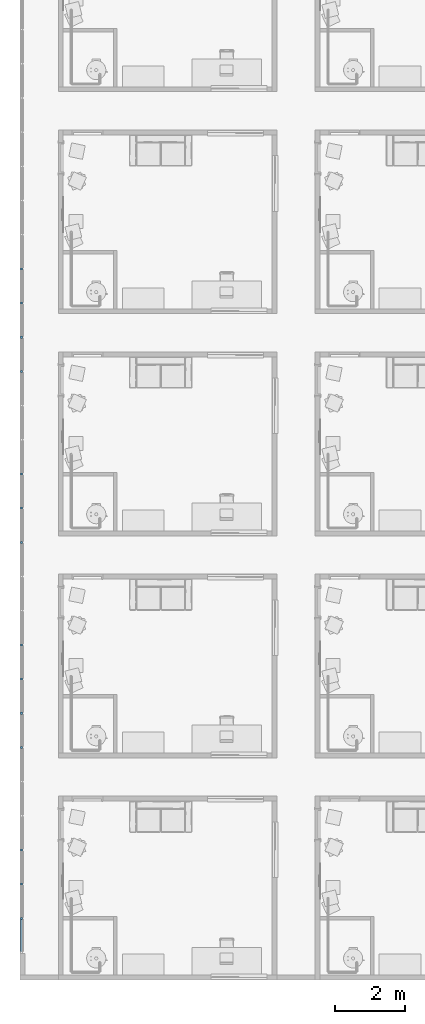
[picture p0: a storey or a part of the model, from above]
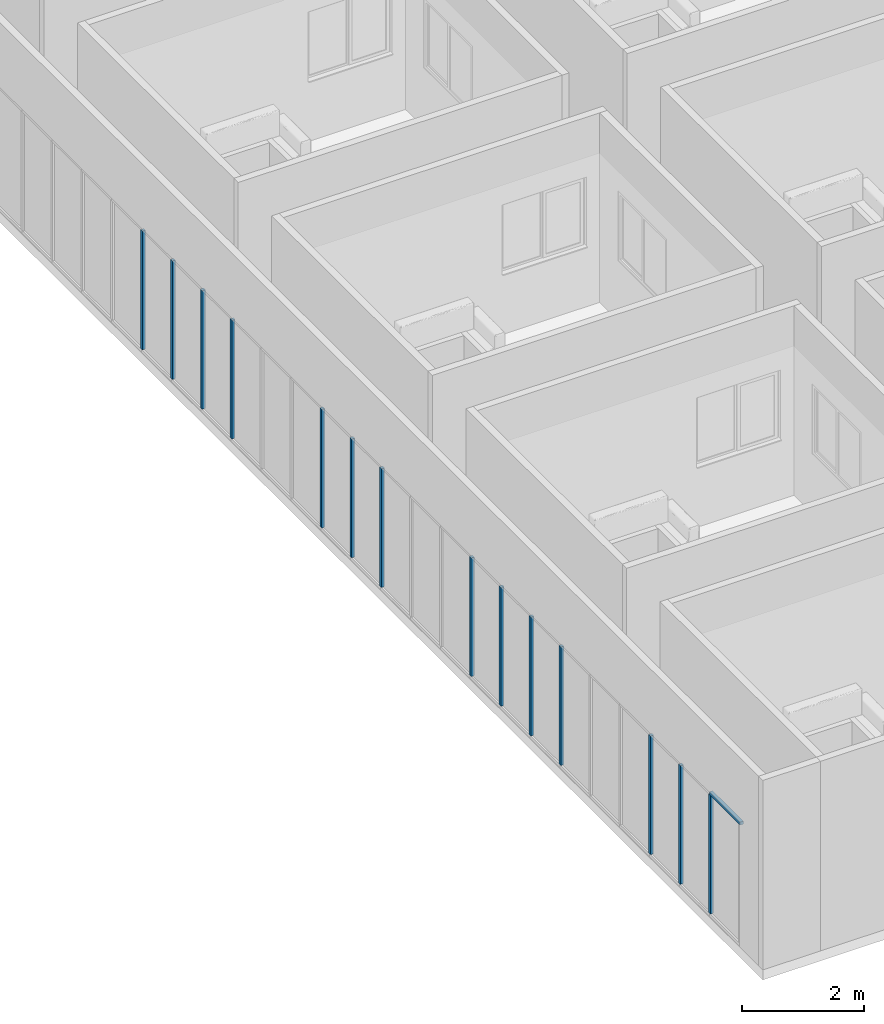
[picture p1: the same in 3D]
Properties of the parts of a building model (IFC4), part 1 of 14

# File
Description: ViewDefinition [ReferenceView_V1.2], RevitIdentifiers [ContentGUID: c18e4294-0ce0-4c7b-a355-1a523e65e639, VersionGUID: 25dbcee9-d0bb-4168-91c9-4b536ebd78aa, NumberOfSaves: 26], CoordinateReference [CoordinateBase: Shared Coordinates, ProjectSite: Internal], ExchangeRequirement [Architecture]
File name: IDS_Escape_Room.ifc
Time: 2026-06-12T16:36:04+02:00
Written by: IfcOpenShell 0.8.5
Made in: Bonsai 0.8.5

# IfcProject, 1234
LongName: IDS Escape Game; Phase: As-Built

# IfcSite, Default
RefLatitude: 42, 24, 53, 508911; RefLongitude: -71, -15, -29, -58837; RefElevation: 0 cm
Pset_SiteCommon - Reference: Project Information

# IfcBuilding, IDS Escape Game Building
LongName: IDS Escape Game Building
Pset_BuildingCommon - Reference: Project Information; NumberOfStoreys: 9

# IfcBuildingStorey: Level:Arcade_ARCHITECTURE_Symbol_Project Base Point (9)
In: IDS Escape Game Building
Pset_BuildingStoreyCommon - Reference: Arcade_ARCHITECTURE_Symbol_Project Base Point
Name | LongName | Elevation (cm)
00_Ground Floor | 00_Ground Floor | 0
01_First Floor | 01_First Floor | 400
02_Second Floor | 02_Second Floor | 800
03_Third Floor | 03_Third Floor | 1200
04_Fourth Floor | 04_Fourth Floor | 1600
05_Fifth Floor | 05_Fifth Floor | 2000
06_Sixth Floor | 06_Sixth Floor | 2400
07_Seventh Floor | 07_Seventh Floor | 2800
08_Roof | 08_Roof | 3200

# IfcSpace: Appartment 100:3026748, 100
In: 02_Second Floor
LongName: Appartment
Pset_SpaceCommon - IsExternal: no; Reference: Appartment 100
Qto_SpaceBaseQuantities - Height: 243.84 cm; GrossFloorArea: 27.396 m2; NetFloorArea: 27.396 m2; GrossCeilingArea: 27.396 m2; NetVolume: 66.8024 m3

# IfcSpace: Appartment 101:3026751, 101
In: 02_Second Floor
LongName: Appartment
Pset_SpaceCommon - IsExternal: no; Reference: Appartment 101
Qto_SpaceBaseQuantities - Height: 243.84 cm; GrossFloorArea: 27.396 m2; NetFloorArea: 27.396 m2; GrossCeilingArea: 27.396 m2; NetVolume: 66.8024 m3

# IfcSpace: Appartment 102:3026754, 102
In: 02_Second Floor
LongName: Appartment
Pset_SpaceCommon - IsExternal: no; Reference: Appartment 102
Qto_SpaceBaseQuantities - Height: 243.84 cm; GrossFloorArea: 27.396 m2; NetFloorArea: 27.396 m2; GrossCeilingArea: 27.396 m2; NetVolume: 66.8024 m3

# IfcSpace: Appartment 103:3026757, 103
In: 02_Second Floor
LongName: Appartment
Pset_SpaceCommon - IsExternal: no; Reference: Appartment 103
Qto_SpaceBaseQuantities - Height: 243.84 cm; GrossFloorArea: 27.396 m2; NetFloorArea: 27.396 m2; GrossCeilingArea: 27.396 m2; NetVolume: 66.8024 m3

# IfcSpace: Appartment 104:3026760, 104
In: 02_Second Floor
LongName: Appartment
Pset_SpaceCommon - IsExternal: no; Reference: Appartment 104
Qto_SpaceBaseQuantities - Height: 243.84 cm; GrossFloorArea: 27.396 m2; NetFloorArea: 27.396 m2; GrossCeilingArea: 27.396 m2; NetVolume: 66.8024 m3

# IfcSpace: Appartment 105:3026763, 105
In: 02_Second Floor
LongName: Appartment
Pset_SpaceCommon - IsExternal: no; Reference: Appartment 105
Qto_SpaceBaseQuantities - Height: 243.84 cm; GrossFloorArea: 27.396 m2; NetFloorArea: 27.396 m2; GrossCeilingArea: 27.396 m2; NetVolume: 66.8024 m3

# IfcSpace: Appartment 106:3026766, 106
In: 03_Third Floor
LongName: Appartment
Pset_SpaceCommon - IsExternal: no; Reference: Appartment 106
Qto_SpaceBaseQuantities - Height: 243.84 cm; GrossFloorArea: 27.396 m2; NetFloorArea: 27.396 m2; GrossCeilingArea: 27.396 m2; NetVolume: 66.8024 m3

# IfcSpace: Appartment 107:3026769, 107
In: 03_Third Floor
LongName: Appartment
Pset_SpaceCommon - IsExternal: no; Reference: Appartment 107
Qto_SpaceBaseQuantities - Height: 243.84 cm; GrossFloorArea: 27.396 m2; NetFloorArea: 27.396 m2; GrossCeilingArea: 27.396 m2; NetVolume: 66.8024 m3

# IfcSpace: Appartment 108:3026772, 108
In: 03_Third Floor
LongName: Appartment
Pset_SpaceCommon - IsExternal: no; Reference: Appartment 108
Qto_SpaceBaseQuantities - Height: 243.84 cm; GrossFloorArea: 27.396 m2; NetFloorArea: 27.396 m2; GrossCeilingArea: 27.396 m2; NetVolume: 66.8024 m3

# IfcSpace: Appartment 109:3026775, 109
In: 03_Third Floor
LongName: Appartment
Pset_SpaceCommon - IsExternal: no; Reference: Appartment 109
Qto_SpaceBaseQuantities - Height: 243.84 cm; GrossFloorArea: 27.396 m2; NetFloorArea: 27.396 m2; GrossCeilingArea: 27.396 m2; NetVolume: 66.8024 m3

# IfcSpace: Appartment 10:3026478, 10
In: 00_Ground Floor
LongName: Appartment
Pset_SpaceCommon - IsExternal: no; Reference: Appartment 10
Qto_SpaceBaseQuantities - Height: 243.84 cm; GrossFloorArea: 27.396 m2; NetFloorArea: 27.396 m2; GrossCeilingArea: 27.396 m2; NetVolume: 66.8024 m3

# IfcSpace: Appartment 110:3026778, 110
In: 03_Third Floor
LongName: Appartment
Pset_SpaceCommon - IsExternal: no; Reference: Appartment 110
Qto_SpaceBaseQuantities - Height: 243.84 cm; GrossFloorArea: 27.396 m2; NetFloorArea: 27.396 m2; GrossCeilingArea: 27.396 m2; NetVolume: 66.8024 m3

# IfcSpace: Appartment 111:3026781, 111
In: 03_Third Floor
LongName: Appartment
Pset_SpaceCommon - IsExternal: no; Reference: Appartment 111
Qto_SpaceBaseQuantities - Height: 243.84 cm; GrossFloorArea: 27.396 m2; NetFloorArea: 27.396 m2; GrossCeilingArea: 27.396 m2; NetVolume: 66.8024 m3

# IfcSpace: Appartment 112:3026784, 112
In: 03_Third Floor
LongName: Appartment
Pset_SpaceCommon - IsExternal: no; Reference: Appartment 112
Qto_SpaceBaseQuantities - Height: 243.84 cm; GrossFloorArea: 27.396 m2; NetFloorArea: 27.396 m2; GrossCeilingArea: 27.396 m2; NetVolume: 66.8024 m3

# IfcSpace: Appartment 113:3026787, 113
In: 03_Third Floor
LongName: Appartment
Pset_SpaceCommon - IsExternal: no; Reference: Appartment 113
Qto_SpaceBaseQuantities - Height: 243.84 cm; GrossFloorArea: 27.396 m2; NetFloorArea: 27.396 m2; GrossCeilingArea: 27.396 m2; NetVolume: 66.8024 m3

# IfcSpace: Appartment 114:3026790, 114
In: 03_Third Floor
LongName: Appartment
Pset_SpaceCommon - IsExternal: no; Reference: Appartment 114
Qto_SpaceBaseQuantities - Height: 243.84 cm; GrossFloorArea: 27.396 m2; NetFloorArea: 27.396 m2; GrossCeilingArea: 27.396 m2; NetVolume: 66.8024 m3

# IfcSpace: Appartment 115:3026793, 115
In: 03_Third Floor
LongName: Appartment
Pset_SpaceCommon - IsExternal: no; Reference: Appartment 115
Qto_SpaceBaseQuantities - Height: 243.84 cm; GrossFloorArea: 27.396 m2; NetFloorArea: 27.396 m2; GrossCeilingArea: 27.396 m2; NetVolume: 66.8024 m3

# IfcSpace: Appartment 116:3026796, 116
In: 03_Third Floor
LongName: Appartment
Pset_SpaceCommon - IsExternal: no; Reference: Appartment 116
Qto_SpaceBaseQuantities - Height: 243.84 cm; GrossFloorArea: 27.396 m2; NetFloorArea: 27.396 m2; GrossCeilingArea: 27.396 m2; NetVolume: 66.8024 m3

# IfcSpace: Appartment 117:3026799, 117
In: 03_Third Floor
LongName: Appartment
Pset_SpaceCommon - IsExternal: no; Reference: Appartment 117
Qto_SpaceBaseQuantities - Height: 243.84 cm; GrossFloorArea: 27.396 m2; NetFloorArea: 27.396 m2; GrossCeilingArea: 27.396 m2; NetVolume: 66.8024 m3

# IfcSpace: Appartment 118:3026802, 118
In: 03_Third Floor
LongName: Appartment
Pset_SpaceCommon - IsExternal: no; Reference: Appartment 118
Qto_SpaceBaseQuantities - Height: 243.84 cm; GrossFloorArea: 27.396 m2; NetFloorArea: 27.396 m2; GrossCeilingArea: 27.396 m2; NetVolume: 66.8024 m3

# IfcSpace: Appartment 119:3026805, 119
In: 03_Third Floor
LongName: Appartment
Pset_SpaceCommon - IsExternal: no; Reference: Appartment 119
Qto_SpaceBaseQuantities - Height: 243.84 cm; GrossFloorArea: 27.396 m2; NetFloorArea: 27.396 m2; GrossCeilingArea: 27.396 m2; NetVolume: 66.8024 m3

# IfcSpace: Appartment 11:3026481, 11
In: 00_Ground Floor
LongName: Appartment
Pset_SpaceCommon - IsExternal: no; Reference: Appartment 11
Qto_SpaceBaseQuantities - Height: 243.84 cm; GrossFloorArea: 27.396 m2; NetFloorArea: 27.396 m2; GrossCeilingArea: 27.396 m2; NetVolume: 66.8024 m3

# IfcSpace: Appartment 120:3026808, 120
In: 03_Third Floor
LongName: Appartment
Pset_SpaceCommon - IsExternal: no; Reference: Appartment 120
Qto_SpaceBaseQuantities - Height: 243.84 cm; GrossFloorArea: 27.396 m2; NetFloorArea: 27.396 m2; GrossCeilingArea: 27.396 m2; NetVolume: 66.8024 m3

# IfcSpace: Appartment 121:3026811, 121
In: 03_Third Floor
LongName: Appartment
Pset_SpaceCommon - IsExternal: no; Reference: Appartment 121
Qto_SpaceBaseQuantities - Height: 243.84 cm; GrossFloorArea: 27.396 m2; NetFloorArea: 27.396 m2; GrossCeilingArea: 27.396 m2; NetVolume: 66.8024 m3

# IfcSpace: Appartment 122:3026814, 122
In: 03_Third Floor
LongName: Appartment
Pset_SpaceCommon - IsExternal: no; Reference: Appartment 122
Qto_SpaceBaseQuantities - Height: 243.84 cm; GrossFloorArea: 27.396 m2; NetFloorArea: 27.396 m2; GrossCeilingArea: 27.396 m2; NetVolume: 66.8024 m3

# IfcSpace: Appartment 123:3026817, 123
In: 03_Third Floor
LongName: Appartment
Pset_SpaceCommon - IsExternal: no; Reference: Appartment 123
Qto_SpaceBaseQuantities - Height: 243.84 cm; GrossFloorArea: 27.396 m2; NetFloorArea: 27.396 m2; GrossCeilingArea: 27.396 m2; NetVolume: 66.8024 m3

# IfcSpace: Appartment 124:3026820, 124
In: 03_Third Floor
LongName: Appartment
Pset_SpaceCommon - IsExternal: no; Reference: Appartment 124
Qto_SpaceBaseQuantities - Height: 243.84 cm; GrossFloorArea: 27.396 m2; NetFloorArea: 27.396 m2; GrossCeilingArea: 27.396 m2; NetVolume: 66.8024 m3

# IfcSpace: Appartment 125:3026823, 125
In: 03_Third Floor
LongName: Appartment
Pset_SpaceCommon - IsExternal: no; Reference: Appartment 125
Qto_SpaceBaseQuantities - Height: 243.84 cm; GrossFloorArea: 27.396 m2; NetFloorArea: 27.396 m2; GrossCeilingArea: 27.396 m2; NetVolume: 66.8024 m3

# IfcSpace: Appartment 126:3026826, 126
In: 03_Third Floor
LongName: Appartment
Pset_SpaceCommon - IsExternal: no; Reference: Appartment 126
Qto_SpaceBaseQuantities - Height: 243.84 cm; GrossFloorArea: 27.396 m2; NetFloorArea: 27.396 m2; GrossCeilingArea: 27.396 m2; NetVolume: 66.8024 m3

# IfcSpace: Appartment 127:3026829, 127
In: 03_Third Floor
LongName: Appartment
Pset_SpaceCommon - IsExternal: no; Reference: Appartment 127
Qto_SpaceBaseQuantities - Height: 243.84 cm; GrossFloorArea: 27.396 m2; NetFloorArea: 27.396 m2; GrossCeilingArea: 27.396 m2; NetVolume: 66.8024 m3

# IfcSpace: Appartment 128:3026832, 128
In: 03_Third Floor
LongName: Appartment
Pset_SpaceCommon - IsExternal: no; Reference: Appartment 128
Qto_SpaceBaseQuantities - Height: 243.84 cm; GrossFloorArea: 27.396 m2; NetFloorArea: 27.396 m2; GrossCeilingArea: 27.396 m2; NetVolume: 66.8024 m3

# IfcSpace: Appartment 129:3026835, 129
In: 03_Third Floor
LongName: Appartment
Pset_SpaceCommon - IsExternal: no; Reference: Appartment 129
Qto_SpaceBaseQuantities - Height: 243.84 cm; GrossFloorArea: 27.396 m2; NetFloorArea: 27.396 m2; GrossCeilingArea: 27.396 m2; NetVolume: 66.8024 m3

# IfcSpace: Appartment 12:3026484, 12
In: 00_Ground Floor
LongName: Appartment
Pset_SpaceCommon - IsExternal: no; Reference: Appartment 12
Qto_SpaceBaseQuantities - Height: 243.84 cm; GrossFloorArea: 27.396 m2; NetFloorArea: 27.396 m2; GrossCeilingArea: 27.396 m2; NetVolume: 66.8024 m3

# IfcSpace: Appartment 130:3026838, 130
In: 03_Third Floor
LongName: Appartment
Pset_SpaceCommon - IsExternal: no; Reference: Appartment 130
Qto_SpaceBaseQuantities - Height: 243.84 cm; GrossFloorArea: 27.396 m2; NetFloorArea: 27.396 m2; GrossCeilingArea: 27.396 m2; NetVolume: 66.8024 m3

# IfcSpace: Appartment 131:3026841, 131
In: 03_Third Floor
LongName: Appartment
Pset_SpaceCommon - IsExternal: no; Reference: Appartment 131
Qto_SpaceBaseQuantities - Height: 243.84 cm; GrossFloorArea: 27.396 m2; NetFloorArea: 27.396 m2; GrossCeilingArea: 27.396 m2; NetVolume: 66.8024 m3

# IfcSpace: Appartment 132:3026844, 132
In: 03_Third Floor
LongName: Appartment
Pset_SpaceCommon - IsExternal: no; Reference: Appartment 132
Qto_SpaceBaseQuantities - Height: 243.84 cm; GrossFloorArea: 27.396 m2; NetFloorArea: 27.396 m2; GrossCeilingArea: 27.396 m2; NetVolume: 66.8024 m3

# IfcSpace: Appartment 133:3026847, 133
In: 03_Third Floor
LongName: Appartment
Pset_SpaceCommon - IsExternal: no; Reference: Appartment 133
Qto_SpaceBaseQuantities - Height: 243.84 cm; GrossFloorArea: 27.396 m2; NetFloorArea: 27.396 m2; GrossCeilingArea: 27.396 m2; NetVolume: 66.8024 m3

# IfcSpace: Appartment 134:3026850, 134
In: 03_Third Floor
LongName: Appartment
Pset_SpaceCommon - IsExternal: no; Reference: Appartment 134
Qto_SpaceBaseQuantities - Height: 243.84 cm; GrossFloorArea: 27.396 m2; NetFloorArea: 27.396 m2; GrossCeilingArea: 27.396 m2; NetVolume: 66.8024 m3

# IfcSpace: Appartment 135:3026853, 135
In: 03_Third Floor
LongName: Appartment
Pset_SpaceCommon - IsExternal: no; Reference: Appartment 135
Qto_SpaceBaseQuantities - Height: 243.84 cm; GrossFloorArea: 27.396 m2; NetFloorArea: 27.396 m2; GrossCeilingArea: 27.396 m2; NetVolume: 66.8024 m3

# IfcSpace: Appartment 136:3026856, 136
In: 03_Third Floor
LongName: Appartment
Pset_SpaceCommon - IsExternal: no; Reference: Appartment 136
Qto_SpaceBaseQuantities - Height: 243.84 cm; GrossFloorArea: 27.396 m2; NetFloorArea: 27.396 m2; GrossCeilingArea: 27.396 m2; NetVolume: 66.8024 m3

# IfcSpace: Appartment 137:3026859, 137
In: 03_Third Floor
LongName: Appartment
Pset_SpaceCommon - IsExternal: no; Reference: Appartment 137
Qto_SpaceBaseQuantities - Height: 243.84 cm; GrossFloorArea: 27.396 m2; NetFloorArea: 27.396 m2; GrossCeilingArea: 27.396 m2; NetVolume: 66.8024 m3

# IfcSpace: Appartment 138:3026862, 138
In: 03_Third Floor
LongName: Appartment
Pset_SpaceCommon - IsExternal: no; Reference: Appartment 138
Qto_SpaceBaseQuantities - Height: 243.84 cm; GrossFloorArea: 27.396 m2; NetFloorArea: 27.396 m2; GrossCeilingArea: 27.396 m2; NetVolume: 66.8024 m3

# IfcSpace: Appartment 139:3026865, 139
In: 03_Third Floor
LongName: Appartment
Pset_SpaceCommon - IsExternal: no; Reference: Appartment 139
Qto_SpaceBaseQuantities - Height: 243.84 cm; GrossFloorArea: 27.396 m2; NetFloorArea: 27.396 m2; GrossCeilingArea: 27.396 m2; NetVolume: 66.8024 m3

# IfcSpace: Appartment 13:3026487, 13
In: 00_Ground Floor
LongName: Appartment
Pset_SpaceCommon - IsExternal: no; Reference: Appartment 13
Qto_SpaceBaseQuantities - Height: 243.84 cm; GrossFloorArea: 27.396 m2; NetFloorArea: 27.396 m2; GrossCeilingArea: 27.396 m2; NetVolume: 66.8024 m3

# IfcSpace: Appartment 140:3026868, 140
In: 03_Third Floor
LongName: Appartment
Pset_SpaceCommon - IsExternal: no; Reference: Appartment 140
Qto_SpaceBaseQuantities - Height: 243.84 cm; GrossFloorArea: 27.396 m2; NetFloorArea: 27.396 m2; GrossCeilingArea: 27.396 m2; NetVolume: 66.8024 m3

# IfcSpace: Appartment 141:3026871, 141
In: 04_Fourth Floor
LongName: Appartment
Pset_SpaceCommon - IsExternal: no; Reference: Appartment 141
Qto_SpaceBaseQuantities - Height: 243.84 cm; GrossFloorArea: 27.396 m2; NetFloorArea: 27.396 m2; GrossCeilingArea: 27.396 m2; NetVolume: 66.8024 m3

# IfcSpace: Appartment 142:3026874, 142
In: 04_Fourth Floor
LongName: Appartment
Pset_SpaceCommon - IsExternal: no; Reference: Appartment 142
Qto_SpaceBaseQuantities - Height: 243.84 cm; GrossFloorArea: 27.396 m2; NetFloorArea: 27.396 m2; GrossCeilingArea: 27.396 m2; NetVolume: 66.8024 m3

# IfcSpace: Appartment 143:3026877, 143
In: 04_Fourth Floor
LongName: Appartment
Pset_SpaceCommon - IsExternal: no; Reference: Appartment 143
Qto_SpaceBaseQuantities - Height: 243.84 cm; GrossFloorArea: 27.396 m2; NetFloorArea: 27.396 m2; GrossCeilingArea: 27.396 m2; NetVolume: 66.8024 m3

# IfcSpace: Appartment 144:3026880, 144
In: 04_Fourth Floor
LongName: Appartment
Pset_SpaceCommon - IsExternal: no; Reference: Appartment 144
Qto_SpaceBaseQuantities - Height: 243.84 cm; GrossFloorArea: 27.396 m2; NetFloorArea: 27.396 m2; GrossCeilingArea: 27.396 m2; NetVolume: 66.8024 m3

# IfcSpace: Appartment 145:3026883, 145
In: 04_Fourth Floor
LongName: Appartment
Pset_SpaceCommon - IsExternal: no; Reference: Appartment 145
Qto_SpaceBaseQuantities - Height: 243.84 cm; GrossFloorArea: 27.396 m2; NetFloorArea: 27.396 m2; GrossCeilingArea: 27.396 m2; NetVolume: 66.8024 m3

# IfcSpace: Appartment 146:3026886, 146
In: 04_Fourth Floor
LongName: Appartment
Pset_SpaceCommon - IsExternal: no; Reference: Appartment 146
Qto_SpaceBaseQuantities - Height: 243.84 cm; GrossFloorArea: 27.396 m2; NetFloorArea: 27.396 m2; GrossCeilingArea: 27.396 m2; NetVolume: 66.8024 m3

# IfcSpace: Appartment 147:3026889, 147
In: 04_Fourth Floor
LongName: Appartment
Pset_SpaceCommon - IsExternal: no; Reference: Appartment 147
Qto_SpaceBaseQuantities - Height: 243.84 cm; GrossFloorArea: 27.396 m2; NetFloorArea: 27.396 m2; GrossCeilingArea: 27.396 m2; NetVolume: 66.8024 m3

# IfcSpace: Appartment 148:3026892, 148
In: 04_Fourth Floor
LongName: Appartment
Pset_SpaceCommon - IsExternal: no; Reference: Appartment 148
Qto_SpaceBaseQuantities - Height: 243.84 cm; GrossFloorArea: 27.396 m2; NetFloorArea: 27.396 m2; GrossCeilingArea: 27.396 m2; NetVolume: 66.8024 m3

# IfcSpace: Appartment 149:3026895, 149
In: 04_Fourth Floor
LongName: Appartment
Pset_SpaceCommon - IsExternal: no; Reference: Appartment 149
Qto_SpaceBaseQuantities - Height: 243.84 cm; GrossFloorArea: 27.396 m2; NetFloorArea: 27.396 m2; GrossCeilingArea: 27.396 m2; NetVolume: 66.8024 m3

# IfcSpace: Appartment 14:3026490, 14
In: 00_Ground Floor
LongName: Appartment
Pset_SpaceCommon - IsExternal: no; Reference: Appartment 14
Qto_SpaceBaseQuantities - Height: 243.84 cm; GrossFloorArea: 27.396 m2; NetFloorArea: 27.396 m2; GrossCeilingArea: 27.396 m2; NetVolume: 66.8024 m3

# IfcSpace: Appartment 150:3026898, 150
In: 04_Fourth Floor
LongName: Appartment
Pset_SpaceCommon - IsExternal: no; Reference: Appartment 150
Qto_SpaceBaseQuantities - Height: 243.84 cm; GrossFloorArea: 27.396 m2; NetFloorArea: 27.396 m2; GrossCeilingArea: 27.396 m2; NetVolume: 66.8024 m3

# IfcSpace: Appartment 151:3026901, 151
In: 04_Fourth Floor
LongName: Appartment
Pset_SpaceCommon - IsExternal: no; Reference: Appartment 151
Qto_SpaceBaseQuantities - Height: 243.84 cm; GrossFloorArea: 27.396 m2; NetFloorArea: 27.396 m2; GrossCeilingArea: 27.396 m2; NetVolume: 66.8024 m3

# IfcSpace: Appartment 152:3026904, 152
In: 04_Fourth Floor
LongName: Appartment
Pset_SpaceCommon - IsExternal: no; Reference: Appartment 152
Qto_SpaceBaseQuantities - Height: 243.84 cm; GrossFloorArea: 27.396 m2; NetFloorArea: 27.396 m2; GrossCeilingArea: 27.396 m2; NetVolume: 66.8024 m3

# IfcSpace: Appartment 153:3026907, 153
In: 04_Fourth Floor
LongName: Appartment
Pset_SpaceCommon - IsExternal: no; Reference: Appartment 153
Qto_SpaceBaseQuantities - Height: 243.84 cm; GrossFloorArea: 27.396 m2; NetFloorArea: 27.396 m2; GrossCeilingArea: 27.396 m2; NetVolume: 66.8024 m3

# IfcSpace: Appartment 154:3026910, 154
In: 04_Fourth Floor
LongName: Appartment
Pset_SpaceCommon - IsExternal: no; Reference: Appartment 154
Qto_SpaceBaseQuantities - Height: 243.84 cm; GrossFloorArea: 27.396 m2; NetFloorArea: 27.396 m2; GrossCeilingArea: 27.396 m2; NetVolume: 66.8024 m3

# IfcSpace: Appartment 155:3026913, 155
In: 04_Fourth Floor
LongName: Appartment
Pset_SpaceCommon - IsExternal: no; Reference: Appartment 155
Qto_SpaceBaseQuantities - Height: 243.84 cm; GrossFloorArea: 27.396 m2; NetFloorArea: 27.396 m2; GrossCeilingArea: 27.396 m2; NetVolume: 66.8024 m3

# IfcSpace: Appartment 156:3026916, 156
In: 04_Fourth Floor
LongName: Appartment
Pset_SpaceCommon - IsExternal: no; Reference: Appartment 156
Qto_SpaceBaseQuantities - Height: 243.84 cm; GrossFloorArea: 27.396 m2; NetFloorArea: 27.396 m2; GrossCeilingArea: 27.396 m2; NetVolume: 66.8024 m3

# IfcSpace: Appartment 157:3026919, 157
In: 04_Fourth Floor
LongName: Appartment
Pset_SpaceCommon - IsExternal: no; Reference: Appartment 157
Qto_SpaceBaseQuantities - Height: 243.84 cm; GrossFloorArea: 27.396 m2; NetFloorArea: 27.396 m2; GrossCeilingArea: 27.396 m2; NetVolume: 66.8024 m3

# IfcSpace: Appartment 158:3026922, 158
In: 04_Fourth Floor
LongName: Appartment
Pset_SpaceCommon - IsExternal: no; Reference: Appartment 158
Qto_SpaceBaseQuantities - Height: 243.84 cm; GrossFloorArea: 27.396 m2; NetFloorArea: 27.396 m2; GrossCeilingArea: 27.396 m2; NetVolume: 66.8024 m3

# IfcSpace: Appartment 159:3026925, 159
In: 04_Fourth Floor
LongName: Appartment
Pset_SpaceCommon - IsExternal: no; Reference: Appartment 159
Qto_SpaceBaseQuantities - Height: 243.84 cm; GrossFloorArea: 27.396 m2; NetFloorArea: 27.396 m2; GrossCeilingArea: 27.396 m2; NetVolume: 66.8024 m3

# IfcSpace: Appartment 15:3026493, 15
In: 00_Ground Floor
LongName: Appartment
Pset_SpaceCommon - IsExternal: no; Reference: Appartment 15
Qto_SpaceBaseQuantities - Height: 243.84 cm; GrossFloorArea: 27.396 m2; NetFloorArea: 27.396 m2; GrossCeilingArea: 27.396 m2; NetVolume: 66.8024 m3

# IfcSpace: Appartment 160:3026928, 160
In: 04_Fourth Floor
LongName: Appartment
Pset_SpaceCommon - IsExternal: no; Reference: Appartment 160
Qto_SpaceBaseQuantities - Height: 243.84 cm; GrossFloorArea: 27.396 m2; NetFloorArea: 27.396 m2; GrossCeilingArea: 27.396 m2; NetVolume: 66.8024 m3

# IfcSpace: Appartment 161:3026931, 161
In: 04_Fourth Floor
LongName: Appartment
Pset_SpaceCommon - IsExternal: no; Reference: Appartment 161
Qto_SpaceBaseQuantities - Height: 243.84 cm; GrossFloorArea: 27.396 m2; NetFloorArea: 27.396 m2; GrossCeilingArea: 27.396 m2; NetVolume: 66.8024 m3

# IfcSpace: Appartment 162:3026934, 162
In: 04_Fourth Floor
LongName: Appartment
Pset_SpaceCommon - IsExternal: no; Reference: Appartment 162
Qto_SpaceBaseQuantities - Height: 243.84 cm; GrossFloorArea: 27.396 m2; NetFloorArea: 27.396 m2; GrossCeilingArea: 27.396 m2; NetVolume: 66.8024 m3

# IfcSpace: Appartment 163:3026937, 163
In: 04_Fourth Floor
LongName: Appartment
Pset_SpaceCommon - IsExternal: no; Reference: Appartment 163
Qto_SpaceBaseQuantities - Height: 243.84 cm; GrossFloorArea: 27.396 m2; NetFloorArea: 27.396 m2; GrossCeilingArea: 27.396 m2; NetVolume: 66.8024 m3

# IfcSpace: Appartment 164:3026940, 164
In: 04_Fourth Floor
LongName: Appartment
Pset_SpaceCommon - IsExternal: no; Reference: Appartment 164
Qto_SpaceBaseQuantities - Height: 243.84 cm; GrossFloorArea: 27.396 m2; NetFloorArea: 27.396 m2; GrossCeilingArea: 27.396 m2; NetVolume: 66.8024 m3

# IfcSpace: Appartment 165:3026943, 165
In: 04_Fourth Floor
LongName: Appartment
Pset_SpaceCommon - IsExternal: no; Reference: Appartment 165
Qto_SpaceBaseQuantities - Height: 243.84 cm; GrossFloorArea: 27.396 m2; NetFloorArea: 27.396 m2; GrossCeilingArea: 27.396 m2; NetVolume: 66.8024 m3

# IfcSpace: Appartment 166:3026946, 166
In: 04_Fourth Floor
LongName: Appartment
Pset_SpaceCommon - IsExternal: no; Reference: Appartment 166
Qto_SpaceBaseQuantities - Height: 243.84 cm; GrossFloorArea: 27.396 m2; NetFloorArea: 27.396 m2; GrossCeilingArea: 27.396 m2; NetVolume: 66.8024 m3

# IfcSpace: Appartment 167:3026949, 167
In: 04_Fourth Floor
LongName: Appartment
Pset_SpaceCommon - IsExternal: no; Reference: Appartment 167
Qto_SpaceBaseQuantities - Height: 243.84 cm; GrossFloorArea: 27.396 m2; NetFloorArea: 27.396 m2; GrossCeilingArea: 27.396 m2; NetVolume: 66.8024 m3

# IfcSpace: Appartment 168:3026952, 168
In: 04_Fourth Floor
LongName: Appartment
Pset_SpaceCommon - IsExternal: no; Reference: Appartment 168
Qto_SpaceBaseQuantities - Height: 243.84 cm; GrossFloorArea: 27.396 m2; NetFloorArea: 27.396 m2; GrossCeilingArea: 27.396 m2; NetVolume: 66.8024 m3

# IfcSpace: Appartment 169:3026955, 169
In: 04_Fourth Floor
LongName: Appartment
Pset_SpaceCommon - IsExternal: no; Reference: Appartment 169
Qto_SpaceBaseQuantities - Height: 243.84 cm; GrossFloorArea: 27.396 m2; NetFloorArea: 27.396 m2; GrossCeilingArea: 27.396 m2; NetVolume: 66.8024 m3

# IfcSpace: Appartment 16:3026496, 16
In: 00_Ground Floor
LongName: Appartment
Pset_SpaceCommon - IsExternal: no; Reference: Appartment 16
Qto_SpaceBaseQuantities - Height: 243.84 cm; GrossFloorArea: 27.396 m2; NetFloorArea: 27.396 m2; GrossCeilingArea: 27.396 m2; NetVolume: 66.8024 m3

# IfcSpace: Appartment 170:3026958, 170
In: 04_Fourth Floor
LongName: Appartment
Pset_SpaceCommon - IsExternal: no; Reference: Appartment 170
Qto_SpaceBaseQuantities - Height: 243.84 cm; GrossFloorArea: 27.396 m2; NetFloorArea: 27.396 m2; GrossCeilingArea: 27.396 m2; NetVolume: 66.8024 m3

# IfcSpace: Appartment 171:3026961, 171
In: 04_Fourth Floor
LongName: Appartment
Pset_SpaceCommon - IsExternal: no; Reference: Appartment 171
Qto_SpaceBaseQuantities - Height: 243.84 cm; GrossFloorArea: 27.396 m2; NetFloorArea: 27.396 m2; GrossCeilingArea: 27.396 m2; NetVolume: 66.8024 m3

# IfcSpace: Appartment 172:3026964, 172
In: 04_Fourth Floor
LongName: Appartment
Pset_SpaceCommon - IsExternal: no; Reference: Appartment 172
Qto_SpaceBaseQuantities - Height: 243.84 cm; GrossFloorArea: 27.396 m2; NetFloorArea: 27.396 m2; GrossCeilingArea: 27.396 m2; NetVolume: 66.8024 m3

# IfcSpace: Appartment 173:3026967, 173
In: 04_Fourth Floor
LongName: Appartment
Pset_SpaceCommon - IsExternal: no; Reference: Appartment 173
Qto_SpaceBaseQuantities - Height: 243.84 cm; GrossFloorArea: 27.396 m2; NetFloorArea: 27.396 m2; GrossCeilingArea: 27.396 m2; NetVolume: 66.8024 m3

# IfcSpace: Appartment 174:3026970, 174
In: 04_Fourth Floor
LongName: Appartment
Pset_SpaceCommon - IsExternal: no; Reference: Appartment 174
Qto_SpaceBaseQuantities - Height: 243.84 cm; GrossFloorArea: 27.396 m2; NetFloorArea: 27.396 m2; GrossCeilingArea: 27.396 m2; NetVolume: 66.8024 m3

# IfcSpace: Appartment 175:3026973, 175
In: 04_Fourth Floor
LongName: Appartment
Pset_SpaceCommon - IsExternal: no; Reference: Appartment 175
Qto_SpaceBaseQuantities - Height: 243.84 cm; GrossFloorArea: 27.396 m2; NetFloorArea: 27.396 m2; GrossCeilingArea: 27.396 m2; NetVolume: 66.8024 m3

# IfcSpace: Appartment 176:3026976, 176
In: 05_Fifth Floor
LongName: Appartment
Pset_SpaceCommon - IsExternal: no; Reference: Appartment 176
Qto_SpaceBaseQuantities - Height: 243.84 cm; GrossFloorArea: 27.396 m2; NetFloorArea: 27.396 m2; GrossCeilingArea: 27.396 m2; NetVolume: 66.8024 m3

# IfcSpace: Appartment 177:3026979, 177
In: 05_Fifth Floor
LongName: Appartment
Pset_SpaceCommon - IsExternal: no; Reference: Appartment 177
Qto_SpaceBaseQuantities - Height: 243.84 cm; GrossFloorArea: 27.396 m2; NetFloorArea: 27.396 m2; GrossCeilingArea: 27.396 m2; NetVolume: 66.8024 m3

# IfcSpace: Appartment 178:3026982, 178
In: 05_Fifth Floor
LongName: Appartment
Pset_SpaceCommon - IsExternal: no; Reference: Appartment 178
Qto_SpaceBaseQuantities - Height: 243.84 cm; GrossFloorArea: 27.396 m2; NetFloorArea: 27.396 m2; GrossCeilingArea: 27.396 m2; NetVolume: 66.8024 m3

# IfcSpace: Appartment 179:3026985, 179
In: 05_Fifth Floor
LongName: Appartment
Pset_SpaceCommon - IsExternal: no; Reference: Appartment 179
Qto_SpaceBaseQuantities - Height: 243.84 cm; GrossFloorArea: 27.396 m2; NetFloorArea: 27.396 m2; GrossCeilingArea: 27.396 m2; NetVolume: 66.8024 m3

# IfcSpace: Appartment 17:3026499, 17
In: 00_Ground Floor
LongName: Appartment
Pset_SpaceCommon - IsExternal: no; Reference: Appartment 17
Qto_SpaceBaseQuantities - Height: 243.84 cm; GrossFloorArea: 27.396 m2; NetFloorArea: 27.396 m2; GrossCeilingArea: 27.396 m2; NetVolume: 66.8024 m3

# IfcSpace: Appartment 180:3026988, 180
In: 05_Fifth Floor
LongName: Appartment
Pset_SpaceCommon - IsExternal: no; Reference: Appartment 180
Qto_SpaceBaseQuantities - Height: 243.84 cm; GrossFloorArea: 27.396 m2; NetFloorArea: 27.396 m2; GrossCeilingArea: 27.396 m2; NetVolume: 66.8024 m3

# IfcSpace: Appartment 181:3026991, 181
In: 05_Fifth Floor
LongName: Appartment
Pset_SpaceCommon - IsExternal: no; Reference: Appartment 181
Qto_SpaceBaseQuantities - Height: 243.84 cm; GrossFloorArea: 27.396 m2; NetFloorArea: 27.396 m2; GrossCeilingArea: 27.396 m2; NetVolume: 66.8024 m3

# IfcSpace: Appartment 182:3026994, 182
In: 05_Fifth Floor
LongName: Appartment
Pset_SpaceCommon - IsExternal: no; Reference: Appartment 182
Qto_SpaceBaseQuantities - Height: 243.84 cm; GrossFloorArea: 27.396 m2; NetFloorArea: 27.396 m2; GrossCeilingArea: 27.396 m2; NetVolume: 66.8024 m3

# IfcSpace: Appartment 183:3026997, 183
In: 05_Fifth Floor
LongName: Appartment
Pset_SpaceCommon - IsExternal: no; Reference: Appartment 183
Qto_SpaceBaseQuantities - Height: 243.84 cm; GrossFloorArea: 27.396 m2; NetFloorArea: 27.396 m2; GrossCeilingArea: 27.396 m2; NetVolume: 66.8024 m3

# IfcSpace: Appartment 184:3027000, 184
In: 05_Fifth Floor
LongName: Appartment
Pset_SpaceCommon - IsExternal: no; Reference: Appartment 184
Qto_SpaceBaseQuantities - Height: 243.84 cm; GrossFloorArea: 27.396 m2; NetFloorArea: 27.396 m2; GrossCeilingArea: 27.396 m2; NetVolume: 66.8024 m3

# IfcSpace: Appartment 185:3027003, 185
In: 05_Fifth Floor
LongName: Appartment
Pset_SpaceCommon - IsExternal: no; Reference: Appartment 185
Qto_SpaceBaseQuantities - Height: 243.84 cm; GrossFloorArea: 27.396 m2; NetFloorArea: 27.396 m2; GrossCeilingArea: 27.396 m2; NetVolume: 66.8024 m3

# IfcSpace: Appartment 186:3027006, 186
In: 05_Fifth Floor
LongName: Appartment
Pset_SpaceCommon - IsExternal: no; Reference: Appartment 186
Qto_SpaceBaseQuantities - Height: 243.84 cm; GrossFloorArea: 27.396 m2; NetFloorArea: 27.396 m2; GrossCeilingArea: 27.396 m2; NetVolume: 66.8024 m3

# IfcSpace: Appartment 187:3027009, 187
In: 05_Fifth Floor
LongName: Appartment
Pset_SpaceCommon - IsExternal: no; Reference: Appartment 187
Qto_SpaceBaseQuantities - Height: 243.84 cm; GrossFloorArea: 27.396 m2; NetFloorArea: 27.396 m2; GrossCeilingArea: 27.396 m2; NetVolume: 66.8024 m3

# IfcSpace: Appartment 188:3027012, 188
In: 05_Fifth Floor
LongName: Appartment
Pset_SpaceCommon - IsExternal: no; Reference: Appartment 188
Qto_SpaceBaseQuantities - Height: 243.84 cm; GrossFloorArea: 27.396 m2; NetFloorArea: 27.396 m2; GrossCeilingArea: 27.396 m2; NetVolume: 66.8024 m3

# IfcSpace: Appartment 189:3027015, 189
In: 05_Fifth Floor
LongName: Appartment
Pset_SpaceCommon - IsExternal: no; Reference: Appartment 189
Qto_SpaceBaseQuantities - Height: 243.84 cm; GrossFloorArea: 27.396 m2; NetFloorArea: 27.396 m2; GrossCeilingArea: 27.396 m2; NetVolume: 66.8024 m3

# IfcSpace: Appartment 18:3026502, 18
In: 00_Ground Floor
LongName: Appartment
Pset_SpaceCommon - IsExternal: no; Reference: Appartment 18
Qto_SpaceBaseQuantities - Height: 243.84 cm; GrossFloorArea: 27.396 m2; NetFloorArea: 27.396 m2; GrossCeilingArea: 27.396 m2; NetVolume: 66.8024 m3

# IfcSpace: Appartment 190:3027018, 190
In: 05_Fifth Floor
LongName: Appartment
Pset_SpaceCommon - IsExternal: no; Reference: Appartment 190
Qto_SpaceBaseQuantities - Height: 243.84 cm; GrossFloorArea: 27.396 m2; NetFloorArea: 27.396 m2; GrossCeilingArea: 27.396 m2; NetVolume: 66.8024 m3

# IfcSpace: Appartment 191:3027021, 191
In: 05_Fifth Floor
LongName: Appartment
Pset_SpaceCommon - IsExternal: no; Reference: Appartment 191
Qto_SpaceBaseQuantities - Height: 243.84 cm; GrossFloorArea: 27.396 m2; NetFloorArea: 27.396 m2; GrossCeilingArea: 27.396 m2; NetVolume: 66.8024 m3

# IfcSpace: Appartment 192:3027024, 192
In: 05_Fifth Floor
LongName: Appartment
Pset_SpaceCommon - IsExternal: no; Reference: Appartment 192
Qto_SpaceBaseQuantities - Height: 243.84 cm; GrossFloorArea: 27.396 m2; NetFloorArea: 27.396 m2; GrossCeilingArea: 27.396 m2; NetVolume: 66.8024 m3

# IfcSpace: Appartment 193:3027027, 193
In: 05_Fifth Floor
LongName: Appartment
Pset_SpaceCommon - IsExternal: no; Reference: Appartment 193
Qto_SpaceBaseQuantities - Height: 243.84 cm; GrossFloorArea: 27.396 m2; NetFloorArea: 27.396 m2; GrossCeilingArea: 27.396 m2; NetVolume: 66.8024 m3

# IfcSpace: Appartment 194:3027030, 194
In: 05_Fifth Floor
LongName: Appartment
Pset_SpaceCommon - IsExternal: no; Reference: Appartment 194
Qto_SpaceBaseQuantities - Height: 243.84 cm; GrossFloorArea: 27.396 m2; NetFloorArea: 27.396 m2; GrossCeilingArea: 27.396 m2; NetVolume: 66.8024 m3

# IfcSpace: Appartment 195:3027033, 195
In: 05_Fifth Floor
LongName: Appartment
Pset_SpaceCommon - IsExternal: no; Reference: Appartment 195
Qto_SpaceBaseQuantities - Height: 243.84 cm; GrossFloorArea: 27.396 m2; NetFloorArea: 27.396 m2; GrossCeilingArea: 27.396 m2; NetVolume: 66.8024 m3

# IfcSpace: Appartment 196:3027036, 196
In: 05_Fifth Floor
LongName: Appartment
Pset_SpaceCommon - IsExternal: no; Reference: Appartment 196
Qto_SpaceBaseQuantities - Height: 243.84 cm; GrossFloorArea: 27.396 m2; NetFloorArea: 27.396 m2; GrossCeilingArea: 27.396 m2; NetVolume: 66.8024 m3

# IfcSpace: Appartment 197:3027039, 197
In: 05_Fifth Floor
LongName: Appartment
Pset_SpaceCommon - IsExternal: no; Reference: Appartment 197
Qto_SpaceBaseQuantities - Height: 243.84 cm; GrossFloorArea: 27.396 m2; NetFloorArea: 27.396 m2; GrossCeilingArea: 27.396 m2; NetVolume: 66.8024 m3

# IfcSpace: Appartment 198:3027042, 198
In: 05_Fifth Floor
LongName: Appartment
Pset_SpaceCommon - IsExternal: no; Reference: Appartment 198
Qto_SpaceBaseQuantities - Height: 243.84 cm; GrossFloorArea: 27.396 m2; NetFloorArea: 27.396 m2; GrossCeilingArea: 27.396 m2; NetVolume: 66.8024 m3

# IfcSpace: Appartment 199:3027045, 199
In: 05_Fifth Floor
LongName: Appartment
Pset_SpaceCommon - IsExternal: no; Reference: Appartment 199
Qto_SpaceBaseQuantities - Height: 243.84 cm; GrossFloorArea: 27.396 m2; NetFloorArea: 27.396 m2; GrossCeilingArea: 27.396 m2; NetVolume: 66.8024 m3

# IfcSpace: Appartment 19:3026505, 19
In: 00_Ground Floor
LongName: Appartment
Pset_SpaceCommon - IsExternal: no; Reference: Appartment 19
Qto_SpaceBaseQuantities - Height: 243.84 cm; GrossFloorArea: 27.396 m2; NetFloorArea: 27.396 m2; GrossCeilingArea: 27.396 m2; NetVolume: 66.8024 m3

# IfcSpace: Appartment 1:3022528, 1
In: 00_Ground Floor
LongName: Appartment
Pset_SpaceCommon - Reference: Appartment 1; IsExternal: no
Qto_SpaceBaseQuantities - Height: 243.84 cm; GrossFloorArea: 27.396 m2; NetFloorArea: 27.396 m2; GrossCeilingArea: 27.396 m2; NetVolume: 66.8024 m3

# IfcSpace: Appartment 200:3027048, 200
In: 05_Fifth Floor
LongName: Appartment
Pset_SpaceCommon - IsExternal: no; Reference: Appartment 200
Qto_SpaceBaseQuantities - Height: 243.84 cm; GrossFloorArea: 27.396 m2; NetFloorArea: 27.396 m2; GrossCeilingArea: 27.396 m2; NetVolume: 66.8024 m3

# IfcSpace: Appartment 201:3027051, 201
In: 05_Fifth Floor
LongName: Appartment
Pset_SpaceCommon - IsExternal: no; Reference: Appartment 201
Qto_SpaceBaseQuantities - Height: 243.84 cm; GrossFloorArea: 27.396 m2; NetFloorArea: 27.396 m2; GrossCeilingArea: 27.396 m2; NetVolume: 66.8024 m3

# IfcSpace: Appartment 202:3027054, 202
In: 05_Fifth Floor
LongName: Appartment
Pset_SpaceCommon - IsExternal: no; Reference: Appartment 202
Qto_SpaceBaseQuantities - Height: 243.84 cm; GrossFloorArea: 27.396 m2; NetFloorArea: 27.396 m2; GrossCeilingArea: 27.396 m2; NetVolume: 66.8024 m3

# IfcSpace: Appartment 203:3027057, 203
In: 05_Fifth Floor
LongName: Appartment
Pset_SpaceCommon - IsExternal: no; Reference: Appartment 203
Qto_SpaceBaseQuantities - Height: 243.84 cm; GrossFloorArea: 27.396 m2; NetFloorArea: 27.396 m2; GrossCeilingArea: 27.396 m2; NetVolume: 66.8024 m3

# IfcSpace: Appartment 204:3027060, 204
In: 05_Fifth Floor
LongName: Appartment
Pset_SpaceCommon - IsExternal: no; Reference: Appartment 204
Qto_SpaceBaseQuantities - Height: 243.84 cm; GrossFloorArea: 27.396 m2; NetFloorArea: 27.396 m2; GrossCeilingArea: 27.396 m2; NetVolume: 66.8024 m3

# IfcSpace: Appartment 205:3027063, 205
In: 05_Fifth Floor
LongName: Appartment
Pset_SpaceCommon - IsExternal: no; Reference: Appartment 205
Qto_SpaceBaseQuantities - Height: 243.84 cm; GrossFloorArea: 27.396 m2; NetFloorArea: 27.396 m2; GrossCeilingArea: 27.396 m2; NetVolume: 66.8024 m3

# IfcSpace: Appartment 206:3027066, 206
In: 05_Fifth Floor
LongName: Appartment
Pset_SpaceCommon - IsExternal: no; Reference: Appartment 206
Qto_SpaceBaseQuantities - Height: 243.84 cm; GrossFloorArea: 27.396 m2; NetFloorArea: 27.396 m2; GrossCeilingArea: 27.396 m2; NetVolume: 66.8024 m3

# IfcSpace: Appartment 207:3027069, 207
In: 05_Fifth Floor
LongName: Appartment
Pset_SpaceCommon - IsExternal: no; Reference: Appartment 207
Qto_SpaceBaseQuantities - Height: 243.84 cm; GrossFloorArea: 27.396 m2; NetFloorArea: 27.396 m2; GrossCeilingArea: 27.396 m2; NetVolume: 66.8024 m3

# IfcSpace: Appartment 208:3027072, 208
In: 05_Fifth Floor
LongName: Appartment
Pset_SpaceCommon - IsExternal: no; Reference: Appartment 208
Qto_SpaceBaseQuantities - Height: 243.84 cm; GrossFloorArea: 27.396 m2; NetFloorArea: 27.396 m2; GrossCeilingArea: 27.396 m2; NetVolume: 66.8024 m3

# IfcSpace: Appartment 209:3027075, 209
In: 05_Fifth Floor
LongName: Appartment
Pset_SpaceCommon - IsExternal: no; Reference: Appartment 209
Qto_SpaceBaseQuantities - Height: 243.84 cm; GrossFloorArea: 27.396 m2; NetFloorArea: 27.396 m2; GrossCeilingArea: 27.396 m2; NetVolume: 66.8024 m3

# IfcSpace: Appartment 20:3026508, 20
In: 00_Ground Floor
LongName: Appartment
Pset_SpaceCommon - IsExternal: no; Reference: Appartment 20
Qto_SpaceBaseQuantities - Height: 243.84 cm; GrossFloorArea: 27.396 m2; NetFloorArea: 27.396 m2; GrossCeilingArea: 27.396 m2; NetVolume: 66.8024 m3

# IfcSpace: Appartment 210:3027078, 210
In: 05_Fifth Floor
LongName: Appartment
Pset_SpaceCommon - IsExternal: no; Reference: Appartment 210
Qto_SpaceBaseQuantities - Height: 243.84 cm; GrossFloorArea: 27.396 m2; NetFloorArea: 27.396 m2; GrossCeilingArea: 27.396 m2; NetVolume: 66.8024 m3

# IfcSpace: Appartment 211:3027081, 211
In: 06_Sixth Floor
LongName: Appartment
Pset_SpaceCommon - IsExternal: no; Reference: Appartment 211
Qto_SpaceBaseQuantities - Height: 243.84 cm; GrossFloorArea: 27.396 m2; NetFloorArea: 27.396 m2; GrossCeilingArea: 27.396 m2; NetVolume: 66.8024 m3

# IfcSpace: Appartment 212:3027084, 212
In: 06_Sixth Floor
LongName: Appartment
Pset_SpaceCommon - IsExternal: no; Reference: Appartment 212
Qto_SpaceBaseQuantities - Height: 243.84 cm; GrossFloorArea: 27.396 m2; NetFloorArea: 27.396 m2; GrossCeilingArea: 27.396 m2; NetVolume: 66.8024 m3

# IfcSpace: Appartment 213:3027087, 213
In: 06_Sixth Floor
LongName: Appartment
Pset_SpaceCommon - IsExternal: no; Reference: Appartment 213
Qto_SpaceBaseQuantities - Height: 243.84 cm; GrossFloorArea: 27.396 m2; NetFloorArea: 27.396 m2; GrossCeilingArea: 27.396 m2; NetVolume: 66.8024 m3

# IfcSpace: Appartment 214:3027090, 214
In: 06_Sixth Floor
LongName: Appartment
Pset_SpaceCommon - IsExternal: no; Reference: Appartment 214
Qto_SpaceBaseQuantities - Height: 243.84 cm; GrossFloorArea: 27.396 m2; NetFloorArea: 27.396 m2; GrossCeilingArea: 27.396 m2; NetVolume: 66.8024 m3

# IfcSpace: Appartment 215:3027093, 215
In: 06_Sixth Floor
LongName: Appartment
Pset_SpaceCommon - IsExternal: no; Reference: Appartment 215
Qto_SpaceBaseQuantities - Height: 243.84 cm; GrossFloorArea: 27.396 m2; NetFloorArea: 27.396 m2; GrossCeilingArea: 27.396 m2; NetVolume: 66.8024 m3

# IfcSpace: Appartment 216:3027096, 216
In: 06_Sixth Floor
LongName: Appartment
Pset_SpaceCommon - IsExternal: no; Reference: Appartment 216
Qto_SpaceBaseQuantities - Height: 243.84 cm; GrossFloorArea: 27.396 m2; NetFloorArea: 27.396 m2; GrossCeilingArea: 27.396 m2; NetVolume: 66.8024 m3

# IfcSpace: Appartment 217:3027099, 217
In: 06_Sixth Floor
LongName: Appartment
Pset_SpaceCommon - IsExternal: no; Reference: Appartment 217
Qto_SpaceBaseQuantities - Height: 243.84 cm; GrossFloorArea: 27.396 m2; NetFloorArea: 27.396 m2; GrossCeilingArea: 27.396 m2; NetVolume: 66.8024 m3

# IfcSpace: Appartment 218:3027102, 218
In: 06_Sixth Floor
LongName: Appartment
Pset_SpaceCommon - IsExternal: no; Reference: Appartment 218
Qto_SpaceBaseQuantities - Height: 243.84 cm; GrossFloorArea: 27.396 m2; NetFloorArea: 27.396 m2; GrossCeilingArea: 27.396 m2; NetVolume: 66.8024 m3

# IfcSpace: Appartment 219:3027105, 219
In: 06_Sixth Floor
LongName: Appartment
Pset_SpaceCommon - IsExternal: no; Reference: Appartment 219
Qto_SpaceBaseQuantities - Height: 243.84 cm; GrossFloorArea: 27.396 m2; NetFloorArea: 27.396 m2; GrossCeilingArea: 27.396 m2; NetVolume: 66.8024 m3

# IfcSpace: Appartment 21:3026511, 21
In: 00_Ground Floor
LongName: Appartment
Pset_SpaceCommon - IsExternal: no; Reference: Appartment 21
Qto_SpaceBaseQuantities - Height: 243.84 cm; GrossFloorArea: 27.396 m2; NetFloorArea: 27.396 m2; GrossCeilingArea: 27.396 m2; NetVolume: 66.8024 m3

# IfcSpace: Appartment 220:3027108, 220
In: 06_Sixth Floor
LongName: Appartment
Pset_SpaceCommon - IsExternal: no; Reference: Appartment 220
Qto_SpaceBaseQuantities - Height: 243.84 cm; GrossFloorArea: 27.396 m2; NetFloorArea: 27.396 m2; GrossCeilingArea: 27.396 m2; NetVolume: 66.8024 m3

# IfcSpace: Appartment 221:3027111, 221
In: 06_Sixth Floor
LongName: Appartment
Pset_SpaceCommon - IsExternal: no; Reference: Appartment 221
Qto_SpaceBaseQuantities - Height: 243.84 cm; GrossFloorArea: 27.396 m2; NetFloorArea: 27.396 m2; GrossCeilingArea: 27.396 m2; NetVolume: 66.8024 m3

# IfcSpace: Appartment 222:3027114, 222
In: 06_Sixth Floor
LongName: Appartment
Pset_SpaceCommon - IsExternal: no; Reference: Appartment 222
Qto_SpaceBaseQuantities - Height: 243.84 cm; GrossFloorArea: 27.396 m2; NetFloorArea: 27.396 m2; GrossCeilingArea: 27.396 m2; NetVolume: 66.8024 m3

# IfcSpace: Appartment 223:3027117, 223
In: 06_Sixth Floor
LongName: Appartment
Pset_SpaceCommon - IsExternal: no; Reference: Appartment 223
Qto_SpaceBaseQuantities - Height: 243.84 cm; GrossFloorArea: 27.396 m2; NetFloorArea: 27.396 m2; GrossCeilingArea: 27.396 m2; NetVolume: 66.8024 m3

# IfcSpace: Appartment 224:3027120, 224
In: 06_Sixth Floor
LongName: Appartment
Pset_SpaceCommon - IsExternal: no; Reference: Appartment 224
Qto_SpaceBaseQuantities - Height: 243.84 cm; GrossFloorArea: 27.396 m2; NetFloorArea: 27.396 m2; GrossCeilingArea: 27.396 m2; NetVolume: 66.8024 m3

# IfcSpace: Appartment 225:3027123, 225
In: 06_Sixth Floor
LongName: Appartment
Pset_SpaceCommon - IsExternal: no; Reference: Appartment 225
Qto_SpaceBaseQuantities - Height: 243.84 cm; GrossFloorArea: 27.396 m2; NetFloorArea: 27.396 m2; GrossCeilingArea: 27.396 m2; NetVolume: 66.8024 m3

# IfcSpace: Appartment 226:3027126, 226
In: 06_Sixth Floor
LongName: Appartment
Pset_SpaceCommon - IsExternal: no; Reference: Appartment 226
Qto_SpaceBaseQuantities - Height: 243.84 cm; GrossFloorArea: 27.396 m2; NetFloorArea: 27.396 m2; GrossCeilingArea: 27.396 m2; NetVolume: 66.8024 m3

# IfcSpace: Appartment 227:3027129, 227
In: 06_Sixth Floor
LongName: Appartment
Pset_SpaceCommon - IsExternal: no; Reference: Appartment 227
Qto_SpaceBaseQuantities - Height: 243.84 cm; GrossFloorArea: 27.396 m2; NetFloorArea: 27.396 m2; GrossCeilingArea: 27.396 m2; NetVolume: 66.8024 m3

# IfcSpace: Appartment 228:3027132, 228
In: 06_Sixth Floor
LongName: Appartment
Pset_SpaceCommon - IsExternal: no; Reference: Appartment 228
Qto_SpaceBaseQuantities - Height: 243.84 cm; GrossFloorArea: 27.396 m2; NetFloorArea: 27.396 m2; GrossCeilingArea: 27.396 m2; NetVolume: 66.8024 m3

# IfcSpace: Appartment 229:3027135, 229
In: 06_Sixth Floor
LongName: Appartment
Pset_SpaceCommon - IsExternal: no; Reference: Appartment 229
Qto_SpaceBaseQuantities - Height: 243.84 cm; GrossFloorArea: 27.396 m2; NetFloorArea: 27.396 m2; GrossCeilingArea: 27.396 m2; NetVolume: 66.8024 m3

# IfcSpace: Appartment 22:3026514, 22
In: 00_Ground Floor
LongName: Appartment
Pset_SpaceCommon - IsExternal: no; Reference: Appartment 22
Qto_SpaceBaseQuantities - Height: 243.84 cm; GrossFloorArea: 27.396 m2; NetFloorArea: 27.396 m2; GrossCeilingArea: 27.396 m2; NetVolume: 66.8024 m3

# IfcSpace: Appartment 230:3027138, 230
In: 06_Sixth Floor
LongName: Appartment
Pset_SpaceCommon - IsExternal: no; Reference: Appartment 230
Qto_SpaceBaseQuantities - Height: 243.84 cm; GrossFloorArea: 27.396 m2; NetFloorArea: 27.396 m2; GrossCeilingArea: 27.396 m2; NetVolume: 66.8024 m3

# IfcSpace: Appartment 231:3027141, 231
In: 06_Sixth Floor
LongName: Appartment
Pset_SpaceCommon - IsExternal: no; Reference: Appartment 231
Qto_SpaceBaseQuantities - Height: 243.84 cm; GrossFloorArea: 27.396 m2; NetFloorArea: 27.396 m2; GrossCeilingArea: 27.396 m2; NetVolume: 66.8024 m3

# IfcSpace: Appartment 232:3027144, 232
In: 06_Sixth Floor
LongName: Appartment
Pset_SpaceCommon - IsExternal: no; Reference: Appartment 232
Qto_SpaceBaseQuantities - Height: 243.84 cm; GrossFloorArea: 27.396 m2; NetFloorArea: 27.396 m2; GrossCeilingArea: 27.396 m2; NetVolume: 66.8024 m3

# IfcSpace: Appartment 233:3027147, 233
In: 06_Sixth Floor
LongName: Appartment
Pset_SpaceCommon - IsExternal: no; Reference: Appartment 233
Qto_SpaceBaseQuantities - Height: 243.84 cm; GrossFloorArea: 27.396 m2; NetFloorArea: 27.396 m2; GrossCeilingArea: 27.396 m2; NetVolume: 66.8024 m3

# IfcSpace: Appartment 234:3027150, 234
In: 06_Sixth Floor
LongName: Appartment
Pset_SpaceCommon - IsExternal: no; Reference: Appartment 234
Qto_SpaceBaseQuantities - Height: 243.84 cm; GrossFloorArea: 27.396 m2; NetFloorArea: 27.396 m2; GrossCeilingArea: 27.396 m2; NetVolume: 66.8024 m3

# IfcSpace: Appartment 235:3027153, 235
In: 06_Sixth Floor
LongName: Appartment
Pset_SpaceCommon - IsExternal: no; Reference: Appartment 235
Qto_SpaceBaseQuantities - Height: 243.84 cm; GrossFloorArea: 27.396 m2; NetFloorArea: 27.396 m2; GrossCeilingArea: 27.396 m2; NetVolume: 66.8024 m3

# IfcSpace: Appartment 236:3027156, 236
In: 06_Sixth Floor
LongName: Appartment
Pset_SpaceCommon - IsExternal: no; Reference: Appartment 236
Qto_SpaceBaseQuantities - Height: 243.84 cm; GrossFloorArea: 27.396 m2; NetFloorArea: 27.396 m2; GrossCeilingArea: 27.396 m2; NetVolume: 66.8024 m3

# IfcSpace: Appartment 237:3027159, 237
In: 06_Sixth Floor
LongName: Appartment
Pset_SpaceCommon - IsExternal: no; Reference: Appartment 237
Qto_SpaceBaseQuantities - Height: 243.84 cm; GrossFloorArea: 27.396 m2; NetFloorArea: 27.396 m2; GrossCeilingArea: 27.396 m2; NetVolume: 66.8024 m3

# IfcSpace: Appartment 238:3027162, 238
In: 06_Sixth Floor
LongName: Appartment
Pset_SpaceCommon - IsExternal: no; Reference: Appartment 238
Qto_SpaceBaseQuantities - Height: 243.84 cm; GrossFloorArea: 27.396 m2; NetFloorArea: 27.396 m2; GrossCeilingArea: 27.396 m2; NetVolume: 66.8024 m3

# IfcSpace: Appartment 239:3027165, 239
In: 06_Sixth Floor
LongName: Appartment
Pset_SpaceCommon - IsExternal: no; Reference: Appartment 239
Qto_SpaceBaseQuantities - Height: 243.84 cm; GrossFloorArea: 27.396 m2; NetFloorArea: 27.396 m2; GrossCeilingArea: 27.396 m2; NetVolume: 66.8024 m3

# IfcSpace: Appartment 23:3026517, 23
In: 00_Ground Floor
LongName: Appartment
Pset_SpaceCommon - IsExternal: no; Reference: Appartment 23
Qto_SpaceBaseQuantities - Height: 243.84 cm; GrossFloorArea: 27.396 m2; NetFloorArea: 27.396 m2; GrossCeilingArea: 27.396 m2; NetVolume: 66.8024 m3

# IfcSpace: Appartment 240:3027168, 240
In: 06_Sixth Floor
LongName: Appartment
Pset_SpaceCommon - IsExternal: no; Reference: Appartment 240
Qto_SpaceBaseQuantities - Height: 243.84 cm; GrossFloorArea: 27.396 m2; NetFloorArea: 27.396 m2; GrossCeilingArea: 27.396 m2; NetVolume: 66.8024 m3

# IfcSpace: Appartment 241:3027171, 241
In: 06_Sixth Floor
LongName: Appartment
Pset_SpaceCommon - IsExternal: no; Reference: Appartment 241
Qto_SpaceBaseQuantities - Height: 243.84 cm; GrossFloorArea: 27.396 m2; NetFloorArea: 27.396 m2; GrossCeilingArea: 27.396 m2; NetVolume: 66.8024 m3

# IfcSpace: Appartment 242:3027174, 242
In: 06_Sixth Floor
LongName: Appartment
Pset_SpaceCommon - IsExternal: no; Reference: Appartment 242
Qto_SpaceBaseQuantities - Height: 243.84 cm; GrossFloorArea: 27.396 m2; NetFloorArea: 27.396 m2; GrossCeilingArea: 27.396 m2; NetVolume: 66.8024 m3

# IfcSpace: Appartment 243:3027177, 243
In: 06_Sixth Floor
LongName: Appartment
Pset_SpaceCommon - IsExternal: no; Reference: Appartment 243
Qto_SpaceBaseQuantities - Height: 243.84 cm; GrossFloorArea: 27.396 m2; NetFloorArea: 27.396 m2; GrossCeilingArea: 27.396 m2; NetVolume: 66.8024 m3

# IfcSpace: Appartment 244:3027180, 244
In: 06_Sixth Floor
LongName: Appartment
Pset_SpaceCommon - IsExternal: no; Reference: Appartment 244
Qto_SpaceBaseQuantities - Height: 243.84 cm; GrossFloorArea: 27.396 m2; NetFloorArea: 27.396 m2; GrossCeilingArea: 27.396 m2; NetVolume: 66.8024 m3

# IfcSpace: Appartment 245:3027183, 245
In: 06_Sixth Floor
LongName: Appartment
Pset_SpaceCommon - IsExternal: no; Reference: Appartment 245
Qto_SpaceBaseQuantities - Height: 243.84 cm; GrossFloorArea: 27.396 m2; NetFloorArea: 27.396 m2; GrossCeilingArea: 27.396 m2; NetVolume: 66.8024 m3

# IfcSpace: Appartment 246:3027186, 246
In: 07_Seventh Floor
LongName: Appartment
Pset_SpaceCommon - IsExternal: no; Reference: Appartment 246
Qto_SpaceBaseQuantities - Height: 243.84 cm; GrossFloorArea: 27.396 m2; NetFloorArea: 27.396 m2; GrossCeilingArea: 27.396 m2; NetVolume: 66.8024 m3

# IfcSpace: Appartment 247:3027189, 247
In: 07_Seventh Floor
LongName: Appartment
Pset_SpaceCommon - IsExternal: no; Reference: Appartment 247
Qto_SpaceBaseQuantities - Height: 243.84 cm; GrossFloorArea: 27.396 m2; NetFloorArea: 27.396 m2; GrossCeilingArea: 27.396 m2; NetVolume: 66.8024 m3

# IfcSpace: Appartment 248:3027192, 248
In: 07_Seventh Floor
LongName: Appartment
Pset_SpaceCommon - IsExternal: no; Reference: Appartment 248
Qto_SpaceBaseQuantities - Height: 243.84 cm; GrossFloorArea: 27.396 m2; NetFloorArea: 27.396 m2; GrossCeilingArea: 27.396 m2; NetVolume: 66.8024 m3

# IfcSpace: Appartment 249:3027195, 249
In: 07_Seventh Floor
LongName: Appartment
Pset_SpaceCommon - IsExternal: no; Reference: Appartment 249
Qto_SpaceBaseQuantities - Height: 243.84 cm; GrossFloorArea: 27.396 m2; NetFloorArea: 27.396 m2; GrossCeilingArea: 27.396 m2; NetVolume: 66.8024 m3

# IfcSpace: Appartment 24:3026520, 24
In: 00_Ground Floor
LongName: Appartment
Pset_SpaceCommon - IsExternal: no; Reference: Appartment 24
Qto_SpaceBaseQuantities - Height: 243.84 cm; GrossFloorArea: 27.396 m2; NetFloorArea: 27.396 m2; GrossCeilingArea: 27.396 m2; NetVolume: 66.8024 m3

# IfcSpace: Appartment 250:3027198, 250
In: 07_Seventh Floor
LongName: Appartment
Pset_SpaceCommon - IsExternal: no; Reference: Appartment 250
Qto_SpaceBaseQuantities - Height: 243.84 cm; GrossFloorArea: 27.396 m2; NetFloorArea: 27.396 m2; GrossCeilingArea: 27.396 m2; NetVolume: 66.8024 m3

# IfcSpace: Appartment 251:3027201, 251
In: 07_Seventh Floor
LongName: Appartment
Pset_SpaceCommon - IsExternal: no; Reference: Appartment 251
Qto_SpaceBaseQuantities - Height: 243.84 cm; GrossFloorArea: 27.396 m2; NetFloorArea: 27.396 m2; GrossCeilingArea: 27.396 m2; NetVolume: 66.8024 m3

# IfcSpace: Appartment 252:3027204, 252
In: 07_Seventh Floor
LongName: Appartment
Pset_SpaceCommon - IsExternal: no; Reference: Appartment 252
Qto_SpaceBaseQuantities - Height: 243.84 cm; GrossFloorArea: 27.396 m2; NetFloorArea: 27.396 m2; GrossCeilingArea: 27.396 m2; NetVolume: 66.8024 m3

# IfcSpace: Appartment 253:3027207, 253
In: 07_Seventh Floor
LongName: Appartment
Pset_SpaceCommon - IsExternal: no; Reference: Appartment 253
Qto_SpaceBaseQuantities - Height: 243.84 cm; GrossFloorArea: 27.396 m2; NetFloorArea: 27.396 m2; GrossCeilingArea: 27.396 m2; NetVolume: 66.8024 m3

# IfcSpace: Appartment 254:3027210, 254
In: 07_Seventh Floor
LongName: Appartment
Pset_SpaceCommon - IsExternal: no; Reference: Appartment 254
Qto_SpaceBaseQuantities - Height: 243.84 cm; GrossFloorArea: 27.396 m2; NetFloorArea: 27.396 m2; GrossCeilingArea: 27.396 m2; NetVolume: 66.8024 m3

# IfcSpace: Appartment 255:3027213, 255
In: 07_Seventh Floor
LongName: Appartment
Pset_SpaceCommon - IsExternal: no; Reference: Appartment 255
Qto_SpaceBaseQuantities - Height: 243.84 cm; GrossFloorArea: 27.396 m2; NetFloorArea: 27.396 m2; GrossCeilingArea: 27.396 m2; NetVolume: 66.8024 m3

# IfcSpace: Appartment 256:3027216, 256
In: 07_Seventh Floor
LongName: Appartment
Pset_SpaceCommon - IsExternal: no; Reference: Appartment 256
Qto_SpaceBaseQuantities - Height: 243.84 cm; GrossFloorArea: 27.396 m2; NetFloorArea: 27.396 m2; GrossCeilingArea: 27.396 m2; NetVolume: 66.8024 m3

# IfcSpace: Appartment 257:3027219, 257
In: 07_Seventh Floor
LongName: Appartment
Pset_SpaceCommon - IsExternal: no; Reference: Appartment 257
Qto_SpaceBaseQuantities - Height: 243.84 cm; GrossFloorArea: 27.396 m2; NetFloorArea: 27.396 m2; GrossCeilingArea: 27.396 m2; NetVolume: 66.8024 m3

# IfcSpace: Appartment 258:3027222, 258
In: 07_Seventh Floor
LongName: Appartment
Pset_SpaceCommon - IsExternal: no; Reference: Appartment 258
Qto_SpaceBaseQuantities - Height: 243.84 cm; GrossFloorArea: 27.396 m2; NetFloorArea: 27.396 m2; GrossCeilingArea: 27.396 m2; NetVolume: 66.8024 m3

# IfcSpace: Appartment 259:3027225, 259
In: 07_Seventh Floor
LongName: Appartment
Pset_SpaceCommon - IsExternal: no; Reference: Appartment 259
Qto_SpaceBaseQuantities - Height: 243.84 cm; GrossFloorArea: 27.396 m2; NetFloorArea: 27.396 m2; GrossCeilingArea: 27.396 m2; NetVolume: 66.8024 m3

# IfcSpace: Appartment 25:3026523, 25
In: 00_Ground Floor
LongName: Appartment
Pset_SpaceCommon - IsExternal: no; Reference: Appartment 25
Qto_SpaceBaseQuantities - Height: 243.84 cm; GrossFloorArea: 27.396 m2; NetFloorArea: 27.396 m2; GrossCeilingArea: 27.396 m2; NetVolume: 66.8024 m3

# IfcSpace: Appartment 260:3027228, 260
In: 07_Seventh Floor
LongName: Appartment
Pset_SpaceCommon - IsExternal: no; Reference: Appartment 260
Qto_SpaceBaseQuantities - Height: 243.84 cm; GrossFloorArea: 27.396 m2; NetFloorArea: 27.396 m2; GrossCeilingArea: 27.396 m2; NetVolume: 66.8024 m3

# IfcSpace: Appartment 261:3027231, 261
In: 07_Seventh Floor
LongName: Appartment
Pset_SpaceCommon - IsExternal: no; Reference: Appartment 261
Qto_SpaceBaseQuantities - Height: 243.84 cm; GrossFloorArea: 27.396 m2; NetFloorArea: 27.396 m2; GrossCeilingArea: 27.396 m2; NetVolume: 66.8024 m3

# IfcSpace: Appartment 262:3027234, 262
In: 07_Seventh Floor
LongName: Appartment
Pset_SpaceCommon - IsExternal: no; Reference: Appartment 262
Qto_SpaceBaseQuantities - Height: 243.84 cm; GrossFloorArea: 27.396 m2; NetFloorArea: 27.396 m2; GrossCeilingArea: 27.396 m2; NetVolume: 66.8024 m3

# IfcSpace: Appartment 263:3027237, 263
In: 07_Seventh Floor
LongName: Appartment
Pset_SpaceCommon - IsExternal: no; Reference: Appartment 263
Qto_SpaceBaseQuantities - Height: 243.84 cm; GrossFloorArea: 27.396 m2; NetFloorArea: 27.396 m2; GrossCeilingArea: 27.396 m2; NetVolume: 66.8024 m3

# IfcSpace: Appartment 264:3027240, 264
In: 07_Seventh Floor
LongName: Appartment
Pset_SpaceCommon - IsExternal: no; Reference: Appartment 264
Qto_SpaceBaseQuantities - Height: 243.84 cm; GrossFloorArea: 27.396 m2; NetFloorArea: 27.396 m2; GrossCeilingArea: 27.396 m2; NetVolume: 66.8024 m3

# IfcSpace: Appartment 265:3027243, 265
In: 07_Seventh Floor
LongName: Appartment
Pset_SpaceCommon - IsExternal: no; Reference: Appartment 265
Qto_SpaceBaseQuantities - Height: 243.84 cm; GrossFloorArea: 27.396 m2; NetFloorArea: 27.396 m2; GrossCeilingArea: 27.396 m2; NetVolume: 66.8024 m3

# IfcSpace: Appartment 266:3027246, 266
In: 07_Seventh Floor
LongName: Appartment
Pset_SpaceCommon - IsExternal: no; Reference: Appartment 266
Qto_SpaceBaseQuantities - Height: 243.84 cm; GrossFloorArea: 27.396 m2; NetFloorArea: 27.396 m2; GrossCeilingArea: 27.396 m2; NetVolume: 66.8024 m3

# IfcSpace: Appartment 267:3027249, 267
In: 07_Seventh Floor
LongName: Appartment
Pset_SpaceCommon - IsExternal: no; Reference: Appartment 267
Qto_SpaceBaseQuantities - Height: 243.84 cm; GrossFloorArea: 27.396 m2; NetFloorArea: 27.396 m2; GrossCeilingArea: 27.396 m2; NetVolume: 66.8024 m3

# IfcSpace: Appartment 268:3027252, 268
In: 07_Seventh Floor
LongName: Appartment
Pset_SpaceCommon - IsExternal: no; Reference: Appartment 268
Qto_SpaceBaseQuantities - Height: 243.84 cm; GrossFloorArea: 27.396 m2; NetFloorArea: 27.396 m2; GrossCeilingArea: 27.396 m2; NetVolume: 66.8024 m3

# IfcSpace: Appartment 269:3027255, 269
In: 07_Seventh Floor
LongName: Appartment
Pset_SpaceCommon - IsExternal: no; Reference: Appartment 269
Qto_SpaceBaseQuantities - Height: 243.84 cm; GrossFloorArea: 27.396 m2; NetFloorArea: 27.396 m2; GrossCeilingArea: 27.396 m2; NetVolume: 66.8024 m3

# IfcSpace: Appartment 26:3026526, 26
In: 00_Ground Floor
LongName: Appartment
Pset_SpaceCommon - IsExternal: no; Reference: Appartment 26
Qto_SpaceBaseQuantities - Height: 243.84 cm; GrossFloorArea: 27.396 m2; NetFloorArea: 27.396 m2; GrossCeilingArea: 27.396 m2; NetVolume: 66.8024 m3

# IfcSpace: Appartment 270:3027258, 270
In: 07_Seventh Floor
LongName: Appartment
Pset_SpaceCommon - IsExternal: no; Reference: Appartment 270
Qto_SpaceBaseQuantities - Height: 243.84 cm; GrossFloorArea: 27.396 m2; NetFloorArea: 27.396 m2; GrossCeilingArea: 27.396 m2; NetVolume: 66.8024 m3

# IfcSpace: Appartment 271:3027261, 271
In: 07_Seventh Floor
LongName: Appartment
Pset_SpaceCommon - IsExternal: no; Reference: Appartment 271
Qto_SpaceBaseQuantities - Height: 243.84 cm; GrossFloorArea: 27.396 m2; NetFloorArea: 27.396 m2; GrossCeilingArea: 27.396 m2; NetVolume: 66.8024 m3

# IfcSpace: Appartment 272:3027264, 272
In: 07_Seventh Floor
LongName: Appartment
Pset_SpaceCommon - IsExternal: no; Reference: Appartment 272
Qto_SpaceBaseQuantities - Height: 243.84 cm; GrossFloorArea: 27.396 m2; NetFloorArea: 27.396 m2; GrossCeilingArea: 27.396 m2; NetVolume: 66.8024 m3

# IfcSpace: Appartment 273:3027267, 273
In: 07_Seventh Floor
LongName: Appartment
Pset_SpaceCommon - IsExternal: no; Reference: Appartment 273
Qto_SpaceBaseQuantities - Height: 243.84 cm; GrossFloorArea: 27.396 m2; NetFloorArea: 27.396 m2; GrossCeilingArea: 27.396 m2; NetVolume: 66.8024 m3

# IfcSpace: Appartment 274:3027270, 274
In: 07_Seventh Floor
LongName: Appartment
Pset_SpaceCommon - IsExternal: no; Reference: Appartment 274
Qto_SpaceBaseQuantities - Height: 243.84 cm; GrossFloorArea: 27.396 m2; NetFloorArea: 27.396 m2; GrossCeilingArea: 27.396 m2; NetVolume: 66.8024 m3

# IfcSpace: Appartment 275:3027273, 275
In: 07_Seventh Floor
LongName: Appartment
Pset_SpaceCommon - IsExternal: no; Reference: Appartment 275
Qto_SpaceBaseQuantities - Height: 243.84 cm; GrossFloorArea: 27.396 m2; NetFloorArea: 27.396 m2; GrossCeilingArea: 27.396 m2; NetVolume: 66.8024 m3

# IfcSpace: Appartment 276:3027276, 276
In: 07_Seventh Floor
LongName: Appartment
Pset_SpaceCommon - IsExternal: no; Reference: Appartment 276
Qto_SpaceBaseQuantities - Height: 243.84 cm; GrossFloorArea: 27.396 m2; NetFloorArea: 27.396 m2; GrossCeilingArea: 27.396 m2; NetVolume: 66.8024 m3

# IfcSpace: Appartment 277:3027279, 277
In: 07_Seventh Floor
LongName: Appartment
Pset_SpaceCommon - IsExternal: no; Reference: Appartment 277
Qto_SpaceBaseQuantities - Height: 243.84 cm; GrossFloorArea: 27.396 m2; NetFloorArea: 27.396 m2; GrossCeilingArea: 27.396 m2; NetVolume: 66.8024 m3

# IfcSpace: Appartment 278:3027282, 278
In: 07_Seventh Floor
LongName: Appartment
Pset_SpaceCommon - IsExternal: no; Reference: Appartment 278
Qto_SpaceBaseQuantities - Height: 243.84 cm; GrossFloorArea: 27.396 m2; NetFloorArea: 27.396 m2; GrossCeilingArea: 27.396 m2; NetVolume: 66.8024 m3

# IfcSpace: Appartment 279:3027285, 279
In: 07_Seventh Floor
LongName: Appartment
Pset_SpaceCommon - IsExternal: no; Reference: Appartment 279
Qto_SpaceBaseQuantities - Height: 243.84 cm; GrossFloorArea: 27.396 m2; NetFloorArea: 27.396 m2; GrossCeilingArea: 27.396 m2; NetVolume: 66.8024 m3

# IfcSpace: Appartment 27:3026529, 27
In: 00_Ground Floor
LongName: Appartment
Pset_SpaceCommon - IsExternal: no; Reference: Appartment 27
Qto_SpaceBaseQuantities - Height: 243.84 cm; GrossFloorArea: 27.396 m2; NetFloorArea: 27.396 m2; GrossCeilingArea: 27.396 m2; NetVolume: 66.8024 m3

# IfcSpace: Appartment 280:3027288, 280
In: 07_Seventh Floor
LongName: Appartment
Pset_SpaceCommon - IsExternal: no; Reference: Appartment 280
Qto_SpaceBaseQuantities - Height: 243.84 cm; GrossFloorArea: 27.396 m2; NetFloorArea: 27.396 m2; GrossCeilingArea: 27.396 m2; NetVolume: 66.8024 m3

# IfcSpace: Appartment 28:3026532, 28
In: 00_Ground Floor
LongName: Appartment
Pset_SpaceCommon - IsExternal: no; Reference: Appartment 28
Qto_SpaceBaseQuantities - Height: 243.84 cm; GrossFloorArea: 27.396 m2; NetFloorArea: 27.396 m2; GrossCeilingArea: 27.396 m2; NetVolume: 66.8024 m3

# IfcSpace: Appartment 29:3026535, 29
In: 00_Ground Floor
LongName: Appartment
Pset_SpaceCommon - IsExternal: no; Reference: Appartment 29
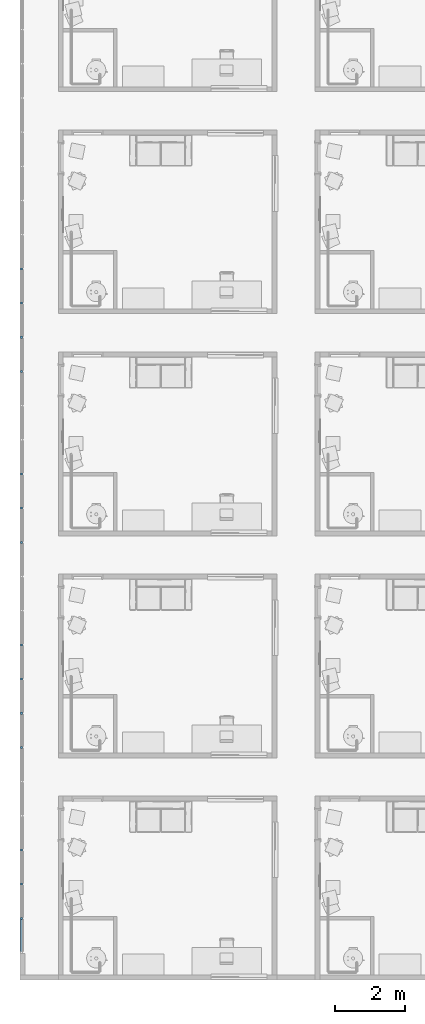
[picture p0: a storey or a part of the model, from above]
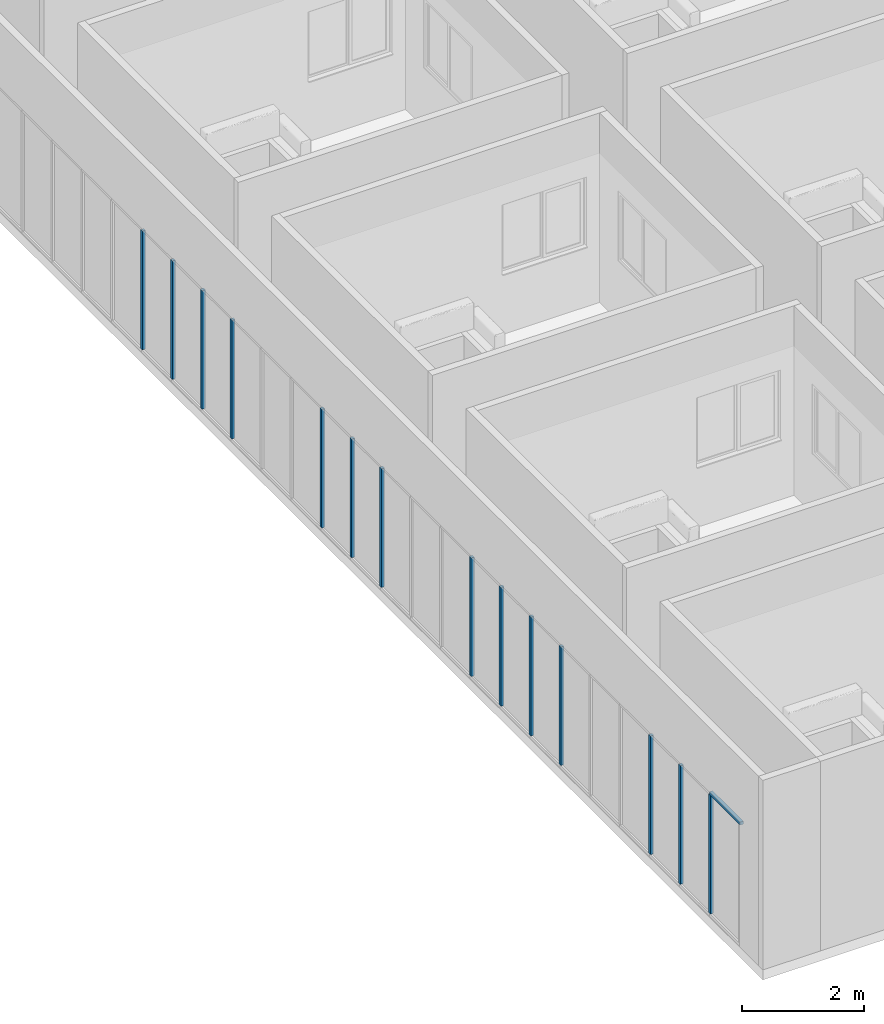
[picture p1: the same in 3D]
Properties of the parts of a building model (IFC4), part 2 of 14

# IfcSpace: Appartment 29:3026535, 29
Qto_SpaceBaseQuantities - Height: 243.84 cm; GrossFloorArea: 27.396 m2; NetFloorArea: 27.396 m2; GrossCeilingArea: 27.396 m2; NetVolume: 66.8024 m3

# IfcSpace: Appartment 2:3026454, 2
In: 00_Ground Floor
LongName: Appartment
Pset_SpaceCommon - IsExternal: no; Reference: Appartment 2
Qto_SpaceBaseQuantities - Height: 243.84 cm; GrossFloorArea: 27.396 m2; NetFloorArea: 27.396 m2; GrossCeilingArea: 27.396 m2; NetVolume: 66.8024 m3

# IfcSpace: Appartment 30:3026538, 30
In: 00_Ground Floor
LongName: Appartment
Pset_SpaceCommon - IsExternal: no; Reference: Appartment 30
Qto_SpaceBaseQuantities - Height: 243.84 cm; GrossFloorArea: 27.396 m2; NetFloorArea: 27.396 m2; GrossCeilingArea: 27.396 m2; NetVolume: 66.8024 m3

# IfcSpace: Appartment 31:3026541, 31
In: 00_Ground Floor
LongName: Appartment
Pset_SpaceCommon - IsExternal: no; Reference: Appartment 31
Qto_SpaceBaseQuantities - Height: 243.84 cm; GrossFloorArea: 27.396 m2; NetFloorArea: 27.396 m2; GrossCeilingArea: 27.396 m2; NetVolume: 66.8024 m3

# IfcSpace: Appartment 32:3026544, 32
In: 00_Ground Floor
LongName: Appartment
Pset_SpaceCommon - IsExternal: no; Reference: Appartment 32
Qto_SpaceBaseQuantities - Height: 243.84 cm; GrossFloorArea: 27.396 m2; NetFloorArea: 27.396 m2; GrossCeilingArea: 27.396 m2; NetVolume: 66.8024 m3

# IfcSpace: Appartment 33:3026547, 33
In: 00_Ground Floor
LongName: Appartment
Pset_SpaceCommon - IsExternal: no; Reference: Appartment 33
Qto_SpaceBaseQuantities - Height: 243.84 cm; GrossFloorArea: 27.396 m2; NetFloorArea: 27.396 m2; GrossCeilingArea: 27.396 m2; NetVolume: 66.8024 m3

# IfcSpace: Appartment 34:3026550, 34
In: 00_Ground Floor
LongName: Appartment
Pset_SpaceCommon - IsExternal: no; Reference: Appartment 34
Qto_SpaceBaseQuantities - Height: 243.84 cm; GrossFloorArea: 27.396 m2; NetFloorArea: 27.396 m2; GrossCeilingArea: 27.396 m2; NetVolume: 66.8024 m3

# IfcSpace: Appartment 35:3026553, 35
In: 00_Ground Floor
LongName: Appartment
Pset_SpaceCommon - IsExternal: no; Reference: Appartment 35
Qto_SpaceBaseQuantities - Height: 243.84 cm; GrossFloorArea: 27.396 m2; NetFloorArea: 27.396 m2; GrossCeilingArea: 27.396 m2; NetVolume: 66.8024 m3

# IfcSpace: Appartment 36:3026556, 36
In: 01_First Floor
LongName: Appartment
Pset_SpaceCommon - IsExternal: no; Reference: Appartment 36
Qto_SpaceBaseQuantities - Height: 243.84 cm; GrossFloorArea: 27.396 m2; NetFloorArea: 27.396 m2; GrossCeilingArea: 27.396 m2; NetVolume: 66.8024 m3

# IfcSpace: Appartment 37:3026559, 37
In: 01_First Floor
LongName: Appartment
Pset_SpaceCommon - IsExternal: no; Reference: Appartment 37
Qto_SpaceBaseQuantities - Height: 243.84 cm; GrossFloorArea: 27.396 m2; NetFloorArea: 27.396 m2; GrossCeilingArea: 27.396 m2; NetVolume: 66.8024 m3

# IfcSpace: Appartment 38:3026562, 38
In: 01_First Floor
LongName: Appartment
Pset_SpaceCommon - IsExternal: no; Reference: Appartment 38
Qto_SpaceBaseQuantities - Height: 243.84 cm; GrossFloorArea: 27.396 m2; NetFloorArea: 27.396 m2; GrossCeilingArea: 27.396 m2; NetVolume: 66.8024 m3

# IfcSpace: Appartment 39:3026565, 39
In: 01_First Floor
LongName: Appartment
Pset_SpaceCommon - IsExternal: no; Reference: Appartment 39
Qto_SpaceBaseQuantities - Height: 243.84 cm; GrossFloorArea: 27.396 m2; NetFloorArea: 27.396 m2; GrossCeilingArea: 27.396 m2; NetVolume: 66.8024 m3

# IfcSpace: Appartment 3:3026457, 3
In: 00_Ground Floor
LongName: Appartment
Pset_SpaceCommon - IsExternal: no; Reference: Appartment 3
Qto_SpaceBaseQuantities - Height: 243.84 cm; GrossFloorArea: 27.396 m2; NetFloorArea: 27.396 m2; GrossCeilingArea: 27.396 m2; NetVolume: 66.8024 m3

# IfcSpace: Appartment 40:3026568, 40
In: 01_First Floor
LongName: Appartment
Pset_SpaceCommon - IsExternal: no; Reference: Appartment 40
Qto_SpaceBaseQuantities - Height: 243.84 cm; GrossFloorArea: 27.396 m2; NetFloorArea: 27.396 m2; GrossCeilingArea: 27.396 m2; NetVolume: 66.8024 m3

# IfcSpace: Appartment 41:3026571, 41
In: 01_First Floor
LongName: Appartment
Pset_SpaceCommon - IsExternal: no; Reference: Appartment 41
Qto_SpaceBaseQuantities - Height: 243.84 cm; GrossFloorArea: 27.396 m2; NetFloorArea: 27.396 m2; GrossCeilingArea: 27.396 m2; NetVolume: 66.8024 m3

# IfcSpace: Appartment 42:3026574, 42
In: 01_First Floor
LongName: Appartment
Pset_SpaceCommon - IsExternal: no; Reference: Appartment 42
Qto_SpaceBaseQuantities - Height: 243.84 cm; GrossFloorArea: 27.396 m2; NetFloorArea: 27.396 m2; GrossCeilingArea: 27.396 m2; NetVolume: 66.8024 m3

# IfcSpace: Appartment 43:3026577, 43
In: 01_First Floor
LongName: Appartment
Pset_SpaceCommon - IsExternal: no; Reference: Appartment 43
Qto_SpaceBaseQuantities - Height: 243.84 cm; GrossFloorArea: 27.396 m2; NetFloorArea: 27.396 m2; GrossCeilingArea: 27.396 m2; NetVolume: 66.8024 m3

# IfcSpace: Appartment 44:3026580, 44
In: 01_First Floor
LongName: Appartment
Pset_SpaceCommon - IsExternal: no; Reference: Appartment 44
Qto_SpaceBaseQuantities - Height: 243.84 cm; GrossFloorArea: 27.396 m2; NetFloorArea: 27.396 m2; GrossCeilingArea: 27.396 m2; NetVolume: 66.8024 m3

# IfcSpace: Appartment 45:3026583, 45
In: 01_First Floor
LongName: Appartment
Pset_SpaceCommon - IsExternal: no; Reference: Appartment 45
Qto_SpaceBaseQuantities - Height: 243.84 cm; GrossFloorArea: 27.396 m2; NetFloorArea: 27.396 m2; GrossCeilingArea: 27.396 m2; NetVolume: 66.8024 m3

# IfcSpace: Appartment 46:3026586, 46
In: 01_First Floor
LongName: Appartment
Pset_SpaceCommon - IsExternal: no; Reference: Appartment 46
Qto_SpaceBaseQuantities - Height: 243.84 cm; GrossFloorArea: 27.396 m2; NetFloorArea: 27.396 m2; GrossCeilingArea: 27.396 m2; NetVolume: 66.8024 m3

# IfcSpace: Appartment 47:3026589, 47
In: 01_First Floor
LongName: Appartment
Pset_SpaceCommon - IsExternal: no; Reference: Appartment 47
Qto_SpaceBaseQuantities - Height: 243.84 cm; GrossFloorArea: 27.396 m2; NetFloorArea: 27.396 m2; GrossCeilingArea: 27.396 m2; NetVolume: 66.8024 m3

# IfcSpace: Appartment 48:3026592, 48
In: 01_First Floor
LongName: Appartment
Pset_SpaceCommon - IsExternal: no; Reference: Appartment 48
Qto_SpaceBaseQuantities - Height: 243.84 cm; GrossFloorArea: 27.396 m2; NetFloorArea: 27.396 m2; GrossCeilingArea: 27.396 m2; NetVolume: 66.8024 m3

# IfcSpace: Appartment 49:3026595, 49
In: 01_First Floor
LongName: Appartment
Pset_SpaceCommon - IsExternal: no; Reference: Appartment 49
Qto_SpaceBaseQuantities - Height: 243.84 cm; GrossFloorArea: 27.396 m2; NetFloorArea: 27.396 m2; GrossCeilingArea: 27.396 m2; NetVolume: 66.8024 m3

# IfcSpace: Appartment 4:3026460, 4
In: 00_Ground Floor
LongName: Appartment
Pset_SpaceCommon - IsExternal: no; Reference: Appartment 4
Qto_SpaceBaseQuantities - Height: 243.84 cm; GrossFloorArea: 27.396 m2; NetFloorArea: 27.396 m2; GrossCeilingArea: 27.396 m2; NetVolume: 66.8024 m3

# IfcSpace: Appartment 50:3026598, 50
In: 01_First Floor
LongName: Appartment
Pset_SpaceCommon - IsExternal: no; Reference: Appartment 50
Qto_SpaceBaseQuantities - Height: 243.84 cm; GrossFloorArea: 27.396 m2; NetFloorArea: 27.396 m2; GrossCeilingArea: 27.396 m2; NetVolume: 66.8024 m3

# IfcSpace: Appartment 51:3026601, 51
In: 01_First Floor
LongName: Appartment
Pset_SpaceCommon - IsExternal: no; Reference: Appartment 51
Qto_SpaceBaseQuantities - Height: 243.84 cm; GrossFloorArea: 27.396 m2; NetFloorArea: 27.396 m2; GrossCeilingArea: 27.396 m2; NetVolume: 66.8024 m3

# IfcSpace: Appartment 52:3026604, 52
In: 01_First Floor
LongName: Appartment
Pset_SpaceCommon - IsExternal: no; Reference: Appartment 52
Qto_SpaceBaseQuantities - Height: 243.84 cm; GrossFloorArea: 27.396 m2; NetFloorArea: 27.396 m2; GrossCeilingArea: 27.396 m2; NetVolume: 66.8024 m3

# IfcSpace: Appartment 53:3026607, 53
In: 01_First Floor
LongName: Appartment
Pset_SpaceCommon - IsExternal: no; Reference: Appartment 53
Qto_SpaceBaseQuantities - Height: 243.84 cm; GrossFloorArea: 27.396 m2; NetFloorArea: 27.396 m2; GrossCeilingArea: 27.396 m2; NetVolume: 66.8024 m3

# IfcSpace: Appartment 54:3026610, 54
In: 01_First Floor
LongName: Appartment
Pset_SpaceCommon - IsExternal: no; Reference: Appartment 54
Qto_SpaceBaseQuantities - Height: 243.84 cm; GrossFloorArea: 27.396 m2; NetFloorArea: 27.396 m2; GrossCeilingArea: 27.396 m2; NetVolume: 66.8024 m3

# IfcSpace: Appartment 55:3026613, 55
In: 01_First Floor
LongName: Appartment
Pset_SpaceCommon - IsExternal: no; Reference: Appartment 55
Qto_SpaceBaseQuantities - Height: 243.84 cm; GrossFloorArea: 27.396 m2; NetFloorArea: 27.396 m2; GrossCeilingArea: 27.396 m2; NetVolume: 66.8024 m3

# IfcSpace: Appartment 56:3026616, 56
In: 01_First Floor
LongName: Appartment
Pset_SpaceCommon - IsExternal: no; Reference: Appartment 56
Qto_SpaceBaseQuantities - Height: 243.84 cm; GrossFloorArea: 27.396 m2; NetFloorArea: 27.396 m2; GrossCeilingArea: 27.396 m2; NetVolume: 66.8024 m3

# IfcSpace: Appartment 57:3026619, 57
In: 01_First Floor
LongName: Appartment
Pset_SpaceCommon - IsExternal: no; Reference: Appartment 57
Qto_SpaceBaseQuantities - Height: 243.84 cm; GrossFloorArea: 27.396 m2; NetFloorArea: 27.396 m2; GrossCeilingArea: 27.396 m2; NetVolume: 66.8024 m3

# IfcSpace: Appartment 58:3026622, 58
In: 01_First Floor
LongName: Appartment
Pset_SpaceCommon - IsExternal: no; Reference: Appartment 58
Qto_SpaceBaseQuantities - Height: 243.84 cm; GrossFloorArea: 27.396 m2; NetFloorArea: 27.396 m2; GrossCeilingArea: 27.396 m2; NetVolume: 66.8024 m3

# IfcSpace: Appartment 59:3026625, 59
In: 01_First Floor
LongName: Appartment
Pset_SpaceCommon - IsExternal: no; Reference: Appartment 59
Qto_SpaceBaseQuantities - Height: 243.84 cm; GrossFloorArea: 27.396 m2; NetFloorArea: 27.396 m2; GrossCeilingArea: 27.396 m2; NetVolume: 66.8024 m3

# IfcSpace: Appartment 5:3026463, 5
In: 00_Ground Floor
LongName: Appartment
Pset_SpaceCommon - IsExternal: no; Reference: Appartment 5
Qto_SpaceBaseQuantities - Height: 243.84 cm; GrossFloorArea: 27.396 m2; NetFloorArea: 27.396 m2; GrossCeilingArea: 27.396 m2; NetVolume: 66.8024 m3

# IfcSpace: Appartment 60:3026628, 60
In: 01_First Floor
LongName: Appartment
Pset_SpaceCommon - IsExternal: no; Reference: Appartment 60
Qto_SpaceBaseQuantities - Height: 243.84 cm; GrossFloorArea: 27.396 m2; NetFloorArea: 27.396 m2; GrossCeilingArea: 27.396 m2; NetVolume: 66.8024 m3

# IfcSpace: Appartment 61:3026631, 61
In: 01_First Floor
LongName: Appartment
Pset_SpaceCommon - IsExternal: no; Reference: Appartment 61
Qto_SpaceBaseQuantities - Height: 243.84 cm; GrossFloorArea: 27.396 m2; NetFloorArea: 27.396 m2; GrossCeilingArea: 27.396 m2; NetVolume: 66.8024 m3

# IfcSpace: Appartment 62:3026634, 62
In: 01_First Floor
LongName: Appartment
Pset_SpaceCommon - IsExternal: no; Reference: Appartment 62
Qto_SpaceBaseQuantities - Height: 243.84 cm; GrossFloorArea: 27.396 m2; NetFloorArea: 27.396 m2; GrossCeilingArea: 27.396 m2; NetVolume: 66.8024 m3

# IfcSpace: Appartment 63:3026637, 63
In: 01_First Floor
LongName: Appartment
Pset_SpaceCommon - IsExternal: no; Reference: Appartment 63
Qto_SpaceBaseQuantities - Height: 243.84 cm; GrossFloorArea: 27.396 m2; NetFloorArea: 27.396 m2; GrossCeilingArea: 27.396 m2; NetVolume: 66.8024 m3

# IfcSpace: Appartment 64:3026640, 64
In: 01_First Floor
LongName: Appartment
Pset_SpaceCommon - IsExternal: no; Reference: Appartment 64
Qto_SpaceBaseQuantities - Height: 243.84 cm; GrossFloorArea: 27.396 m2; NetFloorArea: 27.396 m2; GrossCeilingArea: 27.396 m2; NetVolume: 66.8024 m3

# IfcSpace: Appartment 65:3026643, 65
In: 01_First Floor
LongName: Appartment
Pset_SpaceCommon - IsExternal: no; Reference: Appartment 65
Qto_SpaceBaseQuantities - Height: 243.84 cm; GrossFloorArea: 27.396 m2; NetFloorArea: 27.396 m2; GrossCeilingArea: 27.396 m2; NetVolume: 66.8024 m3

# IfcSpace: Appartment 66:3026646, 66
In: 01_First Floor
LongName: Appartment
Pset_SpaceCommon - IsExternal: no; Reference: Appartment 66
Qto_SpaceBaseQuantities - Height: 243.84 cm; GrossFloorArea: 27.396 m2; NetFloorArea: 27.396 m2; GrossCeilingArea: 27.396 m2; NetVolume: 66.8024 m3

# IfcSpace: Appartment 67:3026649, 67
In: 01_First Floor
LongName: Appartment
Pset_SpaceCommon - IsExternal: no; Reference: Appartment 67
Qto_SpaceBaseQuantities - Height: 243.84 cm; GrossFloorArea: 27.396 m2; NetFloorArea: 27.396 m2; GrossCeilingArea: 27.396 m2; NetVolume: 66.8024 m3

# IfcSpace: Appartment 68:3026652, 68
In: 01_First Floor
LongName: Appartment
Pset_SpaceCommon - IsExternal: no; Reference: Appartment 68
Qto_SpaceBaseQuantities - Height: 243.84 cm; GrossFloorArea: 27.396 m2; NetFloorArea: 27.396 m2; GrossCeilingArea: 27.396 m2; NetVolume: 66.8024 m3

# IfcSpace: Appartment 69:3026655, 69
In: 01_First Floor
LongName: Appartment
Pset_SpaceCommon - IsExternal: no; Reference: Appartment 69
Qto_SpaceBaseQuantities - Height: 243.84 cm; GrossFloorArea: 27.396 m2; NetFloorArea: 27.396 m2; GrossCeilingArea: 27.396 m2; NetVolume: 66.8024 m3

# IfcSpace: Appartment 6:3026466, 6
In: 00_Ground Floor
LongName: Appartment
Pset_SpaceCommon - IsExternal: no; Reference: Appartment 6
Qto_SpaceBaseQuantities - Height: 243.84 cm; GrossFloorArea: 27.396 m2; NetFloorArea: 27.396 m2; GrossCeilingArea: 27.396 m2; NetVolume: 66.8024 m3

# IfcSpace: Appartment 70:3026658, 70
In: 01_First Floor
LongName: Appartment
Pset_SpaceCommon - IsExternal: no; Reference: Appartment 70
Qto_SpaceBaseQuantities - Height: 243.84 cm; GrossFloorArea: 27.396 m2; NetFloorArea: 27.396 m2; GrossCeilingArea: 27.396 m2; NetVolume: 66.8024 m3

# IfcSpace: Appartment 71:3026661, 71
In: 02_Second Floor
LongName: Appartment
Pset_SpaceCommon - IsExternal: no; Reference: Appartment 71
Qto_SpaceBaseQuantities - Height: 243.84 cm; GrossFloorArea: 27.396 m2; NetFloorArea: 27.396 m2; GrossCeilingArea: 27.396 m2; NetVolume: 66.8024 m3

# IfcSpace: Appartment 72:3026664, 72
In: 02_Second Floor
LongName: Appartment
Pset_SpaceCommon - IsExternal: no; Reference: Appartment 72
Qto_SpaceBaseQuantities - Height: 243.84 cm; GrossFloorArea: 27.396 m2; NetFloorArea: 27.396 m2; GrossCeilingArea: 27.396 m2; NetVolume: 66.8024 m3

# IfcSpace: Appartment 73:3026667, 73
In: 02_Second Floor
LongName: Appartment
Pset_SpaceCommon - IsExternal: no; Reference: Appartment 73
Qto_SpaceBaseQuantities - Height: 243.84 cm; GrossFloorArea: 27.396 m2; NetFloorArea: 27.396 m2; GrossCeilingArea: 27.396 m2; NetVolume: 66.8024 m3

# IfcSpace: Appartment 74:3026670, 74
In: 02_Second Floor
LongName: Appartment
Pset_SpaceCommon - IsExternal: no; Reference: Appartment 74
Qto_SpaceBaseQuantities - Height: 243.84 cm; GrossFloorArea: 27.396 m2; NetFloorArea: 27.396 m2; GrossCeilingArea: 27.396 m2; NetVolume: 66.8024 m3

# IfcSpace: Appartment 75:3026673, 75
In: 02_Second Floor
LongName: Appartment
Pset_SpaceCommon - IsExternal: no; Reference: Appartment 75
Qto_SpaceBaseQuantities - Height: 243.84 cm; GrossFloorArea: 27.396 m2; NetFloorArea: 27.396 m2; GrossCeilingArea: 27.396 m2; NetVolume: 66.8024 m3

# IfcSpace: Appartment 76:3026676, 76
In: 02_Second Floor
LongName: Appartment
Pset_SpaceCommon - IsExternal: no; Reference: Appartment 76
Qto_SpaceBaseQuantities - Height: 243.84 cm; GrossFloorArea: 27.396 m2; NetFloorArea: 27.396 m2; GrossCeilingArea: 27.396 m2; NetVolume: 66.8024 m3

# IfcSpace: Appartment 77:3026679, 77
In: 02_Second Floor
LongName: Appartment
Pset_SpaceCommon - IsExternal: no; Reference: Appartment 77
Qto_SpaceBaseQuantities - Height: 243.84 cm; GrossFloorArea: 27.396 m2; NetFloorArea: 27.396 m2; GrossCeilingArea: 27.396 m2; NetVolume: 66.8024 m3

# IfcSpace: Appartment 78:3026682, 78
In: 02_Second Floor
LongName: Appartment
Pset_SpaceCommon - IsExternal: no; Reference: Appartment 78
Qto_SpaceBaseQuantities - Height: 243.84 cm; GrossFloorArea: 27.396 m2; NetFloorArea: 27.396 m2; GrossCeilingArea: 27.396 m2; NetVolume: 66.8024 m3

# IfcSpace: Appartment 79:3026685, 79
In: 02_Second Floor
LongName: Appartment
Pset_SpaceCommon - IsExternal: no; Reference: Appartment 79
Qto_SpaceBaseQuantities - Height: 243.84 cm; GrossFloorArea: 27.396 m2; NetFloorArea: 27.396 m2; GrossCeilingArea: 27.396 m2; NetVolume: 66.8024 m3

# IfcSpace: Appartment 7:3026469, 7
In: 00_Ground Floor
LongName: Appartment
Pset_SpaceCommon - IsExternal: no; Reference: Appartment 7
Qto_SpaceBaseQuantities - Height: 243.84 cm; GrossFloorArea: 27.396 m2; NetFloorArea: 27.396 m2; GrossCeilingArea: 27.396 m2; NetVolume: 66.8024 m3

# IfcSpace: Appartment 80:3026688, 80
In: 02_Second Floor
LongName: Appartment
Pset_SpaceCommon - IsExternal: no; Reference: Appartment 80
Qto_SpaceBaseQuantities - Height: 243.84 cm; GrossFloorArea: 27.396 m2; NetFloorArea: 27.396 m2; GrossCeilingArea: 27.396 m2; NetVolume: 66.8024 m3

# IfcSpace: Appartment 81:3026691, 81
In: 02_Second Floor
LongName: Appartment
Pset_SpaceCommon - IsExternal: no; Reference: Appartment 81
Qto_SpaceBaseQuantities - Height: 243.84 cm; GrossFloorArea: 27.396 m2; NetFloorArea: 27.396 m2; GrossCeilingArea: 27.396 m2; NetVolume: 66.8024 m3

# IfcSpace: Appartment 82:3026694, 82
In: 02_Second Floor
LongName: Appartment
Pset_SpaceCommon - IsExternal: no; Reference: Appartment 82
Qto_SpaceBaseQuantities - Height: 243.84 cm; GrossFloorArea: 27.396 m2; NetFloorArea: 27.396 m2; GrossCeilingArea: 27.396 m2; NetVolume: 66.8024 m3

# IfcSpace: Appartment 83:3026697, 83
In: 02_Second Floor
LongName: Appartment
Pset_SpaceCommon - IsExternal: no; Reference: Appartment 83
Qto_SpaceBaseQuantities - Height: 243.84 cm; GrossFloorArea: 27.396 m2; NetFloorArea: 27.396 m2; GrossCeilingArea: 27.396 m2; NetVolume: 66.8024 m3

# IfcSpace: Appartment 84:3026700, 84
In: 02_Second Floor
LongName: Appartment
Pset_SpaceCommon - IsExternal: no; Reference: Appartment 84
Qto_SpaceBaseQuantities - Height: 243.84 cm; GrossFloorArea: 27.396 m2; NetFloorArea: 27.396 m2; GrossCeilingArea: 27.396 m2; NetVolume: 66.8024 m3

# IfcSpace: Appartment 85:3026703, 85
In: 02_Second Floor
LongName: Appartment
Pset_SpaceCommon - IsExternal: no; Reference: Appartment 85
Qto_SpaceBaseQuantities - Height: 243.84 cm; GrossFloorArea: 27.396 m2; NetFloorArea: 27.396 m2; GrossCeilingArea: 27.396 m2; NetVolume: 66.8024 m3

# IfcSpace: Appartment 86:3026706, 86
In: 02_Second Floor
LongName: Appartment
Pset_SpaceCommon - IsExternal: no; Reference: Appartment 86
Qto_SpaceBaseQuantities - Height: 243.84 cm; GrossFloorArea: 27.396 m2; NetFloorArea: 27.396 m2; GrossCeilingArea: 27.396 m2; NetVolume: 66.8024 m3

# IfcSpace: Appartment 87:3026709, 87
In: 02_Second Floor
LongName: Appartment
Pset_SpaceCommon - IsExternal: no; Reference: Appartment 87
Qto_SpaceBaseQuantities - Height: 243.84 cm; GrossFloorArea: 27.396 m2; NetFloorArea: 27.396 m2; GrossCeilingArea: 27.396 m2; NetVolume: 66.8024 m3

# IfcSpace: Appartment 88:3026712, 88
In: 02_Second Floor
LongName: Appartment
Pset_SpaceCommon - IsExternal: no; Reference: Appartment 88
Qto_SpaceBaseQuantities - Height: 243.84 cm; GrossFloorArea: 27.396 m2; NetFloorArea: 27.396 m2; GrossCeilingArea: 27.396 m2; NetVolume: 66.8024 m3

# IfcSpace: Appartment 89:3026715, 89
In: 02_Second Floor
LongName: Appartment
Pset_SpaceCommon - IsExternal: no; Reference: Appartment 89
Qto_SpaceBaseQuantities - Height: 243.84 cm; GrossFloorArea: 27.396 m2; NetFloorArea: 27.396 m2; GrossCeilingArea: 27.396 m2; NetVolume: 66.8024 m3

# IfcSpace: Appartment 8:3026472, 8
In: 00_Ground Floor
LongName: Appartment
Pset_SpaceCommon - IsExternal: no; Reference: Appartment 8
Qto_SpaceBaseQuantities - Height: 243.84 cm; GrossFloorArea: 27.396 m2; NetFloorArea: 27.396 m2; GrossCeilingArea: 27.396 m2; NetVolume: 66.8024 m3

# IfcSpace: Appartment 90:3026718, 90
In: 02_Second Floor
LongName: Appartment
Pset_SpaceCommon - IsExternal: no; Reference: Appartment 90
Qto_SpaceBaseQuantities - Height: 243.84 cm; GrossFloorArea: 27.396 m2; NetFloorArea: 27.396 m2; GrossCeilingArea: 27.396 m2; NetVolume: 66.8024 m3

# IfcSpace: Appartment 91:3026721, 91
In: 02_Second Floor
LongName: Appartment
Pset_SpaceCommon - IsExternal: no; Reference: Appartment 91
Qto_SpaceBaseQuantities - Height: 243.84 cm; GrossFloorArea: 27.396 m2; NetFloorArea: 27.396 m2; GrossCeilingArea: 27.396 m2; NetVolume: 66.8024 m3

# IfcSpace: Appartment 92:3026724, 92
In: 02_Second Floor
LongName: Appartment
Pset_SpaceCommon - IsExternal: no; Reference: Appartment 92
Qto_SpaceBaseQuantities - Height: 243.84 cm; GrossFloorArea: 27.396 m2; NetFloorArea: 27.396 m2; GrossCeilingArea: 27.396 m2; NetVolume: 66.8024 m3

# IfcSpace: Appartment 93:3026727, 93
In: 02_Second Floor
LongName: Appartment
Pset_SpaceCommon - IsExternal: no; Reference: Appartment 93
Qto_SpaceBaseQuantities - Height: 243.84 cm; GrossFloorArea: 27.396 m2; NetFloorArea: 27.396 m2; GrossCeilingArea: 27.396 m2; NetVolume: 66.8024 m3

# IfcSpace: Appartment 94:3026730, 94
In: 02_Second Floor
LongName: Appartment
Pset_SpaceCommon - IsExternal: no; Reference: Appartment 94
Qto_SpaceBaseQuantities - Height: 243.84 cm; GrossFloorArea: 27.396 m2; NetFloorArea: 27.396 m2; GrossCeilingArea: 27.396 m2; NetVolume: 66.8024 m3

# IfcSpace: Appartment 95:3026733, 95
In: 02_Second Floor
LongName: Appartment
Pset_SpaceCommon - IsExternal: no; Reference: Appartment 95
Qto_SpaceBaseQuantities - Height: 243.84 cm; GrossFloorArea: 27.396 m2; NetFloorArea: 27.396 m2; GrossCeilingArea: 27.396 m2; NetVolume: 66.8024 m3

# IfcSpace: Appartment 96:3026736, 96
In: 02_Second Floor
LongName: Appartment
Pset_SpaceCommon - IsExternal: no; Reference: Appartment 96
Qto_SpaceBaseQuantities - Height: 243.84 cm; GrossFloorArea: 27.396 m2; NetFloorArea: 27.396 m2; GrossCeilingArea: 27.396 m2; NetVolume: 66.8024 m3

# IfcSpace: Appartment 97:3026739, 97
In: 02_Second Floor
LongName: Appartment
Pset_SpaceCommon - IsExternal: no; Reference: Appartment 97
Qto_SpaceBaseQuantities - Height: 243.84 cm; GrossFloorArea: 27.396 m2; NetFloorArea: 27.396 m2; GrossCeilingArea: 27.396 m2; NetVolume: 66.8024 m3

# IfcSpace: Appartment 98:3026742, 98
In: 02_Second Floor
LongName: Appartment
Pset_SpaceCommon - IsExternal: no; Reference: Appartment 98
Qto_SpaceBaseQuantities - Height: 243.84 cm; GrossFloorArea: 27.396 m2; NetFloorArea: 27.396 m2; GrossCeilingArea: 27.396 m2; NetVolume: 66.8024 m3

# IfcSpace: Appartment 99:3026745, 99
In: 02_Second Floor
LongName: Appartment
Pset_SpaceCommon - IsExternal: no; Reference: Appartment 99
Qto_SpaceBaseQuantities - Height: 243.84 cm; GrossFloorArea: 27.396 m2; NetFloorArea: 27.396 m2; GrossCeilingArea: 27.396 m2; NetVolume: 66.8024 m3

# IfcSpace: Appartment 9:3026475, 9
In: 00_Ground Floor
LongName: Appartment
Pset_SpaceCommon - IsExternal: no; Reference: Appartment 9
Qto_SpaceBaseQuantities - Height: 243.84 cm; GrossFloorArea: 27.396 m2; NetFloorArea: 27.396 m2; GrossCeilingArea: 27.396 m2; NetVolume: 66.8024 m3

# IfcAirTerminal: TB_57_AIR_FB_aanzuigrooster - 1 rechthoekige aansluiting - calculated flow_gen_BERSnl:Air Terminal - Exhaust (279)
Type - PredefinedType: GRILLE; Material: TB_LVC_referentievlak_00_gen_BERSnl, ARC_FME.h2_staal_00_gen_BERSnl
Type - Pset_ManufacturerTypeInformation - Manufacturer: gen
Classification: 57.10.90.1 (Uniformat)
Pset_AirTerminalTypeCommon - Reference: Air Terminal - Exhaust; sets with these values: 2
Qto_AirTerminalBaseQuantities - Perimeter: 240 cm
Name (TB_57_AIR_FB_aanzuigrooster - 1 rechthoekige aansluiting - calculated flow_gen_BERSnl:Air Terminal - Exhaust:...) | In | bSI_C_TX_SuperSecretCode
2975006 | 1 | R
2995748 | 2 | R
2995857 | 3 | R
2995916 | 4 | R
2995975 | 5 | R
2996034 | 6 | R
2996093 | 7 | R
2996160 | 8 | R
2996215 | 9 | R
2996274 | 10 | R
2996329 | 11 | R
2996384 | 12 | R
2996439 | 13 | R
2996494 | 14 | R
2996604 | 15 | R
2996659 | 16 | R
2996718 | 17 | R
2996773 | 18 | R
2996828 | 19 | R
2996883 | 20 | R
2996938 | 21 | R
2997010 | 22 | R
2997065 | 23 | R
2997124 | 24 | R
2997179 | 25 | R
2997234 | 26 | R
2997289 | 27 | R
2997344 | 28 | R
2997416 | 29 | R
2997471 | 30 | R
2997530 | 31 | R
2997585 | 32 | R
2997640 | 33 | R
2997695 | 34 | R
2997750 | 35 | R
3001449 | 36 | O
3001496 | 37 | O
3001547 | 38 | O
3001594 | 39 | O
3001641 | 40 | O
3001688 | 41 | O
3001735 | 42 | O
3001783 | 43 | O
3001829 | 44 | O
3001879 | 45 | O
3001925 | 46 | O
3001971 | 47 | O
3002017 | 48 | O
3002063 | 49 | O
3002110 | 50 | O
3002156 | 51 | O
3002206 | 52 | O
3002252 | 53 | O
3002298 | 54 | O
3002344 | 55 | O
3002390 | 56 | O
3002437 | 57 | O
3002483 | 58 | O
3002533 | 59 | O
3002579 | 60 | O
3002625 | 61 | O
3002671 | 62 | O
3002717 | 63 | O
3002764 | 64 | O
3002810 | 65 | O
3002860 | 66 | O
3002906 | 67 | O
3002952 | 68 | O
3002998 | 69 | O
3003044 | 70 | O
3003653 | 71 | P
3003699 | 72 | P
3003749 | 73 | P
3003795 | 74 | P
3003841 | 75 | P
3003887 | 76 | P
3003933 | 77 | P
3003980 | 78 | P
3004026 | 79 | P
3004076 | 80 | P
3004122 | 81 | P
3004168 | 82 | P
3004214 | 83 | P
3004260 | 84 | P
3004307 | 85 | P
3004353 | 86 | P
3004403 | 87 | P
3004449 | 88 | P
3004495 | 89 | P
3004541 | 90 | P
3004587 | 91 | P
3004634 | 92 | P
3004680 | 93 | P
3004730 | 94 | P
3004776 | 95 | P
3004822 | 96 | P
3004868 | 97 | P
3004914 | 98 | P
3004961 | 99 | P
3005007 | 100 | P
3005057 | 101 | P
3005103 | 102 | P
3005149 | 103 | P
3005195 | 104 | P
3005241 | 105 | P
3005850 | 106 | G
3005896 | 107 | G
3005946 | 108 | G
3005992 | 109 | G
3006038 | 110 | G
3006084 | 111 | G
3006130 | 112 | G
3006177 | 113 | G
3006223 | 114 | G
3006273 | 115 | G
3006319 | 116 | G
3006365 | 117 | G
3006411 | 118 | G
3006457 | 119 | G
3006504 | 120 | G
3006550 | 121 | G
3006600 | 122 | G
3006646 | 123 | G
3006692 | 124 | G
3006738 | 125 | G
3006784 | 126 | G
3006831 | 127 | G
3006877 | 128 | G
3006927 | 129 | G
3006973 | 130 | G
3007019 | 131 | G
3007065 | 132 | G
3007111 | 133 | G
3007158 | 134 | G
3007204 | 135 | G
3007254 | 136 | G
3007300 | 137 | G
3007346 | 138 | G
3007392 | 139 | G
3007438 | 140 | G
3008045 | 141 | R
3008091 | 142 | R
3008141 | 143 | R
3008187 | 144 | R
3008233 | 145 | R
3008279 | 146 | R
3008325 | 147 | R
3008372 | 148 | R
3008418 | 149 | R
3008468 | 150 | R
3008514 | 151 | R
3008560 | 152 | R
3008606 | 153 | R
3008652 | 154 | R
3008699 | 155 | R
3008745 | 156 | R
3008795 | 157 | R
3008841 | 158 | R
3008887 | 159 | R
3008933 | 160 | R
3008979 | 161 | R
3009026 | 162 | R
3009072 | 163 | R
3009122 | 164 | R
3009168 | 165 | R
3009214 | 166 | R
3009260 | 167 | R
3009306 | 168 | R
3009353 | 169 | R
3009399 | 170 | R
3009449 | 171 | R
3009495 | 172 | R
3009541 | 173 | R
3009587 | 174 | R
3009633 | 175 | R
3010240 | 176 | B
3010286 | 177 | B
3010336 | 178 | B
3010382 | 179 | B
3010428 | 180 | B
3010474 | 181 | B
3010520 | 182 | B
3010567 | 183 | B
3010613 | 184 | B
3010663 | 185 | B
3010709 | 186 | B
3010755 | 187 | B
3010801 | 188 | B
3010847 | 189 | B
3010894 | 190 | B
3010940 | 191 | B
3010990 | 192 | B
3011036 | 193 | B
3011082 | 194 | B
3011128 | 195 | B
3011174 | 196 | B
3011221 | 197 | B
3011267 | 198 | B
3011317 | 199 | B
3011363 | 200 | B
3011409 | 201 | B
3011455 | 202 | B
3011501 | 203 | B
3011548 | 204 | B
3011594 | 205 | B
3011644 | 206 | B
3011690 | 207 | B
3011736 | 208 | B
3011782 | 209 | B
3011828 | 210 | B
3012437 | 211 | Y
3012483 | 212 | Y
3012533 | 213 | Y
3012579 | 214 | Y
3012625 | 215 | Y
3012671 | 216 | Y
3012717 | 217 | Y
3012764 | 218 | Y
3012810 | 219 | Y
3012860 | 220 | Y
3012906 | 221 | Y
3012952 | 222 | Y
3012998 | 223 | Y
3013044 | 224 | Y
3013091 | 225 | Y
3013137 | 226 | Y
3013187 | 227 | Y
3013233 | 228 | Y
3013279 | 229 | Y
3013325 | 230 | Y
3013371 | 231 | Y
3013464 | 233 | Y
3013514 | 234 | Y
3013560 | 235 | Y
3013606 | 236 | Y
3013652 | 237 | Y
3013698 | 238 | Y
3013745 | 239 | Y
3013791 | 240 | Y
3013841 | 241 | Y
3013887 | 242 | Y
3013933 | 243 | Y
3013979 | 244 | Y
3014025 | 245 | Y
3014632 | 246 | P
3014678 | 247 | P
3014728 | 248 | P
3014774 | 249 | P
3014820 | 250 | P
3014866 | 251 | P
3014912 | 252 | P
3014959 | 253 | P
3015005 | 254 | P
3015055 | 255 | P
3015101 | 256 | P
3015147 | 257 | P
3015193 | 258 | P
3015239 | 259 | P
3015286 | 260 | P
3015332 | 261 | P
3015382 | 262 | P
3015428 | 263 | P
3015474 | 264 | P
3015520 | 265 | P
3015566 | 266 | P
3015613 | 267 | P
3015659 | 268 | P
3015709 | 269 | P
3015755 | 270 | P
3015801 | 271 | P
3015847 | 272 | P
3015893 | 273 | P
3015940 | 274 | P
3015986 | 275 | P
3016036 | 276 | P
3016082 | 277 | P
3016128 | 278 | P
3016174 | 279 | P
3016220 | 280 | P

# IfcAirTerminal: TB_57_AIR_FB_aanzuigrooster - 1 rechthoekige aansluiting - calculated flow_gen_BERSnl:Air Terminal - Exhaust - 2, TB_57_AIR_FB_aanzuigrooster - 1 rechthoekige aansluiting - calculated flow_gen_BERSnl:Air Terminal - Exhaust - 2:3013418
In: 232
Type - PredefinedType: GRILLE; Material: TB_LVC_referentievlak_00_gen_BERSnl, ARC_FME.h4_aluminium_00_gen_BERSnl
Type - Pset_ManufacturerTypeInformation - Manufacturer: gen
Classification: 57.10.90.1 (Uniformat)
Pset_AirTerminalTypeCommon - Reference: Air Terminal - Exhaust - 2; sets with these values: 2
cPset_IDSGame - bSI_C_TX_SuperSecretCode: #FFFF00
Qto_AirTerminalBaseQuantities - Perimeter: 240 cm

# IfcBoiler: TB_53_ME_FB_boiler gasgestookt_gen_BERSnl:160L_gen_hxdi 1230x550 mm (280)
Type - PredefinedType: WATER; Material: <Unnamed>
Type - Pset_ManufacturerTypeInformation - Manufacturer: gen
Classification: 53.30.10.2 (Uniformat)
Pset_BoilerTypeCommon - Reference: 160L_gen_hxdi 1230x550 mm; sets with these values: 2
Name (TB_53_ME_FB_boiler gasgestookt_gen_BERSnl:160L_gen_hxdi 1230x550 mm:...) | In | bSI_C_TX_SuperSecretCode | Group
2978829 | 00_Ground Floor | 1500 | Domestic Hot Water 1
2995759 | 00_Ground Floor | 1501 | Domestic Hot Water 2
2995868 | 00_Ground Floor | 1502 | Domestic Hot Water 4
2995927 | 00_Ground Floor | 1503 | Domestic Hot Water 6
2995986 | 00_Ground Floor | 1504 | Domestic Hot Water 8
2996045 | 00_Ground Floor | 1505 | Domestic Hot Water 10
2996104 | 00_Ground Floor | 1506 | Domestic Hot Water 12
2996171 | 00_Ground Floor | 1507 | Domestic Hot Water 3
2996226 | 00_Ground Floor | 1508 | Domestic Hot Water 7
2996285 | 00_Ground Floor | 1509 | Domestic Hot Water 11
2996340 | 00_Ground Floor | 1510 | Domestic Hot Water 14
2996395 | 00_Ground Floor | 1511 | Domestic Hot Water 16
2996450 | 00_Ground Floor | 1512 | Domestic Hot Water 18
2996505 | 00_Ground Floor | 1513 | Domestic Hot Water 20
2996615 | 00_Ground Floor | 1514 | Domestic Hot Water 22
2996670 | 00_Ground Floor | 1515 | Domestic Hot Water 24
2996729 | 00_Ground Floor | 1516 | Domestic Hot Water 26
2996784 | 00_Ground Floor | 1517 | Domestic Hot Water 28
2996839 | 00_Ground Floor | 1518 | Domestic Hot Water 30
2996894 | 00_Ground Floor | 1519 | Domestic Hot Water 32
2996949 | 00_Ground Floor | 1520 | Domestic Hot Water 34
2997021 | 00_Ground Floor | 1521 | Domestic Hot Water 36
2997076 | 00_Ground Floor | 1522 | Domestic Hot Water 38
2997135 | 00_Ground Floor | 1523 | Domestic Hot Water 40
2997190 | 00_Ground Floor | 1524 | Domestic Hot Water 42
2997245 | 00_Ground Floor | 1525 | Domestic Hot Water 44
2997300 | 00_Ground Floor | 1526 | Domestic Hot Water 46
2997355 | 00_Ground Floor | 1527 | Domestic Hot Water 48
2997482 | 00_Ground Floor | 1529 | Domestic Hot Water 52
2997541 | 00_Ground Floor | 1530 | Domestic Hot Water 54
2997596 | 00_Ground Floor | 1531 | Domestic Hot Water 56
2997651 | 00_Ground Floor | 1532 | Domestic Hot Water 58
2997706 | 00_Ground Floor | 1533 | Domestic Hot Water 60
2997761 | 00_Ground Floor | 1534 | Domestic Hot Water 62
3001460 | 01_First Floor | 1535 | Domestic Hot Water 5
3001507 | 01_First Floor | 1536 | Domestic Hot Water 13
3001558 | 01_First Floor | 1537 | Domestic Hot Water 17
3001605 | 01_First Floor | 1538 | Domestic Hot Water 21
3001652 | 01_First Floor | 1539 | Domestic Hot Water 25
3001699 | 01_First Floor | 1540 | Domestic Hot Water 29
3001746 | 01_First Floor | 1541 | Domestic Hot Water 33
3001793 | 01_First Floor | 1542 | Domestic Hot Water 37
3001839 | 01_First Floor | 1543 | Domestic Hot Water 41
3001889 | 01_First Floor | 1544 | Domestic Hot Water 45
3001935 | 01_First Floor | 1545 | Domestic Hot Water 49
3001981 | 01_First Floor | 1546 | Domestic Hot Water 53
3002027 | 01_First Floor | 1547 | Domestic Hot Water 57
3002073 | 01_First Floor | 1548 | Domestic Hot Water 61
3002120 | 01_First Floor | 1549 | Domestic Hot Water 64
3002166 | 01_First Floor | 1550 | Domestic Hot Water 66
3002216 | 01_First Floor | 1551 | Domestic Hot Water 68
3002262 | 01_First Floor | 1552 | Domestic Hot Water 70
3002308 | 01_First Floor | 1553 | Domestic Hot Water 72
3002354 | 01_First Floor | 1554 | Domestic Hot Water 74
3002400 | 01_First Floor | 1555 | Domestic Hot Water 76
3002447 | 01_First Floor | 1556 | Domestic Hot Water 78
3002493 | 01_First Floor | 1557 | Domestic Hot Water 80
3002543 | 01_First Floor | 1558 | Domestic Hot Water 82
3002589 | 01_First Floor | 1559 | Domestic Hot Water 84
3002635 | 01_First Floor | 1560 | Domestic Hot Water 86
3002681 | 01_First Floor | 1561 | Domestic Hot Water 88
3002727 | 01_First Floor | 1562 | Domestic Hot Water 90
3002774 | 01_First Floor | 1563 | Domestic Hot Water 92
3002820 | 01_First Floor | 1564 | Domestic Hot Water 94
3002870 | 01_First Floor | 1565 | Domestic Hot Water 96
3002916 | 01_First Floor | 1566 | Domestic Hot Water 98
3002962 | 01_First Floor | 1567 | Domestic Hot Water 100
3003008 | 01_First Floor | 1568 | Domestic Hot Water 102
3003054 | 01_First Floor | 1569 | Domestic Hot Water 104
3003663 | 02_Second Floor | 1570 | Domestic Hot Water 9
3003709 | 02_Second Floor | 1571 | Domestic Hot Water 19
3003759 | 02_Second Floor | 1572 | Domestic Hot Water 27
3003805 | 02_Second Floor | 1573 | Domestic Hot Water 35
3003851 | 02_Second Floor | 1574 | Domestic Hot Water 43
3003897 | 02_Second Floor | 1575 | Domestic Hot Water 51
3003943 | 02_Second Floor | 1576 | Domestic Hot Water 59
3003990 | 02_Second Floor | 1577 | Domestic Hot Water 65
3004036 | 02_Second Floor | 1578 | Domestic Hot Water 69
3004086 | 02_Second Floor | 1579 | Domestic Hot Water 73
3004132 | 02_Second Floor | 1580 | Domestic Hot Water 77
3004178 | 02_Second Floor | 1581 | Domestic Hot Water 81
3004224 | 02_Second Floor | 1582 | Domestic Hot Water 85
3004270 | 02_Second Floor | 1583 | Domestic Hot Water 89
3004317 | 02_Second Floor | 1584 | Domestic Hot Water 93
3004363 | 02_Second Floor | 1585 | Domestic Hot Water 97
3004413 | 02_Second Floor | 1586 | Domestic Hot Water 101
3004459 | 02_Second Floor | 1587 | Domestic Hot Water 105
3004505 | 02_Second Floor | 1588 | Domestic Hot Water 107
3004551 | 02_Second Floor | 1589 | Domestic Hot Water 109
3004597 | 02_Second Floor | 1590 | Domestic Hot Water 111
3004644 | 02_Second Floor | 1591 | Domestic Hot Water 113
3004690 | 02_Second Floor | 1592 | Domestic Hot Water 115
3004740 | 02_Second Floor | 1593 | Domestic Hot Water 117
3004786 | 02_Second Floor | 1594 | Domestic Hot Water 119
3004832 | 02_Second Floor | 1595 | Domestic Hot Water 121
3004878 | 02_Second Floor | 1596 | Domestic Hot Water 123
3004924 | 02_Second Floor | 1597 | Domestic Hot Water 125
3004971 | 02_Second Floor | 1598 | Domestic Hot Water 127
3005017 | 02_Second Floor | 1599 | Domestic Hot Water 129
3005067 | 02_Second Floor | 1600 | Domestic Hot Water 131
3005113 | 02_Second Floor | 1601 | Domestic Hot Water 133
3005159 | 02_Second Floor | 1602 | Domestic Hot Water 135
3005205 | 02_Second Floor | 1603 | Domestic Hot Water 137
3005251 | 02_Second Floor | 1604 | Domestic Hot Water 139
3005860 | 03_Third Floor | 1605 | Domestic Hot Water 15
3005906 | 03_Third Floor | 1606 | Domestic Hot Water 31
3005956 | 03_Third Floor | 1607 | Domestic Hot Water 47
3006002 | 03_Third Floor | 1608 | Domestic Hot Water 63
3006048 | 03_Third Floor | 1609 | Domestic Hot Water 71
3006094 | 03_Third Floor | 1610 | Domestic Hot Water 79
3006140 | 03_Third Floor | 1611 | Domestic Hot Water 87
3006187 | 03_Third Floor | 1612 | Domestic Hot Water 95
3006233 | 03_Third Floor | 1613 | Domestic Hot Water 103
3006283 | 03_Third Floor | 1614 | Domestic Hot Water 108
3006329 | 03_Third Floor | 1615 | Domestic Hot Water 112
3006375 | 03_Third Floor | 1616 | Domestic Hot Water 116
3006421 | 03_Third Floor | 1617 | Domestic Hot Water 120
3006467 | 03_Third Floor | 1618 | Domestic Hot Water 124
3006514 | 03_Third Floor | 1619 | Domestic Hot Water 128
3006560 | 03_Third Floor | 1620 | Domestic Hot Water 132
3006610 | 03_Third Floor | 1621 | Domestic Hot Water 136
3006656 | 03_Third Floor | 1622 | Domestic Hot Water 140
3006702 | 03_Third Floor | 1623 | Domestic Hot Water 142
3006748 | 03_Third Floor | 1624 | Domestic Hot Water 144
3006794 | 03_Third Floor | 1625 | Domestic Hot Water 146
3006841 | 03_Third Floor | 1626 | Domestic Hot Water 148
3006887 | 03_Third Floor | 1627 | Domestic Hot Water 150
3006937 | 03_Third Floor | 1628 | Domestic Hot Water 152
3006983 | 03_Third Floor | 1629 | Domestic Hot Water 154
3007029 | 03_Third Floor | 1630 | Domestic Hot Water 156
3007075 | 03_Third Floor | 1631 | Domestic Hot Water 158
3007121 | 03_Third Floor | 1632 | Domestic Hot Water 160
3007168 | 03_Third Floor | 1633 | Domestic Hot Water 162
3007214 | 03_Third Floor | 1634 | Domestic Hot Water 164
3007264 | 03_Third Floor | 1635 | Domestic Hot Water 166
3007310 | 03_Third Floor | 1636 | Domestic Hot Water 168
3007356 | 03_Third Floor | 1637 | Domestic Hot Water 170
3007402 | 03_Third Floor | 1638 | Domestic Hot Water 172
3007448 | 03_Third Floor | 1639 | Domestic Hot Water 174
3008055 | 04_Fourth Floor | 1640 | Domestic Hot Water 23
3008101 | 04_Fourth Floor | 1641 | Domestic Hot Water 55
3008151 | 04_Fourth Floor | 1642 | Domestic Hot Water 75
3008197 | 04_Fourth Floor | 1643 | Domestic Hot Water 91
3008243 | 04_Fourth Floor | 1644 | Domestic Hot Water 106
3008289 | 04_Fourth Floor | 1645 | Domestic Hot Water 114
3008335 | 04_Fourth Floor | 1646 | Domestic Hot Water 122
3008382 | 04_Fourth Floor | 1647 | Domestic Hot Water 130
3008428 | 04_Fourth Floor | 1648 | Domestic Hot Water 138
3008478 | 04_Fourth Floor | 1649 | Domestic Hot Water 143
3008524 | 04_Fourth Floor | 1650 | Domestic Hot Water 147
3008570 | 04_Fourth Floor | 1651 | Domestic Hot Water 151
3008616 | 04_Fourth Floor | 1652 | Domestic Hot Water 155
3008662 | 04_Fourth Floor | 1653 | Domestic Hot Water 159
3008709 | 04_Fourth Floor | 1654 | Domestic Hot Water 163
3008755 | 04_Fourth Floor | 1655 | Domestic Hot Water 167
3008805 | 04_Fourth Floor | 1656 | Domestic Hot Water 171
3008851 | 04_Fourth Floor | 1657 | Domestic Hot Water 175
3008897 | 04_Fourth Floor | 1658 | Domestic Hot Water 177
3008943 | 04_Fourth Floor | 1659 | Domestic Hot Water 179
3008989 | 04_Fourth Floor | 1660 | Domestic Hot Water 181
3009036 | 04_Fourth Floor | 1661 | Domestic Hot Water 183
3009082 | 04_Fourth Floor | 1662 | Domestic Hot Water 185
3009132 | 04_Fourth Floor | 1663 | Domestic Hot Water 187
3009178 | 04_Fourth Floor | 1664 | Domestic Hot Water 189
3009224 | 04_Fourth Floor | 1665 | Domestic Hot Water 191
3009270 | 04_Fourth Floor | 1666 | Domestic Hot Water 193
3009316 | 04_Fourth Floor | 1667 | Domestic Hot Water 195
3009363 | 04_Fourth Floor | 1668 | Domestic Hot Water 197
3009409 | 04_Fourth Floor | 1669 | Domestic Hot Water 199
3009459 | 04_Fourth Floor | 1670 | Domestic Hot Water 201
3009505 | 04_Fourth Floor | 1671 | Domestic Hot Water 203
3009551 | 04_Fourth Floor | 1672 | Domestic Hot Water 205
3009597 | 04_Fourth Floor | 1673 | Domestic Hot Water 207
3009643 | 04_Fourth Floor | 1674 | Domestic Hot Water 209
3010250 | 05_Fifth Floor | 1675 | Domestic Hot Water 39
3010296 | 05_Fifth Floor | 1676 | Domestic Hot Water 83
3010346 | 05_Fifth Floor | 1677 | Domestic Hot Water 110
3010392 | 05_Fifth Floor | 1678 | Domestic Hot Water 126
3010438 | 05_Fifth Floor | 1679 | Domestic Hot Water 141
3010484 | 05_Fifth Floor | 1680 | Domestic Hot Water 149
3010530 | 05_Fifth Floor | 1681 | Domestic Hot Water 157
3010577 | 05_Fifth Floor | 1682 | Domestic Hot Water 165
3010623 | 05_Fifth Floor | 1683 | Domestic Hot Water 173
3010673 | 05_Fifth Floor | 1684 | Domestic Hot Water 178
3010719 | 05_Fifth Floor | 1685 | Domestic Hot Water 182
3010765 | 05_Fifth Floor | 1686 | Domestic Hot Water 186
3010811 | 05_Fifth Floor | 1687 | Domestic Hot Water 190
3010857 | 05_Fifth Floor | 1688 | Domestic Hot Water 194
3010904 | 05_Fifth Floor | 1689 | Domestic Hot Water 198
3010950 | 05_Fifth Floor | 1690 | Domestic Hot Water 202
3011000 | 05_Fifth Floor | 1691 | Domestic Hot Water 206
3011046 | 05_Fifth Floor | 1692 | Domestic Hot Water 210
3011092 | 05_Fifth Floor | 1693 | Domestic Hot Water 212
3011138 | 05_Fifth Floor | 1694 | Domestic Hot Water 214
3011184 | 05_Fifth Floor | 1695 | Domestic Hot Water 216
3011231 | 05_Fifth Floor | 1696 | Domestic Hot Water 218
3011277 | 05_Fifth Floor | 1697 | Domestic Hot Water 220
3011327 | 05_Fifth Floor | 1698 | Domestic Hot Water 222
3011373 | 05_Fifth Floor | 1699 | Domestic Hot Water 224
3011419 | 05_Fifth Floor | 1700 | Domestic Hot Water 226
3011465 | 05_Fifth Floor | 1701 | Domestic Hot Water 228
3011511 | 05_Fifth Floor | 1702 | Domestic Hot Water 230
3011558 | 05_Fifth Floor | 1703 | Domestic Hot Water 232
3011604 | 05_Fifth Floor | 1704 | Domestic Hot Water 234
3011654 | 05_Fifth Floor | 1705 | Domestic Hot Water 236
3011700 | 05_Fifth Floor | 1706 | Domestic Hot Water 238
3011746 | 05_Fifth Floor | 1707 | Domestic Hot Water 240
3011792 | 05_Fifth Floor | 1708 | Domestic Hot Water 242
3011838 | 05_Fifth Floor | 1709 | Domestic Hot Water 244
3012447 | 06_Sixth Floor | 1710 | Domestic Hot Water 67
3012493 | 06_Sixth Floor | 1711 | Domestic Hot Water 118
3012543 | 06_Sixth Floor | 1712 | Domestic Hot Water 145
3012589 | 06_Sixth Floor | 1713 | Domestic Hot Water 161
3012635 | 06_Sixth Floor | 1714 | Domestic Hot Water 176
3012681 | 06_Sixth Floor | 1715 | Domestic Hot Water 184
3012727 | 06_Sixth Floor | 1716 | Domestic Hot Water 192
3012774 | 06_Sixth Floor | 1717 | Domestic Hot Water 200
3012820 | 06_Sixth Floor | 1718 | Domestic Hot Water 208
3012870 | 06_Sixth Floor | 1719 | Domestic Hot Water 213
3012916 | 06_Sixth Floor | 1720 | Domestic Hot Water 217
3012962 | 06_Sixth Floor | 1721 | Domestic Hot Water 221
3013008 | 06_Sixth Floor | 1722 | Domestic Hot Water 225
3013054 | 06_Sixth Floor | 1723 | Domestic Hot Water 229
3013101 | 06_Sixth Floor | 1724 | Domestic Hot Water 233
3013147 | 06_Sixth Floor | 1725 | Domestic Hot Water 237
3013197 | 06_Sixth Floor | 1726 | Domestic Hot Water 241
3013243 | 06_Sixth Floor | 1727 | Domestic Hot Water 245
3013289 | 06_Sixth Floor | 1728 | Domestic Hot Water 247
3013335 | 06_Sixth Floor | 1729 | Domestic Hot Water 249
3013381 | 06_Sixth Floor | 1730 | Domestic Hot Water 251
3013428 | 06_Sixth Floor | 1731 | Domestic Hot Water 253
3013474 | 06_Sixth Floor | 1732 | Domestic Hot Water 255
3013524 | 06_Sixth Floor | 1733 | Domestic Hot Water 257
3013570 | 06_Sixth Floor | 1734 | Domestic Hot Water 259
3013616 | 06_Sixth Floor | 1735 | Domestic Hot Water 261
3013662 | 06_Sixth Floor | 1736 | Domestic Hot Water 263
3013708 | 06_Sixth Floor | 1737 | Domestic Hot Water 265
3013755 | 06_Sixth Floor | 1738 | Domestic Hot Water 267
3013801 | 06_Sixth Floor | 1739 | Domestic Hot Water 269
3013851 | 06_Sixth Floor | 1740 | Domestic Hot Water 271
3013897 | 06_Sixth Floor | 1741 | Domestic Hot Water 273
3013943 | 06_Sixth Floor | 1742 | Domestic Hot Water 275
3013989 | 06_Sixth Floor | 1743 | Domestic Hot Water 277
3014035 | 06_Sixth Floor | 1744 | Domestic Hot Water 279
3014642 | 07_Seventh Floor | 1745 | Domestic Hot Water 99
3014688 | 07_Seventh Floor | 1746 | Domestic Hot Water 153
3014738 | 07_Seventh Floor | 1747 | Domestic Hot Water 180
3014784 | 07_Seventh Floor | 1748 | Domestic Hot Water 196
3014830 | 07_Seventh Floor | 1749 | Domestic Hot Water 211
3014876 | 07_Seventh Floor | 1750 | Domestic Hot Water 219
3014922 | 07_Seventh Floor | 1751 | Domestic Hot Water 227
3014969 | 07_Seventh Floor | 1752 | Domestic Hot Water 235
3015015 | 07_Seventh Floor | 1753 | Domestic Hot Water 243
3015065 | 07_Seventh Floor | 1754 | Domestic Hot Water 248
3015111 | 07_Seventh Floor | 1755 | Domestic Hot Water 252
3015157 | 07_Seventh Floor | 1756 | Domestic Hot Water 256
3015203 | 07_Seventh Floor | 1757 | Domestic Hot Water 260
3015249 | 07_Seventh Floor | 1758 | Domestic Hot Water 264
3015296 | 07_Seventh Floor | 1759 | Domestic Hot Water 268
3015342 | 07_Seventh Floor | 1760 | Domestic Hot Water 272
3015392 | 07_Seventh Floor | 1761 | Domestic Hot Water 276
3015438 | 07_Seventh Floor | 1762 | Domestic Hot Water 280
3015484 | 07_Seventh Floor | 1763 | Domestic Hot Water 282
3015530 | 07_Seventh Floor | 1764 | Domestic Hot Water 284
3015576 | 07_Seventh Floor | 1765 | Domestic Hot Water 286
3015623 | 07_Seventh Floor | 1766 | Domestic Hot Water 288
3015669 | 07_Seventh Floor | 1767 | Domestic Hot Water 290
3015719 | 07_Seventh Floor | 1768 | Domestic Hot Water 292
3015765 | 07_Seventh Floor | 1769 | Domestic Hot Water 294
3015811 | 07_Seventh Floor | 1770 | Domestic Hot Water 296
3015857 | 07_Seventh Floor | 1771 | Domestic Hot Water 298
3015903 | 07_Seventh Floor | 1772 | Domestic Hot Water 300
3015950 | 07_Seventh Floor | 1773 | Domestic Hot Water 302
3015996 | 07_Seventh Floor | 1774 | Domestic Hot Water 304
3016046 | 07_Seventh Floor | 1775 | Domestic Hot Water 306
3016092 | 07_Seventh Floor | 1776 | Domestic Hot Water 308
3016138 | 07_Seventh Floor | 1777 | Domestic Hot Water 310
3016184 | 07_Seventh Floor | 1778 | Domestic Hot Water 312
3016230 | 07_Seventh Floor | 1779 | Domestic Hot Water 314
3040234 | 00_Ground Floor | 1528

# IfcBuildingElementProxy: Cat:Cat (31)
Type - Material: Cat
Pset_BuildingElementProxyCommon - Reference: Cat
Pset_EnvironmentalImpactIndicators - Reference: Cat
Qto_BuildingElementProxyQuantities - NetSurfaceArea: 86.8471 m2; NetVolume: 0.005646 m3
Name | In | IsExternal
Sir Louis Casteleyn | 70 | no
Sir Luis Briones Alonso | 61 | yes
Sir Lex Ransijn | 00_Ground Floor | yes
Lady Jari Verniers | 64 | yes
Lady Evy Verwimp | 107 | no
Sir Dieter Froyen | 129 | no
Sir Jorden Schuit | 132 | yes
Catrick Stewart | 129 | no
Sir Michiel Bienens | 121 | no | PredefinedType: USERDEFINED
Sir Arjan Toet | 113 | yes
Sir Joris Van Bossche | 160 | no
Sir Stefan Boeykens | 151 | yes
King of IDS Menno Mekens | 145 | yes
Lady Aarisca Droog | 170 | yes
Sir Artur Tomczak | 165 | yes
Sir Petru Conduraru | 152 | no
Lady Simon Demaré | 179 | no | PredefinedType: USERDEFINED
Lady Hélène Dewint | 191 | no | PredefinedType: USERDEFINED
Sir Johan De Cock | 183 | yes | PredefinedType: USERDEFINED
Sir Dries Anthonissen | 235 | no | PredefinedType: USERDEFINED
Sir Gerard van der Veer | 244 | yes | PredefinedType: USERDEFINED
Purrlock Holmes | 224 | yes
Sir Mike dos Santos Freitas | 216 | no | PredefinedType: USERDEFINED
Lady Rita Nogueira | 221 | no | PredefinedType: USERDEFINED
Sir Olivier Pesch | 275 | no | PredefinedType: USERDEFINED
Dolly Pawton | 269 | no
Lady Anna Van Gucht | 255 | no | PredefinedType: USERDEFINED
Charlize Furon | 250 | no
Lady Bianca Fontana | 252 | no | PredefinedType: USERDEFINED
Meowri Antoinette | 266 | no
Marcel | 280 | no | cPset_IDSGame - bSI_C_TX_SuperSecretCode: #00FF00 / #FFFFFF

# IfcBuildingElementProxy: Moving Boxes:Moving Boxes (280)
Type - Material: <Unnamed>
Pset_BuildingElementProxyCommon - IsExternal: no; Reference: Moving Boxes
Pset_EnvironmentalImpactIndicators - Reference: Moving Boxes
Qto_BuildingElementProxyQuantities - NetSurfaceArea: 6.72 m2; NetVolume: 0.448 m3
Name (Moving Boxes:Moving Boxes:...) | In
3067638 | 7 | Group: Model Group:Array Group 1:3067993
3067996 | 14 | Group: Model Group:Array Group 1:3067997
3068052 | 21 | Group: Model Group:Array Group 1:3068053
3068055 | 28 | Group: Model Group:Array Group 1:3068056
3068058 | 35 | Group: Model Group:Array Group 1:3068059
3068081 | 6 | Group: Model Group:Array Group 1:3068082
3068083 | 13 | Group: Model Group:Array Group 1:3068084
3068089 | 20 | Group: Model Group:Array Group 1:3068090
3068091 | 27 | Group: Model Group:Array Group 1:3068092
3068093 | 34 | Group: Model Group:Array Group 1:3068094
3068150 | 5 | Group: Model Group:Array Group 1:3068151
3068152 | 12 | Group: Model Group:Array Group 1:3068153
3068158 | 19 | Group: Model Group:Array Group 1:3068159
3068160 | 26 | Group: Model Group:Array Group 1:3068161
3068162 | 33 | Group: Model Group:Array Group 1:3068163
3068166 | 4 | Group: Model Group:Array Group 1:3068167
3068168 | 11 | Group: Model Group:Array Group 1:3068169
3068174 | 18 | Group: Model Group:Array Group 1:3068175
3068176 | 25 | Group: Model Group:Array Group 1:3068177
3068178 | 32 | Group: Model Group:Array Group 1:3068179
3068182 | 3 | Group: Model Group:Array Group 1:3068183
3068184 | 10 | Group: Model Group:Array Group 1:3068185
3068190 | 17 | Group: Model Group:Array Group 1:3068191
3068192 | 24 | Group: Model Group:Array Group 1:3068193
3068194 | 31 | Group: Model Group:Array Group 1:3068195
3068198 | 2 | Group: Model Group:Array Group 1:3068199
3068200 | 9 | Group: Model Group:Array Group 1:3068201
3068206 | 16 | Group: Model Group:Array Group 1:3068207
3068208 | 23 | Group: Model Group:Array Group 1:3068209
3068210 | 30 | Group: Model Group:Array Group 1:3068211
3068214 | 1 | Group: Model Group:Array Group 1:3068215
3068216 | 8 | Group: Model Group:Array Group 1:3068217
3068222 | 15 | Group: Model Group:Array Group 1:3068223
3068224 | 22 | Group: Model Group:Array Group 1:3068225
3068226 | 29 | Group: Model Group:Array Group 1:3068227
3068285 | 42
3068286 | 49
3068287 | 56
3068288 | 63
3068289 | 70
3068290 | 41
3068291 | 48
3068292 | 55
3068293 | 62
3068294 | 69
3068295 | 40
3068296 | 47
3068297 | 54
3068298 | 61
3068299 | 68
3068300 | 39
3068301 | 46
3068302 | 53
3068303 | 60
3068304 | 67
3068305 | 38
3068306 | 45
3068307 | 52
3068308 | 59
3068309 | 66
3068310 | 37
3068311 | 44
3068312 | 51
3068313 | 58
3068314 | 65
3068315 | 36
3068316 | 43
3068317 | 50
3068318 | 57
3068319 | 64
3068327 | 77
3068328 | 84
3068329 | 91
3068330 | 98
3068331 | 105
3068332 | 76
3068333 | 83
3068334 | 90
3068335 | 97
3068336 | 104
3068337 | 75
3068338 | 82
3068339 | 89
3068340 | 96
3068341 | 103
3068342 | 74
3068343 | 81
3068344 | 88
3068345 | 95
3068346 | 102
3068347 | 73
3068348 | 80
3068349 | 87
3068350 | 94
3068351 | 101
3068352 | 72
3068353 | 79
3068354 | 86
3068355 | 93
3068356 | 100
3068357 | 71
3068358 | 78
3068359 | 85
3068360 | 92
3068361 | 99
3068369 | 112
3068370 | 119
3068371 | 126
3068372 | 133
3068373 | 140
3068374 | 111
3068375 | 118
3068376 | 125
3068377 | 132
3068378 | 139
3068379 | 110
3068380 | 117
3068381 | 124
3068382 | 131
3068383 | 138
3068384 | 109
3068385 | 116
3068386 | 123
3068387 | 130
3068388 | 137
3068389 | 108
3068390 | 115
3068391 | 122
3068392 | 129
3068393 | 136
3068394 | 107
3068395 | 114
3068396 | 121
3068397 | 128
3068398 | 135
3068399 | 106
3068400 | 113
3068401 | 120
3068402 | 127
3068403 | 134
3068411 | 147
3068412 | 154
3068413 | 161
3068414 | 168
3068415 | 175
3068416 | 146
3068417 | 153
3068418 | 160
3068419 | 167
3068420 | 174
3068421 | 145
3068422 | 152
3068423 | 159
3068424 | 166
3068425 | 173
3068426 | 144
3068427 | 151
3068428 | 158
3068429 | 165
3068430 | 172
3068431 | 143
3068432 | 150
3068433 | 157
3068434 | 164
3068435 | 171
3068436 | 142
3068437 | 149
3068438 | 156
3068439 | 163
3068440 | 170
3068441 | 141
3068442 | 148
3068443 | 155
3068444 | 162
3068445 | 169
3068453 | 182
3068454 | 189
3068455 | 196
3068456 | 203
3068457 | 210
3068458 | 181
3068459 | 188
3068460 | 195
3068461 | 202
3068462 | 209
3068463 | 180
3068464 | 187
3068465 | 194
3068466 | 201
3068467 | 208
3068468 | 179
3068469 | 186
3068470 | 193
3068471 | 200
3068472 | 207
3068473 | 178
3068474 | 185
3068475 | 192
3068476 | 199
3068477 | 206
3068478 | 177
3068479 | 184
3068480 | 191
3068481 | 198
3068482 | 205
3068483 | 176
3068484 | 183
3068485 | 190
3068486 | 197
3068487 | 204
3068495 | 217
3068496 | 224
3068497 | 231
3068498 | 238
3068499 | 245
3068500 | 216
3068501 | 223
3068502 | 230
3068503 | 237
3068504 | 244
3068505 | 215
3068506 | 222
3068507 | 229
3068508 | 236
3068509 | 243
3068510 | 214
3068511 | 221
3068512 | 228
3068513 | 235
3068514 | 242
3068515 | 213
3068516 | 220
3068517 | 227
3068518 | 234
3068519 | 241
3068520 | 212
3068521 | 219
3068522 | 226
3068523 | 233
3068524 | 240
3068525 | 211
3068526 | 218
3068527 | 225
3068528 | 232
3068529 | 239
3068537 | 252
3068538 | 259
3068539 | 266
3068540 | 273
3068541 | 280
3068542 | 251
3068543 | 258
3068544 | 265
3068545 | 272
3068546 | 279
3068547 | 250
3068548 | 257
3068549 | 264
3068550 | 271
3068551 | 278
3068552 | 249
3068553 | 256
3068554 | 263
3068555 | 270
3068556 | 277
3068557 | 248
3068558 | 255
3068559 | 262
3068560 | 269
3068561 | 276
3068562 | 247
3068563 | 254
3068564 | 261
3068565 | 268
3068566 | 275
3068567 | 246
3068568 | 253
3068569 | 260
3068570 | 267
3068571 | 274

# IfcCovering: Basic Ceiling:ARC_45_CEI_SB_PLxx_gen_BERSnl (280)
Type - PredefinedType: CEILING
Pset_CoveringCommon - IsExternal: no; Reference: ARC_45_CEI_SB_PLxx_gen_BERSnl
Pset_EnvironmentalImpactIndicators - Reference: ARC_45_CEI_SB_PLxx_gen_BERSnl
Qto_CoveringBaseQuantities - GrossArea: 27.709 m2; NetArea: 27.709 m2
Name (Basic Ceiling:ARC_45_CEI_SB_PLxx_gen_BERSnl:...) | In
2975562 | 00_Ground Floor
2995752 | 00_Ground Floor
2995861 | 00_Ground Floor
2995920 | 00_Ground Floor
2995979 | 00_Ground Floor
2996038 | 00_Ground Floor
2996097 | 00_Ground Floor
2996164 | 00_Ground Floor
2996219 | 00_Ground Floor
2996278 | 00_Ground Floor
2996333 | 00_Ground Floor
2996388 | 00_Ground Floor
2996443 | 00_Ground Floor
2996498 | 00_Ground Floor
2996608 | 00_Ground Floor
2996663 | 00_Ground Floor
2996722 | 00_Ground Floor
2996777 | 00_Ground Floor
2996832 | 00_Ground Floor
2996887 | 00_Ground Floor
2996942 | 00_Ground Floor
2997014 | 00_Ground Floor
2997069 | 00_Ground Floor
2997128 | 00_Ground Floor
2997183 | 00_Ground Floor
2997238 | 00_Ground Floor
2997293 | 00_Ground Floor
2997348 | 00_Ground Floor
2997420 | 00_Ground Floor
2997475 | 00_Ground Floor
2997534 | 00_Ground Floor
2997589 | 00_Ground Floor
2997644 | 00_Ground Floor
2997699 | 00_Ground Floor
2997754 | 00_Ground Floor
3001453 | 01_First Floor
3001500 | 01_First Floor
3001551 | 01_First Floor
3001598 | 01_First Floor
3001645 | 01_First Floor
3001692 | 01_First Floor
3001739 | 01_First Floor
3001786 | 01_First Floor
3001832 | 01_First Floor
3001882 | 01_First Floor
3001928 | 01_First Floor
3001974 | 01_First Floor
3002020 | 01_First Floor
3002066 | 01_First Floor
3002113 | 01_First Floor
3002159 | 01_First Floor
3002209 | 01_First Floor
3002255 | 01_First Floor
3002301 | 01_First Floor
3002347 | 01_First Floor
3002393 | 01_First Floor
3002440 | 01_First Floor
3002486 | 01_First Floor
3002536 | 01_First Floor
3002582 | 01_First Floor
3002628 | 01_First Floor
3002674 | 01_First Floor
3002720 | 01_First Floor
3002767 | 01_First Floor
3002813 | 01_First Floor
3002863 | 01_First Floor
3002909 | 01_First Floor
3002955 | 01_First Floor
3003001 | 01_First Floor
3003047 | 01_First Floor
3003656 | 02_Second Floor
3003702 | 02_Second Floor
3003752 | 02_Second Floor
3003798 | 02_Second Floor
3003844 | 02_Second Floor
3003890 | 02_Second Floor
3003936 | 02_Second Floor
3003983 | 02_Second Floor
3004029 | 02_Second Floor
3004079 | 02_Second Floor
3004125 | 02_Second Floor
3004171 | 02_Second Floor
3004217 | 02_Second Floor
3004263 | 02_Second Floor
3004310 | 02_Second Floor
3004356 | 02_Second Floor
3004406 | 02_Second Floor
3004452 | 02_Second Floor
3004498 | 02_Second Floor
3004544 | 02_Second Floor
3004590 | 02_Second Floor
3004637 | 02_Second Floor
3004683 | 02_Second Floor
3004733 | 02_Second Floor
3004779 | 02_Second Floor
3004825 | 02_Second Floor
3004871 | 02_Second Floor
3004917 | 02_Second Floor
3004964 | 02_Second Floor
3005010 | 02_Second Floor
3005060 | 02_Second Floor
3005106 | 02_Second Floor
3005152 | 02_Second Floor
3005198 | 02_Second Floor
3005244 | 02_Second Floor
3005853 | 03_Third Floor
3005899 | 03_Third Floor
3005949 | 03_Third Floor
3005995 | 03_Third Floor
3006041 | 03_Third Floor
3006087 | 03_Third Floor
3006133 | 03_Third Floor
3006180 | 03_Third Floor
3006226 | 03_Third Floor
3006276 | 03_Third Floor
3006322 | 03_Third Floor
3006368 | 03_Third Floor
3006414 | 03_Third Floor
3006460 | 03_Third Floor
3006507 | 03_Third Floor
3006553 | 03_Third Floor
3006603 | 03_Third Floor
3006649 | 03_Third Floor
3006695 | 03_Third Floor
3006741 | 03_Third Floor
3006787 | 03_Third Floor
3006834 | 03_Third Floor
3006880 | 03_Third Floor
3006930 | 03_Third Floor
3006976 | 03_Third Floor
3007022 | 03_Third Floor
3007068 | 03_Third Floor
3007114 | 03_Third Floor
3007161 | 03_Third Floor
3007207 | 03_Third Floor
3007257 | 03_Third Floor
3007303 | 03_Third Floor
3007349 | 03_Third Floor
3007395 | 03_Third Floor
3007441 | 03_Third Floor
3008048 | 04_Fourth Floor
3008094 | 04_Fourth Floor
3008144 | 04_Fourth Floor
3008190 | 04_Fourth Floor
3008236 | 04_Fourth Floor
3008282 | 04_Fourth Floor
3008328 | 04_Fourth Floor
3008375 | 04_Fourth Floor
3008421 | 04_Fourth Floor
3008471 | 04_Fourth Floor
3008517 | 04_Fourth Floor
3008563 | 04_Fourth Floor
3008609 | 04_Fourth Floor
3008655 | 04_Fourth Floor
3008702 | 04_Fourth Floor
3008748 | 04_Fourth Floor
3008798 | 04_Fourth Floor
3008844 | 04_Fourth Floor
3008890 | 04_Fourth Floor
3008936 | 04_Fourth Floor
3008982 | 04_Fourth Floor
3009029 | 04_Fourth Floor
3009075 | 04_Fourth Floor
3009125 | 04_Fourth Floor
3009171 | 04_Fourth Floor
3009217 | 04_Fourth Floor
3009263 | 04_Fourth Floor
3009309 | 04_Fourth Floor
3009356 | 04_Fourth Floor
3009402 | 04_Fourth Floor
3009452 | 04_Fourth Floor
3009498 | 04_Fourth Floor
3009544 | 04_Fourth Floor
3009590 | 04_Fourth Floor
3009636 | 04_Fourth Floor
3010243 | 05_Fifth Floor
3010289 | 05_Fifth Floor
3010339 | 05_Fifth Floor
3010385 | 05_Fifth Floor
3010431 | 05_Fifth Floor
3010477 | 05_Fifth Floor
3010523 | 05_Fifth Floor
3010570 | 05_Fifth Floor
3010616 | 05_Fifth Floor
3010666 | 05_Fifth Floor
3010712 | 05_Fifth Floor
3010758 | 05_Fifth Floor
3010804 | 05_Fifth Floor
3010850 | 05_Fifth Floor
3010897 | 05_Fifth Floor
3010943 | 05_Fifth Floor
3010993 | 05_Fifth Floor
3011039 | 05_Fifth Floor
3011085 | 05_Fifth Floor
3011131 | 05_Fifth Floor
3011177 | 05_Fifth Floor
3011224 | 05_Fifth Floor
3011270 | 05_Fifth Floor
3011320 | 05_Fifth Floor
3011366 | 05_Fifth Floor
3011412 | 05_Fifth Floor
3011458 | 05_Fifth Floor
3011504 | 05_Fifth Floor
3011551 | 05_Fifth Floor
3011597 | 05_Fifth Floor
3011647 | 05_Fifth Floor
3011693 | 05_Fifth Floor
3011739 | 05_Fifth Floor
3011785 | 05_Fifth Floor
3011831 | 05_Fifth Floor
3012440 | 06_Sixth Floor
3012486 | 06_Sixth Floor
3012536 | 06_Sixth Floor
3012582 | 06_Sixth Floor
3012628 | 06_Sixth Floor
3012674 | 06_Sixth Floor
3012720 | 06_Sixth Floor
3012767 | 06_Sixth Floor
3012813 | 06_Sixth Floor
3012863 | 06_Sixth Floor
3012909 | 06_Sixth Floor
3012955 | 06_Sixth Floor
3013001 | 06_Sixth Floor
3013047 | 06_Sixth Floor
3013094 | 06_Sixth Floor
3013140 | 06_Sixth Floor
3013190 | 06_Sixth Floor
3013236 | 06_Sixth Floor
3013282 | 06_Sixth Floor
3013328 | 06_Sixth Floor
3013374 | 06_Sixth Floor
3013421 | 06_Sixth Floor
3013467 | 06_Sixth Floor
3013517 | 06_Sixth Floor
3013563 | 06_Sixth Floor
3013609 | 06_Sixth Floor
3013655 | 06_Sixth Floor
3013701 | 06_Sixth Floor
3013748 | 06_Sixth Floor
3013794 | 06_Sixth Floor
3013844 | 06_Sixth Floor
3013890 | 06_Sixth Floor
3013936 | 06_Sixth Floor
3013982 | 06_Sixth Floor
3014028 | 06_Sixth Floor
3014635 | 07_Seventh Floor
3014681 | 07_Seventh Floor
3014731 | 07_Seventh Floor
3014777 | 07_Seventh Floor
3014823 | 07_Seventh Floor
3014869 | 07_Seventh Floor
3014915 | 07_Seventh Floor
3014962 | 07_Seventh Floor
3015008 | 07_Seventh Floor
3015058 | 07_Seventh Floor
3015104 | 07_Seventh Floor
3015150 | 07_Seventh Floor
3015196 | 07_Seventh Floor
3015242 | 07_Seventh Floor
3015289 | 07_Seventh Floor
3015335 | 07_Seventh Floor
3015385 | 07_Seventh Floor
3015431 | 07_Seventh Floor
3015477 | 07_Seventh Floor
3015523 | 07_Seventh Floor
3015569 | 07_Seventh Floor
3015616 | 07_Seventh Floor
3015662 | 07_Seventh Floor
3015712 | 07_Seventh Floor
3015758 | 07_Seventh Floor
3015804 | 07_Seventh Floor
3015850 | 07_Seventh Floor
3015896 | 07_Seventh Floor
3015943 | 07_Seventh Floor
3015989 | 07_Seventh Floor
3016039 | 07_Seventh Floor
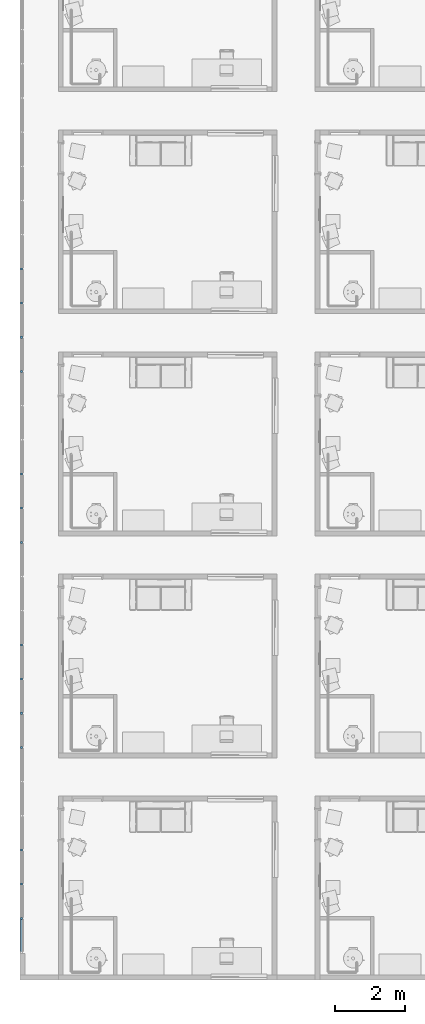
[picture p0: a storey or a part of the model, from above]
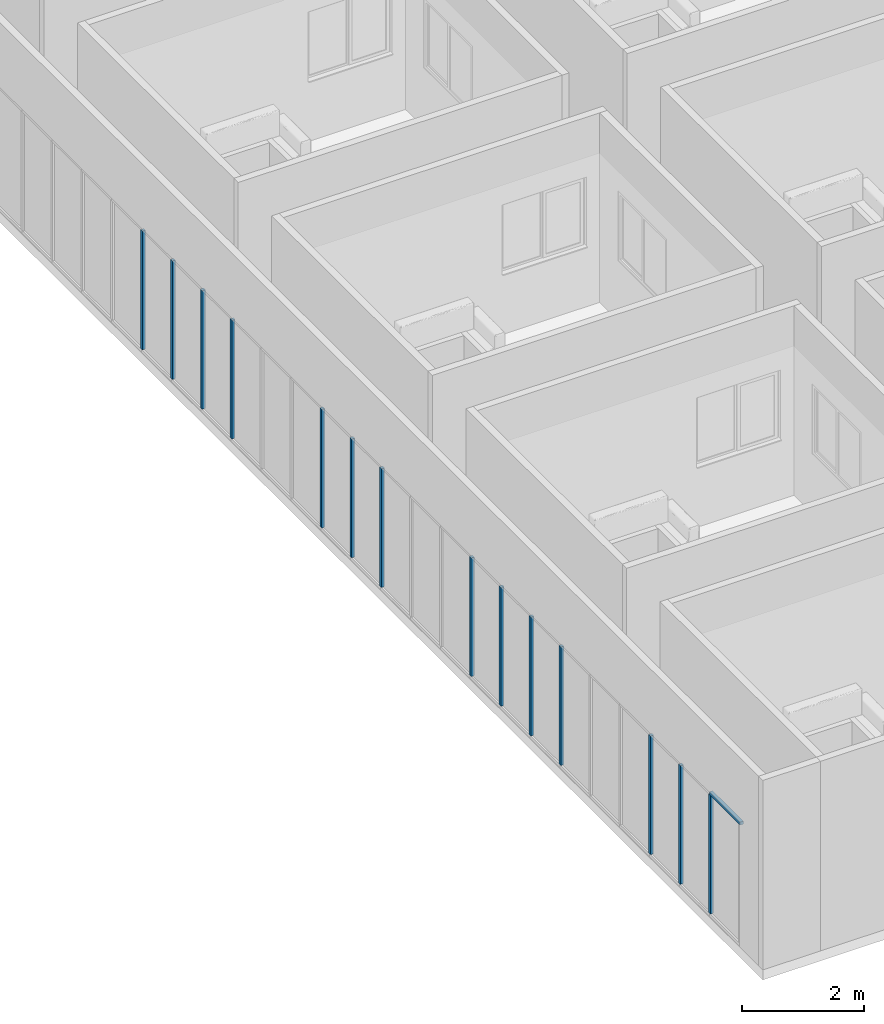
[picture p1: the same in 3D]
Properties of the parts of a building model (IFC4), part 3 of 14

# IfcCovering: Basic Ceiling:ARC_45_CEI_SB_PLxx_gen_BERSnl (280)
Name (Basic Ceiling:ARC_45_CEI_SB_PLxx_gen_BERSnl:...) | In
3016085 | 07_Seventh Floor
3016131 | 07_Seventh Floor
3016177 | 07_Seventh Floor
3016223 | 07_Seventh Floor

# IfcCurtainWall: Curtain Wall:ARC_31.3_CWA_LIB_bandraam vast 100cm - profiel 60x60_gen_BERSnl (16)
Classification: 31.2 buitenwandopeningen; gevuld met ramen (Uniformat)
Pset_CurtainWallCommon - Reference: ARC_31.3_CWA_LIB_bandraam vast 100cm - profiel 60x60_gen_BERSnl; IsExternal: yes
Pset_EnvironmentalImpactIndicators - Reference: ARC_31.3_CWA_LIB_bandraam vast 100cm - profiel 60x60_gen_BERSnl
Name (Curtain Wall:ARC_31.3_CWA_LIB_bandraam vast 100cm - profiel 60x60_gen_BERSnl:...) | In | bSI_C_TX_SuperSecretCode | Length (cm)
3000426 | 00_Ground Floor | 1 | 5098
3001061 | 00_Ground Floor | 2 | 3050
3003140 | 01_First Floor | 3 | 5098
3003396 | 01_First Floor | 4 | 3050
3005333 | 02_Second Floor | 5 | 5098
3005589 | 02_Second Floor | 6 | 3050
3007530 | 03_Third Floor | 7 | 5098
3007786 | 03_Third Floor | 8 | 3050
3009725 | 04_Fourth Floor | 9 | 5098
3009981 | 04_Fourth Floor | 10 | 3050
3011920 | 05_Fifth Floor | 11 | 5098
3012176 | 05_Fifth Floor | 12 | 3050
3014117 | 06_Sixth Floor | 13 | 5098
3014373 | 06_Sixth Floor | 14 | 3050
3016312 | 07_Seventh Floor | 15 | 5098
3016568 | 07_Seventh Floor | 16 | 3050

# IfcDistributionPort (2240)
Description: Flow
Name | FlowDirection | PredefinedType | SystemType
OutPort_2975006_5 | SOURCE | DUCT | VENTILATION
InPort_2978829_4 | SINK | PIPE | DOMESTICHOTWATER | Group: Domestic Hot Water 1
OutPort_2980486_0 | SOURCE | PIPE | DOMESTICHOTWATER | Group: Domestic Hot Water 1
OutPort_2978829_5 | SOURCE | PIPE | DOMESTICHOTWATER
InPort_2978829_6 | SINK | PIPE | DOMESTICCOLDWATER
OutPort_2978829_7 | SOURCE | DUCT | EXHAUST
InPort_2978829_8 | SINK | PIPE | USERDEFINED
InPort_2994246_1 | SINK | PIPE | DOMESTICHOTWATER | Group: Domestic Hot Water 1
OutPort_2995748_5 | SOURCE | DUCT | VENTILATION
InPort_2995759_4 | SINK | PIPE | DOMESTICHOTWATER | Group: Domestic Hot Water 2
OutPort_2995772_0 | SOURCE | PIPE | DOMESTICHOTWATER | Group: Domestic Hot Water 2
OutPort_2995759_5 | SOURCE | PIPE | DOMESTICHOTWATER
InPort_2995759_6 | SINK | PIPE | DOMESTICCOLDWATER
OutPort_2995759_7 | SOURCE | DUCT | EXHAUST
InPort_2995759_8 | SINK | PIPE | USERDEFINED
InPort_2995786_1 | SINK | PIPE | DOMESTICHOTWATER | Group: Domestic Hot Water 2
OutPort_2995857_5 | SOURCE | DUCT | VENTILATION
InPort_2995868_4 | SINK | PIPE | DOMESTICHOTWATER | Group: Domestic Hot Water 4
OutPort_2995881_0 | SOURCE | PIPE | DOMESTICHOTWATER | Group: Domestic Hot Water 4
OutPort_2995868_5 | SOURCE | PIPE | DOMESTICHOTWATER
InPort_2995868_6 | SINK | PIPE | DOMESTICCOLDWATER
OutPort_2995868_7 | SOURCE | DUCT | EXHAUST
InPort_2995868_8 | SINK | PIPE | USERDEFINED
InPort_2995895_1 | SINK | PIPE | DOMESTICHOTWATER | Group: Domestic Hot Water 4
OutPort_2995916_5 | SOURCE | DUCT | VENTILATION
InPort_2995927_4 | SINK | PIPE | DOMESTICHOTWATER | Group: Domestic Hot Water 6
OutPort_2995940_0 | SOURCE | PIPE | DOMESTICHOTWATER | Group: Domestic Hot Water 6
OutPort_2995927_5 | SOURCE | PIPE | DOMESTICHOTWATER
InPort_2995927_6 | SINK | PIPE | DOMESTICCOLDWATER
OutPort_2995927_7 | SOURCE | DUCT | EXHAUST
InPort_2995927_8 | SINK | PIPE | USERDEFINED
InPort_2995954_1 | SINK | PIPE | DOMESTICHOTWATER | Group: Domestic Hot Water 6
OutPort_2995975_5 | SOURCE | DUCT | VENTILATION
InPort_2995986_4 | SINK | PIPE | DOMESTICHOTWATER | Group: Domestic Hot Water 8
OutPort_2995999_0 | SOURCE | PIPE | DOMESTICHOTWATER | Group: Domestic Hot Water 8
OutPort_2995986_5 | SOURCE | PIPE | DOMESTICHOTWATER
InPort_2995986_6 | SINK | PIPE | DOMESTICCOLDWATER
OutPort_2995986_7 | SOURCE | DUCT | EXHAUST
InPort_2995986_8 | SINK | PIPE | USERDEFINED
InPort_2996013_1 | SINK | PIPE | DOMESTICHOTWATER | Group: Domestic Hot Water 8
OutPort_2996034_5 | SOURCE | DUCT | VENTILATION
InPort_2996045_4 | SINK | PIPE | DOMESTICHOTWATER | Group: Domestic Hot Water 10
OutPort_2996058_0 | SOURCE | PIPE | DOMESTICHOTWATER | Group: Domestic Hot Water 10
OutPort_2996045_5 | SOURCE | PIPE | DOMESTICHOTWATER
InPort_2996045_6 | SINK | PIPE | DOMESTICCOLDWATER
OutPort_2996045_7 | SOURCE | DUCT | EXHAUST
InPort_2996045_8 | SINK | PIPE | USERDEFINED
InPort_2996072_1 | SINK | PIPE | DOMESTICHOTWATER | Group: Domestic Hot Water 10
OutPort_2996093_5 | SOURCE | DUCT | VENTILATION
InPort_2996104_4 | SINK | PIPE | DOMESTICHOTWATER | Group: Domestic Hot Water 12
OutPort_2996117_0 | SOURCE | PIPE | DOMESTICHOTWATER | Group: Domestic Hot Water 12
OutPort_2996104_5 | SOURCE | PIPE | DOMESTICHOTWATER
InPort_2996104_6 | SINK | PIPE | DOMESTICCOLDWATER
OutPort_2996104_7 | SOURCE | DUCT | EXHAUST
InPort_2996104_8 | SINK | PIPE | USERDEFINED
InPort_2996131_1 | SINK | PIPE | DOMESTICHOTWATER | Group: Domestic Hot Water 12
OutPort_2996160_5 | SOURCE | DUCT | VENTILATION
InPort_2996171_4 | SINK | PIPE | DOMESTICHOTWATER | Group: Domestic Hot Water 3
OutPort_2996184_0 | SOURCE | PIPE | DOMESTICHOTWATER | Group: Domestic Hot Water 3
OutPort_2996171_5 | SOURCE | PIPE | DOMESTICHOTWATER
InPort_2996171_6 | SINK | PIPE | DOMESTICCOLDWATER
OutPort_2996171_7 | SOURCE | DUCT | EXHAUST
InPort_2996171_8 | SINK | PIPE | USERDEFINED
InPort_2996198_1 | SINK | PIPE | DOMESTICHOTWATER | Group: Domestic Hot Water 3
OutPort_2996215_5 | SOURCE | DUCT | VENTILATION
InPort_2996226_4 | SINK | PIPE | DOMESTICHOTWATER | Group: Domestic Hot Water 7
OutPort_2996239_0 | SOURCE | PIPE | DOMESTICHOTWATER | Group: Domestic Hot Water 7
OutPort_2996226_5 | SOURCE | PIPE | DOMESTICHOTWATER
InPort_2996226_6 | SINK | PIPE | DOMESTICCOLDWATER
OutPort_2996226_7 | SOURCE | DUCT | EXHAUST
InPort_2996226_8 | SINK | PIPE | USERDEFINED
InPort_2996253_1 | SINK | PIPE | DOMESTICHOTWATER | Group: Domestic Hot Water 7
OutPort_2996274_5 | SOURCE | DUCT | VENTILATION
InPort_2996285_4 | SINK | PIPE | DOMESTICHOTWATER | Group: Domestic Hot Water 11
OutPort_2996298_0 | SOURCE | PIPE | DOMESTICHOTWATER | Group: Domestic Hot Water 11
OutPort_2996285_5 | SOURCE | PIPE | DOMESTICHOTWATER
InPort_2996285_6 | SINK | PIPE | DOMESTICCOLDWATER
OutPort_2996285_7 | SOURCE | DUCT | EXHAUST
InPort_2996285_8 | SINK | PIPE | USERDEFINED
InPort_2996312_1 | SINK | PIPE | DOMESTICHOTWATER | Group: Domestic Hot Water 11
OutPort_2996329_5 | SOURCE | DUCT | VENTILATION
InPort_2996340_4 | SINK | PIPE | DOMESTICHOTWATER | Group: Domestic Hot Water 14
OutPort_2996353_0 | SOURCE | PIPE | DOMESTICHOTWATER | Group: Domestic Hot Water 14
OutPort_2996340_5 | SOURCE | PIPE | DOMESTICHOTWATER
InPort_2996340_6 | SINK | PIPE | DOMESTICCOLDWATER
OutPort_2996340_7 | SOURCE | DUCT | EXHAUST
InPort_2996340_8 | SINK | PIPE | USERDEFINED
InPort_2996367_1 | SINK | PIPE | DOMESTICHOTWATER | Group: Domestic Hot Water 14
OutPort_2996384_5 | SOURCE | DUCT | VENTILATION
InPort_2996395_4 | SINK | PIPE | DOMESTICHOTWATER | Group: Domestic Hot Water 16
OutPort_2996408_0 | SOURCE | PIPE | DOMESTICHOTWATER | Group: Domestic Hot Water 16
OutPort_2996395_5 | SOURCE | PIPE | DOMESTICHOTWATER
InPort_2996395_6 | SINK | PIPE | DOMESTICCOLDWATER
OutPort_2996395_7 | SOURCE | DUCT | EXHAUST
InPort_2996395_8 | SINK | PIPE | USERDEFINED
InPort_2996422_1 | SINK | PIPE | DOMESTICHOTWATER | Group: Domestic Hot Water 16
OutPort_2996439_5 | SOURCE | DUCT | VENTILATION
InPort_2996450_4 | SINK | PIPE | DOMESTICHOTWATER | Group: Domestic Hot Water 18
OutPort_2996463_0 | SOURCE | PIPE | DOMESTICHOTWATER | Group: Domestic Hot Water 18
OutPort_2996450_5 | SOURCE | PIPE | DOMESTICHOTWATER
InPort_2996450_6 | SINK | PIPE | DOMESTICCOLDWATER
OutPort_2996450_7 | SOURCE | DUCT | EXHAUST
InPort_2996450_8 | SINK | PIPE | USERDEFINED
InPort_2996477_1 | SINK | PIPE | DOMESTICHOTWATER | Group: Domestic Hot Water 18
OutPort_2996494_5 | SOURCE | DUCT | VENTILATION
InPort_2996505_4 | SINK | PIPE | DOMESTICHOTWATER | Group: Domestic Hot Water 20
OutPort_2996518_0 | SOURCE | PIPE | DOMESTICHOTWATER | Group: Domestic Hot Water 20
OutPort_2996505_5 | SOURCE | PIPE | DOMESTICHOTWATER
InPort_2996505_6 | SINK | PIPE | DOMESTICCOLDWATER
OutPort_2996505_7 | SOURCE | DUCT | EXHAUST
InPort_2996505_8 | SINK | PIPE | USERDEFINED
InPort_2996532_1 | SINK | PIPE | DOMESTICHOTWATER | Group: Domestic Hot Water 20
OutPort_2996604_5 | SOURCE | DUCT | VENTILATION
InPort_2996615_4 | SINK | PIPE | DOMESTICHOTWATER | Group: Domestic Hot Water 22
OutPort_2996628_0 | SOURCE | PIPE | DOMESTICHOTWATER | Group: Domestic Hot Water 22
OutPort_2996615_5 | SOURCE | PIPE | DOMESTICHOTWATER
InPort_2996615_6 | SINK | PIPE | DOMESTICCOLDWATER
OutPort_2996615_7 | SOURCE | DUCT | EXHAUST
InPort_2996615_8 | SINK | PIPE | USERDEFINED
InPort_2996642_1 | SINK | PIPE | DOMESTICHOTWATER | Group: Domestic Hot Water 22
OutPort_2996659_5 | SOURCE | DUCT | VENTILATION
InPort_2996670_4 | SINK | PIPE | DOMESTICHOTWATER | Group: Domestic Hot Water 24
OutPort_2996683_0 | SOURCE | PIPE | DOMESTICHOTWATER | Group: Domestic Hot Water 24
OutPort_2996670_5 | SOURCE | PIPE | DOMESTICHOTWATER
InPort_2996670_6 | SINK | PIPE | DOMESTICCOLDWATER
OutPort_2996670_7 | SOURCE | DUCT | EXHAUST
InPort_2996670_8 | SINK | PIPE | USERDEFINED
InPort_2996697_1 | SINK | PIPE | DOMESTICHOTWATER | Group: Domestic Hot Water 24
OutPort_2996718_5 | SOURCE | DUCT | VENTILATION
InPort_2996729_4 | SINK | PIPE | DOMESTICHOTWATER | Group: Domestic Hot Water 26
OutPort_2996742_0 | SOURCE | PIPE | DOMESTICHOTWATER | Group: Domestic Hot Water 26
OutPort_2996729_5 | SOURCE | PIPE | DOMESTICHOTWATER
InPort_2996729_6 | SINK | PIPE | DOMESTICCOLDWATER
OutPort_2996729_7 | SOURCE | DUCT | EXHAUST
InPort_2996729_8 | SINK | PIPE | USERDEFINED
InPort_2996756_1 | SINK | PIPE | DOMESTICHOTWATER | Group: Domestic Hot Water 26
OutPort_2996773_5 | SOURCE | DUCT | VENTILATION
InPort_2996784_4 | SINK | PIPE | DOMESTICHOTWATER | Group: Domestic Hot Water 28
OutPort_2996797_0 | SOURCE | PIPE | DOMESTICHOTWATER | Group: Domestic Hot Water 28
OutPort_2996784_5 | SOURCE | PIPE | DOMESTICHOTWATER
InPort_2996784_6 | SINK | PIPE | DOMESTICCOLDWATER
OutPort_2996784_7 | SOURCE | DUCT | EXHAUST
InPort_2996784_8 | SINK | PIPE | USERDEFINED
InPort_2996811_1 | SINK | PIPE | DOMESTICHOTWATER | Group: Domestic Hot Water 28
OutPort_2996828_5 | SOURCE | DUCT | VENTILATION
InPort_2996839_4 | SINK | PIPE | DOMESTICHOTWATER | Group: Domestic Hot Water 30
OutPort_2996852_0 | SOURCE | PIPE | DOMESTICHOTWATER | Group: Domestic Hot Water 30
OutPort_2996839_5 | SOURCE | PIPE | DOMESTICHOTWATER
InPort_2996839_6 | SINK | PIPE | DOMESTICCOLDWATER
OutPort_2996839_7 | SOURCE | DUCT | EXHAUST
InPort_2996839_8 | SINK | PIPE | USERDEFINED
InPort_2996866_1 | SINK | PIPE | DOMESTICHOTWATER | Group: Domestic Hot Water 30
OutPort_2996883_5 | SOURCE | DUCT | VENTILATION
InPort_2996894_4 | SINK | PIPE | DOMESTICHOTWATER | Group: Domestic Hot Water 32
OutPort_2996907_0 | SOURCE | PIPE | DOMESTICHOTWATER | Group: Domestic Hot Water 32
OutPort_2996894_5 | SOURCE | PIPE | DOMESTICHOTWATER
InPort_2996894_6 | SINK | PIPE | DOMESTICCOLDWATER
OutPort_2996894_7 | SOURCE | DUCT | EXHAUST
InPort_2996894_8 | SINK | PIPE | USERDEFINED
InPort_2996921_1 | SINK | PIPE | DOMESTICHOTWATER | Group: Domestic Hot Water 32
OutPort_2996938_5 | SOURCE | DUCT | VENTILATION
InPort_2996949_4 | SINK | PIPE | DOMESTICHOTWATER | Group: Domestic Hot Water 34
OutPort_2996962_0 | SOURCE | PIPE | DOMESTICHOTWATER | Group: Domestic Hot Water 34
OutPort_2996949_5 | SOURCE | PIPE | DOMESTICHOTWATER
InPort_2996949_6 | SINK | PIPE | DOMESTICCOLDWATER
OutPort_2996949_7 | SOURCE | DUCT | EXHAUST
InPort_2996949_8 | SINK | PIPE | USERDEFINED
InPort_2996976_1 | SINK | PIPE | DOMESTICHOTWATER | Group: Domestic Hot Water 34
OutPort_2997010_5 | SOURCE | DUCT | VENTILATION
InPort_2997021_4 | SINK | PIPE | DOMESTICHOTWATER | Group: Domestic Hot Water 36
OutPort_2997034_0 | SOURCE | PIPE | DOMESTICHOTWATER | Group: Domestic Hot Water 36
OutPort_2997021_5 | SOURCE | PIPE | DOMESTICHOTWATER
InPort_2997021_6 | SINK | PIPE | DOMESTICCOLDWATER
OutPort_2997021_7 | SOURCE | DUCT | EXHAUST
InPort_2997021_8 | SINK | PIPE | USERDEFINED
InPort_2997048_1 | SINK | PIPE | DOMESTICHOTWATER | Group: Domestic Hot Water 36
OutPort_2997065_5 | SOURCE | DUCT | VENTILATION
InPort_2997076_4 | SINK | PIPE | DOMESTICHOTWATER | Group: Domestic Hot Water 38
OutPort_2997089_0 | SOURCE | PIPE | DOMESTICHOTWATER | Group: Domestic Hot Water 38
OutPort_2997076_5 | SOURCE | PIPE | DOMESTICHOTWATER
InPort_2997076_6 | SINK | PIPE | DOMESTICCOLDWATER
OutPort_2997076_7 | SOURCE | DUCT | EXHAUST
InPort_2997076_8 | SINK | PIPE | USERDEFINED
InPort_2997103_1 | SINK | PIPE | DOMESTICHOTWATER | Group: Domestic Hot Water 38
OutPort_2997124_5 | SOURCE | DUCT | VENTILATION
InPort_2997135_4 | SINK | PIPE | DOMESTICHOTWATER | Group: Domestic Hot Water 40
OutPort_2997148_0 | SOURCE | PIPE | DOMESTICHOTWATER | Group: Domestic Hot Water 40
OutPort_2997135_5 | SOURCE | PIPE | DOMESTICHOTWATER
InPort_2997135_6 | SINK | PIPE | DOMESTICCOLDWATER
OutPort_2997135_7 | SOURCE | DUCT | EXHAUST
InPort_2997135_8 | SINK | PIPE | USERDEFINED
InPort_2997162_1 | SINK | PIPE | DOMESTICHOTWATER | Group: Domestic Hot Water 40
OutPort_2997179_5 | SOURCE | DUCT | VENTILATION
InPort_2997190_4 | SINK | PIPE | DOMESTICHOTWATER | Group: Domestic Hot Water 42
OutPort_2997203_0 | SOURCE | PIPE | DOMESTICHOTWATER | Group: Domestic Hot Water 42
OutPort_2997190_5 | SOURCE | PIPE | DOMESTICHOTWATER
InPort_2997190_6 | SINK | PIPE | DOMESTICCOLDWATER
OutPort_2997190_7 | SOURCE | DUCT | EXHAUST
InPort_2997190_8 | SINK | PIPE | USERDEFINED
InPort_2997217_1 | SINK | PIPE | DOMESTICHOTWATER | Group: Domestic Hot Water 42
OutPort_2997234_5 | SOURCE | DUCT | VENTILATION
InPort_2997245_4 | SINK | PIPE | DOMESTICHOTWATER | Group: Domestic Hot Water 44
OutPort_2997258_0 | SOURCE | PIPE | DOMESTICHOTWATER | Group: Domestic Hot Water 44
OutPort_2997245_5 | SOURCE | PIPE | DOMESTICHOTWATER
InPort_2997245_6 | SINK | PIPE | DOMESTICCOLDWATER
OutPort_2997245_7 | SOURCE | DUCT | EXHAUST
InPort_2997245_8 | SINK | PIPE | USERDEFINED
InPort_2997272_1 | SINK | PIPE | DOMESTICHOTWATER | Group: Domestic Hot Water 44
OutPort_2997289_5 | SOURCE | DUCT | VENTILATION
InPort_2997300_4 | SINK | PIPE | DOMESTICHOTWATER | Group: Domestic Hot Water 46
OutPort_2997313_0 | SOURCE | PIPE | DOMESTICHOTWATER | Group: Domestic Hot Water 46
OutPort_2997300_5 | SOURCE | PIPE | DOMESTICHOTWATER
InPort_2997300_6 | SINK | PIPE | DOMESTICCOLDWATER
OutPort_2997300_7 | SOURCE | DUCT | EXHAUST
InPort_2997300_8 | SINK | PIPE | USERDEFINED
InPort_2997327_1 | SINK | PIPE | DOMESTICHOTWATER | Group: Domestic Hot Water 46
OutPort_2997344_5 | SOURCE | DUCT | VENTILATION
InPort_2997355_4 | SINK | PIPE | DOMESTICHOTWATER | Group: Domestic Hot Water 48
OutPort_2997368_0 | SOURCE | PIPE | DOMESTICHOTWATER | Group: Domestic Hot Water 48
OutPort_2997355_5 | SOURCE | PIPE | DOMESTICHOTWATER
InPort_2997355_6 | SINK | PIPE | DOMESTICCOLDWATER
OutPort_2997355_7 | SOURCE | DUCT | EXHAUST
InPort_2997355_8 | SINK | PIPE | USERDEFINED
InPort_2997382_1 | SINK | PIPE | DOMESTICHOTWATER | Group: Domestic Hot Water 48
OutPort_2997416_5 | SOURCE | DUCT | VENTILATION
Port_2997440_0 | SOURCEANDSINK | PIPE | DOMESTICHOTWATER | Group: Domestic Hot Water 50
Port_2997454_1 | SOURCEANDSINK | PIPE | DOMESTICHOTWATER | Group: Domestic Hot Water 50
OutPort_2997471_5 | SOURCE | DUCT | VENTILATION
InPort_2997482_4 | SINK | PIPE | DOMESTICHOTWATER | Group: Domestic Hot Water 52
OutPort_2997495_0 | SOURCE | PIPE | DOMESTICHOTWATER | Group: Domestic Hot Water 52
OutPort_2997482_5 | SOURCE | PIPE | DOMESTICHOTWATER
InPort_2997482_6 | SINK | PIPE | DOMESTICCOLDWATER
OutPort_2997482_7 | SOURCE | DUCT | EXHAUST
InPort_2997482_8 | SINK | PIPE | USERDEFINED
InPort_2997509_1 | SINK | PIPE | DOMESTICHOTWATER | Group: Domestic Hot Water 52
OutPort_2997530_5 | SOURCE | DUCT | VENTILATION
InPort_2997541_4 | SINK | PIPE | DOMESTICHOTWATER | Group: Domestic Hot Water 54
OutPort_2997554_0 | SOURCE | PIPE | DOMESTICHOTWATER | Group: Domestic Hot Water 54
OutPort_2997541_5 | SOURCE | PIPE | DOMESTICHOTWATER
InPort_2997541_6 | SINK | PIPE | DOMESTICCOLDWATER
OutPort_2997541_7 | SOURCE | DUCT | EXHAUST
InPort_2997541_8 | SINK | PIPE | USERDEFINED
InPort_2997568_1 | SINK | PIPE | DOMESTICHOTWATER | Group: Domestic Hot Water 54
OutPort_2997585_5 | SOURCE | DUCT | VENTILATION
InPort_2997596_4 | SINK | PIPE | DOMESTICHOTWATER | Group: Domestic Hot Water 56
OutPort_2997609_0 | SOURCE | PIPE | DOMESTICHOTWATER | Group: Domestic Hot Water 56
OutPort_2997596_5 | SOURCE | PIPE | DOMESTICHOTWATER
InPort_2997596_6 | SINK | PIPE | DOMESTICCOLDWATER
OutPort_2997596_7 | SOURCE | DUCT | EXHAUST
InPort_2997596_8 | SINK | PIPE | USERDEFINED
InPort_2997623_1 | SINK | PIPE | DOMESTICHOTWATER | Group: Domestic Hot Water 56
OutPort_2997640_5 | SOURCE | DUCT | VENTILATION
InPort_2997651_4 | SINK | PIPE | DOMESTICHOTWATER | Group: Domestic Hot Water 58
OutPort_2997664_0 | SOURCE | PIPE | DOMESTICHOTWATER | Group: Domestic Hot Water 58
OutPort_2997651_5 | SOURCE | PIPE | DOMESTICHOTWATER
InPort_2997651_6 | SINK | PIPE | DOMESTICCOLDWATER
OutPort_2997651_7 | SOURCE | DUCT | EXHAUST
InPort_2997651_8 | SINK | PIPE | USERDEFINED
InPort_2997678_1 | SINK | PIPE | DOMESTICHOTWATER | Group: Domestic Hot Water 58
OutPort_2997695_5 | SOURCE | DUCT | VENTILATION
InPort_2997706_4 | SINK | PIPE | DOMESTICHOTWATER | Group: Domestic Hot Water 60
OutPort_2997719_0 | SOURCE | PIPE | DOMESTICHOTWATER | Group: Domestic Hot Water 60
OutPort_2997706_5 | SOURCE | PIPE | DOMESTICHOTWATER
InPort_2997706_6 | SINK | PIPE | DOMESTICCOLDWATER
OutPort_2997706_7 | SOURCE | DUCT | EXHAUST
InPort_2997706_8 | SINK | PIPE | USERDEFINED
InPort_2997733_1 | SINK | PIPE | DOMESTICHOTWATER | Group: Domestic Hot Water 60
OutPort_2997750_5 | SOURCE | DUCT | VENTILATION
InPort_2997761_4 | SINK | PIPE | DOMESTICHOTWATER | Group: Domestic Hot Water 62
OutPort_2997774_0 | SOURCE | PIPE | DOMESTICHOTWATER | Group: Domestic Hot Water 62
OutPort_2997761_5 | SOURCE | PIPE | DOMESTICHOTWATER
InPort_2997761_6 | SINK | PIPE | DOMESTICCOLDWATER
OutPort_2997761_7 | SOURCE | DUCT | EXHAUST
InPort_2997761_8 | SINK | PIPE | USERDEFINED
InPort_2997788_1 | SINK | PIPE | DOMESTICHOTWATER | Group: Domestic Hot Water 62
OutPort_3001449_5 | SOURCE | DUCT | VENTILATION
InPort_3001460_4 | SINK | PIPE | DOMESTICHOTWATER | Group: Domestic Hot Water 5
OutPort_3001465_0 | SOURCE | PIPE | DOMESTICHOTWATER | Group: Domestic Hot Water 5
OutPort_3001460_5 | SOURCE | PIPE | DOMESTICHOTWATER
InPort_3001460_6 | SINK | PIPE | DOMESTICCOLDWATER
OutPort_3001460_7 | SOURCE | DUCT | EXHAUST
InPort_3001460_8 | SINK | PIPE | USERDEFINED
InPort_3001479_1 | SINK | PIPE | DOMESTICHOTWATER | Group: Domestic Hot Water 5
OutPort_3001496_5 | SOURCE | DUCT | VENTILATION
InPort_3001507_4 | SINK | PIPE | DOMESTICHOTWATER | Group: Domestic Hot Water 13
OutPort_3001512_0 | SOURCE | PIPE | DOMESTICHOTWATER | Group: Domestic Hot Water 13
OutPort_3001507_5 | SOURCE | PIPE | DOMESTICHOTWATER
InPort_3001507_6 | SINK | PIPE | DOMESTICCOLDWATER
OutPort_3001507_7 | SOURCE | DUCT | EXHAUST
InPort_3001507_8 | SINK | PIPE | USERDEFINED
InPort_3001526_1 | SINK | PIPE | DOMESTICHOTWATER | Group: Domestic Hot Water 13
OutPort_3001547_5 | SOURCE | DUCT | VENTILATION
InPort_3001558_4 | SINK | PIPE | DOMESTICHOTWATER | Group: Domestic Hot Water 17
OutPort_3001563_0 | SOURCE | PIPE | DOMESTICHOTWATER | Group: Domestic Hot Water 17
OutPort_3001558_5 | SOURCE | PIPE | DOMESTICHOTWATER
InPort_3001558_6 | SINK | PIPE | DOMESTICCOLDWATER
OutPort_3001558_7 | SOURCE | DUCT | EXHAUST
InPort_3001558_8 | SINK | PIPE | USERDEFINED
InPort_3001577_1 | SINK | PIPE | DOMESTICHOTWATER | Group: Domestic Hot Water 17
OutPort_3001594_5 | SOURCE | DUCT | VENTILATION
InPort_3001605_4 | SINK | PIPE | DOMESTICHOTWATER | Group: Domestic Hot Water 21
OutPort_3001610_0 | SOURCE | PIPE | DOMESTICHOTWATER | Group: Domestic Hot Water 21
OutPort_3001605_5 | SOURCE | PIPE | DOMESTICHOTWATER
InPort_3001605_6 | SINK | PIPE | DOMESTICCOLDWATER
OutPort_3001605_7 | SOURCE | DUCT | EXHAUST
InPort_3001605_8 | SINK | PIPE | USERDEFINED
InPort_3001624_1 | SINK | PIPE | DOMESTICHOTWATER | Group: Domestic Hot Water 21
OutPort_3001641_5 | SOURCE | DUCT | VENTILATION
InPort_3001652_4 | SINK | PIPE | DOMESTICHOTWATER | Group: Domestic Hot Water 25
OutPort_3001657_0 | SOURCE | PIPE | DOMESTICHOTWATER | Group: Domestic Hot Water 25
OutPort_3001652_5 | SOURCE | PIPE | DOMESTICHOTWATER
InPort_3001652_6 | SINK | PIPE | DOMESTICCOLDWATER
OutPort_3001652_7 | SOURCE | DUCT | EXHAUST
InPort_3001652_8 | SINK | PIPE | USERDEFINED
InPort_3001671_1 | SINK | PIPE | DOMESTICHOTWATER | Group: Domestic Hot Water 25
OutPort_3001688_5 | SOURCE | DUCT | VENTILATION
InPort_3001699_4 | SINK | PIPE | DOMESTICHOTWATER | Group: Domestic Hot Water 29
OutPort_3001704_0 | SOURCE | PIPE | DOMESTICHOTWATER | Group: Domestic Hot Water 29
OutPort_3001699_5 | SOURCE | PIPE | DOMESTICHOTWATER
InPort_3001699_6 | SINK | PIPE | DOMESTICCOLDWATER
OutPort_3001699_7 | SOURCE | DUCT | EXHAUST
InPort_3001699_8 | SINK | PIPE | USERDEFINED
InPort_3001718_1 | SINK | PIPE | DOMESTICHOTWATER | Group: Domestic Hot Water 29
OutPort_3001735_5 | SOURCE | DUCT | VENTILATION
InPort_3001746_4 | SINK | PIPE | DOMESTICHOTWATER | Group: Domestic Hot Water 33
OutPort_3001751_0 | SOURCE | PIPE | DOMESTICHOTWATER | Group: Domestic Hot Water 33
OutPort_3001746_5 | SOURCE | PIPE | DOMESTICHOTWATER
InPort_3001746_6 | SINK | PIPE | DOMESTICCOLDWATER
OutPort_3001746_7 | SOURCE | DUCT | EXHAUST
InPort_3001746_8 | SINK | PIPE | USERDEFINED
InPort_3001765_1 | SINK | PIPE | DOMESTICHOTWATER | Group: Domestic Hot Water 33
OutPort_3001783_5 | SOURCE | DUCT | VENTILATION
InPort_3001793_4 | SINK | PIPE | DOMESTICHOTWATER | Group: Domestic Hot Water 37
OutPort_3001798_0 | SOURCE | PIPE | DOMESTICHOTWATER | Group: Domestic Hot Water 37
OutPort_3001793_5 | SOURCE | PIPE | DOMESTICHOTWATER
InPort_3001793_6 | SINK | PIPE | DOMESTICCOLDWATER
OutPort_3001793_7 | SOURCE | DUCT | EXHAUST
InPort_3001793_8 | SINK | PIPE | USERDEFINED
InPort_3001812_1 | SINK | PIPE | DOMESTICHOTWATER | Group: Domestic Hot Water 37
OutPort_3001829_5 | SOURCE | DUCT | VENTILATION
InPort_3001839_4 | SINK | PIPE | DOMESTICHOTWATER | Group: Domestic Hot Water 41
OutPort_3001844_0 | SOURCE | PIPE | DOMESTICHOTWATER | Group: Domestic Hot Water 41
OutPort_3001839_5 | SOURCE | PIPE | DOMESTICHOTWATER
InPort_3001839_6 | SINK | PIPE | DOMESTICCOLDWATER
OutPort_3001839_7 | SOURCE | DUCT | EXHAUST
InPort_3001839_8 | SINK | PIPE | USERDEFINED
InPort_3001858_1 | SINK | PIPE | DOMESTICHOTWATER | Group: Domestic Hot Water 41
OutPort_3001879_5 | SOURCE | DUCT | VENTILATION
InPort_3001889_4 | SINK | PIPE | DOMESTICHOTWATER | Group: Domestic Hot Water 45
OutPort_3001894_0 | SOURCE | PIPE | DOMESTICHOTWATER | Group: Domestic Hot Water 45
OutPort_3001889_5 | SOURCE | PIPE | DOMESTICHOTWATER
InPort_3001889_6 | SINK | PIPE | DOMESTICCOLDWATER
OutPort_3001889_7 | SOURCE | DUCT | EXHAUST
InPort_3001889_8 | SINK | PIPE | USERDEFINED
InPort_3001908_1 | SINK | PIPE | DOMESTICHOTWATER | Group: Domestic Hot Water 45
OutPort_3001925_5 | SOURCE | DUCT | VENTILATION
InPort_3001935_4 | SINK | PIPE | DOMESTICHOTWATER | Group: Domestic Hot Water 49
OutPort_3001940_0 | SOURCE | PIPE | DOMESTICHOTWATER | Group: Domestic Hot Water 49
OutPort_3001935_5 | SOURCE | PIPE | DOMESTICHOTWATER
InPort_3001935_6 | SINK | PIPE | DOMESTICCOLDWATER
OutPort_3001935_7 | SOURCE | DUCT | EXHAUST
InPort_3001935_8 | SINK | PIPE | USERDEFINED
InPort_3001954_1 | SINK | PIPE | DOMESTICHOTWATER | Group: Domestic Hot Water 49
OutPort_3001971_5 | SOURCE | DUCT | VENTILATION
InPort_3001981_4 | SINK | PIPE | DOMESTICHOTWATER | Group: Domestic Hot Water 53
OutPort_3001986_0 | SOURCE | PIPE | DOMESTICHOTWATER | Group: Domestic Hot Water 53
OutPort_3001981_5 | SOURCE | PIPE | DOMESTICHOTWATER
InPort_3001981_6 | SINK | PIPE | DOMESTICCOLDWATER
OutPort_3001981_7 | SOURCE | DUCT | EXHAUST
InPort_3001981_8 | SINK | PIPE | USERDEFINED
InPort_3002000_1 | SINK | PIPE | DOMESTICHOTWATER | Group: Domestic Hot Water 53
OutPort_3002017_5 | SOURCE | DUCT | VENTILATION
InPort_3002027_4 | SINK | PIPE | DOMESTICHOTWATER | Group: Domestic Hot Water 57
OutPort_3002032_0 | SOURCE | PIPE | DOMESTICHOTWATER | Group: Domestic Hot Water 57
OutPort_3002027_5 | SOURCE | PIPE | DOMESTICHOTWATER
InPort_3002027_6 | SINK | PIPE | DOMESTICCOLDWATER
OutPort_3002027_7 | SOURCE | DUCT | EXHAUST
InPort_3002027_8 | SINK | PIPE | USERDEFINED
InPort_3002046_1 | SINK | PIPE | DOMESTICHOTWATER | Group: Domestic Hot Water 57
OutPort_3002063_5 | SOURCE | DUCT | VENTILATION
InPort_3002073_4 | SINK | PIPE | DOMESTICHOTWATER | Group: Domestic Hot Water 61
OutPort_3002078_0 | SOURCE | PIPE | DOMESTICHOTWATER | Group: Domestic Hot Water 61
OutPort_3002073_5 | SOURCE | PIPE | DOMESTICHOTWATER
InPort_3002073_6 | SINK | PIPE | DOMESTICCOLDWATER
OutPort_3002073_7 | SOURCE | DUCT | EXHAUST
InPort_3002073_8 | SINK | PIPE | USERDEFINED
InPort_3002092_1 | SINK | PIPE | DOMESTICHOTWATER | Group: Domestic Hot Water 61
OutPort_3002110_5 | SOURCE | DUCT | VENTILATION
InPort_3002120_4 | SINK | PIPE | DOMESTICHOTWATER | Group: Domestic Hot Water 64
OutPort_3002125_0 | SOURCE | PIPE | DOMESTICHOTWATER | Group: Domestic Hot Water 64
OutPort_3002120_5 | SOURCE | PIPE | DOMESTICHOTWATER
InPort_3002120_6 | SINK | PIPE | DOMESTICCOLDWATER
OutPort_3002120_7 | SOURCE | DUCT | EXHAUST
InPort_3002120_8 | SINK | PIPE | USERDEFINED
InPort_3002139_1 | SINK | PIPE | DOMESTICHOTWATER | Group: Domestic Hot Water 64
OutPort_3002156_5 | SOURCE | DUCT | VENTILATION
InPort_3002166_4 | SINK | PIPE | DOMESTICHOTWATER | Group: Domestic Hot Water 66
OutPort_3002171_0 | SOURCE | PIPE | DOMESTICHOTWATER | Group: Domestic Hot Water 66
OutPort_3002166_5 | SOURCE | PIPE | DOMESTICHOTWATER
InPort_3002166_6 | SINK | PIPE | DOMESTICCOLDWATER
OutPort_3002166_7 | SOURCE | DUCT | EXHAUST
InPort_3002166_8 | SINK | PIPE | USERDEFINED
InPort_3002185_1 | SINK | PIPE | DOMESTICHOTWATER | Group: Domestic Hot Water 66
OutPort_3002206_5 | SOURCE | DUCT | VENTILATION
InPort_3002216_4 | SINK | PIPE | DOMESTICHOTWATER | Group: Domestic Hot Water 68
OutPort_3002221_0 | SOURCE | PIPE | DOMESTICHOTWATER | Group: Domestic Hot Water 68
OutPort_3002216_5 | SOURCE | PIPE | DOMESTICHOTWATER
InPort_3002216_6 | SINK | PIPE | DOMESTICCOLDWATER
OutPort_3002216_7 | SOURCE | DUCT | EXHAUST
InPort_3002216_8 | SINK | PIPE | USERDEFINED
InPort_3002235_1 | SINK | PIPE | DOMESTICHOTWATER | Group: Domestic Hot Water 68
OutPort_3002252_5 | SOURCE | DUCT | VENTILATION
InPort_3002262_4 | SINK | PIPE | DOMESTICHOTWATER | Group: Domestic Hot Water 70
OutPort_3002267_0 | SOURCE | PIPE | DOMESTICHOTWATER | Group: Domestic Hot Water 70
OutPort_3002262_5 | SOURCE | PIPE | DOMESTICHOTWATER
InPort_3002262_6 | SINK | PIPE | DOMESTICCOLDWATER
OutPort_3002262_7 | SOURCE | DUCT | EXHAUST
InPort_3002262_8 | SINK | PIPE | USERDEFINED
InPort_3002281_1 | SINK | PIPE | DOMESTICHOTWATER | Group: Domestic Hot Water 70
OutPort_3002298_5 | SOURCE | DUCT | VENTILATION
InPort_3002308_4 | SINK | PIPE | DOMESTICHOTWATER | Group: Domestic Hot Water 72
OutPort_3002313_0 | SOURCE | PIPE | DOMESTICHOTWATER | Group: Domestic Hot Water 72
OutPort_3002308_5 | SOURCE | PIPE | DOMESTICHOTWATER
InPort_3002308_6 | SINK | PIPE | DOMESTICCOLDWATER
OutPort_3002308_7 | SOURCE | DUCT | EXHAUST
InPort_3002308_8 | SINK | PIPE | USERDEFINED
InPort_3002327_1 | SINK | PIPE | DOMESTICHOTWATER | Group: Domestic Hot Water 72
OutPort_3002344_5 | SOURCE | DUCT | VENTILATION
InPort_3002354_4 | SINK | PIPE | DOMESTICHOTWATER | Group: Domestic Hot Water 74
OutPort_3002359_0 | SOURCE | PIPE | DOMESTICHOTWATER | Group: Domestic Hot Water 74
OutPort_3002354_5 | SOURCE | PIPE | DOMESTICHOTWATER
InPort_3002354_6 | SINK | PIPE | DOMESTICCOLDWATER
OutPort_3002354_7 | SOURCE | DUCT | EXHAUST
InPort_3002354_8 | SINK | PIPE | USERDEFINED
InPort_3002373_1 | SINK | PIPE | DOMESTICHOTWATER | Group: Domestic Hot Water 74
OutPort_3002390_5 | SOURCE | DUCT | VENTILATION
InPort_3002400_4 | SINK | PIPE | DOMESTICHOTWATER | Group: Domestic Hot Water 76
OutPort_3002405_0 | SOURCE | PIPE | DOMESTICHOTWATER | Group: Domestic Hot Water 76
OutPort_3002400_5 | SOURCE | PIPE | DOMESTICHOTWATER
InPort_3002400_6 | SINK | PIPE | DOMESTICCOLDWATER
OutPort_3002400_7 | SOURCE | DUCT | EXHAUST
InPort_3002400_8 | SINK | PIPE | USERDEFINED
InPort_3002419_1 | SINK | PIPE | DOMESTICHOTWATER | Group: Domestic Hot Water 76
OutPort_3002437_5 | SOURCE | DUCT | VENTILATION
InPort_3002447_4 | SINK | PIPE | DOMESTICHOTWATER | Group: Domestic Hot Water 78
OutPort_3002452_0 | SOURCE | PIPE | DOMESTICHOTWATER | Group: Domestic Hot Water 78
OutPort_3002447_5 | SOURCE | PIPE | DOMESTICHOTWATER
InPort_3002447_6 | SINK | PIPE | DOMESTICCOLDWATER
OutPort_3002447_7 | SOURCE | DUCT | EXHAUST
InPort_3002447_8 | SINK | PIPE | USERDEFINED
InPort_3002466_1 | SINK | PIPE | DOMESTICHOTWATER | Group: Domestic Hot Water 78
OutPort_3002483_5 | SOURCE | DUCT | VENTILATION
InPort_3002493_4 | SINK | PIPE | DOMESTICHOTWATER | Group: Domestic Hot Water 80
OutPort_3002498_0 | SOURCE | PIPE | DOMESTICHOTWATER | Group: Domestic Hot Water 80
OutPort_3002493_5 | SOURCE | PIPE | DOMESTICHOTWATER
InPort_3002493_6 | SINK | PIPE | DOMESTICCOLDWATER
OutPort_3002493_7 | SOURCE | DUCT | EXHAUST
InPort_3002493_8 | SINK | PIPE | USERDEFINED
InPort_3002512_1 | SINK | PIPE | DOMESTICHOTWATER | Group: Domestic Hot Water 80
OutPort_3002533_5 | SOURCE | DUCT | VENTILATION
InPort_3002543_4 | SINK | PIPE | DOMESTICHOTWATER | Group: Domestic Hot Water 82
OutPort_3002548_0 | SOURCE | PIPE | DOMESTICHOTWATER | Group: Domestic Hot Water 82
OutPort_3002543_5 | SOURCE | PIPE | DOMESTICHOTWATER
InPort_3002543_6 | SINK | PIPE | DOMESTICCOLDWATER
OutPort_3002543_7 | SOURCE | DUCT | EXHAUST
InPort_3002543_8 | SINK | PIPE | USERDEFINED
InPort_3002562_1 | SINK | PIPE | DOMESTICHOTWATER | Group: Domestic Hot Water 82
OutPort_3002579_5 | SOURCE | DUCT | VENTILATION
InPort_3002589_4 | SINK | PIPE | DOMESTICHOTWATER | Group: Domestic Hot Water 84
OutPort_3002594_0 | SOURCE | PIPE | DOMESTICHOTWATER | Group: Domestic Hot Water 84
OutPort_3002589_5 | SOURCE | PIPE | DOMESTICHOTWATER
InPort_3002589_6 | SINK | PIPE | DOMESTICCOLDWATER
OutPort_3002589_7 | SOURCE | DUCT | EXHAUST
InPort_3002589_8 | SINK | PIPE | USERDEFINED
InPort_3002608_1 | SINK | PIPE | DOMESTICHOTWATER | Group: Domestic Hot Water 84
OutPort_3002625_5 | SOURCE | DUCT | VENTILATION
InPort_3002635_4 | SINK | PIPE | DOMESTICHOTWATER | Group: Domestic Hot Water 86
OutPort_3002640_0 | SOURCE | PIPE | DOMESTICHOTWATER | Group: Domestic Hot Water 86
OutPort_3002635_5 | SOURCE | PIPE | DOMESTICHOTWATER
InPort_3002635_6 | SINK | PIPE | DOMESTICCOLDWATER
OutPort_3002635_7 | SOURCE | DUCT | EXHAUST
InPort_3002635_8 | SINK | PIPE | USERDEFINED
InPort_3002654_1 | SINK | PIPE | DOMESTICHOTWATER | Group: Domestic Hot Water 86
OutPort_3002671_5 | SOURCE | DUCT | VENTILATION
InPort_3002681_4 | SINK | PIPE | DOMESTICHOTWATER | Group: Domestic Hot Water 88
OutPort_3002686_0 | SOURCE | PIPE | DOMESTICHOTWATER | Group: Domestic Hot Water 88
OutPort_3002681_5 | SOURCE | PIPE | DOMESTICHOTWATER
InPort_3002681_6 | SINK | PIPE | DOMESTICCOLDWATER
OutPort_3002681_7 | SOURCE | DUCT | EXHAUST
InPort_3002681_8 | SINK | PIPE | USERDEFINED
InPort_3002700_1 | SINK | PIPE | DOMESTICHOTWATER | Group: Domestic Hot Water 88
OutPort_3002717_5 | SOURCE | DUCT | VENTILATION
InPort_3002727_4 | SINK | PIPE | DOMESTICHOTWATER | Group: Domestic Hot Water 90
OutPort_3002732_0 | SOURCE | PIPE | DOMESTICHOTWATER | Group: Domestic Hot Water 90
OutPort_3002727_5 | SOURCE | PIPE | DOMESTICHOTWATER
InPort_3002727_6 | SINK | PIPE | DOMESTICCOLDWATER
OutPort_3002727_7 | SOURCE | DUCT | EXHAUST
InPort_3002727_8 | SINK | PIPE | USERDEFINED
InPort_3002746_1 | SINK | PIPE | DOMESTICHOTWATER | Group: Domestic Hot Water 90
OutPort_3002764_5 | SOURCE | DUCT | VENTILATION
InPort_3002774_4 | SINK | PIPE | DOMESTICHOTWATER | Group: Domestic Hot Water 92
OutPort_3002779_0 | SOURCE | PIPE | DOMESTICHOTWATER | Group: Domestic Hot Water 92
OutPort_3002774_5 | SOURCE | PIPE | DOMESTICHOTWATER
InPort_3002774_6 | SINK | PIPE | DOMESTICCOLDWATER
OutPort_3002774_7 | SOURCE | DUCT | EXHAUST
InPort_3002774_8 | SINK | PIPE | USERDEFINED
InPort_3002793_1 | SINK | PIPE | DOMESTICHOTWATER | Group: Domestic Hot Water 92
OutPort_3002810_5 | SOURCE | DUCT | VENTILATION
InPort_3002820_4 | SINK | PIPE | DOMESTICHOTWATER | Group: Domestic Hot Water 94
OutPort_3002825_0 | SOURCE | PIPE | DOMESTICHOTWATER | Group: Domestic Hot Water 94
OutPort_3002820_5 | SOURCE | PIPE | DOMESTICHOTWATER
InPort_3002820_6 | SINK | PIPE | DOMESTICCOLDWATER
OutPort_3002820_7 | SOURCE | DUCT | EXHAUST
InPort_3002820_8 | SINK | PIPE | USERDEFINED
InPort_3002839_1 | SINK | PIPE | DOMESTICHOTWATER | Group: Domestic Hot Water 94
OutPort_3002860_5 | SOURCE | DUCT | VENTILATION
InPort_3002870_4 | SINK | PIPE | DOMESTICHOTWATER | Group: Domestic Hot Water 96
OutPort_3002875_0 | SOURCE | PIPE | DOMESTICHOTWATER | Group: Domestic Hot Water 96
OutPort_3002870_5 | SOURCE | PIPE | DOMESTICHOTWATER
InPort_3002870_6 | SINK | PIPE | DOMESTICCOLDWATER
OutPort_3002870_7 | SOURCE | DUCT | EXHAUST
InPort_3002870_8 | SINK | PIPE | USERDEFINED
InPort_3002889_1 | SINK | PIPE | DOMESTICHOTWATER | Group: Domestic Hot Water 96
OutPort_3002906_5 | SOURCE | DUCT | VENTILATION
InPort_3002916_4 | SINK | PIPE | DOMESTICHOTWATER | Group: Domestic Hot Water 98
OutPort_3002921_0 | SOURCE | PIPE | DOMESTICHOTWATER | Group: Domestic Hot Water 98
OutPort_3002916_5 | SOURCE | PIPE | DOMESTICHOTWATER
InPort_3002916_6 | SINK | PIPE | DOMESTICCOLDWATER
OutPort_3002916_7 | SOURCE | DUCT | EXHAUST
InPort_3002916_8 | SINK | PIPE | USERDEFINED
InPort_3002935_1 | SINK | PIPE | DOMESTICHOTWATER | Group: Domestic Hot Water 98
OutPort_3002952_5 | SOURCE | DUCT | VENTILATION
InPort_3002962_4 | SINK | PIPE | DOMESTICHOTWATER | Group: Domestic Hot Water 100
OutPort_3002967_0 | SOURCE | PIPE | DOMESTICHOTWATER | Group: Domestic Hot Water 100
OutPort_3002962_5 | SOURCE | PIPE | DOMESTICHOTWATER
InPort_3002962_6 | SINK | PIPE | DOMESTICCOLDWATER
OutPort_3002962_7 | SOURCE | DUCT | EXHAUST
InPort_3002962_8 | SINK | PIPE | USERDEFINED
InPort_3002981_1 | SINK | PIPE | DOMESTICHOTWATER | Group: Domestic Hot Water 100
OutPort_3002998_5 | SOURCE | DUCT | VENTILATION
InPort_3003008_4 | SINK | PIPE | DOMESTICHOTWATER | Group: Domestic Hot Water 102
OutPort_3003013_0 | SOURCE | PIPE | DOMESTICHOTWATER | Group: Domestic Hot Water 102
OutPort_3003008_5 | SOURCE | PIPE | DOMESTICHOTWATER
InPort_3003008_6 | SINK | PIPE | DOMESTICCOLDWATER
OutPort_3003008_7 | SOURCE | DUCT | EXHAUST
InPort_3003008_8 | SINK | PIPE | USERDEFINED
InPort_3003027_1 | SINK | PIPE | DOMESTICHOTWATER | Group: Domestic Hot Water 102
OutPort_3003044_5 | SOURCE | DUCT | VENTILATION
InPort_3003054_4 | SINK | PIPE | DOMESTICHOTWATER | Group: Domestic Hot Water 104
OutPort_3003059_0 | SOURCE | PIPE | DOMESTICHOTWATER | Group: Domestic Hot Water 104
OutPort_3003054_5 | SOURCE | PIPE | DOMESTICHOTWATER
InPort_3003054_6 | SINK | PIPE | DOMESTICCOLDWATER
OutPort_3003054_7 | SOURCE | DUCT | EXHAUST
InPort_3003054_8 | SINK | PIPE | USERDEFINED
InPort_3003073_1 | SINK | PIPE | DOMESTICHOTWATER | Group: Domestic Hot Water 104
OutPort_3003653_5 | SOURCE | DUCT | VENTILATION
InPort_3003663_4 | SINK | PIPE | DOMESTICHOTWATER | Group: Domestic Hot Water 9
OutPort_3003668_0 | SOURCE | PIPE | DOMESTICHOTWATER | Group: Domestic Hot Water 9
OutPort_3003663_5 | SOURCE | PIPE | DOMESTICHOTWATER
InPort_3003663_6 | SINK | PIPE | DOMESTICCOLDWATER
OutPort_3003663_7 | SOURCE | DUCT | EXHAUST
InPort_3003663_8 | SINK | PIPE | USERDEFINED
InPort_3003682_1 | SINK | PIPE | DOMESTICHOTWATER | Group: Domestic Hot Water 9
OutPort_3003699_5 | SOURCE | DUCT | VENTILATION
InPort_3003709_4 | SINK | PIPE | DOMESTICHOTWATER | Group: Domestic Hot Water 19
OutPort_3003714_0 | SOURCE | PIPE | DOMESTICHOTWATER | Group: Domestic Hot Water 19
OutPort_3003709_5 | SOURCE | PIPE | DOMESTICHOTWATER
InPort_3003709_6 | SINK | PIPE | DOMESTICCOLDWATER
OutPort_3003709_7 | SOURCE | DUCT | EXHAUST
InPort_3003709_8 | SINK | PIPE | USERDEFINED
InPort_3003728_1 | SINK | PIPE | DOMESTICHOTWATER | Group: Domestic Hot Water 19
OutPort_3003749_5 | SOURCE | DUCT | VENTILATION
InPort_3003759_4 | SINK | PIPE | DOMESTICHOTWATER | Group: Domestic Hot Water 27
OutPort_3003764_0 | SOURCE | PIPE | DOMESTICHOTWATER | Group: Domestic Hot Water 27
OutPort_3003759_5 | SOURCE | PIPE | DOMESTICHOTWATER
InPort_3003759_6 | SINK | PIPE | DOMESTICCOLDWATER
OutPort_3003759_7 | SOURCE | DUCT | EXHAUST
InPort_3003759_8 | SINK | PIPE | USERDEFINED
InPort_3003778_1 | SINK | PIPE | DOMESTICHOTWATER | Group: Domestic Hot Water 27
OutPort_3003795_5 | SOURCE | DUCT | VENTILATION
InPort_3003805_4 | SINK | PIPE | DOMESTICHOTWATER | Group: Domestic Hot Water 35
OutPort_3003810_0 | SOURCE | PIPE | DOMESTICHOTWATER | Group: Domestic Hot Water 35
OutPort_3003805_5 | SOURCE | PIPE | DOMESTICHOTWATER
InPort_3003805_6 | SINK | PIPE | DOMESTICCOLDWATER
OutPort_3003805_7 | SOURCE | DUCT | EXHAUST
InPort_3003805_8 | SINK | PIPE | USERDEFINED
InPort_3003824_1 | SINK | PIPE | DOMESTICHOTWATER | Group: Domestic Hot Water 35
OutPort_3003841_5 | SOURCE | DUCT | VENTILATION
InPort_3003851_4 | SINK | PIPE | DOMESTICHOTWATER | Group: Domestic Hot Water 43
OutPort_3003856_0 | SOURCE | PIPE | DOMESTICHOTWATER | Group: Domestic Hot Water 43
OutPort_3003851_5 | SOURCE | PIPE | DOMESTICHOTWATER
InPort_3003851_6 | SINK | PIPE | DOMESTICCOLDWATER
OutPort_3003851_7 | SOURCE | DUCT | EXHAUST
InPort_3003851_8 | SINK | PIPE | USERDEFINED
InPort_3003870_1 | SINK | PIPE | DOMESTICHOTWATER | Group: Domestic Hot Water 43
OutPort_3003887_5 | SOURCE | DUCT | VENTILATION
InPort_3003897_4 | SINK | PIPE | DOMESTICHOTWATER | Group: Domestic Hot Water 51
OutPort_3003902_0 | SOURCE | PIPE | DOMESTICHOTWATER | Group: Domestic Hot Water 51
OutPort_3003897_5 | SOURCE | PIPE | DOMESTICHOTWATER
InPort_3003897_6 | SINK | PIPE | DOMESTICCOLDWATER
OutPort_3003897_7 | SOURCE | DUCT | EXHAUST
InPort_3003897_8 | SINK | PIPE | USERDEFINED
InPort_3003916_1 | SINK | PIPE | DOMESTICHOTWATER | Group: Domestic Hot Water 51
OutPort_3003933_5 | SOURCE | DUCT | VENTILATION
InPort_3003943_4 | SINK | PIPE | DOMESTICHOTWATER | Group: Domestic Hot Water 59
OutPort_3003948_0 | SOURCE | PIPE | DOMESTICHOTWATER | Group: Domestic Hot Water 59
OutPort_3003943_5 | SOURCE | PIPE | DOMESTICHOTWATER
InPort_3003943_6 | SINK | PIPE | DOMESTICCOLDWATER
OutPort_3003943_7 | SOURCE | DUCT | EXHAUST
InPort_3003943_8 | SINK | PIPE | USERDEFINED
InPort_3003962_1 | SINK | PIPE | DOMESTICHOTWATER | Group: Domestic Hot Water 59
OutPort_3003980_5 | SOURCE | DUCT | VENTILATION
InPort_3003990_4 | SINK | PIPE | DOMESTICHOTWATER | Group: Domestic Hot Water 65
OutPort_3003995_0 | SOURCE | PIPE | DOMESTICHOTWATER | Group: Domestic Hot Water 65
OutPort_3003990_5 | SOURCE | PIPE | DOMESTICHOTWATER
InPort_3003990_6 | SINK | PIPE | DOMESTICCOLDWATER
OutPort_3003990_7 | SOURCE | DUCT | EXHAUST
InPort_3003990_8 | SINK | PIPE | USERDEFINED
InPort_3004009_1 | SINK | PIPE | DOMESTICHOTWATER | Group: Domestic Hot Water 65
OutPort_3004026_5 | SOURCE | DUCT | VENTILATION
InPort_3004036_4 | SINK | PIPE | DOMESTICHOTWATER | Group: Domestic Hot Water 69
OutPort_3004041_0 | SOURCE | PIPE | DOMESTICHOTWATER | Group: Domestic Hot Water 69
OutPort_3004036_5 | SOURCE | PIPE | DOMESTICHOTWATER
InPort_3004036_6 | SINK | PIPE | DOMESTICCOLDWATER
OutPort_3004036_7 | SOURCE | DUCT | EXHAUST
InPort_3004036_8 | SINK | PIPE | USERDEFINED
InPort_3004055_1 | SINK | PIPE | DOMESTICHOTWATER | Group: Domestic Hot Water 69
OutPort_3004076_5 | SOURCE | DUCT | VENTILATION
InPort_3004086_4 | SINK | PIPE | DOMESTICHOTWATER | Group: Domestic Hot Water 73
OutPort_3004091_0 | SOURCE | PIPE | DOMESTICHOTWATER | Group: Domestic Hot Water 73
OutPort_3004086_5 | SOURCE | PIPE | DOMESTICHOTWATER
InPort_3004086_6 | SINK | PIPE | DOMESTICCOLDWATER
OutPort_3004086_7 | SOURCE | DUCT | EXHAUST
InPort_3004086_8 | SINK | PIPE | USERDEFINED
InPort_3004105_1 | SINK | PIPE | DOMESTICHOTWATER | Group: Domestic Hot Water 73
OutPort_3004122_5 | SOURCE | DUCT | VENTILATION
InPort_3004132_4 | SINK | PIPE | DOMESTICHOTWATER | Group: Domestic Hot Water 77
OutPort_3004137_0 | SOURCE | PIPE | DOMESTICHOTWATER | Group: Domestic Hot Water 77
OutPort_3004132_5 | SOURCE | PIPE | DOMESTICHOTWATER
InPort_3004132_6 | SINK | PIPE | DOMESTICCOLDWATER
OutPort_3004132_7 | SOURCE | DUCT | EXHAUST
InPort_3004132_8 | SINK | PIPE | USERDEFINED
InPort_3004151_1 | SINK | PIPE | DOMESTICHOTWATER | Group: Domestic Hot Water 77
OutPort_3004168_5 | SOURCE | DUCT | VENTILATION
InPort_3004178_4 | SINK | PIPE | DOMESTICHOTWATER | Group: Domestic Hot Water 81
OutPort_3004183_0 | SOURCE | PIPE | DOMESTICHOTWATER | Group: Domestic Hot Water 81
OutPort_3004178_5 | SOURCE | PIPE | DOMESTICHOTWATER
InPort_3004178_6 | SINK | PIPE | DOMESTICCOLDWATER
OutPort_3004178_7 | SOURCE | DUCT | EXHAUST
InPort_3004178_8 | SINK | PIPE | USERDEFINED
InPort_3004197_1 | SINK | PIPE | DOMESTICHOTWATER | Group: Domestic Hot Water 81
OutPort_3004214_5 | SOURCE | DUCT | VENTILATION
InPort_3004224_4 | SINK | PIPE | DOMESTICHOTWATER | Group: Domestic Hot Water 85
OutPort_3004229_0 | SOURCE | PIPE | DOMESTICHOTWATER | Group: Domestic Hot Water 85
OutPort_3004224_5 | SOURCE | PIPE | DOMESTICHOTWATER
InPort_3004224_6 | SINK | PIPE | DOMESTICCOLDWATER
OutPort_3004224_7 | SOURCE | DUCT | EXHAUST
InPort_3004224_8 | SINK | PIPE | USERDEFINED
InPort_3004243_1 | SINK | PIPE | DOMESTICHOTWATER | Group: Domestic Hot Water 85
OutPort_3004260_5 | SOURCE | DUCT | VENTILATION
InPort_3004270_4 | SINK | PIPE | DOMESTICHOTWATER | Group: Domestic Hot Water 89
OutPort_3004275_0 | SOURCE | PIPE | DOMESTICHOTWATER | Group: Domestic Hot Water 89
OutPort_3004270_5 | SOURCE | PIPE | DOMESTICHOTWATER
InPort_3004270_6 | SINK | PIPE | DOMESTICCOLDWATER
OutPort_3004270_7 | SOURCE | DUCT | EXHAUST
InPort_3004270_8 | SINK | PIPE | USERDEFINED
InPort_3004289_1 | SINK | PIPE | DOMESTICHOTWATER | Group: Domestic Hot Water 89
OutPort_3004307_5 | SOURCE | DUCT | VENTILATION
InPort_3004317_4 | SINK | PIPE | DOMESTICHOTWATER | Group: Domestic Hot Water 93
OutPort_3004322_0 | SOURCE | PIPE | DOMESTICHOTWATER | Group: Domestic Hot Water 93
OutPort_3004317_5 | SOURCE | PIPE | DOMESTICHOTWATER
InPort_3004317_6 | SINK | PIPE | DOMESTICCOLDWATER
OutPort_3004317_7 | SOURCE | DUCT | EXHAUST
InPort_3004317_8 | SINK | PIPE | USERDEFINED
InPort_3004336_1 | SINK | PIPE | DOMESTICHOTWATER | Group: Domestic Hot Water 93
OutPort_3004353_5 | SOURCE | DUCT | VENTILATION
InPort_3004363_4 | SINK | PIPE | DOMESTICHOTWATER | Group: Domestic Hot Water 97
OutPort_3004368_0 | SOURCE | PIPE | DOMESTICHOTWATER | Group: Domestic Hot Water 97
OutPort_3004363_5 | SOURCE | PIPE | DOMESTICHOTWATER
InPort_3004363_6 | SINK | PIPE | DOMESTICCOLDWATER
OutPort_3004363_7 | SOURCE | DUCT | EXHAUST
InPort_3004363_8 | SINK | PIPE | USERDEFINED
InPort_3004382_1 | SINK | PIPE | DOMESTICHOTWATER | Group: Domestic Hot Water 97
OutPort_3004403_5 | SOURCE | DUCT | VENTILATION
InPort_3004413_4 | SINK | PIPE | DOMESTICHOTWATER | Group: Domestic Hot Water 101
OutPort_3004418_0 | SOURCE | PIPE | DOMESTICHOTWATER | Group: Domestic Hot Water 101
OutPort_3004413_5 | SOURCE | PIPE | DOMESTICHOTWATER
InPort_3004413_6 | SINK | PIPE | DOMESTICCOLDWATER
OutPort_3004413_7 | SOURCE | DUCT | EXHAUST
InPort_3004413_8 | SINK | PIPE | USERDEFINED
InPort_3004432_1 | SINK | PIPE | DOMESTICHOTWATER | Group: Domestic Hot Water 101
OutPort_3004449_5 | SOURCE | DUCT | VENTILATION
InPort_3004459_4 | SINK | PIPE | DOMESTICHOTWATER | Group: Domestic Hot Water 105
OutPort_3004464_0 | SOURCE | PIPE | DOMESTICHOTWATER | Group: Domestic Hot Water 105
OutPort_3004459_5 | SOURCE | PIPE | DOMESTICHOTWATER
InPort_3004459_6 | SINK | PIPE | DOMESTICCOLDWATER
OutPort_3004459_7 | SOURCE | DUCT | EXHAUST
InPort_3004459_8 | SINK | PIPE | USERDEFINED
InPort_3004478_1 | SINK | PIPE | DOMESTICHOTWATER | Group: Domestic Hot Water 105
OutPort_3004495_5 | SOURCE | DUCT | VENTILATION
InPort_3004505_4 | SINK | PIPE | DOMESTICHOTWATER | Group: Domestic Hot Water 107
OutPort_3004510_0 | SOURCE | PIPE | DOMESTICHOTWATER | Group: Domestic Hot Water 107
OutPort_3004505_5 | SOURCE | PIPE | DOMESTICHOTWATER
InPort_3004505_6 | SINK | PIPE | DOMESTICCOLDWATER
OutPort_3004505_7 | SOURCE | DUCT | EXHAUST
InPort_3004505_8 | SINK | PIPE | USERDEFINED
InPort_3004524_1 | SINK | PIPE | DOMESTICHOTWATER | Group: Domestic Hot Water 107
OutPort_3004541_5 | SOURCE | DUCT | VENTILATION
InPort_3004551_4 | SINK | PIPE | DOMESTICHOTWATER | Group: Domestic Hot Water 109
OutPort_3004556_0 | SOURCE | PIPE | DOMESTICHOTWATER | Group: Domestic Hot Water 109
OutPort_3004551_5 | SOURCE | PIPE | DOMESTICHOTWATER
InPort_3004551_6 | SINK | PIPE | DOMESTICCOLDWATER
OutPort_3004551_7 | SOURCE | DUCT | EXHAUST
InPort_3004551_8 | SINK | PIPE | USERDEFINED
InPort_3004570_1 | SINK | PIPE | DOMESTICHOTWATER | Group: Domestic Hot Water 109
OutPort_3004587_5 | SOURCE | DUCT | VENTILATION
InPort_3004597_4 | SINK | PIPE | DOMESTICHOTWATER | Group: Domestic Hot Water 111
OutPort_3004602_0 | SOURCE | PIPE | DOMESTICHOTWATER | Group: Domestic Hot Water 111
OutPort_3004597_5 | SOURCE | PIPE | DOMESTICHOTWATER
InPort_3004597_6 | SINK | PIPE | DOMESTICCOLDWATER
OutPort_3004597_7 | SOURCE | DUCT | EXHAUST
InPort_3004597_8 | SINK | PIPE | USERDEFINED
InPort_3004616_1 | SINK | PIPE | DOMESTICHOTWATER | Group: Domestic Hot Water 111
OutPort_3004634_5 | SOURCE | DUCT | VENTILATION
InPort_3004644_4 | SINK | PIPE | DOMESTICHOTWATER | Group: Domestic Hot Water 113
OutPort_3004649_0 | SOURCE | PIPE | DOMESTICHOTWATER | Group: Domestic Hot Water 113
OutPort_3004644_5 | SOURCE | PIPE | DOMESTICHOTWATER
InPort_3004644_6 | SINK | PIPE | DOMESTICCOLDWATER
OutPort_3004644_7 | SOURCE | DUCT | EXHAUST
InPort_3004644_8 | SINK | PIPE | USERDEFINED
InPort_3004663_1 | SINK | PIPE | DOMESTICHOTWATER | Group: Domestic Hot Water 113
OutPort_3004680_5 | SOURCE | DUCT | VENTILATION
InPort_3004690_4 | SINK | PIPE | DOMESTICHOTWATER | Group: Domestic Hot Water 115
OutPort_3004695_0 | SOURCE | PIPE | DOMESTICHOTWATER | Group: Domestic Hot Water 115
OutPort_3004690_5 | SOURCE | PIPE | DOMESTICHOTWATER
InPort_3004690_6 | SINK | PIPE | DOMESTICCOLDWATER
OutPort_3004690_7 | SOURCE | DUCT | EXHAUST
InPort_3004690_8 | SINK | PIPE | USERDEFINED
InPort_3004709_1 | SINK | PIPE | DOMESTICHOTWATER | Group: Domestic Hot Water 115
OutPort_3004730_5 | SOURCE | DUCT | VENTILATION
InPort_3004740_4 | SINK | PIPE | DOMESTICHOTWATER | Group: Domestic Hot Water 117
OutPort_3004745_0 | SOURCE | PIPE | DOMESTICHOTWATER | Group: Domestic Hot Water 117
OutPort_3004740_5 | SOURCE | PIPE | DOMESTICHOTWATER
InPort_3004740_6 | SINK | PIPE | DOMESTICCOLDWATER
OutPort_3004740_7 | SOURCE | DUCT | EXHAUST
InPort_3004740_8 | SINK | PIPE | USERDEFINED
InPort_3004759_1 | SINK | PIPE | DOMESTICHOTWATER | Group: Domestic Hot Water 117
OutPort_3004776_5 | SOURCE | DUCT | VENTILATION
InPort_3004786_4 | SINK | PIPE | DOMESTICHOTWATER | Group: Domestic Hot Water 119
OutPort_3004791_0 | SOURCE | PIPE | DOMESTICHOTWATER | Group: Domestic Hot Water 119
OutPort_3004786_5 | SOURCE | PIPE | DOMESTICHOTWATER
InPort_3004786_6 | SINK | PIPE | DOMESTICCOLDWATER
OutPort_3004786_7 | SOURCE | DUCT | EXHAUST
InPort_3004786_8 | SINK | PIPE | USERDEFINED
InPort_3004805_1 | SINK | PIPE | DOMESTICHOTWATER | Group: Domestic Hot Water 119
OutPort_3004822_5 | SOURCE | DUCT | VENTILATION
InPort_3004832_4 | SINK | PIPE | DOMESTICHOTWATER | Group: Domestic Hot Water 121
OutPort_3004837_0 | SOURCE | PIPE | DOMESTICHOTWATER | Group: Domestic Hot Water 121
OutPort_3004832_5 | SOURCE | PIPE | DOMESTICHOTWATER
InPort_3004832_6 | SINK | PIPE | DOMESTICCOLDWATER
OutPort_3004832_7 | SOURCE | DUCT | EXHAUST
InPort_3004832_8 | SINK | PIPE | USERDEFINED
InPort_3004851_1 | SINK | PIPE | DOMESTICHOTWATER | Group: Domestic Hot Water 121
OutPort_3004868_5 | SOURCE | DUCT | VENTILATION
InPort_3004878_4 | SINK | PIPE | DOMESTICHOTWATER | Group: Domestic Hot Water 123
OutPort_3004883_0 | SOURCE | PIPE | DOMESTICHOTWATER | Group: Domestic Hot Water 123
OutPort_3004878_5 | SOURCE | PIPE | DOMESTICHOTWATER
InPort_3004878_6 | SINK | PIPE | DOMESTICCOLDWATER
OutPort_3004878_7 | SOURCE | DUCT | EXHAUST
InPort_3004878_8 | SINK | PIPE | USERDEFINED
InPort_3004897_1 | SINK | PIPE | DOMESTICHOTWATER | Group: Domestic Hot Water 123
OutPort_3004914_5 | SOURCE | DUCT | VENTILATION
InPort_3004924_4 | SINK | PIPE | DOMESTICHOTWATER | Group: Domestic Hot Water 125
OutPort_3004929_0 | SOURCE | PIPE | DOMESTICHOTWATER | Group: Domestic Hot Water 125
OutPort_3004924_5 | SOURCE | PIPE | DOMESTICHOTWATER
InPort_3004924_6 | SINK | PIPE | DOMESTICCOLDWATER
OutPort_3004924_7 | SOURCE | DUCT | EXHAUST
InPort_3004924_8 | SINK | PIPE | USERDEFINED
InPort_3004943_1 | SINK | PIPE | DOMESTICHOTWATER | Group: Domestic Hot Water 125
OutPort_3004961_5 | SOURCE | DUCT | VENTILATION
InPort_3004971_4 | SINK | PIPE | DOMESTICHOTWATER | Group: Domestic Hot Water 127
OutPort_3004976_0 | SOURCE | PIPE | DOMESTICHOTWATER | Group: Domestic Hot Water 127
OutPort_3004971_5 | SOURCE | PIPE | DOMESTICHOTWATER
InPort_3004971_6 | SINK | PIPE | DOMESTICCOLDWATER
OutPort_3004971_7 | SOURCE | DUCT | EXHAUST
InPort_3004971_8 | SINK | PIPE | USERDEFINED
InPort_3004990_1 | SINK | PIPE | DOMESTICHOTWATER | Group: Domestic Hot Water 127
OutPort_3005007_5 | SOURCE | DUCT | VENTILATION
InPort_3005017_4 | SINK | PIPE | DOMESTICHOTWATER | Group: Domestic Hot Water 129
OutPort_3005022_0 | SOURCE | PIPE | DOMESTICHOTWATER | Group: Domestic Hot Water 129
OutPort_3005017_5 | SOURCE | PIPE | DOMESTICHOTWATER
InPort_3005017_6 | SINK | PIPE | DOMESTICCOLDWATER
OutPort_3005017_7 | SOURCE | DUCT | EXHAUST
InPort_3005017_8 | SINK | PIPE | USERDEFINED
InPort_3005036_1 | SINK | PIPE | DOMESTICHOTWATER | Group: Domestic Hot Water 129
OutPort_3005057_5 | SOURCE | DUCT | VENTILATION
InPort_3005067_4 | SINK | PIPE | DOMESTICHOTWATER | Group: Domestic Hot Water 131
OutPort_3005072_0 | SOURCE | PIPE | DOMESTICHOTWATER | Group: Domestic Hot Water 131
OutPort_3005067_5 | SOURCE | PIPE | DOMESTICHOTWATER
InPort_3005067_6 | SINK | PIPE | DOMESTICCOLDWATER
OutPort_3005067_7 | SOURCE | DUCT | EXHAUST
InPort_3005067_8 | SINK | PIPE | USERDEFINED
InPort_3005086_1 | SINK | PIPE | DOMESTICHOTWATER | Group: Domestic Hot Water 131
OutPort_3005103_5 | SOURCE | DUCT | VENTILATION
InPort_3005113_4 | SINK | PIPE | DOMESTICHOTWATER | Group: Domestic Hot Water 133
OutPort_3005118_0 | SOURCE | PIPE | DOMESTICHOTWATER | Group: Domestic Hot Water 133
OutPort_3005113_5 | SOURCE | PIPE | DOMESTICHOTWATER
InPort_3005113_6 | SINK | PIPE | DOMESTICCOLDWATER
OutPort_3005113_7 | SOURCE | DUCT | EXHAUST
InPort_3005113_8 | SINK | PIPE | USERDEFINED
InPort_3005132_1 | SINK | PIPE | DOMESTICHOTWATER | Group: Domestic Hot Water 133
OutPort_3005149_5 | SOURCE | DUCT | VENTILATION
InPort_3005159_4 | SINK | PIPE | DOMESTICHOTWATER | Group: Domestic Hot Water 135
OutPort_3005164_0 | SOURCE | PIPE | DOMESTICHOTWATER | Group: Domestic Hot Water 135
OutPort_3005159_5 | SOURCE | PIPE | DOMESTICHOTWATER
InPort_3005159_6 | SINK | PIPE | DOMESTICCOLDWATER
OutPort_3005159_7 | SOURCE | DUCT | EXHAUST
InPort_3005159_8 | SINK | PIPE | USERDEFINED
InPort_3005178_1 | SINK | PIPE | DOMESTICHOTWATER | Group: Domestic Hot Water 135
OutPort_3005195_5 | SOURCE | DUCT | VENTILATION
InPort_3005205_4 | SINK | PIPE | DOMESTICHOTWATER | Group: Domestic Hot Water 137
OutPort_3005210_0 | SOURCE | PIPE | DOMESTICHOTWATER | Group: Domestic Hot Water 137
OutPort_3005205_5 | SOURCE | PIPE | DOMESTICHOTWATER
InPort_3005205_6 | SINK | PIPE | DOMESTICCOLDWATER
OutPort_3005205_7 | SOURCE | DUCT | EXHAUST
InPort_3005205_8 | SINK | PIPE | USERDEFINED
InPort_3005224_1 | SINK | PIPE | DOMESTICHOTWATER | Group: Domestic Hot Water 137
OutPort_3005241_5 | SOURCE | DUCT | VENTILATION
InPort_3005251_4 | SINK | PIPE | DOMESTICHOTWATER | Group: Domestic Hot Water 139
OutPort_3005256_0 | SOURCE | PIPE | DOMESTICHOTWATER | Group: Domestic Hot Water 139
OutPort_3005251_5 | SOURCE | PIPE | DOMESTICHOTWATER
InPort_3005251_6 | SINK | PIPE | DOMESTICCOLDWATER
OutPort_3005251_7 | SOURCE | DUCT | EXHAUST
InPort_3005251_8 | SINK | PIPE | USERDEFINED
InPort_3005270_1 | SINK | PIPE | DOMESTICHOTWATER | Group: Domestic Hot Water 139
OutPort_3005850_5 | SOURCE | DUCT | VENTILATION
InPort_3005860_4 | SINK | PIPE | DOMESTICHOTWATER | Group: Domestic Hot Water 15
OutPort_3005865_0 | SOURCE | PIPE | DOMESTICHOTWATER | Group: Domestic Hot Water 15
OutPort_3005860_5 | SOURCE | PIPE | DOMESTICHOTWATER
InPort_3005860_6 | SINK | PIPE | DOMESTICCOLDWATER
OutPort_3005860_7 | SOURCE | DUCT | EXHAUST
InPort_3005860_8 | SINK | PIPE | USERDEFINED
InPort_3005879_1 | SINK | PIPE | DOMESTICHOTWATER | Group: Domestic Hot Water 15
OutPort_3005896_5 | SOURCE | DUCT | VENTILATION
InPort_3005906_4 | SINK | PIPE | DOMESTICHOTWATER | Group: Domestic Hot Water 31
OutPort_3005911_0 | SOURCE | PIPE | DOMESTICHOTWATER | Group: Domestic Hot Water 31
OutPort_3005906_5 | SOURCE | PIPE | DOMESTICHOTWATER
InPort_3005906_6 | SINK | PIPE | DOMESTICCOLDWATER
OutPort_3005906_7 | SOURCE | DUCT | EXHAUST
InPort_3005906_8 | SINK | PIPE | USERDEFINED
InPort_3005925_1 | SINK | PIPE | DOMESTICHOTWATER | Group: Domestic Hot Water 31
OutPort_3005946_5 | SOURCE | DUCT | VENTILATION
InPort_3005956_4 | SINK | PIPE | DOMESTICHOTWATER | Group: Domestic Hot Water 47
OutPort_3005961_0 | SOURCE | PIPE | DOMESTICHOTWATER | Group: Domestic Hot Water 47
OutPort_3005956_5 | SOURCE | PIPE | DOMESTICHOTWATER
InPort_3005956_6 | SINK | PIPE | DOMESTICCOLDWATER
OutPort_3005956_7 | SOURCE | DUCT | EXHAUST
InPort_3005956_8 | SINK | PIPE | USERDEFINED
InPort_3005975_1 | SINK | PIPE | DOMESTICHOTWATER | Group: Domestic Hot Water 47
OutPort_3005992_5 | SOURCE | DUCT | VENTILATION
InPort_3006002_4 | SINK | PIPE | DOMESTICHOTWATER | Group: Domestic Hot Water 63
OutPort_3006007_0 | SOURCE | PIPE | DOMESTICHOTWATER | Group: Domestic Hot Water 63
OutPort_3006002_5 | SOURCE | PIPE | DOMESTICHOTWATER
InPort_3006002_6 | SINK | PIPE | DOMESTICCOLDWATER
OutPort_3006002_7 | SOURCE | DUCT | EXHAUST
InPort_3006002_8 | SINK | PIPE | USERDEFINED
InPort_3006021_1 | SINK | PIPE | DOMESTICHOTWATER | Group: Domestic Hot Water 63
OutPort_3006038_5 | SOURCE | DUCT | VENTILATION
InPort_3006048_4 | SINK | PIPE | DOMESTICHOTWATER | Group: Domestic Hot Water 71
OutPort_3006053_0 | SOURCE | PIPE | DOMESTICHOTWATER | Group: Domestic Hot Water 71
OutPort_3006048_5 | SOURCE | PIPE | DOMESTICHOTWATER
InPort_3006048_6 | SINK | PIPE | DOMESTICCOLDWATER
OutPort_3006048_7 | SOURCE | DUCT | EXHAUST
InPort_3006048_8 | SINK | PIPE | USERDEFINED
InPort_3006067_1 | SINK | PIPE | DOMESTICHOTWATER | Group: Domestic Hot Water 71
OutPort_3006084_5 | SOURCE | DUCT | VENTILATION
InPort_3006094_4 | SINK | PIPE | DOMESTICHOTWATER | Group: Domestic Hot Water 79
OutPort_3006099_0 | SOURCE | PIPE | DOMESTICHOTWATER | Group: Domestic Hot Water 79
OutPort_3006094_5 | SOURCE | PIPE | DOMESTICHOTWATER
InPort_3006094_6 | SINK | PIPE | DOMESTICCOLDWATER
OutPort_3006094_7 | SOURCE | DUCT | EXHAUST
InPort_3006094_8 | SINK | PIPE | USERDEFINED
InPort_3006113_1 | SINK | PIPE | DOMESTICHOTWATER | Group: Domestic Hot Water 79
OutPort_3006130_5 | SOURCE | DUCT | VENTILATION
InPort_3006140_4 | SINK | PIPE | DOMESTICHOTWATER | Group: Domestic Hot Water 87
OutPort_3006145_0 | SOURCE | PIPE | DOMESTICHOTWATER | Group: Domestic Hot Water 87
OutPort_3006140_5 | SOURCE | PIPE | DOMESTICHOTWATER
InPort_3006140_6 | SINK | PIPE | DOMESTICCOLDWATER
OutPort_3006140_7 | SOURCE | DUCT | EXHAUST
InPort_3006140_8 | SINK | PIPE | USERDEFINED
InPort_3006159_1 | SINK | PIPE | DOMESTICHOTWATER | Group: Domestic Hot Water 87
OutPort_3006177_5 | SOURCE | DUCT | VENTILATION
InPort_3006187_4 | SINK | PIPE | DOMESTICHOTWATER | Group: Domestic Hot Water 95
OutPort_3006192_0 | SOURCE | PIPE | DOMESTICHOTWATER | Group: Domestic Hot Water 95
OutPort_3006187_5 | SOURCE | PIPE | DOMESTICHOTWATER
InPort_3006187_6 | SINK | PIPE | DOMESTICCOLDWATER
OutPort_3006187_7 | SOURCE | DUCT | EXHAUST
InPort_3006187_8 | SINK | PIPE | USERDEFINED
InPort_3006206_1 | SINK | PIPE | DOMESTICHOTWATER | Group: Domestic Hot Water 95
OutPort_3006223_5 | SOURCE | DUCT | VENTILATION
InPort_3006233_4 | SINK | PIPE | DOMESTICHOTWATER | Group: Domestic Hot Water 103
OutPort_3006238_0 | SOURCE | PIPE | DOMESTICHOTWATER | Group: Domestic Hot Water 103
OutPort_3006233_5 | SOURCE | PIPE | DOMESTICHOTWATER
InPort_3006233_6 | SINK | PIPE | DOMESTICCOLDWATER
OutPort_3006233_7 | SOURCE | DUCT | EXHAUST
InPort_3006233_8 | SINK | PIPE | USERDEFINED
InPort_3006252_1 | SINK | PIPE | DOMESTICHOTWATER | Group: Domestic Hot Water 103
OutPort_3006273_5 | SOURCE | DUCT | VENTILATION
InPort_3006283_4 | SINK | PIPE | DOMESTICHOTWATER | Group: Domestic Hot Water 108
OutPort_3006288_0 | SOURCE | PIPE | DOMESTICHOTWATER | Group: Domestic Hot Water 108
OutPort_3006283_5 | SOURCE | PIPE | DOMESTICHOTWATER
InPort_3006283_6 | SINK | PIPE | DOMESTICCOLDWATER
OutPort_3006283_7 | SOURCE | DUCT | EXHAUST
InPort_3006283_8 | SINK | PIPE | USERDEFINED
InPort_3006302_1 | SINK | PIPE | DOMESTICHOTWATER | Group: Domestic Hot Water 108
OutPort_3006319_5 | SOURCE | DUCT | VENTILATION
InPort_3006329_4 | SINK | PIPE | DOMESTICHOTWATER | Group: Domestic Hot Water 112
OutPort_3006334_0 | SOURCE | PIPE | DOMESTICHOTWATER | Group: Domestic Hot Water 112
OutPort_3006329_5 | SOURCE | PIPE | DOMESTICHOTWATER
InPort_3006329_6 | SINK | PIPE | DOMESTICCOLDWATER
OutPort_3006329_7 | SOURCE | DUCT | EXHAUST
InPort_3006329_8 | SINK | PIPE | USERDEFINED
InPort_3006348_1 | SINK | PIPE | DOMESTICHOTWATER | Group: Domestic Hot Water 112
OutPort_3006365_5 | SOURCE | DUCT | VENTILATION
InPort_3006375_4 | SINK | PIPE | DOMESTICHOTWATER | Group: Domestic Hot Water 116
OutPort_3006380_0 | SOURCE | PIPE | DOMESTICHOTWATER | Group: Domestic Hot Water 116
OutPort_3006375_5 | SOURCE | PIPE | DOMESTICHOTWATER
InPort_3006375_6 | SINK | PIPE | DOMESTICCOLDWATER
OutPort_3006375_7 | SOURCE | DUCT | EXHAUST
InPort_3006375_8 | SINK | PIPE | USERDEFINED
InPort_3006394_1 | SINK | PIPE | DOMESTICHOTWATER | Group: Domestic Hot Water 116
OutPort_3006411_5 | SOURCE | DUCT | VENTILATION
InPort_3006421_4 | SINK | PIPE | DOMESTICHOTWATER | Group: Domestic Hot Water 120
OutPort_3006426_0 | SOURCE | PIPE | DOMESTICHOTWATER | Group: Domestic Hot Water 120
OutPort_3006421_5 | SOURCE | PIPE | DOMESTICHOTWATER
InPort_3006421_6 | SINK | PIPE | DOMESTICCOLDWATER
OutPort_3006421_7 | SOURCE | DUCT | EXHAUST
InPort_3006421_8 | SINK | PIPE | USERDEFINED
InPort_3006440_1 | SINK | PIPE | DOMESTICHOTWATER | Group: Domestic Hot Water 120
OutPort_3006457_5 | SOURCE | DUCT | VENTILATION
InPort_3006467_4 | SINK | PIPE | DOMESTICHOTWATER | Group: Domestic Hot Water 124
OutPort_3006472_0 | SOURCE | PIPE | DOMESTICHOTWATER | Group: Domestic Hot Water 124
OutPort_3006467_5 | SOURCE | PIPE | DOMESTICHOTWATER
InPort_3006467_6 | SINK | PIPE | DOMESTICCOLDWATER
OutPort_3006467_7 | SOURCE | DUCT | EXHAUST
InPort_3006467_8 | SINK | PIPE | USERDEFINED
InPort_3006486_1 | SINK | PIPE | DOMESTICHOTWATER | Group: Domestic Hot Water 124
OutPort_3006504_5 | SOURCE | DUCT | VENTILATION
InPort_3006514_4 | SINK | PIPE | DOMESTICHOTWATER | Group: Domestic Hot Water 128
OutPort_3006519_0 | SOURCE | PIPE | DOMESTICHOTWATER | Group: Domestic Hot Water 128
OutPort_3006514_5 | SOURCE | PIPE | DOMESTICHOTWATER
InPort_3006514_6 | SINK | PIPE | DOMESTICCOLDWATER
OutPort_3006514_7 | SOURCE | DUCT | EXHAUST
InPort_3006514_8 | SINK | PIPE | USERDEFINED
InPort_3006533_1 | SINK | PIPE | DOMESTICHOTWATER | Group: Domestic Hot Water 128
OutPort_3006550_5 | SOURCE | DUCT | VENTILATION
InPort_3006560_4 | SINK | PIPE | DOMESTICHOTWATER | Group: Domestic Hot Water 132
OutPort_3006565_0 | SOURCE | PIPE | DOMESTICHOTWATER | Group: Domestic Hot Water 132
OutPort_3006560_5 | SOURCE | PIPE | DOMESTICHOTWATER
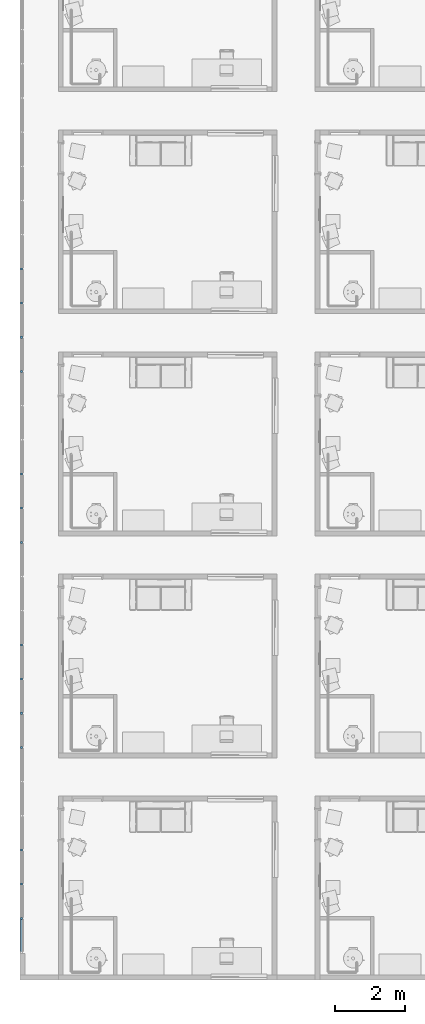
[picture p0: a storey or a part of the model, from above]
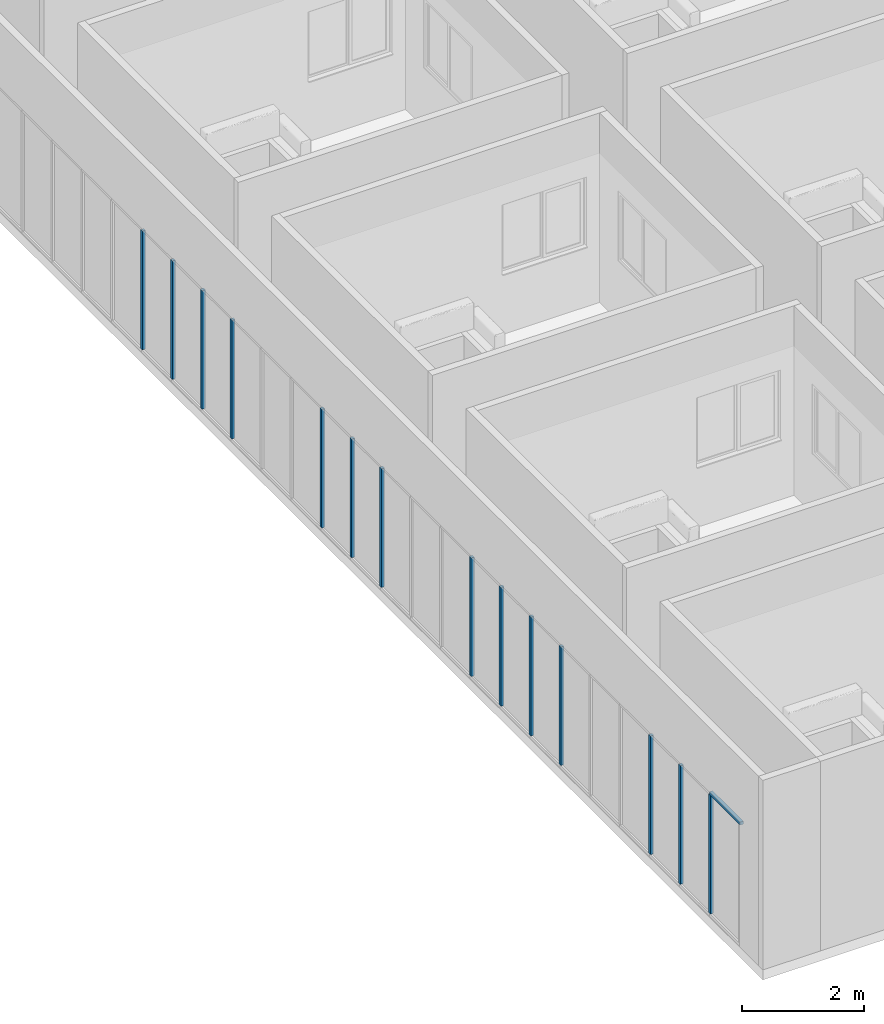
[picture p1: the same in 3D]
Properties of the parts of a building model (IFC4), part 4 of 14

# IfcDistributionPort (2240)
Name | FlowDirection | PredefinedType | SystemType
InPort_3006560_6 | SINK | PIPE | DOMESTICCOLDWATER
OutPort_3006560_7 | SOURCE | DUCT | EXHAUST
InPort_3006560_8 | SINK | PIPE | USERDEFINED
InPort_3006579_1 | SINK | PIPE | DOMESTICHOTWATER | Group: Domestic Hot Water 132
OutPort_3006600_5 | SOURCE | DUCT | VENTILATION
InPort_3006610_4 | SINK | PIPE | DOMESTICHOTWATER | Group: Domestic Hot Water 136
OutPort_3006615_0 | SOURCE | PIPE | DOMESTICHOTWATER | Group: Domestic Hot Water 136
OutPort_3006610_5 | SOURCE | PIPE | DOMESTICHOTWATER
InPort_3006610_6 | SINK | PIPE | DOMESTICCOLDWATER
OutPort_3006610_7 | SOURCE | DUCT | EXHAUST
InPort_3006610_8 | SINK | PIPE | USERDEFINED
InPort_3006629_1 | SINK | PIPE | DOMESTICHOTWATER | Group: Domestic Hot Water 136
OutPort_3006646_5 | SOURCE | DUCT | VENTILATION
InPort_3006656_4 | SINK | PIPE | DOMESTICHOTWATER | Group: Domestic Hot Water 140
OutPort_3006661_0 | SOURCE | PIPE | DOMESTICHOTWATER | Group: Domestic Hot Water 140
OutPort_3006656_5 | SOURCE | PIPE | DOMESTICHOTWATER
InPort_3006656_6 | SINK | PIPE | DOMESTICCOLDWATER
OutPort_3006656_7 | SOURCE | DUCT | EXHAUST
InPort_3006656_8 | SINK | PIPE | USERDEFINED
InPort_3006675_1 | SINK | PIPE | DOMESTICHOTWATER | Group: Domestic Hot Water 140
OutPort_3006692_5 | SOURCE | DUCT | VENTILATION
InPort_3006702_4 | SINK | PIPE | DOMESTICHOTWATER | Group: Domestic Hot Water 142
OutPort_3006707_0 | SOURCE | PIPE | DOMESTICHOTWATER | Group: Domestic Hot Water 142
OutPort_3006702_5 | SOURCE | PIPE | DOMESTICHOTWATER
InPort_3006702_6 | SINK | PIPE | DOMESTICCOLDWATER
OutPort_3006702_7 | SOURCE | DUCT | EXHAUST
InPort_3006702_8 | SINK | PIPE | USERDEFINED
InPort_3006721_1 | SINK | PIPE | DOMESTICHOTWATER | Group: Domestic Hot Water 142
OutPort_3006738_5 | SOURCE | DUCT | VENTILATION
InPort_3006748_4 | SINK | PIPE | DOMESTICHOTWATER | Group: Domestic Hot Water 144
OutPort_3006753_0 | SOURCE | PIPE | DOMESTICHOTWATER | Group: Domestic Hot Water 144
OutPort_3006748_5 | SOURCE | PIPE | DOMESTICHOTWATER
InPort_3006748_6 | SINK | PIPE | DOMESTICCOLDWATER
OutPort_3006748_7 | SOURCE | DUCT | EXHAUST
InPort_3006748_8 | SINK | PIPE | USERDEFINED
InPort_3006767_1 | SINK | PIPE | DOMESTICHOTWATER | Group: Domestic Hot Water 144
OutPort_3006784_5 | SOURCE | DUCT | VENTILATION
InPort_3006794_4 | SINK | PIPE | DOMESTICHOTWATER | Group: Domestic Hot Water 146
OutPort_3006799_0 | SOURCE | PIPE | DOMESTICHOTWATER | Group: Domestic Hot Water 146
OutPort_3006794_5 | SOURCE | PIPE | DOMESTICHOTWATER
InPort_3006794_6 | SINK | PIPE | DOMESTICCOLDWATER
OutPort_3006794_7 | SOURCE | DUCT | EXHAUST
InPort_3006794_8 | SINK | PIPE | USERDEFINED
InPort_3006813_1 | SINK | PIPE | DOMESTICHOTWATER | Group: Domestic Hot Water 146
OutPort_3006831_5 | SOURCE | DUCT | VENTILATION
InPort_3006841_4 | SINK | PIPE | DOMESTICHOTWATER | Group: Domestic Hot Water 148
OutPort_3006846_0 | SOURCE | PIPE | DOMESTICHOTWATER | Group: Domestic Hot Water 148
OutPort_3006841_5 | SOURCE | PIPE | DOMESTICHOTWATER
InPort_3006841_6 | SINK | PIPE | DOMESTICCOLDWATER
OutPort_3006841_7 | SOURCE | DUCT | EXHAUST
InPort_3006841_8 | SINK | PIPE | USERDEFINED
InPort_3006860_1 | SINK | PIPE | DOMESTICHOTWATER | Group: Domestic Hot Water 148
OutPort_3006877_5 | SOURCE | DUCT | VENTILATION
InPort_3006887_4 | SINK | PIPE | DOMESTICHOTWATER | Group: Domestic Hot Water 150
OutPort_3006892_0 | SOURCE | PIPE | DOMESTICHOTWATER | Group: Domestic Hot Water 150
OutPort_3006887_5 | SOURCE | PIPE | DOMESTICHOTWATER
InPort_3006887_6 | SINK | PIPE | DOMESTICCOLDWATER
OutPort_3006887_7 | SOURCE | DUCT | EXHAUST
InPort_3006887_8 | SINK | PIPE | USERDEFINED
InPort_3006906_1 | SINK | PIPE | DOMESTICHOTWATER | Group: Domestic Hot Water 150
OutPort_3006927_5 | SOURCE | DUCT | VENTILATION
InPort_3006937_4 | SINK | PIPE | DOMESTICHOTWATER | Group: Domestic Hot Water 152
OutPort_3006942_0 | SOURCE | PIPE | DOMESTICHOTWATER | Group: Domestic Hot Water 152
OutPort_3006937_5 | SOURCE | PIPE | DOMESTICHOTWATER
InPort_3006937_6 | SINK | PIPE | DOMESTICCOLDWATER
OutPort_3006937_7 | SOURCE | DUCT | EXHAUST
InPort_3006937_8 | SINK | PIPE | USERDEFINED
InPort_3006956_1 | SINK | PIPE | DOMESTICHOTWATER | Group: Domestic Hot Water 152
OutPort_3006973_5 | SOURCE | DUCT | VENTILATION
InPort_3006983_4 | SINK | PIPE | DOMESTICHOTWATER | Group: Domestic Hot Water 154
OutPort_3006988_0 | SOURCE | PIPE | DOMESTICHOTWATER | Group: Domestic Hot Water 154
OutPort_3006983_5 | SOURCE | PIPE | DOMESTICHOTWATER
InPort_3006983_6 | SINK | PIPE | DOMESTICCOLDWATER
OutPort_3006983_7 | SOURCE | DUCT | EXHAUST
InPort_3006983_8 | SINK | PIPE | USERDEFINED
InPort_3007002_1 | SINK | PIPE | DOMESTICHOTWATER | Group: Domestic Hot Water 154
OutPort_3007019_5 | SOURCE | DUCT | VENTILATION
InPort_3007029_4 | SINK | PIPE | DOMESTICHOTWATER | Group: Domestic Hot Water 156
OutPort_3007034_0 | SOURCE | PIPE | DOMESTICHOTWATER | Group: Domestic Hot Water 156
OutPort_3007029_5 | SOURCE | PIPE | DOMESTICHOTWATER
InPort_3007029_6 | SINK | PIPE | DOMESTICCOLDWATER
OutPort_3007029_7 | SOURCE | DUCT | EXHAUST
InPort_3007029_8 | SINK | PIPE | USERDEFINED
InPort_3007048_1 | SINK | PIPE | DOMESTICHOTWATER | Group: Domestic Hot Water 156
OutPort_3007065_5 | SOURCE | DUCT | VENTILATION
InPort_3007075_4 | SINK | PIPE | DOMESTICHOTWATER | Group: Domestic Hot Water 158
OutPort_3007080_0 | SOURCE | PIPE | DOMESTICHOTWATER | Group: Domestic Hot Water 158
OutPort_3007075_5 | SOURCE | PIPE | DOMESTICHOTWATER
InPort_3007075_6 | SINK | PIPE | DOMESTICCOLDWATER
OutPort_3007075_7 | SOURCE | DUCT | EXHAUST
InPort_3007075_8 | SINK | PIPE | USERDEFINED
InPort_3007094_1 | SINK | PIPE | DOMESTICHOTWATER | Group: Domestic Hot Water 158
OutPort_3007111_5 | SOURCE | DUCT | VENTILATION
InPort_3007121_4 | SINK | PIPE | DOMESTICHOTWATER | Group: Domestic Hot Water 160
OutPort_3007126_0 | SOURCE | PIPE | DOMESTICHOTWATER | Group: Domestic Hot Water 160
OutPort_3007121_5 | SOURCE | PIPE | DOMESTICHOTWATER
InPort_3007121_6 | SINK | PIPE | DOMESTICCOLDWATER
OutPort_3007121_7 | SOURCE | DUCT | EXHAUST
InPort_3007121_8 | SINK | PIPE | USERDEFINED
InPort_3007140_1 | SINK | PIPE | DOMESTICHOTWATER | Group: Domestic Hot Water 160
OutPort_3007158_5 | SOURCE | DUCT | VENTILATION
InPort_3007168_4 | SINK | PIPE | DOMESTICHOTWATER | Group: Domestic Hot Water 162
OutPort_3007173_0 | SOURCE | PIPE | DOMESTICHOTWATER | Group: Domestic Hot Water 162
OutPort_3007168_5 | SOURCE | PIPE | DOMESTICHOTWATER
InPort_3007168_6 | SINK | PIPE | DOMESTICCOLDWATER
OutPort_3007168_7 | SOURCE | DUCT | EXHAUST
InPort_3007168_8 | SINK | PIPE | USERDEFINED
InPort_3007187_1 | SINK | PIPE | DOMESTICHOTWATER | Group: Domestic Hot Water 162
OutPort_3007204_5 | SOURCE | DUCT | VENTILATION
InPort_3007214_4 | SINK | PIPE | DOMESTICHOTWATER | Group: Domestic Hot Water 164
OutPort_3007219_0 | SOURCE | PIPE | DOMESTICHOTWATER | Group: Domestic Hot Water 164
OutPort_3007214_5 | SOURCE | PIPE | DOMESTICHOTWATER
InPort_3007214_6 | SINK | PIPE | DOMESTICCOLDWATER
OutPort_3007214_7 | SOURCE | DUCT | EXHAUST
InPort_3007214_8 | SINK | PIPE | USERDEFINED
InPort_3007233_1 | SINK | PIPE | DOMESTICHOTWATER | Group: Domestic Hot Water 164
OutPort_3007254_5 | SOURCE | DUCT | VENTILATION
InPort_3007264_4 | SINK | PIPE | DOMESTICHOTWATER | Group: Domestic Hot Water 166
OutPort_3007269_0 | SOURCE | PIPE | DOMESTICHOTWATER | Group: Domestic Hot Water 166
OutPort_3007264_5 | SOURCE | PIPE | DOMESTICHOTWATER
InPort_3007264_6 | SINK | PIPE | DOMESTICCOLDWATER
OutPort_3007264_7 | SOURCE | DUCT | EXHAUST
InPort_3007264_8 | SINK | PIPE | USERDEFINED
InPort_3007283_1 | SINK | PIPE | DOMESTICHOTWATER | Group: Domestic Hot Water 166
OutPort_3007300_5 | SOURCE | DUCT | VENTILATION
InPort_3007310_4 | SINK | PIPE | DOMESTICHOTWATER | Group: Domestic Hot Water 168
OutPort_3007315_0 | SOURCE | PIPE | DOMESTICHOTWATER | Group: Domestic Hot Water 168
OutPort_3007310_5 | SOURCE | PIPE | DOMESTICHOTWATER
InPort_3007310_6 | SINK | PIPE | DOMESTICCOLDWATER
OutPort_3007310_7 | SOURCE | DUCT | EXHAUST
InPort_3007310_8 | SINK | PIPE | USERDEFINED
InPort_3007329_1 | SINK | PIPE | DOMESTICHOTWATER | Group: Domestic Hot Water 168
OutPort_3007346_5 | SOURCE | DUCT | VENTILATION
InPort_3007356_4 | SINK | PIPE | DOMESTICHOTWATER | Group: Domestic Hot Water 170
OutPort_3007361_0 | SOURCE | PIPE | DOMESTICHOTWATER | Group: Domestic Hot Water 170
OutPort_3007356_5 | SOURCE | PIPE | DOMESTICHOTWATER
InPort_3007356_6 | SINK | PIPE | DOMESTICCOLDWATER
OutPort_3007356_7 | SOURCE | DUCT | EXHAUST
InPort_3007356_8 | SINK | PIPE | USERDEFINED
InPort_3007375_1 | SINK | PIPE | DOMESTICHOTWATER | Group: Domestic Hot Water 170
OutPort_3007392_5 | SOURCE | DUCT | VENTILATION
InPort_3007402_4 | SINK | PIPE | DOMESTICHOTWATER | Group: Domestic Hot Water 172
OutPort_3007407_0 | SOURCE | PIPE | DOMESTICHOTWATER | Group: Domestic Hot Water 172
OutPort_3007402_5 | SOURCE | PIPE | DOMESTICHOTWATER
InPort_3007402_6 | SINK | PIPE | DOMESTICCOLDWATER
OutPort_3007402_7 | SOURCE | DUCT | EXHAUST
InPort_3007402_8 | SINK | PIPE | USERDEFINED
InPort_3007421_1 | SINK | PIPE | DOMESTICHOTWATER | Group: Domestic Hot Water 172
OutPort_3007438_5 | SOURCE | DUCT | VENTILATION
InPort_3007448_4 | SINK | PIPE | DOMESTICHOTWATER | Group: Domestic Hot Water 174
OutPort_3007453_0 | SOURCE | PIPE | DOMESTICHOTWATER | Group: Domestic Hot Water 174
OutPort_3007448_5 | SOURCE | PIPE | DOMESTICHOTWATER
InPort_3007448_6 | SINK | PIPE | DOMESTICCOLDWATER
OutPort_3007448_7 | SOURCE | DUCT | EXHAUST
InPort_3007448_8 | SINK | PIPE | USERDEFINED
InPort_3007467_1 | SINK | PIPE | DOMESTICHOTWATER | Group: Domestic Hot Water 174
OutPort_3008045_5 | SOURCE | DUCT | VENTILATION
InPort_3008055_4 | SINK | PIPE | DOMESTICHOTWATER | Group: Domestic Hot Water 23
OutPort_3008060_0 | SOURCE | PIPE | DOMESTICHOTWATER | Group: Domestic Hot Water 23
OutPort_3008055_5 | SOURCE | PIPE | DOMESTICHOTWATER
InPort_3008055_6 | SINK | PIPE | DOMESTICCOLDWATER
OutPort_3008055_7 | SOURCE | DUCT | EXHAUST
InPort_3008055_8 | SINK | PIPE | USERDEFINED
InPort_3008074_1 | SINK | PIPE | DOMESTICHOTWATER | Group: Domestic Hot Water 23
OutPort_3008091_5 | SOURCE | DUCT | VENTILATION
InPort_3008101_4 | SINK | PIPE | DOMESTICHOTWATER | Group: Domestic Hot Water 55
OutPort_3008106_0 | SOURCE | PIPE | DOMESTICHOTWATER | Group: Domestic Hot Water 55
OutPort_3008101_5 | SOURCE | PIPE | DOMESTICHOTWATER
InPort_3008101_6 | SINK | PIPE | DOMESTICCOLDWATER
OutPort_3008101_7 | SOURCE | DUCT | EXHAUST
InPort_3008101_8 | SINK | PIPE | USERDEFINED
InPort_3008120_1 | SINK | PIPE | DOMESTICHOTWATER | Group: Domestic Hot Water 55
OutPort_3008141_5 | SOURCE | DUCT | VENTILATION
InPort_3008151_4 | SINK | PIPE | DOMESTICHOTWATER | Group: Domestic Hot Water 75
OutPort_3008156_0 | SOURCE | PIPE | DOMESTICHOTWATER | Group: Domestic Hot Water 75
OutPort_3008151_5 | SOURCE | PIPE | DOMESTICHOTWATER
InPort_3008151_6 | SINK | PIPE | DOMESTICCOLDWATER
OutPort_3008151_7 | SOURCE | DUCT | EXHAUST
InPort_3008151_8 | SINK | PIPE | USERDEFINED
InPort_3008170_1 | SINK | PIPE | DOMESTICHOTWATER | Group: Domestic Hot Water 75
OutPort_3008187_5 | SOURCE | DUCT | VENTILATION
InPort_3008197_4 | SINK | PIPE | DOMESTICHOTWATER | Group: Domestic Hot Water 91
OutPort_3008202_0 | SOURCE | PIPE | DOMESTICHOTWATER | Group: Domestic Hot Water 91
OutPort_3008197_5 | SOURCE | PIPE | DOMESTICHOTWATER
InPort_3008197_6 | SINK | PIPE | DOMESTICCOLDWATER
OutPort_3008197_7 | SOURCE | DUCT | EXHAUST
InPort_3008197_8 | SINK | PIPE | USERDEFINED
InPort_3008216_1 | SINK | PIPE | DOMESTICHOTWATER | Group: Domestic Hot Water 91
OutPort_3008233_5 | SOURCE | DUCT | VENTILATION
InPort_3008243_4 | SINK | PIPE | DOMESTICHOTWATER | Group: Domestic Hot Water 106
OutPort_3008248_0 | SOURCE | PIPE | DOMESTICHOTWATER | Group: Domestic Hot Water 106
OutPort_3008243_5 | SOURCE | PIPE | DOMESTICHOTWATER
InPort_3008243_6 | SINK | PIPE | DOMESTICCOLDWATER
OutPort_3008243_7 | SOURCE | DUCT | EXHAUST
InPort_3008243_8 | SINK | PIPE | USERDEFINED
InPort_3008262_1 | SINK | PIPE | DOMESTICHOTWATER | Group: Domestic Hot Water 106
OutPort_3008279_5 | SOURCE | DUCT | VENTILATION
InPort_3008289_4 | SINK | PIPE | DOMESTICHOTWATER | Group: Domestic Hot Water 114
OutPort_3008294_0 | SOURCE | PIPE | DOMESTICHOTWATER | Group: Domestic Hot Water 114
OutPort_3008289_5 | SOURCE | PIPE | DOMESTICHOTWATER
InPort_3008289_6 | SINK | PIPE | DOMESTICCOLDWATER
OutPort_3008289_7 | SOURCE | DUCT | EXHAUST
InPort_3008289_8 | SINK | PIPE | USERDEFINED
InPort_3008308_1 | SINK | PIPE | DOMESTICHOTWATER | Group: Domestic Hot Water 114
OutPort_3008325_5 | SOURCE | DUCT | VENTILATION
InPort_3008335_4 | SINK | PIPE | DOMESTICHOTWATER | Group: Domestic Hot Water 122
OutPort_3008340_0 | SOURCE | PIPE | DOMESTICHOTWATER | Group: Domestic Hot Water 122
OutPort_3008335_5 | SOURCE | PIPE | DOMESTICHOTWATER
InPort_3008335_6 | SINK | PIPE | DOMESTICCOLDWATER
OutPort_3008335_7 | SOURCE | DUCT | EXHAUST
InPort_3008335_8 | SINK | PIPE | USERDEFINED
InPort_3008354_1 | SINK | PIPE | DOMESTICHOTWATER | Group: Domestic Hot Water 122
OutPort_3008372_5 | SOURCE | DUCT | VENTILATION
InPort_3008382_4 | SINK | PIPE | DOMESTICHOTWATER | Group: Domestic Hot Water 130
OutPort_3008387_0 | SOURCE | PIPE | DOMESTICHOTWATER | Group: Domestic Hot Water 130
OutPort_3008382_5 | SOURCE | PIPE | DOMESTICHOTWATER
InPort_3008382_6 | SINK | PIPE | DOMESTICCOLDWATER
OutPort_3008382_7 | SOURCE | DUCT | EXHAUST
InPort_3008382_8 | SINK | PIPE | USERDEFINED
InPort_3008401_1 | SINK | PIPE | DOMESTICHOTWATER | Group: Domestic Hot Water 130
OutPort_3008418_5 | SOURCE | DUCT | VENTILATION
InPort_3008428_4 | SINK | PIPE | DOMESTICHOTWATER | Group: Domestic Hot Water 138
OutPort_3008433_0 | SOURCE | PIPE | DOMESTICHOTWATER | Group: Domestic Hot Water 138
OutPort_3008428_5 | SOURCE | PIPE | DOMESTICHOTWATER
InPort_3008428_6 | SINK | PIPE | DOMESTICCOLDWATER
OutPort_3008428_7 | SOURCE | DUCT | EXHAUST
InPort_3008428_8 | SINK | PIPE | USERDEFINED
InPort_3008447_1 | SINK | PIPE | DOMESTICHOTWATER | Group: Domestic Hot Water 138
OutPort_3008468_5 | SOURCE | DUCT | VENTILATION
InPort_3008478_4 | SINK | PIPE | DOMESTICHOTWATER | Group: Domestic Hot Water 143
OutPort_3008483_0 | SOURCE | PIPE | DOMESTICHOTWATER | Group: Domestic Hot Water 143
OutPort_3008478_5 | SOURCE | PIPE | DOMESTICHOTWATER
InPort_3008478_6 | SINK | PIPE | DOMESTICCOLDWATER
OutPort_3008478_7 | SOURCE | DUCT | EXHAUST
InPort_3008478_8 | SINK | PIPE | USERDEFINED
InPort_3008497_1 | SINK | PIPE | DOMESTICHOTWATER | Group: Domestic Hot Water 143
OutPort_3008514_5 | SOURCE | DUCT | VENTILATION
InPort_3008524_4 | SINK | PIPE | DOMESTICHOTWATER | Group: Domestic Hot Water 147
OutPort_3008529_0 | SOURCE | PIPE | DOMESTICHOTWATER | Group: Domestic Hot Water 147
OutPort_3008524_5 | SOURCE | PIPE | DOMESTICHOTWATER
InPort_3008524_6 | SINK | PIPE | DOMESTICCOLDWATER
OutPort_3008524_7 | SOURCE | DUCT | EXHAUST
InPort_3008524_8 | SINK | PIPE | USERDEFINED
InPort_3008543_1 | SINK | PIPE | DOMESTICHOTWATER | Group: Domestic Hot Water 147
OutPort_3008560_5 | SOURCE | DUCT | VENTILATION
InPort_3008570_4 | SINK | PIPE | DOMESTICHOTWATER | Group: Domestic Hot Water 151
OutPort_3008575_0 | SOURCE | PIPE | DOMESTICHOTWATER | Group: Domestic Hot Water 151
OutPort_3008570_5 | SOURCE | PIPE | DOMESTICHOTWATER
InPort_3008570_6 | SINK | PIPE | DOMESTICCOLDWATER
OutPort_3008570_7 | SOURCE | DUCT | EXHAUST
InPort_3008570_8 | SINK | PIPE | USERDEFINED
InPort_3008589_1 | SINK | PIPE | DOMESTICHOTWATER | Group: Domestic Hot Water 151
OutPort_3008606_5 | SOURCE | DUCT | VENTILATION
InPort_3008616_4 | SINK | PIPE | DOMESTICHOTWATER | Group: Domestic Hot Water 155
OutPort_3008621_0 | SOURCE | PIPE | DOMESTICHOTWATER | Group: Domestic Hot Water 155
OutPort_3008616_5 | SOURCE | PIPE | DOMESTICHOTWATER
InPort_3008616_6 | SINK | PIPE | DOMESTICCOLDWATER
OutPort_3008616_7 | SOURCE | DUCT | EXHAUST
InPort_3008616_8 | SINK | PIPE | USERDEFINED
InPort_3008635_1 | SINK | PIPE | DOMESTICHOTWATER | Group: Domestic Hot Water 155
OutPort_3008652_5 | SOURCE | DUCT | VENTILATION
InPort_3008662_4 | SINK | PIPE | DOMESTICHOTWATER | Group: Domestic Hot Water 159
OutPort_3008667_0 | SOURCE | PIPE | DOMESTICHOTWATER | Group: Domestic Hot Water 159
OutPort_3008662_5 | SOURCE | PIPE | DOMESTICHOTWATER
InPort_3008662_6 | SINK | PIPE | DOMESTICCOLDWATER
OutPort_3008662_7 | SOURCE | DUCT | EXHAUST
InPort_3008662_8 | SINK | PIPE | USERDEFINED
InPort_3008681_1 | SINK | PIPE | DOMESTICHOTWATER | Group: Domestic Hot Water 159
OutPort_3008699_5 | SOURCE | DUCT | VENTILATION
InPort_3008709_4 | SINK | PIPE | DOMESTICHOTWATER | Group: Domestic Hot Water 163
OutPort_3008714_0 | SOURCE | PIPE | DOMESTICHOTWATER | Group: Domestic Hot Water 163
OutPort_3008709_5 | SOURCE | PIPE | DOMESTICHOTWATER
InPort_3008709_6 | SINK | PIPE | DOMESTICCOLDWATER
OutPort_3008709_7 | SOURCE | DUCT | EXHAUST
InPort_3008709_8 | SINK | PIPE | USERDEFINED
InPort_3008728_1 | SINK | PIPE | DOMESTICHOTWATER | Group: Domestic Hot Water 163
OutPort_3008745_5 | SOURCE | DUCT | VENTILATION
InPort_3008755_4 | SINK | PIPE | DOMESTICHOTWATER | Group: Domestic Hot Water 167
OutPort_3008760_0 | SOURCE | PIPE | DOMESTICHOTWATER | Group: Domestic Hot Water 167
OutPort_3008755_5 | SOURCE | PIPE | DOMESTICHOTWATER
InPort_3008755_6 | SINK | PIPE | DOMESTICCOLDWATER
OutPort_3008755_7 | SOURCE | DUCT | EXHAUST
InPort_3008755_8 | SINK | PIPE | USERDEFINED
InPort_3008774_1 | SINK | PIPE | DOMESTICHOTWATER | Group: Domestic Hot Water 167
OutPort_3008795_5 | SOURCE | DUCT | VENTILATION
InPort_3008805_4 | SINK | PIPE | DOMESTICHOTWATER | Group: Domestic Hot Water 171
OutPort_3008810_0 | SOURCE | PIPE | DOMESTICHOTWATER | Group: Domestic Hot Water 171
OutPort_3008805_5 | SOURCE | PIPE | DOMESTICHOTWATER
InPort_3008805_6 | SINK | PIPE | DOMESTICCOLDWATER
OutPort_3008805_7 | SOURCE | DUCT | EXHAUST
InPort_3008805_8 | SINK | PIPE | USERDEFINED
InPort_3008824_1 | SINK | PIPE | DOMESTICHOTWATER | Group: Domestic Hot Water 171
OutPort_3008841_5 | SOURCE | DUCT | VENTILATION
InPort_3008851_4 | SINK | PIPE | DOMESTICHOTWATER | Group: Domestic Hot Water 175
OutPort_3008856_0 | SOURCE | PIPE | DOMESTICHOTWATER | Group: Domestic Hot Water 175
OutPort_3008851_5 | SOURCE | PIPE | DOMESTICHOTWATER
InPort_3008851_6 | SINK | PIPE | DOMESTICCOLDWATER
OutPort_3008851_7 | SOURCE | DUCT | EXHAUST
InPort_3008851_8 | SINK | PIPE | USERDEFINED
InPort_3008870_1 | SINK | PIPE | DOMESTICHOTWATER | Group: Domestic Hot Water 175
OutPort_3008887_5 | SOURCE | DUCT | VENTILATION
InPort_3008897_4 | SINK | PIPE | DOMESTICHOTWATER | Group: Domestic Hot Water 177
OutPort_3008902_0 | SOURCE | PIPE | DOMESTICHOTWATER | Group: Domestic Hot Water 177
OutPort_3008897_5 | SOURCE | PIPE | DOMESTICHOTWATER
InPort_3008897_6 | SINK | PIPE | DOMESTICCOLDWATER
OutPort_3008897_7 | SOURCE | DUCT | EXHAUST
InPort_3008897_8 | SINK | PIPE | USERDEFINED
InPort_3008916_1 | SINK | PIPE | DOMESTICHOTWATER | Group: Domestic Hot Water 177
OutPort_3008933_5 | SOURCE | DUCT | VENTILATION
InPort_3008943_4 | SINK | PIPE | DOMESTICHOTWATER | Group: Domestic Hot Water 179
OutPort_3008948_0 | SOURCE | PIPE | DOMESTICHOTWATER | Group: Domestic Hot Water 179
OutPort_3008943_5 | SOURCE | PIPE | DOMESTICHOTWATER
InPort_3008943_6 | SINK | PIPE | DOMESTICCOLDWATER
OutPort_3008943_7 | SOURCE | DUCT | EXHAUST
InPort_3008943_8 | SINK | PIPE | USERDEFINED
InPort_3008962_1 | SINK | PIPE | DOMESTICHOTWATER | Group: Domestic Hot Water 179
OutPort_3008979_5 | SOURCE | DUCT | VENTILATION
InPort_3008989_4 | SINK | PIPE | DOMESTICHOTWATER | Group: Domestic Hot Water 181
OutPort_3008994_0 | SOURCE | PIPE | DOMESTICHOTWATER | Group: Domestic Hot Water 181
OutPort_3008989_5 | SOURCE | PIPE | DOMESTICHOTWATER
InPort_3008989_6 | SINK | PIPE | DOMESTICCOLDWATER
OutPort_3008989_7 | SOURCE | DUCT | EXHAUST
InPort_3008989_8 | SINK | PIPE | USERDEFINED
InPort_3009008_1 | SINK | PIPE | DOMESTICHOTWATER | Group: Domestic Hot Water 181
OutPort_3009026_5 | SOURCE | DUCT | VENTILATION
InPort_3009036_4 | SINK | PIPE | DOMESTICHOTWATER | Group: Domestic Hot Water 183
OutPort_3009041_0 | SOURCE | PIPE | DOMESTICHOTWATER | Group: Domestic Hot Water 183
OutPort_3009036_5 | SOURCE | PIPE | DOMESTICHOTWATER
InPort_3009036_6 | SINK | PIPE | DOMESTICCOLDWATER
OutPort_3009036_7 | SOURCE | DUCT | EXHAUST
InPort_3009036_8 | SINK | PIPE | USERDEFINED
InPort_3009055_1 | SINK | PIPE | DOMESTICHOTWATER | Group: Domestic Hot Water 183
OutPort_3009072_5 | SOURCE | DUCT | VENTILATION
InPort_3009082_4 | SINK | PIPE | DOMESTICHOTWATER | Group: Domestic Hot Water 185
OutPort_3009087_0 | SOURCE | PIPE | DOMESTICHOTWATER | Group: Domestic Hot Water 185
OutPort_3009082_5 | SOURCE | PIPE | DOMESTICHOTWATER
InPort_3009082_6 | SINK | PIPE | DOMESTICCOLDWATER
OutPort_3009082_7 | SOURCE | DUCT | EXHAUST
InPort_3009082_8 | SINK | PIPE | USERDEFINED
InPort_3009101_1 | SINK | PIPE | DOMESTICHOTWATER | Group: Domestic Hot Water 185
OutPort_3009122_5 | SOURCE | DUCT | VENTILATION
InPort_3009132_4 | SINK | PIPE | DOMESTICHOTWATER | Group: Domestic Hot Water 187
OutPort_3009137_0 | SOURCE | PIPE | DOMESTICHOTWATER | Group: Domestic Hot Water 187
OutPort_3009132_5 | SOURCE | PIPE | DOMESTICHOTWATER
InPort_3009132_6 | SINK | PIPE | DOMESTICCOLDWATER
OutPort_3009132_7 | SOURCE | DUCT | EXHAUST
InPort_3009132_8 | SINK | PIPE | USERDEFINED
InPort_3009151_1 | SINK | PIPE | DOMESTICHOTWATER | Group: Domestic Hot Water 187
OutPort_3009168_5 | SOURCE | DUCT | VENTILATION
InPort_3009178_4 | SINK | PIPE | DOMESTICHOTWATER | Group: Domestic Hot Water 189
OutPort_3009183_0 | SOURCE | PIPE | DOMESTICHOTWATER | Group: Domestic Hot Water 189
OutPort_3009178_5 | SOURCE | PIPE | DOMESTICHOTWATER
InPort_3009178_6 | SINK | PIPE | DOMESTICCOLDWATER
OutPort_3009178_7 | SOURCE | DUCT | EXHAUST
InPort_3009178_8 | SINK | PIPE | USERDEFINED
InPort_3009197_1 | SINK | PIPE | DOMESTICHOTWATER | Group: Domestic Hot Water 189
OutPort_3009214_5 | SOURCE | DUCT | VENTILATION
InPort_3009224_4 | SINK | PIPE | DOMESTICHOTWATER | Group: Domestic Hot Water 191
OutPort_3009229_0 | SOURCE | PIPE | DOMESTICHOTWATER | Group: Domestic Hot Water 191
OutPort_3009224_5 | SOURCE | PIPE | DOMESTICHOTWATER
InPort_3009224_6 | SINK | PIPE | DOMESTICCOLDWATER
OutPort_3009224_7 | SOURCE | DUCT | EXHAUST
InPort_3009224_8 | SINK | PIPE | USERDEFINED
InPort_3009243_1 | SINK | PIPE | DOMESTICHOTWATER | Group: Domestic Hot Water 191
OutPort_3009260_5 | SOURCE | DUCT | VENTILATION
InPort_3009270_4 | SINK | PIPE | DOMESTICHOTWATER | Group: Domestic Hot Water 193
OutPort_3009275_0 | SOURCE | PIPE | DOMESTICHOTWATER | Group: Domestic Hot Water 193
OutPort_3009270_5 | SOURCE | PIPE | DOMESTICHOTWATER
InPort_3009270_6 | SINK | PIPE | DOMESTICCOLDWATER
OutPort_3009270_7 | SOURCE | DUCT | EXHAUST
InPort_3009270_8 | SINK | PIPE | USERDEFINED
InPort_3009289_1 | SINK | PIPE | DOMESTICHOTWATER | Group: Domestic Hot Water 193
OutPort_3009306_5 | SOURCE | DUCT | VENTILATION
InPort_3009316_4 | SINK | PIPE | DOMESTICHOTWATER | Group: Domestic Hot Water 195
OutPort_3009321_0 | SOURCE | PIPE | DOMESTICHOTWATER | Group: Domestic Hot Water 195
OutPort_3009316_5 | SOURCE | PIPE | DOMESTICHOTWATER
InPort_3009316_6 | SINK | PIPE | DOMESTICCOLDWATER
OutPort_3009316_7 | SOURCE | DUCT | EXHAUST
InPort_3009316_8 | SINK | PIPE | USERDEFINED
InPort_3009335_1 | SINK | PIPE | DOMESTICHOTWATER | Group: Domestic Hot Water 195
OutPort_3009353_5 | SOURCE | DUCT | VENTILATION
InPort_3009363_4 | SINK | PIPE | DOMESTICHOTWATER | Group: Domestic Hot Water 197
OutPort_3009368_0 | SOURCE | PIPE | DOMESTICHOTWATER | Group: Domestic Hot Water 197
OutPort_3009363_5 | SOURCE | PIPE | DOMESTICHOTWATER
InPort_3009363_6 | SINK | PIPE | DOMESTICCOLDWATER
OutPort_3009363_7 | SOURCE | DUCT | EXHAUST
InPort_3009363_8 | SINK | PIPE | USERDEFINED
InPort_3009382_1 | SINK | PIPE | DOMESTICHOTWATER | Group: Domestic Hot Water 197
OutPort_3009399_5 | SOURCE | DUCT | VENTILATION
InPort_3009409_4 | SINK | PIPE | DOMESTICHOTWATER | Group: Domestic Hot Water 199
OutPort_3009414_0 | SOURCE | PIPE | DOMESTICHOTWATER | Group: Domestic Hot Water 199
OutPort_3009409_5 | SOURCE | PIPE | DOMESTICHOTWATER
InPort_3009409_6 | SINK | PIPE | DOMESTICCOLDWATER
OutPort_3009409_7 | SOURCE | DUCT | EXHAUST
InPort_3009409_8 | SINK | PIPE | USERDEFINED
InPort_3009428_1 | SINK | PIPE | DOMESTICHOTWATER | Group: Domestic Hot Water 199
OutPort_3009449_5 | SOURCE | DUCT | VENTILATION
InPort_3009459_4 | SINK | PIPE | DOMESTICHOTWATER | Group: Domestic Hot Water 201
OutPort_3009464_0 | SOURCE | PIPE | DOMESTICHOTWATER | Group: Domestic Hot Water 201
OutPort_3009459_5 | SOURCE | PIPE | DOMESTICHOTWATER
InPort_3009459_6 | SINK | PIPE | DOMESTICCOLDWATER
OutPort_3009459_7 | SOURCE | DUCT | EXHAUST
InPort_3009459_8 | SINK | PIPE | USERDEFINED
InPort_3009478_1 | SINK | PIPE | DOMESTICHOTWATER | Group: Domestic Hot Water 201
OutPort_3009495_5 | SOURCE | DUCT | VENTILATION
InPort_3009505_4 | SINK | PIPE | DOMESTICHOTWATER | Group: Domestic Hot Water 203
OutPort_3009510_0 | SOURCE | PIPE | DOMESTICHOTWATER | Group: Domestic Hot Water 203
OutPort_3009505_5 | SOURCE | PIPE | DOMESTICHOTWATER
InPort_3009505_6 | SINK | PIPE | DOMESTICCOLDWATER
OutPort_3009505_7 | SOURCE | DUCT | EXHAUST
InPort_3009505_8 | SINK | PIPE | USERDEFINED
InPort_3009524_1 | SINK | PIPE | DOMESTICHOTWATER | Group: Domestic Hot Water 203
OutPort_3009541_5 | SOURCE | DUCT | VENTILATION
InPort_3009551_4 | SINK | PIPE | DOMESTICHOTWATER | Group: Domestic Hot Water 205
OutPort_3009556_0 | SOURCE | PIPE | DOMESTICHOTWATER | Group: Domestic Hot Water 205
OutPort_3009551_5 | SOURCE | PIPE | DOMESTICHOTWATER
InPort_3009551_6 | SINK | PIPE | DOMESTICCOLDWATER
OutPort_3009551_7 | SOURCE | DUCT | EXHAUST
InPort_3009551_8 | SINK | PIPE | USERDEFINED
InPort_3009570_1 | SINK | PIPE | DOMESTICHOTWATER | Group: Domestic Hot Water 205
OutPort_3009587_5 | SOURCE | DUCT | VENTILATION
InPort_3009597_4 | SINK | PIPE | DOMESTICHOTWATER | Group: Domestic Hot Water 207
OutPort_3009602_0 | SOURCE | PIPE | DOMESTICHOTWATER | Group: Domestic Hot Water 207
OutPort_3009597_5 | SOURCE | PIPE | DOMESTICHOTWATER
InPort_3009597_6 | SINK | PIPE | DOMESTICCOLDWATER
OutPort_3009597_7 | SOURCE | DUCT | EXHAUST
InPort_3009597_8 | SINK | PIPE | USERDEFINED
InPort_3009616_1 | SINK | PIPE | DOMESTICHOTWATER | Group: Domestic Hot Water 207
OutPort_3009633_5 | SOURCE | DUCT | VENTILATION
InPort_3009643_4 | SINK | PIPE | DOMESTICHOTWATER | Group: Domestic Hot Water 209
OutPort_3009648_0 | SOURCE | PIPE | DOMESTICHOTWATER | Group: Domestic Hot Water 209
OutPort_3009643_5 | SOURCE | PIPE | DOMESTICHOTWATER
InPort_3009643_6 | SINK | PIPE | DOMESTICCOLDWATER
OutPort_3009643_7 | SOURCE | DUCT | EXHAUST
InPort_3009643_8 | SINK | PIPE | USERDEFINED
InPort_3009662_1 | SINK | PIPE | DOMESTICHOTWATER | Group: Domestic Hot Water 209
OutPort_3010240_5 | SOURCE | DUCT | VENTILATION
InPort_3010250_4 | SINK | PIPE | DOMESTICHOTWATER | Group: Domestic Hot Water 39
OutPort_3010255_0 | SOURCE | PIPE | DOMESTICHOTWATER | Group: Domestic Hot Water 39
OutPort_3010250_5 | SOURCE | PIPE | DOMESTICHOTWATER
InPort_3010250_6 | SINK | PIPE | DOMESTICCOLDWATER
OutPort_3010250_7 | SOURCE | DUCT | EXHAUST
InPort_3010250_8 | SINK | PIPE | USERDEFINED
InPort_3010269_1 | SINK | PIPE | DOMESTICHOTWATER | Group: Domestic Hot Water 39
OutPort_3010286_5 | SOURCE | DUCT | VENTILATION
InPort_3010296_4 | SINK | PIPE | DOMESTICHOTWATER | Group: Domestic Hot Water 83
OutPort_3010301_0 | SOURCE | PIPE | DOMESTICHOTWATER | Group: Domestic Hot Water 83
OutPort_3010296_5 | SOURCE | PIPE | DOMESTICHOTWATER
InPort_3010296_6 | SINK | PIPE | DOMESTICCOLDWATER
OutPort_3010296_7 | SOURCE | DUCT | EXHAUST
InPort_3010296_8 | SINK | PIPE | USERDEFINED
InPort_3010315_1 | SINK | PIPE | DOMESTICHOTWATER | Group: Domestic Hot Water 83
OutPort_3010336_5 | SOURCE | DUCT | VENTILATION
InPort_3010346_4 | SINK | PIPE | DOMESTICHOTWATER | Group: Domestic Hot Water 110
OutPort_3010351_0 | SOURCE | PIPE | DOMESTICHOTWATER | Group: Domestic Hot Water 110
OutPort_3010346_5 | SOURCE | PIPE | DOMESTICHOTWATER
InPort_3010346_6 | SINK | PIPE | DOMESTICCOLDWATER
OutPort_3010346_7 | SOURCE | DUCT | EXHAUST
InPort_3010346_8 | SINK | PIPE | USERDEFINED
InPort_3010365_1 | SINK | PIPE | DOMESTICHOTWATER | Group: Domestic Hot Water 110
OutPort_3010382_5 | SOURCE | DUCT | VENTILATION
InPort_3010392_4 | SINK | PIPE | DOMESTICHOTWATER | Group: Domestic Hot Water 126
OutPort_3010397_0 | SOURCE | PIPE | DOMESTICHOTWATER | Group: Domestic Hot Water 126
OutPort_3010392_5 | SOURCE | PIPE | DOMESTICHOTWATER
InPort_3010392_6 | SINK | PIPE | DOMESTICCOLDWATER
OutPort_3010392_7 | SOURCE | DUCT | EXHAUST
InPort_3010392_8 | SINK | PIPE | USERDEFINED
InPort_3010411_1 | SINK | PIPE | DOMESTICHOTWATER | Group: Domestic Hot Water 126
OutPort_3010428_5 | SOURCE | DUCT | VENTILATION
InPort_3010438_4 | SINK | PIPE | DOMESTICHOTWATER | Group: Domestic Hot Water 141
OutPort_3010443_0 | SOURCE | PIPE | DOMESTICHOTWATER | Group: Domestic Hot Water 141
OutPort_3010438_5 | SOURCE | PIPE | DOMESTICHOTWATER
InPort_3010438_6 | SINK | PIPE | DOMESTICCOLDWATER
OutPort_3010438_7 | SOURCE | DUCT | EXHAUST
InPort_3010438_8 | SINK | PIPE | USERDEFINED
InPort_3010457_1 | SINK | PIPE | DOMESTICHOTWATER | Group: Domestic Hot Water 141
OutPort_3010474_5 | SOURCE | DUCT | VENTILATION
InPort_3010484_4 | SINK | PIPE | DOMESTICHOTWATER | Group: Domestic Hot Water 149
OutPort_3010489_0 | SOURCE | PIPE | DOMESTICHOTWATER | Group: Domestic Hot Water 149
OutPort_3010484_5 | SOURCE | PIPE | DOMESTICHOTWATER
InPort_3010484_6 | SINK | PIPE | DOMESTICCOLDWATER
OutPort_3010484_7 | SOURCE | DUCT | EXHAUST
InPort_3010484_8 | SINK | PIPE | USERDEFINED
InPort_3010503_1 | SINK | PIPE | DOMESTICHOTWATER | Group: Domestic Hot Water 149
OutPort_3010520_5 | SOURCE | DUCT | VENTILATION
InPort_3010530_4 | SINK | PIPE | DOMESTICHOTWATER | Group: Domestic Hot Water 157
OutPort_3010535_0 | SOURCE | PIPE | DOMESTICHOTWATER | Group: Domestic Hot Water 157
OutPort_3010530_5 | SOURCE | PIPE | DOMESTICHOTWATER
InPort_3010530_6 | SINK | PIPE | DOMESTICCOLDWATER
OutPort_3010530_7 | SOURCE | DUCT | EXHAUST
InPort_3010530_8 | SINK | PIPE | USERDEFINED
InPort_3010549_1 | SINK | PIPE | DOMESTICHOTWATER | Group: Domestic Hot Water 157
OutPort_3010567_5 | SOURCE | DUCT | VENTILATION
InPort_3010577_4 | SINK | PIPE | DOMESTICHOTWATER | Group: Domestic Hot Water 165
OutPort_3010582_0 | SOURCE | PIPE | DOMESTICHOTWATER | Group: Domestic Hot Water 165
OutPort_3010577_5 | SOURCE | PIPE | DOMESTICHOTWATER
InPort_3010577_6 | SINK | PIPE | DOMESTICCOLDWATER
OutPort_3010577_7 | SOURCE | DUCT | EXHAUST
InPort_3010577_8 | SINK | PIPE | USERDEFINED
InPort_3010596_1 | SINK | PIPE | DOMESTICHOTWATER | Group: Domestic Hot Water 165
OutPort_3010613_5 | SOURCE | DUCT | VENTILATION
InPort_3010623_4 | SINK | PIPE | DOMESTICHOTWATER | Group: Domestic Hot Water 173
OutPort_3010628_0 | SOURCE | PIPE | DOMESTICHOTWATER | Group: Domestic Hot Water 173
OutPort_3010623_5 | SOURCE | PIPE | DOMESTICHOTWATER
InPort_3010623_6 | SINK | PIPE | DOMESTICCOLDWATER
OutPort_3010623_7 | SOURCE | DUCT | EXHAUST
InPort_3010623_8 | SINK | PIPE | USERDEFINED
InPort_3010642_1 | SINK | PIPE | DOMESTICHOTWATER | Group: Domestic Hot Water 173
OutPort_3010663_5 | SOURCE | DUCT | VENTILATION
InPort_3010673_4 | SINK | PIPE | DOMESTICHOTWATER | Group: Domestic Hot Water 178
OutPort_3010678_0 | SOURCE | PIPE | DOMESTICHOTWATER | Group: Domestic Hot Water 178
OutPort_3010673_5 | SOURCE | PIPE | DOMESTICHOTWATER
InPort_3010673_6 | SINK | PIPE | DOMESTICCOLDWATER
OutPort_3010673_7 | SOURCE | DUCT | EXHAUST
InPort_3010673_8 | SINK | PIPE | USERDEFINED
InPort_3010692_1 | SINK | PIPE | DOMESTICHOTWATER | Group: Domestic Hot Water 178
OutPort_3010709_5 | SOURCE | DUCT | VENTILATION
InPort_3010719_4 | SINK | PIPE | DOMESTICHOTWATER | Group: Domestic Hot Water 182
OutPort_3010724_0 | SOURCE | PIPE | DOMESTICHOTWATER | Group: Domestic Hot Water 182
OutPort_3010719_5 | SOURCE | PIPE | DOMESTICHOTWATER
InPort_3010719_6 | SINK | PIPE | DOMESTICCOLDWATER
OutPort_3010719_7 | SOURCE | DUCT | EXHAUST
InPort_3010719_8 | SINK | PIPE | USERDEFINED
InPort_3010738_1 | SINK | PIPE | DOMESTICHOTWATER | Group: Domestic Hot Water 182
OutPort_3010755_5 | SOURCE | DUCT | VENTILATION
InPort_3010765_4 | SINK | PIPE | DOMESTICHOTWATER | Group: Domestic Hot Water 186
OutPort_3010770_0 | SOURCE | PIPE | DOMESTICHOTWATER | Group: Domestic Hot Water 186
OutPort_3010765_5 | SOURCE | PIPE | DOMESTICHOTWATER
InPort_3010765_6 | SINK | PIPE | DOMESTICCOLDWATER
OutPort_3010765_7 | SOURCE | DUCT | EXHAUST
InPort_3010765_8 | SINK | PIPE | USERDEFINED
InPort_3010784_1 | SINK | PIPE | DOMESTICHOTWATER | Group: Domestic Hot Water 186
OutPort_3010801_5 | SOURCE | DUCT | VENTILATION
InPort_3010811_4 | SINK | PIPE | DOMESTICHOTWATER | Group: Domestic Hot Water 190
OutPort_3010816_0 | SOURCE | PIPE | DOMESTICHOTWATER | Group: Domestic Hot Water 190
OutPort_3010811_5 | SOURCE | PIPE | DOMESTICHOTWATER
InPort_3010811_6 | SINK | PIPE | DOMESTICCOLDWATER
OutPort_3010811_7 | SOURCE | DUCT | EXHAUST
InPort_3010811_8 | SINK | PIPE | USERDEFINED
InPort_3010830_1 | SINK | PIPE | DOMESTICHOTWATER | Group: Domestic Hot Water 190
OutPort_3010847_5 | SOURCE | DUCT | VENTILATION
InPort_3010857_4 | SINK | PIPE | DOMESTICHOTWATER | Group: Domestic Hot Water 194
OutPort_3010862_0 | SOURCE | PIPE | DOMESTICHOTWATER | Group: Domestic Hot Water 194
OutPort_3010857_5 | SOURCE | PIPE | DOMESTICHOTWATER
InPort_3010857_6 | SINK | PIPE | DOMESTICCOLDWATER
OutPort_3010857_7 | SOURCE | DUCT | EXHAUST
InPort_3010857_8 | SINK | PIPE | USERDEFINED
InPort_3010876_1 | SINK | PIPE | DOMESTICHOTWATER | Group: Domestic Hot Water 194
OutPort_3010894_5 | SOURCE | DUCT | VENTILATION
InPort_3010904_4 | SINK | PIPE | DOMESTICHOTWATER | Group: Domestic Hot Water 198
OutPort_3010909_0 | SOURCE | PIPE | DOMESTICHOTWATER | Group: Domestic Hot Water 198
OutPort_3010904_5 | SOURCE | PIPE | DOMESTICHOTWATER
InPort_3010904_6 | SINK | PIPE | DOMESTICCOLDWATER
OutPort_3010904_7 | SOURCE | DUCT | EXHAUST
InPort_3010904_8 | SINK | PIPE | USERDEFINED
InPort_3010923_1 | SINK | PIPE | DOMESTICHOTWATER | Group: Domestic Hot Water 198
OutPort_3010940_5 | SOURCE | DUCT | VENTILATION
InPort_3010950_4 | SINK | PIPE | DOMESTICHOTWATER | Group: Domestic Hot Water 202
OutPort_3010955_0 | SOURCE | PIPE | DOMESTICHOTWATER | Group: Domestic Hot Water 202
OutPort_3010950_5 | SOURCE | PIPE | DOMESTICHOTWATER
InPort_3010950_6 | SINK | PIPE | DOMESTICCOLDWATER
OutPort_3010950_7 | SOURCE | DUCT | EXHAUST
InPort_3010950_8 | SINK | PIPE | USERDEFINED
InPort_3010969_1 | SINK | PIPE | DOMESTICHOTWATER | Group: Domestic Hot Water 202
OutPort_3010990_5 | SOURCE | DUCT | VENTILATION
InPort_3011000_4 | SINK | PIPE | DOMESTICHOTWATER | Group: Domestic Hot Water 206
OutPort_3011005_0 | SOURCE | PIPE | DOMESTICHOTWATER | Group: Domestic Hot Water 206
OutPort_3011000_5 | SOURCE | PIPE | DOMESTICHOTWATER
InPort_3011000_6 | SINK | PIPE | DOMESTICCOLDWATER
OutPort_3011000_7 | SOURCE | DUCT | EXHAUST
InPort_3011000_8 | SINK | PIPE | USERDEFINED
InPort_3011019_1 | SINK | PIPE | DOMESTICHOTWATER | Group: Domestic Hot Water 206
OutPort_3011036_5 | SOURCE | DUCT | VENTILATION
InPort_3011046_4 | SINK | PIPE | DOMESTICHOTWATER | Group: Domestic Hot Water 210
OutPort_3011051_0 | SOURCE | PIPE | DOMESTICHOTWATER | Group: Domestic Hot Water 210
OutPort_3011046_5 | SOURCE | PIPE | DOMESTICHOTWATER
InPort_3011046_6 | SINK | PIPE | DOMESTICCOLDWATER
OutPort_3011046_7 | SOURCE | DUCT | EXHAUST
InPort_3011046_8 | SINK | PIPE | USERDEFINED
InPort_3011065_1 | SINK | PIPE | DOMESTICHOTWATER | Group: Domestic Hot Water 210
OutPort_3011082_5 | SOURCE | DUCT | VENTILATION
InPort_3011092_4 | SINK | PIPE | DOMESTICHOTWATER | Group: Domestic Hot Water 212
OutPort_3011097_0 | SOURCE | PIPE | DOMESTICHOTWATER | Group: Domestic Hot Water 212
OutPort_3011092_5 | SOURCE | PIPE | DOMESTICHOTWATER
InPort_3011092_6 | SINK | PIPE | DOMESTICCOLDWATER
OutPort_3011092_7 | SOURCE | DUCT | EXHAUST
InPort_3011092_8 | SINK | PIPE | USERDEFINED
InPort_3011111_1 | SINK | PIPE | DOMESTICHOTWATER | Group: Domestic Hot Water 212
OutPort_3011128_5 | SOURCE | DUCT | VENTILATION
InPort_3011138_4 | SINK | PIPE | DOMESTICHOTWATER | Group: Domestic Hot Water 214
OutPort_3011143_0 | SOURCE | PIPE | DOMESTICHOTWATER | Group: Domestic Hot Water 214
OutPort_3011138_5 | SOURCE | PIPE | DOMESTICHOTWATER
InPort_3011138_6 | SINK | PIPE | DOMESTICCOLDWATER
OutPort_3011138_7 | SOURCE | DUCT | EXHAUST
InPort_3011138_8 | SINK | PIPE | USERDEFINED
InPort_3011157_1 | SINK | PIPE | DOMESTICHOTWATER | Group: Domestic Hot Water 214
OutPort_3011174_5 | SOURCE | DUCT | VENTILATION
InPort_3011184_4 | SINK | PIPE | DOMESTICHOTWATER | Group: Domestic Hot Water 216
OutPort_3011189_0 | SOURCE | PIPE | DOMESTICHOTWATER | Group: Domestic Hot Water 216
OutPort_3011184_5 | SOURCE | PIPE | DOMESTICHOTWATER
InPort_3011184_6 | SINK | PIPE | DOMESTICCOLDWATER
OutPort_3011184_7 | SOURCE | DUCT | EXHAUST
InPort_3011184_8 | SINK | PIPE | USERDEFINED
InPort_3011203_1 | SINK | PIPE | DOMESTICHOTWATER | Group: Domestic Hot Water 216
OutPort_3011221_5 | SOURCE | DUCT | VENTILATION
InPort_3011231_4 | SINK | PIPE | DOMESTICHOTWATER | Group: Domestic Hot Water 218
OutPort_3011236_0 | SOURCE | PIPE | DOMESTICHOTWATER | Group: Domestic Hot Water 218
OutPort_3011231_5 | SOURCE | PIPE | DOMESTICHOTWATER
InPort_3011231_6 | SINK | PIPE | DOMESTICCOLDWATER
OutPort_3011231_7 | SOURCE | DUCT | EXHAUST
InPort_3011231_8 | SINK | PIPE | USERDEFINED
InPort_3011250_1 | SINK | PIPE | DOMESTICHOTWATER | Group: Domestic Hot Water 218
OutPort_3011267_5 | SOURCE | DUCT | VENTILATION
InPort_3011277_4 | SINK | PIPE | DOMESTICHOTWATER | Group: Domestic Hot Water 220
OutPort_3011282_0 | SOURCE | PIPE | DOMESTICHOTWATER | Group: Domestic Hot Water 220
OutPort_3011277_5 | SOURCE | PIPE | DOMESTICHOTWATER
InPort_3011277_6 | SINK | PIPE | DOMESTICCOLDWATER
OutPort_3011277_7 | SOURCE | DUCT | EXHAUST
InPort_3011277_8 | SINK | PIPE | USERDEFINED
InPort_3011296_1 | SINK | PIPE | DOMESTICHOTWATER | Group: Domestic Hot Water 220
OutPort_3011317_5 | SOURCE | DUCT | VENTILATION
InPort_3011327_4 | SINK | PIPE | DOMESTICHOTWATER | Group: Domestic Hot Water 222
OutPort_3011332_0 | SOURCE | PIPE | DOMESTICHOTWATER | Group: Domestic Hot Water 222
OutPort_3011327_5 | SOURCE | PIPE | DOMESTICHOTWATER
InPort_3011327_6 | SINK | PIPE | DOMESTICCOLDWATER
OutPort_3011327_7 | SOURCE | DUCT | EXHAUST
InPort_3011327_8 | SINK | PIPE | USERDEFINED
InPort_3011346_1 | SINK | PIPE | DOMESTICHOTWATER | Group: Domestic Hot Water 222
OutPort_3011363_5 | SOURCE | DUCT | VENTILATION
InPort_3011373_4 | SINK | PIPE | DOMESTICHOTWATER | Group: Domestic Hot Water 224
OutPort_3011378_0 | SOURCE | PIPE | DOMESTICHOTWATER | Group: Domestic Hot Water 224
OutPort_3011373_5 | SOURCE | PIPE | DOMESTICHOTWATER
InPort_3011373_6 | SINK | PIPE | DOMESTICCOLDWATER
OutPort_3011373_7 | SOURCE | DUCT | EXHAUST
InPort_3011373_8 | SINK | PIPE | USERDEFINED
InPort_3011392_1 | SINK | PIPE | DOMESTICHOTWATER | Group: Domestic Hot Water 224
OutPort_3011409_5 | SOURCE | DUCT | VENTILATION
InPort_3011419_4 | SINK | PIPE | DOMESTICHOTWATER | Group: Domestic Hot Water 226
OutPort_3011424_0 | SOURCE | PIPE | DOMESTICHOTWATER | Group: Domestic Hot Water 226
OutPort_3011419_5 | SOURCE | PIPE | DOMESTICHOTWATER
InPort_3011419_6 | SINK | PIPE | DOMESTICCOLDWATER
OutPort_3011419_7 | SOURCE | DUCT | EXHAUST
InPort_3011419_8 | SINK | PIPE | USERDEFINED
InPort_3011438_1 | SINK | PIPE | DOMESTICHOTWATER | Group: Domestic Hot Water 226
OutPort_3011455_5 | SOURCE | DUCT | VENTILATION
InPort_3011465_4 | SINK | PIPE | DOMESTICHOTWATER | Group: Domestic Hot Water 228
OutPort_3011470_0 | SOURCE | PIPE | DOMESTICHOTWATER | Group: Domestic Hot Water 228
OutPort_3011465_5 | SOURCE | PIPE | DOMESTICHOTWATER
InPort_3011465_6 | SINK | PIPE | DOMESTICCOLDWATER
OutPort_3011465_7 | SOURCE | DUCT | EXHAUST
InPort_3011465_8 | SINK | PIPE | USERDEFINED
InPort_3011484_1 | SINK | PIPE | DOMESTICHOTWATER | Group: Domestic Hot Water 228
OutPort_3011501_5 | SOURCE | DUCT | VENTILATION
InPort_3011511_4 | SINK | PIPE | DOMESTICHOTWATER | Group: Domestic Hot Water 230
OutPort_3011516_0 | SOURCE | PIPE | DOMESTICHOTWATER | Group: Domestic Hot Water 230
OutPort_3011511_5 | SOURCE | PIPE | DOMESTICHOTWATER
InPort_3011511_6 | SINK | PIPE | DOMESTICCOLDWATER
OutPort_3011511_7 | SOURCE | DUCT | EXHAUST
InPort_3011511_8 | SINK | PIPE | USERDEFINED
InPort_3011530_1 | SINK | PIPE | DOMESTICHOTWATER | Group: Domestic Hot Water 230
OutPort_3011548_5 | SOURCE | DUCT | VENTILATION
InPort_3011558_4 | SINK | PIPE | DOMESTICHOTWATER | Group: Domestic Hot Water 232
OutPort_3011563_0 | SOURCE | PIPE | DOMESTICHOTWATER | Group: Domestic Hot Water 232
OutPort_3011558_5 | SOURCE | PIPE | DOMESTICHOTWATER
InPort_3011558_6 | SINK | PIPE | DOMESTICCOLDWATER
OutPort_3011558_7 | SOURCE | DUCT | EXHAUST
InPort_3011558_8 | SINK | PIPE | USERDEFINED
InPort_3011577_1 | SINK | PIPE | DOMESTICHOTWATER | Group: Domestic Hot Water 232
OutPort_3011594_5 | SOURCE | DUCT | VENTILATION
InPort_3011604_4 | SINK | PIPE | DOMESTICHOTWATER | Group: Domestic Hot Water 234
OutPort_3011609_0 | SOURCE | PIPE | DOMESTICHOTWATER | Group: Domestic Hot Water 234
OutPort_3011604_5 | SOURCE | PIPE | DOMESTICHOTWATER
InPort_3011604_6 | SINK | PIPE | DOMESTICCOLDWATER
OutPort_3011604_7 | SOURCE | DUCT | EXHAUST
InPort_3011604_8 | SINK | PIPE | USERDEFINED
InPort_3011623_1 | SINK | PIPE | DOMESTICHOTWATER | Group: Domestic Hot Water 234
OutPort_3011644_5 | SOURCE | DUCT | VENTILATION
InPort_3011654_4 | SINK | PIPE | DOMESTICHOTWATER | Group: Domestic Hot Water 236
OutPort_3011659_0 | SOURCE | PIPE | DOMESTICHOTWATER | Group: Domestic Hot Water 236
OutPort_3011654_5 | SOURCE | PIPE | DOMESTICHOTWATER
InPort_3011654_6 | SINK | PIPE | DOMESTICCOLDWATER
OutPort_3011654_7 | SOURCE | DUCT | EXHAUST
InPort_3011654_8 | SINK | PIPE | USERDEFINED
InPort_3011673_1 | SINK | PIPE | DOMESTICHOTWATER | Group: Domestic Hot Water 236
OutPort_3011690_5 | SOURCE | DUCT | VENTILATION
InPort_3011700_4 | SINK | PIPE | DOMESTICHOTWATER | Group: Domestic Hot Water 238
OutPort_3011705_0 | SOURCE | PIPE | DOMESTICHOTWATER | Group: Domestic Hot Water 238
OutPort_3011700_5 | SOURCE | PIPE | DOMESTICHOTWATER
InPort_3011700_6 | SINK | PIPE | DOMESTICCOLDWATER
OutPort_3011700_7 | SOURCE | DUCT | EXHAUST
InPort_3011700_8 | SINK | PIPE | USERDEFINED
InPort_3011719_1 | SINK | PIPE | DOMESTICHOTWATER | Group: Domestic Hot Water 238
OutPort_3011736_5 | SOURCE | DUCT | VENTILATION
InPort_3011746_4 | SINK | PIPE | DOMESTICHOTWATER | Group: Domestic Hot Water 240
OutPort_3011751_0 | SOURCE | PIPE | DOMESTICHOTWATER | Group: Domestic Hot Water 240
OutPort_3011746_5 | SOURCE | PIPE | DOMESTICHOTWATER
InPort_3011746_6 | SINK | PIPE | DOMESTICCOLDWATER
OutPort_3011746_7 | SOURCE | DUCT | EXHAUST
InPort_3011746_8 | SINK | PIPE | USERDEFINED
InPort_3011765_1 | SINK | PIPE | DOMESTICHOTWATER | Group: Domestic Hot Water 240
OutPort_3011782_5 | SOURCE | DUCT | VENTILATION
InPort_3011792_4 | SINK | PIPE | DOMESTICHOTWATER | Group: Domestic Hot Water 242
OutPort_3011797_0 | SOURCE | PIPE | DOMESTICHOTWATER | Group: Domestic Hot Water 242
OutPort_3011792_5 | SOURCE | PIPE | DOMESTICHOTWATER
InPort_3011792_6 | SINK | PIPE | DOMESTICCOLDWATER
OutPort_3011792_7 | SOURCE | DUCT | EXHAUST
InPort_3011792_8 | SINK | PIPE | USERDEFINED
InPort_3011811_1 | SINK | PIPE | DOMESTICHOTWATER | Group: Domestic Hot Water 242
OutPort_3011828_5 | SOURCE | DUCT | VENTILATION
InPort_3011838_4 | SINK | PIPE | DOMESTICHOTWATER | Group: Domestic Hot Water 244
OutPort_3011843_0 | SOURCE | PIPE | DOMESTICHOTWATER | Group: Domestic Hot Water 244
OutPort_3011838_5 | SOURCE | PIPE | DOMESTICHOTWATER
InPort_3011838_6 | SINK | PIPE | DOMESTICCOLDWATER
OutPort_3011838_7 | SOURCE | DUCT | EXHAUST
InPort_3011838_8 | SINK | PIPE | USERDEFINED
InPort_3011857_1 | SINK | PIPE | DOMESTICHOTWATER | Group: Domestic Hot Water 244
OutPort_3012437_5 | SOURCE | DUCT | VENTILATION
InPort_3012447_4 | SINK | PIPE | DOMESTICHOTWATER | Group: Domestic Hot Water 67
OutPort_3012452_0 | SOURCE | PIPE | DOMESTICHOTWATER | Group: Domestic Hot Water 67
OutPort_3012447_5 | SOURCE | PIPE | DOMESTICHOTWATER
InPort_3012447_6 | SINK | PIPE | DOMESTICCOLDWATER
OutPort_3012447_7 | SOURCE | DUCT | EXHAUST
InPort_3012447_8 | SINK | PIPE | USERDEFINED
InPort_3012466_1 | SINK | PIPE | DOMESTICHOTWATER | Group: Domestic Hot Water 67
OutPort_3012483_5 | SOURCE | DUCT | VENTILATION
InPort_3012493_4 | SINK | PIPE | DOMESTICHOTWATER | Group: Domestic Hot Water 118
OutPort_3012498_0 | SOURCE | PIPE | DOMESTICHOTWATER | Group: Domestic Hot Water 118
OutPort_3012493_5 | SOURCE | PIPE | DOMESTICHOTWATER
InPort_3012493_6 | SINK | PIPE | DOMESTICCOLDWATER
OutPort_3012493_7 | SOURCE | DUCT | EXHAUST
InPort_3012493_8 | SINK | PIPE | USERDEFINED
InPort_3012512_1 | SINK | PIPE | DOMESTICHOTWATER | Group: Domestic Hot Water 118
OutPort_3012533_5 | SOURCE | DUCT | VENTILATION
InPort_3012543_4 | SINK | PIPE | DOMESTICHOTWATER | Group: Domestic Hot Water 145
OutPort_3012548_0 | SOURCE | PIPE | DOMESTICHOTWATER | Group: Domestic Hot Water 145
OutPort_3012543_5 | SOURCE | PIPE | DOMESTICHOTWATER
InPort_3012543_6 | SINK | PIPE | DOMESTICCOLDWATER
OutPort_3012543_7 | SOURCE | DUCT | EXHAUST
InPort_3012543_8 | SINK | PIPE | USERDEFINED
InPort_3012562_1 | SINK | PIPE | DOMESTICHOTWATER | Group: Domestic Hot Water 145
OutPort_3012579_5 | SOURCE | DUCT | VENTILATION
InPort_3012589_4 | SINK | PIPE | DOMESTICHOTWATER | Group: Domestic Hot Water 161
OutPort_3012594_0 | SOURCE | PIPE | DOMESTICHOTWATER | Group: Domestic Hot Water 161
OutPort_3012589_5 | SOURCE | PIPE | DOMESTICHOTWATER
InPort_3012589_6 | SINK | PIPE | DOMESTICCOLDWATER
OutPort_3012589_7 | SOURCE | DUCT | EXHAUST
InPort_3012589_8 | SINK | PIPE | USERDEFINED
InPort_3012608_1 | SINK | PIPE | DOMESTICHOTWATER | Group: Domestic Hot Water 161
OutPort_3012625_5 | SOURCE | DUCT | VENTILATION
InPort_3012635_4 | SINK | PIPE | DOMESTICHOTWATER | Group: Domestic Hot Water 176
OutPort_3012640_0 | SOURCE | PIPE | DOMESTICHOTWATER | Group: Domestic Hot Water 176
OutPort_3012635_5 | SOURCE | PIPE | DOMESTICHOTWATER
InPort_3012635_6 | SINK | PIPE | DOMESTICCOLDWATER
OutPort_3012635_7 | SOURCE | DUCT | EXHAUST
InPort_3012635_8 | SINK | PIPE | USERDEFINED
InPort_3012654_1 | SINK | PIPE | DOMESTICHOTWATER | Group: Domestic Hot Water 176
OutPort_3012671_5 | SOURCE | DUCT | VENTILATION
InPort_3012681_4 | SINK | PIPE | DOMESTICHOTWATER | Group: Domestic Hot Water 184
OutPort_3012686_0 | SOURCE | PIPE | DOMESTICHOTWATER | Group: Domestic Hot Water 184
OutPort_3012681_5 | SOURCE | PIPE | DOMESTICHOTWATER
InPort_3012681_6 | SINK | PIPE | DOMESTICCOLDWATER
OutPort_3012681_7 | SOURCE | DUCT | EXHAUST
InPort_3012681_8 | SINK | PIPE | USERDEFINED
InPort_3012700_1 | SINK | PIPE | DOMESTICHOTWATER | Group: Domestic Hot Water 184
OutPort_3012717_5 | SOURCE | DUCT | VENTILATION
InPort_3012727_4 | SINK | PIPE | DOMESTICHOTWATER | Group: Domestic Hot Water 192
OutPort_3012732_0 | SOURCE | PIPE | DOMESTICHOTWATER | Group: Domestic Hot Water 192
OutPort_3012727_5 | SOURCE | PIPE | DOMESTICHOTWATER
InPort_3012727_6 | SINK | PIPE | DOMESTICCOLDWATER
OutPort_3012727_7 | SOURCE | DUCT | EXHAUST
InPort_3012727_8 | SINK | PIPE | USERDEFINED
InPort_3012746_1 | SINK | PIPE | DOMESTICHOTWATER | Group: Domestic Hot Water 192
OutPort_3012764_5 | SOURCE | DUCT | VENTILATION
InPort_3012774_4 | SINK | PIPE | DOMESTICHOTWATER | Group: Domestic Hot Water 200
OutPort_3012779_0 | SOURCE | PIPE | DOMESTICHOTWATER | Group: Domestic Hot Water 200
OutPort_3012774_5 | SOURCE | PIPE | DOMESTICHOTWATER
InPort_3012774_6 | SINK | PIPE | DOMESTICCOLDWATER
OutPort_3012774_7 | SOURCE | DUCT | EXHAUST
InPort_3012774_8 | SINK | PIPE | USERDEFINED
InPort_3012793_1 | SINK | PIPE | DOMESTICHOTWATER | Group: Domestic Hot Water 200
OutPort_3012810_5 | SOURCE | DUCT | VENTILATION
InPort_3012820_4 | SINK | PIPE | DOMESTICHOTWATER | Group: Domestic Hot Water 208
OutPort_3012825_0 | SOURCE | PIPE | DOMESTICHOTWATER | Group: Domestic Hot Water 208
OutPort_3012820_5 | SOURCE | PIPE | DOMESTICHOTWATER
InPort_3012820_6 | SINK | PIPE | DOMESTICCOLDWATER
OutPort_3012820_7 | SOURCE | DUCT | EXHAUST
InPort_3012820_8 | SINK | PIPE | USERDEFINED
InPort_3012839_1 | SINK | PIPE | DOMESTICHOTWATER | Group: Domestic Hot Water 208
OutPort_3012860_5 | SOURCE | DUCT | VENTILATION
InPort_3012870_4 | SINK | PIPE | DOMESTICHOTWATER | Group: Domestic Hot Water 213
OutPort_3012875_0 | SOURCE | PIPE | DOMESTICHOTWATER | Group: Domestic Hot Water 213
OutPort_3012870_5 | SOURCE | PIPE | DOMESTICHOTWATER
InPort_3012870_6 | SINK | PIPE | DOMESTICCOLDWATER
OutPort_3012870_7 | SOURCE | DUCT | EXHAUST
InPort_3012870_8 | SINK | PIPE | USERDEFINED
InPort_3012889_1 | SINK | PIPE | DOMESTICHOTWATER | Group: Domestic Hot Water 213
OutPort_3012906_5 | SOURCE | DUCT | VENTILATION
InPort_3012916_4 | SINK | PIPE | DOMESTICHOTWATER | Group: Domestic Hot Water 217
OutPort_3012921_0 | SOURCE | PIPE | DOMESTICHOTWATER | Group: Domestic Hot Water 217
OutPort_3012916_5 | SOURCE | PIPE | DOMESTICHOTWATER
InPort_3012916_6 | SINK | PIPE | DOMESTICCOLDWATER
OutPort_3012916_7 | SOURCE | DUCT | EXHAUST
InPort_3012916_8 | SINK | PIPE | USERDEFINED
InPort_3012935_1 | SINK | PIPE | DOMESTICHOTWATER | Group: Domestic Hot Water 217
OutPort_3012952_5 | SOURCE | DUCT | VENTILATION
InPort_3012962_4 | SINK | PIPE | DOMESTICHOTWATER | Group: Domestic Hot Water 221
OutPort_3012967_0 | SOURCE | PIPE | DOMESTICHOTWATER | Group: Domestic Hot Water 221
OutPort_3012962_5 | SOURCE | PIPE | DOMESTICHOTWATER
InPort_3012962_6 | SINK | PIPE | DOMESTICCOLDWATER
OutPort_3012962_7 | SOURCE | DUCT | EXHAUST
InPort_3012962_8 | SINK | PIPE | USERDEFINED
InPort_3012981_1 | SINK | PIPE | DOMESTICHOTWATER | Group: Domestic Hot Water 221
OutPort_3012998_5 | SOURCE | DUCT | VENTILATION
InPort_3013008_4 | SINK | PIPE | DOMESTICHOTWATER | Group: Domestic Hot Water 225
OutPort_3013013_0 | SOURCE | PIPE | DOMESTICHOTWATER | Group: Domestic Hot Water 225
OutPort_3013008_5 | SOURCE | PIPE | DOMESTICHOTWATER
InPort_3013008_6 | SINK | PIPE | DOMESTICCOLDWATER
OutPort_3013008_7 | SOURCE | DUCT | EXHAUST
InPort_3013008_8 | SINK | PIPE | USERDEFINED
InPort_3013027_1 | SINK | PIPE | DOMESTICHOTWATER | Group: Domestic Hot Water 225
OutPort_3013044_5 | SOURCE | DUCT | VENTILATION
InPort_3013054_4 | SINK | PIPE | DOMESTICHOTWATER | Group: Domestic Hot Water 229
OutPort_3013059_0 | SOURCE | PIPE | DOMESTICHOTWATER | Group: Domestic Hot Water 229
OutPort_3013054_5 | SOURCE | PIPE | DOMESTICHOTWATER
InPort_3013054_6 | SINK | PIPE | DOMESTICCOLDWATER
OutPort_3013054_7 | SOURCE | DUCT | EXHAUST
InPort_3013054_8 | SINK | PIPE | USERDEFINED
InPort_3013073_1 | SINK | PIPE | DOMESTICHOTWATER | Group: Domestic Hot Water 229
OutPort_3013091_5 | SOURCE | DUCT | VENTILATION
InPort_3013101_4 | SINK | PIPE | DOMESTICHOTWATER | Group: Domestic Hot Water 233
OutPort_3013106_0 | SOURCE | PIPE | DOMESTICHOTWATER | Group: Domestic Hot Water 233
OutPort_3013101_5 | SOURCE | PIPE | DOMESTICHOTWATER
InPort_3013101_6 | SINK | PIPE | DOMESTICCOLDWATER
OutPort_3013101_7 | SOURCE | DUCT | EXHAUST
InPort_3013101_8 | SINK | PIPE | USERDEFINED
InPort_3013120_1 | SINK | PIPE | DOMESTICHOTWATER | Group: Domestic Hot Water 233
OutPort_3013137_5 | SOURCE | DUCT | VENTILATION
InPort_3013147_4 | SINK | PIPE | DOMESTICHOTWATER | Group: Domestic Hot Water 237
OutPort_3013152_0 | SOURCE | PIPE | DOMESTICHOTWATER | Group: Domestic Hot Water 237
OutPort_3013147_5 | SOURCE | PIPE | DOMESTICHOTWATER
InPort_3013147_6 | SINK | PIPE | DOMESTICCOLDWATER
OutPort_3013147_7 | SOURCE | DUCT | EXHAUST
InPort_3013147_8 | SINK | PIPE | USERDEFINED
InPort_3013166_1 | SINK | PIPE | DOMESTICHOTWATER | Group: Domestic Hot Water 237
OutPort_3013187_5 | SOURCE | DUCT | VENTILATION
InPort_3013197_4 | SINK | PIPE | DOMESTICHOTWATER | Group: Domestic Hot Water 241
OutPort_3013202_0 | SOURCE | PIPE | DOMESTICHOTWATER | Group: Domestic Hot Water 241
OutPort_3013197_5 | SOURCE | PIPE | DOMESTICHOTWATER
InPort_3013197_6 | SINK | PIPE | DOMESTICCOLDWATER
OutPort_3013197_7 | SOURCE | DUCT | EXHAUST
InPort_3013197_8 | SINK | PIPE | USERDEFINED
InPort_3013216_1 | SINK | PIPE | DOMESTICHOTWATER | Group: Domestic Hot Water 241
OutPort_3013233_5 | SOURCE | DUCT | VENTILATION
InPort_3013243_4 | SINK | PIPE | DOMESTICHOTWATER | Group: Domestic Hot Water 245
OutPort_3013248_0 | SOURCE | PIPE | DOMESTICHOTWATER | Group: Domestic Hot Water 245
OutPort_3013243_5 | SOURCE | PIPE | DOMESTICHOTWATER
InPort_3013243_6 | SINK | PIPE | DOMESTICCOLDWATER
OutPort_3013243_7 | SOURCE | DUCT | EXHAUST
InPort_3013243_8 | SINK | PIPE | USERDEFINED
InPort_3013262_1 | SINK | PIPE | DOMESTICHOTWATER | Group: Domestic Hot Water 245
OutPort_3013279_5 | SOURCE | DUCT | VENTILATION
InPort_3013289_4 | SINK | PIPE | DOMESTICHOTWATER | Group: Domestic Hot Water 247
OutPort_3013294_0 | SOURCE | PIPE | DOMESTICHOTWATER | Group: Domestic Hot Water 247
OutPort_3013289_5 | SOURCE | PIPE | DOMESTICHOTWATER
InPort_3013289_6 | SINK | PIPE | DOMESTICCOLDWATER
OutPort_3013289_7 | SOURCE | DUCT | EXHAUST
InPort_3013289_8 | SINK | PIPE | USERDEFINED
InPort_3013308_1 | SINK | PIPE | DOMESTICHOTWATER | Group: Domestic Hot Water 247
OutPort_3013325_5 | SOURCE | DUCT | VENTILATION
InPort_3013335_4 | SINK | PIPE | DOMESTICHOTWATER | Group: Domestic Hot Water 249
OutPort_3013340_0 | SOURCE | PIPE | DOMESTICHOTWATER | Group: Domestic Hot Water 249
OutPort_3013335_5 | SOURCE | PIPE | DOMESTICHOTWATER
InPort_3013335_6 | SINK | PIPE | DOMESTICCOLDWATER
OutPort_3013335_7 | SOURCE | DUCT | EXHAUST
InPort_3013335_8 | SINK | PIPE | USERDEFINED
InPort_3013354_1 | SINK | PIPE | DOMESTICHOTWATER | Group: Domestic Hot Water 249
OutPort_3013371_5 | SOURCE | DUCT | VENTILATION
InPort_3013381_4 | SINK | PIPE | DOMESTICHOTWATER | Group: Domestic Hot Water 251
OutPort_3013386_0 | SOURCE | PIPE | DOMESTICHOTWATER | Group: Domestic Hot Water 251
OutPort_3013381_5 | SOURCE | PIPE | DOMESTICHOTWATER
InPort_3013381_6 | SINK | PIPE | DOMESTICCOLDWATER
OutPort_3013381_7 | SOURCE | DUCT | EXHAUST
InPort_3013381_8 | SINK | PIPE | USERDEFINED
InPort_3013400_1 | SINK | PIPE | DOMESTICHOTWATER | Group: Domestic Hot Water 251
OutPort_3013418_5 | SOURCE | DUCT | VENTILATION
InPort_3013428_4 | SINK | PIPE | DOMESTICHOTWATER | Group: Domestic Hot Water 253
OutPort_3013433_0 | SOURCE | PIPE | DOMESTICHOTWATER | Group: Domestic Hot Water 253
OutPort_3013428_5 | SOURCE | PIPE | DOMESTICHOTWATER
InPort_3013428_6 | SINK | PIPE | DOMESTICCOLDWATER
OutPort_3013428_7 | SOURCE | DUCT | EXHAUST
InPort_3013428_8 | SINK | PIPE | USERDEFINED
InPort_3013447_1 | SINK | PIPE | DOMESTICHOTWATER | Group: Domestic Hot Water 253
OutPort_3013464_5 | SOURCE | DUCT | VENTILATION
InPort_3013474_4 | SINK | PIPE | DOMESTICHOTWATER | Group: Domestic Hot Water 255
OutPort_3013479_0 | SOURCE | PIPE | DOMESTICHOTWATER | Group: Domestic Hot Water 255
OutPort_3013474_5 | SOURCE | PIPE | DOMESTICHOTWATER
InPort_3013474_6 | SINK | PIPE | DOMESTICCOLDWATER
OutPort_3013474_7 | SOURCE | DUCT | EXHAUST
InPort_3013474_8 | SINK | PIPE | USERDEFINED
InPort_3013493_1 | SINK | PIPE | DOMESTICHOTWATER | Group: Domestic Hot Water 255
OutPort_3013514_5 | SOURCE | DUCT | VENTILATION
InPort_3013524_4 | SINK | PIPE | DOMESTICHOTWATER | Group: Domestic Hot Water 257
OutPort_3013529_0 | SOURCE | PIPE | DOMESTICHOTWATER | Group: Domestic Hot Water 257
OutPort_3013524_5 | SOURCE | PIPE | DOMESTICHOTWATER
InPort_3013524_6 | SINK | PIPE | DOMESTICCOLDWATER
OutPort_3013524_7 | SOURCE | DUCT | EXHAUST
InPort_3013524_8 | SINK | PIPE | USERDEFINED
InPort_3013543_1 | SINK | PIPE | DOMESTICHOTWATER | Group: Domestic Hot Water 257
OutPort_3013560_5 | SOURCE | DUCT | VENTILATION
InPort_3013570_4 | SINK | PIPE | DOMESTICHOTWATER | Group: Domestic Hot Water 259
OutPort_3013575_0 | SOURCE | PIPE | DOMESTICHOTWATER | Group: Domestic Hot Water 259
OutPort_3013570_5 | SOURCE | PIPE | DOMESTICHOTWATER
InPort_3013570_6 | SINK | PIPE | DOMESTICCOLDWATER
OutPort_3013570_7 | SOURCE | DUCT | EXHAUST
InPort_3013570_8 | SINK | PIPE | USERDEFINED
InPort_3013589_1 | SINK | PIPE | DOMESTICHOTWATER | Group: Domestic Hot Water 259
OutPort_3013606_5 | SOURCE | DUCT | VENTILATION
InPort_3013616_4 | SINK | PIPE | DOMESTICHOTWATER | Group: Domestic Hot Water 261
OutPort_3013621_0 | SOURCE | PIPE | DOMESTICHOTWATER | Group: Domestic Hot Water 261
OutPort_3013616_5 | SOURCE | PIPE | DOMESTICHOTWATER
InPort_3013616_6 | SINK | PIPE | DOMESTICCOLDWATER
OutPort_3013616_7 | SOURCE | DUCT | EXHAUST
InPort_3013616_8 | SINK | PIPE | USERDEFINED
InPort_3013635_1 | SINK | PIPE | DOMESTICHOTWATER | Group: Domestic Hot Water 261
OutPort_3013652_5 | SOURCE | DUCT | VENTILATION
InPort_3013662_4 | SINK | PIPE | DOMESTICHOTWATER | Group: Domestic Hot Water 263
OutPort_3013667_0 | SOURCE | PIPE | DOMESTICHOTWATER | Group: Domestic Hot Water 263
OutPort_3013662_5 | SOURCE | PIPE | DOMESTICHOTWATER
InPort_3013662_6 | SINK | PIPE | DOMESTICCOLDWATER
OutPort_3013662_7 | SOURCE | DUCT | EXHAUST
InPort_3013662_8 | SINK | PIPE | USERDEFINED
InPort_3013681_1 | SINK | PIPE | DOMESTICHOTWATER | Group: Domestic Hot Water 263
OutPort_3013698_5 | SOURCE | DUCT | VENTILATION
InPort_3013708_4 | SINK | PIPE | DOMESTICHOTWATER | Group: Domestic Hot Water 265
OutPort_3013713_0 | SOURCE | PIPE | DOMESTICHOTWATER | Group: Domestic Hot Water 265
OutPort_3013708_5 | SOURCE | PIPE | DOMESTICHOTWATER
InPort_3013708_6 | SINK | PIPE | DOMESTICCOLDWATER
OutPort_3013708_7 | SOURCE | DUCT | EXHAUST
InPort_3013708_8 | SINK | PIPE | USERDEFINED
InPort_3013727_1 | SINK | PIPE | DOMESTICHOTWATER | Group: Domestic Hot Water 265
OutPort_3013745_5 | SOURCE | DUCT | VENTILATION
InPort_3013755_4 | SINK | PIPE | DOMESTICHOTWATER | Group: Domestic Hot Water 267
OutPort_3013760_0 | SOURCE | PIPE | DOMESTICHOTWATER | Group: Domestic Hot Water 267
OutPort_3013755_5 | SOURCE | PIPE | DOMESTICHOTWATER
InPort_3013755_6 | SINK | PIPE | DOMESTICCOLDWATER
OutPort_3013755_7 | SOURCE | DUCT | EXHAUST
InPort_3013755_8 | SINK | PIPE | USERDEFINED
InPort_3013774_1 | SINK | PIPE | DOMESTICHOTWATER | Group: Domestic Hot Water 267
OutPort_3013791_5 | SOURCE | DUCT | VENTILATION
InPort_3013801_4 | SINK | PIPE | DOMESTICHOTWATER | Group: Domestic Hot Water 269
OutPort_3013806_0 | SOURCE | PIPE | DOMESTICHOTWATER | Group: Domestic Hot Water 269
OutPort_3013801_5 | SOURCE | PIPE | DOMESTICHOTWATER
InPort_3013801_6 | SINK | PIPE | DOMESTICCOLDWATER
OutPort_3013801_7 | SOURCE | DUCT | EXHAUST
InPort_3013801_8 | SINK | PIPE | USERDEFINED
InPort_3013820_1 | SINK | PIPE | DOMESTICHOTWATER | Group: Domestic Hot Water 269
OutPort_3013841_5 | SOURCE | DUCT | VENTILATION
InPort_3013851_4 | SINK | PIPE | DOMESTICHOTWATER | Group: Domestic Hot Water 271
OutPort_3013856_0 | SOURCE | PIPE | DOMESTICHOTWATER | Group: Domestic Hot Water 271
OutPort_3013851_5 | SOURCE | PIPE | DOMESTICHOTWATER
InPort_3013851_6 | SINK | PIPE | DOMESTICCOLDWATER
OutPort_3013851_7 | SOURCE | DUCT | EXHAUST
InPort_3013851_8 | SINK | PIPE | USERDEFINED
InPort_3013870_1 | SINK | PIPE | DOMESTICHOTWATER | Group: Domestic Hot Water 271
OutPort_3013887_5 | SOURCE | DUCT | VENTILATION
InPort_3013897_4 | SINK | PIPE | DOMESTICHOTWATER | Group: Domestic Hot Water 273
OutPort_3013902_0 | SOURCE | PIPE | DOMESTICHOTWATER | Group: Domestic Hot Water 273
OutPort_3013897_5 | SOURCE | PIPE | DOMESTICHOTWATER
InPort_3013897_6 | SINK | PIPE | DOMESTICCOLDWATER
OutPort_3013897_7 | SOURCE | DUCT | EXHAUST
InPort_3013897_8 | SINK | PIPE | USERDEFINED
InPort_3013916_1 | SINK | PIPE | DOMESTICHOTWATER | Group: Domestic Hot Water 273
OutPort_3013933_5 | SOURCE | DUCT | VENTILATION
InPort_3013943_4 | SINK | PIPE | DOMESTICHOTWATER | Group: Domestic Hot Water 275
OutPort_3013948_0 | SOURCE | PIPE | DOMESTICHOTWATER | Group: Domestic Hot Water 275
OutPort_3013943_5 | SOURCE | PIPE | DOMESTICHOTWATER
InPort_3013943_6 | SINK | PIPE | DOMESTICCOLDWATER
OutPort_3013943_7 | SOURCE | DUCT | EXHAUST
InPort_3013943_8 | SINK | PIPE | USERDEFINED
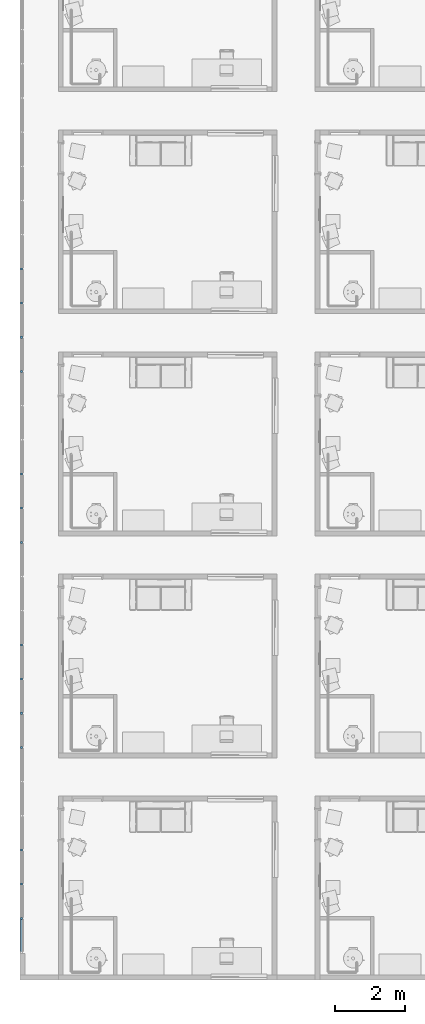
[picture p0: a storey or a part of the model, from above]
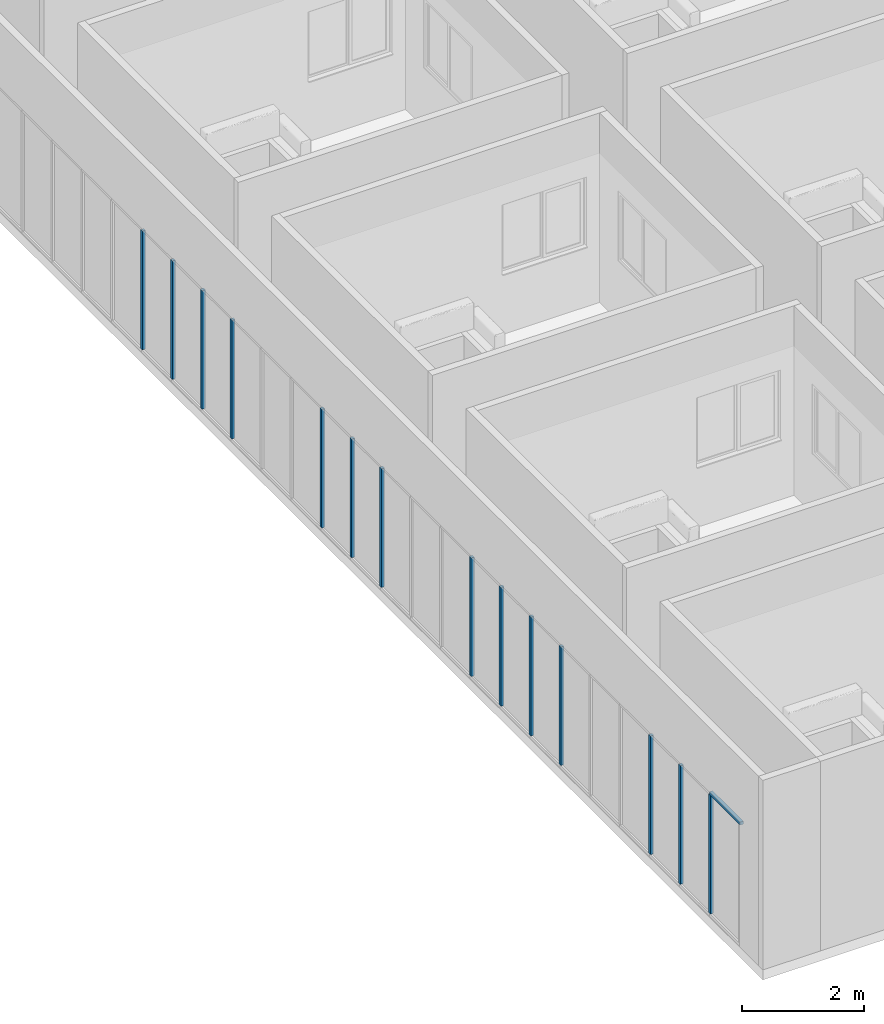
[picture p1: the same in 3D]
Properties of the parts of a building model (IFC4), part 5 of 14

# IfcDistributionPort (2240)
Name | FlowDirection | PredefinedType | SystemType
InPort_3013962_1 | SINK | PIPE | DOMESTICHOTWATER | Group: Domestic Hot Water 275
OutPort_3013979_5 | SOURCE | DUCT | VENTILATION
InPort_3013989_4 | SINK | PIPE | DOMESTICHOTWATER | Group: Domestic Hot Water 277
OutPort_3013994_0 | SOURCE | PIPE | DOMESTICHOTWATER | Group: Domestic Hot Water 277
OutPort_3013989_5 | SOURCE | PIPE | DOMESTICHOTWATER
InPort_3013989_6 | SINK | PIPE | DOMESTICCOLDWATER
OutPort_3013989_7 | SOURCE | DUCT | EXHAUST
InPort_3013989_8 | SINK | PIPE | USERDEFINED
InPort_3014008_1 | SINK | PIPE | DOMESTICHOTWATER | Group: Domestic Hot Water 277
OutPort_3014025_5 | SOURCE | DUCT | VENTILATION
InPort_3014035_4 | SINK | PIPE | DOMESTICHOTWATER | Group: Domestic Hot Water 279
OutPort_3014040_0 | SOURCE | PIPE | DOMESTICHOTWATER | Group: Domestic Hot Water 279
OutPort_3014035_5 | SOURCE | PIPE | DOMESTICHOTWATER
InPort_3014035_6 | SINK | PIPE | DOMESTICCOLDWATER
OutPort_3014035_7 | SOURCE | DUCT | EXHAUST
InPort_3014035_8 | SINK | PIPE | USERDEFINED
InPort_3014054_1 | SINK | PIPE | DOMESTICHOTWATER | Group: Domestic Hot Water 279
OutPort_3014632_5 | SOURCE | DUCT | VENTILATION
InPort_3014642_4 | SINK | PIPE | DOMESTICHOTWATER | Group: Domestic Hot Water 99
OutPort_3014647_0 | SOURCE | PIPE | DOMESTICHOTWATER | Group: Domestic Hot Water 99
OutPort_3014642_5 | SOURCE | PIPE | DOMESTICHOTWATER
InPort_3014642_6 | SINK | PIPE | DOMESTICCOLDWATER
OutPort_3014642_7 | SOURCE | DUCT | EXHAUST
InPort_3014642_8 | SINK | PIPE | USERDEFINED
InPort_3014661_1 | SINK | PIPE | DOMESTICHOTWATER | Group: Domestic Hot Water 99
OutPort_3014678_5 | SOURCE | DUCT | VENTILATION
InPort_3014688_4 | SINK | PIPE | DOMESTICHOTWATER | Group: Domestic Hot Water 153
OutPort_3014693_0 | SOURCE | PIPE | DOMESTICHOTWATER | Group: Domestic Hot Water 153
OutPort_3014688_5 | SOURCE | PIPE | DOMESTICHOTWATER
InPort_3014688_6 | SINK | PIPE | DOMESTICCOLDWATER
OutPort_3014688_7 | SOURCE | DUCT | EXHAUST
InPort_3014688_8 | SINK | PIPE | USERDEFINED
InPort_3014707_1 | SINK | PIPE | DOMESTICHOTWATER | Group: Domestic Hot Water 153
OutPort_3014728_5 | SOURCE | DUCT | VENTILATION
InPort_3014738_4 | SINK | PIPE | DOMESTICHOTWATER | Group: Domestic Hot Water 180
OutPort_3014743_0 | SOURCE | PIPE | DOMESTICHOTWATER | Group: Domestic Hot Water 180
OutPort_3014738_5 | SOURCE | PIPE | DOMESTICHOTWATER
InPort_3014738_6 | SINK | PIPE | DOMESTICCOLDWATER
OutPort_3014738_7 | SOURCE | DUCT | EXHAUST
InPort_3014738_8 | SINK | PIPE | USERDEFINED
InPort_3014757_1 | SINK | PIPE | DOMESTICHOTWATER | Group: Domestic Hot Water 180
OutPort_3014774_5 | SOURCE | DUCT | VENTILATION
InPort_3014784_4 | SINK | PIPE | DOMESTICHOTWATER | Group: Domestic Hot Water 196
OutPort_3014789_0 | SOURCE | PIPE | DOMESTICHOTWATER | Group: Domestic Hot Water 196
OutPort_3014784_5 | SOURCE | PIPE | DOMESTICHOTWATER
InPort_3014784_6 | SINK | PIPE | DOMESTICCOLDWATER
OutPort_3014784_7 | SOURCE | DUCT | EXHAUST
InPort_3014784_8 | SINK | PIPE | USERDEFINED
InPort_3014803_1 | SINK | PIPE | DOMESTICHOTWATER | Group: Domestic Hot Water 196
OutPort_3014820_5 | SOURCE | DUCT | VENTILATION
InPort_3014830_4 | SINK | PIPE | DOMESTICHOTWATER | Group: Domestic Hot Water 211
OutPort_3014835_0 | SOURCE | PIPE | DOMESTICHOTWATER | Group: Domestic Hot Water 211
OutPort_3014830_5 | SOURCE | PIPE | DOMESTICHOTWATER
InPort_3014830_6 | SINK | PIPE | DOMESTICCOLDWATER
OutPort_3014830_7 | SOURCE | DUCT | EXHAUST
InPort_3014830_8 | SINK | PIPE | USERDEFINED
InPort_3014849_1 | SINK | PIPE | DOMESTICHOTWATER | Group: Domestic Hot Water 211
OutPort_3014866_5 | SOURCE | DUCT | VENTILATION
InPort_3014876_4 | SINK | PIPE | DOMESTICHOTWATER | Group: Domestic Hot Water 219
OutPort_3014881_0 | SOURCE | PIPE | DOMESTICHOTWATER | Group: Domestic Hot Water 219
OutPort_3014876_5 | SOURCE | PIPE | DOMESTICHOTWATER
InPort_3014876_6 | SINK | PIPE | DOMESTICCOLDWATER
OutPort_3014876_7 | SOURCE | DUCT | EXHAUST
InPort_3014876_8 | SINK | PIPE | USERDEFINED
InPort_3014895_1 | SINK | PIPE | DOMESTICHOTWATER | Group: Domestic Hot Water 219
OutPort_3014912_5 | SOURCE | DUCT | VENTILATION
InPort_3014922_4 | SINK | PIPE | DOMESTICHOTWATER | Group: Domestic Hot Water 227
OutPort_3014927_0 | SOURCE | PIPE | DOMESTICHOTWATER | Group: Domestic Hot Water 227
OutPort_3014922_5 | SOURCE | PIPE | DOMESTICHOTWATER
InPort_3014922_6 | SINK | PIPE | DOMESTICCOLDWATER
OutPort_3014922_7 | SOURCE | DUCT | EXHAUST
InPort_3014922_8 | SINK | PIPE | USERDEFINED
InPort_3014941_1 | SINK | PIPE | DOMESTICHOTWATER | Group: Domestic Hot Water 227
OutPort_3014959_5 | SOURCE | DUCT | VENTILATION
InPort_3014969_4 | SINK | PIPE | DOMESTICHOTWATER | Group: Domestic Hot Water 235
OutPort_3014974_0 | SOURCE | PIPE | DOMESTICHOTWATER | Group: Domestic Hot Water 235
OutPort_3014969_5 | SOURCE | PIPE | DOMESTICHOTWATER
InPort_3014969_6 | SINK | PIPE | DOMESTICCOLDWATER
OutPort_3014969_7 | SOURCE | DUCT | EXHAUST
InPort_3014969_8 | SINK | PIPE | USERDEFINED
InPort_3014988_1 | SINK | PIPE | DOMESTICHOTWATER | Group: Domestic Hot Water 235
OutPort_3015005_5 | SOURCE | DUCT | VENTILATION
InPort_3015015_4 | SINK | PIPE | DOMESTICHOTWATER | Group: Domestic Hot Water 243
OutPort_3015020_0 | SOURCE | PIPE | DOMESTICHOTWATER | Group: Domestic Hot Water 243
OutPort_3015015_5 | SOURCE | PIPE | DOMESTICHOTWATER
InPort_3015015_6 | SINK | PIPE | DOMESTICCOLDWATER
OutPort_3015015_7 | SOURCE | DUCT | EXHAUST
InPort_3015015_8 | SINK | PIPE | USERDEFINED
InPort_3015034_1 | SINK | PIPE | DOMESTICHOTWATER | Group: Domestic Hot Water 243
OutPort_3015055_5 | SOURCE | DUCT | VENTILATION
InPort_3015065_4 | SINK | PIPE | DOMESTICHOTWATER | Group: Domestic Hot Water 248
OutPort_3015070_0 | SOURCE | PIPE | DOMESTICHOTWATER | Group: Domestic Hot Water 248
OutPort_3015065_5 | SOURCE | PIPE | DOMESTICHOTWATER
InPort_3015065_6 | SINK | PIPE | DOMESTICCOLDWATER
OutPort_3015065_7 | SOURCE | DUCT | EXHAUST
InPort_3015065_8 | SINK | PIPE | USERDEFINED
InPort_3015084_1 | SINK | PIPE | DOMESTICHOTWATER | Group: Domestic Hot Water 248
OutPort_3015101_5 | SOURCE | DUCT | VENTILATION
InPort_3015111_4 | SINK | PIPE | DOMESTICHOTWATER | Group: Domestic Hot Water 252
OutPort_3015116_0 | SOURCE | PIPE | DOMESTICHOTWATER | Group: Domestic Hot Water 252
OutPort_3015111_5 | SOURCE | PIPE | DOMESTICHOTWATER
InPort_3015111_6 | SINK | PIPE | DOMESTICCOLDWATER
OutPort_3015111_7 | SOURCE | DUCT | EXHAUST
InPort_3015111_8 | SINK | PIPE | USERDEFINED
InPort_3015130_1 | SINK | PIPE | DOMESTICHOTWATER | Group: Domestic Hot Water 252
OutPort_3015147_5 | SOURCE | DUCT | VENTILATION
InPort_3015157_4 | SINK | PIPE | DOMESTICHOTWATER | Group: Domestic Hot Water 256
OutPort_3015162_0 | SOURCE | PIPE | DOMESTICHOTWATER | Group: Domestic Hot Water 256
OutPort_3015157_5 | SOURCE | PIPE | DOMESTICHOTWATER
InPort_3015157_6 | SINK | PIPE | DOMESTICCOLDWATER
OutPort_3015157_7 | SOURCE | DUCT | EXHAUST
InPort_3015157_8 | SINK | PIPE | USERDEFINED
InPort_3015176_1 | SINK | PIPE | DOMESTICHOTWATER | Group: Domestic Hot Water 256
OutPort_3015193_5 | SOURCE | DUCT | VENTILATION
InPort_3015203_4 | SINK | PIPE | DOMESTICHOTWATER | Group: Domestic Hot Water 260
OutPort_3015208_0 | SOURCE | PIPE | DOMESTICHOTWATER | Group: Domestic Hot Water 260
OutPort_3015203_5 | SOURCE | PIPE | DOMESTICHOTWATER
InPort_3015203_6 | SINK | PIPE | DOMESTICCOLDWATER
OutPort_3015203_7 | SOURCE | DUCT | EXHAUST
InPort_3015203_8 | SINK | PIPE | USERDEFINED
InPort_3015222_1 | SINK | PIPE | DOMESTICHOTWATER | Group: Domestic Hot Water 260
OutPort_3015239_5 | SOURCE | DUCT | VENTILATION
InPort_3015249_4 | SINK | PIPE | DOMESTICHOTWATER | Group: Domestic Hot Water 264
OutPort_3015254_0 | SOURCE | PIPE | DOMESTICHOTWATER | Group: Domestic Hot Water 264
OutPort_3015249_5 | SOURCE | PIPE | DOMESTICHOTWATER
InPort_3015249_6 | SINK | PIPE | DOMESTICCOLDWATER
OutPort_3015249_7 | SOURCE | DUCT | EXHAUST
InPort_3015249_8 | SINK | PIPE | USERDEFINED
InPort_3015268_1 | SINK | PIPE | DOMESTICHOTWATER | Group: Domestic Hot Water 264
OutPort_3015286_5 | SOURCE | DUCT | VENTILATION
InPort_3015296_4 | SINK | PIPE | DOMESTICHOTWATER | Group: Domestic Hot Water 268
OutPort_3015301_0 | SOURCE | PIPE | DOMESTICHOTWATER | Group: Domestic Hot Water 268
OutPort_3015296_5 | SOURCE | PIPE | DOMESTICHOTWATER
InPort_3015296_6 | SINK | PIPE | DOMESTICCOLDWATER
OutPort_3015296_7 | SOURCE | DUCT | EXHAUST
InPort_3015296_8 | SINK | PIPE | USERDEFINED
InPort_3015315_1 | SINK | PIPE | DOMESTICHOTWATER | Group: Domestic Hot Water 268
OutPort_3015332_5 | SOURCE | DUCT | VENTILATION
InPort_3015342_4 | SINK | PIPE | DOMESTICHOTWATER | Group: Domestic Hot Water 272
OutPort_3015347_0 | SOURCE | PIPE | DOMESTICHOTWATER | Group: Domestic Hot Water 272
OutPort_3015342_5 | SOURCE | PIPE | DOMESTICHOTWATER
InPort_3015342_6 | SINK | PIPE | DOMESTICCOLDWATER
OutPort_3015342_7 | SOURCE | DUCT | EXHAUST
InPort_3015342_8 | SINK | PIPE | USERDEFINED
InPort_3015361_1 | SINK | PIPE | DOMESTICHOTWATER | Group: Domestic Hot Water 272
OutPort_3015382_5 | SOURCE | DUCT | VENTILATION
InPort_3015392_4 | SINK | PIPE | DOMESTICHOTWATER | Group: Domestic Hot Water 276
OutPort_3015397_0 | SOURCE | PIPE | DOMESTICHOTWATER | Group: Domestic Hot Water 276
OutPort_3015392_5 | SOURCE | PIPE | DOMESTICHOTWATER
InPort_3015392_6 | SINK | PIPE | DOMESTICCOLDWATER
OutPort_3015392_7 | SOURCE | DUCT | EXHAUST
InPort_3015392_8 | SINK | PIPE | USERDEFINED
InPort_3015411_1 | SINK | PIPE | DOMESTICHOTWATER | Group: Domestic Hot Water 276
OutPort_3015428_5 | SOURCE | DUCT | VENTILATION
InPort_3015438_4 | SINK | PIPE | DOMESTICHOTWATER | Group: Domestic Hot Water 280
OutPort_3015443_0 | SOURCE | PIPE | DOMESTICHOTWATER | Group: Domestic Hot Water 280
OutPort_3015438_5 | SOURCE | PIPE | DOMESTICHOTWATER
InPort_3015438_6 | SINK | PIPE | DOMESTICCOLDWATER
OutPort_3015438_7 | SOURCE | DUCT | EXHAUST
InPort_3015438_8 | SINK | PIPE | USERDEFINED
InPort_3015457_1 | SINK | PIPE | DOMESTICHOTWATER | Group: Domestic Hot Water 280
OutPort_3015474_5 | SOURCE | DUCT | VENTILATION
InPort_3015484_4 | SINK | PIPE | DOMESTICHOTWATER | Group: Domestic Hot Water 282
OutPort_3015489_0 | SOURCE | PIPE | DOMESTICHOTWATER | Group: Domestic Hot Water 282
OutPort_3015484_5 | SOURCE | PIPE | DOMESTICHOTWATER
InPort_3015484_6 | SINK | PIPE | DOMESTICCOLDWATER
OutPort_3015484_7 | SOURCE | DUCT | EXHAUST
InPort_3015484_8 | SINK | PIPE | USERDEFINED
InPort_3015503_1 | SINK | PIPE | DOMESTICHOTWATER | Group: Domestic Hot Water 282
OutPort_3015520_5 | SOURCE | DUCT | VENTILATION
InPort_3015530_4 | SINK | PIPE | DOMESTICHOTWATER | Group: Domestic Hot Water 284
OutPort_3015535_0 | SOURCE | PIPE | DOMESTICHOTWATER | Group: Domestic Hot Water 284
OutPort_3015530_5 | SOURCE | PIPE | DOMESTICHOTWATER
InPort_3015530_6 | SINK | PIPE | DOMESTICCOLDWATER
OutPort_3015530_7 | SOURCE | DUCT | EXHAUST
InPort_3015530_8 | SINK | PIPE | USERDEFINED
InPort_3015549_1 | SINK | PIPE | DOMESTICHOTWATER | Group: Domestic Hot Water 284
OutPort_3015566_5 | SOURCE | DUCT | VENTILATION
InPort_3015576_4 | SINK | PIPE | DOMESTICHOTWATER | Group: Domestic Hot Water 286
OutPort_3015581_0 | SOURCE | PIPE | DOMESTICHOTWATER | Group: Domestic Hot Water 286
OutPort_3015576_5 | SOURCE | PIPE | DOMESTICHOTWATER
InPort_3015576_6 | SINK | PIPE | DOMESTICCOLDWATER
OutPort_3015576_7 | SOURCE | DUCT | EXHAUST
InPort_3015576_8 | SINK | PIPE | USERDEFINED
InPort_3015595_1 | SINK | PIPE | DOMESTICHOTWATER | Group: Domestic Hot Water 286
OutPort_3015613_5 | SOURCE | DUCT | VENTILATION
InPort_3015623_4 | SINK | PIPE | DOMESTICHOTWATER | Group: Domestic Hot Water 288
OutPort_3015628_0 | SOURCE | PIPE | DOMESTICHOTWATER | Group: Domestic Hot Water 288
OutPort_3015623_5 | SOURCE | PIPE | DOMESTICHOTWATER
InPort_3015623_6 | SINK | PIPE | DOMESTICCOLDWATER
OutPort_3015623_7 | SOURCE | DUCT | EXHAUST
InPort_3015623_8 | SINK | PIPE | USERDEFINED
InPort_3015642_1 | SINK | PIPE | DOMESTICHOTWATER | Group: Domestic Hot Water 288
OutPort_3015659_5 | SOURCE | DUCT | VENTILATION
InPort_3015669_4 | SINK | PIPE | DOMESTICHOTWATER | Group: Domestic Hot Water 290
OutPort_3015674_0 | SOURCE | PIPE | DOMESTICHOTWATER | Group: Domestic Hot Water 290
OutPort_3015669_5 | SOURCE | PIPE | DOMESTICHOTWATER
InPort_3015669_6 | SINK | PIPE | DOMESTICCOLDWATER
OutPort_3015669_7 | SOURCE | DUCT | EXHAUST
InPort_3015669_8 | SINK | PIPE | USERDEFINED
InPort_3015688_1 | SINK | PIPE | DOMESTICHOTWATER | Group: Domestic Hot Water 290
OutPort_3015709_5 | SOURCE | DUCT | VENTILATION
InPort_3015719_4 | SINK | PIPE | DOMESTICHOTWATER | Group: Domestic Hot Water 292
OutPort_3015724_0 | SOURCE | PIPE | DOMESTICHOTWATER | Group: Domestic Hot Water 292
OutPort_3015719_5 | SOURCE | PIPE | DOMESTICHOTWATER
InPort_3015719_6 | SINK | PIPE | DOMESTICCOLDWATER
OutPort_3015719_7 | SOURCE | DUCT | EXHAUST
InPort_3015719_8 | SINK | PIPE | USERDEFINED
InPort_3015738_1 | SINK | PIPE | DOMESTICHOTWATER | Group: Domestic Hot Water 292
OutPort_3015755_5 | SOURCE | DUCT | VENTILATION
InPort_3015765_4 | SINK | PIPE | DOMESTICHOTWATER | Group: Domestic Hot Water 294
OutPort_3015770_0 | SOURCE | PIPE | DOMESTICHOTWATER | Group: Domestic Hot Water 294
OutPort_3015765_5 | SOURCE | PIPE | DOMESTICHOTWATER
InPort_3015765_6 | SINK | PIPE | DOMESTICCOLDWATER
OutPort_3015765_7 | SOURCE | DUCT | EXHAUST
InPort_3015765_8 | SINK | PIPE | USERDEFINED
InPort_3015784_1 | SINK | PIPE | DOMESTICHOTWATER | Group: Domestic Hot Water 294
OutPort_3015801_5 | SOURCE | DUCT | VENTILATION
InPort_3015811_4 | SINK | PIPE | DOMESTICHOTWATER | Group: Domestic Hot Water 296
OutPort_3015816_0 | SOURCE | PIPE | DOMESTICHOTWATER | Group: Domestic Hot Water 296
OutPort_3015811_5 | SOURCE | PIPE | DOMESTICHOTWATER
InPort_3015811_6 | SINK | PIPE | DOMESTICCOLDWATER
OutPort_3015811_7 | SOURCE | DUCT | EXHAUST
InPort_3015811_8 | SINK | PIPE | USERDEFINED
InPort_3015830_1 | SINK | PIPE | DOMESTICHOTWATER | Group: Domestic Hot Water 296
OutPort_3015847_5 | SOURCE | DUCT | VENTILATION
InPort_3015857_4 | SINK | PIPE | DOMESTICHOTWATER | Group: Domestic Hot Water 298
OutPort_3015862_0 | SOURCE | PIPE | DOMESTICHOTWATER | Group: Domestic Hot Water 298
OutPort_3015857_5 | SOURCE | PIPE | DOMESTICHOTWATER
InPort_3015857_6 | SINK | PIPE | DOMESTICCOLDWATER
OutPort_3015857_7 | SOURCE | DUCT | EXHAUST
InPort_3015857_8 | SINK | PIPE | USERDEFINED
InPort_3015876_1 | SINK | PIPE | DOMESTICHOTWATER | Group: Domestic Hot Water 298
OutPort_3015893_5 | SOURCE | DUCT | VENTILATION
InPort_3015903_4 | SINK | PIPE | DOMESTICHOTWATER | Group: Domestic Hot Water 300
OutPort_3015908_0 | SOURCE | PIPE | DOMESTICHOTWATER | Group: Domestic Hot Water 300
OutPort_3015903_5 | SOURCE | PIPE | DOMESTICHOTWATER
InPort_3015903_6 | SINK | PIPE | DOMESTICCOLDWATER
OutPort_3015903_7 | SOURCE | DUCT | EXHAUST
InPort_3015903_8 | SINK | PIPE | USERDEFINED
InPort_3015922_1 | SINK | PIPE | DOMESTICHOTWATER | Group: Domestic Hot Water 300
OutPort_3015940_5 | SOURCE | DUCT | VENTILATION
InPort_3015950_4 | SINK | PIPE | DOMESTICHOTWATER | Group: Domestic Hot Water 302
OutPort_3015955_0 | SOURCE | PIPE | DOMESTICHOTWATER | Group: Domestic Hot Water 302
OutPort_3015950_5 | SOURCE | PIPE | DOMESTICHOTWATER
InPort_3015950_6 | SINK | PIPE | DOMESTICCOLDWATER
OutPort_3015950_7 | SOURCE | DUCT | EXHAUST
InPort_3015950_8 | SINK | PIPE | USERDEFINED
InPort_3015969_1 | SINK | PIPE | DOMESTICHOTWATER | Group: Domestic Hot Water 302
OutPort_3015986_5 | SOURCE | DUCT | VENTILATION
InPort_3015996_4 | SINK | PIPE | DOMESTICHOTWATER | Group: Domestic Hot Water 304
OutPort_3016001_0 | SOURCE | PIPE | DOMESTICHOTWATER | Group: Domestic Hot Water 304
OutPort_3015996_5 | SOURCE | PIPE | DOMESTICHOTWATER
InPort_3015996_6 | SINK | PIPE | DOMESTICCOLDWATER
OutPort_3015996_7 | SOURCE | DUCT | EXHAUST
InPort_3015996_8 | SINK | PIPE | USERDEFINED
InPort_3016015_1 | SINK | PIPE | DOMESTICHOTWATER | Group: Domestic Hot Water 304
OutPort_3016036_5 | SOURCE | DUCT | VENTILATION
InPort_3016046_4 | SINK | PIPE | DOMESTICHOTWATER | Group: Domestic Hot Water 306
OutPort_3016051_0 | SOURCE | PIPE | DOMESTICHOTWATER | Group: Domestic Hot Water 306
OutPort_3016046_5 | SOURCE | PIPE | DOMESTICHOTWATER
InPort_3016046_6 | SINK | PIPE | DOMESTICCOLDWATER
OutPort_3016046_7 | SOURCE | DUCT | EXHAUST
InPort_3016046_8 | SINK | PIPE | USERDEFINED
InPort_3016065_1 | SINK | PIPE | DOMESTICHOTWATER | Group: Domestic Hot Water 306
OutPort_3016082_5 | SOURCE | DUCT | VENTILATION
InPort_3016092_4 | SINK | PIPE | DOMESTICHOTWATER | Group: Domestic Hot Water 308
OutPort_3016097_0 | SOURCE | PIPE | DOMESTICHOTWATER | Group: Domestic Hot Water 308
OutPort_3016092_5 | SOURCE | PIPE | DOMESTICHOTWATER
InPort_3016092_6 | SINK | PIPE | DOMESTICCOLDWATER
OutPort_3016092_7 | SOURCE | DUCT | EXHAUST
InPort_3016092_8 | SINK | PIPE | USERDEFINED
InPort_3016111_1 | SINK | PIPE | DOMESTICHOTWATER | Group: Domestic Hot Water 308
OutPort_3016128_5 | SOURCE | DUCT | VENTILATION
InPort_3016138_4 | SINK | PIPE | DOMESTICHOTWATER | Group: Domestic Hot Water 310
OutPort_3016143_0 | SOURCE | PIPE | DOMESTICHOTWATER | Group: Domestic Hot Water 310
OutPort_3016138_5 | SOURCE | PIPE | DOMESTICHOTWATER
InPort_3016138_6 | SINK | PIPE | DOMESTICCOLDWATER
OutPort_3016138_7 | SOURCE | DUCT | EXHAUST
InPort_3016138_8 | SINK | PIPE | USERDEFINED
InPort_3016157_1 | SINK | PIPE | DOMESTICHOTWATER | Group: Domestic Hot Water 310
OutPort_3016174_5 | SOURCE | DUCT | VENTILATION
InPort_3016184_4 | SINK | PIPE | DOMESTICHOTWATER | Group: Domestic Hot Water 312
OutPort_3016189_0 | SOURCE | PIPE | DOMESTICHOTWATER | Group: Domestic Hot Water 312
OutPort_3016184_5 | SOURCE | PIPE | DOMESTICHOTWATER
InPort_3016184_6 | SINK | PIPE | DOMESTICCOLDWATER
OutPort_3016184_7 | SOURCE | DUCT | EXHAUST
InPort_3016184_8 | SINK | PIPE | USERDEFINED
InPort_3016203_1 | SINK | PIPE | DOMESTICHOTWATER | Group: Domestic Hot Water 312
OutPort_3016220_5 | SOURCE | DUCT | VENTILATION
InPort_3016230_4 | SINK | PIPE | DOMESTICHOTWATER | Group: Domestic Hot Water 314
OutPort_3016235_0 | SOURCE | PIPE | DOMESTICHOTWATER | Group: Domestic Hot Water 314
OutPort_3016230_5 | SOURCE | PIPE | DOMESTICHOTWATER
InPort_3016230_6 | SINK | PIPE | DOMESTICCOLDWATER
OutPort_3016230_7 | SOURCE | DUCT | EXHAUST
InPort_3016230_8 | SINK | PIPE | USERDEFINED
InPort_3016249_1 | SINK | PIPE | DOMESTICHOTWATER | Group: Domestic Hot Water 314
InPort_3040234_4 | SINK | PIPE | DOMESTICHOTWATER
OutPort_3040234_5 | SOURCE | PIPE | DOMESTICHOTWATER
InPort_3040234_6 | SINK | PIPE | DOMESTICCOLDWATER
OutPort_3040234_7 | SOURCE | DUCT | EXHAUST
InPort_3040234_8 | SINK | PIPE | USERDEFINED

# IfcDistributionSystem: Domestic Hot Water (280)
PredefinedType: DOMESTICHOTWATER
Pset_DistributionSystemCommon - Reference: Domestic Hot Water
Name
Domestic Hot Water 1
Domestic Hot Water 2
Domestic Hot Water 4
Domestic Hot Water 6
Domestic Hot Water 8
Domestic Hot Water 10
Domestic Hot Water 12
Domestic Hot Water 3
Domestic Hot Water 7
Domestic Hot Water 11
Domestic Hot Water 14
Domestic Hot Water 16
Domestic Hot Water 18
Domestic Hot Water 20
Domestic Hot Water 22
Domestic Hot Water 24
Domestic Hot Water 26
Domestic Hot Water 28
Domestic Hot Water 30
Domestic Hot Water 32
Domestic Hot Water 34
Domestic Hot Water 36
Domestic Hot Water 38
Domestic Hot Water 40
Domestic Hot Water 42
Domestic Hot Water 44
Domestic Hot Water 46
Domestic Hot Water 48
Domestic Hot Water 50
Domestic Hot Water 52
Domestic Hot Water 54
Domestic Hot Water 56
Domestic Hot Water 58
Domestic Hot Water 60
Domestic Hot Water 62
Domestic Hot Water 5
Domestic Hot Water 13
Domestic Hot Water 17
Domestic Hot Water 21
Domestic Hot Water 25
Domestic Hot Water 29
Domestic Hot Water 33
Domestic Hot Water 37
Domestic Hot Water 41
Domestic Hot Water 45
Domestic Hot Water 49
Domestic Hot Water 53
Domestic Hot Water 57
Domestic Hot Water 61
Domestic Hot Water 64
Domestic Hot Water 66
Domestic Hot Water 68
Domestic Hot Water 70
Domestic Hot Water 72
Domestic Hot Water 74
Domestic Hot Water 76
Domestic Hot Water 78
Domestic Hot Water 80
Domestic Hot Water 82
Domestic Hot Water 84
Domestic Hot Water 86
Domestic Hot Water 88
Domestic Hot Water 90
Domestic Hot Water 92
Domestic Hot Water 94
Domestic Hot Water 96
Domestic Hot Water 98
Domestic Hot Water 100
Domestic Hot Water 102
Domestic Hot Water 104
Domestic Hot Water 9
Domestic Hot Water 19
Domestic Hot Water 27
Domestic Hot Water 35
Domestic Hot Water 43
Domestic Hot Water 51
Domestic Hot Water 59
Domestic Hot Water 65
Domestic Hot Water 69
Domestic Hot Water 73
Domestic Hot Water 77
Domestic Hot Water 81
Domestic Hot Water 85
Domestic Hot Water 89
Domestic Hot Water 93
Domestic Hot Water 97
Domestic Hot Water 101
Domestic Hot Water 105
Domestic Hot Water 107
Domestic Hot Water 109
Domestic Hot Water 111
Domestic Hot Water 113
Domestic Hot Water 115
Domestic Hot Water 117
Domestic Hot Water 119
Domestic Hot Water 121
Domestic Hot Water 123
Domestic Hot Water 125
Domestic Hot Water 127
Domestic Hot Water 129
Domestic Hot Water 131
Domestic Hot Water 133
Domestic Hot Water 135
Domestic Hot Water 137
Domestic Hot Water 139
Domestic Hot Water 15
Domestic Hot Water 31
Domestic Hot Water 47
Domestic Hot Water 63
Domestic Hot Water 71
Domestic Hot Water 79
Domestic Hot Water 87
Domestic Hot Water 95
Domestic Hot Water 103
Domestic Hot Water 108
Domestic Hot Water 112
Domestic Hot Water 116
Domestic Hot Water 120
Domestic Hot Water 124
Domestic Hot Water 128
Domestic Hot Water 132
Domestic Hot Water 136
Domestic Hot Water 140
Domestic Hot Water 142
Domestic Hot Water 144
Domestic Hot Water 146
Domestic Hot Water 148
Domestic Hot Water 150
Domestic Hot Water 152
Domestic Hot Water 154
Domestic Hot Water 156
Domestic Hot Water 158
Domestic Hot Water 160
Domestic Hot Water 162
Domestic Hot Water 164
Domestic Hot Water 166
Domestic Hot Water 168
Domestic Hot Water 170
Domestic Hot Water 172
Domestic Hot Water 174
Domestic Hot Water 23
Domestic Hot Water 55
Domestic Hot Water 75
Domestic Hot Water 91
Domestic Hot Water 106
Domestic Hot Water 114
Domestic Hot Water 122
Domestic Hot Water 130
Domestic Hot Water 138
Domestic Hot Water 143
Domestic Hot Water 147
Domestic Hot Water 151
Domestic Hot Water 155
Domestic Hot Water 159
Domestic Hot Water 163
Domestic Hot Water 167
Domestic Hot Water 171
Domestic Hot Water 175
Domestic Hot Water 177
Domestic Hot Water 179
Domestic Hot Water 181
Domestic Hot Water 183
Domestic Hot Water 185
Domestic Hot Water 187
Domestic Hot Water 189
Domestic Hot Water 191
Domestic Hot Water 193
Domestic Hot Water 195
Domestic Hot Water 197
Domestic Hot Water 199
Domestic Hot Water 201
Domestic Hot Water 203
Domestic Hot Water 205
Domestic Hot Water 207
Domestic Hot Water 209
Domestic Hot Water 39
Domestic Hot Water 83
Domestic Hot Water 110
Domestic Hot Water 126
Domestic Hot Water 141
Domestic Hot Water 149
Domestic Hot Water 157
Domestic Hot Water 165
Domestic Hot Water 173
Domestic Hot Water 178
Domestic Hot Water 182
Domestic Hot Water 186
Domestic Hot Water 190
Domestic Hot Water 194
Domestic Hot Water 198
Domestic Hot Water 202
Domestic Hot Water 206
Domestic Hot Water 210
Domestic Hot Water 212
Domestic Hot Water 214
Domestic Hot Water 216
Domestic Hot Water 218
Domestic Hot Water 220
Domestic Hot Water 222
Domestic Hot Water 224
Domestic Hot Water 226
Domestic Hot Water 228
Domestic Hot Water 230
Domestic Hot Water 232
Domestic Hot Water 234
Domestic Hot Water 236
Domestic Hot Water 238
Domestic Hot Water 240
Domestic Hot Water 242
Domestic Hot Water 244
Domestic Hot Water 67
Domestic Hot Water 118
Domestic Hot Water 145
Domestic Hot Water 161
Domestic Hot Water 176
Domestic Hot Water 184
Domestic Hot Water 192
Domestic Hot Water 200
Domestic Hot Water 208
Domestic Hot Water 213
Domestic Hot Water 217
Domestic Hot Water 221
Domestic Hot Water 225
Domestic Hot Water 229
Domestic Hot Water 233
Domestic Hot Water 237
Domestic Hot Water 241
Domestic Hot Water 245
Domestic Hot Water 247
Domestic Hot Water 249
Domestic Hot Water 251
Domestic Hot Water 253
Domestic Hot Water 255
Domestic Hot Water 257
Domestic Hot Water 259
Domestic Hot Water 261
Domestic Hot Water 263
Domestic Hot Water 265
Domestic Hot Water 267
Domestic Hot Water 269
Domestic Hot Water 271
Domestic Hot Water 273
Domestic Hot Water 275
Domestic Hot Water 277
Domestic Hot Water 279
Domestic Hot Water 99
Domestic Hot Water 153
Domestic Hot Water 180
Domestic Hot Water 196
Domestic Hot Water 211
Domestic Hot Water 219
Domestic Hot Water 227
Domestic Hot Water 235
Domestic Hot Water 243
Domestic Hot Water 248
Domestic Hot Water 252
Domestic Hot Water 256
Domestic Hot Water 260
Domestic Hot Water 264
Domestic Hot Water 268
Domestic Hot Water 272
Domestic Hot Water 276
Domestic Hot Water 280
Domestic Hot Water 282
Domestic Hot Water 284
Domestic Hot Water 286
Domestic Hot Water 288
Domestic Hot Water 290
Domestic Hot Water 292
Domestic Hot Water 294
Domestic Hot Water 296
Domestic Hot Water 298
Domestic Hot Water 300
Domestic Hot Water 302
Domestic Hot Water 304
Domestic Hot Water 306
Domestic Hot Water 308
Domestic Hot Water 310
Domestic Hot Water 312
Domestic Hot Water 314

# IfcDoor: ARC_32.30_DO_WB_binnendeur enkel draaiend met void_gen_BERSnl:Fire Exit_830x2115_EI60 (280)
Type - PredefinedType: DOOR; OperationType: SINGLE_SWING_RIGHT; Material: ARC_FME.i3_wood_00_gen_BERSnl
Type - ARC_32.30_DO_WB_binnendeur enkel draaiend met void_gen_BERSnl:Fire Exit_830x2115_EI60:2968559:1 - PanelOperation: SWINGING
Type - Pset_DoorCommon - FireRating: EI60
OverallHeight: 275 cm; OverallWidth: 90 cm
Pset_DoorCommon - IsExternal: no; Reference: Fire Exit_830x2115_EI60
Pset_EnvironmentalImpactIndicators - Reference: Fire Exit_830x2115_EI60
Qto_DoorBaseQuantities - Width: 90 cm; Height: 215 cm; Perimeter: 181 cm; Area: 1.935 m2
Name (ARC_32.30_DO_WB_binnendeur enkel draaiend met void_gen_BERSnl:Fire Exit_830x2115_EI60:...) | In | FireExit | bSI_C_TX_SuperSecretCode
2968559 | 00_Ground Floor | yes | G
2995747 | 00_Ground Floor | yes | G
2995856 | 00_Ground Floor | yes | G
2995915 | 00_Ground Floor | yes | G
2995974 | 00_Ground Floor | yes | G
2996033 | 00_Ground Floor | yes | G
2996092 | 00_Ground Floor | yes | G
2996159 | 00_Ground Floor | yes | G
2996214 | 00_Ground Floor | yes | G
2996273 | 00_Ground Floor | yes | G
2996328 | 00_Ground Floor | yes | G
2996383 | 00_Ground Floor | yes | G
2996438 | 00_Ground Floor | yes | G
2996493 | 00_Ground Floor | yes | G
2996603 | 00_Ground Floor | yes | G
2996658 | 00_Ground Floor | yes | G
2996717 | 00_Ground Floor | yes | G
2996772 | 00_Ground Floor | yes | G
2996827 | 00_Ground Floor | yes | G
2996882 | 00_Ground Floor | yes | G
2996937 | 00_Ground Floor | yes | G
2997009 | 00_Ground Floor | yes | G
2997064 | 00_Ground Floor | yes | G
2997123 | 00_Ground Floor | yes | G
2997178 | 00_Ground Floor | yes | G
2997233 | 00_Ground Floor | yes | G
2997288 | 00_Ground Floor | yes | G
2997343 | 00_Ground Floor | yes | G
2997415 | 00_Ground Floor | yes | G
2997470 | 00_Ground Floor | yes | G
2997529 | 00_Ground Floor | yes | G
2997584 | 00_Ground Floor | yes | G
2997639 | 00_Ground Floor | yes | G
2997694 | 00_Ground Floor | yes | G
2997749 | 00_Ground Floor | yes | G
3001448 | 01_First Floor | yes | O
3001495 | 01_First Floor | yes | O
3001546 | 01_First Floor | yes | O
3001593 | 01_First Floor | yes | O
3001640 | 01_First Floor | yes | O
3001687 | 01_First Floor | yes | O
3001734 | 01_First Floor | yes | O
3001782 | 01_First Floor | yes | O
3001828 | 01_First Floor | yes | O
3001878 | 01_First Floor | yes | O
3001924 | 01_First Floor | yes | O
3001970 | 01_First Floor | yes | O
3002016 | 01_First Floor | yes | O
3002062 | 01_First Floor | yes | O
3002109 | 01_First Floor | yes | O
3002155 | 01_First Floor | yes | O
3002205 | 01_First Floor | yes | O
3002251 | 01_First Floor | yes | O
3002297 | 01_First Floor | yes | O
3002343 | 01_First Floor | yes | O
3002389 | 01_First Floor | yes | O
3002436 | 01_First Floor | yes | O
3002482 | 01_First Floor | yes | O
3002532 | 01_First Floor | yes | O
3002578 | 01_First Floor | yes | O
3002624 | 01_First Floor | yes | O
3002670 | 01_First Floor | yes | O
3002716 | 01_First Floor | yes | O
3002763 | 01_First Floor | yes | O
3002809 | 01_First Floor | yes | O
3002859 | 01_First Floor | yes | O
3002905 | 01_First Floor | yes | O
3002951 | 01_First Floor | yes | O
3002997 | 01_First Floor | yes | O
3003043 | 01_First Floor | yes | O
3003652 | 02_Second Floor | yes | R
3003698 | 02_Second Floor | yes | R
3003748 | 02_Second Floor | yes | R
3003794 | 02_Second Floor | yes | R
3003840 | 02_Second Floor | yes | R
3003886 | 02_Second Floor | yes | R
3003932 | 02_Second Floor | yes | R
3003979 | 02_Second Floor | yes | R
3004025 | 02_Second Floor | yes | R
3004075 | 02_Second Floor | yes | R
3004121 | 02_Second Floor | yes | R
3004167 | 02_Second Floor | yes | R
3004213 | 02_Second Floor | yes | R
3004259 | 02_Second Floor | yes | R
3004306 | 02_Second Floor | yes | R
3004352 | 02_Second Floor | yes | R
3004402 | 02_Second Floor | yes | R
3004448 | 02_Second Floor | yes | R
3004494 | 02_Second Floor | yes | R
3004540 | 02_Second Floor | yes | R
3004586 | 02_Second Floor | yes | R
3004633 | 02_Second Floor | yes | R
3004679 | 02_Second Floor | yes | R
3004729 | 02_Second Floor | yes | R
3004775 | 02_Second Floor | yes | R
3004821 | 02_Second Floor | yes | R
3004867 | 02_Second Floor | yes | R
3004913 | 02_Second Floor | yes | R
3004960 | 02_Second Floor | yes | R
3005006 | 02_Second Floor | yes | R
3005056 | 02_Second Floor | yes | R
3005102 | 02_Second Floor | yes | R
3005148 | 02_Second Floor | yes | R
3005194 | 02_Second Floor | yes | R
3005240 | 02_Second Floor | yes | R
3005849 | 03_Third Floor | yes | Y
3005895 | 03_Third Floor | yes | Y
3005945 | 03_Third Floor | yes | Y
3005991 | 03_Third Floor | yes | Y
3006037 | 03_Third Floor | yes | Y
3006083 | 03_Third Floor | yes | Y
3006129 | 03_Third Floor | yes | Y
3006176 | 03_Third Floor | yes | Y
3006222 | 03_Third Floor | yes | Y
3006272 | 03_Third Floor | yes | Y
3006318 | 03_Third Floor | yes | Y
3006364 | 03_Third Floor | yes | Y
3006410 | 03_Third Floor | yes | Y
3006456 | 03_Third Floor | yes | Y
3006503 | 03_Third Floor | yes | Y
3006549 | 03_Third Floor | yes | Y
3006599 | 03_Third Floor | yes | Y
3006645 | 03_Third Floor | yes | Y
3006691 | 03_Third Floor | yes | Y
3006737 | 03_Third Floor | yes | Y
3006783 | 03_Third Floor | yes | Y
3006830 | 03_Third Floor | yes | Y
3006876 | 03_Third Floor | yes | Y
3006926 | 03_Third Floor | yes | Y
3006972 | 03_Third Floor | yes | Y
3007018 | 03_Third Floor | yes | Y
3007064 | 03_Third Floor | yes | Y
3007110 | 03_Third Floor | yes | Y
3007157 | 03_Third Floor | yes | Y
3007203 | 03_Third Floor | yes | Y
3007253 | 03_Third Floor | yes | Y
3007299 | 03_Third Floor | yes | Y
3007345 | 03_Third Floor | yes | Y
3007391 | 03_Third Floor | yes | Y
3007437 | 03_Third Floor | yes | Y
3008044 | 04_Fourth Floor | yes | B
3008090 | 04_Fourth Floor | yes | B
3008140 | 04_Fourth Floor | yes | B
3008186 | 04_Fourth Floor | yes | B
3008232 | 04_Fourth Floor | yes | B
3008278 | 04_Fourth Floor | yes | B
3008324 | 04_Fourth Floor | yes | B
3008371 | 04_Fourth Floor | yes | B
3008417 | 04_Fourth Floor | yes | B
3008467 | 04_Fourth Floor | yes | B
3008513 | 04_Fourth Floor | yes | B
3008559 | 04_Fourth Floor | yes | B
3008605 | 04_Fourth Floor | yes | B
3008651 | 04_Fourth Floor | yes | B
3008698 | 04_Fourth Floor | yes | B
3008744 | 04_Fourth Floor | yes | B
3008794 | 04_Fourth Floor | yes | B
3008840 | 04_Fourth Floor | yes | B
3008886 | 04_Fourth Floor | yes | B
3008932 | 04_Fourth Floor | yes | B
3008978 | 04_Fourth Floor | yes | B
3009025 | 04_Fourth Floor | yes | B
3009071 | 04_Fourth Floor | yes | B
3009121 | 04_Fourth Floor | yes | B
3009167 | 04_Fourth Floor | yes | B
3009213 | 04_Fourth Floor | yes | B
3009259 | 04_Fourth Floor | yes | B
3009305 | 04_Fourth Floor | yes | B
3009352 | 04_Fourth Floor | yes | B
3009398 | 04_Fourth Floor | yes | B
3009448 | 04_Fourth Floor | yes | B
3009494 | 04_Fourth Floor | yes | B
3009540 | 04_Fourth Floor | yes | B
3009586 | 04_Fourth Floor | yes | B
3009632 | 04_Fourth Floor | yes | B
3010239 | 05_Fifth Floor | yes | O
3010285 | 05_Fifth Floor | yes | O
3010335 | 05_Fifth Floor | yes | O
3010381 | 05_Fifth Floor | yes | O
3010427 | 05_Fifth Floor | yes | O
3010473 | 05_Fifth Floor | yes | O
3010519 | 05_Fifth Floor | yes | O
3010566 | 05_Fifth Floor | yes | O
3010612 | 05_Fifth Floor | yes | O
3010662 | 05_Fifth Floor | yes | O
3010708 | 05_Fifth Floor | yes | O
3010754 | 05_Fifth Floor | yes | O
3010800 | 05_Fifth Floor | yes | O
3010846 | 05_Fifth Floor | yes | O
3010893 | 05_Fifth Floor | yes | O
3010939 | 05_Fifth Floor | yes | O
3010989 | 05_Fifth Floor | yes | O
3011035 | 05_Fifth Floor | yes | O
3011081 | 05_Fifth Floor | yes | O
3011127 | 05_Fifth Floor | yes | O
3011173 | 05_Fifth Floor | yes | O
3011220 | 05_Fifth Floor | yes | O
3011266 | 05_Fifth Floor | yes | O
3011316 | 05_Fifth Floor | yes | O
3011362 | 05_Fifth Floor | yes | O
3011408 | 05_Fifth Floor | no | #FFA500
3011454 | 05_Fifth Floor | yes | O
3011500 | 05_Fifth Floor | yes | O
3011547 | 05_Fifth Floor | yes | O
3011593 | 05_Fifth Floor | yes | O
3011643 | 05_Fifth Floor | yes | O
3011689 | 05_Fifth Floor | yes | O
3011735 | 05_Fifth Floor | yes | O
3011781 | 05_Fifth Floor | yes | O
3011827 | 05_Fifth Floor | yes | O
3012436 | 06_Sixth Floor | yes | R
3012482 | 06_Sixth Floor | yes | R
3012532 | 06_Sixth Floor | yes | R
3012578 | 06_Sixth Floor | yes | R
3012624 | 06_Sixth Floor | yes | R
3012670 | 06_Sixth Floor | yes | R
3012716 | 06_Sixth Floor | yes | R
3012763 | 06_Sixth Floor | yes | R
3012809 | 06_Sixth Floor | yes | R
3012859 | 06_Sixth Floor | yes | R
3012905 | 06_Sixth Floor | yes | R
3012951 | 06_Sixth Floor | yes | R
3012997 | 06_Sixth Floor | yes | R
3013043 | 06_Sixth Floor | yes | R
3013090 | 06_Sixth Floor | yes | R
3013136 | 06_Sixth Floor | yes | R
3013186 | 06_Sixth Floor | yes | R
3013232 | 06_Sixth Floor | yes | R
3013278 | 06_Sixth Floor | yes | R
3013324 | 06_Sixth Floor | yes | R
3013370 | 06_Sixth Floor | yes | R
3013417 | 06_Sixth Floor | yes | R
3013463 | 06_Sixth Floor | yes | R
3013513 | 06_Sixth Floor | yes | R
3013559 | 06_Sixth Floor | yes | R
3013605 | 06_Sixth Floor | yes | R
3013651 | 06_Sixth Floor | yes | R
3013697 | 06_Sixth Floor | yes | R
3013744 | 06_Sixth Floor | yes | R
3013790 | 06_Sixth Floor | yes | R
3013840 | 06_Sixth Floor | yes | R
3013886 | 06_Sixth Floor | yes | R
3013932 | 06_Sixth Floor | yes | R
3013978 | 06_Sixth Floor | yes | R
3014024 | 06_Sixth Floor | yes | R
3014631 | 07_Seventh Floor | yes | P
3014677 | 07_Seventh Floor | yes | P
3014727 | 07_Seventh Floor | yes | P
3014773 | 07_Seventh Floor | yes | P
3014819 | 07_Seventh Floor | yes | P
3014865 | 07_Seventh Floor | yes | P
3014911 | 07_Seventh Floor | yes | P
3014958 | 07_Seventh Floor | yes | P
3015004 | 07_Seventh Floor | yes | P
3015054 | 07_Seventh Floor | yes | P
3015100 | 07_Seventh Floor | yes | P
3015146 | 07_Seventh Floor | yes | P
3015192 | 07_Seventh Floor | yes | P
3015238 | 07_Seventh Floor | yes | P
3015285 | 07_Seventh Floor | yes | P
3015331 | 07_Seventh Floor | yes | P
3015381 | 07_Seventh Floor | yes | P
3015427 | 07_Seventh Floor | yes | P
3015473 | 07_Seventh Floor | yes | P
3015519 | 07_Seventh Floor | yes | P
3015565 | 07_Seventh Floor | yes | P
3015612 | 07_Seventh Floor | yes | P
3015658 | 07_Seventh Floor | yes | P
3015708 | 07_Seventh Floor | yes | P
3015754 | 07_Seventh Floor | yes | P
3015800 | 07_Seventh Floor | yes | P
3015846 | 07_Seventh Floor | yes | P
3015892 | 07_Seventh Floor | yes | P
3015939 | 07_Seventh Floor | yes | P
3015985 | 07_Seventh Floor | yes | P
3016035 | 07_Seventh Floor | yes | P
3016081 | 07_Seventh Floor | yes | P
3016127 | 07_Seventh Floor | yes | P
3016173 | 07_Seventh Floor | yes | P
3016219 | 07_Seventh Floor | yes | P

# IfcDoor: ARC_32.30_DO_WB_binnendeur enkel draaiend met void_gen_BERSnl:hout_blokkader_830x2115_EI00 (280)
Type - PredefinedType: DOOR; OperationType: SINGLE_SWING_LEFT; Material: ARC_FME.i3_wood_00_gen_BERSnl
Type - ARC_32.30_DO_WB_binnendeur enkel draaiend met void_gen_BERSnl:hout_blokkader_830x2115_EI00:2949493:1 - PanelOperation: SWINGING
Type - Pset_DoorCommon - FireRating: EI60
OverallHeight: 275 cm; OverallWidth: 90 cm
Pset_DoorCommon - IsExternal: no; Reference: hout_blokkader_830x2115_EI00; FireExit: yes
Pset_EnvironmentalImpactIndicators - Reference: hout_blokkader_830x2115_EI00
Qto_DoorBaseQuantities - Width: 90 cm; Height: 215 cm; Perimeter: 181 cm; Area: 1.935 m2
Name (ARC_32.30_DO_WB_binnendeur enkel draaiend met void_gen_BERSnl:hout_blokkader_830x2115_EI00:...) | In
2949493 | 00_Ground Floor
2995740 | 00_Ground Floor
2995849 | 00_Ground Floor
2995908 | 00_Ground Floor
2995967 | 00_Ground Floor
2996026 | 00_Ground Floor
2996085 | 00_Ground Floor
2996152 | 00_Ground Floor
2996207 | 00_Ground Floor
2996266 | 00_Ground Floor
2996321 | 00_Ground Floor
2996376 | 00_Ground Floor
2996431 | 00_Ground Floor
2996486 | 00_Ground Floor
2996596 | 00_Ground Floor
2996651 | 00_Ground Floor
2996710 | 00_Ground Floor
2996765 | 00_Ground Floor
2996820 | 00_Ground Floor
2996875 | 00_Ground Floor
2996930 | 00_Ground Floor
2997002 | 00_Ground Floor
2997057 | 00_Ground Floor
2997116 | 00_Ground Floor
2997171 | 00_Ground Floor
2997226 | 00_Ground Floor
2997281 | 00_Ground Floor
2997336 | 00_Ground Floor
2997408 | 00_Ground Floor
2997463 | 00_Ground Floor
2997522 | 00_Ground Floor
2997577 | 00_Ground Floor
2997632 | 00_Ground Floor
2997687 | 00_Ground Floor
2997742 | 00_Ground Floor
3001441 | 01_First Floor
3001488 | 01_First Floor
3001539 | 01_First Floor
3001586 | 01_First Floor
3001633 | 01_First Floor
3001680 | 01_First Floor
3001727 | 01_First Floor
3001775 | 01_First Floor
3001821 | 01_First Floor
3001871 | 01_First Floor
3001917 | 01_First Floor
3001963 | 01_First Floor
3002009 | 01_First Floor
3002055 | 01_First Floor
3002102 | 01_First Floor
3002148 | 01_First Floor
3002198 | 01_First Floor
3002244 | 01_First Floor
3002290 | 01_First Floor
3002336 | 01_First Floor
3002382 | 01_First Floor
3002429 | 01_First Floor
3002475 | 01_First Floor
3002525 | 01_First Floor
3002571 | 01_First Floor
3002617 | 01_First Floor
3002663 | 01_First Floor
3002709 | 01_First Floor
3002756 | 01_First Floor
3002802 | 01_First Floor
3002852 | 01_First Floor
3002898 | 01_First Floor
3002944 | 01_First Floor
3002990 | 01_First Floor
3003036 | 01_First Floor
3003645 | 02_Second Floor
3003691 | 02_Second Floor
3003741 | 02_Second Floor
3003787 | 02_Second Floor
3003833 | 02_Second Floor
3003879 | 02_Second Floor
3003925 | 02_Second Floor
3003972 | 02_Second Floor
3004018 | 02_Second Floor
3004068 | 02_Second Floor
3004114 | 02_Second Floor
3004160 | 02_Second Floor
3004206 | 02_Second Floor
3004252 | 02_Second Floor
3004299 | 02_Second Floor
3004345 | 02_Second Floor
3004395 | 02_Second Floor
3004441 | 02_Second Floor
3004487 | 02_Second Floor
3004533 | 02_Second Floor
3004579 | 02_Second Floor
3004626 | 02_Second Floor
3004672 | 02_Second Floor
3004722 | 02_Second Floor
3004768 | 02_Second Floor
3004814 | 02_Second Floor
3004860 | 02_Second Floor
3004906 | 02_Second Floor
3004953 | 02_Second Floor
3004999 | 02_Second Floor
3005049 | 02_Second Floor
3005095 | 02_Second Floor
3005141 | 02_Second Floor
3005187 | 02_Second Floor
3005233 | 02_Second Floor
3005842 | 03_Third Floor
3005888 | 03_Third Floor
3005938 | 03_Third Floor
3005984 | 03_Third Floor
3006030 | 03_Third Floor
3006076 | 03_Third Floor
3006122 | 03_Third Floor
3006169 | 03_Third Floor
3006215 | 03_Third Floor
3006265 | 03_Third Floor
3006311 | 03_Third Floor
3006357 | 03_Third Floor
3006403 | 03_Third Floor
3006449 | 03_Third Floor
3006496 | 03_Third Floor
3006542 | 03_Third Floor
3006592 | 03_Third Floor
3006638 | 03_Third Floor
3006684 | 03_Third Floor
3006730 | 03_Third Floor
3006776 | 03_Third Floor
3006823 | 03_Third Floor
3006869 | 03_Third Floor
3006919 | 03_Third Floor
3006965 | 03_Third Floor
3007011 | 03_Third Floor
3007057 | 03_Third Floor
3007103 | 03_Third Floor
3007150 | 03_Third Floor
3007196 | 03_Third Floor
3007246 | 03_Third Floor
3007292 | 03_Third Floor
3007338 | 03_Third Floor
3007384 | 03_Third Floor
3007430 | 03_Third Floor
3008037 | 04_Fourth Floor
3008083 | 04_Fourth Floor
3008133 | 04_Fourth Floor
3008179 | 04_Fourth Floor
3008225 | 04_Fourth Floor
3008271 | 04_Fourth Floor
3008317 | 04_Fourth Floor
3008364 | 04_Fourth Floor
3008410 | 04_Fourth Floor
3008460 | 04_Fourth Floor
3008506 | 04_Fourth Floor
3008552 | 04_Fourth Floor
3008598 | 04_Fourth Floor
3008644 | 04_Fourth Floor
3008691 | 04_Fourth Floor
3008737 | 04_Fourth Floor
3008787 | 04_Fourth Floor
3008833 | 04_Fourth Floor
3008879 | 04_Fourth Floor
3008925 | 04_Fourth Floor
3008971 | 04_Fourth Floor
3009018 | 04_Fourth Floor
3009064 | 04_Fourth Floor
3009114 | 04_Fourth Floor
3009160 | 04_Fourth Floor
3009206 | 04_Fourth Floor
3009252 | 04_Fourth Floor
3009298 | 04_Fourth Floor
3009345 | 04_Fourth Floor
3009391 | 04_Fourth Floor
3009441 | 04_Fourth Floor
3009487 | 04_Fourth Floor
3009533 | 04_Fourth Floor
3009579 | 04_Fourth Floor
3009625 | 04_Fourth Floor
3010232 | 05_Fifth Floor
3010278 | 05_Fifth Floor
3010328 | 05_Fifth Floor
3010374 | 05_Fifth Floor
3010420 | 05_Fifth Floor
3010466 | 05_Fifth Floor
3010512 | 05_Fifth Floor
3010559 | 05_Fifth Floor
3010605 | 05_Fifth Floor
3010655 | 05_Fifth Floor
3010701 | 05_Fifth Floor
3010747 | 05_Fifth Floor
3010793 | 05_Fifth Floor
3010839 | 05_Fifth Floor
3010886 | 05_Fifth Floor
3010932 | 05_Fifth Floor
3010982 | 05_Fifth Floor
3011028 | 05_Fifth Floor
3011074 | 05_Fifth Floor
3011120 | 05_Fifth Floor
3011166 | 05_Fifth Floor
3011213 | 05_Fifth Floor
3011259 | 05_Fifth Floor
3011309 | 05_Fifth Floor
3011355 | 05_Fifth Floor
3011401 | 05_Fifth Floor
3011447 | 05_Fifth Floor
3011493 | 05_Fifth Floor
3011540 | 05_Fifth Floor
3011586 | 05_Fifth Floor
3011636 | 05_Fifth Floor
3011682 | 05_Fifth Floor
3011728 | 05_Fifth Floor
3011774 | 05_Fifth Floor
3011820 | 05_Fifth Floor
3012429 | 06_Sixth Floor
3012475 | 06_Sixth Floor
3012525 | 06_Sixth Floor
3012571 | 06_Sixth Floor
3012617 | 06_Sixth Floor
3012663 | 06_Sixth Floor
3012709 | 06_Sixth Floor
3012756 | 06_Sixth Floor
3012802 | 06_Sixth Floor
3012852 | 06_Sixth Floor
3012898 | 06_Sixth Floor
3012944 | 06_Sixth Floor
3012990 | 06_Sixth Floor
3013036 | 06_Sixth Floor
3013083 | 06_Sixth Floor
3013129 | 06_Sixth Floor
3013179 | 06_Sixth Floor
3013225 | 06_Sixth Floor
3013271 | 06_Sixth Floor
3013317 | 06_Sixth Floor
3013363 | 06_Sixth Floor
3013410 | 06_Sixth Floor
3013456 | 06_Sixth Floor
3013506 | 06_Sixth Floor
3013552 | 06_Sixth Floor
3013598 | 06_Sixth Floor
3013644 | 06_Sixth Floor
3013690 | 06_Sixth Floor
3013737 | 06_Sixth Floor
3013783 | 06_Sixth Floor
3013833 | 06_Sixth Floor
3013879 | 06_Sixth Floor
3013925 | 06_Sixth Floor
3013971 | 06_Sixth Floor
3014017 | 06_Sixth Floor
3014624 | 07_Seventh Floor
3014670 | 07_Seventh Floor
3014720 | 07_Seventh Floor
3014766 | 07_Seventh Floor
3014812 | 07_Seventh Floor
3014858 | 07_Seventh Floor
3014904 | 07_Seventh Floor
3014951 | 07_Seventh Floor
3014997 | 07_Seventh Floor
3015047 | 07_Seventh Floor
3015093 | 07_Seventh Floor
3015139 | 07_Seventh Floor
3015185 | 07_Seventh Floor
3015231 | 07_Seventh Floor
3015278 | 07_Seventh Floor
3015324 | 07_Seventh Floor
3015374 | 07_Seventh Floor
3015420 | 07_Seventh Floor
3015466 | 07_Seventh Floor
3015512 | 07_Seventh Floor
3015558 | 07_Seventh Floor
3015605 | 07_Seventh Floor
3015651 | 07_Seventh Floor
3015701 | 07_Seventh Floor
3015747 | 07_Seventh Floor
3015793 | 07_Seventh Floor
3015839 | 07_Seventh Floor
3015885 | 07_Seventh Floor
3015932 | 07_Seventh Floor
3015978 | 07_Seventh Floor
3016028 | 07_Seventh Floor
3016074 | 07_Seventh Floor
3016120 | 07_Seventh Floor
3016166 | 07_Seventh Floor
3016212 | 07_Seventh Floor

# IfcFurniture: BPL_82.11_CA_UN_kast_gen_BERSnl:type 1 (279)
Type - Material: <Unnamed>
Pset_EnvironmentalImpactIndicators - Reference: type 1; sets with these values: 2
Name (BPL_82.11_CA_UN_kast_gen_BERSnl:type 1:...) | In | bSI_C_TX_SuperSecretCode
2960721 | 1 | 4500
2995745 | 2 | 4501
2995854 | 3 | 4502
2995913 | 4 | 4503
2995972 | 5 | 4504
2996031 | 6 | 4505
2996090 | 7 | 4506
2996157 | 8 | 4507
2996212 | 9 | 4508
2996271 | 10 | 4509
2996326 | 11 | 4510
2996381 | 12 | 4511
2996436 | 13 | 4512
2996491 | 14 | 4513
2996601 | 15 | 4514
2996656 | 16 | 4515
2996715 | 17 | 4516
2996770 | 18 | 4517
2996825 | 19 | 4518
2996880 | 20 | 4519
2996935 | 21 | 4520
2997007 | 22 | 4521
2997062 | 23 | 4522
2997121 | 24 | 4523
2997176 | 25 | 4524
2997231 | 26 | 4525
2997286 | 27 | 4526
2997341 | 28 | 4527
2997413 | 29 | 4528
2997468 | 30 | 4529
2997527 | 31 | 4530
2997582 | 32 | 4531
2997637 | 33 | 4532
2997692 | 34 | 4533
2997747 | 35 | 4534
3001446 | 36 | 4535
3001493 | 37 | 4536
3001544 | 38 | 4537
3001591 | 39 | 4538
3001638 | 40 | 4539
3001685 | 41 | 4540
3001732 | 42 | 4541
3001780 | 43 | 4542
3001826 | 44 | 4543
3001876 | 45 | 4544
3001922 | 46 | 4545
3001968 | 47 | 4546
3002014 | 48 | 4547
3002060 | 49 | 4548
3002107 | 50 | 4549
3002153 | 51 | 4550
3002203 | 52 | 4551
3002249 | 53 | 4552
3002295 | 54 | 4553
3002341 | 55 | 4554
3002387 | 56 | 4555
3002434 | 57 | 4556
3002480 | 58 | 4557
3002530 | 59 | 4558
3002576 | 60 | 4559
3002622 | 61 | 4560
3002668 | 62 | 4561
3002714 | 63 | 4562
3002761 | 64 | 4563
3002807 | 65 | 4564
3002857 | 66 | 4565
3002903 | 67 | 4566
3002949 | 68 | 4567
3002995 | 69 | 4568
3003041 | 70 | 4569
3003650 | 71 | 4570
3003696 | 72 | 4571
3003746 | 73 | 4572
3003792 | 74 | 4573
3003838 | 75 | 4574
3003884 | 76 | 4575
3003930 | 77 | 4576
3003977 | 78 | 4577
3004023 | 79 | 4578
3004073 | 80 | 4579
3004119 | 81 | 4580
3004165 | 82 | 4581
3004211 | 83 | 4582
3004257 | 84 | 4583
3004304 | 85 | 4584
3004350 | 86 | 4585
3004400 | 87 | 4586
3004446 | 88 | 4587
3004492 | 89 | 4588
3004538 | 90 | 4589
3004584 | 91 | 4590
3004631 | 92 | 4591
3004677 | 93 | 4592
3004727 | 94 | 4593
3004773 | 95 | 4594
3004819 | 96 | 4595
3004865 | 97 | 4596
3004911 | 98 | 4597
3004958 | 99 | 4598
3005004 | 100 | 4599
3005054 | 101 | 4600
3005100 | 102 | 4601
3005146 | 103 | 4602
3005192 | 104 | 4603
3005238 | 105 | 4604
3005893 | 107 | 4606
3005943 | 108 | 4607
3005989 | 109 | 4608
3006035 | 110 | 4609
3006081 | 111 | 4610
3006127 | 112 | 4611
3006174 | 113 | 4612
3006220 | 114 | 4613
3006270 | 115 | 4614
3006316 | 116 | 4615
3006362 | 117 | 4616
3006408 | 118 | 4617
3006454 | 119 | 4618
3006501 | 120 | 4619
3006547 | 121 | 4620
3006597 | 122 | 4621
3006643 | 123 | 4622
3006689 | 124 | 4623
3006735 | 125 | 4624
3006781 | 126 | 4625
3006828 | 127 | 4626
3006874 | 128 | 4627
3006924 | 129 | 4628
3006970 | 130 | 4629
3007016 | 131 | 4630
3007062 | 132 | 4631
3007108 | 133 | 4632
3007155 | 134 | 4633
3007201 | 135 | 4634
3007251 | 136 | 4635
3007297 | 137 | 4636
3007343 | 138 | 4637
3007389 | 139 | 4638
3007435 | 140 | 4639
3008042 | 141 | 4640
3008088 | 142 | 4641
3008138 | 143 | 4642
3008184 | 144 | 4643
3008230 | 145 | 4644
3008276 | 146 | 4645
3008322 | 147 | 4646
3008369 | 148 | 4647
3008415 | 149 | 4648
3008465 | 150 | 4649
3008511 | 151 | 4650
3008557 | 152 | 4651
3008603 | 153 | 4652
3008649 | 154 | 4653
3008696 | 155 | 4654
3008742 | 156 | 4655
3008792 | 157 | 4656
3008838 | 158 | 4657
3008884 | 159 | 4658
3008930 | 160 | 4659
3008976 | 161 | 4660
3009023 | 162 | 4661
3009069 | 163 | 4662
3009119 | 164 | 4663
3009165 | 165 | 4664
3009211 | 166 | 4665
3009257 | 167 | 4666
3009303 | 168 | 4667
3009350 | 169 | 4668
3009396 | 170 | 4669
3009446 | 171 | 4670
3009492 | 172 | 4671
3009538 | 173 | 4672
3009584 | 174 | 4673
3009630 | 175 | 4674
3010237 | 176 | 4675
3010283 | 177 | 4676
3010333 | 178 | 4677
3010379 | 179 | 4678
3010425 | 180 | 4679
3010471 | 181 | 4680
3010517 | 182 | 4681
3010564 | 183 | 4682
3010610 | 184 | 4683
3010660 | 185 | 4684
3010706 | 186 | 4685
3010752 | 187 | 4686
3010798 | 188 | 4687
3010844 | 189 | 4688
3010891 | 190 | 4689
3010937 | 191 | 4690
3010987 | 192 | 4691
3011033 | 193 | 4692
3011079 | 194 | 4693
3011125 | 195 | 4694
3011171 | 196 | 4695
3011218 | 197 | 4696
3011264 | 198 | 4697
3011314 | 199 | 4698
3011360 | 200 | 4699
3011406 | 201 | 4700
3011452 | 202 | 4701
3011498 | 203 | 4702
3011545 | 204 | 4703
3011591 | 205 | 4704
3011641 | 206 | 4705
3011687 | 207 | 4706
3011733 | 208 | 4707
3011779 | 209 | 4708
3011825 | 210 | 4709
3012434 | 211 | 4710
3012480 | 212 | 4711
3012530 | 213 | 4712
3012576 | 214 | 4713
3012622 | 215 | 4714
3012668 | 216 | 4715
3012714 | 217 | 4716
3012761 | 218 | 4717
3012807 | 219 | 4718
3012857 | 220 | 4719
3012903 | 221 | 4720
3012949 | 222 | 4721
3012995 | 223 | 4722
3013041 | 224 | 4723
3013088 | 225 | 4724
3013134 | 226 | 4725
3013184 | 227 | 4726
3013230 | 228 | 4727
3013276 | 229 | 4728
3013322 | 230 | 4729
3013368 | 231 | 4730
3013415 | 232 | 4731
3013461 | 233 | 4732
3013511 | 234 | 4733
3013557 | 235 | 4734
3013603 | 236 | 4735
3013649 | 237 | 4736
3013695 | 238 | 4737
3013742 | 239 | 4738
3013788 | 240 | 4739
3013838 | 241 | 4740
3013884 | 242 | 4741
3013930 | 243 | 4742
3013976 | 244 | 4743
3014022 | 245 | 4744
3014629 | 246 | 4745
3014675 | 247 | 4746
3014725 | 248 | 4747
3014771 | 249 | 4748
3014817 | 250 | 4749
3014863 | 251 | 4750
3014909 | 252 | 4751
3014956 | 253 | 4752
3015002 | 254 | 4753
3015052 | 255 | 4754
3015098 | 256 | 4755
3015144 | 257 | 4756
3015190 | 258 | 4757
3015236 | 259 | 4758
3015283 | 260 | 4759
3015329 | 261 | 4760
3015379 | 262 | 4761
3015425 | 263 | 4762
3015471 | 264 | 4763
3015517 | 265 | 4764
3015563 | 266 | 4765
3015610 | 267 | 4766
3015656 | 268 | 4767
3015706 | 269 | 4768
3015752 | 270 | 4769
3015798 | 271 | 4770
3015844 | 272 | 4771
3015890 | 273 | 4772
3015937 | 274 | 4773
3015983 | 275 | 4774
3016033 | 276 | 4775
3016079 | 277 | 4776
3016125 | 278 | 4777
3016171 | 279 | 4778
3016217 | 280 | 4779

# IfcFurniture: BPL_82.11_CA_UN_kast_gen_BERSnl:type 1, BPL_82.11_CA_UN_kast_gen_BERSnl:type 1:3005847
In: 106
Type - PredefinedType: FILECABINET; Material: <Unnamed>
Pset_EnvironmentalImpactIndicators - Reference: type 1; sets with these values: 2
cPset_IDSGame - bSI_C_TX_SuperSecretCode: 4605

# IfcFurniture: BPL_82.11_FU_WPB_bureau met stoel_gen_BERSnl:1200x800x750 (280)
Type - PredefinedType: DESK; Material: <Unnamed>
Pset_EnvironmentalImpactIndicators - Reference: 1200x800x750; sets with these values: 2
Name (BPL_82.11_FU_WPB_bureau met stoel_gen_BERSnl:1200x800x750:...) | In | bSI_C_TX_SuperSecretCode
2958787 | 1 | 4900
2995744 | 2 | 4901
2995853 | 3 | 4902
2995912 | 4 | 4903
2995971 | 5 | 4904
2996030 | 6 | 4905
2996089 | 7 | 4906
2996156 | 8 | 4907
2996211 | 9 | 4908
2996270 | 10 | 4909
2996325 | 11 | 4910
2996380 | 12 | 4911
2996435 | 13 | 4912
2996490 | 14 | 4913
2996600 | 15 | 4914
2996655 | 16 | 4915
2996714 | 17 | 4916
2996769 | 18 | 4917
2996824 | 19 | 4918
2996879 | 20 | 4919
2996934 | 21 | 4920
2997006 | 22 | 4921
2997061 | 23 | 4922
2997120 | 24 | 4923
2997175 | 25 | 4924
2997230 | 26 | 4925
2997285 | 27 | 4926
2997340 | 28 | 4927
2997412 | 29 | 4928
2997467 | 30 | 4929
2997526 | 31 | 4930
2997581 | 32 | 4931
2997636 | 33 | 4932
2997691 | 34 | 4933
2997746 | 35 | 4934
3001445 | 36 | 4935
3001492 | 37 | 4936
3001543 | 38 | 4937
3001590 | 39 | 4938
3001637 | 40 | 4939
3001684 | 41 | 4940
3001731 | 42 | 4941
3001779 | 43 | 4942
3001825 | 44 | 4943
3001875 | 45 | 4944
3001921 | 46 | 4945
3001967 | 47 | 4946
3002013 | 48 | 4947
3002059 | 49 | 4948
3002106 | 50 | 4949
3002152 | 51 | 4950
3002202 | 52 | 4951
3002248 | 53 | 4952
3002294 | 54 | 4953
3002340 | 55 | 4954
3002386 | 56 | 4955
3002433 | 57 | 4956
3002479 | 58 | 4957
3002529 | 59 | 4958
3002575 | 60 | 4959
3002621 | 61 | 4960
3002667 | 62 | 4961
3002713 | 63 | 4962
3002760 | 64 | 4963
3002806 | 65 | 4964
3002856 | 66 | 4965
3002902 | 67 | 4966
3002948 | 68 | 4967
3002994 | 69 | 4968
3003040 | 70 | 4969
3003649 | 71 | 4970
3003695 | 72 | 4971
3003745 | 73 | 4972
3003791 | 74 | 4973
3003837 | 75 | 4974
3003883 | 76 | 4975
3003929 | 77 | 4976
3003976 | 78 | 4977
3004022 | 79 | 4978
3004072 | 80 | 4979
3004118 | 81 | 4980
3004164 | 82 | 4981
3004210 | 83 | 4982
3004256 | 84 | 4983
3004303 | 85 | 4984
3004349 | 86 | 4985
3004399 | 87 | 4986
3004445 | 88 | 4987
3004491 | 89 | 4988
3004537 | 90 | 4989
3004583 | 91 | 4990
3004630 | 92 | 4991
3004676 | 93 | 4992
3004726 | 94 | 4993
3004772 | 95 | 4994
3004818 | 96 | 4995
3004864 | 97 | 4996
3004910 | 98 | 4997
3004957 | 99 | 4998
3005003 | 100 | 4999
3005053 | 101 | 5000
3005099 | 102 | 5001
3005145 | 103 | 5002
3005191 | 104 | 5003
3005237 | 105 | 5004
3005846 | 106 | 5005
3005892 | 107 | 5006
3005942 | 108 | 5007
3005988 | 109 | 5008
3006034 | 110 | 5009
3006080 | 111 | 5010
3006126 | 112 | 5011
3006173 | 113 | 5012
3006219 | 114 | 5013
3006269 | 115 | 5014
3006315 | 116 | 5015
3006361 | 117 | 5016
3006407 | 118 | 5017
3006453 | 119 | 5018
3006500 | 120 | 5019
3006546 | 121 | 5020
3006596 | 122 | 5021
3006642 | 123 | 5022
3006688 | 124 | 5023
3006734 | 125 | 5024
3006780 | 126 | 5025
3006827 | 127 | 5026
3006873 | 128 | 5027
3006923 | 129 | 5028
3006969 | 130 | 5029
3007015 | 131 | 5030
3007061 | 132 | 5031
3007107 | 133 | 5032
3007154 | 134 | 5033
3007200 | 135 | 5034
3007250 | 136 | 5035
3007296 | 137 | 5036
3007342 | 138 | 5037
3007388 | 139 | 5038
3007434 | 140 | 5039
3008041 | 141 | 5040
3008087 | 142 | 5041
3008137 | 143 | 5042
3008183 | 144 | 5043
3008229 | 145 | 5044
3008275 | 146 | 5045
3008321 | 147 | 5046
3008368 | 148 | 5047
3008414 | 149 | 5048
3008464 | 150 | 5049
3008510 | 151 | 5050
3008556 | 152 | 5051
3008602 | 153 | 5052
3008648 | 154 | 5053
3008695 | 155 | 5054
3008741 | 156 | 5055
3008791 | 157 | 5056
3008837 | 158 | 5057
3008883 | 159 | 5058
3008929 | 160 | 5059
3008975 | 161 | 5060
3009022 | 162 | 5061
3009068 | 163 | 5062
3009118 | 164 | 5063
3009164 | 165 | 5064
3009210 | 166 | 5065
3009256 | 167 | 5066
3009302 | 168 | 5067
3009349 | 169 | 5068
3009395 | 170 | 5069
3009445 | 171 | 5070
3009491 | 172 | 5071
3009537 | 173 | 5072
3009583 | 174 | 5073
3009629 | 175 | 5074
3010236 | 176 | 5075
3010282 | 177 | 5076
3010332 | 178 | 5077
3010378 | 179 | 5078
3010424 | 180 | 5079
3010470 | 181 | 5080
3010516 | 182 | 5081
3010563 | 183 | 5082
3010609 | 184 | 5083
3010659 | 185 | 5084
3010705 | 186 | 5085
3010751 | 187 | 5086
3010797 | 188 | 5087
3010843 | 189 | 5088
3010890 | 190 | 5089
3010936 | 191 | 5090
3010986 | 192 | 5091
3011032 | 193 | 5092
3011078 | 194 | 5093
3011124 | 195 | 5094
3011170 | 196 | 5095
3011217 | 197 | 5096
3011263 | 198 | 5097
3011313 | 199 | 5098
3011359 | 200 | 5099
3011405 | 201 | 5100
3011451 | 202 | 5101
3011497 | 203 | 5102
3011544 | 204 | 5103
3011590 | 205 | 5104
3011640 | 206 | 5105
3011686 | 207 | 5106
3011732 | 208 | 5107
3011778 | 209 | 5108
3011824 | 210 | 5109
3012433 | 211 | 5110
3012479 | 212 | 5111
3012529 | 213 | 5112
3012575 | 214 | 5113
3012621 | 215 | 5114
3012667 | 216 | 5115
3012713 | 217 | 5116
3012760 | 218 | 5117
3012806 | 219 | 5118
3012856 | 220 | 5119
3012902 | 221 | 5120
3012948 | 222 | 5121
3012994 | 223 | 5122
3013040 | 224 | 5123
3013087 | 225 | 5124
3013133 | 226 | 5125
3013183 | 227 | 5126
3013229 | 228 | 5127
3013275 | 229 | 5128
3013321 | 230 | 5129
3013367 | 231 | 5130
3013414 | 232 | 5131
3013460 | 233 | 5132
3013510 | 234 | 5133
3013556 | 235 | 5134
3013602 | 236 | 5135
3013648 | 237 | 5136
3013694 | 238 | 5137
3013741 | 239 | 5138
3013787 | 240 | 5139
3013837 | 241 | 5140
3013883 | 242 | 5141
3013929 | 243 | 5142
3013975 | 244 | 5143
3014021 | 245 | 5144
3014628 | 246 | 5145
3014674 | 247 | 5146
3014724 | 248 | 5147
3014770 | 249 | 5148
3014816 | 250 | 5149
3014862 | 251 | 5150
3014908 | 252 | 5151
3014955 | 253 | 5152
3015001 | 254 | 5153
3015051 | 255 | 5154
3015097 | 256 | 5155
3015143 | 257 | 5156
3015189 | 258 | 5157
3015235 | 259 | 5158
3015282 | 260 | 5159
3015328 | 261 | 5160
3015378 | 262 | 5161
3015424 | 263 | 5162
3015470 | 264 | 5163
3015516 | 265 | 5164
3015562 | 266 | 5165
3015609 | 267 | 5166
3015655 | 268 | 5167
3015705 | 269 | 5168
3015751 | 270 | 5169
3015797 | 271 | 5170
3015843 | 272 | 5171
3015889 | 273 | 5172
3015936 | 274 | 5173
3015982 | 275 | 5174
3016032 | 276 | 5175
3016078 | 277 | 5176
3016124 | 278 | 5177
3016170 | 279 | 5178
3016216 | 280 | 5179

# IfcFurniture: BPL_82.11_FU_WPB_zetel 2 zit_gen_BERSnl:Type 1 (280)
Type - Material: <Unnamed>
Pset_EnvironmentalImpactIndicators - Reference: Type 1; sets with these values: 2
Name (BPL_82.11_FU_WPB_zetel 2 zit_gen_BERSnl:Type 1:...) | In | bSI_C_TX_SuperSecretCode
2955559 | 1 | 8500
2995742 | 2 | 8501
2995851 | 3 | 8502
2995910 | 4 | 8503
2995969 | 5 | 8504
2996028 | 6 | 8505
2996087 | 7 | 8506
2996154 | 8 | 8507
2996209 | 9 | 8508
2996268 | 10 | 8509
2996323 | 11 | 8510
2996378 | 12 | 8511
2996433 | 13 | 8512
2996488 | 14 | 8513
2996598 | 15 | 8514
2996653 | 16 | 8515
2996712 | 17 | 8516 | Classification: Pr_40_50_12_80 SofaBeds (Uniclass 2015)
2996767 | 18 | 8517
2996822 | 19 | 8518
2996877 | 20 | 8519
2996932 | 21 | 8520
2997004 | 22 | 8521
2997059 | 23 | 8522
2997118 | 24 | 8523
2997173 | 25 | 8524
2997228 | 26 | 8525
2997283 | 27 | 8526
2997338 | 28 | 8527
2997410 | 29 | 8528
2997465 | 30 | 8529
2997524 | 31 | 8530
2997579 | 32 | 8531
2997634 | 33 | 8532
2997689 | 34 | 8533
2997744 | 35 | 8534
3001443 | 36 | 8535
3001490 | 37 | 8536
3001541 | 38 | 8537
3001588 | 39 | 8538
3001635 | 40 | 8539
3001682 | 41 | 8540
3001729 | 42 | 8541
3001777 | 43 | 8542
3001823 | 44 | 8543
3001873 | 45 | 8544
3001919 | 46 | 8545
3001965 | 47 | 8546
3002011 | 48 | 8547
3002057 | 49 | 8548
3002104 | 50 | 8549
3002150 | 51 | 8550
3002200 | 52 | 8551
3002246 | 53 | 8552
3002292 | 54 | 8553
3002338 | 55 | 8554
3002384 | 56 | 8555
3002431 | 57 | 8556
3002477 | 58 | 8557
3002527 | 59 | 8558
3002573 | 60 | 8559
3002619 | 61 | 8560
3002665 | 62 | 8561
3002711 | 63 | 8562
3002758 | 64 | 8563
3002804 | 65 | 8564
3002854 | 66 | 8565
3002900 | 67 | 8566
3002946 | 68 | 8567
3002992 | 69 | 8568
3003038 | 70 | 8569
3003647 | 71 | 8570
3003693 | 72 | 8571
3003743 | 73 | 8572
3003789 | 74 | 8573
3003835 | 75 | 8574
3003881 | 76 | 8575
3003927 | 77 | 8576
3003974 | 78 | 8577
3004020 | 79 | 8578
3004070 | 80 | 8579
3004116 | 81 | 8580
3004162 | 82 | 8581
3004208 | 83 | 8582
3004254 | 84 | 8583
3004301 | 85 | 8584
3004347 | 86 | 8585
3004397 | 87 | 8586
3004443 | 88 | 8587
3004489 | 89 | 8588
3004535 | 90 | 8589
3004581 | 91 | 8590
3004628 | 92 | 8591
3004674 | 93 | 8592
3004724 | 94 | 8593
3004770 | 95 | 8594
3004816 | 96 | 8595
3004862 | 97 | 8596
3004908 | 98 | 8597
3004955 | 99 | 8598
3005001 | 100 | 8599
3005051 | 101 | 8600
3005097 | 102 | 8601
3005143 | 103 | 8602
3005189 | 104 | 8603
3005235 | 105 | 8604
3005844 | 106 | 8605
3005890 | 107 | 8606
3005940 | 108 | 8607
3005986 | 109 | 8608
3006032 | 110 | 8609
3006078 | 111 | 8610
3006124 | 112 | 8611
3006171 | 113 | 8612
3006217 | 114 | 8613
3006267 | 115 | 8614
3006313 | 116 | 8615
3006359 | 117 | 8616
3006405 | 118 | 8617
3006451 | 119 | 8618
3006498 | 120 | 8619
3006544 | 121 | 8620
3006594 | 122 | 8621
3006640 | 123 | 8622
3006686 | 124 | 8623
3006732 | 125 | 8624
3006778 | 126 | 8625
3006825 | 127 | 8626
3006871 | 128 | 8627
3006921 | 129 | 8628
3006967 | 130 | 8629
3007013 | 131 | 8630
3007059 | 132 | 8631
3007105 | 133 | 8632
3007152 | 134 | 8633
3007198 | 135 | 8634
3007248 | 136 | 8635
3007294 | 137 | 8636
3007340 | 138 | 8637
3007386 | 139 | 8638
3007432 | 140 | 8639
3008039 | 141 | 8640
3008085 | 142 | 8641
3008135 | 143 | 8642
3008181 | 144 | 8643
3008227 | 145 | 8644
3008273 | 146 | 8645
3008319 | 147 | 8646
3008366 | 148 | 8647
3008412 | 149 | 8648
3008462 | 150 | 8649
3008508 | 151 | 8650
3008554 | 152 | 8651
3008600 | 153 | 8652
3008646 | 154 | 8653
3008693 | 155 | 8654
3008739 | 156 | 8655
3008789 | 157 | 8656
3008835 | 158 | 8657
3008881 | 159 | 8658
3008927 | 160 | 8659
3008973 | 161 | 8660
3009020 | 162 | 8661
3009066 | 163 | 8662
3009116 | 164 | 8663
3009162 | 165 | 8664
3009208 | 166 | 8665
3009254 | 167 | 8666
3009300 | 168 | 8667
3009347 | 169 | 8668
3009393 | 170 | 8669
3009443 | 171 | 8670
3009489 | 172 | 8671
3009535 | 173 | 8672
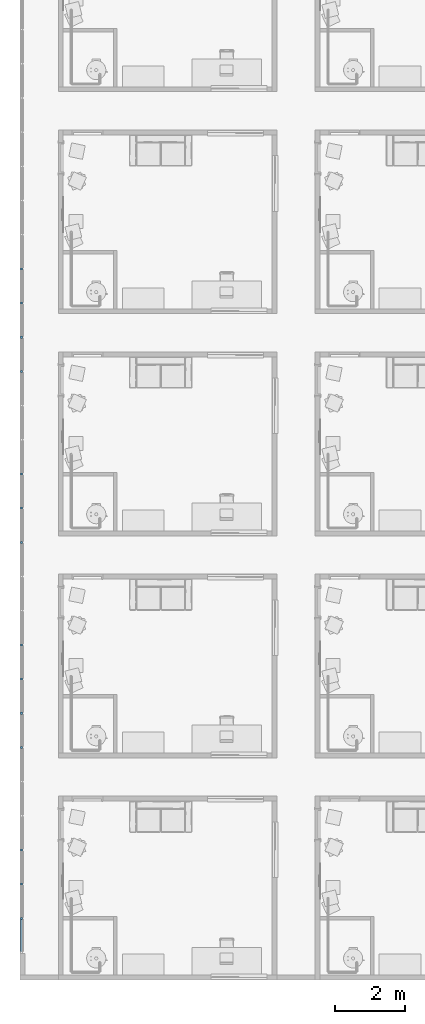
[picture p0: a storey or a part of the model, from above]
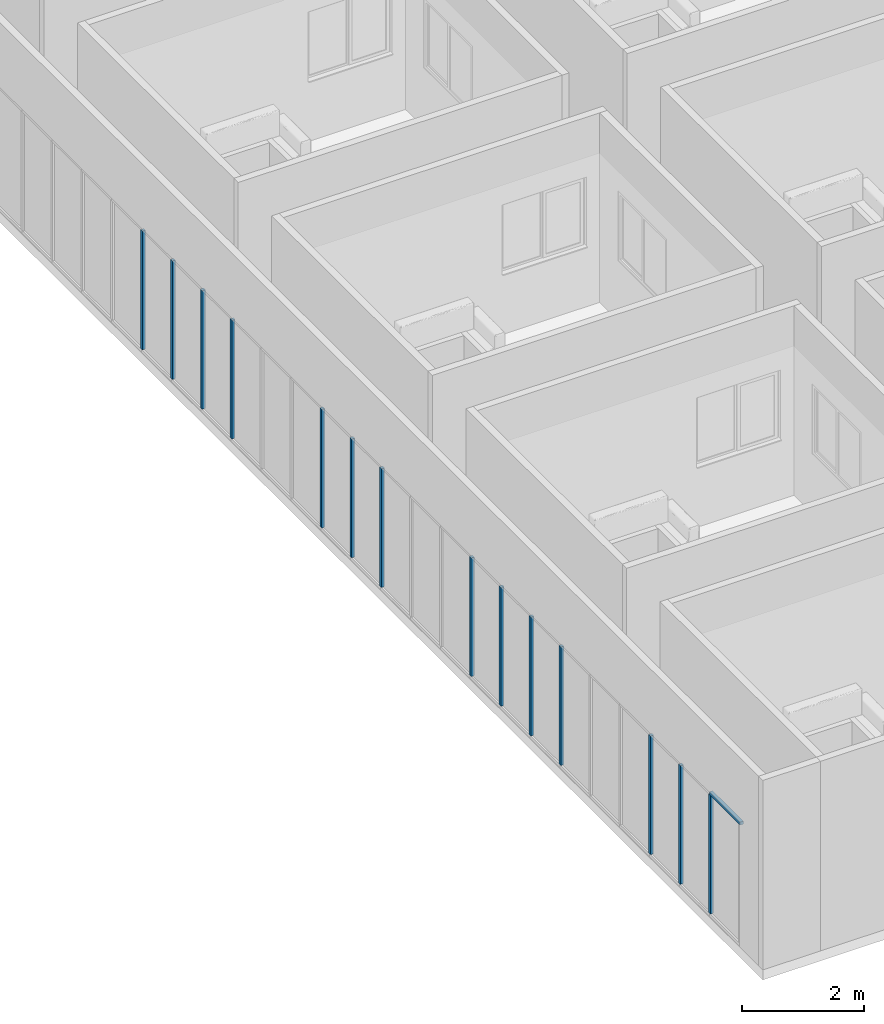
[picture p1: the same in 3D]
Properties of the parts of a building model (IFC4), part 6 of 14

# IfcFurniture: BPL_82.11_FU_WPB_zetel 2 zit_gen_BERSnl:Type 1 (280)
Name (BPL_82.11_FU_WPB_zetel 2 zit_gen_BERSnl:Type 1:...) | In | bSI_C_TX_SuperSecretCode
3009581 | 174 | 8673
3009627 | 175 | 8674
3010234 | 176 | 8675
3010280 | 177 | 8676
3010330 | 178 | 8677
3010376 | 179 | 8678
3010422 | 180 | 8679
3010468 | 181 | 8680
3010514 | 182 | 8681
3010561 | 183 | 8682
3010607 | 184 | 8683
3010657 | 185 | 8684
3010703 | 186 | 8685
3010749 | 187 | 8686
3010795 | 188 | 8687
3010841 | 189 | 8688
3010888 | 190 | 8689
3010934 | 191 | 8690
3010984 | 192 | 8691
3011030 | 193 | 8692
3011076 | 194 | 8693
3011122 | 195 | 8694
3011168 | 196 | 8695
3011215 | 197 | 8696
3011261 | 198 | 8697
3011311 | 199 | 8698
3011357 | 200 | 8699
3011403 | 201 | 8700
3011449 | 202 | 8701
3011495 | 203 | 8702
3011542 | 204 | 8703
3011588 | 205 | 8704
3011638 | 206 | 8705
3011684 | 207 | 8706
3011730 | 208 | 8707
3011776 | 209 | 8708
3011822 | 210 | 8709
3012431 | 211 | 8710
3012477 | 212 | 8711
3012527 | 213 | 8712
3012573 | 214 | 8713
3012619 | 215 | 8714
3012665 | 216 | 8715
3012711 | 217 | 8716
3012758 | 218 | 8717
3012804 | 219 | 8718
3012854 | 220 | 8719
3012900 | 221 | 8720
3012946 | 222 | 8721
3012992 | 223 | 8722
3013038 | 224 | 8723
3013085 | 225 | 8724
3013131 | 226 | 8725
3013181 | 227 | 8726
3013227 | 228 | 8727
3013273 | 229 | 8728
3013319 | 230 | 8729
3013365 | 231 | 8730
3013412 | 232 | 8731
3013458 | 233 | 8732
3013508 | 234 | 8733
3013554 | 235 | 8734
3013600 | 236 | 8735
3013646 | 237 | 8736
3013692 | 238 | 8737
3013739 | 239 | 8738
3013785 | 240 | 8739
3013835 | 241 | 8740
3013881 | 242 | 8741
3013927 | 243 | 8742
3013973 | 244 | 8743
3014019 | 245 | 8744
3014626 | 246 | 8745
3014672 | 247 | 8746
3014722 | 248 | 8747
3014768 | 249 | 8748
3014814 | 250 | 8749
3014860 | 251 | 8750
3014906 | 252 | 8751
3014953 | 253 | 8752
3014999 | 254 | 8753
3015049 | 255 | 8754
3015095 | 256 | 8755
3015141 | 257 | 8756
3015187 | 258 | 8757
3015233 | 259 | 8758
3015280 | 260 | 8759
3015326 | 261 | 8760
3015376 | 262 | 8761
3015422 | 263 | 8762
3015468 | 264 | 8763
3015514 | 265 | 8764
3015560 | 266 | 8765
3015607 | 267 | 8766
3015653 | 268 | 8767
3015703 | 269 | 8768
3015749 | 270 | 8769
3015795 | 271 | 8770
3015841 | 272 | 8771
3015887 | 273 | 8772
3015934 | 274 | 8773
3015980 | 275 | 8774
3016030 | 276 | 8775
3016076 | 277 | 8776
3016122 | 278 | 8777
3016168 | 279 | 8778
3016214 | 280 | 8779

# IfcFurniture: BPL_82.22_FU_WPB_laptop_gen_BERSnl:type 1 (280)
Type - Material: <Unnamed>
Pset_EnvironmentalImpactIndicators - Reference: type 1; sets with these values: 2
Name (BPL_82.22_FU_WPB_laptop_gen_BERSnl:type 1:...) | In
2965565 | 1
2995746 | 2
2995855 | 3
2995914 | 4
2995973 | 5
2996032 | 6
2996091 | 7
2996158 | 8
2996213 | 9
2996272 | 10
2996327 | 11
2996382 | 12
2996437 | 13
2996492 | 14
2996602 | 15
2996657 | 16
2996716 | 17
2996771 | 18
2996826 | 19
2996881 | 20
2996936 | 21
2997008 | 22
2997063 | 23
2997122 | 24
2997177 | 25
2997232 | 26
2997287 | 27
2997342 | 28
2997414 | 29
2997469 | 30
2997528 | 31
2997583 | 32
2997638 | 33
2997693 | 34
2997748 | 35
3001447 | 36
3001494 | 37
3001545 | 38
3001592 | 39
3001639 | 40
3001686 | 41
3001733 | 42
3001781 | 43
3001827 | 44
3001877 | 45
3001923 | 46
3001969 | 47
3002015 | 48
3002061 | 49
3002108 | 50
3002154 | 51
3002204 | 52
3002250 | 53
3002296 | 54
3002342 | 55
3002388 | 56
3002435 | 57
3002481 | 58
3002531 | 59
3002577 | 60
3002623 | 61
3002669 | 62
3002715 | 63
3002762 | 64
3002808 | 65
3002858 | 66
3002904 | 67
3002950 | 68
3002996 | 69
3003042 | 70
3003651 | 71
3003697 | 72
3003747 | 73
3003793 | 74
3003839 | 75
3003885 | 76
3003931 | 77
3003978 | 78
3004024 | 79
3004074 | 80
3004120 | 81
3004166 | 82
3004212 | 83
3004258 | 84
3004305 | 85
3004351 | 86
3004401 | 87
3004447 | 88
3004493 | 89
3004539 | 90
3004585 | 91
3004632 | 92
3004678 | 93
3004728 | 94
3004774 | 95
3004820 | 96
3004866 | 97
3004912 | 98
3004959 | 99
3005005 | 100
3005055 | 101
3005101 | 102
3005147 | 103
3005193 | 104
3005239 | 105
3005848 | 106
3005894 | 107
3005944 | 108
3005990 | 109
3006036 | 110
3006082 | 111
3006128 | 112
3006175 | 113
3006221 | 114
3006271 | 115
3006317 | 116
3006363 | 117
3006409 | 118
3006455 | 119
3006502 | 120
3006548 | 121
3006598 | 122
3006644 | 123
3006690 | 124
3006736 | 125
3006782 | 126
3006829 | 127
3006875 | 128
3006925 | 129
3006971 | 130
3007017 | 131
3007063 | 132
3007109 | 133
3007156 | 134
3007202 | 135
3007252 | 136
3007298 | 137
3007344 | 138
3007390 | 139
3007436 | 140
3008043 | 141
3008089 | 142
3008139 | 143
3008185 | 144
3008231 | 145
3008277 | 146
3008323 | 147
3008370 | 148
3008416 | 149
3008466 | 150
3008512 | 151
3008558 | 152
3008604 | 153
3008650 | 154
3008697 | 155
3008743 | 156
3008793 | 157
3008839 | 158
3008885 | 159
3008931 | 160
3008977 | 161
3009024 | 162
3009070 | 163
3009120 | 164
3009166 | 165
3009212 | 166
3009258 | 167
3009304 | 168
3009351 | 169
3009397 | 170
3009447 | 171
3009493 | 172
3009539 | 173
3009585 | 174
3009631 | 175
3010238 | 176
3010284 | 177
3010334 | 178
3010380 | 179
3010426 | 180
3010472 | 181
3010518 | 182
3010565 | 183
3010611 | 184
3010661 | 185
3010707 | 186
3010753 | 187
3010799 | 188
3010845 | 189
3010892 | 190
3010938 | 191
3010988 | 192
3011034 | 193
3011080 | 194
3011126 | 195
3011172 | 196
3011219 | 197
3011265 | 198
3011315 | 199
3011361 | 200
3011407 | 201
3011453 | 202
3011499 | 203
3011546 | 204
3011592 | 205
3011642 | 206
3011688 | 207
3011734 | 208
3011780 | 209
3011826 | 210
3012435 | 211
3012481 | 212
3012531 | 213
3012577 | 214
3012623 | 215
3012669 | 216
3012715 | 217
3012762 | 218
3012808 | 219
3012858 | 220
3012904 | 221
3012950 | 222
3012996 | 223
3013042 | 224
3013089 | 225
3013135 | 226
3013185 | 227
3013231 | 228
3013277 | 229
3013323 | 230
3013369 | 231
3013416 | 232
3013462 | 233
3013512 | 234
3013558 | 235
3013604 | 236
3013650 | 237
3013696 | 238
3013743 | 239
3013789 | 240
3013839 | 241
3013885 | 242
3013931 | 243
3013977 | 244
3014023 | 245
3014630 | 246
3014676 | 247
3014726 | 248
3014772 | 249
3014818 | 250
3014864 | 251
3014910 | 252
3014957 | 253
3015003 | 254
3015053 | 255
3015099 | 256
3015145 | 257
3015191 | 258
3015237 | 259
3015284 | 260
3015330 | 261
3015380 | 262
3015426 | 263
3015472 | 264
3015518 | 265
3015564 | 266
3015611 | 267
3015657 | 268
3015707 | 269
3015753 | 270
3015799 | 271
3015845 | 272
3015891 | 273
3015938 | 274
3015984 | 275
3016034 | 276
3016080 | 277
3016126 | 278
3016172 | 279
3016218 | 280

# IfcGroup: Model Group:Array Group 1 (35)
Name (Model Group:Array Group 1:...) | Group
3067993 | Model Group:Array Group 2:3068075
3067997 | Model Group:Array Group 2:3068075
3068053 | Model Group:Array Group 2:3068075
3068056 | Model Group:Array Group 2:3068075
3068059 | Model Group:Array Group 2:3068075
3068082 | Model Group:Array Group 2:3068095
3068084 | Model Group:Array Group 2:3068095
3068090 | Model Group:Array Group 2:3068095
3068092 | Model Group:Array Group 2:3068095
3068094 | Model Group:Array Group 2:3068095
3068151 | Model Group:Array Group 2:3068164
3068153 | Model Group:Array Group 2:3068164
3068159 | Model Group:Array Group 2:3068164
3068161 | Model Group:Array Group 2:3068164
3068163 | Model Group:Array Group 2:3068164
3068167 | Model Group:Array Group 2:3068180
3068169 | Model Group:Array Group 2:3068180
3068175 | Model Group:Array Group 2:3068180
3068177 | Model Group:Array Group 2:3068180
3068179 | Model Group:Array Group 2:3068180
3068183 | Model Group:Array Group 2:3068196
3068185 | Model Group:Array Group 2:3068196
3068191 | Model Group:Array Group 2:3068196
3068193 | Model Group:Array Group 2:3068196
3068195 | Model Group:Array Group 2:3068196
3068199 | Model Group:Array Group 2:3068212
3068201 | Model Group:Array Group 2:3068212
3068207 | Model Group:Array Group 2:3068212
3068209 | Model Group:Array Group 2:3068212
3068211 | Model Group:Array Group 2:3068212
3068215 | Model Group:Array Group 2:3068228
3068217 | Model Group:Array Group 2:3068228
3068223 | Model Group:Array Group 2:3068228
3068225 | Model Group:Array Group 2:3068228
3068227 | Model Group:Array Group 2:3068228

# IfcMember: Rectangular Mullion:30-_Stijl_Rechthoek_Midden_B60xD60 (1984)
Type - PredefinedType: MULLION; Material: <Unnamed>
Pset_EnvironmentalImpactIndicators - Reference: 30-_Stijl_Rechthoek_Midden_B60xD60
Pset_MemberCommon - IsExternal: yes; Reference: 30-_Stijl_Rechthoek_Midden_B60xD60
Name (Rectangular Mullion:30-_Stijl_Rechthoek_Midden_B60xD60:...) | In | Length (cm) | CrossSectionArea (m2) | NetSurfaceArea (m2) | NetVolume (m3)
3000530 | 00_Ground Floor | 102.843 | 0.127012 | 0.250424 | 0.00370235
3000531 | 00_Ground Floor | 102.843 | 0.127012 | 0.250424 | 0.00370235
3000532 | 00_Ground Floor | 99.8431 | 0.123412 | 0.239624 | 0.00359435
3000533 | 00_Ground Floor | 99.8431 | 0.123412 | 0.239624 | 0.00359435
3000534 | 00_Ground Floor | 99.8431 | 0.123412 | 0.239624 | 0.00359435
3000535 | 00_Ground Floor | 99.8431 | 0.123412 | 0.239624 | 0.00359435
3000536 | 00_Ground Floor | 99.8431 | 0.123412 | 0.239624 | 0.00359435
3000537 | 00_Ground Floor | 99.8431 | 0.123412 | 0.239624 | 0.00359435
3000538 | 00_Ground Floor | 99.8431 | 0.123412 | 0.239624 | 0.00359435
3000539 | 00_Ground Floor | 99.8431 | 0.123412 | 0.239624 | 0.00359435
3000540 | 00_Ground Floor | 99.8431 | 0.123412 | 0.239624 | 0.00359435
3000541 | 00_Ground Floor | 99.8431 | 0.123412 | 0.239624 | 0.00359435
3000542 | 00_Ground Floor | 99.8431 | 0.123412 | 0.239624 | 0.00359435
3000543 | 00_Ground Floor | 99.8431 | 0.123412 | 0.239624 | 0.00359435
3000544 | 00_Ground Floor | 99.8431 | 0.123412 | 0.239624 | 0.00359435
3000545 | 00_Ground Floor | 99.8431 | 0.123412 | 0.239624 | 0.00359435
3000546 | 00_Ground Floor | 99.8431 | 0.123412 | 0.239624 | 0.00359435
3000547 | 00_Ground Floor | 99.8431 | 0.123412 | 0.239624 | 0.00359435
3000548 | 00_Ground Floor | 99.8431 | 0.123412 | 0.239624 | 0.00359435
3000549 | 00_Ground Floor | 99.8431 | 0.123412 | 0.239624 | 0.00359435
3000550 | 00_Ground Floor | 99.8431 | 0.123412 | 0.239624 | 0.00359435
3000551 | 00_Ground Floor | 99.8431 | 0.123412 | 0.239624 | 0.00359435
3000552 | 00_Ground Floor | 99.8431 | 0.123412 | 0.239624 | 0.00359435
3000553 | 00_Ground Floor | 99.8431 | 0.123412 | 0.239624 | 0.00359435
3000554 | 00_Ground Floor | 99.8431 | 0.123412 | 0.239624 | 0.00359435
3000555 | 00_Ground Floor | 99.8431 | 0.123412 | 0.239624 | 0.00359435
3000556 | 00_Ground Floor | 99.8431 | 0.123412 | 0.239624 | 0.00359435
3000557 | 00_Ground Floor | 99.8431 | 0.123412 | 0.239624 | 0.00359435
3000558 | 00_Ground Floor | 99.8431 | 0.123412 | 0.239624 | 0.00359435
3000559 | 00_Ground Floor | 99.8431 | 0.123412 | 0.239624 | 0.00359435
3000560 | 00_Ground Floor | 99.8431 | 0.123412 | 0.239624 | 0.00359435
3000561 | 00_Ground Floor | 99.8431 | 0.123412 | 0.239624 | 0.00359435
3000562 | 00_Ground Floor | 99.8431 | 0.123412 | 0.239624 | 0.00359435
3000563 | 00_Ground Floor | 99.8431 | 0.123412 | 0.239624 | 0.00359435
3000564 | 00_Ground Floor | 99.8431 | 0.123412 | 0.239624 | 0.00359435
3000565 | 00_Ground Floor | 99.8431 | 0.123412 | 0.239624 | 0.00359435
3000566 | 00_Ground Floor | 99.8431 | 0.123412 | 0.239624 | 0.00359435
3000567 | 00_Ground Floor | 99.8431 | 0.123412 | 0.239624 | 0.00359435
3000568 | 00_Ground Floor | 99.8431 | 0.123412 | 0.239624 | 0.00359435
3000569 | 00_Ground Floor | 99.8431 | 0.123412 | 0.239624 | 0.00359435
3000570 | 00_Ground Floor | 99.8431 | 0.123412 | 0.239624 | 0.00359435
3000571 | 00_Ground Floor | 99.8431 | 0.123412 | 0.239624 | 0.00359435
3000572 | 00_Ground Floor | 99.8431 | 0.123412 | 0.239624 | 0.00359435
3000573 | 00_Ground Floor | 99.8431 | 0.123412 | 0.239624 | 0.00359435
3000574 | 00_Ground Floor | 99.8431 | 0.123412 | 0.239624 | 0.00359435
3000575 | 00_Ground Floor | 99.8431 | 0.123412 | 0.239624 | 0.00359435
3000576 | 00_Ground Floor | 99.8431 | 0.123412 | 0.239624 | 0.00359435
3000577 | 00_Ground Floor | 99.8431 | 0.123412 | 0.239624 | 0.00359435
3000578 | 00_Ground Floor | 99.8431 | 0.123412 | 0.239624 | 0.00359435
3000579 | 00_Ground Floor | 99.8431 | 0.123412 | 0.239624 | 0.00359435
3000580 | 00_Ground Floor | 99.8431 | 0.123412 | 0.239624 | 0.00359435
3000581 | 00_Ground Floor | 102.843 | 0.127012 | 0.250424 | 0.00370235
3000582 | 00_Ground Floor | 99.8431 | 0.123412 | 0.239624 | 0.00359435
3000583 | 00_Ground Floor | 99.8431 | 0.123412 | 0.239624 | 0.00359435
3000584 | 00_Ground Floor | 99.8431 | 0.123412 | 0.239624 | 0.00359435
3000585 | 00_Ground Floor | 99.8431 | 0.123412 | 0.239624 | 0.00359435
3000586 | 00_Ground Floor | 99.8431 | 0.123412 | 0.239624 | 0.00359435
3000587 | 00_Ground Floor | 99.8431 | 0.123412 | 0.239624 | 0.00359435
3000588 | 00_Ground Floor | 99.8431 | 0.123412 | 0.239624 | 0.00359435
3000589 | 00_Ground Floor | 99.8431 | 0.123412 | 0.239624 | 0.00359435
3000590 | 00_Ground Floor | 99.8431 | 0.123412 | 0.239624 | 0.00359435
3000591 | 00_Ground Floor | 99.8431 | 0.123412 | 0.239624 | 0.00359435
3000592 | 00_Ground Floor | 99.8431 | 0.123412 | 0.239624 | 0.00359435
3000593 | 00_Ground Floor | 99.8431 | 0.123412 | 0.239624 | 0.00359435
3000594 | 00_Ground Floor | 99.8431 | 0.123412 | 0.239624 | 0.00359435
3000595 | 00_Ground Floor | 99.8431 | 0.123412 | 0.239624 | 0.00359435
3000596 | 00_Ground Floor | 99.8431 | 0.123412 | 0.239624 | 0.00359435
3000597 | 00_Ground Floor | 99.8431 | 0.123412 | 0.239624 | 0.00359435
3000598 | 00_Ground Floor | 99.8431 | 0.123412 | 0.239624 | 0.00359435
3000599 | 00_Ground Floor | 99.8431 | 0.123412 | 0.239624 | 0.00359435
3000600 | 00_Ground Floor | 99.8431 | 0.123412 | 0.239624 | 0.00359435
3000601 | 00_Ground Floor | 99.8431 | 0.123412 | 0.239624 | 0.00359435
3000602 | 00_Ground Floor | 99.8431 | 0.123412 | 0.239624 | 0.00359435
3000603 | 00_Ground Floor | 99.8431 | 0.123412 | 0.239624 | 0.00359435
3000604 | 00_Ground Floor | 99.8431 | 0.123412 | 0.239624 | 0.00359435
3000605 | 00_Ground Floor | 99.8431 | 0.123412 | 0.239624 | 0.00359435
3000606 | 00_Ground Floor | 99.8431 | 0.123412 | 0.239624 | 0.00359435
3000607 | 00_Ground Floor | 99.8431 | 0.123412 | 0.239624 | 0.00359435
3000608 | 00_Ground Floor | 99.8431 | 0.123412 | 0.239624 | 0.00359435
3000609 | 00_Ground Floor | 99.8431 | 0.123412 | 0.239624 | 0.00359435
3000610 | 00_Ground Floor | 99.8431 | 0.123412 | 0.239624 | 0.00359435
3000611 | 00_Ground Floor | 99.8431 | 0.123412 | 0.239624 | 0.00359435
3000612 | 00_Ground Floor | 99.8431 | 0.123412 | 0.239624 | 0.00359435
3000613 | 00_Ground Floor | 99.8431 | 0.123412 | 0.239624 | 0.00359435
3000614 | 00_Ground Floor | 99.8431 | 0.123412 | 0.239624 | 0.00359435
3000615 | 00_Ground Floor | 99.8431 | 0.123412 | 0.239624 | 0.00359435
3000616 | 00_Ground Floor | 99.8431 | 0.123412 | 0.239624 | 0.00359435
3000617 | 00_Ground Floor | 99.8431 | 0.123412 | 0.239624 | 0.00359435
3000618 | 00_Ground Floor | 99.8431 | 0.123412 | 0.239624 | 0.00359435
3000619 | 00_Ground Floor | 99.8431 | 0.123412 | 0.239624 | 0.00359435
3000620 | 00_Ground Floor | 99.8431 | 0.123412 | 0.239624 | 0.00359435
3000621 | 00_Ground Floor | 99.8431 | 0.123412 | 0.239624 | 0.00359435
3000622 | 00_Ground Floor | 99.8431 | 0.123412 | 0.239624 | 0.00359435
3000623 | 00_Ground Floor | 99.8431 | 0.123412 | 0.239624 | 0.00359435
3000624 | 00_Ground Floor | 99.8431 | 0.123412 | 0.239624 | 0.00359435
3000625 | 00_Ground Floor | 99.8431 | 0.123412 | 0.239624 | 0.00359435
3000626 | 00_Ground Floor | 99.8431 | 0.123412 | 0.239624 | 0.00359435
3000627 | 00_Ground Floor | 99.8431 | 0.123412 | 0.239624 | 0.00359435
3000628 | 00_Ground Floor | 99.8431 | 0.123412 | 0.239624 | 0.00359435
3000629 | 00_Ground Floor | 99.8431 | 0.123412 | 0.239624 | 0.00359435
3000630 | 00_Ground Floor | 99.8431 | 0.123412 | 0.239624 | 0.00359435
3000631 | 00_Ground Floor | 102.843 | 0.127012 | 0.250424 | 0.00370235
3000632 | 00_Ground Floor | 238 | 0.2892 | 0.5784 | 0.008568
3000633 | 00_Ground Floor | 238 | 0.2892 | 0.5784 | 0.008568
3000634 | 00_Ground Floor | 238 | 0.2892 | 0.5784 | 0.008568
3000635 | 00_Ground Floor | 238 | 0.2892 | 0.5784 | 0.008568
3000636 | 00_Ground Floor | 238 | 0.2892 | 0.5784 | 0.008568
3000637 | 00_Ground Floor | 238 | 0.2892 | 0.5784 | 0.008568
3000638 | 00_Ground Floor | 238 | 0.2892 | 0.5784 | 0.008568
3000639 | 00_Ground Floor | 238 | 0.2892 | 0.5784 | 0.008568
3000640 | 00_Ground Floor | 238 | 0.2892 | 0.5784 | 0.008568
3000641 | 00_Ground Floor | 238 | 0.2892 | 0.5784 | 0.008568
3000642 | 00_Ground Floor | 238 | 0.2892 | 0.5784 | 0.008568
3000643 | 00_Ground Floor | 238 | 0.2892 | 0.5784 | 0.008568
3000644 | 00_Ground Floor | 238 | 0.2892 | 0.5784 | 0.008568
3000645 | 00_Ground Floor | 238 | 0.2892 | 0.5784 | 0.008568
3000646 | 00_Ground Floor | 238 | 0.2892 | 0.5784 | 0.008568
3000647 | 00_Ground Floor | 238 | 0.2892 | 0.5784 | 0.008568
3000648 | 00_Ground Floor | 238 | 0.2892 | 0.5784 | 0.008568
3000649 | 00_Ground Floor | 238 | 0.2892 | 0.5784 | 0.008568
3000650 | 00_Ground Floor | 238 | 0.2892 | 0.5784 | 0.008568
3000651 | 00_Ground Floor | 238 | 0.2892 | 0.5784 | 0.008568
3000652 | 00_Ground Floor | 238 | 0.2892 | 0.5784 | 0.008568
3000653 | 00_Ground Floor | 238 | 0.2892 | 0.5784 | 0.008568
3000654 | 00_Ground Floor | 238 | 0.2892 | 0.5784 | 0.008568
3000655 | 00_Ground Floor | 238 | 0.2892 | 0.5784 | 0.008568
3000656 | 00_Ground Floor | 238 | 0.2892 | 0.5784 | 0.008568
3000657 | 00_Ground Floor | 238 | 0.2892 | 0.5784 | 0.008568
3000658 | 00_Ground Floor | 238 | 0.2892 | 0.5784 | 0.008568
3000659 | 00_Ground Floor | 238 | 0.2892 | 0.5784 | 0.008568
3000660 | 00_Ground Floor | 238 | 0.2892 | 0.5784 | 0.008568
3000661 | 00_Ground Floor | 238 | 0.2892 | 0.5784 | 0.008568
3000662 | 00_Ground Floor | 238 | 0.2892 | 0.5784 | 0.008568
3000663 | 00_Ground Floor | 238 | 0.2892 | 0.5784 | 0.008568
3000664 | 00_Ground Floor | 238 | 0.2892 | 0.5784 | 0.008568
3000665 | 00_Ground Floor | 238 | 0.2892 | 0.5784 | 0.008568
3000666 | 00_Ground Floor | 238 | 0.2892 | 0.5784 | 0.008568
3000667 | 00_Ground Floor | 238 | 0.2892 | 0.5784 | 0.008568
3000668 | 00_Ground Floor | 238 | 0.2892 | 0.5784 | 0.008568
3000669 | 00_Ground Floor | 238 | 0.2892 | 0.5784 | 0.008568
3000670 | 00_Ground Floor | 238 | 0.2892 | 0.5784 | 0.008568
3000671 | 00_Ground Floor | 238 | 0.2892 | 0.5784 | 0.008568
3000672 | 00_Ground Floor | 238 | 0.2892 | 0.5784 | 0.008568
3000673 | 00_Ground Floor | 238 | 0.2892 | 0.5784 | 0.008568
3000674 | 00_Ground Floor | 238 | 0.2892 | 0.5784 | 0.008568
3000675 | 00_Ground Floor | 238 | 0.2892 | 0.5784 | 0.008568
3000676 | 00_Ground Floor | 238 | 0.2892 | 0.5784 | 0.008568
3000677 | 00_Ground Floor | 238 | 0.2892 | 0.5784 | 0.008568
3000678 | 00_Ground Floor | 238 | 0.2892 | 0.5784 | 0.008568
3000679 | 00_Ground Floor | 238 | 0.2892 | 0.5784 | 0.008568
3000680 | 00_Ground Floor | 238 | 0.2892 | 0.5784 | 0.008568
3000681 | 00_Ground Floor | 238 | 0.2892 | 0.5784 | 0.008568
3000682 | 00_Ground Floor | 238 | 0.2892 | 0.5784 | 0.008568
3000683 | 00_Ground Floor | 238 | 0.2892 | 0.5784 | 0.008568
3001125 | 00_Ground Floor | 101.194 | 0.125032 | 0.246465 | 0.00364297
3001126 | 00_Ground Floor | 101.194 | 0.125032 | 0.246465 | 0.00364297
3001127 | 00_Ground Floor | 98.1935 | 0.121432 | 0.235665 | 0.00353497
3001128 | 00_Ground Floor | 98.1935 | 0.121432 | 0.235665 | 0.00353497
3001129 | 00_Ground Floor | 98.1935 | 0.121432 | 0.235665 | 0.00353497
3001130 | 00_Ground Floor | 98.1935 | 0.121432 | 0.235665 | 0.00353497
3001131 | 00_Ground Floor | 98.1935 | 0.121432 | 0.235665 | 0.00353497
3001132 | 00_Ground Floor | 98.1935 | 0.121432 | 0.235665 | 0.00353497
3001133 | 00_Ground Floor | 98.1935 | 0.121432 | 0.235665 | 0.00353497
3001134 | 00_Ground Floor | 98.1935 | 0.121432 | 0.235665 | 0.00353497
3001135 | 00_Ground Floor | 98.1935 | 0.121432 | 0.235665 | 0.00353497
3001136 | 00_Ground Floor | 98.1935 | 0.121432 | 0.235665 | 0.00353497
3001137 | 00_Ground Floor | 98.1935 | 0.121432 | 0.235665 | 0.00353497
3001138 | 00_Ground Floor | 98.1935 | 0.121432 | 0.235665 | 0.00353497
3001139 | 00_Ground Floor | 98.1935 | 0.121432 | 0.235665 | 0.00353497
3001140 | 00_Ground Floor | 98.1935 | 0.121432 | 0.235665 | 0.00353497
3001141 | 00_Ground Floor | 98.1935 | 0.121432 | 0.235665 | 0.00353497
3001142 | 00_Ground Floor | 98.1935 | 0.121432 | 0.235665 | 0.00353497
3001143 | 00_Ground Floor | 98.1935 | 0.121432 | 0.235665 | 0.00353497
3001144 | 00_Ground Floor | 98.1935 | 0.121432 | 0.235665 | 0.00353497
3001145 | 00_Ground Floor | 98.1935 | 0.121432 | 0.235665 | 0.00353497
3001146 | 00_Ground Floor | 98.1935 | 0.121432 | 0.235665 | 0.00353497
3001147 | 00_Ground Floor | 98.1935 | 0.121432 | 0.235665 | 0.00353497
3001148 | 00_Ground Floor | 98.1935 | 0.121432 | 0.235665 | 0.00353497
3001149 | 00_Ground Floor | 98.1935 | 0.121432 | 0.235665 | 0.00353497
3001150 | 00_Ground Floor | 98.1935 | 0.121432 | 0.235665 | 0.00353497
3001151 | 00_Ground Floor | 98.1935 | 0.121432 | 0.235665 | 0.00353497
3001152 | 00_Ground Floor | 98.1935 | 0.121432 | 0.235665 | 0.00353497
3001153 | 00_Ground Floor | 98.1935 | 0.121432 | 0.235665 | 0.00353497
3001154 | 00_Ground Floor | 98.1935 | 0.121432 | 0.235665 | 0.00353497
3001155 | 00_Ground Floor | 98.1935 | 0.121432 | 0.235665 | 0.00353497
3001156 | 00_Ground Floor | 101.194 | 0.125032 | 0.246465 | 0.00364297
3001157 | 00_Ground Floor | 98.1935 | 0.121432 | 0.235665 | 0.00353497
3001158 | 00_Ground Floor | 98.1935 | 0.121432 | 0.235665 | 0.00353497
3001159 | 00_Ground Floor | 98.1935 | 0.121432 | 0.235665 | 0.00353497
3001160 | 00_Ground Floor | 98.1935 | 0.121432 | 0.235665 | 0.00353497
3001161 | 00_Ground Floor | 98.1935 | 0.121432 | 0.235665 | 0.00353497
3001162 | 00_Ground Floor | 98.1935 | 0.121432 | 0.235665 | 0.00353497
3001163 | 00_Ground Floor | 98.1935 | 0.121432 | 0.235665 | 0.00353497
3001164 | 00_Ground Floor | 98.1935 | 0.121432 | 0.235665 | 0.00353497
3001165 | 00_Ground Floor | 98.1935 | 0.121432 | 0.235665 | 0.00353497
3001166 | 00_Ground Floor | 98.1935 | 0.121432 | 0.235665 | 0.00353497
3001167 | 00_Ground Floor | 98.1935 | 0.121432 | 0.235665 | 0.00353497
3001168 | 00_Ground Floor | 98.1935 | 0.121432 | 0.235665 | 0.00353497
3001169 | 00_Ground Floor | 98.1935 | 0.121432 | 0.235665 | 0.00353497
3001170 | 00_Ground Floor | 98.1935 | 0.121432 | 0.235665 | 0.00353497
3001171 | 00_Ground Floor | 98.1935 | 0.121432 | 0.235665 | 0.00353497
3001172 | 00_Ground Floor | 98.1935 | 0.121432 | 0.235665 | 0.00353497
3001173 | 00_Ground Floor | 98.1935 | 0.121432 | 0.235665 | 0.00353497
3001174 | 00_Ground Floor | 98.1935 | 0.121432 | 0.235665 | 0.00353497
3001175 | 00_Ground Floor | 98.1935 | 0.121432 | 0.235665 | 0.00353497
3001176 | 00_Ground Floor | 98.1935 | 0.121432 | 0.235665 | 0.00353497
3001177 | 00_Ground Floor | 98.1935 | 0.121432 | 0.235665 | 0.00353497
3001178 | 00_Ground Floor | 98.1935 | 0.121432 | 0.235665 | 0.00353497
3001179 | 00_Ground Floor | 98.1935 | 0.121432 | 0.235665 | 0.00353497
3001180 | 00_Ground Floor | 98.1935 | 0.121432 | 0.235665 | 0.00353497
3001181 | 00_Ground Floor | 98.1935 | 0.121432 | 0.235665 | 0.00353497
3001182 | 00_Ground Floor | 98.1935 | 0.121432 | 0.235665 | 0.00353497
3001183 | 00_Ground Floor | 98.1935 | 0.121432 | 0.235665 | 0.00353497
3001184 | 00_Ground Floor | 98.1935 | 0.121432 | 0.235665 | 0.00353497
3001185 | 00_Ground Floor | 98.1935 | 0.121432 | 0.235665 | 0.00353497
3001186 | 00_Ground Floor | 101.194 | 0.125032 | 0.246465 | 0.00364297
3001187 | 00_Ground Floor | 238 | 0.2892 | 0.5784 | 0.008568
3001188 | 00_Ground Floor | 238 | 0.2892 | 0.5784 | 0.008568
3001189 | 00_Ground Floor | 238 | 0.2892 | 0.5784 | 0.008568
3001190 | 00_Ground Floor | 238 | 0.2892 | 0.5784 | 0.008568
3001191 | 00_Ground Floor | 238 | 0.2892 | 0.5784 | 0.008568
3001192 | 00_Ground Floor | 238 | 0.2892 | 0.5784 | 0.008568
3001193 | 00_Ground Floor | 238 | 0.2892 | 0.5784 | 0.008568
3001194 | 00_Ground Floor | 238 | 0.2892 | 0.5784 | 0.008568
3001195 | 00_Ground Floor | 238 | 0.2892 | 0.5784 | 0.008568
3001196 | 00_Ground Floor | 238 | 0.2892 | 0.5784 | 0.008568
3001197 | 00_Ground Floor | 238 | 0.2892 | 0.5784 | 0.008568
3001198 | 00_Ground Floor | 238 | 0.2892 | 0.5784 | 0.008568
3001199 | 00_Ground Floor | 238 | 0.2892 | 0.5784 | 0.008568
3001200 | 00_Ground Floor | 238 | 0.2892 | 0.5784 | 0.008568
3001201 | 00_Ground Floor | 238 | 0.2892 | 0.5784 | 0.008568
3001202 | 00_Ground Floor | 238 | 0.2892 | 0.5784 | 0.008568
3001203 | 00_Ground Floor | 238 | 0.2892 | 0.5784 | 0.008568
3001204 | 00_Ground Floor | 238 | 0.2892 | 0.5784 | 0.008568
3001205 | 00_Ground Floor | 238 | 0.2892 | 0.5784 | 0.008568
3001206 | 00_Ground Floor | 238 | 0.2892 | 0.5784 | 0.008568
3001207 | 00_Ground Floor | 238 | 0.2892 | 0.5784 | 0.008568
3001208 | 00_Ground Floor | 238 | 0.2892 | 0.5784 | 0.008568
3001209 | 00_Ground Floor | 238 | 0.2892 | 0.5784 | 0.008568
3001210 | 00_Ground Floor | 238 | 0.2892 | 0.5784 | 0.008568
3001211 | 00_Ground Floor | 238 | 0.2892 | 0.5784 | 0.008568
3001212 | 00_Ground Floor | 238 | 0.2892 | 0.5784 | 0.008568
3001213 | 00_Ground Floor | 238 | 0.2892 | 0.5784 | 0.008568
3001214 | 00_Ground Floor | 238 | 0.2892 | 0.5784 | 0.008568
3001215 | 00_Ground Floor | 238 | 0.2892 | 0.5784 | 0.008568
3001216 | 00_Ground Floor | 238 | 0.2892 | 0.5784 | 0.008568
3001217 | 00_Ground Floor | 238 | 0.2892 | 0.5784 | 0.008568
3001218 | 00_Ground Floor | 238 | 0.2892 | 0.5784 | 0.008568
3003242 | 01_First Floor | 102.843 | 0.127012 | 0.250424 | 0.00370235
3003243 | 01_First Floor | 102.843 | 0.127012 | 0.250424 | 0.00370235
3003244 | 01_First Floor | 99.8431 | 0.123412 | 0.239624 | 0.00359435
3003245 | 01_First Floor | 99.8431 | 0.123412 | 0.239624 | 0.00359435
3003246 | 01_First Floor | 99.8431 | 0.123412 | 0.239624 | 0.00359435
3003247 | 01_First Floor | 99.8431 | 0.123412 | 0.239624 | 0.00359435
3003248 | 01_First Floor | 99.8431 | 0.123412 | 0.239624 | 0.00359435
3003249 | 01_First Floor | 99.8431 | 0.123412 | 0.239624 | 0.00359435
3003250 | 01_First Floor | 99.8431 | 0.123412 | 0.239624 | 0.00359435
3003251 | 01_First Floor | 99.8431 | 0.123412 | 0.239624 | 0.00359435
3003252 | 01_First Floor | 99.8431 | 0.123412 | 0.239624 | 0.00359435
3003253 | 01_First Floor | 99.8431 | 0.123412 | 0.239624 | 0.00359435
3003254 | 01_First Floor | 99.8431 | 0.123412 | 0.239624 | 0.00359435
3003255 | 01_First Floor | 99.8431 | 0.123412 | 0.239624 | 0.00359435
3003256 | 01_First Floor | 99.8431 | 0.123412 | 0.239624 | 0.00359435
3003257 | 01_First Floor | 99.8431 | 0.123412 | 0.239624 | 0.00359435
3003258 | 01_First Floor | 99.8431 | 0.123412 | 0.239624 | 0.00359435
3003259 | 01_First Floor | 99.8431 | 0.123412 | 0.239624 | 0.00359435
3003260 | 01_First Floor | 99.8431 | 0.123412 | 0.239624 | 0.00359435
3003261 | 01_First Floor | 99.8431 | 0.123412 | 0.239624 | 0.00359435
3003262 | 01_First Floor | 99.8431 | 0.123412 | 0.239624 | 0.00359435
3003263 | 01_First Floor | 99.8431 | 0.123412 | 0.239624 | 0.00359435
3003264 | 01_First Floor | 99.8431 | 0.123412 | 0.239624 | 0.00359435
3003265 | 01_First Floor | 99.8431 | 0.123412 | 0.239624 | 0.00359435
3003266 | 01_First Floor | 99.8431 | 0.123412 | 0.239624 | 0.00359435
3003267 | 01_First Floor | 99.8431 | 0.123412 | 0.239624 | 0.00359435
3003268 | 01_First Floor | 99.8431 | 0.123412 | 0.239624 | 0.00359435
3003269 | 01_First Floor | 99.8431 | 0.123412 | 0.239624 | 0.00359435
3003270 | 01_First Floor | 99.8431 | 0.123412 | 0.239624 | 0.00359435
3003271 | 01_First Floor | 99.8431 | 0.123412 | 0.239624 | 0.00359435
3003272 | 01_First Floor | 99.8431 | 0.123412 | 0.239624 | 0.00359435
3003273 | 01_First Floor | 99.8431 | 0.123412 | 0.239624 | 0.00359435
3003274 | 01_First Floor | 99.8431 | 0.123412 | 0.239624 | 0.00359435
3003275 | 01_First Floor | 99.8431 | 0.123412 | 0.239624 | 0.00359435
3003276 | 01_First Floor | 99.8431 | 0.123412 | 0.239624 | 0.00359435
3003277 | 01_First Floor | 99.8431 | 0.123412 | 0.239624 | 0.00359435
3003278 | 01_First Floor | 99.8431 | 0.123412 | 0.239624 | 0.00359435
3003279 | 01_First Floor | 99.8431 | 0.123412 | 0.239624 | 0.00359435
3003280 | 01_First Floor | 99.8431 | 0.123412 | 0.239624 | 0.00359435
3003281 | 01_First Floor | 99.8431 | 0.123412 | 0.239624 | 0.00359435
3003282 | 01_First Floor | 99.8431 | 0.123412 | 0.239624 | 0.00359435
3003283 | 01_First Floor | 99.8431 | 0.123412 | 0.239624 | 0.00359435
3003284 | 01_First Floor | 99.8431 | 0.123412 | 0.239624 | 0.00359435
3003285 | 01_First Floor | 99.8431 | 0.123412 | 0.239624 | 0.00359435
3003286 | 01_First Floor | 99.8431 | 0.123412 | 0.239624 | 0.00359435
3003287 | 01_First Floor | 99.8431 | 0.123412 | 0.239624 | 0.00359435
3003288 | 01_First Floor | 99.8431 | 0.123412 | 0.239624 | 0.00359435
3003289 | 01_First Floor | 99.8431 | 0.123412 | 0.239624 | 0.00359435
3003290 | 01_First Floor | 99.8431 | 0.123412 | 0.239624 | 0.00359435
3003291 | 01_First Floor | 99.8431 | 0.123412 | 0.239624 | 0.00359435
3003292 | 01_First Floor | 99.8431 | 0.123412 | 0.239624 | 0.00359435
3003293 | 01_First Floor | 102.843 | 0.127012 | 0.250424 | 0.00370235
3003294 | 01_First Floor | 99.8431 | 0.123412 | 0.239624 | 0.00359435
3003295 | 01_First Floor | 99.8431 | 0.123412 | 0.239624 | 0.00359435
3003296 | 01_First Floor | 99.8431 | 0.123412 | 0.239624 | 0.00359435
3003297 | 01_First Floor | 99.8431 | 0.123412 | 0.239624 | 0.00359435
3003298 | 01_First Floor | 99.8431 | 0.123412 | 0.239624 | 0.00359435
3003299 | 01_First Floor | 99.8431 | 0.123412 | 0.239624 | 0.00359435
3003300 | 01_First Floor | 99.8431 | 0.123412 | 0.239624 | 0.00359435
3003301 | 01_First Floor | 99.8431 | 0.123412 | 0.239624 | 0.00359435
3003302 | 01_First Floor | 99.8431 | 0.123412 | 0.239624 | 0.00359435
3003303 | 01_First Floor | 99.8431 | 0.123412 | 0.239624 | 0.00359435
3003304 | 01_First Floor | 99.8431 | 0.123412 | 0.239624 | 0.00359435
3003305 | 01_First Floor | 99.8431 | 0.123412 | 0.239624 | 0.00359435
3003306 | 01_First Floor | 99.8431 | 0.123412 | 0.239624 | 0.00359435
3003307 | 01_First Floor | 99.8431 | 0.123412 | 0.239624 | 0.00359435
3003308 | 01_First Floor | 99.8431 | 0.123412 | 0.239624 | 0.00359435
3003309 | 01_First Floor | 99.8431 | 0.123412 | 0.239624 | 0.00359435
3003310 | 01_First Floor | 99.8431 | 0.123412 | 0.239624 | 0.00359435
3003311 | 01_First Floor | 99.8431 | 0.123412 | 0.239624 | 0.00359435
3003312 | 01_First Floor | 99.8431 | 0.123412 | 0.239624 | 0.00359435
3003313 | 01_First Floor | 99.8431 | 0.123412 | 0.239624 | 0.00359435
3003314 | 01_First Floor | 99.8431 | 0.123412 | 0.239624 | 0.00359435
3003315 | 01_First Floor | 99.8431 | 0.123412 | 0.239624 | 0.00359435
3003316 | 01_First Floor | 99.8431 | 0.123412 | 0.239624 | 0.00359435
3003317 | 01_First Floor | 99.8431 | 0.123412 | 0.239624 | 0.00359435
3003318 | 01_First Floor | 99.8431 | 0.123412 | 0.239624 | 0.00359435
3003319 | 01_First Floor | 99.8431 | 0.123412 | 0.239624 | 0.00359435
3003320 | 01_First Floor | 99.8431 | 0.123412 | 0.239624 | 0.00359435
3003321 | 01_First Floor | 99.8431 | 0.123412 | 0.239624 | 0.00359435
3003322 | 01_First Floor | 99.8431 | 0.123412 | 0.239624 | 0.00359435
3003323 | 01_First Floor | 99.8431 | 0.123412 | 0.239624 | 0.00359435
3003324 | 01_First Floor | 99.8431 | 0.123412 | 0.239624 | 0.00359435
3003325 | 01_First Floor | 99.8431 | 0.123412 | 0.239624 | 0.00359435
3003326 | 01_First Floor | 99.8431 | 0.123412 | 0.239624 | 0.00359435
3003327 | 01_First Floor | 99.8431 | 0.123412 | 0.239624 | 0.00359435
3003328 | 01_First Floor | 99.8431 | 0.123412 | 0.239624 | 0.00359435
3003329 | 01_First Floor | 99.8431 | 0.123412 | 0.239624 | 0.00359435
3003330 | 01_First Floor | 99.8431 | 0.123412 | 0.239624 | 0.00359435
3003331 | 01_First Floor | 99.8431 | 0.123412 | 0.239624 | 0.00359435
3003332 | 01_First Floor | 99.8431 | 0.123412 | 0.239624 | 0.00359435
3003333 | 01_First Floor | 99.8431 | 0.123412 | 0.239624 | 0.00359435
3003334 | 01_First Floor | 99.8431 | 0.123412 | 0.239624 | 0.00359435
3003335 | 01_First Floor | 99.8431 | 0.123412 | 0.239624 | 0.00359435
3003336 | 01_First Floor | 99.8431 | 0.123412 | 0.239624 | 0.00359435
3003337 | 01_First Floor | 99.8431 | 0.123412 | 0.239624 | 0.00359435
3003338 | 01_First Floor | 99.8431 | 0.123412 | 0.239624 | 0.00359435
3003339 | 01_First Floor | 99.8431 | 0.123412 | 0.239624 | 0.00359435
3003340 | 01_First Floor | 99.8431 | 0.123412 | 0.239624 | 0.00359435
3003341 | 01_First Floor | 99.8431 | 0.123412 | 0.239624 | 0.00359435
3003342 | 01_First Floor | 99.8431 | 0.123412 | 0.239624 | 0.00359435
3003343 | 01_First Floor | 102.843 | 0.127012 | 0.250424 | 0.00370235
3003344 | 01_First Floor | 238 | 0.2892 | 0.5784 | 0.008568
3003345 | 01_First Floor | 238 | 0.2892 | 0.5784 | 0.008568
3003346 | 01_First Floor | 238 | 0.2892 | 0.5784 | 0.008568
3003347 | 01_First Floor | 238 | 0.2892 | 0.5784 | 0.008568
3003348 | 01_First Floor | 238 | 0.2892 | 0.5784 | 0.008568
3003349 | 01_First Floor | 238 | 0.2892 | 0.5784 | 0.008568
3003350 | 01_First Floor | 238 | 0.2892 | 0.5784 | 0.008568
3003351 | 01_First Floor | 238 | 0.2892 | 0.5784 | 0.008568
3003352 | 01_First Floor | 238 | 0.2892 | 0.5784 | 0.008568
3003353 | 01_First Floor | 238 | 0.2892 | 0.5784 | 0.008568
3003354 | 01_First Floor | 238 | 0.2892 | 0.5784 | 0.008568
3003355 | 01_First Floor | 238 | 0.2892 | 0.5784 | 0.008568
3003356 | 01_First Floor | 238 | 0.2892 | 0.5784 | 0.008568
3003357 | 01_First Floor | 238 | 0.2892 | 0.5784 | 0.008568
3003358 | 01_First Floor | 238 | 0.2892 | 0.5784 | 0.008568
3003359 | 01_First Floor | 238 | 0.2892 | 0.5784 | 0.008568
3003360 | 01_First Floor | 238 | 0.2892 | 0.5784 | 0.008568
3003361 | 01_First Floor | 238 | 0.2892 | 0.5784 | 0.008568
3003362 | 01_First Floor | 238 | 0.2892 | 0.5784 | 0.008568
3003363 | 01_First Floor | 238 | 0.2892 | 0.5784 | 0.008568
3003364 | 01_First Floor | 238 | 0.2892 | 0.5784 | 0.008568
3003365 | 01_First Floor | 238 | 0.2892 | 0.5784 | 0.008568
3003366 | 01_First Floor | 238 | 0.2892 | 0.5784 | 0.008568
3003367 | 01_First Floor | 238 | 0.2892 | 0.5784 | 0.008568
3003368 | 01_First Floor | 238 | 0.2892 | 0.5784 | 0.008568
3003369 | 01_First Floor | 238 | 0.2892 | 0.5784 | 0.008568
3003370 | 01_First Floor | 238 | 0.2892 | 0.5784 | 0.008568
3003371 | 01_First Floor | 238 | 0.2892 | 0.5784 | 0.008568
3003372 | 01_First Floor | 238 | 0.2892 | 0.5784 | 0.008568
3003373 | 01_First Floor | 238 | 0.2892 | 0.5784 | 0.008568
3003374 | 01_First Floor | 238 | 0.2892 | 0.5784 | 0.008568
3003375 | 01_First Floor | 238 | 0.2892 | 0.5784 | 0.008568
3003376 | 01_First Floor | 238 | 0.2892 | 0.5784 | 0.008568
3003377 | 01_First Floor | 238 | 0.2892 | 0.5784 | 0.008568
3003378 | 01_First Floor | 238 | 0.2892 | 0.5784 | 0.008568
3003379 | 01_First Floor | 238 | 0.2892 | 0.5784 | 0.008568
3003380 | 01_First Floor | 238 | 0.2892 | 0.5784 | 0.008568
3003381 | 01_First Floor | 238 | 0.2892 | 0.5784 | 0.008568
3003382 | 01_First Floor | 238 | 0.2892 | 0.5784 | 0.008568
3003383 | 01_First Floor | 238 | 0.2892 | 0.5784 | 0.008568
3003384 | 01_First Floor | 238 | 0.2892 | 0.5784 | 0.008568
3003385 | 01_First Floor | 238 | 0.2892 | 0.5784 | 0.008568
3003386 | 01_First Floor | 238 | 0.2892 | 0.5784 | 0.008568
3003387 | 01_First Floor | 238 | 0.2892 | 0.5784 | 0.008568
3003388 | 01_First Floor | 238 | 0.2892 | 0.5784 | 0.008568
3003389 | 01_First Floor | 238 | 0.2892 | 0.5784 | 0.008568
3003390 | 01_First Floor | 238 | 0.2892 | 0.5784 | 0.008568
3003391 | 01_First Floor | 238 | 0.2892 | 0.5784 | 0.008568
3003392 | 01_First Floor | 238 | 0.2892 | 0.5784 | 0.008568
3003393 | 01_First Floor | 238 | 0.2892 | 0.5784 | 0.008568
3003394 | 01_First Floor | 238 | 0.2892 | 0.5784 | 0.008568
3003395 | 01_First Floor | 238 | 0.2892 | 0.5784 | 0.008568
3003458 | 01_First Floor | 101.194 | 0.125032 | 0.246465 | 0.00364297
3003459 | 01_First Floor | 101.194 | 0.125032 | 0.246465 | 0.00364297
3003460 | 01_First Floor | 98.1935 | 0.121432 | 0.235665 | 0.00353497
3003461 | 01_First Floor | 98.1935 | 0.121432 | 0.235665 | 0.00353497
3003462 | 01_First Floor | 98.1935 | 0.121432 | 0.235665 | 0.00353497
3003463 | 01_First Floor | 98.1935 | 0.121432 | 0.235665 | 0.00353497
3003464 | 01_First Floor | 98.1935 | 0.121432 | 0.235665 | 0.00353497
3003465 | 01_First Floor | 98.1935 | 0.121432 | 0.235665 | 0.00353497
3003466 | 01_First Floor | 98.1935 | 0.121432 | 0.235665 | 0.00353497
3003467 | 01_First Floor | 98.1935 | 0.121432 | 0.235665 | 0.00353497
3003468 | 01_First Floor | 98.1935 | 0.121432 | 0.235665 | 0.00353497
3003469 | 01_First Floor | 98.1935 | 0.121432 | 0.235665 | 0.00353497
3003470 | 01_First Floor | 98.1935 | 0.121432 | 0.235665 | 0.00353497
3003471 | 01_First Floor | 98.1935 | 0.121432 | 0.235665 | 0.00353497
3003472 | 01_First Floor | 98.1935 | 0.121432 | 0.235665 | 0.00353497
3003473 | 01_First Floor | 98.1935 | 0.121432 | 0.235665 | 0.00353497
3003474 | 01_First Floor | 98.1935 | 0.121432 | 0.235665 | 0.00353497
3003475 | 01_First Floor | 98.1935 | 0.121432 | 0.235665 | 0.00353497
3003476 | 01_First Floor | 98.1935 | 0.121432 | 0.235665 | 0.00353497
3003477 | 01_First Floor | 98.1935 | 0.121432 | 0.235665 | 0.00353497
3003478 | 01_First Floor | 98.1935 | 0.121432 | 0.235665 | 0.00353497
3003479 | 01_First Floor | 98.1935 | 0.121432 | 0.235665 | 0.00353497
3003480 | 01_First Floor | 98.1935 | 0.121432 | 0.235665 | 0.00353497
3003481 | 01_First Floor | 98.1935 | 0.121432 | 0.235665 | 0.00353497
3003482 | 01_First Floor | 98.1935 | 0.121432 | 0.235665 | 0.00353497
3003483 | 01_First Floor | 98.1935 | 0.121432 | 0.235665 | 0.00353497
3003484 | 01_First Floor | 98.1935 | 0.121432 | 0.235665 | 0.00353497
3003485 | 01_First Floor | 98.1935 | 0.121432 | 0.235665 | 0.00353497
3003486 | 01_First Floor | 98.1935 | 0.121432 | 0.235665 | 0.00353497
3003487 | 01_First Floor | 98.1935 | 0.121432 | 0.235665 | 0.00353497
3003488 | 01_First Floor | 98.1935 | 0.121432 | 0.235665 | 0.00353497
3003489 | 01_First Floor | 101.194 | 0.125032 | 0.246465 | 0.00364297
3003490 | 01_First Floor | 98.1935 | 0.121432 | 0.235665 | 0.00353497
3003491 | 01_First Floor | 98.1935 | 0.121432 | 0.235665 | 0.00353497
3003492 | 01_First Floor | 98.1935 | 0.121432 | 0.235665 | 0.00353497
3003493 | 01_First Floor | 98.1935 | 0.121432 | 0.235665 | 0.00353497
3003494 | 01_First Floor | 98.1935 | 0.121432 | 0.235665 | 0.00353497
3003495 | 01_First Floor | 98.1935 | 0.121432 | 0.235665 | 0.00353497
3003496 | 01_First Floor | 98.1935 | 0.121432 | 0.235665 | 0.00353497
3003497 | 01_First Floor | 98.1935 | 0.121432 | 0.235665 | 0.00353497
3003498 | 01_First Floor | 98.1935 | 0.121432 | 0.235665 | 0.00353497
3003499 | 01_First Floor | 98.1935 | 0.121432 | 0.235665 | 0.00353497
3003500 | 01_First Floor | 98.1935 | 0.121432 | 0.235665 | 0.00353497
3003501 | 01_First Floor | 98.1935 | 0.121432 | 0.235665 | 0.00353497
3003502 | 01_First Floor | 98.1935 | 0.121432 | 0.235665 | 0.00353497
3003503 | 01_First Floor | 98.1935 | 0.121432 | 0.235665 | 0.00353497
3003504 | 01_First Floor | 98.1935 | 0.121432 | 0.235665 | 0.00353497
3003505 | 01_First Floor | 98.1935 | 0.121432 | 0.235665 | 0.00353497
3003506 | 01_First Floor | 98.1935 | 0.121432 | 0.235665 | 0.00353497
3003507 | 01_First Floor | 98.1935 | 0.121432 | 0.235665 | 0.00353497
3003508 | 01_First Floor | 98.1935 | 0.121432 | 0.235665 | 0.00353497
3003509 | 01_First Floor | 98.1935 | 0.121432 | 0.235665 | 0.00353497
3003510 | 01_First Floor | 98.1935 | 0.121432 | 0.235665 | 0.00353497
3003511 | 01_First Floor | 98.1935 | 0.121432 | 0.235665 | 0.00353497
3003512 | 01_First Floor | 98.1935 | 0.121432 | 0.235665 | 0.00353497
3003513 | 01_First Floor | 98.1935 | 0.121432 | 0.235665 | 0.00353497
3003514 | 01_First Floor | 98.1935 | 0.121432 | 0.235665 | 0.00353497
3003515 | 01_First Floor | 98.1935 | 0.121432 | 0.235665 | 0.00353497
3003516 | 01_First Floor | 98.1935 | 0.121432 | 0.235665 | 0.00353497
3003517 | 01_First Floor | 98.1935 | 0.121432 | 0.235665 | 0.00353497
3003518 | 01_First Floor | 98.1935 | 0.121432 | 0.235665 | 0.00353497
3003519 | 01_First Floor | 101.194 | 0.125032 | 0.246465 | 0.00364297
3003520 | 01_First Floor | 238 | 0.2892 | 0.5784 | 0.008568
3003521 | 01_First Floor | 238 | 0.2892 | 0.5784 | 0.008568
3003522 | 01_First Floor | 238 | 0.2892 | 0.5784 | 0.008568
3003523 | 01_First Floor | 238 | 0.2892 | 0.5784 | 0.008568
3003524 | 01_First Floor | 238 | 0.2892 | 0.5784 | 0.008568
3003525 | 01_First Floor | 238 | 0.2892 | 0.5784 | 0.008568
3003526 | 01_First Floor | 238 | 0.2892 | 0.5784 | 0.008568
3003527 | 01_First Floor | 238 | 0.2892 | 0.5784 | 0.008568
3003528 | 01_First Floor | 238 | 0.2892 | 0.5784 | 0.008568
3003529 | 01_First Floor | 238 | 0.2892 | 0.5784 | 0.008568
3003530 | 01_First Floor | 238 | 0.2892 | 0.5784 | 0.008568
3003531 | 01_First Floor | 238 | 0.2892 | 0.5784 | 0.008568
3003532 | 01_First Floor | 238 | 0.2892 | 0.5784 | 0.008568
3003533 | 01_First Floor | 238 | 0.2892 | 0.5784 | 0.008568
3003534 | 01_First Floor | 238 | 0.2892 | 0.5784 | 0.008568
3003535 | 01_First Floor | 238 | 0.2892 | 0.5784 | 0.008568
3003536 | 01_First Floor | 238 | 0.2892 | 0.5784 | 0.008568
3003537 | 01_First Floor | 238 | 0.2892 | 0.5784 | 0.008568
3003538 | 01_First Floor | 238 | 0.2892 | 0.5784 | 0.008568
3003539 | 01_First Floor | 238 | 0.2892 | 0.5784 | 0.008568
3003540 | 01_First Floor | 238 | 0.2892 | 0.5784 | 0.008568
3003541 | 01_First Floor | 238 | 0.2892 | 0.5784 | 0.008568
3003542 | 01_First Floor | 238 | 0.2892 | 0.5784 | 0.008568
3003543 | 01_First Floor | 238 | 0.2892 | 0.5784 | 0.008568
3003544 | 01_First Floor | 238 | 0.2892 | 0.5784 | 0.008568
3003545 | 01_First Floor | 238 | 0.2892 | 0.5784 | 0.008568
3003546 | 01_First Floor | 238 | 0.2892 | 0.5784 | 0.008568
3003547 | 01_First Floor | 238 | 0.2892 | 0.5784 | 0.008568
3003548 | 01_First Floor | 238 | 0.2892 | 0.5784 | 0.008568
3003549 | 01_First Floor | 238 | 0.2892 | 0.5784 | 0.008568
3003550 | 01_First Floor | 238 | 0.2892 | 0.5784 | 0.008568
3003551 | 01_First Floor | 238 | 0.2892 | 0.5784 | 0.008568
3005435 | 02_Second Floor | 102.843 | 0.127012 | 0.250424 | 0.00370235
3005436 | 02_Second Floor | 102.843 | 0.127012 | 0.250424 | 0.00370235
3005437 | 02_Second Floor | 99.8431 | 0.123412 | 0.239624 | 0.00359435
3005438 | 02_Second Floor | 99.8431 | 0.123412 | 0.239624 | 0.00359435
3005439 | 02_Second Floor | 99.8431 | 0.123412 | 0.239624 | 0.00359435
3005440 | 02_Second Floor | 99.8431 | 0.123412 | 0.239624 | 0.00359435
3005441 | 02_Second Floor | 99.8431 | 0.123412 | 0.239624 | 0.00359435
3005442 | 02_Second Floor | 99.8431 | 0.123412 | 0.239624 | 0.00359435
3005443 | 02_Second Floor | 99.8431 | 0.123412 | 0.239624 | 0.00359435
3005444 | 02_Second Floor | 99.8431 | 0.123412 | 0.239624 | 0.00359435
3005445 | 02_Second Floor | 99.8431 | 0.123412 | 0.239624 | 0.00359435
3005446 | 02_Second Floor | 99.8431 | 0.123412 | 0.239624 | 0.00359435
3005447 | 02_Second Floor | 99.8431 | 0.123412 | 0.239624 | 0.00359435
3005448 | 02_Second Floor | 99.8431 | 0.123412 | 0.239624 | 0.00359435
3005449 | 02_Second Floor | 99.8431 | 0.123412 | 0.239624 | 0.00359435
3005450 | 02_Second Floor | 99.8431 | 0.123412 | 0.239624 | 0.00359435
3005451 | 02_Second Floor | 99.8431 | 0.123412 | 0.239624 | 0.00359435
3005452 | 02_Second Floor | 99.8431 | 0.123412 | 0.239624 | 0.00359435
3005453 | 02_Second Floor | 99.8431 | 0.123412 | 0.239624 | 0.00359435
3005454 | 02_Second Floor | 99.8431 | 0.123412 | 0.239624 | 0.00359435
3005455 | 02_Second Floor | 99.8431 | 0.123412 | 0.239624 | 0.00359435
3005456 | 02_Second Floor | 99.8431 | 0.123412 | 0.239624 | 0.00359435
3005457 | 02_Second Floor | 99.8431 | 0.123412 | 0.239624 | 0.00359435
3005458 | 02_Second Floor | 99.8431 | 0.123412 | 0.239624 | 0.00359435
3005459 | 02_Second Floor | 99.8431 | 0.123412 | 0.239624 | 0.00359435
3005460 | 02_Second Floor | 99.8431 | 0.123412 | 0.239624 | 0.00359435
3005461 | 02_Second Floor | 99.8431 | 0.123412 | 0.239624 | 0.00359435
3005462 | 02_Second Floor | 99.8431 | 0.123412 | 0.239624 | 0.00359435
3005463 | 02_Second Floor | 99.8431 | 0.123412 | 0.239624 | 0.00359435
3005464 | 02_Second Floor | 99.8431 | 0.123412 | 0.239624 | 0.00359435
3005465 | 02_Second Floor | 99.8431 | 0.123412 | 0.239624 | 0.00359435
3005466 | 02_Second Floor | 99.8431 | 0.123412 | 0.239624 | 0.00359435
3005467 | 02_Second Floor | 99.8431 | 0.123412 | 0.239624 | 0.00359435
3005468 | 02_Second Floor | 99.8431 | 0.123412 | 0.239624 | 0.00359435
3005469 | 02_Second Floor | 99.8431 | 0.123412 | 0.239624 | 0.00359435
3005470 | 02_Second Floor | 99.8431 | 0.123412 | 0.239624 | 0.00359435
3005471 | 02_Second Floor | 99.8431 | 0.123412 | 0.239624 | 0.00359435
3005472 | 02_Second Floor | 99.8431 | 0.123412 | 0.239624 | 0.00359435
3005473 | 02_Second Floor | 99.8431 | 0.123412 | 0.239624 | 0.00359435
3005474 | 02_Second Floor | 99.8431 | 0.123412 | 0.239624 | 0.00359435
3005475 | 02_Second Floor | 99.8431 | 0.123412 | 0.239624 | 0.00359435
3005476 | 02_Second Floor | 99.8431 | 0.123412 | 0.239624 | 0.00359435
3005477 | 02_Second Floor | 99.8431 | 0.123412 | 0.239624 | 0.00359435
3005478 | 02_Second Floor | 99.8431 | 0.123412 | 0.239624 | 0.00359435
3005479 | 02_Second Floor | 99.8431 | 0.123412 | 0.239624 | 0.00359435
3005480 | 02_Second Floor | 99.8431 | 0.123412 | 0.239624 | 0.00359435
3005481 | 02_Second Floor | 99.8431 | 0.123412 | 0.239624 | 0.00359435
3005482 | 02_Second Floor | 99.8431 | 0.123412 | 0.239624 | 0.00359435
3005483 | 02_Second Floor | 99.8431 | 0.123412 | 0.239624 | 0.00359435
3005484 | 02_Second Floor | 99.8431 | 0.123412 | 0.239624 | 0.00359435
3005485 | 02_Second Floor | 99.8431 | 0.123412 | 0.239624 | 0.00359435
3005486 | 02_Second Floor | 102.843 | 0.127012 | 0.250424 | 0.00370235
3005487 | 02_Second Floor | 99.8431 | 0.123412 | 0.239624 | 0.00359435
3005488 | 02_Second Floor | 99.8431 | 0.123412 | 0.239624 | 0.00359435
3005489 | 02_Second Floor | 99.8431 | 0.123412 | 0.239624 | 0.00359435
3005490 | 02_Second Floor | 99.8431 | 0.123412 | 0.239624 | 0.00359435
3005491 | 02_Second Floor | 99.8431 | 0.123412 | 0.239624 | 0.00359435
3005492 | 02_Second Floor | 99.8431 | 0.123412 | 0.239624 | 0.00359435
3005493 | 02_Second Floor | 99.8431 | 0.123412 | 0.239624 | 0.00359435
3005494 | 02_Second Floor | 99.8431 | 0.123412 | 0.239624 | 0.00359435
3005495 | 02_Second Floor | 99.8431 | 0.123412 | 0.239624 | 0.00359435
3005496 | 02_Second Floor | 99.8431 | 0.123412 | 0.239624 | 0.00359435
3005497 | 02_Second Floor | 99.8431 | 0.123412 | 0.239624 | 0.00359435
3005498 | 02_Second Floor | 99.8431 | 0.123412 | 0.239624 | 0.00359435
3005499 | 02_Second Floor | 99.8431 | 0.123412 | 0.239624 | 0.00359435
3005500 | 02_Second Floor | 99.8431 | 0.123412 | 0.239624 | 0.00359435
3005501 | 02_Second Floor | 99.8431 | 0.123412 | 0.239624 | 0.00359435
3005502 | 02_Second Floor | 99.8431 | 0.123412 | 0.239624 | 0.00359435
3005503 | 02_Second Floor | 99.8431 | 0.123412 | 0.239624 | 0.00359435
3005504 | 02_Second Floor | 99.8431 | 0.123412 | 0.239624 | 0.00359435
3005505 | 02_Second Floor | 99.8431 | 0.123412 | 0.239624 | 0.00359435
3005506 | 02_Second Floor | 99.8431 | 0.123412 | 0.239624 | 0.00359435
3005507 | 02_Second Floor | 99.8431 | 0.123412 | 0.239624 | 0.00359435
3005508 | 02_Second Floor | 99.8431 | 0.123412 | 0.239624 | 0.00359435
3005509 | 02_Second Floor | 99.8431 | 0.123412 | 0.239624 | 0.00359435
3005510 | 02_Second Floor | 99.8431 | 0.123412 | 0.239624 | 0.00359435
3005511 | 02_Second Floor | 99.8431 | 0.123412 | 0.239624 | 0.00359435
3005512 | 02_Second Floor | 99.8431 | 0.123412 | 0.239624 | 0.00359435
3005513 | 02_Second Floor | 99.8431 | 0.123412 | 0.239624 | 0.00359435
3005514 | 02_Second Floor | 99.8431 | 0.123412 | 0.239624 | 0.00359435
3005515 | 02_Second Floor | 99.8431 | 0.123412 | 0.239624 | 0.00359435
3005516 | 02_Second Floor | 99.8431 | 0.123412 | 0.239624 | 0.00359435
3005517 | 02_Second Floor | 99.8431 | 0.123412 | 0.239624 | 0.00359435
3005518 | 02_Second Floor | 99.8431 | 0.123412 | 0.239624 | 0.00359435
3005519 | 02_Second Floor | 99.8431 | 0.123412 | 0.239624 | 0.00359435
3005520 | 02_Second Floor | 99.8431 | 0.123412 | 0.239624 | 0.00359435
3005521 | 02_Second Floor | 99.8431 | 0.123412 | 0.239624 | 0.00359435
3005522 | 02_Second Floor | 99.8431 | 0.123412 | 0.239624 | 0.00359435
3005523 | 02_Second Floor | 99.8431 | 0.123412 | 0.239624 | 0.00359435
3005524 | 02_Second Floor | 99.8431 | 0.123412 | 0.239624 | 0.00359435
3005525 | 02_Second Floor | 99.8431 | 0.123412 | 0.239624 | 0.00359435
3005526 | 02_Second Floor | 99.8431 | 0.123412 | 0.239624 | 0.00359435
3005527 | 02_Second Floor | 99.8431 | 0.123412 | 0.239624 | 0.00359435
3005528 | 02_Second Floor | 99.8431 | 0.123412 | 0.239624 | 0.00359435
3005529 | 02_Second Floor | 99.8431 | 0.123412 | 0.239624 | 0.00359435
3005530 | 02_Second Floor | 99.8431 | 0.123412 | 0.239624 | 0.00359435
3005531 | 02_Second Floor | 99.8431 | 0.123412 | 0.239624 | 0.00359435
3005532 | 02_Second Floor | 99.8431 | 0.123412 | 0.239624 | 0.00359435
3005533 | 02_Second Floor | 99.8431 | 0.123412 | 0.239624 | 0.00359435
3005534 | 02_Second Floor | 99.8431 | 0.123412 | 0.239624 | 0.00359435
3005535 | 02_Second Floor | 99.8431 | 0.123412 | 0.239624 | 0.00359435
3005536 | 02_Second Floor | 102.843 | 0.127012 | 0.250424 | 0.00370235
3005537 | 02_Second Floor | 238 | 0.2892 | 0.5784 | 0.008568
3005538 | 02_Second Floor | 238 | 0.2892 | 0.5784 | 0.008568
3005539 | 02_Second Floor | 238 | 0.2892 | 0.5784 | 0.008568
3005540 | 02_Second Floor | 238 | 0.2892 | 0.5784 | 0.008568
3005541 | 02_Second Floor | 238 | 0.2892 | 0.5784 | 0.008568
3005542 | 02_Second Floor | 238 | 0.2892 | 0.5784 | 0.008568
3005543 | 02_Second Floor | 238 | 0.2892 | 0.5784 | 0.008568
3005544 | 02_Second Floor | 238 | 0.2892 | 0.5784 | 0.008568
3005545 | 02_Second Floor | 238 | 0.2892 | 0.5784 | 0.008568
3005546 | 02_Second Floor | 238 | 0.2892 | 0.5784 | 0.008568
3005547 | 02_Second Floor | 238 | 0.2892 | 0.5784 | 0.008568
3005548 | 02_Second Floor | 238 | 0.2892 | 0.5784 | 0.008568
3005549 | 02_Second Floor | 238 | 0.2892 | 0.5784 | 0.008568
3005550 | 02_Second Floor | 238 | 0.2892 | 0.5784 | 0.008568
3005551 | 02_Second Floor | 238 | 0.2892 | 0.5784 | 0.008568
3005552 | 02_Second Floor | 238 | 0.2892 | 0.5784 | 0.008568
3005553 | 02_Second Floor | 238 | 0.2892 | 0.5784 | 0.008568
3005554 | 02_Second Floor | 238 | 0.2892 | 0.5784 | 0.008568
3005555 | 02_Second Floor | 238 | 0.2892 | 0.5784 | 0.008568
3005556 | 02_Second Floor | 238 | 0.2892 | 0.5784 | 0.008568
3005557 | 02_Second Floor | 238 | 0.2892 | 0.5784 | 0.008568
3005558 | 02_Second Floor | 238 | 0.2892 | 0.5784 | 0.008568
3005559 | 02_Second Floor | 238 | 0.2892 | 0.5784 | 0.008568
3005560 | 02_Second Floor | 238 | 0.2892 | 0.5784 | 0.008568
3005561 | 02_Second Floor | 238 | 0.2892 | 0.5784 | 0.008568
3005562 | 02_Second Floor | 238 | 0.2892 | 0.5784 | 0.008568
3005563 | 02_Second Floor | 238 | 0.2892 | 0.5784 | 0.008568
3005564 | 02_Second Floor | 238 | 0.2892 | 0.5784 | 0.008568
3005565 | 02_Second Floor | 238 | 0.2892 | 0.5784 | 0.008568
3005566 | 02_Second Floor | 238 | 0.2892 | 0.5784 | 0.008568
3005567 | 02_Second Floor | 238 | 0.2892 | 0.5784 | 0.008568
3005568 | 02_Second Floor | 238 | 0.2892 | 0.5784 | 0.008568
3005569 | 02_Second Floor | 238 | 0.2892 | 0.5784 | 0.008568
3005570 | 02_Second Floor | 238 | 0.2892 | 0.5784 | 0.008568
3005571 | 02_Second Floor | 238 | 0.2892 | 0.5784 | 0.008568
3005572 | 02_Second Floor | 238 | 0.2892 | 0.5784 | 0.008568
3005573 | 02_Second Floor | 238 | 0.2892 | 0.5784 | 0.008568
3005574 | 02_Second Floor | 238 | 0.2892 | 0.5784 | 0.008568
3005575 | 02_Second Floor | 238 | 0.2892 | 0.5784 | 0.008568
3005576 | 02_Second Floor | 238 | 0.2892 | 0.5784 | 0.008568
3005577 | 02_Second Floor | 238 | 0.2892 | 0.5784 | 0.008568
3005578 | 02_Second Floor | 238 | 0.2892 | 0.5784 | 0.008568
3005579 | 02_Second Floor | 238 | 0.2892 | 0.5784 | 0.008568
3005580 | 02_Second Floor | 238 | 0.2892 | 0.5784 | 0.008568
3005581 | 02_Second Floor | 238 | 0.2892 | 0.5784 | 0.008568
3005582 | 02_Second Floor | 238 | 0.2892 | 0.5784 | 0.008568
3005583 | 02_Second Floor | 238 | 0.2892 | 0.5784 | 0.008568
3005584 | 02_Second Floor | 238 | 0.2892 | 0.5784 | 0.008568
3005585 | 02_Second Floor | 238 | 0.2892 | 0.5784 | 0.008568
3005586 | 02_Second Floor | 238 | 0.2892 | 0.5784 | 0.008568
3005587 | 02_Second Floor | 238 | 0.2892 | 0.5784 | 0.008568
3005588 | 02_Second Floor | 238 | 0.2892 | 0.5784 | 0.008568
3005651 | 02_Second Floor | 101.194 | 0.125032 | 0.246465 | 0.00364297
3005652 | 02_Second Floor | 101.194 | 0.125032 | 0.246465 | 0.00364297
3005653 | 02_Second Floor | 98.1935 | 0.121432 | 0.235665 | 0.00353497
3005654 | 02_Second Floor | 98.1935 | 0.121432 | 0.235665 | 0.00353497
3005655 | 02_Second Floor | 98.1935 | 0.121432 | 0.235665 | 0.00353497
3005656 | 02_Second Floor | 98.1935 | 0.121432 | 0.235665 | 0.00353497
3005657 | 02_Second Floor | 98.1935 | 0.121432 | 0.235665 | 0.00353497
3005658 | 02_Second Floor | 98.1935 | 0.121432 | 0.235665 | 0.00353497
3005659 | 02_Second Floor | 98.1935 | 0.121432 | 0.235665 | 0.00353497
3005660 | 02_Second Floor | 98.1935 | 0.121432 | 0.235665 | 0.00353497
3005661 | 02_Second Floor | 98.1935 | 0.121432 | 0.235665 | 0.00353497
3005662 | 02_Second Floor | 98.1935 | 0.121432 | 0.235665 | 0.00353497
3005663 | 02_Second Floor | 98.1935 | 0.121432 | 0.235665 | 0.00353497
3005664 | 02_Second Floor | 98.1935 | 0.121432 | 0.235665 | 0.00353497
3005665 | 02_Second Floor | 98.1935 | 0.121432 | 0.235665 | 0.00353497
3005666 | 02_Second Floor | 98.1935 | 0.121432 | 0.235665 | 0.00353497
3005667 | 02_Second Floor | 98.1935 | 0.121432 | 0.235665 | 0.00353497
3005668 | 02_Second Floor | 98.1935 | 0.121432 | 0.235665 | 0.00353497
3005669 | 02_Second Floor | 98.1935 | 0.121432 | 0.235665 | 0.00353497
3005670 | 02_Second Floor | 98.1935 | 0.121432 | 0.235665 | 0.00353497
3005671 | 02_Second Floor | 98.1935 | 0.121432 | 0.235665 | 0.00353497
3005672 | 02_Second Floor | 98.1935 | 0.121432 | 0.235665 | 0.00353497
3005673 | 02_Second Floor | 98.1935 | 0.121432 | 0.235665 | 0.00353497
3005674 | 02_Second Floor | 98.1935 | 0.121432 | 0.235665 | 0.00353497
3005675 | 02_Second Floor | 98.1935 | 0.121432 | 0.235665 | 0.00353497
3005676 | 02_Second Floor | 98.1935 | 0.121432 | 0.235665 | 0.00353497
3005677 | 02_Second Floor | 98.1935 | 0.121432 | 0.235665 | 0.00353497
3005678 | 02_Second Floor | 98.1935 | 0.121432 | 0.235665 | 0.00353497
3005679 | 02_Second Floor | 98.1935 | 0.121432 | 0.235665 | 0.00353497
3005680 | 02_Second Floor | 98.1935 | 0.121432 | 0.235665 | 0.00353497
3005681 | 02_Second Floor | 98.1935 | 0.121432 | 0.235665 | 0.00353497
3005682 | 02_Second Floor | 101.194 | 0.125032 | 0.246465 | 0.00364297
3005683 | 02_Second Floor | 98.1935 | 0.121432 | 0.235665 | 0.00353497
3005684 | 02_Second Floor | 98.1935 | 0.121432 | 0.235665 | 0.00353497
3005685 | 02_Second Floor | 98.1935 | 0.121432 | 0.235665 | 0.00353497
3005686 | 02_Second Floor | 98.1935 | 0.121432 | 0.235665 | 0.00353497
3005687 | 02_Second Floor | 98.1935 | 0.121432 | 0.235665 | 0.00353497
3005688 | 02_Second Floor | 98.1935 | 0.121432 | 0.235665 | 0.00353497
3005689 | 02_Second Floor | 98.1935 | 0.121432 | 0.235665 | 0.00353497
3005690 | 02_Second Floor | 98.1935 | 0.121432 | 0.235665 | 0.00353497
3005691 | 02_Second Floor | 98.1935 | 0.121432 | 0.235665 | 0.00353497
3005692 | 02_Second Floor | 98.1935 | 0.121432 | 0.235665 | 0.00353497
3005693 | 02_Second Floor | 98.1935 | 0.121432 | 0.235665 | 0.00353497
3005694 | 02_Second Floor | 98.1935 | 0.121432 | 0.235665 | 0.00353497
3005695 | 02_Second Floor | 98.1935 | 0.121432 | 0.235665 | 0.00353497
3005696 | 02_Second Floor | 98.1935 | 0.121432 | 0.235665 | 0.00353497
3005697 | 02_Second Floor | 98.1935 | 0.121432 | 0.235665 | 0.00353497
3005698 | 02_Second Floor | 98.1935 | 0.121432 | 0.235665 | 0.00353497
3005699 | 02_Second Floor | 98.1935 | 0.121432 | 0.235665 | 0.00353497
3005700 | 02_Second Floor | 98.1935 | 0.121432 | 0.235665 | 0.00353497
3005701 | 02_Second Floor | 98.1935 | 0.121432 | 0.235665 | 0.00353497
3005702 | 02_Second Floor | 98.1935 | 0.121432 | 0.235665 | 0.00353497
3005703 | 02_Second Floor | 98.1935 | 0.121432 | 0.235665 | 0.00353497
3005704 | 02_Second Floor | 98.1935 | 0.121432 | 0.235665 | 0.00353497
3005705 | 02_Second Floor | 98.1935 | 0.121432 | 0.235665 | 0.00353497
3005706 | 02_Second Floor | 98.1935 | 0.121432 | 0.235665 | 0.00353497
3005707 | 02_Second Floor | 98.1935 | 0.121432 | 0.235665 | 0.00353497
3005708 | 02_Second Floor | 98.1935 | 0.121432 | 0.235665 | 0.00353497
3005709 | 02_Second Floor | 98.1935 | 0.121432 | 0.235665 | 0.00353497
3005710 | 02_Second Floor | 98.1935 | 0.121432 | 0.235665 | 0.00353497
3005711 | 02_Second Floor | 98.1935 | 0.121432 | 0.235665 | 0.00353497
3005712 | 02_Second Floor | 101.194 | 0.125032 | 0.246465 | 0.00364297
3005713 | 02_Second Floor | 238 | 0.2892 | 0.5784 | 0.008568
3005714 | 02_Second Floor | 238 | 0.2892 | 0.5784 | 0.008568
3005715 | 02_Second Floor | 238 | 0.2892 | 0.5784 | 0.008568
3005716 | 02_Second Floor | 238 | 0.2892 | 0.5784 | 0.008568
3005717 | 02_Second Floor | 238 | 0.2892 | 0.5784 | 0.008568
3005718 | 02_Second Floor | 238 | 0.2892 | 0.5784 | 0.008568
3005719 | 02_Second Floor | 238 | 0.2892 | 0.5784 | 0.008568
3005720 | 02_Second Floor | 238 | 0.2892 | 0.5784 | 0.008568
3005721 | 02_Second Floor | 238 | 0.2892 | 0.5784 | 0.008568
3005722 | 02_Second Floor | 238 | 0.2892 | 0.5784 | 0.008568
3005723 | 02_Second Floor | 238 | 0.2892 | 0.5784 | 0.008568
3005724 | 02_Second Floor | 238 | 0.2892 | 0.5784 | 0.008568
3005725 | 02_Second Floor | 238 | 0.2892 | 0.5784 | 0.008568
3005726 | 02_Second Floor | 238 | 0.2892 | 0.5784 | 0.008568
3005727 | 02_Second Floor | 238 | 0.2892 | 0.5784 | 0.008568
3005728 | 02_Second Floor | 238 | 0.2892 | 0.5784 | 0.008568
3005729 | 02_Second Floor | 238 | 0.2892 | 0.5784 | 0.008568
3005730 | 02_Second Floor | 238 | 0.2892 | 0.5784 | 0.008568
3005731 | 02_Second Floor | 238 | 0.2892 | 0.5784 | 0.008568
3005732 | 02_Second Floor | 238 | 0.2892 | 0.5784 | 0.008568
3005733 | 02_Second Floor | 238 | 0.2892 | 0.5784 | 0.008568
3005734 | 02_Second Floor | 238 | 0.2892 | 0.5784 | 0.008568
3005735 | 02_Second Floor | 238 | 0.2892 | 0.5784 | 0.008568
3005736 | 02_Second Floor | 238 | 0.2892 | 0.5784 | 0.008568
3005737 | 02_Second Floor | 238 | 0.2892 | 0.5784 | 0.008568
3005738 | 02_Second Floor | 238 | 0.2892 | 0.5784 | 0.008568
3005739 | 02_Second Floor | 238 | 0.2892 | 0.5784 | 0.008568
3005740 | 02_Second Floor | 238 | 0.2892 | 0.5784 | 0.008568
3005741 | 02_Second Floor | 238 | 0.2892 | 0.5784 | 0.008568
3005742 | 02_Second Floor | 238 | 0.2892 | 0.5784 | 0.008568
3005743 | 02_Second Floor | 238 | 0.2892 | 0.5784 | 0.008568
3005744 | 02_Second Floor | 238 | 0.2892 | 0.5784 | 0.008568
3007632 | 03_Third Floor | 102.843 | 0.127012 | 0.250424 | 0.00370235
3007633 | 03_Third Floor | 102.843 | 0.127012 | 0.250424 | 0.00370235
3007634 | 03_Third Floor | 99.8431 | 0.123412 | 0.239624 | 0.00359435
3007635 | 03_Third Floor | 99.8431 | 0.123412 | 0.239624 | 0.00359435
3007636 | 03_Third Floor | 99.8431 | 0.123412 | 0.239624 | 0.00359435
3007637 | 03_Third Floor | 99.8431 | 0.123412 | 0.239624 | 0.00359435
3007638 | 03_Third Floor | 99.8431 | 0.123412 | 0.239624 | 0.00359435
3007639 | 03_Third Floor | 99.8431 | 0.123412 | 0.239624 | 0.00359435
3007640 | 03_Third Floor | 99.8431 | 0.123412 | 0.239624 | 0.00359435
3007641 | 03_Third Floor | 99.8431 | 0.123412 | 0.239624 | 0.00359435
3007642 | 03_Third Floor | 99.8431 | 0.123412 | 0.239624 | 0.00359435
3007643 | 03_Third Floor | 99.8431 | 0.123412 | 0.239624 | 0.00359435
3007644 | 03_Third Floor | 99.8431 | 0.123412 | 0.239624 | 0.00359435
3007645 | 03_Third Floor | 99.8431 | 0.123412 | 0.239624 | 0.00359435
3007646 | 03_Third Floor | 99.8431 | 0.123412 | 0.239624 | 0.00359435
3007647 | 03_Third Floor | 99.8431 | 0.123412 | 0.239624 | 0.00359435
3007648 | 03_Third Floor | 99.8431 | 0.123412 | 0.239624 | 0.00359435
3007649 | 03_Third Floor | 99.8431 | 0.123412 | 0.239624 | 0.00359435
3007650 | 03_Third Floor | 99.8431 | 0.123412 | 0.239624 | 0.00359435
3007651 | 03_Third Floor | 99.8431 | 0.123412 | 0.239624 | 0.00359435
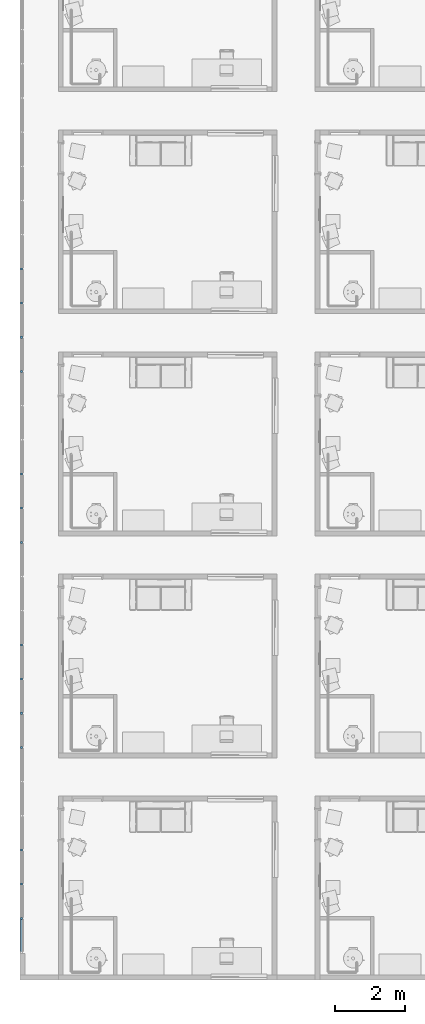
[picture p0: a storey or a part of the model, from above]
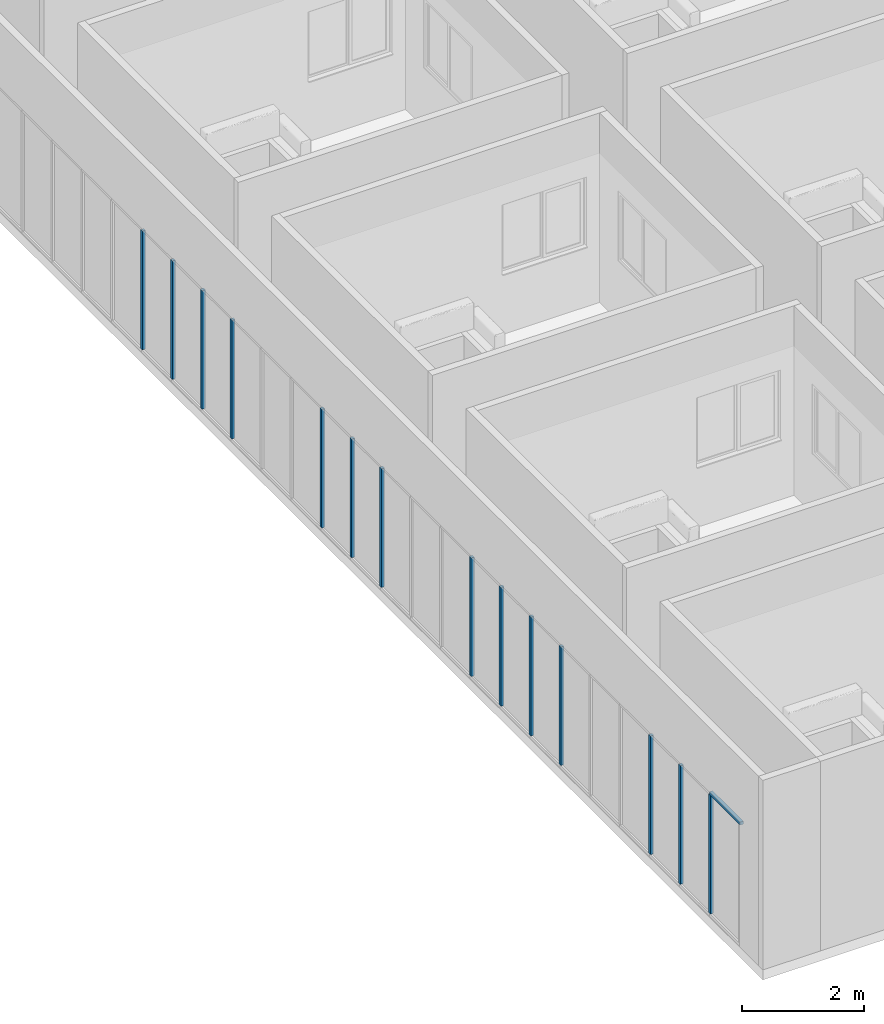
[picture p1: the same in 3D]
Properties of the parts of a building model (IFC4), part 7 of 14

# IfcMember: Rectangular Mullion:30-_Stijl_Rechthoek_Midden_B60xD60 (1984)
Name (Rectangular Mullion:30-_Stijl_Rechthoek_Midden_B60xD60:...) | In | Length (cm) | CrossSectionArea (m2) | NetSurfaceArea (m2) | NetVolume (m3)
3007652 | 03_Third Floor | 99.8431 | 0.123412 | 0.239624 | 0.00359435
3007653 | 03_Third Floor | 99.8431 | 0.123412 | 0.239624 | 0.00359435
3007654 | 03_Third Floor | 99.8431 | 0.123412 | 0.239624 | 0.00359435
3007655 | 03_Third Floor | 99.8431 | 0.123412 | 0.239624 | 0.00359435
3007656 | 03_Third Floor | 99.8431 | 0.123412 | 0.239624 | 0.00359435
3007657 | 03_Third Floor | 99.8431 | 0.123412 | 0.239624 | 0.00359435
3007658 | 03_Third Floor | 99.8431 | 0.123412 | 0.239624 | 0.00359435
3007659 | 03_Third Floor | 99.8431 | 0.123412 | 0.239624 | 0.00359435
3007660 | 03_Third Floor | 99.8431 | 0.123412 | 0.239624 | 0.00359435
3007661 | 03_Third Floor | 99.8431 | 0.123412 | 0.239624 | 0.00359435
3007662 | 03_Third Floor | 99.8431 | 0.123412 | 0.239624 | 0.00359435
3007663 | 03_Third Floor | 99.8431 | 0.123412 | 0.239624 | 0.00359435
3007664 | 03_Third Floor | 99.8431 | 0.123412 | 0.239624 | 0.00359435
3007665 | 03_Third Floor | 99.8431 | 0.123412 | 0.239624 | 0.00359435
3007666 | 03_Third Floor | 99.8431 | 0.123412 | 0.239624 | 0.00359435
3007667 | 03_Third Floor | 99.8431 | 0.123412 | 0.239624 | 0.00359435
3007668 | 03_Third Floor | 99.8431 | 0.123412 | 0.239624 | 0.00359435
3007669 | 03_Third Floor | 99.8431 | 0.123412 | 0.239624 | 0.00359435
3007670 | 03_Third Floor | 99.8431 | 0.123412 | 0.239624 | 0.00359435
3007671 | 03_Third Floor | 99.8431 | 0.123412 | 0.239624 | 0.00359435
3007672 | 03_Third Floor | 99.8431 | 0.123412 | 0.239624 | 0.00359435
3007673 | 03_Third Floor | 99.8431 | 0.123412 | 0.239624 | 0.00359435
3007674 | 03_Third Floor | 99.8431 | 0.123412 | 0.239624 | 0.00359435
3007675 | 03_Third Floor | 99.8431 | 0.123412 | 0.239624 | 0.00359435
3007676 | 03_Third Floor | 99.8431 | 0.123412 | 0.239624 | 0.00359435
3007677 | 03_Third Floor | 99.8431 | 0.123412 | 0.239624 | 0.00359435
3007678 | 03_Third Floor | 99.8431 | 0.123412 | 0.239624 | 0.00359435
3007679 | 03_Third Floor | 99.8431 | 0.123412 | 0.239624 | 0.00359435
3007680 | 03_Third Floor | 99.8431 | 0.123412 | 0.239624 | 0.00359435
3007681 | 03_Third Floor | 99.8431 | 0.123412 | 0.239624 | 0.00359435
3007682 | 03_Third Floor | 99.8431 | 0.123412 | 0.239624 | 0.00359435
3007683 | 03_Third Floor | 102.843 | 0.127012 | 0.250424 | 0.00370235
3007684 | 03_Third Floor | 99.8431 | 0.123412 | 0.239624 | 0.00359435
3007685 | 03_Third Floor | 99.8431 | 0.123412 | 0.239624 | 0.00359435
3007686 | 03_Third Floor | 99.8431 | 0.123412 | 0.239624 | 0.00359435
3007687 | 03_Third Floor | 99.8431 | 0.123412 | 0.239624 | 0.00359435
3007688 | 03_Third Floor | 99.8431 | 0.123412 | 0.239624 | 0.00359435
3007689 | 03_Third Floor | 99.8431 | 0.123412 | 0.239624 | 0.00359435
3007690 | 03_Third Floor | 99.8431 | 0.123412 | 0.239624 | 0.00359435
3007691 | 03_Third Floor | 99.8431 | 0.123412 | 0.239624 | 0.00359435
3007692 | 03_Third Floor | 99.8431 | 0.123412 | 0.239624 | 0.00359435
3007693 | 03_Third Floor | 99.8431 | 0.123412 | 0.239624 | 0.00359435
3007694 | 03_Third Floor | 99.8431 | 0.123412 | 0.239624 | 0.00359435
3007695 | 03_Third Floor | 99.8431 | 0.123412 | 0.239624 | 0.00359435
3007696 | 03_Third Floor | 99.8431 | 0.123412 | 0.239624 | 0.00359435
3007697 | 03_Third Floor | 99.8431 | 0.123412 | 0.239624 | 0.00359435
3007698 | 03_Third Floor | 99.8431 | 0.123412 | 0.239624 | 0.00359435
3007699 | 03_Third Floor | 99.8431 | 0.123412 | 0.239624 | 0.00359435
3007700 | 03_Third Floor | 99.8431 | 0.123412 | 0.239624 | 0.00359435
3007701 | 03_Third Floor | 99.8431 | 0.123412 | 0.239624 | 0.00359435
3007702 | 03_Third Floor | 99.8431 | 0.123412 | 0.239624 | 0.00359435
3007703 | 03_Third Floor | 99.8431 | 0.123412 | 0.239624 | 0.00359435
3007704 | 03_Third Floor | 99.8431 | 0.123412 | 0.239624 | 0.00359435
3007705 | 03_Third Floor | 99.8431 | 0.123412 | 0.239624 | 0.00359435
3007706 | 03_Third Floor | 99.8431 | 0.123412 | 0.239624 | 0.00359435
3007707 | 03_Third Floor | 99.8431 | 0.123412 | 0.239624 | 0.00359435
3007708 | 03_Third Floor | 99.8431 | 0.123412 | 0.239624 | 0.00359435
3007709 | 03_Third Floor | 99.8431 | 0.123412 | 0.239624 | 0.00359435
3007710 | 03_Third Floor | 99.8431 | 0.123412 | 0.239624 | 0.00359435
3007711 | 03_Third Floor | 99.8431 | 0.123412 | 0.239624 | 0.00359435
3007712 | 03_Third Floor | 99.8431 | 0.123412 | 0.239624 | 0.00359435
3007713 | 03_Third Floor | 99.8431 | 0.123412 | 0.239624 | 0.00359435
3007714 | 03_Third Floor | 99.8431 | 0.123412 | 0.239624 | 0.00359435
3007715 | 03_Third Floor | 99.8431 | 0.123412 | 0.239624 | 0.00359435
3007716 | 03_Third Floor | 99.8431 | 0.123412 | 0.239624 | 0.00359435
3007717 | 03_Third Floor | 99.8431 | 0.123412 | 0.239624 | 0.00359435
3007718 | 03_Third Floor | 99.8431 | 0.123412 | 0.239624 | 0.00359435
3007719 | 03_Third Floor | 99.8431 | 0.123412 | 0.239624 | 0.00359435
3007720 | 03_Third Floor | 99.8431 | 0.123412 | 0.239624 | 0.00359435
3007721 | 03_Third Floor | 99.8431 | 0.123412 | 0.239624 | 0.00359435
3007722 | 03_Third Floor | 99.8431 | 0.123412 | 0.239624 | 0.00359435
3007723 | 03_Third Floor | 99.8431 | 0.123412 | 0.239624 | 0.00359435
3007724 | 03_Third Floor | 99.8431 | 0.123412 | 0.239624 | 0.00359435
3007725 | 03_Third Floor | 99.8431 | 0.123412 | 0.239624 | 0.00359435
3007726 | 03_Third Floor | 99.8431 | 0.123412 | 0.239624 | 0.00359435
3007727 | 03_Third Floor | 99.8431 | 0.123412 | 0.239624 | 0.00359435
3007728 | 03_Third Floor | 99.8431 | 0.123412 | 0.239624 | 0.00359435
3007729 | 03_Third Floor | 99.8431 | 0.123412 | 0.239624 | 0.00359435
3007730 | 03_Third Floor | 99.8431 | 0.123412 | 0.239624 | 0.00359435
3007731 | 03_Third Floor | 99.8431 | 0.123412 | 0.239624 | 0.00359435
3007732 | 03_Third Floor | 99.8431 | 0.123412 | 0.239624 | 0.00359435
3007733 | 03_Third Floor | 102.843 | 0.127012 | 0.250424 | 0.00370235
3007734 | 03_Third Floor | 238 | 0.2892 | 0.5784 | 0.008568
3007735 | 03_Third Floor | 238 | 0.2892 | 0.5784 | 0.008568
3007736 | 03_Third Floor | 238 | 0.2892 | 0.5784 | 0.008568
3007737 | 03_Third Floor | 238 | 0.2892 | 0.5784 | 0.008568
3007738 | 03_Third Floor | 238 | 0.2892 | 0.5784 | 0.008568
3007739 | 03_Third Floor | 238 | 0.2892 | 0.5784 | 0.008568
3007740 | 03_Third Floor | 238 | 0.2892 | 0.5784 | 0.008568
3007741 | 03_Third Floor | 238 | 0.2892 | 0.5784 | 0.008568
3007742 | 03_Third Floor | 238 | 0.2892 | 0.5784 | 0.008568
3007743 | 03_Third Floor | 238 | 0.2892 | 0.5784 | 0.008568
3007744 | 03_Third Floor | 238 | 0.2892 | 0.5784 | 0.008568
3007745 | 03_Third Floor | 238 | 0.2892 | 0.5784 | 0.008568
3007746 | 03_Third Floor | 238 | 0.2892 | 0.5784 | 0.008568
3007747 | 03_Third Floor | 238 | 0.2892 | 0.5784 | 0.008568
3007748 | 03_Third Floor | 238 | 0.2892 | 0.5784 | 0.008568
3007749 | 03_Third Floor | 238 | 0.2892 | 0.5784 | 0.008568
3007750 | 03_Third Floor | 238 | 0.2892 | 0.5784 | 0.008568
3007751 | 03_Third Floor | 238 | 0.2892 | 0.5784 | 0.008568
3007752 | 03_Third Floor | 238 | 0.2892 | 0.5784 | 0.008568
3007753 | 03_Third Floor | 238 | 0.2892 | 0.5784 | 0.008568
3007754 | 03_Third Floor | 238 | 0.2892 | 0.5784 | 0.008568
3007755 | 03_Third Floor | 238 | 0.2892 | 0.5784 | 0.008568
3007756 | 03_Third Floor | 238 | 0.2892 | 0.5784 | 0.008568
3007757 | 03_Third Floor | 238 | 0.2892 | 0.5784 | 0.008568
3007758 | 03_Third Floor | 238 | 0.2892 | 0.5784 | 0.008568
3007759 | 03_Third Floor | 238 | 0.2892 | 0.5784 | 0.008568
3007760 | 03_Third Floor | 238 | 0.2892 | 0.5784 | 0.008568
3007761 | 03_Third Floor | 238 | 0.2892 | 0.5784 | 0.008568
3007762 | 03_Third Floor | 238 | 0.2892 | 0.5784 | 0.008568
3007763 | 03_Third Floor | 238 | 0.2892 | 0.5784 | 0.008568
3007764 | 03_Third Floor | 238 | 0.2892 | 0.5784 | 0.008568
3007765 | 03_Third Floor | 238 | 0.2892 | 0.5784 | 0.008568
3007766 | 03_Third Floor | 238 | 0.2892 | 0.5784 | 0.008568
3007767 | 03_Third Floor | 238 | 0.2892 | 0.5784 | 0.008568
3007768 | 03_Third Floor | 238 | 0.2892 | 0.5784 | 0.008568
3007769 | 03_Third Floor | 238 | 0.2892 | 0.5784 | 0.008568
3007770 | 03_Third Floor | 238 | 0.2892 | 0.5784 | 0.008568
3007771 | 03_Third Floor | 238 | 0.2892 | 0.5784 | 0.008568
3007772 | 03_Third Floor | 238 | 0.2892 | 0.5784 | 0.008568
3007773 | 03_Third Floor | 238 | 0.2892 | 0.5784 | 0.008568
3007774 | 03_Third Floor | 238 | 0.2892 | 0.5784 | 0.008568
3007775 | 03_Third Floor | 238 | 0.2892 | 0.5784 | 0.008568
3007776 | 03_Third Floor | 238 | 0.2892 | 0.5784 | 0.008568
3007777 | 03_Third Floor | 238 | 0.2892 | 0.5784 | 0.008568
3007778 | 03_Third Floor | 238 | 0.2892 | 0.5784 | 0.008568
3007779 | 03_Third Floor | 238 | 0.2892 | 0.5784 | 0.008568
3007780 | 03_Third Floor | 238 | 0.2892 | 0.5784 | 0.008568
3007781 | 03_Third Floor | 238 | 0.2892 | 0.5784 | 0.008568
3007782 | 03_Third Floor | 238 | 0.2892 | 0.5784 | 0.008568
3007783 | 03_Third Floor | 238 | 0.2892 | 0.5784 | 0.008568
3007784 | 03_Third Floor | 238 | 0.2892 | 0.5784 | 0.008568
3007785 | 03_Third Floor | 238 | 0.2892 | 0.5784 | 0.008568
3007848 | 03_Third Floor | 101.194 | 0.125032 | 0.246465 | 0.00364297
3007849 | 03_Third Floor | 101.194 | 0.125032 | 0.246465 | 0.00364297
3007850 | 03_Third Floor | 98.1935 | 0.121432 | 0.235665 | 0.00353497
3007851 | 03_Third Floor | 98.1935 | 0.121432 | 0.235665 | 0.00353497
3007852 | 03_Third Floor | 98.1935 | 0.121432 | 0.235665 | 0.00353497
3007853 | 03_Third Floor | 98.1935 | 0.121432 | 0.235665 | 0.00353497
3007854 | 03_Third Floor | 98.1935 | 0.121432 | 0.235665 | 0.00353497
3007855 | 03_Third Floor | 98.1935 | 0.121432 | 0.235665 | 0.00353497
3007856 | 03_Third Floor | 98.1935 | 0.121432 | 0.235665 | 0.00353497
3007857 | 03_Third Floor | 98.1935 | 0.121432 | 0.235665 | 0.00353497
3007858 | 03_Third Floor | 98.1935 | 0.121432 | 0.235665 | 0.00353497
3007859 | 03_Third Floor | 98.1935 | 0.121432 | 0.235665 | 0.00353497
3007860 | 03_Third Floor | 98.1935 | 0.121432 | 0.235665 | 0.00353497
3007861 | 03_Third Floor | 98.1935 | 0.121432 | 0.235665 | 0.00353497
3007862 | 03_Third Floor | 98.1935 | 0.121432 | 0.235665 | 0.00353497
3007863 | 03_Third Floor | 98.1935 | 0.121432 | 0.235665 | 0.00353497
3007864 | 03_Third Floor | 98.1935 | 0.121432 | 0.235665 | 0.00353497
3007865 | 03_Third Floor | 98.1935 | 0.121432 | 0.235665 | 0.00353497
3007866 | 03_Third Floor | 98.1935 | 0.121432 | 0.235665 | 0.00353497
3007867 | 03_Third Floor | 98.1935 | 0.121432 | 0.235665 | 0.00353497
3007868 | 03_Third Floor | 98.1935 | 0.121432 | 0.235665 | 0.00353497
3007869 | 03_Third Floor | 98.1935 | 0.121432 | 0.235665 | 0.00353497
3007870 | 03_Third Floor | 98.1935 | 0.121432 | 0.235665 | 0.00353497
3007871 | 03_Third Floor | 98.1935 | 0.121432 | 0.235665 | 0.00353497
3007872 | 03_Third Floor | 98.1935 | 0.121432 | 0.235665 | 0.00353497
3007873 | 03_Third Floor | 98.1935 | 0.121432 | 0.235665 | 0.00353497
3007874 | 03_Third Floor | 98.1935 | 0.121432 | 0.235665 | 0.00353497
3007875 | 03_Third Floor | 98.1935 | 0.121432 | 0.235665 | 0.00353497
3007876 | 03_Third Floor | 98.1935 | 0.121432 | 0.235665 | 0.00353497
3007877 | 03_Third Floor | 98.1935 | 0.121432 | 0.235665 | 0.00353497
3007878 | 03_Third Floor | 98.1935 | 0.121432 | 0.235665 | 0.00353497
3007879 | 03_Third Floor | 101.194 | 0.125032 | 0.246465 | 0.00364297
3007880 | 03_Third Floor | 98.1935 | 0.121432 | 0.235665 | 0.00353497
3007881 | 03_Third Floor | 98.1935 | 0.121432 | 0.235665 | 0.00353497
3007882 | 03_Third Floor | 98.1935 | 0.121432 | 0.235665 | 0.00353497
3007883 | 03_Third Floor | 98.1935 | 0.121432 | 0.235665 | 0.00353497
3007884 | 03_Third Floor | 98.1935 | 0.121432 | 0.235665 | 0.00353497
3007885 | 03_Third Floor | 98.1935 | 0.121432 | 0.235665 | 0.00353497
3007886 | 03_Third Floor | 98.1935 | 0.121432 | 0.235665 | 0.00353497
3007887 | 03_Third Floor | 98.1935 | 0.121432 | 0.235665 | 0.00353497
3007888 | 03_Third Floor | 98.1935 | 0.121432 | 0.235665 | 0.00353497
3007889 | 03_Third Floor | 98.1935 | 0.121432 | 0.235665 | 0.00353497
3007890 | 03_Third Floor | 98.1935 | 0.121432 | 0.235665 | 0.00353497
3007891 | 03_Third Floor | 98.1935 | 0.121432 | 0.235665 | 0.00353497
3007892 | 03_Third Floor | 98.1935 | 0.121432 | 0.235665 | 0.00353497
3007893 | 03_Third Floor | 98.1935 | 0.121432 | 0.235665 | 0.00353497
3007894 | 03_Third Floor | 98.1935 | 0.121432 | 0.235665 | 0.00353497
3007895 | 03_Third Floor | 98.1935 | 0.121432 | 0.235665 | 0.00353497
3007896 | 03_Third Floor | 98.1935 | 0.121432 | 0.235665 | 0.00353497
3007897 | 03_Third Floor | 98.1935 | 0.121432 | 0.235665 | 0.00353497
3007898 | 03_Third Floor | 98.1935 | 0.121432 | 0.235665 | 0.00353497
3007899 | 03_Third Floor | 98.1935 | 0.121432 | 0.235665 | 0.00353497
3007900 | 03_Third Floor | 98.1935 | 0.121432 | 0.235665 | 0.00353497
3007901 | 03_Third Floor | 98.1935 | 0.121432 | 0.235665 | 0.00353497
3007902 | 03_Third Floor | 98.1935 | 0.121432 | 0.235665 | 0.00353497
3007903 | 03_Third Floor | 98.1935 | 0.121432 | 0.235665 | 0.00353497
3007904 | 03_Third Floor | 98.1935 | 0.121432 | 0.235665 | 0.00353497
3007905 | 03_Third Floor | 98.1935 | 0.121432 | 0.235665 | 0.00353497
3007906 | 03_Third Floor | 98.1935 | 0.121432 | 0.235665 | 0.00353497
3007907 | 03_Third Floor | 98.1935 | 0.121432 | 0.235665 | 0.00353497
3007908 | 03_Third Floor | 98.1935 | 0.121432 | 0.235665 | 0.00353497
3007909 | 03_Third Floor | 101.194 | 0.125032 | 0.246465 | 0.00364297
3007910 | 03_Third Floor | 238 | 0.2892 | 0.5784 | 0.008568
3007911 | 03_Third Floor | 238 | 0.2892 | 0.5784 | 0.008568
3007912 | 03_Third Floor | 238 | 0.2892 | 0.5784 | 0.008568
3007913 | 03_Third Floor | 238 | 0.2892 | 0.5784 | 0.008568
3007914 | 03_Third Floor | 238 | 0.2892 | 0.5784 | 0.008568
3007915 | 03_Third Floor | 238 | 0.2892 | 0.5784 | 0.008568
3007916 | 03_Third Floor | 238 | 0.2892 | 0.5784 | 0.008568
3007917 | 03_Third Floor | 238 | 0.2892 | 0.5784 | 0.008568
3007918 | 03_Third Floor | 238 | 0.2892 | 0.5784 | 0.008568
3007919 | 03_Third Floor | 238 | 0.2892 | 0.5784 | 0.008568
3007920 | 03_Third Floor | 238 | 0.2892 | 0.5784 | 0.008568
3007921 | 03_Third Floor | 238 | 0.2892 | 0.5784 | 0.008568
3007922 | 03_Third Floor | 238 | 0.2892 | 0.5784 | 0.008568
3007923 | 03_Third Floor | 238 | 0.2892 | 0.5784 | 0.008568
3007924 | 03_Third Floor | 238 | 0.2892 | 0.5784 | 0.008568
3007925 | 03_Third Floor | 238 | 0.2892 | 0.5784 | 0.008568
3007926 | 03_Third Floor | 238 | 0.2892 | 0.5784 | 0.008568
3007927 | 03_Third Floor | 238 | 0.2892 | 0.5784 | 0.008568
3007928 | 03_Third Floor | 238 | 0.2892 | 0.5784 | 0.008568
3007929 | 03_Third Floor | 238 | 0.2892 | 0.5784 | 0.008568
3007930 | 03_Third Floor | 238 | 0.2892 | 0.5784 | 0.008568
3007931 | 03_Third Floor | 238 | 0.2892 | 0.5784 | 0.008568
3007932 | 03_Third Floor | 238 | 0.2892 | 0.5784 | 0.008568
3007933 | 03_Third Floor | 238 | 0.2892 | 0.5784 | 0.008568
3007934 | 03_Third Floor | 238 | 0.2892 | 0.5784 | 0.008568
3007935 | 03_Third Floor | 238 | 0.2892 | 0.5784 | 0.008568
3007936 | 03_Third Floor | 238 | 0.2892 | 0.5784 | 0.008568
3007937 | 03_Third Floor | 238 | 0.2892 | 0.5784 | 0.008568
3007938 | 03_Third Floor | 238 | 0.2892 | 0.5784 | 0.008568
3007939 | 03_Third Floor | 238 | 0.2892 | 0.5784 | 0.008568
3007940 | 03_Third Floor | 238 | 0.2892 | 0.5784 | 0.008568
3007941 | 03_Third Floor | 238 | 0.2892 | 0.5784 | 0.008568
3009827 | 04_Fourth Floor | 102.843 | 0.127012 | 0.250424 | 0.00370235
3009828 | 04_Fourth Floor | 102.843 | 0.127012 | 0.250424 | 0.00370235
3009829 | 04_Fourth Floor | 99.8431 | 0.123412 | 0.239624 | 0.00359435
3009830 | 04_Fourth Floor | 99.8431 | 0.123412 | 0.239624 | 0.00359435
3009831 | 04_Fourth Floor | 99.8431 | 0.123412 | 0.239624 | 0.00359435
3009832 | 04_Fourth Floor | 99.8431 | 0.123412 | 0.239624 | 0.00359435
3009833 | 04_Fourth Floor | 99.8431 | 0.123412 | 0.239624 | 0.00359435
3009834 | 04_Fourth Floor | 99.8431 | 0.123412 | 0.239624 | 0.00359435
3009835 | 04_Fourth Floor | 99.8431 | 0.123412 | 0.239624 | 0.00359435
3009836 | 04_Fourth Floor | 99.8431 | 0.123412 | 0.239624 | 0.00359435
3009837 | 04_Fourth Floor | 99.8431 | 0.123412 | 0.239624 | 0.00359435
3009838 | 04_Fourth Floor | 99.8431 | 0.123412 | 0.239624 | 0.00359435
3009839 | 04_Fourth Floor | 99.8431 | 0.123412 | 0.239624 | 0.00359435
3009840 | 04_Fourth Floor | 99.8431 | 0.123412 | 0.239624 | 0.00359435
3009841 | 04_Fourth Floor | 99.8431 | 0.123412 | 0.239624 | 0.00359435
3009842 | 04_Fourth Floor | 99.8431 | 0.123412 | 0.239624 | 0.00359435
3009843 | 04_Fourth Floor | 99.8431 | 0.123412 | 0.239624 | 0.00359435
3009844 | 04_Fourth Floor | 99.8431 | 0.123412 | 0.239624 | 0.00359435
3009845 | 04_Fourth Floor | 99.8431 | 0.123412 | 0.239624 | 0.00359435
3009846 | 04_Fourth Floor | 99.8431 | 0.123412 | 0.239624 | 0.00359435
3009847 | 04_Fourth Floor | 99.8431 | 0.123412 | 0.239624 | 0.00359435
3009848 | 04_Fourth Floor | 99.8431 | 0.123412 | 0.239624 | 0.00359435
3009849 | 04_Fourth Floor | 99.8431 | 0.123412 | 0.239624 | 0.00359435
3009850 | 04_Fourth Floor | 99.8431 | 0.123412 | 0.239624 | 0.00359435
3009851 | 04_Fourth Floor | 99.8431 | 0.123412 | 0.239624 | 0.00359435
3009852 | 04_Fourth Floor | 99.8431 | 0.123412 | 0.239624 | 0.00359435
3009853 | 04_Fourth Floor | 99.8431 | 0.123412 | 0.239624 | 0.00359435
3009854 | 04_Fourth Floor | 99.8431 | 0.123412 | 0.239624 | 0.00359435
3009855 | 04_Fourth Floor | 99.8431 | 0.123412 | 0.239624 | 0.00359435
3009856 | 04_Fourth Floor | 99.8431 | 0.123412 | 0.239624 | 0.00359435
3009857 | 04_Fourth Floor | 99.8431 | 0.123412 | 0.239624 | 0.00359435
3009858 | 04_Fourth Floor | 99.8431 | 0.123412 | 0.239624 | 0.00359435
3009859 | 04_Fourth Floor | 99.8431 | 0.123412 | 0.239624 | 0.00359435
3009860 | 04_Fourth Floor | 99.8431 | 0.123412 | 0.239624 | 0.00359435
3009861 | 04_Fourth Floor | 99.8431 | 0.123412 | 0.239624 | 0.00359435
3009862 | 04_Fourth Floor | 99.8431 | 0.123412 | 0.239624 | 0.00359435
3009863 | 04_Fourth Floor | 99.8431 | 0.123412 | 0.239624 | 0.00359435
3009864 | 04_Fourth Floor | 99.8431 | 0.123412 | 0.239624 | 0.00359435
3009865 | 04_Fourth Floor | 99.8431 | 0.123412 | 0.239624 | 0.00359435
3009866 | 04_Fourth Floor | 99.8431 | 0.123412 | 0.239624 | 0.00359435
3009867 | 04_Fourth Floor | 99.8431 | 0.123412 | 0.239624 | 0.00359435
3009868 | 04_Fourth Floor | 99.8431 | 0.123412 | 0.239624 | 0.00359435
3009869 | 04_Fourth Floor | 99.8431 | 0.123412 | 0.239624 | 0.00359435
3009870 | 04_Fourth Floor | 99.8431 | 0.123412 | 0.239624 | 0.00359435
3009871 | 04_Fourth Floor | 99.8431 | 0.123412 | 0.239624 | 0.00359435
3009872 | 04_Fourth Floor | 99.8431 | 0.123412 | 0.239624 | 0.00359435
3009873 | 04_Fourth Floor | 99.8431 | 0.123412 | 0.239624 | 0.00359435
3009874 | 04_Fourth Floor | 99.8431 | 0.123412 | 0.239624 | 0.00359435
3009875 | 04_Fourth Floor | 99.8431 | 0.123412 | 0.239624 | 0.00359435
3009876 | 04_Fourth Floor | 99.8431 | 0.123412 | 0.239624 | 0.00359435
3009877 | 04_Fourth Floor | 99.8431 | 0.123412 | 0.239624 | 0.00359435
3009878 | 04_Fourth Floor | 102.843 | 0.127012 | 0.250424 | 0.00370235
3009879 | 04_Fourth Floor | 99.8431 | 0.123412 | 0.239624 | 0.00359435
3009880 | 04_Fourth Floor | 99.8431 | 0.123412 | 0.239624 | 0.00359435
3009881 | 04_Fourth Floor | 99.8431 | 0.123412 | 0.239624 | 0.00359435
3009882 | 04_Fourth Floor | 99.8431 | 0.123412 | 0.239624 | 0.00359435
3009883 | 04_Fourth Floor | 99.8431 | 0.123412 | 0.239624 | 0.00359435
3009884 | 04_Fourth Floor | 99.8431 | 0.123412 | 0.239624 | 0.00359435
3009885 | 04_Fourth Floor | 99.8431 | 0.123412 | 0.239624 | 0.00359435
3009886 | 04_Fourth Floor | 99.8431 | 0.123412 | 0.239624 | 0.00359435
3009887 | 04_Fourth Floor | 99.8431 | 0.123412 | 0.239624 | 0.00359435
3009888 | 04_Fourth Floor | 99.8431 | 0.123412 | 0.239624 | 0.00359435
3009889 | 04_Fourth Floor | 99.8431 | 0.123412 | 0.239624 | 0.00359435
3009890 | 04_Fourth Floor | 99.8431 | 0.123412 | 0.239624 | 0.00359435
3009891 | 04_Fourth Floor | 99.8431 | 0.123412 | 0.239624 | 0.00359435
3009892 | 04_Fourth Floor | 99.8431 | 0.123412 | 0.239624 | 0.00359435
3009893 | 04_Fourth Floor | 99.8431 | 0.123412 | 0.239624 | 0.00359435
3009894 | 04_Fourth Floor | 99.8431 | 0.123412 | 0.239624 | 0.00359435
3009895 | 04_Fourth Floor | 99.8431 | 0.123412 | 0.239624 | 0.00359435
3009896 | 04_Fourth Floor | 99.8431 | 0.123412 | 0.239624 | 0.00359435
3009897 | 04_Fourth Floor | 99.8431 | 0.123412 | 0.239624 | 0.00359435
3009898 | 04_Fourth Floor | 99.8431 | 0.123412 | 0.239624 | 0.00359435
3009899 | 04_Fourth Floor | 99.8431 | 0.123412 | 0.239624 | 0.00359435
3009900 | 04_Fourth Floor | 99.8431 | 0.123412 | 0.239624 | 0.00359435
3009901 | 04_Fourth Floor | 99.8431 | 0.123412 | 0.239624 | 0.00359435
3009902 | 04_Fourth Floor | 99.8431 | 0.123412 | 0.239624 | 0.00359435
3009903 | 04_Fourth Floor | 99.8431 | 0.123412 | 0.239624 | 0.00359435
3009904 | 04_Fourth Floor | 99.8431 | 0.123412 | 0.239624 | 0.00359435
3009905 | 04_Fourth Floor | 99.8431 | 0.123412 | 0.239624 | 0.00359435
3009906 | 04_Fourth Floor | 99.8431 | 0.123412 | 0.239624 | 0.00359435
3009907 | 04_Fourth Floor | 99.8431 | 0.123412 | 0.239624 | 0.00359435
3009908 | 04_Fourth Floor | 99.8431 | 0.123412 | 0.239624 | 0.00359435
3009909 | 04_Fourth Floor | 99.8431 | 0.123412 | 0.239624 | 0.00359435
3009910 | 04_Fourth Floor | 99.8431 | 0.123412 | 0.239624 | 0.00359435
3009911 | 04_Fourth Floor | 99.8431 | 0.123412 | 0.239624 | 0.00359435
3009912 | 04_Fourth Floor | 99.8431 | 0.123412 | 0.239624 | 0.00359435
3009913 | 04_Fourth Floor | 99.8431 | 0.123412 | 0.239624 | 0.00359435
3009914 | 04_Fourth Floor | 99.8431 | 0.123412 | 0.239624 | 0.00359435
3009915 | 04_Fourth Floor | 99.8431 | 0.123412 | 0.239624 | 0.00359435
3009916 | 04_Fourth Floor | 99.8431 | 0.123412 | 0.239624 | 0.00359435
3009917 | 04_Fourth Floor | 99.8431 | 0.123412 | 0.239624 | 0.00359435
3009918 | 04_Fourth Floor | 99.8431 | 0.123412 | 0.239624 | 0.00359435
3009919 | 04_Fourth Floor | 99.8431 | 0.123412 | 0.239624 | 0.00359435
3009920 | 04_Fourth Floor | 99.8431 | 0.123412 | 0.239624 | 0.00359435
3009921 | 04_Fourth Floor | 99.8431 | 0.123412 | 0.239624 | 0.00359435
3009922 | 04_Fourth Floor | 99.8431 | 0.123412 | 0.239624 | 0.00359435
3009923 | 04_Fourth Floor | 99.8431 | 0.123412 | 0.239624 | 0.00359435
3009924 | 04_Fourth Floor | 99.8431 | 0.123412 | 0.239624 | 0.00359435
3009925 | 04_Fourth Floor | 99.8431 | 0.123412 | 0.239624 | 0.00359435
3009926 | 04_Fourth Floor | 99.8431 | 0.123412 | 0.239624 | 0.00359435
3009927 | 04_Fourth Floor | 99.8431 | 0.123412 | 0.239624 | 0.00359435
3009928 | 04_Fourth Floor | 102.843 | 0.127012 | 0.250424 | 0.00370235
3009929 | 04_Fourth Floor | 238 | 0.2892 | 0.5784 | 0.008568
3009930 | 04_Fourth Floor | 238 | 0.2892 | 0.5784 | 0.008568
3009931 | 04_Fourth Floor | 238 | 0.2892 | 0.5784 | 0.008568
3009932 | 04_Fourth Floor | 238 | 0.2892 | 0.5784 | 0.008568
3009933 | 04_Fourth Floor | 238 | 0.2892 | 0.5784 | 0.008568
3009934 | 04_Fourth Floor | 238 | 0.2892 | 0.5784 | 0.008568
3009935 | 04_Fourth Floor | 238 | 0.2892 | 0.5784 | 0.008568
3009936 | 04_Fourth Floor | 238 | 0.2892 | 0.5784 | 0.008568
3009937 | 04_Fourth Floor | 238 | 0.2892 | 0.5784 | 0.008568
3009938 | 04_Fourth Floor | 238 | 0.2892 | 0.5784 | 0.008568
3009939 | 04_Fourth Floor | 238 | 0.2892 | 0.5784 | 0.008568
3009940 | 04_Fourth Floor | 238 | 0.2892 | 0.5784 | 0.008568
3009941 | 04_Fourth Floor | 238 | 0.2892 | 0.5784 | 0.008568
3009942 | 04_Fourth Floor | 238 | 0.2892 | 0.5784 | 0.008568
3009943 | 04_Fourth Floor | 238 | 0.2892 | 0.5784 | 0.008568
3009944 | 04_Fourth Floor | 238 | 0.2892 | 0.5784 | 0.008568
3009945 | 04_Fourth Floor | 238 | 0.2892 | 0.5784 | 0.008568
3009946 | 04_Fourth Floor | 238 | 0.2892 | 0.5784 | 0.008568
3009947 | 04_Fourth Floor | 238 | 0.2892 | 0.5784 | 0.008568
3009948 | 04_Fourth Floor | 238 | 0.2892 | 0.5784 | 0.008568
3009949 | 04_Fourth Floor | 238 | 0.2892 | 0.5784 | 0.008568
3009950 | 04_Fourth Floor | 238 | 0.2892 | 0.5784 | 0.008568
3009951 | 04_Fourth Floor | 238 | 0.2892 | 0.5784 | 0.008568
3009952 | 04_Fourth Floor | 238 | 0.2892 | 0.5784 | 0.008568
3009953 | 04_Fourth Floor | 238 | 0.2892 | 0.5784 | 0.008568
3009954 | 04_Fourth Floor | 238 | 0.2892 | 0.5784 | 0.008568
3009955 | 04_Fourth Floor | 238 | 0.2892 | 0.5784 | 0.008568
3009956 | 04_Fourth Floor | 238 | 0.2892 | 0.5784 | 0.008568
3009957 | 04_Fourth Floor | 238 | 0.2892 | 0.5784 | 0.008568
3009958 | 04_Fourth Floor | 238 | 0.2892 | 0.5784 | 0.008568
3009959 | 04_Fourth Floor | 238 | 0.2892 | 0.5784 | 0.008568
3009960 | 04_Fourth Floor | 238 | 0.2892 | 0.5784 | 0.008568
3009961 | 04_Fourth Floor | 238 | 0.2892 | 0.5784 | 0.008568
3009962 | 04_Fourth Floor | 238 | 0.2892 | 0.5784 | 0.008568
3009963 | 04_Fourth Floor | 238 | 0.2892 | 0.5784 | 0.008568
3009964 | 04_Fourth Floor | 238 | 0.2892 | 0.5784 | 0.008568
3009965 | 04_Fourth Floor | 238 | 0.2892 | 0.5784 | 0.008568
3009966 | 04_Fourth Floor | 238 | 0.2892 | 0.5784 | 0.008568
3009967 | 04_Fourth Floor | 238 | 0.2892 | 0.5784 | 0.008568
3009968 | 04_Fourth Floor | 238 | 0.2892 | 0.5784 | 0.008568
3009969 | 04_Fourth Floor | 238 | 0.2892 | 0.5784 | 0.008568
3009970 | 04_Fourth Floor | 238 | 0.2892 | 0.5784 | 0.008568
3009971 | 04_Fourth Floor | 238 | 0.2892 | 0.5784 | 0.008568
3009972 | 04_Fourth Floor | 238 | 0.2892 | 0.5784 | 0.008568
3009973 | 04_Fourth Floor | 238 | 0.2892 | 0.5784 | 0.008568
3009974 | 04_Fourth Floor | 238 | 0.2892 | 0.5784 | 0.008568
3009975 | 04_Fourth Floor | 238 | 0.2892 | 0.5784 | 0.008568
3009976 | 04_Fourth Floor | 238 | 0.2892 | 0.5784 | 0.008568
3009977 | 04_Fourth Floor | 238 | 0.2892 | 0.5784 | 0.008568
3009978 | 04_Fourth Floor | 238 | 0.2892 | 0.5784 | 0.008568
3009979 | 04_Fourth Floor | 238 | 0.2892 | 0.5784 | 0.008568
3009980 | 04_Fourth Floor | 238 | 0.2892 | 0.5784 | 0.008568
3010043 | 04_Fourth Floor | 101.194 | 0.125032 | 0.246465 | 0.00364297
3010044 | 04_Fourth Floor | 101.194 | 0.125032 | 0.246465 | 0.00364297
3010045 | 04_Fourth Floor | 98.1935 | 0.121432 | 0.235665 | 0.00353497
3010046 | 04_Fourth Floor | 98.1935 | 0.121432 | 0.235665 | 0.00353497
3010047 | 04_Fourth Floor | 98.1935 | 0.121432 | 0.235665 | 0.00353497
3010048 | 04_Fourth Floor | 98.1935 | 0.121432 | 0.235665 | 0.00353497
3010049 | 04_Fourth Floor | 98.1935 | 0.121432 | 0.235665 | 0.00353497
3010050 | 04_Fourth Floor | 98.1935 | 0.121432 | 0.235665 | 0.00353497
3010051 | 04_Fourth Floor | 98.1935 | 0.121432 | 0.235665 | 0.00353497
3010052 | 04_Fourth Floor | 98.1935 | 0.121432 | 0.235665 | 0.00353497
3010053 | 04_Fourth Floor | 98.1935 | 0.121432 | 0.235665 | 0.00353497
3010054 | 04_Fourth Floor | 98.1935 | 0.121432 | 0.235665 | 0.00353497
3010055 | 04_Fourth Floor | 98.1935 | 0.121432 | 0.235665 | 0.00353497
3010056 | 04_Fourth Floor | 98.1935 | 0.121432 | 0.235665 | 0.00353497
3010057 | 04_Fourth Floor | 98.1935 | 0.121432 | 0.235665 | 0.00353497
3010058 | 04_Fourth Floor | 98.1935 | 0.121432 | 0.235665 | 0.00353497
3010059 | 04_Fourth Floor | 98.1935 | 0.121432 | 0.235665 | 0.00353497
3010060 | 04_Fourth Floor | 98.1935 | 0.121432 | 0.235665 | 0.00353497
3010061 | 04_Fourth Floor | 98.1935 | 0.121432 | 0.235665 | 0.00353497
3010062 | 04_Fourth Floor | 98.1935 | 0.121432 | 0.235665 | 0.00353497
3010063 | 04_Fourth Floor | 98.1935 | 0.121432 | 0.235665 | 0.00353497
3010064 | 04_Fourth Floor | 98.1935 | 0.121432 | 0.235665 | 0.00353497
3010065 | 04_Fourth Floor | 98.1935 | 0.121432 | 0.235665 | 0.00353497
3010066 | 04_Fourth Floor | 98.1935 | 0.121432 | 0.235665 | 0.00353497
3010067 | 04_Fourth Floor | 98.1935 | 0.121432 | 0.235665 | 0.00353497
3010068 | 04_Fourth Floor | 98.1935 | 0.121432 | 0.235665 | 0.00353497
3010069 | 04_Fourth Floor | 98.1935 | 0.121432 | 0.235665 | 0.00353497
3010070 | 04_Fourth Floor | 98.1935 | 0.121432 | 0.235665 | 0.00353497
3010071 | 04_Fourth Floor | 98.1935 | 0.121432 | 0.235665 | 0.00353497
3010072 | 04_Fourth Floor | 98.1935 | 0.121432 | 0.235665 | 0.00353497
3010073 | 04_Fourth Floor | 98.1935 | 0.121432 | 0.235665 | 0.00353497
3010074 | 04_Fourth Floor | 101.194 | 0.125032 | 0.246465 | 0.00364297
3010075 | 04_Fourth Floor | 98.1935 | 0.121432 | 0.235665 | 0.00353497
3010076 | 04_Fourth Floor | 98.1935 | 0.121432 | 0.235665 | 0.00353497
3010077 | 04_Fourth Floor | 98.1935 | 0.121432 | 0.235665 | 0.00353497
3010078 | 04_Fourth Floor | 98.1935 | 0.121432 | 0.235665 | 0.00353497
3010079 | 04_Fourth Floor | 98.1935 | 0.121432 | 0.235665 | 0.00353497
3010080 | 04_Fourth Floor | 98.1935 | 0.121432 | 0.235665 | 0.00353497
3010081 | 04_Fourth Floor | 98.1935 | 0.121432 | 0.235665 | 0.00353497
3010082 | 04_Fourth Floor | 98.1935 | 0.121432 | 0.235665 | 0.00353497
3010083 | 04_Fourth Floor | 98.1935 | 0.121432 | 0.235665 | 0.00353497
3010084 | 04_Fourth Floor | 98.1935 | 0.121432 | 0.235665 | 0.00353497
3010085 | 04_Fourth Floor | 98.1935 | 0.121432 | 0.235665 | 0.00353497
3010086 | 04_Fourth Floor | 98.1935 | 0.121432 | 0.235665 | 0.00353497
3010087 | 04_Fourth Floor | 98.1935 | 0.121432 | 0.235665 | 0.00353497
3010088 | 04_Fourth Floor | 98.1935 | 0.121432 | 0.235665 | 0.00353497
3010089 | 04_Fourth Floor | 98.1935 | 0.121432 | 0.235665 | 0.00353497
3010090 | 04_Fourth Floor | 98.1935 | 0.121432 | 0.235665 | 0.00353497
3010091 | 04_Fourth Floor | 98.1935 | 0.121432 | 0.235665 | 0.00353497
3010092 | 04_Fourth Floor | 98.1935 | 0.121432 | 0.235665 | 0.00353497
3010093 | 04_Fourth Floor | 98.1935 | 0.121432 | 0.235665 | 0.00353497
3010094 | 04_Fourth Floor | 98.1935 | 0.121432 | 0.235665 | 0.00353497
3010095 | 04_Fourth Floor | 98.1935 | 0.121432 | 0.235665 | 0.00353497
3010096 | 04_Fourth Floor | 98.1935 | 0.121432 | 0.235665 | 0.00353497
3010097 | 04_Fourth Floor | 98.1935 | 0.121432 | 0.235665 | 0.00353497
3010098 | 04_Fourth Floor | 98.1935 | 0.121432 | 0.235665 | 0.00353497
3010099 | 04_Fourth Floor | 98.1935 | 0.121432 | 0.235665 | 0.00353497
3010100 | 04_Fourth Floor | 98.1935 | 0.121432 | 0.235665 | 0.00353497
3010101 | 04_Fourth Floor | 98.1935 | 0.121432 | 0.235665 | 0.00353497
3010102 | 04_Fourth Floor | 98.1935 | 0.121432 | 0.235665 | 0.00353497
3010103 | 04_Fourth Floor | 98.1935 | 0.121432 | 0.235665 | 0.00353497
3010104 | 04_Fourth Floor | 101.194 | 0.125032 | 0.246465 | 0.00364297
3010105 | 04_Fourth Floor | 238 | 0.2892 | 0.5784 | 0.008568
3010106 | 04_Fourth Floor | 238 | 0.2892 | 0.5784 | 0.008568
3010107 | 04_Fourth Floor | 238 | 0.2892 | 0.5784 | 0.008568
3010108 | 04_Fourth Floor | 238 | 0.2892 | 0.5784 | 0.008568
3010109 | 04_Fourth Floor | 238 | 0.2892 | 0.5784 | 0.008568
3010110 | 04_Fourth Floor | 238 | 0.2892 | 0.5784 | 0.008568
3010111 | 04_Fourth Floor | 238 | 0.2892 | 0.5784 | 0.008568
3010112 | 04_Fourth Floor | 238 | 0.2892 | 0.5784 | 0.008568
3010113 | 04_Fourth Floor | 238 | 0.2892 | 0.5784 | 0.008568
3010114 | 04_Fourth Floor | 238 | 0.2892 | 0.5784 | 0.008568
3010115 | 04_Fourth Floor | 238 | 0.2892 | 0.5784 | 0.008568
3010116 | 04_Fourth Floor | 238 | 0.2892 | 0.5784 | 0.008568
3010117 | 04_Fourth Floor | 238 | 0.2892 | 0.5784 | 0.008568
3010118 | 04_Fourth Floor | 238 | 0.2892 | 0.5784 | 0.008568
3010119 | 04_Fourth Floor | 238 | 0.2892 | 0.5784 | 0.008568
3010120 | 04_Fourth Floor | 238 | 0.2892 | 0.5784 | 0.008568
3010121 | 04_Fourth Floor | 238 | 0.2892 | 0.5784 | 0.008568
3010122 | 04_Fourth Floor | 238 | 0.2892 | 0.5784 | 0.008568
3010123 | 04_Fourth Floor | 238 | 0.2892 | 0.5784 | 0.008568
3010124 | 04_Fourth Floor | 238 | 0.2892 | 0.5784 | 0.008568
3010125 | 04_Fourth Floor | 238 | 0.2892 | 0.5784 | 0.008568
3010126 | 04_Fourth Floor | 238 | 0.2892 | 0.5784 | 0.008568
3010127 | 04_Fourth Floor | 238 | 0.2892 | 0.5784 | 0.008568
3010128 | 04_Fourth Floor | 238 | 0.2892 | 0.5784 | 0.008568
3010129 | 04_Fourth Floor | 238 | 0.2892 | 0.5784 | 0.008568
3010130 | 04_Fourth Floor | 238 | 0.2892 | 0.5784 | 0.008568
3010131 | 04_Fourth Floor | 238 | 0.2892 | 0.5784 | 0.008568
3010132 | 04_Fourth Floor | 238 | 0.2892 | 0.5784 | 0.008568
3010133 | 04_Fourth Floor | 238 | 0.2892 | 0.5784 | 0.008568
3010134 | 04_Fourth Floor | 238 | 0.2892 | 0.5784 | 0.008568
3010135 | 04_Fourth Floor | 238 | 0.2892 | 0.5784 | 0.008568
3010136 | 04_Fourth Floor | 238 | 0.2892 | 0.5784 | 0.008568
3012022 | 05_Fifth Floor | 102.843 | 0.127012 | 0.250424 | 0.00370235
3012023 | 05_Fifth Floor | 102.843 | 0.127012 | 0.250424 | 0.00370235
3012024 | 05_Fifth Floor | 99.8431 | 0.123412 | 0.239624 | 0.00359435
3012025 | 05_Fifth Floor | 99.8431 | 0.123412 | 0.239624 | 0.00359435
3012026 | 05_Fifth Floor | 99.8431 | 0.123412 | 0.239624 | 0.00359435
3012027 | 05_Fifth Floor | 99.8431 | 0.123412 | 0.239624 | 0.00359435
3012028 | 05_Fifth Floor | 99.8431 | 0.123412 | 0.239624 | 0.00359435
3012029 | 05_Fifth Floor | 99.8431 | 0.123412 | 0.239624 | 0.00359435
3012030 | 05_Fifth Floor | 99.8431 | 0.123412 | 0.239624 | 0.00359435
3012031 | 05_Fifth Floor | 99.8431 | 0.123412 | 0.239624 | 0.00359435
3012032 | 05_Fifth Floor | 99.8431 | 0.123412 | 0.239624 | 0.00359435
3012033 | 05_Fifth Floor | 99.8431 | 0.123412 | 0.239624 | 0.00359435
3012034 | 05_Fifth Floor | 99.8431 | 0.123412 | 0.239624 | 0.00359435
3012035 | 05_Fifth Floor | 99.8431 | 0.123412 | 0.239624 | 0.00359435
3012036 | 05_Fifth Floor | 99.8431 | 0.123412 | 0.239624 | 0.00359435
3012037 | 05_Fifth Floor | 99.8431 | 0.123412 | 0.239624 | 0.00359435
3012038 | 05_Fifth Floor | 99.8431 | 0.123412 | 0.239624 | 0.00359435
3012039 | 05_Fifth Floor | 99.8431 | 0.123412 | 0.239624 | 0.00359435
3012040 | 05_Fifth Floor | 99.8431 | 0.123412 | 0.239624 | 0.00359435
3012041 | 05_Fifth Floor | 99.8431 | 0.123412 | 0.239624 | 0.00359435
3012042 | 05_Fifth Floor | 99.8431 | 0.123412 | 0.239624 | 0.00359435
3012043 | 05_Fifth Floor | 99.8431 | 0.123412 | 0.239624 | 0.00359435
3012044 | 05_Fifth Floor | 99.8431 | 0.123412 | 0.239624 | 0.00359435
3012045 | 05_Fifth Floor | 99.8431 | 0.123412 | 0.239624 | 0.00359435
3012046 | 05_Fifth Floor | 99.8431 | 0.123412 | 0.239624 | 0.00359435
3012047 | 05_Fifth Floor | 99.8431 | 0.123412 | 0.239624 | 0.00359435
3012048 | 05_Fifth Floor | 99.8431 | 0.123412 | 0.239624 | 0.00359435
3012049 | 05_Fifth Floor | 99.8431 | 0.123412 | 0.239624 | 0.00359435
3012050 | 05_Fifth Floor | 99.8431 | 0.123412 | 0.239624 | 0.00359435
3012051 | 05_Fifth Floor | 99.8431 | 0.123412 | 0.239624 | 0.00359435
3012052 | 05_Fifth Floor | 99.8431 | 0.123412 | 0.239624 | 0.00359435
3012053 | 05_Fifth Floor | 99.8431 | 0.123412 | 0.239624 | 0.00359435
3012054 | 05_Fifth Floor | 99.8431 | 0.123412 | 0.239624 | 0.00359435
3012055 | 05_Fifth Floor | 99.8431 | 0.123412 | 0.239624 | 0.00359435
3012056 | 05_Fifth Floor | 99.8431 | 0.123412 | 0.239624 | 0.00359435
3012057 | 05_Fifth Floor | 99.8431 | 0.123412 | 0.239624 | 0.00359435
3012058 | 05_Fifth Floor | 99.8431 | 0.123412 | 0.239624 | 0.00359435
3012059 | 05_Fifth Floor | 99.8431 | 0.123412 | 0.239624 | 0.00359435
3012060 | 05_Fifth Floor | 99.8431 | 0.123412 | 0.239624 | 0.00359435
3012061 | 05_Fifth Floor | 99.8431 | 0.123412 | 0.239624 | 0.00359435
3012062 | 05_Fifth Floor | 99.8431 | 0.123412 | 0.239624 | 0.00359435
3012063 | 05_Fifth Floor | 99.8431 | 0.123412 | 0.239624 | 0.00359435
3012064 | 05_Fifth Floor | 99.8431 | 0.123412 | 0.239624 | 0.00359435
3012065 | 05_Fifth Floor | 99.8431 | 0.123412 | 0.239624 | 0.00359435
3012066 | 05_Fifth Floor | 99.8431 | 0.123412 | 0.239624 | 0.00359435
3012067 | 05_Fifth Floor | 99.8431 | 0.123412 | 0.239624 | 0.00359435
3012068 | 05_Fifth Floor | 99.8431 | 0.123412 | 0.239624 | 0.00359435
3012069 | 05_Fifth Floor | 99.8431 | 0.123412 | 0.239624 | 0.00359435
3012070 | 05_Fifth Floor | 99.8431 | 0.123412 | 0.239624 | 0.00359435
3012071 | 05_Fifth Floor | 99.8431 | 0.123412 | 0.239624 | 0.00359435
3012072 | 05_Fifth Floor | 99.8431 | 0.123412 | 0.239624 | 0.00359435
3012073 | 05_Fifth Floor | 102.843 | 0.127012 | 0.250424 | 0.00370235
3012074 | 05_Fifth Floor | 99.8431 | 0.123412 | 0.239624 | 0.00359435
3012075 | 05_Fifth Floor | 99.8431 | 0.123412 | 0.239624 | 0.00359435
3012076 | 05_Fifth Floor | 99.8431 | 0.123412 | 0.239624 | 0.00359435
3012077 | 05_Fifth Floor | 99.8431 | 0.123412 | 0.239624 | 0.00359435
3012078 | 05_Fifth Floor | 99.8431 | 0.123412 | 0.239624 | 0.00359435
3012079 | 05_Fifth Floor | 99.8431 | 0.123412 | 0.239624 | 0.00359435
3012080 | 05_Fifth Floor | 99.8431 | 0.123412 | 0.239624 | 0.00359435
3012081 | 05_Fifth Floor | 99.8431 | 0.123412 | 0.239624 | 0.00359435
3012082 | 05_Fifth Floor | 99.8431 | 0.123412 | 0.239624 | 0.00359435
3012083 | 05_Fifth Floor | 99.8431 | 0.123412 | 0.239624 | 0.00359435
3012084 | 05_Fifth Floor | 99.8431 | 0.123412 | 0.239624 | 0.00359435
3012085 | 05_Fifth Floor | 99.8431 | 0.123412 | 0.239624 | 0.00359435
3012086 | 05_Fifth Floor | 99.8431 | 0.123412 | 0.239624 | 0.00359435
3012087 | 05_Fifth Floor | 99.8431 | 0.123412 | 0.239624 | 0.00359435
3012088 | 05_Fifth Floor | 99.8431 | 0.123412 | 0.239624 | 0.00359435
3012089 | 05_Fifth Floor | 99.8431 | 0.123412 | 0.239624 | 0.00359435
3012090 | 05_Fifth Floor | 99.8431 | 0.123412 | 0.239624 | 0.00359435
3012091 | 05_Fifth Floor | 99.8431 | 0.123412 | 0.239624 | 0.00359435
3012092 | 05_Fifth Floor | 99.8431 | 0.123412 | 0.239624 | 0.00359435
3012093 | 05_Fifth Floor | 99.8431 | 0.123412 | 0.239624 | 0.00359435
3012094 | 05_Fifth Floor | 99.8431 | 0.123412 | 0.239624 | 0.00359435
3012095 | 05_Fifth Floor | 99.8431 | 0.123412 | 0.239624 | 0.00359435
3012096 | 05_Fifth Floor | 99.8431 | 0.123412 | 0.239624 | 0.00359435
3012097 | 05_Fifth Floor | 99.8431 | 0.123412 | 0.239624 | 0.00359435
3012098 | 05_Fifth Floor | 99.8431 | 0.123412 | 0.239624 | 0.00359435
3012099 | 05_Fifth Floor | 99.8431 | 0.123412 | 0.239624 | 0.00359435
3012100 | 05_Fifth Floor | 99.8431 | 0.123412 | 0.239624 | 0.00359435
3012101 | 05_Fifth Floor | 99.8431 | 0.123412 | 0.239624 | 0.00359435
3012102 | 05_Fifth Floor | 99.8431 | 0.123412 | 0.239624 | 0.00359435
3012103 | 05_Fifth Floor | 99.8431 | 0.123412 | 0.239624 | 0.00359435
3012104 | 05_Fifth Floor | 99.8431 | 0.123412 | 0.239624 | 0.00359435
3012105 | 05_Fifth Floor | 99.8431 | 0.123412 | 0.239624 | 0.00359435
3012106 | 05_Fifth Floor | 99.8431 | 0.123412 | 0.239624 | 0.00359435
3012107 | 05_Fifth Floor | 99.8431 | 0.123412 | 0.239624 | 0.00359435
3012108 | 05_Fifth Floor | 99.8431 | 0.123412 | 0.239624 | 0.00359435
3012109 | 05_Fifth Floor | 99.8431 | 0.123412 | 0.239624 | 0.00359435
3012110 | 05_Fifth Floor | 99.8431 | 0.123412 | 0.239624 | 0.00359435
3012111 | 05_Fifth Floor | 99.8431 | 0.123412 | 0.239624 | 0.00359435
3012112 | 05_Fifth Floor | 99.8431 | 0.123412 | 0.239624 | 0.00359435
3012113 | 05_Fifth Floor | 99.8431 | 0.123412 | 0.239624 | 0.00359435
3012114 | 05_Fifth Floor | 99.8431 | 0.123412 | 0.239624 | 0.00359435
3012115 | 05_Fifth Floor | 99.8431 | 0.123412 | 0.239624 | 0.00359435
3012116 | 05_Fifth Floor | 99.8431 | 0.123412 | 0.239624 | 0.00359435
3012117 | 05_Fifth Floor | 99.8431 | 0.123412 | 0.239624 | 0.00359435
3012118 | 05_Fifth Floor | 99.8431 | 0.123412 | 0.239624 | 0.00359435
3012119 | 05_Fifth Floor | 99.8431 | 0.123412 | 0.239624 | 0.00359435
3012120 | 05_Fifth Floor | 99.8431 | 0.123412 | 0.239624 | 0.00359435
3012121 | 05_Fifth Floor | 99.8431 | 0.123412 | 0.239624 | 0.00359435
3012122 | 05_Fifth Floor | 99.8431 | 0.123412 | 0.239624 | 0.00359435
3012123 | 05_Fifth Floor | 102.843 | 0.127012 | 0.250424 | 0.00370235
3012124 | 05_Fifth Floor | 238 | 0.2892 | 0.5784 | 0.008568
3012125 | 05_Fifth Floor | 238 | 0.2892 | 0.5784 | 0.008568
3012126 | 05_Fifth Floor | 238 | 0.2892 | 0.5784 | 0.008568
3012127 | 05_Fifth Floor | 238 | 0.2892 | 0.5784 | 0.008568
3012128 | 05_Fifth Floor | 238 | 0.2892 | 0.5784 | 0.008568
3012129 | 05_Fifth Floor | 238 | 0.2892 | 0.5784 | 0.008568
3012130 | 05_Fifth Floor | 238 | 0.2892 | 0.5784 | 0.008568
3012131 | 05_Fifth Floor | 238 | 0.2892 | 0.5784 | 0.008568
3012132 | 05_Fifth Floor | 238 | 0.2892 | 0.5784 | 0.008568
3012133 | 05_Fifth Floor | 238 | 0.2892 | 0.5784 | 0.008568
3012134 | 05_Fifth Floor | 238 | 0.2892 | 0.5784 | 0.008568
3012135 | 05_Fifth Floor | 238 | 0.2892 | 0.5784 | 0.008568
3012136 | 05_Fifth Floor | 238 | 0.2892 | 0.5784 | 0.008568
3012137 | 05_Fifth Floor | 238 | 0.2892 | 0.5784 | 0.008568
3012138 | 05_Fifth Floor | 238 | 0.2892 | 0.5784 | 0.008568
3012139 | 05_Fifth Floor | 238 | 0.2892 | 0.5784 | 0.008568
3012140 | 05_Fifth Floor | 238 | 0.2892 | 0.5784 | 0.008568
3012141 | 05_Fifth Floor | 238 | 0.2892 | 0.5784 | 0.008568
3012142 | 05_Fifth Floor | 238 | 0.2892 | 0.5784 | 0.008568
3012143 | 05_Fifth Floor | 238 | 0.2892 | 0.5784 | 0.008568
3012144 | 05_Fifth Floor | 238 | 0.2892 | 0.5784 | 0.008568
3012145 | 05_Fifth Floor | 238 | 0.2892 | 0.5784 | 0.008568
3012146 | 05_Fifth Floor | 238 | 0.2892 | 0.5784 | 0.008568
3012147 | 05_Fifth Floor | 238 | 0.2892 | 0.5784 | 0.008568
3012148 | 05_Fifth Floor | 238 | 0.2892 | 0.5784 | 0.008568
3012149 | 05_Fifth Floor | 238 | 0.2892 | 0.5784 | 0.008568
3012150 | 05_Fifth Floor | 238 | 0.2892 | 0.5784 | 0.008568
3012151 | 05_Fifth Floor | 238 | 0.2892 | 0.5784 | 0.008568
3012152 | 05_Fifth Floor | 238 | 0.2892 | 0.5784 | 0.008568
3012153 | 05_Fifth Floor | 238 | 0.2892 | 0.5784 | 0.008568
3012154 | 05_Fifth Floor | 238 | 0.2892 | 0.5784 | 0.008568
3012155 | 05_Fifth Floor | 238 | 0.2892 | 0.5784 | 0.008568
3012156 | 05_Fifth Floor | 238 | 0.2892 | 0.5784 | 0.008568
3012157 | 05_Fifth Floor | 238 | 0.2892 | 0.5784 | 0.008568
3012158 | 05_Fifth Floor | 238 | 0.2892 | 0.5784 | 0.008568
3012159 | 05_Fifth Floor | 238 | 0.2892 | 0.5784 | 0.008568
3012160 | 05_Fifth Floor | 238 | 0.2892 | 0.5784 | 0.008568
3012161 | 05_Fifth Floor | 238 | 0.2892 | 0.5784 | 0.008568
3012162 | 05_Fifth Floor | 238 | 0.2892 | 0.5784 | 0.008568
3012163 | 05_Fifth Floor | 238 | 0.2892 | 0.5784 | 0.008568
3012164 | 05_Fifth Floor | 238 | 0.2892 | 0.5784 | 0.008568
3012165 | 05_Fifth Floor | 238 | 0.2892 | 0.5784 | 0.008568
3012166 | 05_Fifth Floor | 238 | 0.2892 | 0.5784 | 0.008568
3012167 | 05_Fifth Floor | 238 | 0.2892 | 0.5784 | 0.008568
3012168 | 05_Fifth Floor | 238 | 0.2892 | 0.5784 | 0.008568
3012169 | 05_Fifth Floor | 238 | 0.2892 | 0.5784 | 0.008568
3012170 | 05_Fifth Floor | 238 | 0.2892 | 0.5784 | 0.008568
3012171 | 05_Fifth Floor | 238 | 0.2892 | 0.5784 | 0.008568
3012172 | 05_Fifth Floor | 238 | 0.2892 | 0.5784 | 0.008568
3012173 | 05_Fifth Floor | 238 | 0.2892 | 0.5784 | 0.008568
3012174 | 05_Fifth Floor | 238 | 0.2892 | 0.5784 | 0.008568
3012175 | 05_Fifth Floor | 238 | 0.2892 | 0.5784 | 0.008568
3012238 | 05_Fifth Floor | 101.194 | 0.125032 | 0.246465 | 0.00364297
3012239 | 05_Fifth Floor | 101.194 | 0.125032 | 0.246465 | 0.00364297
3012240 | 05_Fifth Floor | 98.1935 | 0.121432 | 0.235665 | 0.00353497
3012241 | 05_Fifth Floor | 98.1935 | 0.121432 | 0.235665 | 0.00353497
3012242 | 05_Fifth Floor | 98.1935 | 0.121432 | 0.235665 | 0.00353497
3012243 | 05_Fifth Floor | 98.1935 | 0.121432 | 0.235665 | 0.00353497
3012244 | 05_Fifth Floor | 98.1935 | 0.121432 | 0.235665 | 0.00353497
3012245 | 05_Fifth Floor | 98.1935 | 0.121432 | 0.235665 | 0.00353497
3012246 | 05_Fifth Floor | 98.1935 | 0.121432 | 0.235665 | 0.00353497
3012247 | 05_Fifth Floor | 98.1935 | 0.121432 | 0.235665 | 0.00353497
3012248 | 05_Fifth Floor | 98.1935 | 0.121432 | 0.235665 | 0.00353497
3012249 | 05_Fifth Floor | 98.1935 | 0.121432 | 0.235665 | 0.00353497
3012250 | 05_Fifth Floor | 98.1935 | 0.121432 | 0.235665 | 0.00353497
3012251 | 05_Fifth Floor | 98.1935 | 0.121432 | 0.235665 | 0.00353497
3012252 | 05_Fifth Floor | 98.1935 | 0.121432 | 0.235665 | 0.00353497
3012253 | 05_Fifth Floor | 98.1935 | 0.121432 | 0.235665 | 0.00353497
3012254 | 05_Fifth Floor | 98.1935 | 0.121432 | 0.235665 | 0.00353497
3012255 | 05_Fifth Floor | 98.1935 | 0.121432 | 0.235665 | 0.00353497
3012256 | 05_Fifth Floor | 98.1935 | 0.121432 | 0.235665 | 0.00353497
3012257 | 05_Fifth Floor | 98.1935 | 0.121432 | 0.235665 | 0.00353497
3012258 | 05_Fifth Floor | 98.1935 | 0.121432 | 0.235665 | 0.00353497
3012259 | 05_Fifth Floor | 98.1935 | 0.121432 | 0.235665 | 0.00353497
3012260 | 05_Fifth Floor | 98.1935 | 0.121432 | 0.235665 | 0.00353497
3012261 | 05_Fifth Floor | 98.1935 | 0.121432 | 0.235665 | 0.00353497
3012262 | 05_Fifth Floor | 98.1935 | 0.121432 | 0.235665 | 0.00353497
3012263 | 05_Fifth Floor | 98.1935 | 0.121432 | 0.235665 | 0.00353497
3012264 | 05_Fifth Floor | 98.1935 | 0.121432 | 0.235665 | 0.00353497
3012265 | 05_Fifth Floor | 98.1935 | 0.121432 | 0.235665 | 0.00353497
3012266 | 05_Fifth Floor | 98.1935 | 0.121432 | 0.235665 | 0.00353497
3012267 | 05_Fifth Floor | 98.1935 | 0.121432 | 0.235665 | 0.00353497
3012268 | 05_Fifth Floor | 98.1935 | 0.121432 | 0.235665 | 0.00353497
3012269 | 05_Fifth Floor | 101.194 | 0.125032 | 0.246465 | 0.00364297
3012270 | 05_Fifth Floor | 98.1935 | 0.121432 | 0.235665 | 0.00353497
3012271 | 05_Fifth Floor | 98.1935 | 0.121432 | 0.235665 | 0.00353497
3012272 | 05_Fifth Floor | 98.1935 | 0.121432 | 0.235665 | 0.00353497
3012273 | 05_Fifth Floor | 98.1935 | 0.121432 | 0.235665 | 0.00353497
3012274 | 05_Fifth Floor | 98.1935 | 0.121432 | 0.235665 | 0.00353497
3012275 | 05_Fifth Floor | 98.1935 | 0.121432 | 0.235665 | 0.00353497
3012276 | 05_Fifth Floor | 98.1935 | 0.121432 | 0.235665 | 0.00353497
3012277 | 05_Fifth Floor | 98.1935 | 0.121432 | 0.235665 | 0.00353497
3012278 | 05_Fifth Floor | 98.1935 | 0.121432 | 0.235665 | 0.00353497
3012279 | 05_Fifth Floor | 98.1935 | 0.121432 | 0.235665 | 0.00353497
3012280 | 05_Fifth Floor | 98.1935 | 0.121432 | 0.235665 | 0.00353497
3012281 | 05_Fifth Floor | 98.1935 | 0.121432 | 0.235665 | 0.00353497
3012282 | 05_Fifth Floor | 98.1935 | 0.121432 | 0.235665 | 0.00353497
3012283 | 05_Fifth Floor | 98.1935 | 0.121432 | 0.235665 | 0.00353497
3012284 | 05_Fifth Floor | 98.1935 | 0.121432 | 0.235665 | 0.00353497
3012285 | 05_Fifth Floor | 98.1935 | 0.121432 | 0.235665 | 0.00353497
3012286 | 05_Fifth Floor | 98.1935 | 0.121432 | 0.235665 | 0.00353497
3012287 | 05_Fifth Floor | 98.1935 | 0.121432 | 0.235665 | 0.00353497
3012288 | 05_Fifth Floor | 98.1935 | 0.121432 | 0.235665 | 0.00353497
3012289 | 05_Fifth Floor | 98.1935 | 0.121432 | 0.235665 | 0.00353497
3012290 | 05_Fifth Floor | 98.1935 | 0.121432 | 0.235665 | 0.00353497
3012291 | 05_Fifth Floor | 98.1935 | 0.121432 | 0.235665 | 0.00353497
3012292 | 05_Fifth Floor | 98.1935 | 0.121432 | 0.235665 | 0.00353497
3012293 | 05_Fifth Floor | 98.1935 | 0.121432 | 0.235665 | 0.00353497
3012294 | 05_Fifth Floor | 98.1935 | 0.121432 | 0.235665 | 0.00353497
3012295 | 05_Fifth Floor | 98.1935 | 0.121432 | 0.235665 | 0.00353497
3012296 | 05_Fifth Floor | 98.1935 | 0.121432 | 0.235665 | 0.00353497
3012297 | 05_Fifth Floor | 98.1935 | 0.121432 | 0.235665 | 0.00353497
3012298 | 05_Fifth Floor | 98.1935 | 0.121432 | 0.235665 | 0.00353497
3012299 | 05_Fifth Floor | 101.194 | 0.125032 | 0.246465 | 0.00364297
3012300 | 05_Fifth Floor | 238 | 0.2892 | 0.5784 | 0.008568
3012301 | 05_Fifth Floor | 238 | 0.2892 | 0.5784 | 0.008568
3012302 | 05_Fifth Floor | 238 | 0.2892 | 0.5784 | 0.008568
3012303 | 05_Fifth Floor | 238 | 0.2892 | 0.5784 | 0.008568
3012304 | 05_Fifth Floor | 238 | 0.2892 | 0.5784 | 0.008568
3012305 | 05_Fifth Floor | 238 | 0.2892 | 0.5784 | 0.008568
3012306 | 05_Fifth Floor | 238 | 0.2892 | 0.5784 | 0.008568
3012307 | 05_Fifth Floor | 238 | 0.2892 | 0.5784 | 0.008568
3012308 | 05_Fifth Floor | 238 | 0.2892 | 0.5784 | 0.008568
3012309 | 05_Fifth Floor | 238 | 0.2892 | 0.5784 | 0.008568
3012310 | 05_Fifth Floor | 238 | 0.2892 | 0.5784 | 0.008568
3012311 | 05_Fifth Floor | 238 | 0.2892 | 0.5784 | 0.008568
3012312 | 05_Fifth Floor | 238 | 0.2892 | 0.5784 | 0.008568
3012313 | 05_Fifth Floor | 238 | 0.2892 | 0.5784 | 0.008568
3012314 | 05_Fifth Floor | 238 | 0.2892 | 0.5784 | 0.008568
3012315 | 05_Fifth Floor | 238 | 0.2892 | 0.5784 | 0.008568
3012316 | 05_Fifth Floor | 238 | 0.2892 | 0.5784 | 0.008568
3012317 | 05_Fifth Floor | 238 | 0.2892 | 0.5784 | 0.008568
3012318 | 05_Fifth Floor | 238 | 0.2892 | 0.5784 | 0.008568
3012319 | 05_Fifth Floor | 238 | 0.2892 | 0.5784 | 0.008568
3012320 | 05_Fifth Floor | 238 | 0.2892 | 0.5784 | 0.008568
3012321 | 05_Fifth Floor | 238 | 0.2892 | 0.5784 | 0.008568
3012322 | 05_Fifth Floor | 238 | 0.2892 | 0.5784 | 0.008568
3012323 | 05_Fifth Floor | 238 | 0.2892 | 0.5784 | 0.008568
3012324 | 05_Fifth Floor | 238 | 0.2892 | 0.5784 | 0.008568
3012325 | 05_Fifth Floor | 238 | 0.2892 | 0.5784 | 0.008568
3012326 | 05_Fifth Floor | 238 | 0.2892 | 0.5784 | 0.008568
3012327 | 05_Fifth Floor | 238 | 0.2892 | 0.5784 | 0.008568
3012328 | 05_Fifth Floor | 238 | 0.2892 | 0.5784 | 0.008568
3012329 | 05_Fifth Floor | 238 | 0.2892 | 0.5784 | 0.008568
3012330 | 05_Fifth Floor | 238 | 0.2892 | 0.5784 | 0.008568
3012331 | 05_Fifth Floor | 238 | 0.2892 | 0.5784 | 0.008568
3014219 | 06_Sixth Floor | 102.843 | 0.127012 | 0.250424 | 0.00370235
3014220 | 06_Sixth Floor | 102.843 | 0.127012 | 0.250424 | 0.00370235
3014221 | 06_Sixth Floor | 99.8431 | 0.123412 | 0.239624 | 0.00359435
3014222 | 06_Sixth Floor | 99.8431 | 0.123412 | 0.239624 | 0.00359435
3014223 | 06_Sixth Floor | 99.8431 | 0.123412 | 0.239624 | 0.00359435
3014224 | 06_Sixth Floor | 99.8431 | 0.123412 | 0.239624 | 0.00359435
3014225 | 06_Sixth Floor | 99.8431 | 0.123412 | 0.239624 | 0.00359435
3014226 | 06_Sixth Floor | 99.8431 | 0.123412 | 0.239624 | 0.00359435
3014227 | 06_Sixth Floor | 99.8431 | 0.123412 | 0.239624 | 0.00359435
3014228 | 06_Sixth Floor | 99.8431 | 0.123412 | 0.239624 | 0.00359435
3014229 | 06_Sixth Floor | 99.8431 | 0.123412 | 0.239624 | 0.00359435
3014230 | 06_Sixth Floor | 99.8431 | 0.123412 | 0.239624 | 0.00359435
3014231 | 06_Sixth Floor | 99.8431 | 0.123412 | 0.239624 | 0.00359435
3014232 | 06_Sixth Floor | 99.8431 | 0.123412 | 0.239624 | 0.00359435
3014233 | 06_Sixth Floor | 99.8431 | 0.123412 | 0.239624 | 0.00359435
3014234 | 06_Sixth Floor | 99.8431 | 0.123412 | 0.239624 | 0.00359435
3014235 | 06_Sixth Floor | 99.8431 | 0.123412 | 0.239624 | 0.00359435
3014236 | 06_Sixth Floor | 99.8431 | 0.123412 | 0.239624 | 0.00359435
3014237 | 06_Sixth Floor | 99.8431 | 0.123412 | 0.239624 | 0.00359435
3014238 | 06_Sixth Floor | 99.8431 | 0.123412 | 0.239624 | 0.00359435
3014239 | 06_Sixth Floor | 99.8431 | 0.123412 | 0.239624 | 0.00359435
3014240 | 06_Sixth Floor | 99.8431 | 0.123412 | 0.239624 | 0.00359435
3014241 | 06_Sixth Floor | 99.8431 | 0.123412 | 0.239624 | 0.00359435
3014242 | 06_Sixth Floor | 99.8431 | 0.123412 | 0.239624 | 0.00359435
3014243 | 06_Sixth Floor | 99.8431 | 0.123412 | 0.239624 | 0.00359435
3014244 | 06_Sixth Floor | 99.8431 | 0.123412 | 0.239624 | 0.00359435
3014245 | 06_Sixth Floor | 99.8431 | 0.123412 | 0.239624 | 0.00359435
3014246 | 06_Sixth Floor | 99.8431 | 0.123412 | 0.239624 | 0.00359435
3014247 | 06_Sixth Floor | 99.8431 | 0.123412 | 0.239624 | 0.00359435
3014248 | 06_Sixth Floor | 99.8431 | 0.123412 | 0.239624 | 0.00359435
3014249 | 06_Sixth Floor | 99.8431 | 0.123412 | 0.239624 | 0.00359435
3014250 | 06_Sixth Floor | 99.8431 | 0.123412 | 0.239624 | 0.00359435
3014251 | 06_Sixth Floor | 99.8431 | 0.123412 | 0.239624 | 0.00359435
3014252 | 06_Sixth Floor | 99.8431 | 0.123412 | 0.239624 | 0.00359435
3014253 | 06_Sixth Floor | 99.8431 | 0.123412 | 0.239624 | 0.00359435
3014254 | 06_Sixth Floor | 99.8431 | 0.123412 | 0.239624 | 0.00359435
3014255 | 06_Sixth Floor | 99.8431 | 0.123412 | 0.239624 | 0.00359435
3014256 | 06_Sixth Floor | 99.8431 | 0.123412 | 0.239624 | 0.00359435
3014257 | 06_Sixth Floor | 99.8431 | 0.123412 | 0.239624 | 0.00359435
3014258 | 06_Sixth Floor | 99.8431 | 0.123412 | 0.239624 | 0.00359435
3014259 | 06_Sixth Floor | 99.8431 | 0.123412 | 0.239624 | 0.00359435
3014260 | 06_Sixth Floor | 99.8431 | 0.123412 | 0.239624 | 0.00359435
3014261 | 06_Sixth Floor | 99.8431 | 0.123412 | 0.239624 | 0.00359435
3014262 | 06_Sixth Floor | 99.8431 | 0.123412 | 0.239624 | 0.00359435
3014263 | 06_Sixth Floor | 99.8431 | 0.123412 | 0.239624 | 0.00359435
3014264 | 06_Sixth Floor | 99.8431 | 0.123412 | 0.239624 | 0.00359435
3014265 | 06_Sixth Floor | 99.8431 | 0.123412 | 0.239624 | 0.00359435
3014266 | 06_Sixth Floor | 99.8431 | 0.123412 | 0.239624 | 0.00359435
3014267 | 06_Sixth Floor | 99.8431 | 0.123412 | 0.239624 | 0.00359435
3014268 | 06_Sixth Floor | 99.8431 | 0.123412 | 0.239624 | 0.00359435
3014269 | 06_Sixth Floor | 99.8431 | 0.123412 | 0.239624 | 0.00359435
3014270 | 06_Sixth Floor | 102.843 | 0.127012 | 0.250424 | 0.00370235
3014271 | 06_Sixth Floor | 99.8431 | 0.123412 | 0.239624 | 0.00359435
3014272 | 06_Sixth Floor | 99.8431 | 0.123412 | 0.239624 | 0.00359435
3014273 | 06_Sixth Floor | 99.8431 | 0.123412 | 0.239624 | 0.00359435
3014274 | 06_Sixth Floor | 99.8431 | 0.123412 | 0.239624 | 0.00359435
3014275 | 06_Sixth Floor | 99.8431 | 0.123412 | 0.239624 | 0.00359435
3014276 | 06_Sixth Floor | 99.8431 | 0.123412 | 0.239624 | 0.00359435
3014277 | 06_Sixth Floor | 99.8431 | 0.123412 | 0.239624 | 0.00359435
3014278 | 06_Sixth Floor | 99.8431 | 0.123412 | 0.239624 | 0.00359435
3014279 | 06_Sixth Floor | 99.8431 | 0.123412 | 0.239624 | 0.00359435
3014280 | 06_Sixth Floor | 99.8431 | 0.123412 | 0.239624 | 0.00359435
3014281 | 06_Sixth Floor | 99.8431 | 0.123412 | 0.239624 | 0.00359435
3014282 | 06_Sixth Floor | 99.8431 | 0.123412 | 0.239624 | 0.00359435
3014283 | 06_Sixth Floor | 99.8431 | 0.123412 | 0.239624 | 0.00359435
3014284 | 06_Sixth Floor | 99.8431 | 0.123412 | 0.239624 | 0.00359435
3014285 | 06_Sixth Floor | 99.8431 | 0.123412 | 0.239624 | 0.00359435
3014286 | 06_Sixth Floor | 99.8431 | 0.123412 | 0.239624 | 0.00359435
3014287 | 06_Sixth Floor | 99.8431 | 0.123412 | 0.239624 | 0.00359435
3014288 | 06_Sixth Floor | 99.8431 | 0.123412 | 0.239624 | 0.00359435
3014289 | 06_Sixth Floor | 99.8431 | 0.123412 | 0.239624 | 0.00359435
3014290 | 06_Sixth Floor | 99.8431 | 0.123412 | 0.239624 | 0.00359435
3014291 | 06_Sixth Floor | 99.8431 | 0.123412 | 0.239624 | 0.00359435
3014292 | 06_Sixth Floor | 99.8431 | 0.123412 | 0.239624 | 0.00359435
3014293 | 06_Sixth Floor | 99.8431 | 0.123412 | 0.239624 | 0.00359435
3014294 | 06_Sixth Floor | 99.8431 | 0.123412 | 0.239624 | 0.00359435
3014295 | 06_Sixth Floor | 99.8431 | 0.123412 | 0.239624 | 0.00359435
3014296 | 06_Sixth Floor | 99.8431 | 0.123412 | 0.239624 | 0.00359435
3014297 | 06_Sixth Floor | 99.8431 | 0.123412 | 0.239624 | 0.00359435
3014298 | 06_Sixth Floor | 99.8431 | 0.123412 | 0.239624 | 0.00359435
3014299 | 06_Sixth Floor | 99.8431 | 0.123412 | 0.239624 | 0.00359435
3014300 | 06_Sixth Floor | 99.8431 | 0.123412 | 0.239624 | 0.00359435
3014301 | 06_Sixth Floor | 99.8431 | 0.123412 | 0.239624 | 0.00359435
3014302 | 06_Sixth Floor | 99.8431 | 0.123412 | 0.239624 | 0.00359435
3014303 | 06_Sixth Floor | 99.8431 | 0.123412 | 0.239624 | 0.00359435
3014304 | 06_Sixth Floor | 99.8431 | 0.123412 | 0.239624 | 0.00359435
3014305 | 06_Sixth Floor | 99.8431 | 0.123412 | 0.239624 | 0.00359435
3014306 | 06_Sixth Floor | 99.8431 | 0.123412 | 0.239624 | 0.00359435
3014307 | 06_Sixth Floor | 99.8431 | 0.123412 | 0.239624 | 0.00359435
3014308 | 06_Sixth Floor | 99.8431 | 0.123412 | 0.239624 | 0.00359435
3014309 | 06_Sixth Floor | 99.8431 | 0.123412 | 0.239624 | 0.00359435
3014310 | 06_Sixth Floor | 99.8431 | 0.123412 | 0.239624 | 0.00359435
3014311 | 06_Sixth Floor | 99.8431 | 0.123412 | 0.239624 | 0.00359435
3014312 | 06_Sixth Floor | 99.8431 | 0.123412 | 0.239624 | 0.00359435
3014313 | 06_Sixth Floor | 99.8431 | 0.123412 | 0.239624 | 0.00359435
3014314 | 06_Sixth Floor | 99.8431 | 0.123412 | 0.239624 | 0.00359435
3014315 | 06_Sixth Floor | 99.8431 | 0.123412 | 0.239624 | 0.00359435
3014316 | 06_Sixth Floor | 99.8431 | 0.123412 | 0.239624 | 0.00359435
3014317 | 06_Sixth Floor | 99.8431 | 0.123412 | 0.239624 | 0.00359435
3014318 | 06_Sixth Floor | 99.8431 | 0.123412 | 0.239624 | 0.00359435
3014319 | 06_Sixth Floor | 99.8431 | 0.123412 | 0.239624 | 0.00359435
3014320 | 06_Sixth Floor | 102.843 | 0.127012 | 0.250424 | 0.00370235
3014321 | 06_Sixth Floor | 238 | 0.2892 | 0.5784 | 0.008568
3014322 | 06_Sixth Floor | 238 | 0.2892 | 0.5784 | 0.008568
3014323 | 06_Sixth Floor | 238 | 0.2892 | 0.5784 | 0.008568
3014324 | 06_Sixth Floor | 238 | 0.2892 | 0.5784 | 0.008568
3014325 | 06_Sixth Floor | 238 | 0.2892 | 0.5784 | 0.008568
3014326 | 06_Sixth Floor | 238 | 0.2892 | 0.5784 | 0.008568
3014327 | 06_Sixth Floor | 238 | 0.2892 | 0.5784 | 0.008568
3014328 | 06_Sixth Floor | 238 | 0.2892 | 0.5784 | 0.008568
3014329 | 06_Sixth Floor | 238 | 0.2892 | 0.5784 | 0.008568
3014330 | 06_Sixth Floor | 238 | 0.2892 | 0.5784 | 0.008568
3014331 | 06_Sixth Floor | 238 | 0.2892 | 0.5784 | 0.008568
3014332 | 06_Sixth Floor | 238 | 0.2892 | 0.5784 | 0.008568
3014333 | 06_Sixth Floor | 238 | 0.2892 | 0.5784 | 0.008568
3014334 | 06_Sixth Floor | 238 | 0.2892 | 0.5784 | 0.008568
3014335 | 06_Sixth Floor | 238 | 0.2892 | 0.5784 | 0.008568
3014336 | 06_Sixth Floor | 238 | 0.2892 | 0.5784 | 0.008568
3014337 | 06_Sixth Floor | 238 | 0.2892 | 0.5784 | 0.008568
3014338 | 06_Sixth Floor | 238 | 0.2892 | 0.5784 | 0.008568
3014339 | 06_Sixth Floor | 238 | 0.2892 | 0.5784 | 0.008568
3014340 | 06_Sixth Floor | 238 | 0.2892 | 0.5784 | 0.008568
3014341 | 06_Sixth Floor | 238 | 0.2892 | 0.5784 | 0.008568
3014342 | 06_Sixth Floor | 238 | 0.2892 | 0.5784 | 0.008568
3014343 | 06_Sixth Floor | 238 | 0.2892 | 0.5784 | 0.008568
3014344 | 06_Sixth Floor | 238 | 0.2892 | 0.5784 | 0.008568
3014345 | 06_Sixth Floor | 238 | 0.2892 | 0.5784 | 0.008568
3014346 | 06_Sixth Floor | 238 | 0.2892 | 0.5784 | 0.008568
3014347 | 06_Sixth Floor | 238 | 0.2892 | 0.5784 | 0.008568
3014348 | 06_Sixth Floor | 238 | 0.2892 | 0.5784 | 0.008568
3014349 | 06_Sixth Floor | 238 | 0.2892 | 0.5784 | 0.008568
3014350 | 06_Sixth Floor | 238 | 0.2892 | 0.5784 | 0.008568
3014351 | 06_Sixth Floor | 238 | 0.2892 | 0.5784 | 0.008568
3014352 | 06_Sixth Floor | 238 | 0.2892 | 0.5784 | 0.008568
3014353 | 06_Sixth Floor | 238 | 0.2892 | 0.5784 | 0.008568
3014354 | 06_Sixth Floor | 238 | 0.2892 | 0.5784 | 0.008568
3014355 | 06_Sixth Floor | 238 | 0.2892 | 0.5784 | 0.008568
3014356 | 06_Sixth Floor | 238 | 0.2892 | 0.5784 | 0.008568
3014357 | 06_Sixth Floor | 238 | 0.2892 | 0.5784 | 0.008568
3014358 | 06_Sixth Floor | 238 | 0.2892 | 0.5784 | 0.008568
3014359 | 06_Sixth Floor | 238 | 0.2892 | 0.5784 | 0.008568
3014360 | 06_Sixth Floor | 238 | 0.2892 | 0.5784 | 0.008568
3014361 | 06_Sixth Floor | 238 | 0.2892 | 0.5784 | 0.008568
3014362 | 06_Sixth Floor | 238 | 0.2892 | 0.5784 | 0.008568
3014363 | 06_Sixth Floor | 238 | 0.2892 | 0.5784 | 0.008568
3014364 | 06_Sixth Floor | 238 | 0.2892 | 0.5784 | 0.008568
3014365 | 06_Sixth Floor | 238 | 0.2892 | 0.5784 | 0.008568
3014366 | 06_Sixth Floor | 238 | 0.2892 | 0.5784 | 0.008568
3014367 | 06_Sixth Floor | 238 | 0.2892 | 0.5784 | 0.008568
3014368 | 06_Sixth Floor | 238 | 0.2892 | 0.5784 | 0.008568
3014369 | 06_Sixth Floor | 238 | 0.2892 | 0.5784 | 0.008568
3014370 | 06_Sixth Floor | 238 | 0.2892 | 0.5784 | 0.008568
3014371 | 06_Sixth Floor | 238 | 0.2892 | 0.5784 | 0.008568
3014372 | 06_Sixth Floor | 238 | 0.2892 | 0.5784 | 0.008568
3014435 | 06_Sixth Floor | 101.194 | 0.125032 | 0.246465 | 0.00364297
3014436 | 06_Sixth Floor | 101.194 | 0.125032 | 0.246465 | 0.00364297
3014437 | 06_Sixth Floor | 98.1935 | 0.121432 | 0.235665 | 0.00353497
3014438 | 06_Sixth Floor | 98.1935 | 0.121432 | 0.235665 | 0.00353497
3014439 | 06_Sixth Floor | 98.1935 | 0.121432 | 0.235665 | 0.00353497
3014440 | 06_Sixth Floor | 98.1935 | 0.121432 | 0.235665 | 0.00353497
3014441 | 06_Sixth Floor | 98.1935 | 0.121432 | 0.235665 | 0.00353497
3014442 | 06_Sixth Floor | 98.1935 | 0.121432 | 0.235665 | 0.00353497
3014443 | 06_Sixth Floor | 98.1935 | 0.121432 | 0.235665 | 0.00353497
3014444 | 06_Sixth Floor | 98.1935 | 0.121432 | 0.235665 | 0.00353497
3014445 | 06_Sixth Floor | 98.1935 | 0.121432 | 0.235665 | 0.00353497
3014446 | 06_Sixth Floor | 98.1935 | 0.121432 | 0.235665 | 0.00353497
3014447 | 06_Sixth Floor | 98.1935 | 0.121432 | 0.235665 | 0.00353497
3014448 | 06_Sixth Floor | 98.1935 | 0.121432 | 0.235665 | 0.00353497
3014449 | 06_Sixth Floor | 98.1935 | 0.121432 | 0.235665 | 0.00353497
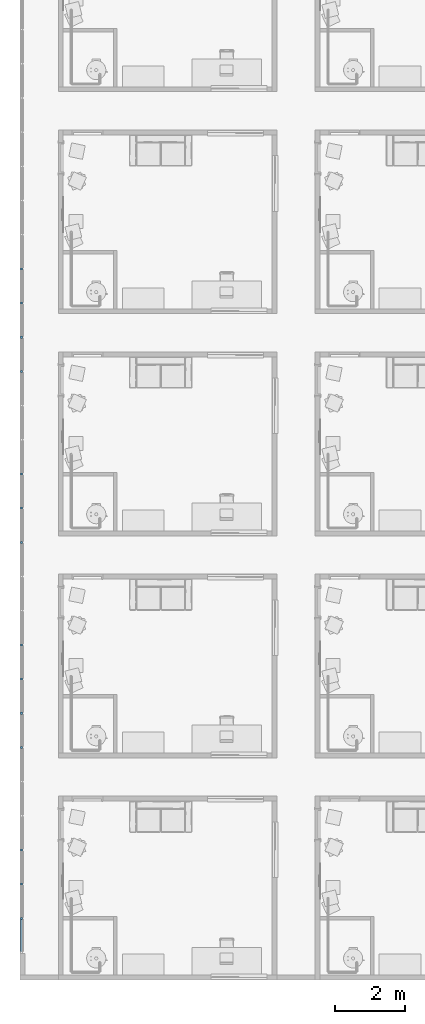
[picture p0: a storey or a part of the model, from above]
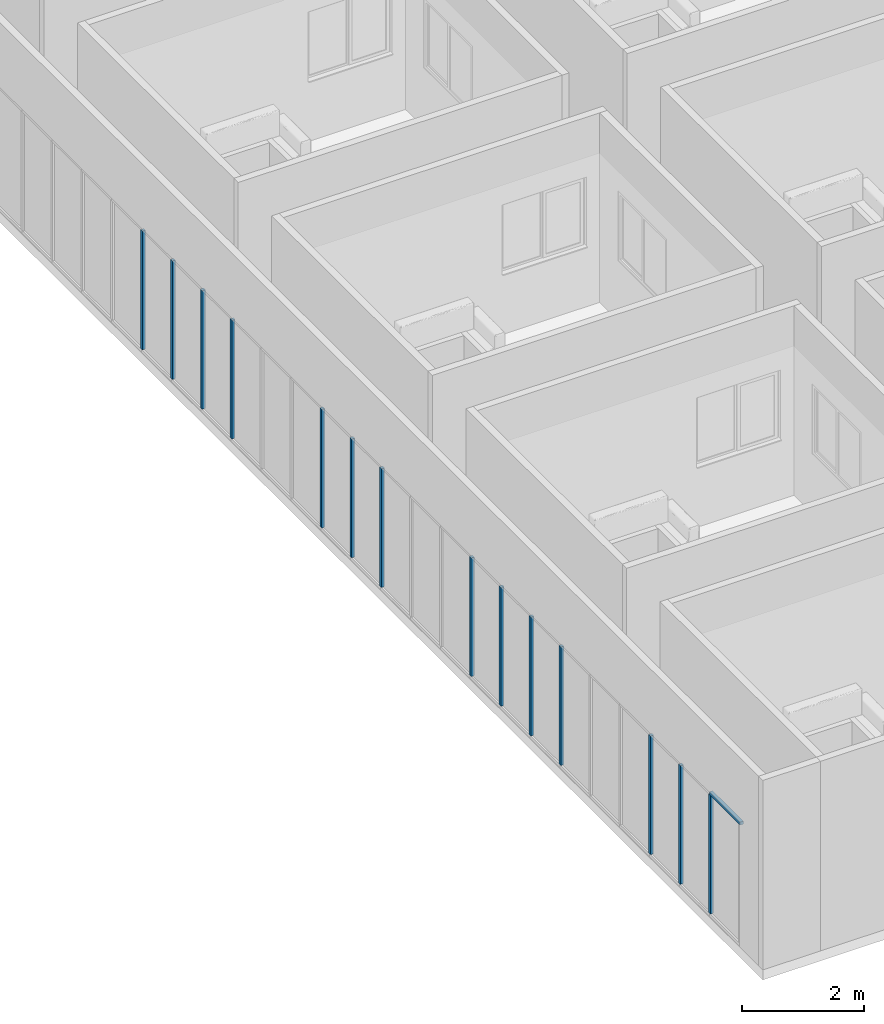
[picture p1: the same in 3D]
Properties of the parts of a building model (IFC4), part 8 of 14

# IfcMember: Rectangular Mullion:30-_Stijl_Rechthoek_Midden_B60xD60 (1984)
Name (Rectangular Mullion:30-_Stijl_Rechthoek_Midden_B60xD60:...) | In | Length (cm) | CrossSectionArea (m2) | NetSurfaceArea (m2) | NetVolume (m3)
3014450 | 06_Sixth Floor | 98.1935 | 0.121432 | 0.235665 | 0.00353497
3014451 | 06_Sixth Floor | 98.1935 | 0.121432 | 0.235665 | 0.00353497
3014452 | 06_Sixth Floor | 98.1935 | 0.121432 | 0.235665 | 0.00353497
3014453 | 06_Sixth Floor | 98.1935 | 0.121432 | 0.235665 | 0.00353497
3014454 | 06_Sixth Floor | 98.1935 | 0.121432 | 0.235665 | 0.00353497
3014455 | 06_Sixth Floor | 98.1935 | 0.121432 | 0.235665 | 0.00353497
3014456 | 06_Sixth Floor | 98.1935 | 0.121432 | 0.235665 | 0.00353497
3014457 | 06_Sixth Floor | 98.1935 | 0.121432 | 0.235665 | 0.00353497
3014458 | 06_Sixth Floor | 98.1935 | 0.121432 | 0.235665 | 0.00353497
3014459 | 06_Sixth Floor | 98.1935 | 0.121432 | 0.235665 | 0.00353497
3014460 | 06_Sixth Floor | 98.1935 | 0.121432 | 0.235665 | 0.00353497
3014461 | 06_Sixth Floor | 98.1935 | 0.121432 | 0.235665 | 0.00353497
3014462 | 06_Sixth Floor | 98.1935 | 0.121432 | 0.235665 | 0.00353497
3014463 | 06_Sixth Floor | 98.1935 | 0.121432 | 0.235665 | 0.00353497
3014464 | 06_Sixth Floor | 98.1935 | 0.121432 | 0.235665 | 0.00353497
3014465 | 06_Sixth Floor | 98.1935 | 0.121432 | 0.235665 | 0.00353497
3014466 | 06_Sixth Floor | 101.194 | 0.125032 | 0.246465 | 0.00364297
3014467 | 06_Sixth Floor | 98.1935 | 0.121432 | 0.235665 | 0.00353497
3014468 | 06_Sixth Floor | 98.1935 | 0.121432 | 0.235665 | 0.00353497
3014469 | 06_Sixth Floor | 98.1935 | 0.121432 | 0.235665 | 0.00353497
3014470 | 06_Sixth Floor | 98.1935 | 0.121432 | 0.235665 | 0.00353497
3014471 | 06_Sixth Floor | 98.1935 | 0.121432 | 0.235665 | 0.00353497
3014472 | 06_Sixth Floor | 98.1935 | 0.121432 | 0.235665 | 0.00353497
3014473 | 06_Sixth Floor | 98.1935 | 0.121432 | 0.235665 | 0.00353497
3014474 | 06_Sixth Floor | 98.1935 | 0.121432 | 0.235665 | 0.00353497
3014475 | 06_Sixth Floor | 98.1935 | 0.121432 | 0.235665 | 0.00353497
3014476 | 06_Sixth Floor | 98.1935 | 0.121432 | 0.235665 | 0.00353497
3014477 | 06_Sixth Floor | 98.1935 | 0.121432 | 0.235665 | 0.00353497
3014478 | 06_Sixth Floor | 98.1935 | 0.121432 | 0.235665 | 0.00353497
3014479 | 06_Sixth Floor | 98.1935 | 0.121432 | 0.235665 | 0.00353497
3014480 | 06_Sixth Floor | 98.1935 | 0.121432 | 0.235665 | 0.00353497
3014481 | 06_Sixth Floor | 98.1935 | 0.121432 | 0.235665 | 0.00353497
3014482 | 06_Sixth Floor | 98.1935 | 0.121432 | 0.235665 | 0.00353497
3014483 | 06_Sixth Floor | 98.1935 | 0.121432 | 0.235665 | 0.00353497
3014484 | 06_Sixth Floor | 98.1935 | 0.121432 | 0.235665 | 0.00353497
3014485 | 06_Sixth Floor | 98.1935 | 0.121432 | 0.235665 | 0.00353497
3014486 | 06_Sixth Floor | 98.1935 | 0.121432 | 0.235665 | 0.00353497
3014487 | 06_Sixth Floor | 98.1935 | 0.121432 | 0.235665 | 0.00353497
3014488 | 06_Sixth Floor | 98.1935 | 0.121432 | 0.235665 | 0.00353497
3014489 | 06_Sixth Floor | 98.1935 | 0.121432 | 0.235665 | 0.00353497
3014490 | 06_Sixth Floor | 98.1935 | 0.121432 | 0.235665 | 0.00353497
3014491 | 06_Sixth Floor | 98.1935 | 0.121432 | 0.235665 | 0.00353497
3014492 | 06_Sixth Floor | 98.1935 | 0.121432 | 0.235665 | 0.00353497
3014493 | 06_Sixth Floor | 98.1935 | 0.121432 | 0.235665 | 0.00353497
3014494 | 06_Sixth Floor | 98.1935 | 0.121432 | 0.235665 | 0.00353497
3014495 | 06_Sixth Floor | 98.1935 | 0.121432 | 0.235665 | 0.00353497
3014496 | 06_Sixth Floor | 101.194 | 0.125032 | 0.246465 | 0.00364297
3014497 | 06_Sixth Floor | 238 | 0.2892 | 0.5784 | 0.008568
3014498 | 06_Sixth Floor | 238 | 0.2892 | 0.5784 | 0.008568
3014499 | 06_Sixth Floor | 238 | 0.2892 | 0.5784 | 0.008568
3014500 | 06_Sixth Floor | 238 | 0.2892 | 0.5784 | 0.008568
3014501 | 06_Sixth Floor | 238 | 0.2892 | 0.5784 | 0.008568
3014502 | 06_Sixth Floor | 238 | 0.2892 | 0.5784 | 0.008568
3014503 | 06_Sixth Floor | 238 | 0.2892 | 0.5784 | 0.008568
3014504 | 06_Sixth Floor | 238 | 0.2892 | 0.5784 | 0.008568
3014505 | 06_Sixth Floor | 238 | 0.2892 | 0.5784 | 0.008568
3014506 | 06_Sixth Floor | 238 | 0.2892 | 0.5784 | 0.008568
3014507 | 06_Sixth Floor | 238 | 0.2892 | 0.5784 | 0.008568
3014508 | 06_Sixth Floor | 238 | 0.2892 | 0.5784 | 0.008568
3014509 | 06_Sixth Floor | 238 | 0.2892 | 0.5784 | 0.008568
3014510 | 06_Sixth Floor | 238 | 0.2892 | 0.5784 | 0.008568
3014511 | 06_Sixth Floor | 238 | 0.2892 | 0.5784 | 0.008568
3014512 | 06_Sixth Floor | 238 | 0.2892 | 0.5784 | 0.008568
3014513 | 06_Sixth Floor | 238 | 0.2892 | 0.5784 | 0.008568
3014514 | 06_Sixth Floor | 238 | 0.2892 | 0.5784 | 0.008568
3014515 | 06_Sixth Floor | 238 | 0.2892 | 0.5784 | 0.008568
3014516 | 06_Sixth Floor | 238 | 0.2892 | 0.5784 | 0.008568
3014517 | 06_Sixth Floor | 238 | 0.2892 | 0.5784 | 0.008568
3014518 | 06_Sixth Floor | 238 | 0.2892 | 0.5784 | 0.008568
3014519 | 06_Sixth Floor | 238 | 0.2892 | 0.5784 | 0.008568
3014520 | 06_Sixth Floor | 238 | 0.2892 | 0.5784 | 0.008568
3014521 | 06_Sixth Floor | 238 | 0.2892 | 0.5784 | 0.008568
3014522 | 06_Sixth Floor | 238 | 0.2892 | 0.5784 | 0.008568
3014523 | 06_Sixth Floor | 238 | 0.2892 | 0.5784 | 0.008568
3014524 | 06_Sixth Floor | 238 | 0.2892 | 0.5784 | 0.008568
3014525 | 06_Sixth Floor | 238 | 0.2892 | 0.5784 | 0.008568
3014526 | 06_Sixth Floor | 238 | 0.2892 | 0.5784 | 0.008568
3014527 | 06_Sixth Floor | 238 | 0.2892 | 0.5784 | 0.008568
3014528 | 06_Sixth Floor | 238 | 0.2892 | 0.5784 | 0.008568
3016414 | 07_Seventh Floor | 102.843 | 0.127012 | 0.250424 | 0.00370235
3016415 | 07_Seventh Floor | 102.843 | 0.127012 | 0.250424 | 0.00370235
3016416 | 07_Seventh Floor | 99.8431 | 0.123412 | 0.239624 | 0.00359435
3016417 | 07_Seventh Floor | 99.8431 | 0.123412 | 0.239624 | 0.00359435
3016418 | 07_Seventh Floor | 99.8431 | 0.123412 | 0.239624 | 0.00359435
3016419 | 07_Seventh Floor | 99.8431 | 0.123412 | 0.239624 | 0.00359435
3016420 | 07_Seventh Floor | 99.8431 | 0.123412 | 0.239624 | 0.00359435
3016421 | 07_Seventh Floor | 99.8431 | 0.123412 | 0.239624 | 0.00359435
3016422 | 07_Seventh Floor | 99.8431 | 0.123412 | 0.239624 | 0.00359435
3016423 | 07_Seventh Floor | 99.8431 | 0.123412 | 0.239624 | 0.00359435
3016424 | 07_Seventh Floor | 99.8431 | 0.123412 | 0.239624 | 0.00359435
3016425 | 07_Seventh Floor | 99.8431 | 0.123412 | 0.239624 | 0.00359435
3016426 | 07_Seventh Floor | 99.8431 | 0.123412 | 0.239624 | 0.00359435
3016427 | 07_Seventh Floor | 99.8431 | 0.123412 | 0.239624 | 0.00359435
3016428 | 07_Seventh Floor | 99.8431 | 0.123412 | 0.239624 | 0.00359435
3016429 | 07_Seventh Floor | 99.8431 | 0.123412 | 0.239624 | 0.00359435
3016430 | 07_Seventh Floor | 99.8431 | 0.123412 | 0.239624 | 0.00359435
3016431 | 07_Seventh Floor | 99.8431 | 0.123412 | 0.239624 | 0.00359435
3016432 | 07_Seventh Floor | 99.8431 | 0.123412 | 0.239624 | 0.00359435
3016433 | 07_Seventh Floor | 99.8431 | 0.123412 | 0.239624 | 0.00359435
3016434 | 07_Seventh Floor | 99.8431 | 0.123412 | 0.239624 | 0.00359435
3016435 | 07_Seventh Floor | 99.8431 | 0.123412 | 0.239624 | 0.00359435
3016436 | 07_Seventh Floor | 99.8431 | 0.123412 | 0.239624 | 0.00359435
3016437 | 07_Seventh Floor | 99.8431 | 0.123412 | 0.239624 | 0.00359435
3016438 | 07_Seventh Floor | 99.8431 | 0.123412 | 0.239624 | 0.00359435
3016439 | 07_Seventh Floor | 99.8431 | 0.123412 | 0.239624 | 0.00359435
3016440 | 07_Seventh Floor | 99.8431 | 0.123412 | 0.239624 | 0.00359435
3016441 | 07_Seventh Floor | 99.8431 | 0.123412 | 0.239624 | 0.00359435
3016442 | 07_Seventh Floor | 99.8431 | 0.123412 | 0.239624 | 0.00359435
3016443 | 07_Seventh Floor | 99.8431 | 0.123412 | 0.239624 | 0.00359435
3016444 | 07_Seventh Floor | 99.8431 | 0.123412 | 0.239624 | 0.00359435
3016445 | 07_Seventh Floor | 99.8431 | 0.123412 | 0.239624 | 0.00359435
3016446 | 07_Seventh Floor | 99.8431 | 0.123412 | 0.239624 | 0.00359435
3016447 | 07_Seventh Floor | 99.8431 | 0.123412 | 0.239624 | 0.00359435
3016448 | 07_Seventh Floor | 99.8431 | 0.123412 | 0.239624 | 0.00359435
3016449 | 07_Seventh Floor | 99.8431 | 0.123412 | 0.239624 | 0.00359435
3016450 | 07_Seventh Floor | 99.8431 | 0.123412 | 0.239624 | 0.00359435
3016451 | 07_Seventh Floor | 99.8431 | 0.123412 | 0.239624 | 0.00359435
3016452 | 07_Seventh Floor | 99.8431 | 0.123412 | 0.239624 | 0.00359435
3016453 | 07_Seventh Floor | 99.8431 | 0.123412 | 0.239624 | 0.00359435
3016454 | 07_Seventh Floor | 99.8431 | 0.123412 | 0.239624 | 0.00359435
3016455 | 07_Seventh Floor | 99.8431 | 0.123412 | 0.239624 | 0.00359435
3016456 | 07_Seventh Floor | 99.8431 | 0.123412 | 0.239624 | 0.00359435
3016457 | 07_Seventh Floor | 99.8431 | 0.123412 | 0.239624 | 0.00359435
3016458 | 07_Seventh Floor | 99.8431 | 0.123412 | 0.239624 | 0.00359435
3016459 | 07_Seventh Floor | 99.8431 | 0.123412 | 0.239624 | 0.00359435
3016460 | 07_Seventh Floor | 99.8431 | 0.123412 | 0.239624 | 0.00359435
3016461 | 07_Seventh Floor | 99.8431 | 0.123412 | 0.239624 | 0.00359435
3016462 | 07_Seventh Floor | 99.8431 | 0.123412 | 0.239624 | 0.00359435
3016463 | 07_Seventh Floor | 99.8431 | 0.123412 | 0.239624 | 0.00359435
3016464 | 07_Seventh Floor | 99.8431 | 0.123412 | 0.239624 | 0.00359435
3016465 | 07_Seventh Floor | 102.843 | 0.127012 | 0.250424 | 0.00370235
3016466 | 07_Seventh Floor | 99.8431 | 0.123412 | 0.239624 | 0.00359435
3016467 | 07_Seventh Floor | 99.8431 | 0.123412 | 0.239624 | 0.00359435
3016468 | 07_Seventh Floor | 99.8431 | 0.123412 | 0.239624 | 0.00359435
3016469 | 07_Seventh Floor | 99.8431 | 0.123412 | 0.239624 | 0.00359435
3016470 | 07_Seventh Floor | 99.8431 | 0.123412 | 0.239624 | 0.00359435
3016471 | 07_Seventh Floor | 99.8431 | 0.123412 | 0.239624 | 0.00359435
3016472 | 07_Seventh Floor | 99.8431 | 0.123412 | 0.239624 | 0.00359435
3016473 | 07_Seventh Floor | 99.8431 | 0.123412 | 0.239624 | 0.00359435
3016474 | 07_Seventh Floor | 99.8431 | 0.123412 | 0.239624 | 0.00359435
3016475 | 07_Seventh Floor | 99.8431 | 0.123412 | 0.239624 | 0.00359435
3016476 | 07_Seventh Floor | 99.8431 | 0.123412 | 0.239624 | 0.00359435
3016477 | 07_Seventh Floor | 99.8431 | 0.123412 | 0.239624 | 0.00359435
3016478 | 07_Seventh Floor | 99.8431 | 0.123412 | 0.239624 | 0.00359435
3016479 | 07_Seventh Floor | 99.8431 | 0.123412 | 0.239624 | 0.00359435
3016480 | 07_Seventh Floor | 99.8431 | 0.123412 | 0.239624 | 0.00359435
3016481 | 07_Seventh Floor | 99.8431 | 0.123412 | 0.239624 | 0.00359435
3016482 | 07_Seventh Floor | 99.8431 | 0.123412 | 0.239624 | 0.00359435
3016483 | 07_Seventh Floor | 99.8431 | 0.123412 | 0.239624 | 0.00359435
3016484 | 07_Seventh Floor | 99.8431 | 0.123412 | 0.239624 | 0.00359435
3016485 | 07_Seventh Floor | 99.8431 | 0.123412 | 0.239624 | 0.00359435
3016486 | 07_Seventh Floor | 99.8431 | 0.123412 | 0.239624 | 0.00359435
3016487 | 07_Seventh Floor | 99.8431 | 0.123412 | 0.239624 | 0.00359435
3016488 | 07_Seventh Floor | 99.8431 | 0.123412 | 0.239624 | 0.00359435
3016489 | 07_Seventh Floor | 99.8431 | 0.123412 | 0.239624 | 0.00359435
3016490 | 07_Seventh Floor | 99.8431 | 0.123412 | 0.239624 | 0.00359435
3016491 | 07_Seventh Floor | 99.8431 | 0.123412 | 0.239624 | 0.00359435
3016492 | 07_Seventh Floor | 99.8431 | 0.123412 | 0.239624 | 0.00359435
3016493 | 07_Seventh Floor | 99.8431 | 0.123412 | 0.239624 | 0.00359435
3016494 | 07_Seventh Floor | 99.8431 | 0.123412 | 0.239624 | 0.00359435
3016495 | 07_Seventh Floor | 99.8431 | 0.123412 | 0.239624 | 0.00359435
3016496 | 07_Seventh Floor | 99.8431 | 0.123412 | 0.239624 | 0.00359435
3016497 | 07_Seventh Floor | 99.8431 | 0.123412 | 0.239624 | 0.00359435
3016498 | 07_Seventh Floor | 99.8431 | 0.123412 | 0.239624 | 0.00359435
3016499 | 07_Seventh Floor | 99.8431 | 0.123412 | 0.239624 | 0.00359435
3016500 | 07_Seventh Floor | 99.8431 | 0.123412 | 0.239624 | 0.00359435
3016501 | 07_Seventh Floor | 99.8431 | 0.123412 | 0.239624 | 0.00359435
3016502 | 07_Seventh Floor | 99.8431 | 0.123412 | 0.239624 | 0.00359435
3016503 | 07_Seventh Floor | 99.8431 | 0.123412 | 0.239624 | 0.00359435
3016504 | 07_Seventh Floor | 99.8431 | 0.123412 | 0.239624 | 0.00359435
3016505 | 07_Seventh Floor | 99.8431 | 0.123412 | 0.239624 | 0.00359435
3016506 | 07_Seventh Floor | 99.8431 | 0.123412 | 0.239624 | 0.00359435
3016507 | 07_Seventh Floor | 99.8431 | 0.123412 | 0.239624 | 0.00359435
3016508 | 07_Seventh Floor | 99.8431 | 0.123412 | 0.239624 | 0.00359435
3016509 | 07_Seventh Floor | 99.8431 | 0.123412 | 0.239624 | 0.00359435
3016510 | 07_Seventh Floor | 99.8431 | 0.123412 | 0.239624 | 0.00359435
3016511 | 07_Seventh Floor | 99.8431 | 0.123412 | 0.239624 | 0.00359435
3016512 | 07_Seventh Floor | 99.8431 | 0.123412 | 0.239624 | 0.00359435
3016513 | 07_Seventh Floor | 99.8431 | 0.123412 | 0.239624 | 0.00359435
3016514 | 07_Seventh Floor | 99.8431 | 0.123412 | 0.239624 | 0.00359435
3016515 | 07_Seventh Floor | 102.843 | 0.127012 | 0.250424 | 0.00370235
3016516 | 07_Seventh Floor | 238 | 0.2892 | 0.5784 | 0.008568
3016517 | 07_Seventh Floor | 238 | 0.2892 | 0.5784 | 0.008568
3016518 | 07_Seventh Floor | 238 | 0.2892 | 0.5784 | 0.008568
3016519 | 07_Seventh Floor | 238 | 0.2892 | 0.5784 | 0.008568
3016520 | 07_Seventh Floor | 238 | 0.2892 | 0.5784 | 0.008568
3016521 | 07_Seventh Floor | 238 | 0.2892 | 0.5784 | 0.008568
3016522 | 07_Seventh Floor | 238 | 0.2892 | 0.5784 | 0.008568
3016523 | 07_Seventh Floor | 238 | 0.2892 | 0.5784 | 0.008568
3016524 | 07_Seventh Floor | 238 | 0.2892 | 0.5784 | 0.008568
3016525 | 07_Seventh Floor | 238 | 0.2892 | 0.5784 | 0.008568
3016526 | 07_Seventh Floor | 238 | 0.2892 | 0.5784 | 0.008568
3016527 | 07_Seventh Floor | 238 | 0.2892 | 0.5784 | 0.008568
3016528 | 07_Seventh Floor | 238 | 0.2892 | 0.5784 | 0.008568
3016529 | 07_Seventh Floor | 238 | 0.2892 | 0.5784 | 0.008568
3016530 | 07_Seventh Floor | 238 | 0.2892 | 0.5784 | 0.008568
3016531 | 07_Seventh Floor | 238 | 0.2892 | 0.5784 | 0.008568
3016532 | 07_Seventh Floor | 238 | 0.2892 | 0.5784 | 0.008568
3016533 | 07_Seventh Floor | 238 | 0.2892 | 0.5784 | 0.008568
3016534 | 07_Seventh Floor | 238 | 0.2892 | 0.5784 | 0.008568
3016535 | 07_Seventh Floor | 238 | 0.2892 | 0.5784 | 0.008568
3016536 | 07_Seventh Floor | 238 | 0.2892 | 0.5784 | 0.008568
3016537 | 07_Seventh Floor | 238 | 0.2892 | 0.5784 | 0.008568
3016538 | 07_Seventh Floor | 238 | 0.2892 | 0.5784 | 0.008568
3016539 | 07_Seventh Floor | 238 | 0.2892 | 0.5784 | 0.008568
3016540 | 07_Seventh Floor | 238 | 0.2892 | 0.5784 | 0.008568
3016541 | 07_Seventh Floor | 238 | 0.2892 | 0.5784 | 0.008568
3016542 | 07_Seventh Floor | 238 | 0.2892 | 0.5784 | 0.008568
3016543 | 07_Seventh Floor | 238 | 0.2892 | 0.5784 | 0.008568
3016544 | 07_Seventh Floor | 238 | 0.2892 | 0.5784 | 0.008568
3016545 | 07_Seventh Floor | 238 | 0.2892 | 0.5784 | 0.008568
3016546 | 07_Seventh Floor | 238 | 0.2892 | 0.5784 | 0.008568
3016547 | 07_Seventh Floor | 238 | 0.2892 | 0.5784 | 0.008568
3016548 | 07_Seventh Floor | 238 | 0.2892 | 0.5784 | 0.008568
3016549 | 07_Seventh Floor | 238 | 0.2892 | 0.5784 | 0.008568
3016550 | 07_Seventh Floor | 238 | 0.2892 | 0.5784 | 0.008568
3016551 | 07_Seventh Floor | 238 | 0.2892 | 0.5784 | 0.008568
3016552 | 07_Seventh Floor | 238 | 0.2892 | 0.5784 | 0.008568
3016553 | 07_Seventh Floor | 238 | 0.2892 | 0.5784 | 0.008568
3016554 | 07_Seventh Floor | 238 | 0.2892 | 0.5784 | 0.008568
3016555 | 07_Seventh Floor | 238 | 0.2892 | 0.5784 | 0.008568
3016556 | 07_Seventh Floor | 238 | 0.2892 | 0.5784 | 0.008568
3016557 | 07_Seventh Floor | 238 | 0.2892 | 0.5784 | 0.008568
3016558 | 07_Seventh Floor | 238 | 0.2892 | 0.5784 | 0.008568
3016559 | 07_Seventh Floor | 238 | 0.2892 | 0.5784 | 0.008568
3016560 | 07_Seventh Floor | 238 | 0.2892 | 0.5784 | 0.008568
3016561 | 07_Seventh Floor | 238 | 0.2892 | 0.5784 | 0.008568
3016562 | 07_Seventh Floor | 238 | 0.2892 | 0.5784 | 0.008568
3016563 | 07_Seventh Floor | 238 | 0.2892 | 0.5784 | 0.008568
3016564 | 07_Seventh Floor | 238 | 0.2892 | 0.5784 | 0.008568
3016565 | 07_Seventh Floor | 238 | 0.2892 | 0.5784 | 0.008568
3016566 | 07_Seventh Floor | 238 | 0.2892 | 0.5784 | 0.008568
3016567 | 07_Seventh Floor | 238 | 0.2892 | 0.5784 | 0.008568
3016630 | 07_Seventh Floor | 101.194 | 0.125032 | 0.246465 | 0.00364297
3016631 | 07_Seventh Floor | 101.194 | 0.125032 | 0.246465 | 0.00364297
3016632 | 07_Seventh Floor | 98.1935 | 0.121432 | 0.235665 | 0.00353497
3016633 | 07_Seventh Floor | 98.1935 | 0.121432 | 0.235665 | 0.00353497
3016634 | 07_Seventh Floor | 98.1935 | 0.121432 | 0.235665 | 0.00353497
3016635 | 07_Seventh Floor | 98.1935 | 0.121432 | 0.235665 | 0.00353497
3016636 | 07_Seventh Floor | 98.1935 | 0.121432 | 0.235665 | 0.00353497
3016637 | 07_Seventh Floor | 98.1935 | 0.121432 | 0.235665 | 0.00353497
3016638 | 07_Seventh Floor | 98.1935 | 0.121432 | 0.235665 | 0.00353497
3016639 | 07_Seventh Floor | 98.1935 | 0.121432 | 0.235665 | 0.00353497
3016640 | 07_Seventh Floor | 98.1935 | 0.121432 | 0.235665 | 0.00353497
3016641 | 07_Seventh Floor | 98.1935 | 0.121432 | 0.235665 | 0.00353497
3016642 | 07_Seventh Floor | 98.1935 | 0.121432 | 0.235665 | 0.00353497
3016643 | 07_Seventh Floor | 98.1935 | 0.121432 | 0.235665 | 0.00353497
3016644 | 07_Seventh Floor | 98.1935 | 0.121432 | 0.235665 | 0.00353497
3016645 | 07_Seventh Floor | 98.1935 | 0.121432 | 0.235665 | 0.00353497
3016646 | 07_Seventh Floor | 98.1935 | 0.121432 | 0.235665 | 0.00353497
3016647 | 07_Seventh Floor | 98.1935 | 0.121432 | 0.235665 | 0.00353497
3016648 | 07_Seventh Floor | 98.1935 | 0.121432 | 0.235665 | 0.00353497
3016649 | 07_Seventh Floor | 98.1935 | 0.121432 | 0.235665 | 0.00353497
3016650 | 07_Seventh Floor | 98.1935 | 0.121432 | 0.235665 | 0.00353497
3016651 | 07_Seventh Floor | 98.1935 | 0.121432 | 0.235665 | 0.00353497
3016652 | 07_Seventh Floor | 98.1935 | 0.121432 | 0.235665 | 0.00353497
3016653 | 07_Seventh Floor | 98.1935 | 0.121432 | 0.235665 | 0.00353497
3016654 | 07_Seventh Floor | 98.1935 | 0.121432 | 0.235665 | 0.00353497
3016655 | 07_Seventh Floor | 98.1935 | 0.121432 | 0.235665 | 0.00353497
3016656 | 07_Seventh Floor | 98.1935 | 0.121432 | 0.235665 | 0.00353497
3016657 | 07_Seventh Floor | 98.1935 | 0.121432 | 0.235665 | 0.00353497
3016658 | 07_Seventh Floor | 98.1935 | 0.121432 | 0.235665 | 0.00353497
3016659 | 07_Seventh Floor | 98.1935 | 0.121432 | 0.235665 | 0.00353497
3016660 | 07_Seventh Floor | 98.1935 | 0.121432 | 0.235665 | 0.00353497
3016661 | 07_Seventh Floor | 101.194 | 0.125032 | 0.246465 | 0.00364297
3016662 | 07_Seventh Floor | 98.1935 | 0.121432 | 0.235665 | 0.00353497
3016663 | 07_Seventh Floor | 98.1935 | 0.121432 | 0.235665 | 0.00353497
3016664 | 07_Seventh Floor | 98.1935 | 0.121432 | 0.235665 | 0.00353497
3016665 | 07_Seventh Floor | 98.1935 | 0.121432 | 0.235665 | 0.00353497
3016666 | 07_Seventh Floor | 98.1935 | 0.121432 | 0.235665 | 0.00353497
3016667 | 07_Seventh Floor | 98.1935 | 0.121432 | 0.235665 | 0.00353497
3016668 | 07_Seventh Floor | 98.1935 | 0.121432 | 0.235665 | 0.00353497
3016669 | 07_Seventh Floor | 98.1935 | 0.121432 | 0.235665 | 0.00353497
3016670 | 07_Seventh Floor | 98.1935 | 0.121432 | 0.235665 | 0.00353497
3016671 | 07_Seventh Floor | 98.1935 | 0.121432 | 0.235665 | 0.00353497
3016672 | 07_Seventh Floor | 98.1935 | 0.121432 | 0.235665 | 0.00353497
3016673 | 07_Seventh Floor | 98.1935 | 0.121432 | 0.235665 | 0.00353497
3016674 | 07_Seventh Floor | 98.1935 | 0.121432 | 0.235665 | 0.00353497
3016675 | 07_Seventh Floor | 98.1935 | 0.121432 | 0.235665 | 0.00353497
3016676 | 07_Seventh Floor | 98.1935 | 0.121432 | 0.235665 | 0.00353497
3016677 | 07_Seventh Floor | 98.1935 | 0.121432 | 0.235665 | 0.00353497
3016678 | 07_Seventh Floor | 98.1935 | 0.121432 | 0.235665 | 0.00353497
3016679 | 07_Seventh Floor | 98.1935 | 0.121432 | 0.235665 | 0.00353497
3016680 | 07_Seventh Floor | 98.1935 | 0.121432 | 0.235665 | 0.00353497
3016681 | 07_Seventh Floor | 98.1935 | 0.121432 | 0.235665 | 0.00353497
3016682 | 07_Seventh Floor | 98.1935 | 0.121432 | 0.235665 | 0.00353497
3016683 | 07_Seventh Floor | 98.1935 | 0.121432 | 0.235665 | 0.00353497
3016684 | 07_Seventh Floor | 98.1935 | 0.121432 | 0.235665 | 0.00353497
3016685 | 07_Seventh Floor | 98.1935 | 0.121432 | 0.235665 | 0.00353497
3016686 | 07_Seventh Floor | 98.1935 | 0.121432 | 0.235665 | 0.00353497
3016687 | 07_Seventh Floor | 98.1935 | 0.121432 | 0.235665 | 0.00353497
3016688 | 07_Seventh Floor | 98.1935 | 0.121432 | 0.235665 | 0.00353497
3016689 | 07_Seventh Floor | 98.1935 | 0.121432 | 0.235665 | 0.00353497
3016690 | 07_Seventh Floor | 98.1935 | 0.121432 | 0.235665 | 0.00353497
3016691 | 07_Seventh Floor | 101.194 | 0.125032 | 0.246465 | 0.00364297
3016692 | 07_Seventh Floor | 238 | 0.2892 | 0.5784 | 0.008568
3016693 | 07_Seventh Floor | 238 | 0.2892 | 0.5784 | 0.008568
3016694 | 07_Seventh Floor | 238 | 0.2892 | 0.5784 | 0.008568
3016695 | 07_Seventh Floor | 238 | 0.2892 | 0.5784 | 0.008568
3016696 | 07_Seventh Floor | 238 | 0.2892 | 0.5784 | 0.008568
3016697 | 07_Seventh Floor | 238 | 0.2892 | 0.5784 | 0.008568
3016698 | 07_Seventh Floor | 238 | 0.2892 | 0.5784 | 0.008568
3016699 | 07_Seventh Floor | 238 | 0.2892 | 0.5784 | 0.008568
3016700 | 07_Seventh Floor | 238 | 0.2892 | 0.5784 | 0.008568
3016701 | 07_Seventh Floor | 238 | 0.2892 | 0.5784 | 0.008568
3016702 | 07_Seventh Floor | 238 | 0.2892 | 0.5784 | 0.008568
3016703 | 07_Seventh Floor | 238 | 0.2892 | 0.5784 | 0.008568
3016704 | 07_Seventh Floor | 238 | 0.2892 | 0.5784 | 0.008568
3016705 | 07_Seventh Floor | 238 | 0.2892 | 0.5784 | 0.008568
3016706 | 07_Seventh Floor | 238 | 0.2892 | 0.5784 | 0.008568
3016707 | 07_Seventh Floor | 238 | 0.2892 | 0.5784 | 0.008568
3016708 | 07_Seventh Floor | 238 | 0.2892 | 0.5784 | 0.008568
3016709 | 07_Seventh Floor | 238 | 0.2892 | 0.5784 | 0.008568
3016710 | 07_Seventh Floor | 238 | 0.2892 | 0.5784 | 0.008568
3016711 | 07_Seventh Floor | 238 | 0.2892 | 0.5784 | 0.008568
3016712 | 07_Seventh Floor | 238 | 0.2892 | 0.5784 | 0.008568
3016713 | 07_Seventh Floor | 238 | 0.2892 | 0.5784 | 0.008568
3016714 | 07_Seventh Floor | 238 | 0.2892 | 0.5784 | 0.008568
3016715 | 07_Seventh Floor | 238 | 0.2892 | 0.5784 | 0.008568
3016716 | 07_Seventh Floor | 238 | 0.2892 | 0.5784 | 0.008568
3016717 | 07_Seventh Floor | 238 | 0.2892 | 0.5784 | 0.008568
3016718 | 07_Seventh Floor | 238 | 0.2892 | 0.5784 | 0.008568
3016719 | 07_Seventh Floor | 238 | 0.2892 | 0.5784 | 0.008568
3016720 | 07_Seventh Floor | 238 | 0.2892 | 0.5784 | 0.008568
3016721 | 07_Seventh Floor | 238 | 0.2892 | 0.5784 | 0.008568
3016722 | 07_Seventh Floor | 238 | 0.2892 | 0.5784 | 0.008568
3016723 | 07_Seventh Floor | 238 | 0.2892 | 0.5784 | 0.008568

# IfcOpeningElement (1416)
PredefinedType: OPENING
Name (Basic Wall:ARC_22.10_WA_LB_SB14_gen_BERSnl:...) | In
2998366 | 00_Ground Floor | Classification: 31.2 buitenwandopeningen; gevuld met ramen (Uniformat); Qto_OpeningElementBaseQuantities - Depth: 44.48 cm; Height: 250 cm; Width: 3050 cm; Pset_EnvironmentalImpactIndicators - Reference: ARC_31.3_CWA_LIB_bandraam vast 100cm - profiel 60x60_gen_BERSnl; sets with these values: 2; cPset_IDSGame - bSI_C_TX_SuperSecretCode: 2
2998456 | 00_Ground Floor | Classification: 31.2 buitenwandopeningen; gevuld met ramen (Uniformat); Qto_OpeningElementBaseQuantities - Depth: 44.48 cm; Height: 250 cm; Width: 5098 cm; Pset_EnvironmentalImpactIndicators - Reference: ARC_31.3_CWA_LIB_bandraam vast 100cm - profiel 60x60_gen_BERSnl; sets with these values: 2; cPset_IDSGame - bSI_C_TX_SuperSecretCode: 1
3003086 | 01_First Floor | Classification: 31.2 buitenwandopeningen; gevuld met ramen (Uniformat); Qto_OpeningElementBaseQuantities - Depth: 44.48 cm; Height: 250 cm; Width: 3050 cm; Pset_EnvironmentalImpactIndicators - Reference: ARC_31.3_CWA_LIB_bandraam vast 100cm - profiel 60x60_gen_BERSnl; sets with these values: 2; cPset_IDSGame - bSI_C_TX_SuperSecretCode: 4
3003087 | 01_First Floor | Classification: 31.2 buitenwandopeningen; gevuld met ramen (Uniformat); Qto_OpeningElementBaseQuantities - Depth: 44.48 cm; Height: 250 cm; Width: 5098 cm; Pset_EnvironmentalImpactIndicators - Reference: ARC_31.3_CWA_LIB_bandraam vast 100cm - profiel 60x60_gen_BERSnl; sets with these values: 2; cPset_IDSGame - bSI_C_TX_SuperSecretCode: 3
3005283 | 02_Second Floor | Classification: 31.2 buitenwandopeningen; gevuld met ramen (Uniformat); Qto_OpeningElementBaseQuantities - Depth: 44.48 cm; Height: 250 cm; Width: 3050 cm; Pset_EnvironmentalImpactIndicators - Reference: ARC_31.3_CWA_LIB_bandraam vast 100cm - profiel 60x60_gen_BERSnl; sets with these values: 2; cPset_IDSGame - bSI_C_TX_SuperSecretCode: 6
3005284 | 02_Second Floor | Classification: 31.2 buitenwandopeningen; gevuld met ramen (Uniformat); Qto_OpeningElementBaseQuantities - Depth: 44.48 cm; Height: 250 cm; Width: 5098 cm; Pset_EnvironmentalImpactIndicators - Reference: ARC_31.3_CWA_LIB_bandraam vast 100cm - profiel 60x60_gen_BERSnl; sets with these values: 2; cPset_IDSGame - bSI_C_TX_SuperSecretCode: 5
3007480 | 03_Third Floor | Classification: 31.2 buitenwandopeningen; gevuld met ramen (Uniformat); Qto_OpeningElementBaseQuantities - Depth: 44.48 cm; Height: 250 cm; Width: 3050 cm; Pset_EnvironmentalImpactIndicators - Reference: ARC_31.3_CWA_LIB_bandraam vast 100cm - profiel 60x60_gen_BERSnl; sets with these values: 2; cPset_IDSGame - bSI_C_TX_SuperSecretCode: 8
3007481 | 03_Third Floor | Classification: 31.2 buitenwandopeningen; gevuld met ramen (Uniformat); Qto_OpeningElementBaseQuantities - Depth: 44.48 cm; Height: 250 cm; Width: 5098 cm; Pset_EnvironmentalImpactIndicators - Reference: ARC_31.3_CWA_LIB_bandraam vast 100cm - profiel 60x60_gen_BERSnl; sets with these values: 2; cPset_IDSGame - bSI_C_TX_SuperSecretCode: 7
3009675 | 04_Fourth Floor | Classification: 31.2 buitenwandopeningen; gevuld met ramen (Uniformat); Qto_OpeningElementBaseQuantities - Depth: 44.48 cm; Height: 250 cm; Width: 3050 cm; Pset_EnvironmentalImpactIndicators - Reference: ARC_31.3_CWA_LIB_bandraam vast 100cm - profiel 60x60_gen_BERSnl; sets with these values: 2; cPset_IDSGame - bSI_C_TX_SuperSecretCode: 10
3009676 | 04_Fourth Floor | Classification: 31.2 buitenwandopeningen; gevuld met ramen (Uniformat); Qto_OpeningElementBaseQuantities - Depth: 44.48 cm; Height: 250 cm; Width: 5098 cm; Pset_EnvironmentalImpactIndicators - Reference: ARC_31.3_CWA_LIB_bandraam vast 100cm - profiel 60x60_gen_BERSnl; sets with these values: 2; cPset_IDSGame - bSI_C_TX_SuperSecretCode: 9
3011870 | 05_Fifth Floor | Classification: 31.2 buitenwandopeningen; gevuld met ramen (Uniformat); Qto_OpeningElementBaseQuantities - Depth: 44.48 cm; Height: 250 cm; Width: 3050 cm; Pset_EnvironmentalImpactIndicators - Reference: ARC_31.3_CWA_LIB_bandraam vast 100cm - profiel 60x60_gen_BERSnl; sets with these values: 2; cPset_IDSGame - bSI_C_TX_SuperSecretCode: 12
3011871 | 05_Fifth Floor | Classification: 31.2 buitenwandopeningen; gevuld met ramen (Uniformat); Qto_OpeningElementBaseQuantities - Depth: 44.48 cm; Height: 250 cm; Width: 5098 cm; Pset_EnvironmentalImpactIndicators - Reference: ARC_31.3_CWA_LIB_bandraam vast 100cm - profiel 60x60_gen_BERSnl; sets with these values: 2; cPset_IDSGame - bSI_C_TX_SuperSecretCode: 11
3014067 | 06_Sixth Floor | Classification: 31.2 buitenwandopeningen; gevuld met ramen (Uniformat); Qto_OpeningElementBaseQuantities - Depth: 44.48 cm; Height: 250 cm; Width: 3050 cm; Pset_EnvironmentalImpactIndicators - Reference: ARC_31.3_CWA_LIB_bandraam vast 100cm - profiel 60x60_gen_BERSnl; sets with these values: 2; cPset_IDSGame - bSI_C_TX_SuperSecretCode: 14
3014068 | 06_Sixth Floor | Classification: 31.2 buitenwandopeningen; gevuld met ramen (Uniformat); Qto_OpeningElementBaseQuantities - Depth: 44.48 cm; Height: 250 cm; Width: 5098 cm; Pset_EnvironmentalImpactIndicators - Reference: ARC_31.3_CWA_LIB_bandraam vast 100cm - profiel 60x60_gen_BERSnl; sets with these values: 2; cPset_IDSGame - bSI_C_TX_SuperSecretCode: 13
3016262 | 07_Seventh Floor | Classification: 31.2 buitenwandopeningen; gevuld met ramen (Uniformat); Qto_OpeningElementBaseQuantities - Depth: 44.48 cm; Height: 250 cm; Width: 3050 cm; Pset_EnvironmentalImpactIndicators - Reference: ARC_31.3_CWA_LIB_bandraam vast 100cm - profiel 60x60_gen_BERSnl; sets with these values: 2; cPset_IDSGame - bSI_C_TX_SuperSecretCode: 16
3016263 | 07_Seventh Floor | Classification: 31.2 buitenwandopeningen; gevuld met ramen (Uniformat); Qto_OpeningElementBaseQuantities - Depth: 44.48 cm; Height: 250 cm; Width: 5098 cm; Pset_EnvironmentalImpactIndicators - Reference: ARC_31.3_CWA_LIB_bandraam vast 100cm - profiel 60x60_gen_BERSnl; sets with these values: 2; cPset_IDSGame - bSI_C_TX_SuperSecretCode: 15
2938170 | 00_Ground Floor
2938171 | 00_Ground Floor | Qto_OpeningElementBaseQuantities - Depth: 166 cm; Height: 275 cm; Width: 90 cm
2938172 | 00_Ground Floor | Qto_OpeningElementBaseQuantities - Depth: 166 cm; Height: 275 cm; Width: 90 cm
2938172 | 00_Ground Floor
2938173 | 00_Ground Floor
2995736 | 00_Ground Floor
2995737 | 00_Ground Floor | Qto_OpeningElementBaseQuantities - Depth: 166 cm; Height: 275 cm; Width: 90 cm
2995738 | 00_Ground Floor | Qto_OpeningElementBaseQuantities - Depth: 166 cm; Height: 275 cm; Width: 90 cm
2995738 | 00_Ground Floor
2995739 | 00_Ground Floor
2995845 | 00_Ground Floor
2995846 | 00_Ground Floor | Qto_OpeningElementBaseQuantities - Depth: 166 cm; Height: 275 cm; Width: 90 cm
2995847 | 00_Ground Floor | Qto_OpeningElementBaseQuantities - Depth: 166 cm; Height: 275 cm; Width: 90 cm
2995847 | 00_Ground Floor
2995848 | 00_Ground Floor
2995904 | 00_Ground Floor
2995905 | 00_Ground Floor | Qto_OpeningElementBaseQuantities - Depth: 166 cm; Height: 275 cm; Width: 90 cm
2995906 | 00_Ground Floor | Qto_OpeningElementBaseQuantities - Depth: 166 cm; Height: 275 cm; Width: 90 cm
2995906 | 00_Ground Floor
2995907 | 00_Ground Floor
2995963 | 00_Ground Floor
2995964 | 00_Ground Floor | Qto_OpeningElementBaseQuantities - Depth: 166 cm; Height: 275 cm; Width: 90 cm
2995965 | 00_Ground Floor | Qto_OpeningElementBaseQuantities - Depth: 166 cm; Height: 275 cm; Width: 90 cm
2995965 | 00_Ground Floor
2995966 | 00_Ground Floor
2996022 | 00_Ground Floor
2996023 | 00_Ground Floor | Qto_OpeningElementBaseQuantities - Depth: 166 cm; Height: 275 cm; Width: 90 cm
2996024 | 00_Ground Floor | Qto_OpeningElementBaseQuantities - Depth: 166 cm; Height: 275 cm; Width: 90 cm
2996024 | 00_Ground Floor
2996025 | 00_Ground Floor
2996081 | 00_Ground Floor
2996082 | 00_Ground Floor | Qto_OpeningElementBaseQuantities - Depth: 166 cm; Height: 275 cm; Width: 90 cm
2996083 | 00_Ground Floor | Qto_OpeningElementBaseQuantities - Depth: 166 cm; Height: 275 cm; Width: 90 cm
2996083 | 00_Ground Floor
2996084 | 00_Ground Floor
2996148 | 00_Ground Floor
2996149 | 00_Ground Floor | Qto_OpeningElementBaseQuantities - Depth: 166 cm; Height: 275 cm; Width: 90 cm
2996150 | 00_Ground Floor | Qto_OpeningElementBaseQuantities - Depth: 166 cm; Height: 275 cm; Width: 90 cm
2996150 | 00_Ground Floor
2996151 | 00_Ground Floor
2996203 | 00_Ground Floor
2996204 | 00_Ground Floor | Qto_OpeningElementBaseQuantities - Depth: 166 cm; Height: 275 cm; Width: 90 cm
2996205 | 00_Ground Floor | Qto_OpeningElementBaseQuantities - Depth: 166 cm; Height: 275 cm; Width: 90 cm
2996205 | 00_Ground Floor
2996206 | 00_Ground Floor
2996262 | 00_Ground Floor
2996263 | 00_Ground Floor | Qto_OpeningElementBaseQuantities - Depth: 166 cm; Height: 275 cm; Width: 90 cm
2996264 | 00_Ground Floor | Qto_OpeningElementBaseQuantities - Depth: 166 cm; Height: 275 cm; Width: 90 cm
2996264 | 00_Ground Floor
2996265 | 00_Ground Floor
2996317 | 00_Ground Floor
2996318 | 00_Ground Floor | Qto_OpeningElementBaseQuantities - Depth: 166 cm; Height: 275 cm; Width: 90 cm
2996319 | 00_Ground Floor | Qto_OpeningElementBaseQuantities - Depth: 166 cm; Height: 275 cm; Width: 90 cm
2996319 | 00_Ground Floor
2996320 | 00_Ground Floor
2996372 | 00_Ground Floor
2996373 | 00_Ground Floor | Qto_OpeningElementBaseQuantities - Depth: 166 cm; Height: 275 cm; Width: 90 cm
2996374 | 00_Ground Floor | Qto_OpeningElementBaseQuantities - Depth: 166 cm; Height: 275 cm; Width: 90 cm
2996374 | 00_Ground Floor
2996375 | 00_Ground Floor
2996427 | 00_Ground Floor
2996428 | 00_Ground Floor | Qto_OpeningElementBaseQuantities - Depth: 166 cm; Height: 275 cm; Width: 90 cm
2996429 | 00_Ground Floor | Qto_OpeningElementBaseQuantities - Depth: 166 cm; Height: 275 cm; Width: 90 cm
2996429 | 00_Ground Floor
2996430 | 00_Ground Floor
2996482 | 00_Ground Floor
2996483 | 00_Ground Floor | Qto_OpeningElementBaseQuantities - Depth: 166 cm; Height: 275 cm; Width: 90 cm
2996484 | 00_Ground Floor | Qto_OpeningElementBaseQuantities - Depth: 166 cm; Height: 275 cm; Width: 90 cm
2996484 | 00_Ground Floor
2996485 | 00_Ground Floor
2996592 | 00_Ground Floor
2996593 | 00_Ground Floor | Qto_OpeningElementBaseQuantities - Depth: 166 cm; Height: 275 cm; Width: 90 cm
2996594 | 00_Ground Floor | Qto_OpeningElementBaseQuantities - Depth: 166 cm; Height: 275 cm; Width: 90 cm
2996594 | 00_Ground Floor
2996595 | 00_Ground Floor
2996647 | 00_Ground Floor
2996648 | 00_Ground Floor | Qto_OpeningElementBaseQuantities - Depth: 166 cm; Height: 275 cm; Width: 90 cm
2996649 | 00_Ground Floor | Qto_OpeningElementBaseQuantities - Depth: 166 cm; Height: 275 cm; Width: 90 cm
2996649 | 00_Ground Floor
2996650 | 00_Ground Floor
2996706 | 00_Ground Floor
2996707 | 00_Ground Floor | Qto_OpeningElementBaseQuantities - Depth: 166 cm; Height: 275 cm; Width: 90 cm
2996708 | 00_Ground Floor | Qto_OpeningElementBaseQuantities - Depth: 166 cm; Height: 275 cm; Width: 90 cm
2996708 | 00_Ground Floor
2996709 | 00_Ground Floor
2996761 | 00_Ground Floor
2996762 | 00_Ground Floor | Qto_OpeningElementBaseQuantities - Depth: 166 cm; Height: 275 cm; Width: 90 cm
2996763 | 00_Ground Floor | Qto_OpeningElementBaseQuantities - Depth: 166 cm; Height: 275 cm; Width: 90 cm
2996763 | 00_Ground Floor
2996764 | 00_Ground Floor
2996816 | 00_Ground Floor
2996817 | 00_Ground Floor | Qto_OpeningElementBaseQuantities - Depth: 166 cm; Height: 275 cm; Width: 90 cm
2996818 | 00_Ground Floor | Qto_OpeningElementBaseQuantities - Depth: 166 cm; Height: 275 cm; Width: 90 cm
2996818 | 00_Ground Floor
2996819 | 00_Ground Floor
2996871 | 00_Ground Floor
2996872 | 00_Ground Floor | Qto_OpeningElementBaseQuantities - Depth: 166 cm; Height: 275 cm; Width: 90 cm
2996873 | 00_Ground Floor | Qto_OpeningElementBaseQuantities - Depth: 166 cm; Height: 275 cm; Width: 90 cm
2996873 | 00_Ground Floor
2996874 | 00_Ground Floor
2996926 | 00_Ground Floor
2996927 | 00_Ground Floor | Qto_OpeningElementBaseQuantities - Depth: 166 cm; Height: 275 cm; Width: 90 cm
2996928 | 00_Ground Floor | Qto_OpeningElementBaseQuantities - Depth: 166 cm; Height: 275 cm; Width: 90 cm
2996928 | 00_Ground Floor
2996929 | 00_Ground Floor
2996998 | 00_Ground Floor
2996999 | 00_Ground Floor | Qto_OpeningElementBaseQuantities - Depth: 166 cm; Height: 275 cm; Width: 90 cm
2997000 | 00_Ground Floor | Qto_OpeningElementBaseQuantities - Depth: 166 cm; Height: 275 cm; Width: 90 cm
2997000 | 00_Ground Floor
2997001 | 00_Ground Floor
2997053 | 00_Ground Floor
2997054 | 00_Ground Floor | Qto_OpeningElementBaseQuantities - Depth: 166 cm; Height: 275 cm; Width: 90 cm
2997055 | 00_Ground Floor | Qto_OpeningElementBaseQuantities - Depth: 166 cm; Height: 275 cm; Width: 90 cm
2997055 | 00_Ground Floor
2997056 | 00_Ground Floor
2997112 | 00_Ground Floor
2997113 | 00_Ground Floor | Qto_OpeningElementBaseQuantities - Depth: 166 cm; Height: 275 cm; Width: 90 cm
2997114 | 00_Ground Floor | Qto_OpeningElementBaseQuantities - Depth: 166 cm; Height: 275 cm; Width: 90 cm
2997114 | 00_Ground Floor
2997115 | 00_Ground Floor
2997167 | 00_Ground Floor
2997168 | 00_Ground Floor | Qto_OpeningElementBaseQuantities - Depth: 166 cm; Height: 275 cm; Width: 90 cm
2997169 | 00_Ground Floor | Qto_OpeningElementBaseQuantities - Depth: 166 cm; Height: 275 cm; Width: 90 cm
2997169 | 00_Ground Floor
2997170 | 00_Ground Floor
2997222 | 00_Ground Floor
2997223 | 00_Ground Floor | Qto_OpeningElementBaseQuantities - Depth: 166 cm; Height: 275 cm; Width: 90 cm
2997224 | 00_Ground Floor | Qto_OpeningElementBaseQuantities - Depth: 166 cm; Height: 275 cm; Width: 90 cm
2997224 | 00_Ground Floor
2997225 | 00_Ground Floor
2997277 | 00_Ground Floor
2997278 | 00_Ground Floor | Qto_OpeningElementBaseQuantities - Depth: 166 cm; Height: 275 cm; Width: 90 cm
2997279 | 00_Ground Floor | Qto_OpeningElementBaseQuantities - Depth: 166 cm; Height: 275 cm; Width: 90 cm
2997279 | 00_Ground Floor
2997280 | 00_Ground Floor
2997332 | 00_Ground Floor
2997333 | 00_Ground Floor | Qto_OpeningElementBaseQuantities - Depth: 166 cm; Height: 275 cm; Width: 90 cm
2997334 | 00_Ground Floor | Qto_OpeningElementBaseQuantities - Depth: 166 cm; Height: 275 cm; Width: 90 cm
2997334 | 00_Ground Floor
2997335 | 00_Ground Floor
2997404 | 00_Ground Floor
2997405 | 00_Ground Floor | Qto_OpeningElementBaseQuantities - Depth: 166 cm; Height: 275 cm; Width: 90 cm
2997406 | 00_Ground Floor | Qto_OpeningElementBaseQuantities - Depth: 166 cm; Height: 275 cm; Width: 90 cm
2997406 | 00_Ground Floor
2997407 | 00_Ground Floor
2997459 | 00_Ground Floor
2997460 | 00_Ground Floor | Qto_OpeningElementBaseQuantities - Depth: 166 cm; Height: 275 cm; Width: 90 cm
2997461 | 00_Ground Floor | Qto_OpeningElementBaseQuantities - Depth: 166 cm; Height: 275 cm; Width: 90 cm
2997461 | 00_Ground Floor
2997462 | 00_Ground Floor
2997518 | 00_Ground Floor
2997519 | 00_Ground Floor | Qto_OpeningElementBaseQuantities - Depth: 166 cm; Height: 275 cm; Width: 90 cm
2997520 | 00_Ground Floor | Qto_OpeningElementBaseQuantities - Depth: 166 cm; Height: 275 cm; Width: 90 cm
2997520 | 00_Ground Floor
2997521 | 00_Ground Floor
2997573 | 00_Ground Floor
2997574 | 00_Ground Floor | Qto_OpeningElementBaseQuantities - Depth: 166 cm; Height: 275 cm; Width: 90 cm
2997575 | 00_Ground Floor | Qto_OpeningElementBaseQuantities - Depth: 166 cm; Height: 275 cm; Width: 90 cm
2997575 | 00_Ground Floor
2997576 | 00_Ground Floor
2997628 | 00_Ground Floor
2997629 | 00_Ground Floor | Qto_OpeningElementBaseQuantities - Depth: 166 cm; Height: 275 cm; Width: 90 cm
2997630 | 00_Ground Floor | Qto_OpeningElementBaseQuantities - Depth: 166 cm; Height: 275 cm; Width: 90 cm
2997630 | 00_Ground Floor
2997631 | 00_Ground Floor
2997683 | 00_Ground Floor
2997684 | 00_Ground Floor | Qto_OpeningElementBaseQuantities - Depth: 166 cm; Height: 275 cm; Width: 90 cm
2997685 | 00_Ground Floor | Qto_OpeningElementBaseQuantities - Depth: 166 cm; Height: 275 cm; Width: 90 cm
2997685 | 00_Ground Floor
2997686 | 00_Ground Floor
2997738 | 00_Ground Floor
2997739 | 00_Ground Floor | Qto_OpeningElementBaseQuantities - Depth: 166 cm; Height: 275 cm; Width: 90 cm
2997740 | 00_Ground Floor | Qto_OpeningElementBaseQuantities - Depth: 166 cm; Height: 275 cm; Width: 90 cm
2997740 | 00_Ground Floor
2997741 | 00_Ground Floor
3001437 | 01_First Floor
3001438 | 01_First Floor | Qto_OpeningElementBaseQuantities - Depth: 166 cm; Height: 275 cm; Width: 90 cm
3001439 | 01_First Floor | Qto_OpeningElementBaseQuantities - Depth: 166 cm; Height: 275 cm; Width: 90 cm
3001439 | 01_First Floor
3001440 | 01_First Floor
3001484 | 01_First Floor
3001485 | 01_First Floor | Qto_OpeningElementBaseQuantities - Depth: 166 cm; Height: 275 cm; Width: 90 cm
3001486 | 01_First Floor | Qto_OpeningElementBaseQuantities - Depth: 166 cm; Height: 275 cm; Width: 90 cm
3001486 | 01_First Floor
3001487 | 01_First Floor
3001535 | 01_First Floor
3001536 | 01_First Floor | Qto_OpeningElementBaseQuantities - Depth: 166 cm; Height: 275 cm; Width: 90 cm
3001537 | 01_First Floor | Qto_OpeningElementBaseQuantities - Depth: 166 cm; Height: 275 cm; Width: 90 cm
3001537 | 01_First Floor
3001538 | 01_First Floor
3001582 | 01_First Floor
3001583 | 01_First Floor | Qto_OpeningElementBaseQuantities - Depth: 166 cm; Height: 275 cm; Width: 90 cm
3001584 | 01_First Floor | Qto_OpeningElementBaseQuantities - Depth: 166 cm; Height: 275 cm; Width: 90 cm
3001584 | 01_First Floor
3001585 | 01_First Floor
3001629 | 01_First Floor
3001630 | 01_First Floor | Qto_OpeningElementBaseQuantities - Depth: 166 cm; Height: 275 cm; Width: 90 cm
3001631 | 01_First Floor | Qto_OpeningElementBaseQuantities - Depth: 166 cm; Height: 275 cm; Width: 90 cm
3001631 | 01_First Floor
3001632 | 01_First Floor
3001676 | 01_First Floor
3001677 | 01_First Floor | Qto_OpeningElementBaseQuantities - Depth: 166 cm; Height: 275 cm; Width: 90 cm
3001678 | 01_First Floor | Qto_OpeningElementBaseQuantities - Depth: 166 cm; Height: 275 cm; Width: 90 cm
3001678 | 01_First Floor
3001679 | 01_First Floor
3001723 | 01_First Floor
3001724 | 01_First Floor | Qto_OpeningElementBaseQuantities - Depth: 166 cm; Height: 275 cm; Width: 90 cm
3001725 | 01_First Floor | Qto_OpeningElementBaseQuantities - Depth: 166 cm; Height: 275 cm; Width: 90 cm
3001725 | 01_First Floor
3001726 | 01_First Floor
3001771 | 01_First Floor
3001772 | 01_First Floor | Qto_OpeningElementBaseQuantities - Depth: 166 cm; Height: 275 cm; Width: 90 cm
3001773 | 01_First Floor | Qto_OpeningElementBaseQuantities - Depth: 166 cm; Height: 275 cm; Width: 90 cm
3001773 | 01_First Floor
3001774 | 01_First Floor
3001817 | 01_First Floor
3001818 | 01_First Floor | Qto_OpeningElementBaseQuantities - Depth: 166 cm; Height: 275 cm; Width: 90 cm
3001819 | 01_First Floor | Qto_OpeningElementBaseQuantities - Depth: 166 cm; Height: 275 cm; Width: 90 cm
3001819 | 01_First Floor
3001820 | 01_First Floor
3001867 | 01_First Floor
3001868 | 01_First Floor | Qto_OpeningElementBaseQuantities - Depth: 166 cm; Height: 275 cm; Width: 90 cm
3001869 | 01_First Floor | Qto_OpeningElementBaseQuantities - Depth: 166 cm; Height: 275 cm; Width: 90 cm
3001869 | 01_First Floor
3001870 | 01_First Floor
3001913 | 01_First Floor
3001914 | 01_First Floor | Qto_OpeningElementBaseQuantities - Depth: 166 cm; Height: 275 cm; Width: 90 cm
3001915 | 01_First Floor | Qto_OpeningElementBaseQuantities - Depth: 166 cm; Height: 275 cm; Width: 90 cm
3001915 | 01_First Floor
3001916 | 01_First Floor
3001959 | 01_First Floor
3001960 | 01_First Floor | Qto_OpeningElementBaseQuantities - Depth: 166 cm; Height: 275 cm; Width: 90 cm
3001961 | 01_First Floor | Qto_OpeningElementBaseQuantities - Depth: 166 cm; Height: 275 cm; Width: 90 cm
3001961 | 01_First Floor
3001962 | 01_First Floor
3002005 | 01_First Floor
3002006 | 01_First Floor | Qto_OpeningElementBaseQuantities - Depth: 166 cm; Height: 275 cm; Width: 90 cm
3002007 | 01_First Floor | Qto_OpeningElementBaseQuantities - Depth: 166 cm; Height: 275 cm; Width: 90 cm
3002007 | 01_First Floor
3002008 | 01_First Floor
3002051 | 01_First Floor
3002052 | 01_First Floor | Qto_OpeningElementBaseQuantities - Depth: 166 cm; Height: 275 cm; Width: 90 cm
3002053 | 01_First Floor | Qto_OpeningElementBaseQuantities - Depth: 166 cm; Height: 275 cm; Width: 90 cm
3002053 | 01_First Floor
3002054 | 01_First Floor
3002098 | 01_First Floor
3002099 | 01_First Floor | Qto_OpeningElementBaseQuantities - Depth: 166 cm; Height: 275 cm; Width: 90 cm
3002100 | 01_First Floor | Qto_OpeningElementBaseQuantities - Depth: 166 cm; Height: 275 cm; Width: 90 cm
3002100 | 01_First Floor
3002101 | 01_First Floor
3002144 | 01_First Floor
3002145 | 01_First Floor | Qto_OpeningElementBaseQuantities - Depth: 166 cm; Height: 275 cm; Width: 90 cm
3002146 | 01_First Floor | Qto_OpeningElementBaseQuantities - Depth: 166 cm; Height: 275 cm; Width: 90 cm
3002146 | 01_First Floor
3002147 | 01_First Floor
3002194 | 01_First Floor
3002195 | 01_First Floor | Qto_OpeningElementBaseQuantities - Depth: 166 cm; Height: 275 cm; Width: 90 cm
3002196 | 01_First Floor | Qto_OpeningElementBaseQuantities - Depth: 166 cm; Height: 275 cm; Width: 90 cm
3002196 | 01_First Floor
3002197 | 01_First Floor
3002240 | 01_First Floor
3002241 | 01_First Floor | Qto_OpeningElementBaseQuantities - Depth: 166 cm; Height: 275 cm; Width: 90 cm
3002242 | 01_First Floor | Qto_OpeningElementBaseQuantities - Depth: 166 cm; Height: 275 cm; Width: 90 cm
3002242 | 01_First Floor
3002243 | 01_First Floor
3002286 | 01_First Floor
3002287 | 01_First Floor | Qto_OpeningElementBaseQuantities - Depth: 166 cm; Height: 275 cm; Width: 90 cm
3002288 | 01_First Floor | Qto_OpeningElementBaseQuantities - Depth: 166 cm; Height: 275 cm; Width: 90 cm
3002288 | 01_First Floor
3002289 | 01_First Floor
3002332 | 01_First Floor
3002333 | 01_First Floor | Qto_OpeningElementBaseQuantities - Depth: 166 cm; Height: 275 cm; Width: 90 cm
3002334 | 01_First Floor | Qto_OpeningElementBaseQuantities - Depth: 166 cm; Height: 275 cm; Width: 90 cm
3002334 | 01_First Floor
3002335 | 01_First Floor
3002378 | 01_First Floor
3002379 | 01_First Floor | Qto_OpeningElementBaseQuantities - Depth: 166 cm; Height: 275 cm; Width: 90 cm
3002380 | 01_First Floor | Qto_OpeningElementBaseQuantities - Depth: 166 cm; Height: 275 cm; Width: 90 cm
3002380 | 01_First Floor
3002381 | 01_First Floor
3002425 | 01_First Floor
3002426 | 01_First Floor | Qto_OpeningElementBaseQuantities - Depth: 166 cm; Height: 275 cm; Width: 90 cm
3002427 | 01_First Floor | Qto_OpeningElementBaseQuantities - Depth: 166 cm; Height: 275 cm; Width: 90 cm
3002427 | 01_First Floor
3002428 | 01_First Floor
3002471 | 01_First Floor
3002472 | 01_First Floor | Qto_OpeningElementBaseQuantities - Depth: 166 cm; Height: 275 cm; Width: 90 cm
3002473 | 01_First Floor | Qto_OpeningElementBaseQuantities - Depth: 166 cm; Height: 275 cm; Width: 90 cm
3002473 | 01_First Floor
3002474 | 01_First Floor
3002521 | 01_First Floor
3002522 | 01_First Floor | Qto_OpeningElementBaseQuantities - Depth: 166 cm; Height: 275 cm; Width: 90 cm
3002523 | 01_First Floor | Qto_OpeningElementBaseQuantities - Depth: 166 cm; Height: 275 cm; Width: 90 cm
3002523 | 01_First Floor
3002524 | 01_First Floor
3002567 | 01_First Floor
3002568 | 01_First Floor | Qto_OpeningElementBaseQuantities - Depth: 166 cm; Height: 275 cm; Width: 90 cm
3002569 | 01_First Floor | Qto_OpeningElementBaseQuantities - Depth: 166 cm; Height: 275 cm; Width: 90 cm
3002569 | 01_First Floor
3002570 | 01_First Floor
3002613 | 01_First Floor
3002614 | 01_First Floor | Qto_OpeningElementBaseQuantities - Depth: 166 cm; Height: 275 cm; Width: 90 cm
3002615 | 01_First Floor | Qto_OpeningElementBaseQuantities - Depth: 166 cm; Height: 275 cm; Width: 90 cm
3002615 | 01_First Floor
3002616 | 01_First Floor
3002659 | 01_First Floor
3002660 | 01_First Floor | Qto_OpeningElementBaseQuantities - Depth: 166 cm; Height: 275 cm; Width: 90 cm
3002661 | 01_First Floor | Qto_OpeningElementBaseQuantities - Depth: 166 cm; Height: 275 cm; Width: 90 cm
3002661 | 01_First Floor
3002662 | 01_First Floor
3002705 | 01_First Floor
3002706 | 01_First Floor | Qto_OpeningElementBaseQuantities - Depth: 166 cm; Height: 275 cm; Width: 90 cm
3002707 | 01_First Floor | Qto_OpeningElementBaseQuantities - Depth: 166 cm; Height: 275 cm; Width: 90 cm
3002707 | 01_First Floor
3002708 | 01_First Floor
3002752 | 01_First Floor
3002753 | 01_First Floor | Qto_OpeningElementBaseQuantities - Depth: 166 cm; Height: 275 cm; Width: 90 cm
3002754 | 01_First Floor | Qto_OpeningElementBaseQuantities - Depth: 166 cm; Height: 275 cm; Width: 90 cm
3002754 | 01_First Floor
3002755 | 01_First Floor
3002798 | 01_First Floor
3002799 | 01_First Floor | Qto_OpeningElementBaseQuantities - Depth: 166 cm; Height: 275 cm; Width: 90 cm
3002800 | 01_First Floor | Qto_OpeningElementBaseQuantities - Depth: 166 cm; Height: 275 cm; Width: 90 cm
3002800 | 01_First Floor
3002801 | 01_First Floor
3002848 | 01_First Floor
3002849 | 01_First Floor | Qto_OpeningElementBaseQuantities - Depth: 166 cm; Height: 275 cm; Width: 90 cm
3002850 | 01_First Floor | Qto_OpeningElementBaseQuantities - Depth: 166 cm; Height: 275 cm; Width: 90 cm
3002850 | 01_First Floor
3002851 | 01_First Floor
3002894 | 01_First Floor
3002895 | 01_First Floor | Qto_OpeningElementBaseQuantities - Depth: 166 cm; Height: 275 cm; Width: 90 cm
3002896 | 01_First Floor | Qto_OpeningElementBaseQuantities - Depth: 166 cm; Height: 275 cm; Width: 90 cm
3002896 | 01_First Floor
3002897 | 01_First Floor
3002940 | 01_First Floor
3002941 | 01_First Floor | Qto_OpeningElementBaseQuantities - Depth: 166 cm; Height: 275 cm; Width: 90 cm
3002942 | 01_First Floor | Qto_OpeningElementBaseQuantities - Depth: 166 cm; Height: 275 cm; Width: 90 cm
3002942 | 01_First Floor
3002943 | 01_First Floor
3002986 | 01_First Floor
3002987 | 01_First Floor | Qto_OpeningElementBaseQuantities - Depth: 166 cm; Height: 275 cm; Width: 90 cm
3002988 | 01_First Floor | Qto_OpeningElementBaseQuantities - Depth: 166 cm; Height: 275 cm; Width: 90 cm
3002988 | 01_First Floor
3002989 | 01_First Floor
3003032 | 01_First Floor
3003033 | 01_First Floor | Qto_OpeningElementBaseQuantities - Depth: 166 cm; Height: 275 cm; Width: 90 cm
3003034 | 01_First Floor | Qto_OpeningElementBaseQuantities - Depth: 166 cm; Height: 275 cm; Width: 90 cm
3003034 | 01_First Floor
3003035 | 01_First Floor
3003641 | 02_Second Floor
3003642 | 02_Second Floor | Qto_OpeningElementBaseQuantities - Depth: 166 cm; Height: 275 cm; Width: 90 cm
3003643 | 02_Second Floor | Qto_OpeningElementBaseQuantities - Depth: 166 cm; Height: 275 cm; Width: 90 cm
3003643 | 02_Second Floor
3003644 | 02_Second Floor
3003687 | 02_Second Floor
3003688 | 02_Second Floor | Qto_OpeningElementBaseQuantities - Depth: 166 cm; Height: 275 cm; Width: 90 cm
3003689 | 02_Second Floor | Qto_OpeningElementBaseQuantities - Depth: 166 cm; Height: 275 cm; Width: 90 cm
3003689 | 02_Second Floor
3003690 | 02_Second Floor
3003737 | 02_Second Floor
3003738 | 02_Second Floor | Qto_OpeningElementBaseQuantities - Depth: 166 cm; Height: 275 cm; Width: 90 cm
3003739 | 02_Second Floor | Qto_OpeningElementBaseQuantities - Depth: 166 cm; Height: 275 cm; Width: 90 cm
3003739 | 02_Second Floor
3003740 | 02_Second Floor
3003783 | 02_Second Floor
3003784 | 02_Second Floor | Qto_OpeningElementBaseQuantities - Depth: 166 cm; Height: 275 cm; Width: 90 cm
3003785 | 02_Second Floor | Qto_OpeningElementBaseQuantities - Depth: 166 cm; Height: 275 cm; Width: 90 cm
3003785 | 02_Second Floor
3003786 | 02_Second Floor
3003829 | 02_Second Floor
3003830 | 02_Second Floor | Qto_OpeningElementBaseQuantities - Depth: 166 cm; Height: 275 cm; Width: 90 cm
3003831 | 02_Second Floor | Qto_OpeningElementBaseQuantities - Depth: 166 cm; Height: 275 cm; Width: 90 cm
3003831 | 02_Second Floor
3003832 | 02_Second Floor
3003875 | 02_Second Floor
3003876 | 02_Second Floor | Qto_OpeningElementBaseQuantities - Depth: 166 cm; Height: 275 cm; Width: 90 cm
3003877 | 02_Second Floor | Qto_OpeningElementBaseQuantities - Depth: 166 cm; Height: 275 cm; Width: 90 cm
3003877 | 02_Second Floor
3003878 | 02_Second Floor
3003921 | 02_Second Floor
3003922 | 02_Second Floor | Qto_OpeningElementBaseQuantities - Depth: 166 cm; Height: 275 cm; Width: 90 cm
3003923 | 02_Second Floor | Qto_OpeningElementBaseQuantities - Depth: 166 cm; Height: 275 cm; Width: 90 cm
3003923 | 02_Second Floor
3003924 | 02_Second Floor
3003968 | 02_Second Floor
3003969 | 02_Second Floor | Qto_OpeningElementBaseQuantities - Depth: 166 cm; Height: 275 cm; Width: 90 cm
3003970 | 02_Second Floor | Qto_OpeningElementBaseQuantities - Depth: 166 cm; Height: 275 cm; Width: 90 cm
3003970 | 02_Second Floor
3003971 | 02_Second Floor
3004014 | 02_Second Floor
3004015 | 02_Second Floor | Qto_OpeningElementBaseQuantities - Depth: 166 cm; Height: 275 cm; Width: 90 cm
3004016 | 02_Second Floor | Qto_OpeningElementBaseQuantities - Depth: 166 cm; Height: 275 cm; Width: 90 cm
3004016 | 02_Second Floor
3004017 | 02_Second Floor
3004064 | 02_Second Floor
3004065 | 02_Second Floor | Qto_OpeningElementBaseQuantities - Depth: 166 cm; Height: 275 cm; Width: 90 cm
3004066 | 02_Second Floor | Qto_OpeningElementBaseQuantities - Depth: 166 cm; Height: 275 cm; Width: 90 cm
3004066 | 02_Second Floor
3004067 | 02_Second Floor
3004110 | 02_Second Floor
3004111 | 02_Second Floor | Qto_OpeningElementBaseQuantities - Depth: 166 cm; Height: 275 cm; Width: 90 cm
3004112 | 02_Second Floor | Qto_OpeningElementBaseQuantities - Depth: 166 cm; Height: 275 cm; Width: 90 cm
3004112 | 02_Second Floor
3004113 | 02_Second Floor
3004156 | 02_Second Floor
3004157 | 02_Second Floor | Qto_OpeningElementBaseQuantities - Depth: 166 cm; Height: 275 cm; Width: 90 cm
3004158 | 02_Second Floor | Qto_OpeningElementBaseQuantities - Depth: 166 cm; Height: 275 cm; Width: 90 cm
3004158 | 02_Second Floor
3004159 | 02_Second Floor
3004202 | 02_Second Floor
3004203 | 02_Second Floor | Qto_OpeningElementBaseQuantities - Depth: 166 cm; Height: 275 cm; Width: 90 cm
3004204 | 02_Second Floor | Qto_OpeningElementBaseQuantities - Depth: 166 cm; Height: 275 cm; Width: 90 cm
3004204 | 02_Second Floor
3004205 | 02_Second Floor
3004248 | 02_Second Floor
3004249 | 02_Second Floor | Qto_OpeningElementBaseQuantities - Depth: 166 cm; Height: 275 cm; Width: 90 cm
3004250 | 02_Second Floor | Qto_OpeningElementBaseQuantities - Depth: 166 cm; Height: 275 cm; Width: 90 cm
3004250 | 02_Second Floor
3004251 | 02_Second Floor
3004295 | 02_Second Floor
3004296 | 02_Second Floor | Qto_OpeningElementBaseQuantities - Depth: 166 cm; Height: 275 cm; Width: 90 cm
3004297 | 02_Second Floor | Qto_OpeningElementBaseQuantities - Depth: 166 cm; Height: 275 cm; Width: 90 cm
3004297 | 02_Second Floor
3004298 | 02_Second Floor
3004341 | 02_Second Floor
3004342 | 02_Second Floor | Qto_OpeningElementBaseQuantities - Depth: 166 cm; Height: 275 cm; Width: 90 cm
3004343 | 02_Second Floor | Qto_OpeningElementBaseQuantities - Depth: 166 cm; Height: 275 cm; Width: 90 cm
3004343 | 02_Second Floor
3004344 | 02_Second Floor
3004391 | 02_Second Floor
3004392 | 02_Second Floor | Qto_OpeningElementBaseQuantities - Depth: 166 cm; Height: 275 cm; Width: 90 cm
3004393 | 02_Second Floor | Qto_OpeningElementBaseQuantities - Depth: 166 cm; Height: 275 cm; Width: 90 cm
3004393 | 02_Second Floor
3004394 | 02_Second Floor
3004437 | 02_Second Floor
3004438 | 02_Second Floor | Qto_OpeningElementBaseQuantities - Depth: 166 cm; Height: 275 cm; Width: 90 cm
3004439 | 02_Second Floor | Qto_OpeningElementBaseQuantities - Depth: 166 cm; Height: 275 cm; Width: 90 cm
3004439 | 02_Second Floor
3004440 | 02_Second Floor
3004483 | 02_Second Floor
3004484 | 02_Second Floor | Qto_OpeningElementBaseQuantities - Depth: 166 cm; Height: 275 cm; Width: 90 cm
3004485 | 02_Second Floor | Qto_OpeningElementBaseQuantities - Depth: 166 cm; Height: 275 cm; Width: 90 cm
3004485 | 02_Second Floor
3004486 | 02_Second Floor
3004529 | 02_Second Floor
3004530 | 02_Second Floor | Qto_OpeningElementBaseQuantities - Depth: 166 cm; Height: 275 cm; Width: 90 cm
3004531 | 02_Second Floor | Qto_OpeningElementBaseQuantities - Depth: 166 cm; Height: 275 cm; Width: 90 cm
3004531 | 02_Second Floor
3004532 | 02_Second Floor
3004575 | 02_Second Floor
3004576 | 02_Second Floor | Qto_OpeningElementBaseQuantities - Depth: 166 cm; Height: 275 cm; Width: 90 cm
3004577 | 02_Second Floor | Qto_OpeningElementBaseQuantities - Depth: 166 cm; Height: 275 cm; Width: 90 cm
3004577 | 02_Second Floor
3004578 | 02_Second Floor
3004622 | 02_Second Floor
3004623 | 02_Second Floor | Qto_OpeningElementBaseQuantities - Depth: 166 cm; Height: 275 cm; Width: 90 cm
3004624 | 02_Second Floor | Qto_OpeningElementBaseQuantities - Depth: 166 cm; Height: 275 cm; Width: 90 cm
3004624 | 02_Second Floor
3004625 | 02_Second Floor
3004668 | 02_Second Floor
3004669 | 02_Second Floor | Qto_OpeningElementBaseQuantities - Depth: 166 cm; Height: 275 cm; Width: 90 cm
3004670 | 02_Second Floor | Qto_OpeningElementBaseQuantities - Depth: 166 cm; Height: 275 cm; Width: 90 cm
3004670 | 02_Second Floor
3004671 | 02_Second Floor
3004718 | 02_Second Floor
3004719 | 02_Second Floor | Qto_OpeningElementBaseQuantities - Depth: 166 cm; Height: 275 cm; Width: 90 cm
3004720 | 02_Second Floor | Qto_OpeningElementBaseQuantities - Depth: 166 cm; Height: 275 cm; Width: 90 cm
3004720 | 02_Second Floor
3004721 | 02_Second Floor
3004764 | 02_Second Floor
3004765 | 02_Second Floor | Qto_OpeningElementBaseQuantities - Depth: 166 cm; Height: 275 cm; Width: 90 cm
3004766 | 02_Second Floor | Qto_OpeningElementBaseQuantities - Depth: 166 cm; Height: 275 cm; Width: 90 cm
3004766 | 02_Second Floor
3004767 | 02_Second Floor
3004810 | 02_Second Floor
3004811 | 02_Second Floor | Qto_OpeningElementBaseQuantities - Depth: 166 cm; Height: 275 cm; Width: 90 cm
3004812 | 02_Second Floor | Qto_OpeningElementBaseQuantities - Depth: 166 cm; Height: 275 cm; Width: 90 cm
3004812 | 02_Second Floor
3004813 | 02_Second Floor
3004856 | 02_Second Floor
3004857 | 02_Second Floor | Qto_OpeningElementBaseQuantities - Depth: 166 cm; Height: 275 cm; Width: 90 cm
3004858 | 02_Second Floor | Qto_OpeningElementBaseQuantities - Depth: 166 cm; Height: 275 cm; Width: 90 cm
3004858 | 02_Second Floor
3004859 | 02_Second Floor
3004902 | 02_Second Floor
3004903 | 02_Second Floor | Qto_OpeningElementBaseQuantities - Depth: 166 cm; Height: 275 cm; Width: 90 cm
3004904 | 02_Second Floor | Qto_OpeningElementBaseQuantities - Depth: 166 cm; Height: 275 cm; Width: 90 cm
3004904 | 02_Second Floor
3004905 | 02_Second Floor
3004949 | 02_Second Floor
3004950 | 02_Second Floor | Qto_OpeningElementBaseQuantities - Depth: 166 cm; Height: 275 cm; Width: 90 cm
3004951 | 02_Second Floor | Qto_OpeningElementBaseQuantities - Depth: 166 cm; Height: 275 cm; Width: 90 cm
3004951 | 02_Second Floor
3004952 | 02_Second Floor
3004995 | 02_Second Floor
3004996 | 02_Second Floor | Qto_OpeningElementBaseQuantities - Depth: 166 cm; Height: 275 cm; Width: 90 cm
3004997 | 02_Second Floor | Qto_OpeningElementBaseQuantities - Depth: 166 cm; Height: 275 cm; Width: 90 cm
3004997 | 02_Second Floor
3004998 | 02_Second Floor
3005045 | 02_Second Floor
3005046 | 02_Second Floor | Qto_OpeningElementBaseQuantities - Depth: 166 cm; Height: 275 cm; Width: 90 cm
3005047 | 02_Second Floor | Qto_OpeningElementBaseQuantities - Depth: 166 cm; Height: 275 cm; Width: 90 cm
3005047 | 02_Second Floor
3005048 | 02_Second Floor
3005091 | 02_Second Floor
3005092 | 02_Second Floor | Qto_OpeningElementBaseQuantities - Depth: 166 cm; Height: 275 cm; Width: 90 cm
3005093 | 02_Second Floor | Qto_OpeningElementBaseQuantities - Depth: 166 cm; Height: 275 cm; Width: 90 cm
3005093 | 02_Second Floor
3005094 | 02_Second Floor
3005137 | 02_Second Floor
3005138 | 02_Second Floor | Qto_OpeningElementBaseQuantities - Depth: 166 cm; Height: 275 cm; Width: 90 cm
3005139 | 02_Second Floor | Qto_OpeningElementBaseQuantities - Depth: 166 cm; Height: 275 cm; Width: 90 cm
3005139 | 02_Second Floor
3005140 | 02_Second Floor
3005183 | 02_Second Floor
3005184 | 02_Second Floor | Qto_OpeningElementBaseQuantities - Depth: 166 cm; Height: 275 cm; Width: 90 cm
3005185 | 02_Second Floor | Qto_OpeningElementBaseQuantities - Depth: 166 cm; Height: 275 cm; Width: 90 cm
3005185 | 02_Second Floor
3005186 | 02_Second Floor
3005229 | 02_Second Floor
3005230 | 02_Second Floor | Qto_OpeningElementBaseQuantities - Depth: 166 cm; Height: 275 cm; Width: 90 cm
3005231 | 02_Second Floor | Qto_OpeningElementBaseQuantities - Depth: 166 cm; Height: 275 cm; Width: 90 cm
3005231 | 02_Second Floor
3005232 | 02_Second Floor
3005838 | 03_Third Floor
3005839 | 03_Third Floor | Qto_OpeningElementBaseQuantities - Depth: 166 cm; Height: 275 cm; Width: 90 cm
3005840 | 03_Third Floor | Qto_OpeningElementBaseQuantities - Depth: 166 cm; Height: 275 cm; Width: 90 cm
3005840 | 03_Third Floor
3005841 | 03_Third Floor
3005884 | 03_Third Floor
3005885 | 03_Third Floor | Qto_OpeningElementBaseQuantities - Depth: 166 cm; Height: 275 cm; Width: 90 cm
3005886 | 03_Third Floor | Qto_OpeningElementBaseQuantities - Depth: 166 cm; Height: 275 cm; Width: 90 cm
3005886 | 03_Third Floor
3005887 | 03_Third Floor
3005934 | 03_Third Floor
3005935 | 03_Third Floor | Qto_OpeningElementBaseQuantities - Depth: 166 cm; Height: 275 cm; Width: 90 cm
3005936 | 03_Third Floor | Qto_OpeningElementBaseQuantities - Depth: 166 cm; Height: 275 cm; Width: 90 cm
3005936 | 03_Third Floor
3005937 | 03_Third Floor
3005980 | 03_Third Floor
3005981 | 03_Third Floor | Qto_OpeningElementBaseQuantities - Depth: 166 cm; Height: 275 cm; Width: 90 cm
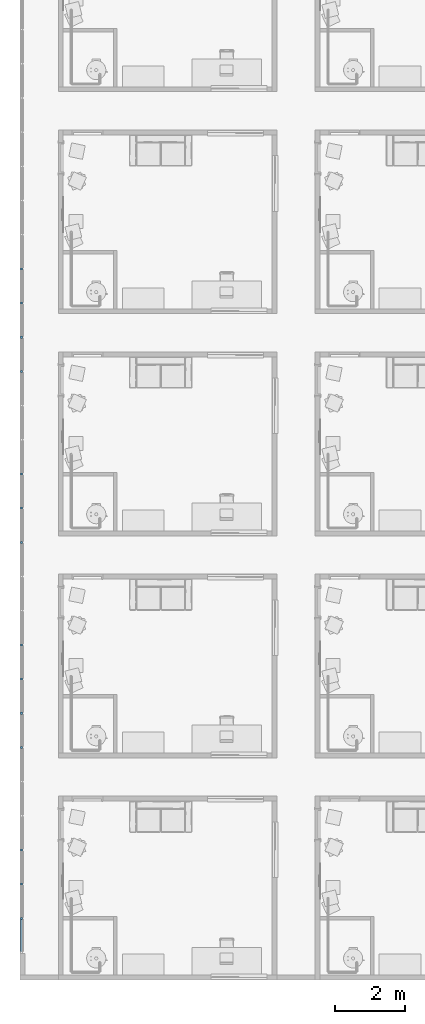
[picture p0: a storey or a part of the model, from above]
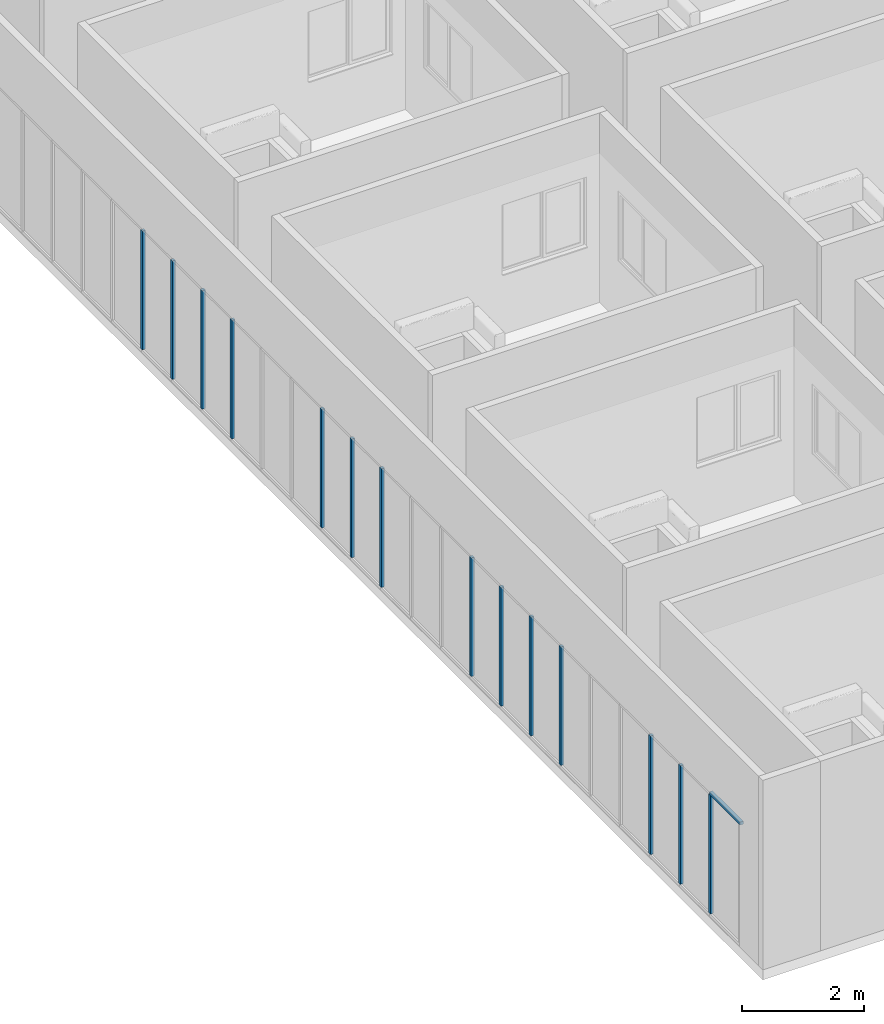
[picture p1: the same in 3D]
Properties of the parts of a building model (IFC4), part 9 of 14

# IfcOpeningElement (1416)
Name (Basic Wall:ARC_22.10_WA_LB_SB14_gen_BERSnl:...) | In
3005982 | 03_Third Floor | Qto_OpeningElementBaseQuantities - Depth: 166 cm; Height: 275 cm; Width: 90 cm
3005982 | 03_Third Floor
3005983 | 03_Third Floor
3006026 | 03_Third Floor
3006027 | 03_Third Floor | Qto_OpeningElementBaseQuantities - Depth: 166 cm; Height: 275 cm; Width: 90 cm
3006028 | 03_Third Floor | Qto_OpeningElementBaseQuantities - Depth: 166 cm; Height: 275 cm; Width: 90 cm
3006028 | 03_Third Floor
3006029 | 03_Third Floor
3006072 | 03_Third Floor
3006073 | 03_Third Floor | Qto_OpeningElementBaseQuantities - Depth: 166 cm; Height: 275 cm; Width: 90 cm
3006074 | 03_Third Floor | Qto_OpeningElementBaseQuantities - Depth: 166 cm; Height: 275 cm; Width: 90 cm
3006074 | 03_Third Floor
3006075 | 03_Third Floor
3006118 | 03_Third Floor
3006119 | 03_Third Floor | Qto_OpeningElementBaseQuantities - Depth: 166 cm; Height: 275 cm; Width: 90 cm
3006120 | 03_Third Floor | Qto_OpeningElementBaseQuantities - Depth: 166 cm; Height: 275 cm; Width: 90 cm
3006120 | 03_Third Floor
3006121 | 03_Third Floor
3006165 | 03_Third Floor
3006166 | 03_Third Floor | Qto_OpeningElementBaseQuantities - Depth: 166 cm; Height: 275 cm; Width: 90 cm
3006167 | 03_Third Floor | Qto_OpeningElementBaseQuantities - Depth: 166 cm; Height: 275 cm; Width: 90 cm
3006167 | 03_Third Floor
3006168 | 03_Third Floor
3006211 | 03_Third Floor
3006212 | 03_Third Floor | Qto_OpeningElementBaseQuantities - Depth: 166 cm; Height: 275 cm; Width: 90 cm
3006213 | 03_Third Floor | Qto_OpeningElementBaseQuantities - Depth: 166 cm; Height: 275 cm; Width: 90 cm
3006213 | 03_Third Floor
3006214 | 03_Third Floor
3006261 | 03_Third Floor
3006262 | 03_Third Floor | Qto_OpeningElementBaseQuantities - Depth: 166 cm; Height: 275 cm; Width: 90 cm
3006263 | 03_Third Floor | Qto_OpeningElementBaseQuantities - Depth: 166 cm; Height: 275 cm; Width: 90 cm
3006263 | 03_Third Floor
3006264 | 03_Third Floor
3006307 | 03_Third Floor
3006308 | 03_Third Floor | Qto_OpeningElementBaseQuantities - Depth: 166 cm; Height: 275 cm; Width: 90 cm
3006309 | 03_Third Floor | Qto_OpeningElementBaseQuantities - Depth: 166 cm; Height: 275 cm; Width: 90 cm
3006309 | 03_Third Floor
3006310 | 03_Third Floor
3006353 | 03_Third Floor
3006354 | 03_Third Floor | Qto_OpeningElementBaseQuantities - Depth: 166 cm; Height: 275 cm; Width: 90 cm
3006355 | 03_Third Floor | Qto_OpeningElementBaseQuantities - Depth: 166 cm; Height: 275 cm; Width: 90 cm
3006355 | 03_Third Floor
3006356 | 03_Third Floor
3006399 | 03_Third Floor
3006400 | 03_Third Floor | Qto_OpeningElementBaseQuantities - Depth: 166 cm; Height: 275 cm; Width: 90 cm
3006401 | 03_Third Floor | Qto_OpeningElementBaseQuantities - Depth: 166 cm; Height: 275 cm; Width: 90 cm
3006401 | 03_Third Floor
3006402 | 03_Third Floor
3006445 | 03_Third Floor
3006446 | 03_Third Floor | Qto_OpeningElementBaseQuantities - Depth: 166 cm; Height: 275 cm; Width: 90 cm
3006447 | 03_Third Floor | Qto_OpeningElementBaseQuantities - Depth: 166 cm; Height: 275 cm; Width: 90 cm
3006447 | 03_Third Floor
3006448 | 03_Third Floor
3006492 | 03_Third Floor
3006493 | 03_Third Floor | Qto_OpeningElementBaseQuantities - Depth: 166 cm; Height: 275 cm; Width: 90 cm
3006494 | 03_Third Floor | Qto_OpeningElementBaseQuantities - Depth: 166 cm; Height: 275 cm; Width: 90 cm
3006494 | 03_Third Floor
3006495 | 03_Third Floor
3006538 | 03_Third Floor
3006539 | 03_Third Floor | Qto_OpeningElementBaseQuantities - Depth: 166 cm; Height: 275 cm; Width: 90 cm
3006540 | 03_Third Floor | Qto_OpeningElementBaseQuantities - Depth: 166 cm; Height: 275 cm; Width: 90 cm
3006540 | 03_Third Floor
3006541 | 03_Third Floor
3006588 | 03_Third Floor
3006589 | 03_Third Floor | Qto_OpeningElementBaseQuantities - Depth: 166 cm; Height: 275 cm; Width: 90 cm
3006590 | 03_Third Floor | Qto_OpeningElementBaseQuantities - Depth: 166 cm; Height: 275 cm; Width: 90 cm
3006590 | 03_Third Floor
3006591 | 03_Third Floor
3006634 | 03_Third Floor
3006635 | 03_Third Floor | Qto_OpeningElementBaseQuantities - Depth: 166 cm; Height: 275 cm; Width: 90 cm
3006636 | 03_Third Floor | Qto_OpeningElementBaseQuantities - Depth: 166 cm; Height: 275 cm; Width: 90 cm
3006636 | 03_Third Floor
3006637 | 03_Third Floor
3006680 | 03_Third Floor
3006681 | 03_Third Floor | Qto_OpeningElementBaseQuantities - Depth: 166 cm; Height: 275 cm; Width: 90 cm
3006682 | 03_Third Floor | Qto_OpeningElementBaseQuantities - Depth: 166 cm; Height: 275 cm; Width: 90 cm
3006682 | 03_Third Floor
3006683 | 03_Third Floor
3006726 | 03_Third Floor
3006727 | 03_Third Floor | Qto_OpeningElementBaseQuantities - Depth: 166 cm; Height: 275 cm; Width: 90 cm
3006728 | 03_Third Floor | Qto_OpeningElementBaseQuantities - Depth: 166 cm; Height: 275 cm; Width: 90 cm
3006728 | 03_Third Floor
3006729 | 03_Third Floor
3006772 | 03_Third Floor
3006773 | 03_Third Floor | Qto_OpeningElementBaseQuantities - Depth: 166 cm; Height: 275 cm; Width: 90 cm
3006774 | 03_Third Floor | Qto_OpeningElementBaseQuantities - Depth: 166 cm; Height: 275 cm; Width: 90 cm
3006774 | 03_Third Floor
3006775 | 03_Third Floor
3006819 | 03_Third Floor
3006820 | 03_Third Floor | Qto_OpeningElementBaseQuantities - Depth: 166 cm; Height: 275 cm; Width: 90 cm
3006821 | 03_Third Floor | Qto_OpeningElementBaseQuantities - Depth: 166 cm; Height: 275 cm; Width: 90 cm
3006821 | 03_Third Floor
3006822 | 03_Third Floor
3006865 | 03_Third Floor
3006866 | 03_Third Floor | Qto_OpeningElementBaseQuantities - Depth: 166 cm; Height: 275 cm; Width: 90 cm
3006867 | 03_Third Floor | Qto_OpeningElementBaseQuantities - Depth: 166 cm; Height: 275 cm; Width: 90 cm
3006867 | 03_Third Floor
3006868 | 03_Third Floor
3006915 | 03_Third Floor
3006916 | 03_Third Floor | Qto_OpeningElementBaseQuantities - Depth: 166 cm; Height: 275 cm; Width: 90 cm
3006917 | 03_Third Floor | Qto_OpeningElementBaseQuantities - Depth: 166 cm; Height: 275 cm; Width: 90 cm
3006917 | 03_Third Floor
3006918 | 03_Third Floor
3006961 | 03_Third Floor
3006962 | 03_Third Floor | Qto_OpeningElementBaseQuantities - Depth: 166 cm; Height: 275 cm; Width: 90 cm
3006963 | 03_Third Floor | Qto_OpeningElementBaseQuantities - Depth: 166 cm; Height: 275 cm; Width: 90 cm
3006963 | 03_Third Floor
3006964 | 03_Third Floor
3007007 | 03_Third Floor
3007008 | 03_Third Floor | Qto_OpeningElementBaseQuantities - Depth: 166 cm; Height: 275 cm; Width: 90 cm
3007009 | 03_Third Floor | Qto_OpeningElementBaseQuantities - Depth: 166 cm; Height: 275 cm; Width: 90 cm
3007009 | 03_Third Floor
3007010 | 03_Third Floor
3007053 | 03_Third Floor
3007054 | 03_Third Floor | Qto_OpeningElementBaseQuantities - Depth: 166 cm; Height: 275 cm; Width: 90 cm
3007055 | 03_Third Floor | Qto_OpeningElementBaseQuantities - Depth: 166 cm; Height: 275 cm; Width: 90 cm
3007055 | 03_Third Floor
3007056 | 03_Third Floor
3007099 | 03_Third Floor
3007100 | 03_Third Floor | Qto_OpeningElementBaseQuantities - Depth: 166 cm; Height: 275 cm; Width: 90 cm
3007101 | 03_Third Floor | Qto_OpeningElementBaseQuantities - Depth: 166 cm; Height: 275 cm; Width: 90 cm
3007101 | 03_Third Floor
3007102 | 03_Third Floor
3007146 | 03_Third Floor
3007147 | 03_Third Floor | Qto_OpeningElementBaseQuantities - Depth: 166 cm; Height: 275 cm; Width: 90 cm
3007148 | 03_Third Floor | Qto_OpeningElementBaseQuantities - Depth: 166 cm; Height: 275 cm; Width: 90 cm
3007148 | 03_Third Floor
3007149 | 03_Third Floor
3007192 | 03_Third Floor
3007193 | 03_Third Floor | Qto_OpeningElementBaseQuantities - Depth: 166 cm; Height: 275 cm; Width: 90 cm
3007194 | 03_Third Floor | Qto_OpeningElementBaseQuantities - Depth: 166 cm; Height: 275 cm; Width: 90 cm
3007194 | 03_Third Floor
3007195 | 03_Third Floor
3007242 | 03_Third Floor
3007243 | 03_Third Floor | Qto_OpeningElementBaseQuantities - Depth: 166 cm; Height: 275 cm; Width: 90 cm
3007244 | 03_Third Floor | Qto_OpeningElementBaseQuantities - Depth: 166 cm; Height: 275 cm; Width: 90 cm
3007244 | 03_Third Floor
3007245 | 03_Third Floor
3007288 | 03_Third Floor
3007289 | 03_Third Floor | Qto_OpeningElementBaseQuantities - Depth: 166 cm; Height: 275 cm; Width: 90 cm
3007290 | 03_Third Floor | Qto_OpeningElementBaseQuantities - Depth: 166 cm; Height: 275 cm; Width: 90 cm
3007290 | 03_Third Floor
3007291 | 03_Third Floor
3007334 | 03_Third Floor
3007335 | 03_Third Floor | Qto_OpeningElementBaseQuantities - Depth: 166 cm; Height: 275 cm; Width: 90 cm
3007336 | 03_Third Floor | Qto_OpeningElementBaseQuantities - Depth: 166 cm; Height: 275 cm; Width: 90 cm
3007336 | 03_Third Floor
3007337 | 03_Third Floor
3007380 | 03_Third Floor
3007381 | 03_Third Floor | Qto_OpeningElementBaseQuantities - Depth: 166 cm; Height: 275 cm; Width: 90 cm
3007382 | 03_Third Floor | Qto_OpeningElementBaseQuantities - Depth: 166 cm; Height: 275 cm; Width: 90 cm
3007382 | 03_Third Floor
3007383 | 03_Third Floor
3007426 | 03_Third Floor
3007427 | 03_Third Floor | Qto_OpeningElementBaseQuantities - Depth: 166 cm; Height: 275 cm; Width: 90 cm
3007428 | 03_Third Floor | Qto_OpeningElementBaseQuantities - Depth: 166 cm; Height: 275 cm; Width: 90 cm
3007428 | 03_Third Floor
3007429 | 03_Third Floor
3008033 | 04_Fourth Floor
3008034 | 04_Fourth Floor | Qto_OpeningElementBaseQuantities - Depth: 166 cm; Height: 275 cm; Width: 90 cm
3008035 | 04_Fourth Floor | Qto_OpeningElementBaseQuantities - Depth: 166 cm; Height: 275 cm; Width: 90 cm
3008035 | 04_Fourth Floor
3008036 | 04_Fourth Floor
3008079 | 04_Fourth Floor
3008080 | 04_Fourth Floor | Qto_OpeningElementBaseQuantities - Depth: 166 cm; Height: 275 cm; Width: 90 cm
3008081 | 04_Fourth Floor | Qto_OpeningElementBaseQuantities - Depth: 166 cm; Height: 275 cm; Width: 90 cm
3008081 | 04_Fourth Floor
3008082 | 04_Fourth Floor
3008129 | 04_Fourth Floor
3008130 | 04_Fourth Floor | Qto_OpeningElementBaseQuantities - Depth: 166 cm; Height: 275 cm; Width: 90 cm
3008131 | 04_Fourth Floor | Qto_OpeningElementBaseQuantities - Depth: 166 cm; Height: 275 cm; Width: 90 cm
3008131 | 04_Fourth Floor
3008132 | 04_Fourth Floor
3008175 | 04_Fourth Floor
3008176 | 04_Fourth Floor | Qto_OpeningElementBaseQuantities - Depth: 166 cm; Height: 275 cm; Width: 90 cm
3008177 | 04_Fourth Floor | Qto_OpeningElementBaseQuantities - Depth: 166 cm; Height: 275 cm; Width: 90 cm
3008177 | 04_Fourth Floor
3008178 | 04_Fourth Floor
3008221 | 04_Fourth Floor
3008222 | 04_Fourth Floor | Qto_OpeningElementBaseQuantities - Depth: 166 cm; Height: 275 cm; Width: 90 cm
3008223 | 04_Fourth Floor | Qto_OpeningElementBaseQuantities - Depth: 166 cm; Height: 275 cm; Width: 90 cm
3008223 | 04_Fourth Floor
3008224 | 04_Fourth Floor
3008267 | 04_Fourth Floor
3008268 | 04_Fourth Floor | Qto_OpeningElementBaseQuantities - Depth: 166 cm; Height: 275 cm; Width: 90 cm
3008269 | 04_Fourth Floor | Qto_OpeningElementBaseQuantities - Depth: 166 cm; Height: 275 cm; Width: 90 cm
3008269 | 04_Fourth Floor
3008270 | 04_Fourth Floor
3008313 | 04_Fourth Floor
3008314 | 04_Fourth Floor | Qto_OpeningElementBaseQuantities - Depth: 166 cm; Height: 275 cm; Width: 90 cm
3008315 | 04_Fourth Floor | Qto_OpeningElementBaseQuantities - Depth: 166 cm; Height: 275 cm; Width: 90 cm
3008315 | 04_Fourth Floor
3008316 | 04_Fourth Floor
3008360 | 04_Fourth Floor
3008361 | 04_Fourth Floor | Qto_OpeningElementBaseQuantities - Depth: 166 cm; Height: 275 cm; Width: 90 cm
3008362 | 04_Fourth Floor | Qto_OpeningElementBaseQuantities - Depth: 166 cm; Height: 275 cm; Width: 90 cm
3008362 | 04_Fourth Floor
3008363 | 04_Fourth Floor
3008406 | 04_Fourth Floor
3008407 | 04_Fourth Floor | Qto_OpeningElementBaseQuantities - Depth: 166 cm; Height: 275 cm; Width: 90 cm
3008408 | 04_Fourth Floor | Qto_OpeningElementBaseQuantities - Depth: 166 cm; Height: 275 cm; Width: 90 cm
3008408 | 04_Fourth Floor
3008409 | 04_Fourth Floor
3008456 | 04_Fourth Floor
3008457 | 04_Fourth Floor | Qto_OpeningElementBaseQuantities - Depth: 166 cm; Height: 275 cm; Width: 90 cm
3008458 | 04_Fourth Floor | Qto_OpeningElementBaseQuantities - Depth: 166 cm; Height: 275 cm; Width: 90 cm
3008458 | 04_Fourth Floor
3008459 | 04_Fourth Floor
3008502 | 04_Fourth Floor
3008503 | 04_Fourth Floor | Qto_OpeningElementBaseQuantities - Depth: 166 cm; Height: 275 cm; Width: 90 cm
3008504 | 04_Fourth Floor | Qto_OpeningElementBaseQuantities - Depth: 166 cm; Height: 275 cm; Width: 90 cm
3008504 | 04_Fourth Floor
3008505 | 04_Fourth Floor
3008548 | 04_Fourth Floor
3008549 | 04_Fourth Floor | Qto_OpeningElementBaseQuantities - Depth: 166 cm; Height: 275 cm; Width: 90 cm
3008550 | 04_Fourth Floor | Qto_OpeningElementBaseQuantities - Depth: 166 cm; Height: 275 cm; Width: 90 cm
3008550 | 04_Fourth Floor
3008551 | 04_Fourth Floor
3008594 | 04_Fourth Floor
3008595 | 04_Fourth Floor | Qto_OpeningElementBaseQuantities - Depth: 166 cm; Height: 275 cm; Width: 90 cm
3008596 | 04_Fourth Floor | Qto_OpeningElementBaseQuantities - Depth: 166 cm; Height: 275 cm; Width: 90 cm
3008596 | 04_Fourth Floor
3008597 | 04_Fourth Floor
3008640 | 04_Fourth Floor
3008641 | 04_Fourth Floor | Qto_OpeningElementBaseQuantities - Depth: 166 cm; Height: 275 cm; Width: 90 cm
3008642 | 04_Fourth Floor | Qto_OpeningElementBaseQuantities - Depth: 166 cm; Height: 275 cm; Width: 90 cm
3008642 | 04_Fourth Floor
3008643 | 04_Fourth Floor
3008687 | 04_Fourth Floor
3008688 | 04_Fourth Floor | Qto_OpeningElementBaseQuantities - Depth: 166 cm; Height: 275 cm; Width: 90 cm
3008689 | 04_Fourth Floor | Qto_OpeningElementBaseQuantities - Depth: 166 cm; Height: 275 cm; Width: 90 cm
3008689 | 04_Fourth Floor
3008690 | 04_Fourth Floor
3008733 | 04_Fourth Floor
3008734 | 04_Fourth Floor | Qto_OpeningElementBaseQuantities - Depth: 166 cm; Height: 275 cm; Width: 90 cm
3008735 | 04_Fourth Floor | Qto_OpeningElementBaseQuantities - Depth: 166 cm; Height: 275 cm; Width: 90 cm
3008735 | 04_Fourth Floor
3008736 | 04_Fourth Floor
3008783 | 04_Fourth Floor
3008784 | 04_Fourth Floor | Qto_OpeningElementBaseQuantities - Depth: 166 cm; Height: 275 cm; Width: 90 cm
3008785 | 04_Fourth Floor | Qto_OpeningElementBaseQuantities - Depth: 166 cm; Height: 275 cm; Width: 90 cm
3008785 | 04_Fourth Floor
3008786 | 04_Fourth Floor
3008829 | 04_Fourth Floor
3008830 | 04_Fourth Floor | Qto_OpeningElementBaseQuantities - Depth: 166 cm; Height: 275 cm; Width: 90 cm
3008831 | 04_Fourth Floor | Qto_OpeningElementBaseQuantities - Depth: 166 cm; Height: 275 cm; Width: 90 cm
3008831 | 04_Fourth Floor
3008832 | 04_Fourth Floor
3008875 | 04_Fourth Floor
3008876 | 04_Fourth Floor | Qto_OpeningElementBaseQuantities - Depth: 166 cm; Height: 275 cm; Width: 90 cm
3008877 | 04_Fourth Floor | Qto_OpeningElementBaseQuantities - Depth: 166 cm; Height: 275 cm; Width: 90 cm
3008877 | 04_Fourth Floor
3008878 | 04_Fourth Floor
3008921 | 04_Fourth Floor
3008922 | 04_Fourth Floor | Qto_OpeningElementBaseQuantities - Depth: 166 cm; Height: 275 cm; Width: 90 cm
3008923 | 04_Fourth Floor | Qto_OpeningElementBaseQuantities - Depth: 166 cm; Height: 275 cm; Width: 90 cm
3008923 | 04_Fourth Floor
3008924 | 04_Fourth Floor
3008967 | 04_Fourth Floor
3008968 | 04_Fourth Floor | Qto_OpeningElementBaseQuantities - Depth: 166 cm; Height: 275 cm; Width: 90 cm
3008969 | 04_Fourth Floor | Qto_OpeningElementBaseQuantities - Depth: 166 cm; Height: 275 cm; Width: 90 cm
3008969 | 04_Fourth Floor
3008970 | 04_Fourth Floor
3009014 | 04_Fourth Floor
3009015 | 04_Fourth Floor | Qto_OpeningElementBaseQuantities - Depth: 166 cm; Height: 275 cm; Width: 90 cm
3009016 | 04_Fourth Floor | Qto_OpeningElementBaseQuantities - Depth: 166 cm; Height: 275 cm; Width: 90 cm
3009016 | 04_Fourth Floor
3009017 | 04_Fourth Floor
3009060 | 04_Fourth Floor
3009061 | 04_Fourth Floor | Qto_OpeningElementBaseQuantities - Depth: 166 cm; Height: 275 cm; Width: 90 cm
3009062 | 04_Fourth Floor | Qto_OpeningElementBaseQuantities - Depth: 166 cm; Height: 275 cm; Width: 90 cm
3009062 | 04_Fourth Floor
3009063 | 04_Fourth Floor
3009110 | 04_Fourth Floor
3009111 | 04_Fourth Floor | Qto_OpeningElementBaseQuantities - Depth: 166 cm; Height: 275 cm; Width: 90 cm
3009112 | 04_Fourth Floor | Qto_OpeningElementBaseQuantities - Depth: 166 cm; Height: 275 cm; Width: 90 cm
3009112 | 04_Fourth Floor
3009113 | 04_Fourth Floor
3009156 | 04_Fourth Floor
3009157 | 04_Fourth Floor | Qto_OpeningElementBaseQuantities - Depth: 166 cm; Height: 275 cm; Width: 90 cm
3009158 | 04_Fourth Floor | Qto_OpeningElementBaseQuantities - Depth: 166 cm; Height: 275 cm; Width: 90 cm
3009158 | 04_Fourth Floor
3009159 | 04_Fourth Floor
3009202 | 04_Fourth Floor
3009203 | 04_Fourth Floor | Qto_OpeningElementBaseQuantities - Depth: 166 cm; Height: 275 cm; Width: 90 cm
3009204 | 04_Fourth Floor | Qto_OpeningElementBaseQuantities - Depth: 166 cm; Height: 275 cm; Width: 90 cm
3009204 | 04_Fourth Floor
3009205 | 04_Fourth Floor
3009248 | 04_Fourth Floor
3009249 | 04_Fourth Floor | Qto_OpeningElementBaseQuantities - Depth: 166 cm; Height: 275 cm; Width: 90 cm
3009250 | 04_Fourth Floor | Qto_OpeningElementBaseQuantities - Depth: 166 cm; Height: 275 cm; Width: 90 cm
3009250 | 04_Fourth Floor
3009251 | 04_Fourth Floor
3009294 | 04_Fourth Floor
3009295 | 04_Fourth Floor | Qto_OpeningElementBaseQuantities - Depth: 166 cm; Height: 275 cm; Width: 90 cm
3009296 | 04_Fourth Floor | Qto_OpeningElementBaseQuantities - Depth: 166 cm; Height: 275 cm; Width: 90 cm
3009296 | 04_Fourth Floor
3009297 | 04_Fourth Floor
3009341 | 04_Fourth Floor
3009342 | 04_Fourth Floor | Qto_OpeningElementBaseQuantities - Depth: 166 cm; Height: 275 cm; Width: 90 cm
3009343 | 04_Fourth Floor | Qto_OpeningElementBaseQuantities - Depth: 166 cm; Height: 275 cm; Width: 90 cm
3009343 | 04_Fourth Floor
3009344 | 04_Fourth Floor
3009387 | 04_Fourth Floor
3009388 | 04_Fourth Floor | Qto_OpeningElementBaseQuantities - Depth: 166 cm; Height: 275 cm; Width: 90 cm
3009389 | 04_Fourth Floor | Qto_OpeningElementBaseQuantities - Depth: 166 cm; Height: 275 cm; Width: 90 cm
3009389 | 04_Fourth Floor
3009390 | 04_Fourth Floor
3009437 | 04_Fourth Floor
3009438 | 04_Fourth Floor | Qto_OpeningElementBaseQuantities - Depth: 166 cm; Height: 275 cm; Width: 90 cm
3009439 | 04_Fourth Floor | Qto_OpeningElementBaseQuantities - Depth: 166 cm; Height: 275 cm; Width: 90 cm
3009439 | 04_Fourth Floor
3009440 | 04_Fourth Floor
3009483 | 04_Fourth Floor
3009484 | 04_Fourth Floor | Qto_OpeningElementBaseQuantities - Depth: 166 cm; Height: 275 cm; Width: 90 cm
3009485 | 04_Fourth Floor | Qto_OpeningElementBaseQuantities - Depth: 166 cm; Height: 275 cm; Width: 90 cm
3009485 | 04_Fourth Floor
3009486 | 04_Fourth Floor
3009529 | 04_Fourth Floor
3009530 | 04_Fourth Floor | Qto_OpeningElementBaseQuantities - Depth: 166 cm; Height: 275 cm; Width: 90 cm
3009531 | 04_Fourth Floor | Qto_OpeningElementBaseQuantities - Depth: 166 cm; Height: 275 cm; Width: 90 cm
3009531 | 04_Fourth Floor
3009532 | 04_Fourth Floor
3009575 | 04_Fourth Floor
3009576 | 04_Fourth Floor | Qto_OpeningElementBaseQuantities - Depth: 166 cm; Height: 275 cm; Width: 90 cm
3009577 | 04_Fourth Floor | Qto_OpeningElementBaseQuantities - Depth: 166 cm; Height: 275 cm; Width: 90 cm
3009577 | 04_Fourth Floor
3009578 | 04_Fourth Floor
3009621 | 04_Fourth Floor
3009622 | 04_Fourth Floor | Qto_OpeningElementBaseQuantities - Depth: 166 cm; Height: 275 cm; Width: 90 cm
3009623 | 04_Fourth Floor | Qto_OpeningElementBaseQuantities - Depth: 166 cm; Height: 275 cm; Width: 90 cm
3009623 | 04_Fourth Floor
3009624 | 04_Fourth Floor
3010228 | 05_Fifth Floor
3010229 | 05_Fifth Floor | Qto_OpeningElementBaseQuantities - Depth: 166 cm; Height: 275 cm; Width: 90 cm
3010230 | 05_Fifth Floor | Qto_OpeningElementBaseQuantities - Depth: 166 cm; Height: 275 cm; Width: 90 cm
3010230 | 05_Fifth Floor
3010231 | 05_Fifth Floor
3010274 | 05_Fifth Floor
3010275 | 05_Fifth Floor | Qto_OpeningElementBaseQuantities - Depth: 166 cm; Height: 275 cm; Width: 90 cm
3010276 | 05_Fifth Floor | Qto_OpeningElementBaseQuantities - Depth: 166 cm; Height: 275 cm; Width: 90 cm
3010276 | 05_Fifth Floor
3010277 | 05_Fifth Floor
3010324 | 05_Fifth Floor
3010325 | 05_Fifth Floor | Qto_OpeningElementBaseQuantities - Depth: 166 cm; Height: 275 cm; Width: 90 cm
3010326 | 05_Fifth Floor | Qto_OpeningElementBaseQuantities - Depth: 166 cm; Height: 275 cm; Width: 90 cm
3010326 | 05_Fifth Floor
3010327 | 05_Fifth Floor
3010370 | 05_Fifth Floor
3010371 | 05_Fifth Floor | Qto_OpeningElementBaseQuantities - Depth: 166 cm; Height: 275 cm; Width: 90 cm
3010372 | 05_Fifth Floor | Qto_OpeningElementBaseQuantities - Depth: 166 cm; Height: 275 cm; Width: 90 cm
3010372 | 05_Fifth Floor
3010373 | 05_Fifth Floor
3010416 | 05_Fifth Floor
3010417 | 05_Fifth Floor | Qto_OpeningElementBaseQuantities - Depth: 166 cm; Height: 275 cm; Width: 90 cm
3010418 | 05_Fifth Floor | Qto_OpeningElementBaseQuantities - Depth: 166 cm; Height: 275 cm; Width: 90 cm
3010418 | 05_Fifth Floor
3010419 | 05_Fifth Floor
3010462 | 05_Fifth Floor
3010463 | 05_Fifth Floor | Qto_OpeningElementBaseQuantities - Depth: 166 cm; Height: 275 cm; Width: 90 cm
3010464 | 05_Fifth Floor | Qto_OpeningElementBaseQuantities - Depth: 166 cm; Height: 275 cm; Width: 90 cm
3010464 | 05_Fifth Floor
3010465 | 05_Fifth Floor
3010508 | 05_Fifth Floor
3010509 | 05_Fifth Floor | Qto_OpeningElementBaseQuantities - Depth: 166 cm; Height: 275 cm; Width: 90 cm
3010510 | 05_Fifth Floor | Qto_OpeningElementBaseQuantities - Depth: 166 cm; Height: 275 cm; Width: 90 cm
3010510 | 05_Fifth Floor
3010511 | 05_Fifth Floor
3010555 | 05_Fifth Floor
3010556 | 05_Fifth Floor | Qto_OpeningElementBaseQuantities - Depth: 166 cm; Height: 275 cm; Width: 90 cm
3010557 | 05_Fifth Floor | Qto_OpeningElementBaseQuantities - Depth: 166 cm; Height: 275 cm; Width: 90 cm
3010557 | 05_Fifth Floor
3010558 | 05_Fifth Floor
3010601 | 05_Fifth Floor
3010602 | 05_Fifth Floor | Qto_OpeningElementBaseQuantities - Depth: 166 cm; Height: 275 cm; Width: 90 cm
3010603 | 05_Fifth Floor | Qto_OpeningElementBaseQuantities - Depth: 166 cm; Height: 275 cm; Width: 90 cm
3010603 | 05_Fifth Floor
3010604 | 05_Fifth Floor
3010651 | 05_Fifth Floor
3010652 | 05_Fifth Floor | Qto_OpeningElementBaseQuantities - Depth: 166 cm; Height: 275 cm; Width: 90 cm
3010653 | 05_Fifth Floor | Qto_OpeningElementBaseQuantities - Depth: 166 cm; Height: 275 cm; Width: 90 cm
3010653 | 05_Fifth Floor
3010654 | 05_Fifth Floor
3010697 | 05_Fifth Floor
3010698 | 05_Fifth Floor | Qto_OpeningElementBaseQuantities - Depth: 166 cm; Height: 275 cm; Width: 90 cm
3010699 | 05_Fifth Floor | Qto_OpeningElementBaseQuantities - Depth: 166 cm; Height: 275 cm; Width: 90 cm
3010699 | 05_Fifth Floor
3010700 | 05_Fifth Floor
3010743 | 05_Fifth Floor
3010744 | 05_Fifth Floor | Qto_OpeningElementBaseQuantities - Depth: 166 cm; Height: 275 cm; Width: 90 cm
3010745 | 05_Fifth Floor | Qto_OpeningElementBaseQuantities - Depth: 166 cm; Height: 275 cm; Width: 90 cm
3010745 | 05_Fifth Floor
3010746 | 05_Fifth Floor
3010789 | 05_Fifth Floor
3010790 | 05_Fifth Floor | Qto_OpeningElementBaseQuantities - Depth: 166 cm; Height: 275 cm; Width: 90 cm
3010791 | 05_Fifth Floor | Qto_OpeningElementBaseQuantities - Depth: 166 cm; Height: 275 cm; Width: 90 cm
3010791 | 05_Fifth Floor
3010792 | 05_Fifth Floor
3010835 | 05_Fifth Floor
3010836 | 05_Fifth Floor | Qto_OpeningElementBaseQuantities - Depth: 166 cm; Height: 275 cm; Width: 90 cm
3010837 | 05_Fifth Floor | Qto_OpeningElementBaseQuantities - Depth: 166 cm; Height: 275 cm; Width: 90 cm
3010837 | 05_Fifth Floor
3010838 | 05_Fifth Floor
3010882 | 05_Fifth Floor
3010883 | 05_Fifth Floor | Qto_OpeningElementBaseQuantities - Depth: 166 cm; Height: 275 cm; Width: 90 cm
3010884 | 05_Fifth Floor | Qto_OpeningElementBaseQuantities - Depth: 166 cm; Height: 275 cm; Width: 90 cm
3010884 | 05_Fifth Floor
3010885 | 05_Fifth Floor
3010928 | 05_Fifth Floor
3010929 | 05_Fifth Floor | Qto_OpeningElementBaseQuantities - Depth: 166 cm; Height: 275 cm; Width: 90 cm
3010930 | 05_Fifth Floor | Qto_OpeningElementBaseQuantities - Depth: 166 cm; Height: 275 cm; Width: 90 cm
3010930 | 05_Fifth Floor
3010931 | 05_Fifth Floor
3010978 | 05_Fifth Floor
3010979 | 05_Fifth Floor | Qto_OpeningElementBaseQuantities - Depth: 166 cm; Height: 275 cm; Width: 90 cm
3010980 | 05_Fifth Floor | Qto_OpeningElementBaseQuantities - Depth: 166 cm; Height: 275 cm; Width: 90 cm
3010980 | 05_Fifth Floor
3010981 | 05_Fifth Floor
3011024 | 05_Fifth Floor
3011025 | 05_Fifth Floor | Qto_OpeningElementBaseQuantities - Depth: 166 cm; Height: 275 cm; Width: 90 cm
3011026 | 05_Fifth Floor | Qto_OpeningElementBaseQuantities - Depth: 166 cm; Height: 275 cm; Width: 90 cm
3011026 | 05_Fifth Floor
3011027 | 05_Fifth Floor
3011070 | 05_Fifth Floor
3011071 | 05_Fifth Floor | Qto_OpeningElementBaseQuantities - Depth: 166 cm; Height: 275 cm; Width: 90 cm
3011072 | 05_Fifth Floor | Qto_OpeningElementBaseQuantities - Depth: 166 cm; Height: 275 cm; Width: 90 cm
3011072 | 05_Fifth Floor
3011073 | 05_Fifth Floor
3011116 | 05_Fifth Floor
3011117 | 05_Fifth Floor | Qto_OpeningElementBaseQuantities - Depth: 166 cm; Height: 275 cm; Width: 90 cm
3011118 | 05_Fifth Floor | Qto_OpeningElementBaseQuantities - Depth: 166 cm; Height: 275 cm; Width: 90 cm
3011118 | 05_Fifth Floor
3011119 | 05_Fifth Floor
3011162 | 05_Fifth Floor
3011163 | 05_Fifth Floor | Qto_OpeningElementBaseQuantities - Depth: 166 cm; Height: 275 cm; Width: 90 cm
3011164 | 05_Fifth Floor | Qto_OpeningElementBaseQuantities - Depth: 166 cm; Height: 275 cm; Width: 90 cm
3011164 | 05_Fifth Floor
3011165 | 05_Fifth Floor
3011209 | 05_Fifth Floor
3011210 | 05_Fifth Floor | Qto_OpeningElementBaseQuantities - Depth: 166 cm; Height: 275 cm; Width: 90 cm
3011211 | 05_Fifth Floor | Qto_OpeningElementBaseQuantities - Depth: 166 cm; Height: 275 cm; Width: 90 cm
3011211 | 05_Fifth Floor
3011212 | 05_Fifth Floor
3011255 | 05_Fifth Floor
3011256 | 05_Fifth Floor | Qto_OpeningElementBaseQuantities - Depth: 166 cm; Height: 275 cm; Width: 90 cm
3011257 | 05_Fifth Floor | Qto_OpeningElementBaseQuantities - Depth: 166 cm; Height: 275 cm; Width: 90 cm
3011257 | 05_Fifth Floor
3011258 | 05_Fifth Floor
3011305 | 05_Fifth Floor
3011306 | 05_Fifth Floor | Qto_OpeningElementBaseQuantities - Depth: 166 cm; Height: 275 cm; Width: 90 cm
3011307 | 05_Fifth Floor | Qto_OpeningElementBaseQuantities - Depth: 166 cm; Height: 275 cm; Width: 90 cm
3011307 | 05_Fifth Floor
3011308 | 05_Fifth Floor
3011351 | 05_Fifth Floor
3011352 | 05_Fifth Floor | Qto_OpeningElementBaseQuantities - Depth: 166 cm; Height: 275 cm; Width: 90 cm
3011353 | 05_Fifth Floor | Qto_OpeningElementBaseQuantities - Depth: 166 cm; Height: 275 cm; Width: 90 cm
3011353 | 05_Fifth Floor
3011354 | 05_Fifth Floor
3011397 | 05_Fifth Floor
3011398 | 05_Fifth Floor | Qto_OpeningElementBaseQuantities - Depth: 166 cm; Height: 275 cm; Width: 90 cm
3011399 | 05_Fifth Floor | Qto_OpeningElementBaseQuantities - Depth: 166 cm; Height: 275 cm; Width: 90 cm
3011399 | 05_Fifth Floor
3011400 | 05_Fifth Floor
3011443 | 05_Fifth Floor
3011444 | 05_Fifth Floor | Qto_OpeningElementBaseQuantities - Depth: 166 cm; Height: 275 cm; Width: 90 cm
3011445 | 05_Fifth Floor | Qto_OpeningElementBaseQuantities - Depth: 166 cm; Height: 275 cm; Width: 90 cm
3011445 | 05_Fifth Floor
3011446 | 05_Fifth Floor
3011489 | 05_Fifth Floor
3011490 | 05_Fifth Floor | Qto_OpeningElementBaseQuantities - Depth: 166 cm; Height: 275 cm; Width: 90 cm
3011491 | 05_Fifth Floor | Qto_OpeningElementBaseQuantities - Depth: 166 cm; Height: 275 cm; Width: 90 cm
3011491 | 05_Fifth Floor
3011492 | 05_Fifth Floor
3011536 | 05_Fifth Floor
3011537 | 05_Fifth Floor | Qto_OpeningElementBaseQuantities - Depth: 166 cm; Height: 275 cm; Width: 90 cm
3011538 | 05_Fifth Floor | Qto_OpeningElementBaseQuantities - Depth: 166 cm; Height: 275 cm; Width: 90 cm
3011538 | 05_Fifth Floor
3011539 | 05_Fifth Floor
3011582 | 05_Fifth Floor
3011583 | 05_Fifth Floor | Qto_OpeningElementBaseQuantities - Depth: 166 cm; Height: 275 cm; Width: 90 cm
3011584 | 05_Fifth Floor | Qto_OpeningElementBaseQuantities - Depth: 166 cm; Height: 275 cm; Width: 90 cm
3011584 | 05_Fifth Floor
3011585 | 05_Fifth Floor
3011632 | 05_Fifth Floor
3011633 | 05_Fifth Floor | Qto_OpeningElementBaseQuantities - Depth: 166 cm; Height: 275 cm; Width: 90 cm
3011634 | 05_Fifth Floor | Qto_OpeningElementBaseQuantities - Depth: 166 cm; Height: 275 cm; Width: 90 cm
3011634 | 05_Fifth Floor
3011635 | 05_Fifth Floor
3011678 | 05_Fifth Floor
3011679 | 05_Fifth Floor | Qto_OpeningElementBaseQuantities - Depth: 166 cm; Height: 275 cm; Width: 90 cm
3011680 | 05_Fifth Floor | Qto_OpeningElementBaseQuantities - Depth: 166 cm; Height: 275 cm; Width: 90 cm
3011680 | 05_Fifth Floor
3011681 | 05_Fifth Floor
3011724 | 05_Fifth Floor
3011725 | 05_Fifth Floor | Qto_OpeningElementBaseQuantities - Depth: 166 cm; Height: 275 cm; Width: 90 cm
3011726 | 05_Fifth Floor | Qto_OpeningElementBaseQuantities - Depth: 166 cm; Height: 275 cm; Width: 90 cm
3011726 | 05_Fifth Floor
3011727 | 05_Fifth Floor
3011770 | 05_Fifth Floor
3011771 | 05_Fifth Floor | Qto_OpeningElementBaseQuantities - Depth: 166 cm; Height: 275 cm; Width: 90 cm
3011772 | 05_Fifth Floor | Qto_OpeningElementBaseQuantities - Depth: 166 cm; Height: 275 cm; Width: 90 cm
3011772 | 05_Fifth Floor
3011773 | 05_Fifth Floor
3011816 | 05_Fifth Floor
3011817 | 05_Fifth Floor | Qto_OpeningElementBaseQuantities - Depth: 166 cm; Height: 275 cm; Width: 90 cm
3011818 | 05_Fifth Floor | Qto_OpeningElementBaseQuantities - Depth: 166 cm; Height: 275 cm; Width: 90 cm
3011818 | 05_Fifth Floor
3011819 | 05_Fifth Floor
3012425 | 06_Sixth Floor
3012426 | 06_Sixth Floor | Qto_OpeningElementBaseQuantities - Depth: 166 cm; Height: 275 cm; Width: 90 cm
3012427 | 06_Sixth Floor | Qto_OpeningElementBaseQuantities - Depth: 166 cm; Height: 275 cm; Width: 90 cm
3012427 | 06_Sixth Floor
3012428 | 06_Sixth Floor
3012471 | 06_Sixth Floor
3012472 | 06_Sixth Floor | Qto_OpeningElementBaseQuantities - Depth: 166 cm; Height: 275 cm; Width: 90 cm
3012473 | 06_Sixth Floor | Qto_OpeningElementBaseQuantities - Depth: 166 cm; Height: 275 cm; Width: 90 cm
3012473 | 06_Sixth Floor
3012474 | 06_Sixth Floor
3012521 | 06_Sixth Floor
3012522 | 06_Sixth Floor | Qto_OpeningElementBaseQuantities - Depth: 166 cm; Height: 275 cm; Width: 90 cm
3012523 | 06_Sixth Floor | Qto_OpeningElementBaseQuantities - Depth: 166 cm; Height: 275 cm; Width: 90 cm
3012523 | 06_Sixth Floor
3012524 | 06_Sixth Floor
3012567 | 06_Sixth Floor
3012568 | 06_Sixth Floor | Qto_OpeningElementBaseQuantities - Depth: 166 cm; Height: 275 cm; Width: 90 cm
3012569 | 06_Sixth Floor | Qto_OpeningElementBaseQuantities - Depth: 166 cm; Height: 275 cm; Width: 90 cm
3012569 | 06_Sixth Floor
3012570 | 06_Sixth Floor
3012613 | 06_Sixth Floor
3012614 | 06_Sixth Floor | Qto_OpeningElementBaseQuantities - Depth: 166 cm; Height: 275 cm; Width: 90 cm
3012615 | 06_Sixth Floor | Qto_OpeningElementBaseQuantities - Depth: 166 cm; Height: 275 cm; Width: 90 cm
3012615 | 06_Sixth Floor
3012616 | 06_Sixth Floor
3012659 | 06_Sixth Floor
3012660 | 06_Sixth Floor | Qto_OpeningElementBaseQuantities - Depth: 166 cm; Height: 275 cm; Width: 90 cm
3012661 | 06_Sixth Floor | Qto_OpeningElementBaseQuantities - Depth: 166 cm; Height: 275 cm; Width: 90 cm
3012661 | 06_Sixth Floor
3012662 | 06_Sixth Floor
3012705 | 06_Sixth Floor
3012706 | 06_Sixth Floor | Qto_OpeningElementBaseQuantities - Depth: 166 cm; Height: 275 cm; Width: 90 cm
3012707 | 06_Sixth Floor | Qto_OpeningElementBaseQuantities - Depth: 166 cm; Height: 275 cm; Width: 90 cm
3012707 | 06_Sixth Floor
3012708 | 06_Sixth Floor
3012752 | 06_Sixth Floor
3012753 | 06_Sixth Floor | Qto_OpeningElementBaseQuantities - Depth: 166 cm; Height: 275 cm; Width: 90 cm
3012754 | 06_Sixth Floor | Qto_OpeningElementBaseQuantities - Depth: 166 cm; Height: 275 cm; Width: 90 cm
3012754 | 06_Sixth Floor
3012755 | 06_Sixth Floor
3012798 | 06_Sixth Floor
3012799 | 06_Sixth Floor | Qto_OpeningElementBaseQuantities - Depth: 166 cm; Height: 275 cm; Width: 90 cm
3012800 | 06_Sixth Floor | Qto_OpeningElementBaseQuantities - Depth: 166 cm; Height: 275 cm; Width: 90 cm
3012800 | 06_Sixth Floor
3012801 | 06_Sixth Floor
3012848 | 06_Sixth Floor
3012849 | 06_Sixth Floor | Qto_OpeningElementBaseQuantities - Depth: 166 cm; Height: 275 cm; Width: 90 cm
3012850 | 06_Sixth Floor | Qto_OpeningElementBaseQuantities - Depth: 166 cm; Height: 275 cm; Width: 90 cm
3012850 | 06_Sixth Floor
3012851 | 06_Sixth Floor
3012894 | 06_Sixth Floor
3012895 | 06_Sixth Floor | Qto_OpeningElementBaseQuantities - Depth: 166 cm; Height: 275 cm; Width: 90 cm
3012896 | 06_Sixth Floor | Qto_OpeningElementBaseQuantities - Depth: 166 cm; Height: 275 cm; Width: 90 cm
3012896 | 06_Sixth Floor
3012897 | 06_Sixth Floor
3012940 | 06_Sixth Floor
3012941 | 06_Sixth Floor | Qto_OpeningElementBaseQuantities - Depth: 166 cm; Height: 275 cm; Width: 90 cm
3012942 | 06_Sixth Floor | Qto_OpeningElementBaseQuantities - Depth: 166 cm; Height: 275 cm; Width: 90 cm
3012942 | 06_Sixth Floor
3012943 | 06_Sixth Floor
3012986 | 06_Sixth Floor
3012987 | 06_Sixth Floor | Qto_OpeningElementBaseQuantities - Depth: 166 cm; Height: 275 cm; Width: 90 cm
3012988 | 06_Sixth Floor | Qto_OpeningElementBaseQuantities - Depth: 166 cm; Height: 275 cm; Width: 90 cm
3012988 | 06_Sixth Floor
3012989 | 06_Sixth Floor
3013032 | 06_Sixth Floor
3013033 | 06_Sixth Floor | Qto_OpeningElementBaseQuantities - Depth: 166 cm; Height: 275 cm; Width: 90 cm
3013034 | 06_Sixth Floor | Qto_OpeningElementBaseQuantities - Depth: 166 cm; Height: 275 cm; Width: 90 cm
3013034 | 06_Sixth Floor
3013035 | 06_Sixth Floor
3013079 | 06_Sixth Floor
3013080 | 06_Sixth Floor | Qto_OpeningElementBaseQuantities - Depth: 166 cm; Height: 275 cm; Width: 90 cm
3013081 | 06_Sixth Floor | Qto_OpeningElementBaseQuantities - Depth: 166 cm; Height: 275 cm; Width: 90 cm
3013081 | 06_Sixth Floor
3013082 | 06_Sixth Floor
3013125 | 06_Sixth Floor
3013126 | 06_Sixth Floor | Qto_OpeningElementBaseQuantities - Depth: 166 cm; Height: 275 cm; Width: 90 cm
3013127 | 06_Sixth Floor | Qto_OpeningElementBaseQuantities - Depth: 166 cm; Height: 275 cm; Width: 90 cm
3013127 | 06_Sixth Floor
3013128 | 06_Sixth Floor
3013175 | 06_Sixth Floor
3013176 | 06_Sixth Floor | Qto_OpeningElementBaseQuantities - Depth: 166 cm; Height: 275 cm; Width: 90 cm
3013177 | 06_Sixth Floor | Qto_OpeningElementBaseQuantities - Depth: 166 cm; Height: 275 cm; Width: 90 cm
3013177 | 06_Sixth Floor
3013178 | 06_Sixth Floor
3013221 | 06_Sixth Floor
3013222 | 06_Sixth Floor | Qto_OpeningElementBaseQuantities - Depth: 166 cm; Height: 275 cm; Width: 90 cm
3013223 | 06_Sixth Floor | Qto_OpeningElementBaseQuantities - Depth: 166 cm; Height: 275 cm; Width: 90 cm
3013223 | 06_Sixth Floor
3013224 | 06_Sixth Floor
3013267 | 06_Sixth Floor
3013268 | 06_Sixth Floor | Qto_OpeningElementBaseQuantities - Depth: 166 cm; Height: 275 cm; Width: 90 cm
3013269 | 06_Sixth Floor | Qto_OpeningElementBaseQuantities - Depth: 166 cm; Height: 275 cm; Width: 90 cm
3013269 | 06_Sixth Floor
3013270 | 06_Sixth Floor
3013313 | 06_Sixth Floor
3013314 | 06_Sixth Floor | Qto_OpeningElementBaseQuantities - Depth: 166 cm; Height: 275 cm; Width: 90 cm
3013315 | 06_Sixth Floor | Qto_OpeningElementBaseQuantities - Depth: 166 cm; Height: 275 cm; Width: 90 cm
3013315 | 06_Sixth Floor
3013316 | 06_Sixth Floor
3013359 | 06_Sixth Floor
3013360 | 06_Sixth Floor | Qto_OpeningElementBaseQuantities - Depth: 166 cm; Height: 275 cm; Width: 90 cm
3013361 | 06_Sixth Floor | Qto_OpeningElementBaseQuantities - Depth: 166 cm; Height: 275 cm; Width: 90 cm
3013361 | 06_Sixth Floor
3013362 | 06_Sixth Floor
3013406 | 06_Sixth Floor
3013407 | 06_Sixth Floor | Qto_OpeningElementBaseQuantities - Depth: 166 cm; Height: 275 cm; Width: 90 cm
3013408 | 06_Sixth Floor | Qto_OpeningElementBaseQuantities - Depth: 166 cm; Height: 275 cm; Width: 90 cm
3013408 | 06_Sixth Floor
3013409 | 06_Sixth Floor
3013452 | 06_Sixth Floor
3013453 | 06_Sixth Floor | Qto_OpeningElementBaseQuantities - Depth: 166 cm; Height: 275 cm; Width: 90 cm
3013454 | 06_Sixth Floor | Qto_OpeningElementBaseQuantities - Depth: 166 cm; Height: 275 cm; Width: 90 cm
3013454 | 06_Sixth Floor
3013455 | 06_Sixth Floor
3013502 | 06_Sixth Floor
3013503 | 06_Sixth Floor | Qto_OpeningElementBaseQuantities - Depth: 166 cm; Height: 275 cm; Width: 90 cm
3013504 | 06_Sixth Floor | Qto_OpeningElementBaseQuantities - Depth: 166 cm; Height: 275 cm; Width: 90 cm
3013504 | 06_Sixth Floor
3013505 | 06_Sixth Floor
3013548 | 06_Sixth Floor
3013549 | 06_Sixth Floor | Qto_OpeningElementBaseQuantities - Depth: 166 cm; Height: 275 cm; Width: 90 cm
3013550 | 06_Sixth Floor | Qto_OpeningElementBaseQuantities - Depth: 166 cm; Height: 275 cm; Width: 90 cm
3013550 | 06_Sixth Floor
3013551 | 06_Sixth Floor
3013594 | 06_Sixth Floor
3013595 | 06_Sixth Floor | Qto_OpeningElementBaseQuantities - Depth: 166 cm; Height: 275 cm; Width: 90 cm
3013596 | 06_Sixth Floor | Qto_OpeningElementBaseQuantities - Depth: 166 cm; Height: 275 cm; Width: 90 cm
3013596 | 06_Sixth Floor
3013597 | 06_Sixth Floor
3013640 | 06_Sixth Floor
3013641 | 06_Sixth Floor | Qto_OpeningElementBaseQuantities - Depth: 166 cm; Height: 275 cm; Width: 90 cm
3013642 | 06_Sixth Floor | Qto_OpeningElementBaseQuantities - Depth: 166 cm; Height: 275 cm; Width: 90 cm
3013642 | 06_Sixth Floor
3013643 | 06_Sixth Floor
3013686 | 06_Sixth Floor
3013687 | 06_Sixth Floor | Qto_OpeningElementBaseQuantities - Depth: 166 cm; Height: 275 cm; Width: 90 cm
3013688 | 06_Sixth Floor | Qto_OpeningElementBaseQuantities - Depth: 166 cm; Height: 275 cm; Width: 90 cm
3013688 | 06_Sixth Floor
3013689 | 06_Sixth Floor
3013733 | 06_Sixth Floor
3013734 | 06_Sixth Floor | Qto_OpeningElementBaseQuantities - Depth: 166 cm; Height: 275 cm; Width: 90 cm
3013735 | 06_Sixth Floor | Qto_OpeningElementBaseQuantities - Depth: 166 cm; Height: 275 cm; Width: 90 cm
3013735 | 06_Sixth Floor
3013736 | 06_Sixth Floor
3013779 | 06_Sixth Floor
3013780 | 06_Sixth Floor | Qto_OpeningElementBaseQuantities - Depth: 166 cm; Height: 275 cm; Width: 90 cm
3013781 | 06_Sixth Floor | Qto_OpeningElementBaseQuantities - Depth: 166 cm; Height: 275 cm; Width: 90 cm
3013781 | 06_Sixth Floor
3013782 | 06_Sixth Floor
3013829 | 06_Sixth Floor
3013830 | 06_Sixth Floor | Qto_OpeningElementBaseQuantities - Depth: 166 cm; Height: 275 cm; Width: 90 cm
3013831 | 06_Sixth Floor | Qto_OpeningElementBaseQuantities - Depth: 166 cm; Height: 275 cm; Width: 90 cm
3013831 | 06_Sixth Floor
3013832 | 06_Sixth Floor
3013875 | 06_Sixth Floor
3013876 | 06_Sixth Floor | Qto_OpeningElementBaseQuantities - Depth: 166 cm; Height: 275 cm; Width: 90 cm
3013877 | 06_Sixth Floor | Qto_OpeningElementBaseQuantities - Depth: 166 cm; Height: 275 cm; Width: 90 cm
3013877 | 06_Sixth Floor
3013878 | 06_Sixth Floor
3013921 | 06_Sixth Floor
3013922 | 06_Sixth Floor | Qto_OpeningElementBaseQuantities - Depth: 166 cm; Height: 275 cm; Width: 90 cm
3013923 | 06_Sixth Floor | Qto_OpeningElementBaseQuantities - Depth: 166 cm; Height: 275 cm; Width: 90 cm
3013923 | 06_Sixth Floor
3013924 | 06_Sixth Floor
3013967 | 06_Sixth Floor
3013968 | 06_Sixth Floor | Qto_OpeningElementBaseQuantities - Depth: 166 cm; Height: 275 cm; Width: 90 cm
3013969 | 06_Sixth Floor | Qto_OpeningElementBaseQuantities - Depth: 166 cm; Height: 275 cm; Width: 90 cm
3013969 | 06_Sixth Floor
3013970 | 06_Sixth Floor
3014013 | 06_Sixth Floor
3014014 | 06_Sixth Floor | Qto_OpeningElementBaseQuantities - Depth: 166 cm; Height: 275 cm; Width: 90 cm
3014015 | 06_Sixth Floor | Qto_OpeningElementBaseQuantities - Depth: 166 cm; Height: 275 cm; Width: 90 cm
3014015 | 06_Sixth Floor
3014016 | 06_Sixth Floor
3014620 | 07_Seventh Floor
3014621 | 07_Seventh Floor | Qto_OpeningElementBaseQuantities - Depth: 166 cm; Height: 275 cm; Width: 90 cm
3014622 | 07_Seventh Floor | Qto_OpeningElementBaseQuantities - Depth: 166 cm; Height: 275 cm; Width: 90 cm
3014622 | 07_Seventh Floor
3014623 | 07_Seventh Floor
3014666 | 07_Seventh Floor
3014667 | 07_Seventh Floor | Qto_OpeningElementBaseQuantities - Depth: 166 cm; Height: 275 cm; Width: 90 cm
3014668 | 07_Seventh Floor | Qto_OpeningElementBaseQuantities - Depth: 166 cm; Height: 275 cm; Width: 90 cm
3014668 | 07_Seventh Floor
3014669 | 07_Seventh Floor
3014716 | 07_Seventh Floor
3014717 | 07_Seventh Floor | Qto_OpeningElementBaseQuantities - Depth: 166 cm; Height: 275 cm; Width: 90 cm
3014718 | 07_Seventh Floor | Qto_OpeningElementBaseQuantities - Depth: 166 cm; Height: 275 cm; Width: 90 cm
3014718 | 07_Seventh Floor
3014719 | 07_Seventh Floor
3014762 | 07_Seventh Floor
3014763 | 07_Seventh Floor | Qto_OpeningElementBaseQuantities - Depth: 166 cm; Height: 275 cm; Width: 90 cm
3014764 | 07_Seventh Floor | Qto_OpeningElementBaseQuantities - Depth: 166 cm; Height: 275 cm; Width: 90 cm
3014764 | 07_Seventh Floor
3014765 | 07_Seventh Floor
3014808 | 07_Seventh Floor
3014809 | 07_Seventh Floor | Qto_OpeningElementBaseQuantities - Depth: 166 cm; Height: 275 cm; Width: 90 cm
3014810 | 07_Seventh Floor | Qto_OpeningElementBaseQuantities - Depth: 166 cm; Height: 275 cm; Width: 90 cm
3014810 | 07_Seventh Floor
3014811 | 07_Seventh Floor
3014854 | 07_Seventh Floor
3014855 | 07_Seventh Floor | Qto_OpeningElementBaseQuantities - Depth: 166 cm; Height: 275 cm; Width: 90 cm
3014856 | 07_Seventh Floor | Qto_OpeningElementBaseQuantities - Depth: 166 cm; Height: 275 cm; Width: 90 cm
3014856 | 07_Seventh Floor
3014857 | 07_Seventh Floor
3014900 | 07_Seventh Floor
3014901 | 07_Seventh Floor | Qto_OpeningElementBaseQuantities - Depth: 166 cm; Height: 275 cm; Width: 90 cm
3014902 | 07_Seventh Floor | Qto_OpeningElementBaseQuantities - Depth: 166 cm; Height: 275 cm; Width: 90 cm
3014902 | 07_Seventh Floor
3014903 | 07_Seventh Floor
3014947 | 07_Seventh Floor
3014948 | 07_Seventh Floor | Qto_OpeningElementBaseQuantities - Depth: 166 cm; Height: 275 cm; Width: 90 cm
3014949 | 07_Seventh Floor | Qto_OpeningElementBaseQuantities - Depth: 166 cm; Height: 275 cm; Width: 90 cm
3014949 | 07_Seventh Floor
3014950 | 07_Seventh Floor
3014993 | 07_Seventh Floor
3014994 | 07_Seventh Floor | Qto_OpeningElementBaseQuantities - Depth: 166 cm; Height: 275 cm; Width: 90 cm
3014995 | 07_Seventh Floor | Qto_OpeningElementBaseQuantities - Depth: 166 cm; Height: 275 cm; Width: 90 cm
3014995 | 07_Seventh Floor
3014996 | 07_Seventh Floor
3015043 | 07_Seventh Floor
3015044 | 07_Seventh Floor | Qto_OpeningElementBaseQuantities - Depth: 166 cm; Height: 275 cm; Width: 90 cm
3015045 | 07_Seventh Floor | Qto_OpeningElementBaseQuantities - Depth: 166 cm; Height: 275 cm; Width: 90 cm
3015045 | 07_Seventh Floor
3015046 | 07_Seventh Floor
3015089 | 07_Seventh Floor
3015090 | 07_Seventh Floor | Qto_OpeningElementBaseQuantities - Depth: 166 cm; Height: 275 cm; Width: 90 cm
3015091 | 07_Seventh Floor | Qto_OpeningElementBaseQuantities - Depth: 166 cm; Height: 275 cm; Width: 90 cm
3015091 | 07_Seventh Floor
3015092 | 07_Seventh Floor
3015135 | 07_Seventh Floor
3015136 | 07_Seventh Floor | Qto_OpeningElementBaseQuantities - Depth: 166 cm; Height: 275 cm; Width: 90 cm
3015137 | 07_Seventh Floor | Qto_OpeningElementBaseQuantities - Depth: 166 cm; Height: 275 cm; Width: 90 cm
3015137 | 07_Seventh Floor
3015138 | 07_Seventh Floor
3015181 | 07_Seventh Floor
3015182 | 07_Seventh Floor | Qto_OpeningElementBaseQuantities - Depth: 166 cm; Height: 275 cm; Width: 90 cm
3015183 | 07_Seventh Floor | Qto_OpeningElementBaseQuantities - Depth: 166 cm; Height: 275 cm; Width: 90 cm
3015183 | 07_Seventh Floor
3015184 | 07_Seventh Floor
3015227 | 07_Seventh Floor
3015228 | 07_Seventh Floor | Qto_OpeningElementBaseQuantities - Depth: 166 cm; Height: 275 cm; Width: 90 cm
3015229 | 07_Seventh Floor | Qto_OpeningElementBaseQuantities - Depth: 166 cm; Height: 275 cm; Width: 90 cm
3015229 | 07_Seventh Floor
3015230 | 07_Seventh Floor
3015274 | 07_Seventh Floor
3015275 | 07_Seventh Floor | Qto_OpeningElementBaseQuantities - Depth: 166 cm; Height: 275 cm; Width: 90 cm
3015276 | 07_Seventh Floor | Qto_OpeningElementBaseQuantities - Depth: 166 cm; Height: 275 cm; Width: 90 cm
3015276 | 07_Seventh Floor
3015277 | 07_Seventh Floor
3015320 | 07_Seventh Floor
3015321 | 07_Seventh Floor | Qto_OpeningElementBaseQuantities - Depth: 166 cm; Height: 275 cm; Width: 90 cm
3015322 | 07_Seventh Floor | Qto_OpeningElementBaseQuantities - Depth: 166 cm; Height: 275 cm; Width: 90 cm
3015322 | 07_Seventh Floor
3015323 | 07_Seventh Floor
3015370 | 07_Seventh Floor
3015371 | 07_Seventh Floor | Qto_OpeningElementBaseQuantities - Depth: 166 cm; Height: 275 cm; Width: 90 cm
3015372 | 07_Seventh Floor | Qto_OpeningElementBaseQuantities - Depth: 166 cm; Height: 275 cm; Width: 90 cm
3015372 | 07_Seventh Floor
3015373 | 07_Seventh Floor
3015416 | 07_Seventh Floor
3015417 | 07_Seventh Floor | Qto_OpeningElementBaseQuantities - Depth: 166 cm; Height: 275 cm; Width: 90 cm
3015418 | 07_Seventh Floor | Qto_OpeningElementBaseQuantities - Depth: 166 cm; Height: 275 cm; Width: 90 cm
3015418 | 07_Seventh Floor
3015419 | 07_Seventh Floor
3015462 | 07_Seventh Floor
3015463 | 07_Seventh Floor | Qto_OpeningElementBaseQuantities - Depth: 166 cm; Height: 275 cm; Width: 90 cm
3015464 | 07_Seventh Floor | Qto_OpeningElementBaseQuantities - Depth: 166 cm; Height: 275 cm; Width: 90 cm
3015464 | 07_Seventh Floor
3015465 | 07_Seventh Floor
3015508 | 07_Seventh Floor
3015509 | 07_Seventh Floor | Qto_OpeningElementBaseQuantities - Depth: 166 cm; Height: 275 cm; Width: 90 cm
3015510 | 07_Seventh Floor | Qto_OpeningElementBaseQuantities - Depth: 166 cm; Height: 275 cm; Width: 90 cm
3015510 | 07_Seventh Floor
3015511 | 07_Seventh Floor
3015554 | 07_Seventh Floor
3015555 | 07_Seventh Floor | Qto_OpeningElementBaseQuantities - Depth: 166 cm; Height: 275 cm; Width: 90 cm
3015556 | 07_Seventh Floor | Qto_OpeningElementBaseQuantities - Depth: 166 cm; Height: 275 cm; Width: 90 cm
3015556 | 07_Seventh Floor
3015557 | 07_Seventh Floor
3015601 | 07_Seventh Floor
3015602 | 07_Seventh Floor | Qto_OpeningElementBaseQuantities - Depth: 166 cm; Height: 275 cm; Width: 90 cm
3015603 | 07_Seventh Floor | Qto_OpeningElementBaseQuantities - Depth: 166 cm; Height: 275 cm; Width: 90 cm
3015603 | 07_Seventh Floor
3015604 | 07_Seventh Floor
3015647 | 07_Seventh Floor
3015648 | 07_Seventh Floor | Qto_OpeningElementBaseQuantities - Depth: 166 cm; Height: 275 cm; Width: 90 cm
3015649 | 07_Seventh Floor | Qto_OpeningElementBaseQuantities - Depth: 166 cm; Height: 275 cm; Width: 90 cm
3015649 | 07_Seventh Floor
3015650 | 07_Seventh Floor
3015697 | 07_Seventh Floor
3015698 | 07_Seventh Floor | Qto_OpeningElementBaseQuantities - Depth: 166 cm; Height: 275 cm; Width: 90 cm
3015699 | 07_Seventh Floor | Qto_OpeningElementBaseQuantities - Depth: 166 cm; Height: 275 cm; Width: 90 cm
3015699 | 07_Seventh Floor
3015700 | 07_Seventh Floor
3015743 | 07_Seventh Floor
3015744 | 07_Seventh Floor | Qto_OpeningElementBaseQuantities - Depth: 166 cm; Height: 275 cm; Width: 90 cm
3015745 | 07_Seventh Floor | Qto_OpeningElementBaseQuantities - Depth: 166 cm; Height: 275 cm; Width: 90 cm
3015745 | 07_Seventh Floor
3015746 | 07_Seventh Floor
3015789 | 07_Seventh Floor
3015790 | 07_Seventh Floor | Qto_OpeningElementBaseQuantities - Depth: 166 cm; Height: 275 cm; Width: 90 cm
3015791 | 07_Seventh Floor | Qto_OpeningElementBaseQuantities - Depth: 166 cm; Height: 275 cm; Width: 90 cm
3015791 | 07_Seventh Floor
3015792 | 07_Seventh Floor
3015835 | 07_Seventh Floor
3015836 | 07_Seventh Floor | Qto_OpeningElementBaseQuantities - Depth: 166 cm; Height: 275 cm; Width: 90 cm
3015837 | 07_Seventh Floor | Qto_OpeningElementBaseQuantities - Depth: 166 cm; Height: 275 cm; Width: 90 cm
3015837 | 07_Seventh Floor
3015838 | 07_Seventh Floor
3015881 | 07_Seventh Floor
3015882 | 07_Seventh Floor | Qto_OpeningElementBaseQuantities - Depth: 166 cm; Height: 275 cm; Width: 90 cm
3015883 | 07_Seventh Floor | Qto_OpeningElementBaseQuantities - Depth: 166 cm; Height: 275 cm; Width: 90 cm
3015883 | 07_Seventh Floor
3015884 | 07_Seventh Floor
3015928 | 07_Seventh Floor
3015929 | 07_Seventh Floor | Qto_OpeningElementBaseQuantities - Depth: 166 cm; Height: 275 cm; Width: 90 cm
3015930 | 07_Seventh Floor | Qto_OpeningElementBaseQuantities - Depth: 166 cm; Height: 275 cm; Width: 90 cm
3015930 | 07_Seventh Floor
3015931 | 07_Seventh Floor
3015974 | 07_Seventh Floor
3015975 | 07_Seventh Floor | Qto_OpeningElementBaseQuantities - Depth: 166 cm; Height: 275 cm; Width: 90 cm
3015976 | 07_Seventh Floor | Qto_OpeningElementBaseQuantities - Depth: 166 cm; Height: 275 cm; Width: 90 cm
3015976 | 07_Seventh Floor
3015977 | 07_Seventh Floor
3016024 | 07_Seventh Floor
3016025 | 07_Seventh Floor | Qto_OpeningElementBaseQuantities - Depth: 166 cm; Height: 275 cm; Width: 90 cm
3016026 | 07_Seventh Floor | Qto_OpeningElementBaseQuantities - Depth: 166 cm; Height: 275 cm; Width: 90 cm
3016026 | 07_Seventh Floor
3016027 | 07_Seventh Floor
3016070 | 07_Seventh Floor
3016071 | 07_Seventh Floor | Qto_OpeningElementBaseQuantities - Depth: 166 cm; Height: 275 cm; Width: 90 cm
3016072 | 07_Seventh Floor | Qto_OpeningElementBaseQuantities - Depth: 166 cm; Height: 275 cm; Width: 90 cm
3016072 | 07_Seventh Floor
3016073 | 07_Seventh Floor
3016116 | 07_Seventh Floor
3016117 | 07_Seventh Floor | Qto_OpeningElementBaseQuantities - Depth: 166 cm; Height: 275 cm; Width: 90 cm
3016118 | 07_Seventh Floor | Qto_OpeningElementBaseQuantities - Depth: 166 cm; Height: 275 cm; Width: 90 cm
3016118 | 07_Seventh Floor
3016119 | 07_Seventh Floor
3016162 | 07_Seventh Floor
3016163 | 07_Seventh Floor | Qto_OpeningElementBaseQuantities - Depth: 166 cm; Height: 275 cm; Width: 90 cm
3016164 | 07_Seventh Floor | Qto_OpeningElementBaseQuantities - Depth: 166 cm; Height: 275 cm; Width: 90 cm
3016164 | 07_Seventh Floor
3016165 | 07_Seventh Floor
3016208 | 07_Seventh Floor
3016209 | 07_Seventh Floor | Qto_OpeningElementBaseQuantities - Depth: 166 cm; Height: 275 cm; Width: 90 cm
3016210 | 07_Seventh Floor | Qto_OpeningElementBaseQuantities - Depth: 166 cm; Height: 275 cm; Width: 90 cm
3016210 | 07_Seventh Floor
3016211 | 07_Seventh Floor

# IfcPipeSegment: Pipe Types:Piping Aluminum (1400)
Pset_EnvironmentalImpactIndicators - Reference: Piping Aluminum; sets with these values: 2
Qto_PipeSegmentBaseQuantities - GrossCrossSectionArea: 0.00182894 m2; NetCrossSectionArea: 0.00182894 m2
Name (Pipe Types:Piping Aluminum:...) | In | InvertElevation (cm) | Length (cm) | OuterSurfaceArea (m2)
2980486 | 00_Ground Floor | 128 | 112.9 | 0.171171 | Group: Domestic Hot Water 1
2980589 | 00_Ground Floor | 239.955 | 79.9033 | 0.121144
2994089 | 00_Ground Floor | 239.955 | 25.4352 | 0.0385631
2994139 | 00_Ground Floor | 239.955 | 208.8 | 0.316568
2994246 | 00_Ground Floor | 244.1 | 27.9 | 0.0423001 | Group: Domestic Hot Water 1
2995772 | 00_Ground Floor | 128 | 112.9 | 0.171171 | Group: Domestic Hot Water 2
2995774 | 00_Ground Floor | 239.955 | 79.9033 | 0.121144
2995776 | 00_Ground Floor | 239.955 | 25.4352 | 0.0385631
2995782 | 00_Ground Floor | 239.955 | 208.8 | 0.316568
2995786 | 00_Ground Floor | 244.1 | 27.9 | 0.0423001 | Group: Domestic Hot Water 2
2995881 | 00_Ground Floor | 128 | 112.9 | 0.171171 | Group: Domestic Hot Water 4
2995883 | 00_Ground Floor | 239.955 | 79.9033 | 0.121144
2995885 | 00_Ground Floor | 239.955 | 25.4352 | 0.0385631
2995891 | 00_Ground Floor | 239.955 | 208.8 | 0.316568
2995895 | 00_Ground Floor | 244.1 | 27.9 | 0.0423001 | Group: Domestic Hot Water 4
2995940 | 00_Ground Floor | 128 | 112.9 | 0.171171 | Group: Domestic Hot Water 6
2995942 | 00_Ground Floor | 239.955 | 79.9033 | 0.121144
2995944 | 00_Ground Floor | 239.955 | 25.4352 | 0.0385631
2995950 | 00_Ground Floor | 239.955 | 208.8 | 0.316568
2995954 | 00_Ground Floor | 244.1 | 27.9 | 0.0423001 | Group: Domestic Hot Water 6
2995999 | 00_Ground Floor | 128 | 112.9 | 0.171171 | Group: Domestic Hot Water 8
2996001 | 00_Ground Floor | 239.955 | 79.9033 | 0.121144
2996003 | 00_Ground Floor | 239.955 | 25.4352 | 0.0385631
2996009 | 00_Ground Floor | 239.955 | 208.8 | 0.316568
2996013 | 00_Ground Floor | 244.1 | 27.9 | 0.0423001 | Group: Domestic Hot Water 8
2996058 | 00_Ground Floor | 128 | 112.9 | 0.171171 | Group: Domestic Hot Water 10
2996060 | 00_Ground Floor | 239.955 | 79.9033 | 0.121144
2996062 | 00_Ground Floor | 239.955 | 25.4352 | 0.0385631
2996068 | 00_Ground Floor | 239.955 | 208.8 | 0.316568
2996072 | 00_Ground Floor | 244.1 | 27.9 | 0.0423001 | Group: Domestic Hot Water 10
2996117 | 00_Ground Floor | 128 | 112.9 | 0.171171 | Group: Domestic Hot Water 12
2996119 | 00_Ground Floor | 239.955 | 79.9033 | 0.121144
2996121 | 00_Ground Floor | 239.955 | 25.4352 | 0.0385631
2996127 | 00_Ground Floor | 239.955 | 208.8 | 0.316568
2996131 | 00_Ground Floor | 244.1 | 27.9 | 0.0423001 | Group: Domestic Hot Water 12
2996184 | 00_Ground Floor | 128 | 112.9 | 0.171171 | Group: Domestic Hot Water 3
2996186 | 00_Ground Floor | 239.955 | 79.9033 | 0.121144
2996188 | 00_Ground Floor | 239.955 | 25.4352 | 0.0385631
2996194 | 00_Ground Floor | 239.955 | 208.8 | 0.316568
2996198 | 00_Ground Floor | 244.1 | 27.9 | 0.0423001 | Group: Domestic Hot Water 3
2996239 | 00_Ground Floor | 128 | 112.9 | 0.171171 | Group: Domestic Hot Water 7
2996241 | 00_Ground Floor | 239.955 | 79.9033 | 0.121144
2996243 | 00_Ground Floor | 239.955 | 25.4352 | 0.0385631
2996249 | 00_Ground Floor | 239.955 | 208.8 | 0.316568
2996253 | 00_Ground Floor | 244.1 | 27.9 | 0.0423001 | Group: Domestic Hot Water 7
2996298 | 00_Ground Floor | 128 | 112.9 | 0.171171 | Group: Domestic Hot Water 11
2996300 | 00_Ground Floor | 239.955 | 79.9033 | 0.121144
2996302 | 00_Ground Floor | 239.955 | 25.4352 | 0.0385631
2996308 | 00_Ground Floor | 239.955 | 208.8 | 0.316568
2996312 | 00_Ground Floor | 244.1 | 27.9 | 0.0423001 | Group: Domestic Hot Water 11
2996353 | 00_Ground Floor | 128 | 112.9 | 0.171171 | Group: Domestic Hot Water 14
2996355 | 00_Ground Floor | 239.955 | 79.9033 | 0.121144
2996357 | 00_Ground Floor | 239.955 | 25.4352 | 0.0385631
2996363 | 00_Ground Floor | 239.955 | 208.8 | 0.316568
2996367 | 00_Ground Floor | 244.1 | 27.9 | 0.0423001 | Group: Domestic Hot Water 14
2996408 | 00_Ground Floor | 128 | 112.9 | 0.171171 | Group: Domestic Hot Water 16
2996410 | 00_Ground Floor | 239.955 | 79.9033 | 0.121144
2996412 | 00_Ground Floor | 239.955 | 25.4352 | 0.0385631
2996418 | 00_Ground Floor | 239.955 | 208.8 | 0.316568
2996422 | 00_Ground Floor | 244.1 | 27.9 | 0.0423001 | Group: Domestic Hot Water 16
2996463 | 00_Ground Floor | 128 | 112.9 | 0.171171 | Group: Domestic Hot Water 18
2996465 | 00_Ground Floor | 239.955 | 79.9033 | 0.121144
2996467 | 00_Ground Floor | 239.955 | 25.4352 | 0.0385631
2996473 | 00_Ground Floor | 239.955 | 208.8 | 0.316568
2996477 | 00_Ground Floor | 244.1 | 27.9 | 0.0423001 | Group: Domestic Hot Water 18
2996518 | 00_Ground Floor | 128 | 112.9 | 0.171171 | Group: Domestic Hot Water 20
2996520 | 00_Ground Floor | 239.955 | 79.9033 | 0.121144
2996522 | 00_Ground Floor | 239.955 | 25.4352 | 0.0385631
2996528 | 00_Ground Floor | 239.955 | 208.8 | 0.316568
2996532 | 00_Ground Floor | 244.1 | 27.9 | 0.0423001 | Group: Domestic Hot Water 20
2996628 | 00_Ground Floor | 128 | 112.9 | 0.171171 | Group: Domestic Hot Water 22
2996630 | 00_Ground Floor | 239.955 | 79.9033 | 0.121144
2996632 | 00_Ground Floor | 239.955 | 25.4352 | 0.0385631
2996638 | 00_Ground Floor | 239.955 | 208.8 | 0.316568
2996642 | 00_Ground Floor | 244.1 | 27.9 | 0.0423001 | Group: Domestic Hot Water 22
2996683 | 00_Ground Floor | 128 | 112.9 | 0.171171 | Group: Domestic Hot Water 24
2996685 | 00_Ground Floor | 239.955 | 79.9033 | 0.121144
2996687 | 00_Ground Floor | 239.955 | 25.4352 | 0.0385631
2996693 | 00_Ground Floor | 239.955 | 208.8 | 0.316568
2996697 | 00_Ground Floor | 244.1 | 27.9 | 0.0423001 | Group: Domestic Hot Water 24
2996742 | 00_Ground Floor | 128 | 112.9 | 0.171171 | Group: Domestic Hot Water 26
2996744 | 00_Ground Floor | 239.955 | 79.9033 | 0.121144
2996746 | 00_Ground Floor | 239.955 | 25.4352 | 0.0385631
2996752 | 00_Ground Floor | 239.955 | 208.8 | 0.316568
2996756 | 00_Ground Floor | 244.1 | 27.9 | 0.0423001 | Group: Domestic Hot Water 26
2996797 | 00_Ground Floor | 128 | 112.9 | 0.171171 | Group: Domestic Hot Water 28
2996799 | 00_Ground Floor | 239.955 | 79.9033 | 0.121144
2996801 | 00_Ground Floor | 239.955 | 25.4352 | 0.0385631
2996807 | 00_Ground Floor | 239.955 | 208.8 | 0.316568
2996811 | 00_Ground Floor | 244.1 | 27.9 | 0.0423001 | Group: Domestic Hot Water 28
2996852 | 00_Ground Floor | 128 | 112.9 | 0.171171 | Group: Domestic Hot Water 30
2996854 | 00_Ground Floor | 239.955 | 79.9033 | 0.121144
2996856 | 00_Ground Floor | 239.955 | 25.4352 | 0.0385631
2996862 | 00_Ground Floor | 239.955 | 208.8 | 0.316568
2996866 | 00_Ground Floor | 244.1 | 27.9 | 0.0423001 | Group: Domestic Hot Water 30
2996907 | 00_Ground Floor | 128 | 112.9 | 0.171171 | Group: Domestic Hot Water 32
2996909 | 00_Ground Floor | 239.955 | 79.9033 | 0.121144
2996911 | 00_Ground Floor | 239.955 | 25.4352 | 0.0385631
2996917 | 00_Ground Floor | 239.955 | 208.8 | 0.316568
2996921 | 00_Ground Floor | 244.1 | 27.9 | 0.0423001 | Group: Domestic Hot Water 32
2996962 | 00_Ground Floor | 128 | 112.9 | 0.171171 | Group: Domestic Hot Water 34
2996964 | 00_Ground Floor | 239.955 | 79.9033 | 0.121144
2996966 | 00_Ground Floor | 239.955 | 25.4352 | 0.0385631
2996972 | 00_Ground Floor | 239.955 | 208.8 | 0.316568
2996976 | 00_Ground Floor | 244.1 | 27.9 | 0.0423001 | Group: Domestic Hot Water 34
2997034 | 00_Ground Floor | 128 | 112.9 | 0.171171 | Group: Domestic Hot Water 36
2997036 | 00_Ground Floor | 239.955 | 79.9033 | 0.121144
2997038 | 00_Ground Floor | 239.955 | 25.4352 | 0.0385631
2997044 | 00_Ground Floor | 239.955 | 208.8 | 0.316568
2997048 | 00_Ground Floor | 244.1 | 27.9 | 0.0423001 | Group: Domestic Hot Water 36
2997089 | 00_Ground Floor | 128 | 112.9 | 0.171171 | Group: Domestic Hot Water 38
2997091 | 00_Ground Floor | 239.955 | 79.9033 | 0.121144
2997093 | 00_Ground Floor | 239.955 | 25.4352 | 0.0385631
2997099 | 00_Ground Floor | 239.955 | 208.8 | 0.316568
2997103 | 00_Ground Floor | 244.1 | 27.9 | 0.0423001 | Group: Domestic Hot Water 38
2997148 | 00_Ground Floor | 128 | 112.9 | 0.171171 | Group: Domestic Hot Water 40
2997150 | 00_Ground Floor | 239.955 | 79.9033 | 0.121144
2997152 | 00_Ground Floor | 239.955 | 25.4352 | 0.0385631
2997158 | 00_Ground Floor | 239.955 | 208.8 | 0.316568
2997162 | 00_Ground Floor | 244.1 | 27.9 | 0.0423001 | Group: Domestic Hot Water 40
2997203 | 00_Ground Floor | 128 | 112.9 | 0.171171 | Group: Domestic Hot Water 42
2997205 | 00_Ground Floor | 239.955 | 79.9033 | 0.121144
2997207 | 00_Ground Floor | 239.955 | 25.4352 | 0.0385631
2997213 | 00_Ground Floor | 239.955 | 208.8 | 0.316568
2997217 | 00_Ground Floor | 244.1 | 27.9 | 0.0423001 | Group: Domestic Hot Water 42
2997258 | 00_Ground Floor | 128 | 112.9 | 0.171171 | Group: Domestic Hot Water 44
2997260 | 00_Ground Floor | 239.955 | 79.9033 | 0.121144
2997262 | 00_Ground Floor | 239.955 | 25.4352 | 0.0385631
2997268 | 00_Ground Floor | 239.955 | 208.8 | 0.316568
2997272 | 00_Ground Floor | 244.1 | 27.9 | 0.0423001 | Group: Domestic Hot Water 44
2997313 | 00_Ground Floor | 128 | 112.9 | 0.171171 | Group: Domestic Hot Water 46
2997315 | 00_Ground Floor | 239.955 | 79.9033 | 0.121144
2997317 | 00_Ground Floor | 239.955 | 25.4352 | 0.0385631
2997323 | 00_Ground Floor | 239.955 | 208.8 | 0.316568
2997327 | 00_Ground Floor | 244.1 | 27.9 | 0.0423001 | Group: Domestic Hot Water 46
2997368 | 00_Ground Floor | 128 | 112.9 | 0.171171 | Group: Domestic Hot Water 48
2997370 | 00_Ground Floor | 239.955 | 79.9033 | 0.121144
2997372 | 00_Ground Floor | 239.955 | 25.4352 | 0.0385631
2997378 | 00_Ground Floor | 239.955 | 208.8 | 0.316568
2997382 | 00_Ground Floor | 244.1 | 27.9 | 0.0423001 | Group: Domestic Hot Water 48
2997440 | 00_Ground Floor | 130 | 112.9 | 0.171171 | Group: Domestic Hot Water 50
2997442 | 00_Ground Floor | 239.955 | 79.9033 | 0.121144
2997444 | 00_Ground Floor | 239.955 | 25.4352 | 0.0385631
2997450 | 00_Ground Floor | 239.955 | 208.8 | 0.316568
2997454 | 00_Ground Floor | 244.1 | 27.9 | 0.0423001 | Group: Domestic Hot Water 50
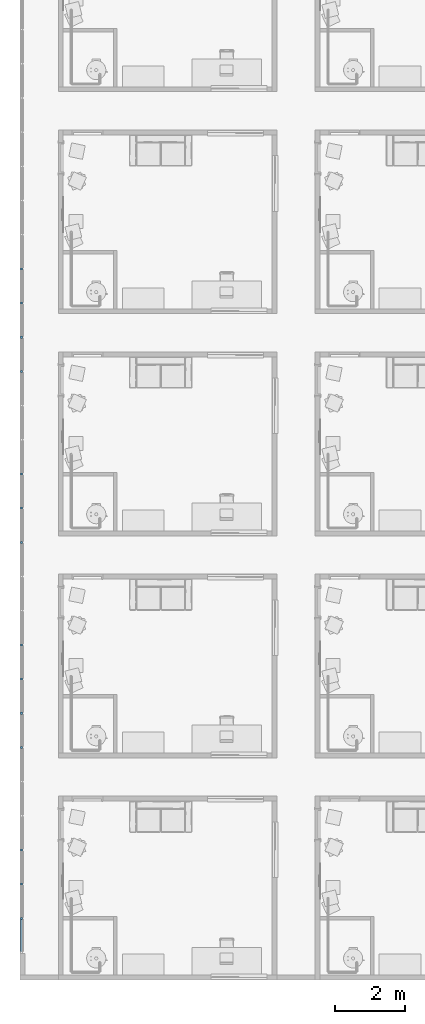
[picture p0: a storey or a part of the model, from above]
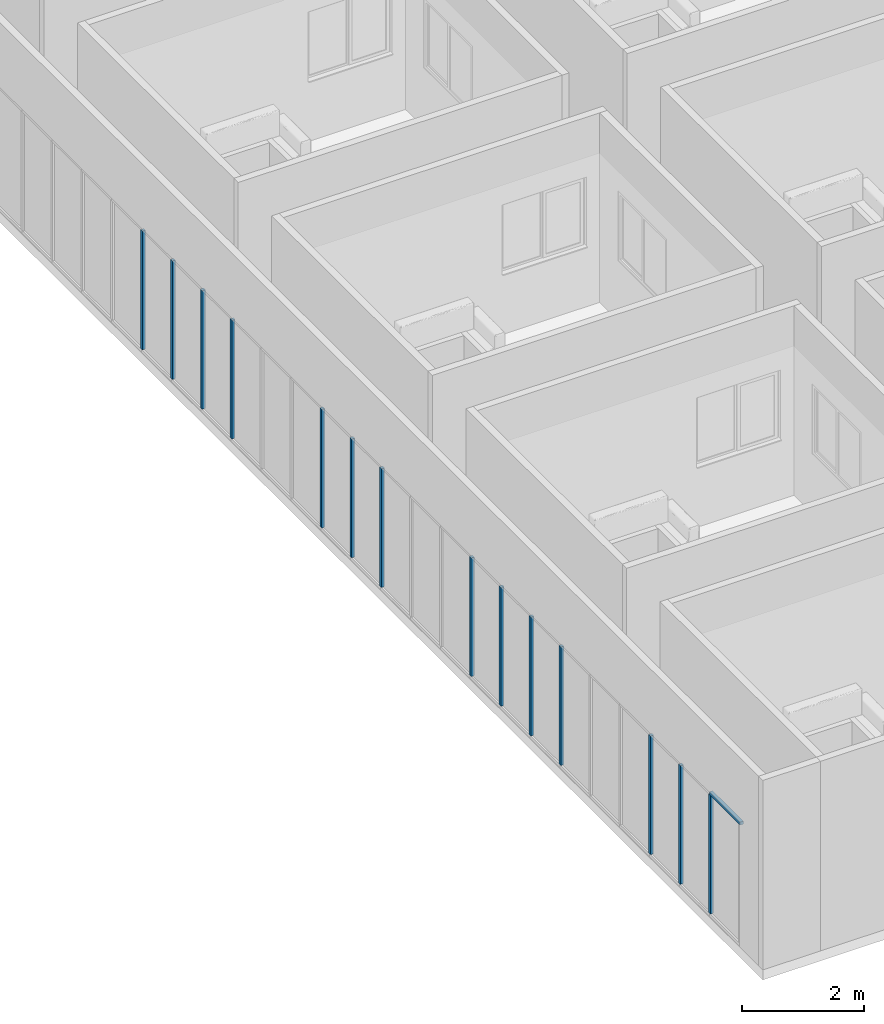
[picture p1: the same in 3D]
Properties of the parts of a building model (IFC4), part 10 of 14

# IfcPipeSegment: Pipe Types:Piping Aluminum (1400)
Name (Pipe Types:Piping Aluminum:...) | In | InvertElevation (cm) | Length (cm) | OuterSurfaceArea (m2)
2997495 | 00_Ground Floor | 128 | 112.9 | 0.171171 | Group: Domestic Hot Water 52
2997497 | 00_Ground Floor | 239.955 | 79.9033 | 0.121144
2997499 | 00_Ground Floor | 239.955 | 25.4352 | 0.0385631
2997505 | 00_Ground Floor | 239.955 | 208.8 | 0.316568
2997509 | 00_Ground Floor | 244.1 | 27.9 | 0.0423001 | Group: Domestic Hot Water 52
2997554 | 00_Ground Floor | 128 | 112.9 | 0.171171 | Group: Domestic Hot Water 54
2997556 | 00_Ground Floor | 239.955 | 79.9033 | 0.121144
2997558 | 00_Ground Floor | 239.955 | 25.4352 | 0.0385631
2997564 | 00_Ground Floor | 239.955 | 208.8 | 0.316568
2997568 | 00_Ground Floor | 244.1 | 27.9 | 0.0423001 | Group: Domestic Hot Water 54
2997609 | 00_Ground Floor | 128 | 112.9 | 0.171171 | Group: Domestic Hot Water 56
2997611 | 00_Ground Floor | 239.955 | 79.9033 | 0.121144
2997613 | 00_Ground Floor | 239.955 | 25.4352 | 0.0385631
2997619 | 00_Ground Floor | 239.955 | 208.8 | 0.316568
2997623 | 00_Ground Floor | 244.1 | 27.9 | 0.0423001 | Group: Domestic Hot Water 56
2997664 | 00_Ground Floor | 128 | 112.9 | 0.171171 | Group: Domestic Hot Water 58
2997666 | 00_Ground Floor | 239.955 | 79.9033 | 0.121144
2997668 | 00_Ground Floor | 239.955 | 25.4352 | 0.0385631
2997674 | 00_Ground Floor | 239.955 | 208.8 | 0.316568
2997678 | 00_Ground Floor | 244.1 | 27.9 | 0.0423001 | Group: Domestic Hot Water 58
2997719 | 00_Ground Floor | 128 | 112.9 | 0.171171 | Group: Domestic Hot Water 60
2997721 | 00_Ground Floor | 239.955 | 79.9033 | 0.121144
2997723 | 00_Ground Floor | 239.955 | 25.4352 | 0.0385631
2997729 | 00_Ground Floor | 239.955 | 208.8 | 0.316568
2997733 | 00_Ground Floor | 244.1 | 27.9 | 0.0423001 | Group: Domestic Hot Water 60
2997774 | 00_Ground Floor | 128 | 112.9 | 0.171171 | Group: Domestic Hot Water 62
2997776 | 00_Ground Floor | 239.955 | 79.9033 | 0.121144
2997778 | 00_Ground Floor | 239.955 | 25.4352 | 0.0385631
2997784 | 00_Ground Floor | 239.955 | 208.8 | 0.316568
2997788 | 00_Ground Floor | 244.1 | 27.9 | 0.0423001 | Group: Domestic Hot Water 62
3001465 | 01_First Floor | 528 | 112.9 | 0.171171 | Group: Domestic Hot Water 5
3001467 | 01_First Floor | 639.955 | 79.9033 | 0.121144
3001469 | 01_First Floor | 639.955 | 25.4352 | 0.0385631
3001475 | 01_First Floor | 639.955 | 208.8 | 0.316568
3001479 | 01_First Floor | 644.1 | 27.9 | 0.0423001 | Group: Domestic Hot Water 5
3001512 | 01_First Floor | 528 | 112.9 | 0.171171 | Group: Domestic Hot Water 13
3001514 | 01_First Floor | 639.955 | 79.9033 | 0.121144
3001516 | 01_First Floor | 639.955 | 25.4352 | 0.0385631
3001522 | 01_First Floor | 639.955 | 208.8 | 0.316568
3001526 | 01_First Floor | 644.1 | 27.9 | 0.0423001 | Group: Domestic Hot Water 13
3001563 | 01_First Floor | 528 | 112.9 | 0.171171 | Group: Domestic Hot Water 17
3001565 | 01_First Floor | 639.955 | 79.9033 | 0.121144
3001567 | 01_First Floor | 639.955 | 25.4352 | 0.0385631
3001573 | 01_First Floor | 639.955 | 208.8 | 0.316568
3001577 | 01_First Floor | 644.1 | 27.9 | 0.0423001 | Group: Domestic Hot Water 17
3001610 | 01_First Floor | 528 | 112.9 | 0.171171 | Group: Domestic Hot Water 21
3001612 | 01_First Floor | 639.955 | 79.9033 | 0.121144
3001614 | 01_First Floor | 639.955 | 25.4352 | 0.0385631
3001620 | 01_First Floor | 639.955 | 208.8 | 0.316568
3001624 | 01_First Floor | 644.1 | 27.9 | 0.0423001 | Group: Domestic Hot Water 21
3001657 | 01_First Floor | 528 | 112.9 | 0.171171 | Group: Domestic Hot Water 25
3001659 | 01_First Floor | 639.955 | 79.9033 | 0.121144
3001661 | 01_First Floor | 639.955 | 25.4352 | 0.0385631
3001667 | 01_First Floor | 639.955 | 208.8 | 0.316568
3001671 | 01_First Floor | 644.1 | 27.9 | 0.0423001 | Group: Domestic Hot Water 25
3001704 | 01_First Floor | 528 | 112.9 | 0.171171 | Group: Domestic Hot Water 29
3001706 | 01_First Floor | 639.955 | 79.9033 | 0.121144
3001708 | 01_First Floor | 639.955 | 25.4352 | 0.0385631
3001714 | 01_First Floor | 639.955 | 208.8 | 0.316568
3001718 | 01_First Floor | 644.1 | 27.9 | 0.0423001 | Group: Domestic Hot Water 29
3001751 | 01_First Floor | 528 | 112.9 | 0.171171 | Group: Domestic Hot Water 33
3001753 | 01_First Floor | 639.955 | 79.9033 | 0.121144
3001755 | 01_First Floor | 639.955 | 25.4352 | 0.0385631
3001761 | 01_First Floor | 639.955 | 208.8 | 0.316568
3001765 | 01_First Floor | 644.1 | 27.9 | 0.0423001 | Group: Domestic Hot Water 33
3001798 | 01_First Floor | 528 | 112.9 | 0.171171 | Group: Domestic Hot Water 37
3001800 | 01_First Floor | 639.955 | 79.9033 | 0.121144
3001802 | 01_First Floor | 639.955 | 25.4352 | 0.0385631
3001808 | 01_First Floor | 639.955 | 208.8 | 0.316568
3001812 | 01_First Floor | 644.1 | 27.9 | 0.0423001 | Group: Domestic Hot Water 37
3001844 | 01_First Floor | 528 | 112.9 | 0.171171 | Group: Domestic Hot Water 41
3001846 | 01_First Floor | 639.955 | 79.9033 | 0.121144
3001848 | 01_First Floor | 639.955 | 25.4352 | 0.0385631
3001854 | 01_First Floor | 639.955 | 208.8 | 0.316568
3001858 | 01_First Floor | 644.1 | 27.9 | 0.0423001 | Group: Domestic Hot Water 41
3001894 | 01_First Floor | 528 | 112.9 | 0.171171 | Group: Domestic Hot Water 45
3001896 | 01_First Floor | 639.955 | 79.9033 | 0.121144
3001898 | 01_First Floor | 639.955 | 25.4352 | 0.0385631
3001904 | 01_First Floor | 639.955 | 208.8 | 0.316568
3001908 | 01_First Floor | 644.1 | 27.9 | 0.0423001 | Group: Domestic Hot Water 45
3001940 | 01_First Floor | 528 | 112.9 | 0.171171 | Group: Domestic Hot Water 49
3001942 | 01_First Floor | 639.955 | 79.9033 | 0.121144
3001944 | 01_First Floor | 639.955 | 25.4352 | 0.0385631
3001950 | 01_First Floor | 639.955 | 208.8 | 0.316568
3001954 | 01_First Floor | 644.1 | 27.9 | 0.0423001 | Group: Domestic Hot Water 49
3001986 | 01_First Floor | 528 | 112.9 | 0.171171 | Group: Domestic Hot Water 53
3001988 | 01_First Floor | 639.955 | 79.9033 | 0.121144
3001990 | 01_First Floor | 639.955 | 25.4352 | 0.0385631
3001996 | 01_First Floor | 639.955 | 208.8 | 0.316568
3002000 | 01_First Floor | 644.1 | 27.9 | 0.0423001 | Group: Domestic Hot Water 53
3002032 | 01_First Floor | 528 | 112.9 | 0.171171 | Group: Domestic Hot Water 57
3002034 | 01_First Floor | 639.955 | 79.9033 | 0.121144
3002036 | 01_First Floor | 639.955 | 25.4352 | 0.0385631
3002042 | 01_First Floor | 639.955 | 208.8 | 0.316568
3002046 | 01_First Floor | 644.1 | 27.9 | 0.0423001 | Group: Domestic Hot Water 57
3002078 | 01_First Floor | 528 | 112.9 | 0.171171 | Group: Domestic Hot Water 61
3002080 | 01_First Floor | 639.955 | 79.9033 | 0.121144
3002082 | 01_First Floor | 639.955 | 25.4352 | 0.0385631
3002088 | 01_First Floor | 639.955 | 208.8 | 0.316568
3002092 | 01_First Floor | 644.1 | 27.9 | 0.0423001 | Group: Domestic Hot Water 61
3002125 | 01_First Floor | 528 | 112.9 | 0.171171 | Group: Domestic Hot Water 64
3002127 | 01_First Floor | 639.955 | 79.9033 | 0.121144
3002129 | 01_First Floor | 639.955 | 25.4352 | 0.0385631
3002135 | 01_First Floor | 639.955 | 208.8 | 0.316568
3002139 | 01_First Floor | 644.1 | 27.9 | 0.0423001 | Group: Domestic Hot Water 64
3002171 | 01_First Floor | 528 | 112.9 | 0.171171 | Group: Domestic Hot Water 66
3002173 | 01_First Floor | 639.955 | 79.9033 | 0.121144
3002175 | 01_First Floor | 639.955 | 25.4352 | 0.0385631
3002181 | 01_First Floor | 639.955 | 208.8 | 0.316568
3002185 | 01_First Floor | 644.1 | 27.9 | 0.0423001 | Group: Domestic Hot Water 66
3002221 | 01_First Floor | 528 | 112.9 | 0.171171 | Group: Domestic Hot Water 68
3002223 | 01_First Floor | 639.955 | 79.9033 | 0.121144
3002225 | 01_First Floor | 639.955 | 25.4352 | 0.0385631
3002231 | 01_First Floor | 639.955 | 208.8 | 0.316568
3002235 | 01_First Floor | 644.1 | 27.9 | 0.0423001 | Group: Domestic Hot Water 68
3002267 | 01_First Floor | 528 | 112.9 | 0.171171 | Group: Domestic Hot Water 70
3002269 | 01_First Floor | 639.955 | 79.9033 | 0.121144
3002271 | 01_First Floor | 639.955 | 25.4352 | 0.0385631
3002277 | 01_First Floor | 639.955 | 208.8 | 0.316568
3002281 | 01_First Floor | 644.1 | 27.9 | 0.0423001 | Group: Domestic Hot Water 70
3002313 | 01_First Floor | 528 | 112.9 | 0.171171 | Group: Domestic Hot Water 72
3002315 | 01_First Floor | 639.955 | 79.9033 | 0.121144
3002317 | 01_First Floor | 639.955 | 25.4352 | 0.0385631
3002323 | 01_First Floor | 639.955 | 208.8 | 0.316568
3002327 | 01_First Floor | 644.1 | 27.9 | 0.0423001 | Group: Domestic Hot Water 72
3002359 | 01_First Floor | 528 | 112.9 | 0.171171 | Group: Domestic Hot Water 74
3002361 | 01_First Floor | 639.955 | 79.9033 | 0.121144
3002363 | 01_First Floor | 639.955 | 25.4352 | 0.0385631
3002369 | 01_First Floor | 639.955 | 208.8 | 0.316568
3002373 | 01_First Floor | 644.1 | 27.9 | 0.0423001 | Group: Domestic Hot Water 74
3002405 | 01_First Floor | 528 | 112.9 | 0.171171 | Group: Domestic Hot Water 76
3002407 | 01_First Floor | 639.955 | 79.9033 | 0.121144
3002409 | 01_First Floor | 639.955 | 25.4352 | 0.0385631
3002415 | 01_First Floor | 639.955 | 208.8 | 0.316568
3002419 | 01_First Floor | 644.1 | 27.9 | 0.0423001 | Group: Domestic Hot Water 76
3002452 | 01_First Floor | 528 | 112.9 | 0.171171 | Group: Domestic Hot Water 78
3002454 | 01_First Floor | 639.955 | 79.9033 | 0.121144
3002456 | 01_First Floor | 639.955 | 25.4352 | 0.0385631
3002462 | 01_First Floor | 639.955 | 208.8 | 0.316568
3002466 | 01_First Floor | 644.1 | 27.9 | 0.0423001 | Group: Domestic Hot Water 78
3002498 | 01_First Floor | 528 | 112.9 | 0.171171 | Group: Domestic Hot Water 80
3002500 | 01_First Floor | 639.955 | 79.9033 | 0.121144
3002502 | 01_First Floor | 639.955 | 25.4352 | 0.0385631
3002508 | 01_First Floor | 639.955 | 208.8 | 0.316568
3002512 | 01_First Floor | 644.1 | 27.9 | 0.0423001 | Group: Domestic Hot Water 80
3002548 | 01_First Floor | 528 | 112.9 | 0.171171 | Group: Domestic Hot Water 82
3002550 | 01_First Floor | 639.955 | 79.9033 | 0.121144
3002552 | 01_First Floor | 639.955 | 25.4352 | 0.0385631
3002558 | 01_First Floor | 639.955 | 208.8 | 0.316568
3002562 | 01_First Floor | 644.1 | 27.9 | 0.0423001 | Group: Domestic Hot Water 82
3002594 | 01_First Floor | 528 | 112.9 | 0.171171 | Group: Domestic Hot Water 84
3002596 | 01_First Floor | 639.955 | 79.9033 | 0.121144
3002598 | 01_First Floor | 639.955 | 25.4352 | 0.0385631
3002604 | 01_First Floor | 639.955 | 208.8 | 0.316568
3002608 | 01_First Floor | 644.1 | 27.9 | 0.0423001 | Group: Domestic Hot Water 84
3002640 | 01_First Floor | 528 | 112.9 | 0.171171 | Group: Domestic Hot Water 86
3002642 | 01_First Floor | 639.955 | 79.9033 | 0.121144
3002644 | 01_First Floor | 639.955 | 25.4352 | 0.0385631
3002650 | 01_First Floor | 639.955 | 208.8 | 0.316568
3002654 | 01_First Floor | 644.1 | 27.9 | 0.0423001 | Group: Domestic Hot Water 86
3002686 | 01_First Floor | 528 | 112.9 | 0.171171 | Group: Domestic Hot Water 88
3002688 | 01_First Floor | 639.955 | 79.9033 | 0.121144
3002690 | 01_First Floor | 639.955 | 25.4352 | 0.0385631
3002696 | 01_First Floor | 639.955 | 208.8 | 0.316568
3002700 | 01_First Floor | 644.1 | 27.9 | 0.0423001 | Group: Domestic Hot Water 88
3002732 | 01_First Floor | 528 | 112.9 | 0.171171 | Group: Domestic Hot Water 90
3002734 | 01_First Floor | 639.955 | 79.9033 | 0.121144
3002736 | 01_First Floor | 639.955 | 25.4352 | 0.0385631
3002742 | 01_First Floor | 639.955 | 208.8 | 0.316568
3002746 | 01_First Floor | 644.1 | 27.9 | 0.0423001 | Group: Domestic Hot Water 90
3002779 | 01_First Floor | 528 | 112.9 | 0.171171 | Group: Domestic Hot Water 92
3002781 | 01_First Floor | 639.955 | 79.9033 | 0.121144
3002783 | 01_First Floor | 639.955 | 25.4352 | 0.0385631
3002789 | 01_First Floor | 639.955 | 208.8 | 0.316568
3002793 | 01_First Floor | 644.1 | 27.9 | 0.0423001 | Group: Domestic Hot Water 92
3002825 | 01_First Floor | 528 | 112.9 | 0.171171 | Group: Domestic Hot Water 94
3002827 | 01_First Floor | 639.955 | 79.9033 | 0.121144
3002829 | 01_First Floor | 639.955 | 25.4352 | 0.0385631
3002835 | 01_First Floor | 639.955 | 208.8 | 0.316568
3002839 | 01_First Floor | 644.1 | 27.9 | 0.0423001 | Group: Domestic Hot Water 94
3002875 | 01_First Floor | 528 | 112.9 | 0.171171 | Group: Domestic Hot Water 96
3002877 | 01_First Floor | 639.955 | 79.9033 | 0.121144
3002879 | 01_First Floor | 639.955 | 25.4352 | 0.0385631
3002885 | 01_First Floor | 639.955 | 208.8 | 0.316568
3002889 | 01_First Floor | 644.1 | 27.9 | 0.0423001 | Group: Domestic Hot Water 96
3002921 | 01_First Floor | 528 | 112.9 | 0.171171 | Group: Domestic Hot Water 98
3002923 | 01_First Floor | 639.955 | 79.9033 | 0.121144
3002925 | 01_First Floor | 639.955 | 25.4352 | 0.0385631
3002931 | 01_First Floor | 639.955 | 208.8 | 0.316568
3002935 | 01_First Floor | 644.1 | 27.9 | 0.0423001 | Group: Domestic Hot Water 98
3002967 | 01_First Floor | 528 | 112.9 | 0.171171 | Group: Domestic Hot Water 100
3002969 | 01_First Floor | 639.955 | 79.9033 | 0.121144
3002971 | 01_First Floor | 639.955 | 25.4352 | 0.0385631
3002977 | 01_First Floor | 639.955 | 208.8 | 0.316568
3002981 | 01_First Floor | 644.1 | 27.9 | 0.0423001 | Group: Domestic Hot Water 100
3003013 | 01_First Floor | 528 | 112.9 | 0.171171 | Group: Domestic Hot Water 102
3003015 | 01_First Floor | 639.955 | 79.9033 | 0.121144
3003017 | 01_First Floor | 639.955 | 25.4352 | 0.0385631
3003023 | 01_First Floor | 639.955 | 208.8 | 0.316568
3003027 | 01_First Floor | 644.1 | 27.9 | 0.0423001 | Group: Domestic Hot Water 102
3003059 | 01_First Floor | 528 | 112.9 | 0.171171 | Group: Domestic Hot Water 104
3003061 | 01_First Floor | 639.955 | 79.9033 | 0.121144
3003063 | 01_First Floor | 639.955 | 25.4352 | 0.0385631
3003069 | 01_First Floor | 639.955 | 208.8 | 0.316568
3003073 | 01_First Floor | 644.1 | 27.9 | 0.0423001 | Group: Domestic Hot Water 104
3003668 | 02_Second Floor | 928 | 112.9 | 0.171171 | Group: Domestic Hot Water 9
3003670 | 02_Second Floor | 1039.96 | 79.9033 | 0.121144
3003672 | 02_Second Floor | 1039.96 | 25.4352 | 0.0385631
3003678 | 02_Second Floor | 1039.96 | 208.8 | 0.316568
3003682 | 02_Second Floor | 1044.1 | 27.9 | 0.0423001 | Group: Domestic Hot Water 9
3003714 | 02_Second Floor | 928 | 112.9 | 0.171171 | Group: Domestic Hot Water 19
3003716 | 02_Second Floor | 1039.96 | 79.9033 | 0.121144
3003718 | 02_Second Floor | 1039.96 | 25.4352 | 0.0385631
3003724 | 02_Second Floor | 1039.96 | 208.8 | 0.316568
3003728 | 02_Second Floor | 1044.1 | 27.9 | 0.0423001 | Group: Domestic Hot Water 19
3003764 | 02_Second Floor | 928 | 112.9 | 0.171171 | Group: Domestic Hot Water 27
3003766 | 02_Second Floor | 1039.96 | 79.9033 | 0.121144
3003768 | 02_Second Floor | 1039.96 | 25.4352 | 0.0385631
3003774 | 02_Second Floor | 1039.96 | 208.8 | 0.316568
3003778 | 02_Second Floor | 1044.1 | 27.9 | 0.0423001 | Group: Domestic Hot Water 27
3003810 | 02_Second Floor | 928 | 112.9 | 0.171171 | Group: Domestic Hot Water 35
3003812 | 02_Second Floor | 1039.96 | 79.9033 | 0.121144
3003814 | 02_Second Floor | 1039.96 | 25.4352 | 0.0385631
3003820 | 02_Second Floor | 1039.96 | 208.8 | 0.316568
3003824 | 02_Second Floor | 1044.1 | 27.9 | 0.0423001 | Group: Domestic Hot Water 35
3003856 | 02_Second Floor | 928 | 112.9 | 0.171171 | Group: Domestic Hot Water 43
3003858 | 02_Second Floor | 1039.96 | 79.9033 | 0.121144
3003860 | 02_Second Floor | 1039.96 | 25.4352 | 0.0385631
3003866 | 02_Second Floor | 1039.96 | 208.8 | 0.316568
3003870 | 02_Second Floor | 1044.1 | 27.9 | 0.0423001 | Group: Domestic Hot Water 43
3003902 | 02_Second Floor | 928 | 112.9 | 0.171171 | Group: Domestic Hot Water 51
3003904 | 02_Second Floor | 1039.96 | 79.9033 | 0.121144
3003906 | 02_Second Floor | 1039.96 | 25.4352 | 0.0385631
3003912 | 02_Second Floor | 1039.96 | 208.8 | 0.316568
3003916 | 02_Second Floor | 1044.1 | 27.9 | 0.0423001 | Group: Domestic Hot Water 51
3003948 | 02_Second Floor | 928 | 112.9 | 0.171171 | Group: Domestic Hot Water 59
3003950 | 02_Second Floor | 1039.96 | 79.9033 | 0.121144
3003952 | 02_Second Floor | 1039.96 | 25.4352 | 0.0385631
3003958 | 02_Second Floor | 1039.96 | 208.8 | 0.316568
3003962 | 02_Second Floor | 1044.1 | 27.9 | 0.0423001 | Group: Domestic Hot Water 59
3003995 | 02_Second Floor | 928 | 112.9 | 0.171171 | Group: Domestic Hot Water 65
3003997 | 02_Second Floor | 1039.96 | 79.9033 | 0.121144
3003999 | 02_Second Floor | 1039.96 | 25.4352 | 0.0385631
3004005 | 02_Second Floor | 1039.96 | 208.8 | 0.316568
3004009 | 02_Second Floor | 1044.1 | 27.9 | 0.0423001 | Group: Domestic Hot Water 65
3004041 | 02_Second Floor | 928 | 112.9 | 0.171171 | Group: Domestic Hot Water 69
3004043 | 02_Second Floor | 1039.96 | 79.9033 | 0.121144
3004045 | 02_Second Floor | 1039.96 | 25.4352 | 0.0385631
3004051 | 02_Second Floor | 1039.96 | 208.8 | 0.316568
3004055 | 02_Second Floor | 1044.1 | 27.9 | 0.0423001 | Group: Domestic Hot Water 69
3004091 | 02_Second Floor | 928 | 112.9 | 0.171171 | Group: Domestic Hot Water 73
3004093 | 02_Second Floor | 1039.96 | 79.9033 | 0.121144
3004095 | 02_Second Floor | 1039.96 | 25.4352 | 0.0385631
3004101 | 02_Second Floor | 1039.96 | 208.8 | 0.316568
3004105 | 02_Second Floor | 1044.1 | 27.9 | 0.0423001 | Group: Domestic Hot Water 73
3004137 | 02_Second Floor | 928 | 112.9 | 0.171171 | Group: Domestic Hot Water 77
3004139 | 02_Second Floor | 1039.96 | 79.9033 | 0.121144
3004141 | 02_Second Floor | 1039.96 | 25.4352 | 0.0385631
3004147 | 02_Second Floor | 1039.96 | 208.8 | 0.316568
3004151 | 02_Second Floor | 1044.1 | 27.9 | 0.0423001 | Group: Domestic Hot Water 77
3004183 | 02_Second Floor | 928 | 112.9 | 0.171171 | Group: Domestic Hot Water 81
3004185 | 02_Second Floor | 1039.96 | 79.9033 | 0.121144
3004187 | 02_Second Floor | 1039.96 | 25.4352 | 0.0385631
3004193 | 02_Second Floor | 1039.96 | 208.8 | 0.316568
3004197 | 02_Second Floor | 1044.1 | 27.9 | 0.0423001 | Group: Domestic Hot Water 81
3004229 | 02_Second Floor | 928 | 112.9 | 0.171171 | Group: Domestic Hot Water 85
3004231 | 02_Second Floor | 1039.96 | 79.9033 | 0.121144
3004233 | 02_Second Floor | 1039.96 | 25.4352 | 0.0385631
3004239 | 02_Second Floor | 1039.96 | 208.8 | 0.316568
3004243 | 02_Second Floor | 1044.1 | 27.9 | 0.0423001 | Group: Domestic Hot Water 85
3004275 | 02_Second Floor | 928 | 112.9 | 0.171171 | Group: Domestic Hot Water 89
3004277 | 02_Second Floor | 1039.96 | 79.9033 | 0.121144
3004279 | 02_Second Floor | 1039.96 | 25.4352 | 0.0385631
3004285 | 02_Second Floor | 1039.96 | 208.8 | 0.316568
3004289 | 02_Second Floor | 1044.1 | 27.9 | 0.0423001 | Group: Domestic Hot Water 89
3004322 | 02_Second Floor | 928 | 112.9 | 0.171171 | Group: Domestic Hot Water 93
3004324 | 02_Second Floor | 1039.96 | 79.9033 | 0.121144
3004326 | 02_Second Floor | 1039.96 | 25.4352 | 0.0385631
3004332 | 02_Second Floor | 1039.96 | 208.8 | 0.316568
3004336 | 02_Second Floor | 1044.1 | 27.9 | 0.0423001 | Group: Domestic Hot Water 93
3004368 | 02_Second Floor | 928 | 112.9 | 0.171171 | Group: Domestic Hot Water 97
3004370 | 02_Second Floor | 1039.96 | 79.9033 | 0.121144
3004372 | 02_Second Floor | 1039.96 | 25.4352 | 0.0385631
3004378 | 02_Second Floor | 1039.96 | 208.8 | 0.316568
3004382 | 02_Second Floor | 1044.1 | 27.9 | 0.0423001 | Group: Domestic Hot Water 97
3004418 | 02_Second Floor | 928 | 112.9 | 0.171171 | Group: Domestic Hot Water 101
3004420 | 02_Second Floor | 1039.96 | 79.9033 | 0.121144
3004422 | 02_Second Floor | 1039.96 | 25.4352 | 0.0385631
3004428 | 02_Second Floor | 1039.96 | 208.8 | 0.316568
3004432 | 02_Second Floor | 1044.1 | 27.9 | 0.0423001 | Group: Domestic Hot Water 101
3004464 | 02_Second Floor | 928 | 112.9 | 0.171171 | Group: Domestic Hot Water 105
3004466 | 02_Second Floor | 1039.96 | 79.9033 | 0.121144
3004468 | 02_Second Floor | 1039.96 | 25.4352 | 0.0385631
3004474 | 02_Second Floor | 1039.96 | 208.8 | 0.316568
3004478 | 02_Second Floor | 1044.1 | 27.9 | 0.0423001 | Group: Domestic Hot Water 105
3004510 | 02_Second Floor | 928 | 112.9 | 0.171171 | Group: Domestic Hot Water 107
3004512 | 02_Second Floor | 1039.96 | 79.9033 | 0.121144
3004514 | 02_Second Floor | 1039.96 | 25.4352 | 0.0385631
3004520 | 02_Second Floor | 1039.96 | 208.8 | 0.316568
3004524 | 02_Second Floor | 1044.1 | 27.9 | 0.0423001 | Group: Domestic Hot Water 107
3004556 | 02_Second Floor | 928 | 112.9 | 0.171171 | Group: Domestic Hot Water 109
3004558 | 02_Second Floor | 1039.96 | 79.9033 | 0.121144
3004560 | 02_Second Floor | 1039.96 | 25.4352 | 0.0385631
3004566 | 02_Second Floor | 1039.96 | 208.8 | 0.316568
3004570 | 02_Second Floor | 1044.1 | 27.9 | 0.0423001 | Group: Domestic Hot Water 109
3004602 | 02_Second Floor | 928 | 112.9 | 0.171171 | Group: Domestic Hot Water 111
3004604 | 02_Second Floor | 1039.96 | 79.9033 | 0.121144
3004606 | 02_Second Floor | 1039.96 | 25.4352 | 0.0385631
3004612 | 02_Second Floor | 1039.96 | 208.8 | 0.316568
3004616 | 02_Second Floor | 1044.1 | 27.9 | 0.0423001 | Group: Domestic Hot Water 111
3004649 | 02_Second Floor | 928 | 112.9 | 0.171171 | Group: Domestic Hot Water 113
3004651 | 02_Second Floor | 1039.96 | 79.9033 | 0.121144
3004653 | 02_Second Floor | 1039.96 | 25.4352 | 0.0385631
3004659 | 02_Second Floor | 1039.96 | 208.8 | 0.316568
3004663 | 02_Second Floor | 1044.1 | 27.9 | 0.0423001 | Group: Domestic Hot Water 113
3004695 | 02_Second Floor | 928 | 112.9 | 0.171171 | Group: Domestic Hot Water 115
3004697 | 02_Second Floor | 1039.96 | 79.9033 | 0.121144
3004699 | 02_Second Floor | 1039.96 | 25.4352 | 0.0385631
3004705 | 02_Second Floor | 1039.96 | 208.8 | 0.316568
3004709 | 02_Second Floor | 1044.1 | 27.9 | 0.0423001 | Group: Domestic Hot Water 115
3004745 | 02_Second Floor | 928 | 112.9 | 0.171171 | Group: Domestic Hot Water 117
3004747 | 02_Second Floor | 1039.96 | 79.9033 | 0.121144
3004749 | 02_Second Floor | 1039.96 | 25.4352 | 0.0385631
3004755 | 02_Second Floor | 1039.96 | 208.8 | 0.316568
3004759 | 02_Second Floor | 1044.1 | 27.9 | 0.0423001 | Group: Domestic Hot Water 117
3004791 | 02_Second Floor | 928 | 112.9 | 0.171171 | Group: Domestic Hot Water 119
3004793 | 02_Second Floor | 1039.96 | 79.9033 | 0.121144
3004795 | 02_Second Floor | 1039.96 | 25.4352 | 0.0385631
3004801 | 02_Second Floor | 1039.96 | 208.8 | 0.316568
3004805 | 02_Second Floor | 1044.1 | 27.9 | 0.0423001 | Group: Domestic Hot Water 119
3004837 | 02_Second Floor | 928 | 112.9 | 0.171171 | Group: Domestic Hot Water 121
3004839 | 02_Second Floor | 1039.96 | 79.9033 | 0.121144
3004841 | 02_Second Floor | 1039.96 | 25.4352 | 0.0385631
3004847 | 02_Second Floor | 1039.96 | 208.8 | 0.316568
3004851 | 02_Second Floor | 1044.1 | 27.9 | 0.0423001 | Group: Domestic Hot Water 121
3004883 | 02_Second Floor | 928 | 112.9 | 0.171171 | Group: Domestic Hot Water 123
3004885 | 02_Second Floor | 1039.96 | 79.9033 | 0.121144
3004887 | 02_Second Floor | 1039.96 | 25.4352 | 0.0385631
3004893 | 02_Second Floor | 1039.96 | 208.8 | 0.316568
3004897 | 02_Second Floor | 1044.1 | 27.9 | 0.0423001 | Group: Domestic Hot Water 123
3004929 | 02_Second Floor | 928 | 112.9 | 0.171171 | Group: Domestic Hot Water 125
3004931 | 02_Second Floor | 1039.96 | 79.9033 | 0.121144
3004933 | 02_Second Floor | 1039.96 | 25.4352 | 0.0385631
3004939 | 02_Second Floor | 1039.96 | 208.8 | 0.316568
3004943 | 02_Second Floor | 1044.1 | 27.9 | 0.0423001 | Group: Domestic Hot Water 125
3004976 | 02_Second Floor | 928 | 112.9 | 0.171171 | Group: Domestic Hot Water 127
3004978 | 02_Second Floor | 1039.96 | 79.9033 | 0.121144
3004980 | 02_Second Floor | 1039.96 | 25.4352 | 0.0385631
3004986 | 02_Second Floor | 1039.96 | 208.8 | 0.316568
3004990 | 02_Second Floor | 1044.1 | 27.9 | 0.0423001 | Group: Domestic Hot Water 127
3005022 | 02_Second Floor | 928 | 112.9 | 0.171171 | Group: Domestic Hot Water 129
3005024 | 02_Second Floor | 1039.96 | 79.9033 | 0.121144
3005026 | 02_Second Floor | 1039.96 | 25.4352 | 0.0385631
3005032 | 02_Second Floor | 1039.96 | 208.8 | 0.316568
3005036 | 02_Second Floor | 1044.1 | 27.9 | 0.0423001 | Group: Domestic Hot Water 129
3005072 | 02_Second Floor | 928 | 112.9 | 0.171171 | Group: Domestic Hot Water 131
3005074 | 02_Second Floor | 1039.96 | 79.9033 | 0.121144
3005076 | 02_Second Floor | 1039.96 | 25.4352 | 0.0385631
3005082 | 02_Second Floor | 1039.96 | 208.8 | 0.316568
3005086 | 02_Second Floor | 1044.1 | 27.9 | 0.0423001 | Group: Domestic Hot Water 131
3005118 | 02_Second Floor | 928 | 112.9 | 0.171171 | Group: Domestic Hot Water 133
3005120 | 02_Second Floor | 1039.96 | 79.9033 | 0.121144
3005122 | 02_Second Floor | 1039.96 | 25.4352 | 0.0385631
3005128 | 02_Second Floor | 1039.96 | 208.8 | 0.316568
3005132 | 02_Second Floor | 1044.1 | 27.9 | 0.0423001 | Group: Domestic Hot Water 133
3005164 | 02_Second Floor | 928 | 112.9 | 0.171171 | Group: Domestic Hot Water 135
3005166 | 02_Second Floor | 1039.96 | 79.9033 | 0.121144
3005168 | 02_Second Floor | 1039.96 | 25.4352 | 0.0385631
3005174 | 02_Second Floor | 1039.96 | 208.8 | 0.316568
3005178 | 02_Second Floor | 1044.1 | 27.9 | 0.0423001 | Group: Domestic Hot Water 135
3005210 | 02_Second Floor | 928 | 112.9 | 0.171171 | Group: Domestic Hot Water 137
3005212 | 02_Second Floor | 1039.96 | 79.9033 | 0.121144
3005214 | 02_Second Floor | 1039.96 | 25.4352 | 0.0385631
3005220 | 02_Second Floor | 1039.96 | 208.8 | 0.316568
3005224 | 02_Second Floor | 1044.1 | 27.9 | 0.0423001 | Group: Domestic Hot Water 137
3005256 | 02_Second Floor | 928 | 112.9 | 0.171171 | Group: Domestic Hot Water 139
3005258 | 02_Second Floor | 1039.96 | 79.9033 | 0.121144
3005260 | 02_Second Floor | 1039.96 | 25.4352 | 0.0385631
3005266 | 02_Second Floor | 1039.96 | 208.8 | 0.316568
3005270 | 02_Second Floor | 1044.1 | 27.9 | 0.0423001 | Group: Domestic Hot Water 139
3005865 | 03_Third Floor | 1328 | 112.9 | 0.171171 | Group: Domestic Hot Water 15
3005867 | 03_Third Floor | 1439.96 | 79.9033 | 0.121144
3005869 | 03_Third Floor | 1439.96 | 25.4352 | 0.0385631
3005875 | 03_Third Floor | 1439.96 | 208.8 | 0.316568
3005879 | 03_Third Floor | 1444.1 | 27.9 | 0.0423001 | Group: Domestic Hot Water 15
3005911 | 03_Third Floor | 1328 | 112.9 | 0.171171 | Group: Domestic Hot Water 31
3005913 | 03_Third Floor | 1439.96 | 79.9033 | 0.121144
3005915 | 03_Third Floor | 1439.96 | 25.4352 | 0.0385631
3005921 | 03_Third Floor | 1439.96 | 208.8 | 0.316568
3005925 | 03_Third Floor | 1444.1 | 27.9 | 0.0423001 | Group: Domestic Hot Water 31
3005961 | 03_Third Floor | 1328 | 112.9 | 0.171171 | Group: Domestic Hot Water 47
3005963 | 03_Third Floor | 1439.96 | 79.9033 | 0.121144
3005965 | 03_Third Floor | 1439.96 | 25.4352 | 0.0385631
3005971 | 03_Third Floor | 1439.96 | 208.8 | 0.316568
3005975 | 03_Third Floor | 1444.1 | 27.9 | 0.0423001 | Group: Domestic Hot Water 47
3006007 | 03_Third Floor | 1328 | 112.9 | 0.171171 | Group: Domestic Hot Water 63
3006009 | 03_Third Floor | 1439.96 | 79.9033 | 0.121144
3006011 | 03_Third Floor | 1439.96 | 25.4352 | 0.0385631
3006017 | 03_Third Floor | 1439.96 | 208.8 | 0.316568
3006021 | 03_Third Floor | 1444.1 | 27.9 | 0.0423001 | Group: Domestic Hot Water 63
3006053 | 03_Third Floor | 1328 | 112.9 | 0.171171 | Group: Domestic Hot Water 71
3006055 | 03_Third Floor | 1439.96 | 79.9033 | 0.121144
3006057 | 03_Third Floor | 1439.96 | 25.4352 | 0.0385631
3006063 | 03_Third Floor | 1439.96 | 208.8 | 0.316568
3006067 | 03_Third Floor | 1444.1 | 27.9 | 0.0423001 | Group: Domestic Hot Water 71
3006099 | 03_Third Floor | 1328 | 112.9 | 0.171171 | Group: Domestic Hot Water 79
3006101 | 03_Third Floor | 1439.96 | 79.9033 | 0.121144
3006103 | 03_Third Floor | 1439.96 | 25.4352 | 0.0385631
3006109 | 03_Third Floor | 1439.96 | 208.8 | 0.316568
3006113 | 03_Third Floor | 1444.1 | 27.9 | 0.0423001 | Group: Domestic Hot Water 79
3006145 | 03_Third Floor | 1328 | 112.9 | 0.171171 | Group: Domestic Hot Water 87
3006147 | 03_Third Floor | 1439.96 | 79.9033 | 0.121144
3006149 | 03_Third Floor | 1439.96 | 25.4352 | 0.0385631
3006155 | 03_Third Floor | 1439.96 | 208.8 | 0.316568
3006159 | 03_Third Floor | 1444.1 | 27.9 | 0.0423001 | Group: Domestic Hot Water 87
3006192 | 03_Third Floor | 1328 | 112.9 | 0.171171 | Group: Domestic Hot Water 95
3006194 | 03_Third Floor | 1439.96 | 79.9033 | 0.121144
3006196 | 03_Third Floor | 1439.96 | 25.4352 | 0.0385631
3006202 | 03_Third Floor | 1439.96 | 208.8 | 0.316568
3006206 | 03_Third Floor | 1444.1 | 27.9 | 0.0423001 | Group: Domestic Hot Water 95
3006238 | 03_Third Floor | 1328 | 112.9 | 0.171171 | Group: Domestic Hot Water 103
3006240 | 03_Third Floor | 1439.96 | 79.9033 | 0.121144
3006242 | 03_Third Floor | 1439.96 | 25.4352 | 0.0385631
3006248 | 03_Third Floor | 1439.96 | 208.8 | 0.316568
3006252 | 03_Third Floor | 1444.1 | 27.9 | 0.0423001 | Group: Domestic Hot Water 103
3006288 | 03_Third Floor | 1328 | 112.9 | 0.171171 | Group: Domestic Hot Water 108
3006290 | 03_Third Floor | 1439.96 | 79.9033 | 0.121144
3006292 | 03_Third Floor | 1439.96 | 25.4352 | 0.0385631
3006298 | 03_Third Floor | 1439.96 | 208.8 | 0.316568
3006302 | 03_Third Floor | 1444.1 | 27.9 | 0.0423001 | Group: Domestic Hot Water 108
3006334 | 03_Third Floor | 1328 | 112.9 | 0.171171 | Group: Domestic Hot Water 112
3006336 | 03_Third Floor | 1439.96 | 79.9033 | 0.121144
3006338 | 03_Third Floor | 1439.96 | 25.4352 | 0.0385631
3006344 | 03_Third Floor | 1439.96 | 208.8 | 0.316568
3006348 | 03_Third Floor | 1444.1 | 27.9 | 0.0423001 | Group: Domestic Hot Water 112
3006380 | 03_Third Floor | 1328 | 112.9 | 0.171171 | Group: Domestic Hot Water 116
3006382 | 03_Third Floor | 1439.96 | 79.9033 | 0.121144
3006384 | 03_Third Floor | 1439.96 | 25.4352 | 0.0385631
3006390 | 03_Third Floor | 1439.96 | 208.8 | 0.316568
3006394 | 03_Third Floor | 1444.1 | 27.9 | 0.0423001 | Group: Domestic Hot Water 116
3006426 | 03_Third Floor | 1328 | 112.9 | 0.171171 | Group: Domestic Hot Water 120
3006428 | 03_Third Floor | 1439.96 | 79.9033 | 0.121144
3006430 | 03_Third Floor | 1439.96 | 25.4352 | 0.0385631
3006436 | 03_Third Floor | 1439.96 | 208.8 | 0.316568
3006440 | 03_Third Floor | 1444.1 | 27.9 | 0.0423001 | Group: Domestic Hot Water 120
3006472 | 03_Third Floor | 1328 | 112.9 | 0.171171 | Group: Domestic Hot Water 124
3006474 | 03_Third Floor | 1439.96 | 79.9033 | 0.121144
3006476 | 03_Third Floor | 1439.96 | 25.4352 | 0.0385631
3006482 | 03_Third Floor | 1439.96 | 208.8 | 0.316568
3006486 | 03_Third Floor | 1444.1 | 27.9 | 0.0423001 | Group: Domestic Hot Water 124
3006519 | 03_Third Floor | 1328 | 112.9 | 0.171171 | Group: Domestic Hot Water 128
3006521 | 03_Third Floor | 1439.96 | 79.9033 | 0.121144
3006523 | 03_Third Floor | 1439.96 | 25.4352 | 0.0385631
3006529 | 03_Third Floor | 1439.96 | 208.8 | 0.316568
3006533 | 03_Third Floor | 1444.1 | 27.9 | 0.0423001 | Group: Domestic Hot Water 128
3006565 | 03_Third Floor | 1328 | 112.9 | 0.171171 | Group: Domestic Hot Water 132
3006567 | 03_Third Floor | 1439.96 | 79.9033 | 0.121144
3006569 | 03_Third Floor | 1439.96 | 25.4352 | 0.0385631
3006575 | 03_Third Floor | 1439.96 | 208.8 | 0.316568
3006579 | 03_Third Floor | 1444.1 | 27.9 | 0.0423001 | Group: Domestic Hot Water 132
3006615 | 03_Third Floor | 1328 | 112.9 | 0.171171 | Group: Domestic Hot Water 136
3006617 | 03_Third Floor | 1439.96 | 79.9033 | 0.121144
3006619 | 03_Third Floor | 1439.96 | 25.4352 | 0.0385631
3006625 | 03_Third Floor | 1439.96 | 208.8 | 0.316568
3006629 | 03_Third Floor | 1444.1 | 27.9 | 0.0423001 | Group: Domestic Hot Water 136
3006661 | 03_Third Floor | 1328 | 112.9 | 0.171171 | Group: Domestic Hot Water 140
3006663 | 03_Third Floor | 1439.96 | 79.9033 | 0.121144
3006665 | 03_Third Floor | 1439.96 | 25.4352 | 0.0385631
3006671 | 03_Third Floor | 1439.96 | 208.8 | 0.316568
3006675 | 03_Third Floor | 1444.1 | 27.9 | 0.0423001 | Group: Domestic Hot Water 140
3006707 | 03_Third Floor | 1328 | 112.9 | 0.171171 | Group: Domestic Hot Water 142
3006709 | 03_Third Floor | 1439.96 | 79.9033 | 0.121144
3006711 | 03_Third Floor | 1439.96 | 25.4352 | 0.0385631
3006717 | 03_Third Floor | 1439.96 | 208.8 | 0.316568
3006721 | 03_Third Floor | 1444.1 | 27.9 | 0.0423001 | Group: Domestic Hot Water 142
3006753 | 03_Third Floor | 1328 | 112.9 | 0.171171 | Group: Domestic Hot Water 144
3006755 | 03_Third Floor | 1439.96 | 79.9033 | 0.121144
3006757 | 03_Third Floor | 1439.96 | 25.4352 | 0.0385631
3006763 | 03_Third Floor | 1439.96 | 208.8 | 0.316568
3006767 | 03_Third Floor | 1444.1 | 27.9 | 0.0423001 | Group: Domestic Hot Water 144
3006799 | 03_Third Floor | 1328 | 112.9 | 0.171171 | Group: Domestic Hot Water 146
3006801 | 03_Third Floor | 1439.96 | 79.9033 | 0.121144
3006803 | 03_Third Floor | 1439.96 | 25.4352 | 0.0385631
3006809 | 03_Third Floor | 1439.96 | 208.8 | 0.316568
3006813 | 03_Third Floor | 1444.1 | 27.9 | 0.0423001 | Group: Domestic Hot Water 146
3006846 | 03_Third Floor | 1328 | 112.9 | 0.171171 | Group: Domestic Hot Water 148
3006848 | 03_Third Floor | 1439.96 | 79.9033 | 0.121144
3006850 | 03_Third Floor | 1439.96 | 25.4352 | 0.0385631
3006856 | 03_Third Floor | 1439.96 | 208.8 | 0.316568
3006860 | 03_Third Floor | 1444.1 | 27.9 | 0.0423001 | Group: Domestic Hot Water 148
3006892 | 03_Third Floor | 1328 | 112.9 | 0.171171 | Group: Domestic Hot Water 150
3006894 | 03_Third Floor | 1439.96 | 79.9033 | 0.121144
3006896 | 03_Third Floor | 1439.96 | 25.4352 | 0.0385631
3006902 | 03_Third Floor | 1439.96 | 208.8 | 0.316568
3006906 | 03_Third Floor | 1444.1 | 27.9 | 0.0423001 | Group: Domestic Hot Water 150
3006942 | 03_Third Floor | 1328 | 112.9 | 0.171171 | Group: Domestic Hot Water 152
3006944 | 03_Third Floor | 1439.96 | 79.9033 | 0.121144
3006946 | 03_Third Floor | 1439.96 | 25.4352 | 0.0385631
3006952 | 03_Third Floor | 1439.96 | 208.8 | 0.316568
3006956 | 03_Third Floor | 1444.1 | 27.9 | 0.0423001 | Group: Domestic Hot Water 152
3006988 | 03_Third Floor | 1328 | 112.9 | 0.171171 | Group: Domestic Hot Water 154
3006990 | 03_Third Floor | 1439.96 | 79.9033 | 0.121144
3006992 | 03_Third Floor | 1439.96 | 25.4352 | 0.0385631
3006998 | 03_Third Floor | 1439.96 | 208.8 | 0.316568
3007002 | 03_Third Floor | 1444.1 | 27.9 | 0.0423001 | Group: Domestic Hot Water 154
3007034 | 03_Third Floor | 1328 | 112.9 | 0.171171 | Group: Domestic Hot Water 156
3007036 | 03_Third Floor | 1439.96 | 79.9033 | 0.121144
3007038 | 03_Third Floor | 1439.96 | 25.4352 | 0.0385631
3007044 | 03_Third Floor | 1439.96 | 208.8 | 0.316568
3007048 | 03_Third Floor | 1444.1 | 27.9 | 0.0423001 | Group: Domestic Hot Water 156
3007080 | 03_Third Floor | 1328 | 112.9 | 0.171171 | Group: Domestic Hot Water 158
3007082 | 03_Third Floor | 1439.96 | 79.9033 | 0.121144
3007084 | 03_Third Floor | 1439.96 | 25.4352 | 0.0385631
3007090 | 03_Third Floor | 1439.96 | 208.8 | 0.316568
3007094 | 03_Third Floor | 1444.1 | 27.9 | 0.0423001 | Group: Domestic Hot Water 158
3007126 | 03_Third Floor | 1328 | 112.9 | 0.171171 | Group: Domestic Hot Water 160
3007128 | 03_Third Floor | 1439.96 | 79.9033 | 0.121144
3007130 | 03_Third Floor | 1439.96 | 25.4352 | 0.0385631
3007136 | 03_Third Floor | 1439.96 | 208.8 | 0.316568
3007140 | 03_Third Floor | 1444.1 | 27.9 | 0.0423001 | Group: Domestic Hot Water 160
3007173 | 03_Third Floor | 1328 | 112.9 | 0.171171 | Group: Domestic Hot Water 162
3007175 | 03_Third Floor | 1439.96 | 79.9033 | 0.121144
3007177 | 03_Third Floor | 1439.96 | 25.4352 | 0.0385631
3007183 | 03_Third Floor | 1439.96 | 208.8 | 0.316568
3007187 | 03_Third Floor | 1444.1 | 27.9 | 0.0423001 | Group: Domestic Hot Water 162
3007219 | 03_Third Floor | 1328 | 112.9 | 0.171171 | Group: Domestic Hot Water 164
3007221 | 03_Third Floor | 1439.96 | 79.9033 | 0.121144
3007223 | 03_Third Floor | 1439.96 | 25.4352 | 0.0385631
3007229 | 03_Third Floor | 1439.96 | 208.8 | 0.316568
3007233 | 03_Third Floor | 1444.1 | 27.9 | 0.0423001 | Group: Domestic Hot Water 164
3007269 | 03_Third Floor | 1328 | 112.9 | 0.171171 | Group: Domestic Hot Water 166
3007271 | 03_Third Floor | 1439.96 | 79.9033 | 0.121144
3007273 | 03_Third Floor | 1439.96 | 25.4352 | 0.0385631
3007279 | 03_Third Floor | 1439.96 | 208.8 | 0.316568
3007283 | 03_Third Floor | 1444.1 | 27.9 | 0.0423001 | Group: Domestic Hot Water 166
3007315 | 03_Third Floor | 1328 | 112.9 | 0.171171 | Group: Domestic Hot Water 168
3007317 | 03_Third Floor | 1439.96 | 79.9033 | 0.121144
3007319 | 03_Third Floor | 1439.96 | 25.4352 | 0.0385631
3007325 | 03_Third Floor | 1439.96 | 208.8 | 0.316568
3007329 | 03_Third Floor | 1444.1 | 27.9 | 0.0423001 | Group: Domestic Hot Water 168
3007361 | 03_Third Floor | 1328 | 112.9 | 0.171171 | Group: Domestic Hot Water 170
3007363 | 03_Third Floor | 1439.96 | 79.9033 | 0.121144
3007365 | 03_Third Floor | 1439.96 | 25.4352 | 0.0385631
3007371 | 03_Third Floor | 1439.96 | 208.8 | 0.316568
3007375 | 03_Third Floor | 1444.1 | 27.9 | 0.0423001 | Group: Domestic Hot Water 170
3007407 | 03_Third Floor | 1328 | 112.9 | 0.171171 | Group: Domestic Hot Water 172
3007409 | 03_Third Floor | 1439.96 | 79.9033 | 0.121144
3007411 | 03_Third Floor | 1439.96 | 25.4352 | 0.0385631
3007417 | 03_Third Floor | 1439.96 | 208.8 | 0.316568
3007421 | 03_Third Floor | 1444.1 | 27.9 | 0.0423001 | Group: Domestic Hot Water 172
3007453 | 03_Third Floor | 1328 | 112.9 | 0.171171 | Group: Domestic Hot Water 174
3007455 | 03_Third Floor | 1439.96 | 79.9033 | 0.121144
3007457 | 03_Third Floor | 1439.96 | 25.4352 | 0.0385631
3007463 | 03_Third Floor | 1439.96 | 208.8 | 0.316568
3007467 | 03_Third Floor | 1444.1 | 27.9 | 0.0423001 | Group: Domestic Hot Water 174
3008060 | 04_Fourth Floor | 1728 | 112.9 | 0.171171 | Group: Domestic Hot Water 23
3008062 | 04_Fourth Floor | 1839.96 | 79.9033 | 0.121144
3008064 | 04_Fourth Floor | 1839.96 | 25.4352 | 0.0385631
3008070 | 04_Fourth Floor | 1839.96 | 208.8 | 0.316568
3008074 | 04_Fourth Floor | 1844.1 | 27.9 | 0.0423001 | Group: Domestic Hot Water 23
3008106 | 04_Fourth Floor | 1728 | 112.9 | 0.171171 | Group: Domestic Hot Water 55
3008108 | 04_Fourth Floor | 1839.96 | 79.9033 | 0.121144
3008110 | 04_Fourth Floor | 1839.96 | 25.4352 | 0.0385631
3008116 | 04_Fourth Floor | 1839.96 | 208.8 | 0.316568
3008120 | 04_Fourth Floor | 1844.1 | 27.9 | 0.0423001 | Group: Domestic Hot Water 55
3008156 | 04_Fourth Floor | 1728 | 112.9 | 0.171171 | Group: Domestic Hot Water 75
3008158 | 04_Fourth Floor | 1839.96 | 79.9033 | 0.121144
3008160 | 04_Fourth Floor | 1839.96 | 25.4352 | 0.0385631
3008166 | 04_Fourth Floor | 1839.96 | 208.8 | 0.316568
3008170 | 04_Fourth Floor | 1844.1 | 27.9 | 0.0423001 | Group: Domestic Hot Water 75
3008202 | 04_Fourth Floor | 1728 | 112.9 | 0.171171 | Group: Domestic Hot Water 91
3008204 | 04_Fourth Floor | 1839.96 | 79.9033 | 0.121144
3008206 | 04_Fourth Floor | 1839.96 | 25.4352 | 0.0385631
3008212 | 04_Fourth Floor | 1839.96 | 208.8 | 0.316568
3008216 | 04_Fourth Floor | 1844.1 | 27.9 | 0.0423001 | Group: Domestic Hot Water 91
3008248 | 04_Fourth Floor | 1728 | 112.9 | 0.171171 | Group: Domestic Hot Water 106
3008250 | 04_Fourth Floor | 1839.96 | 79.9033 | 0.121144
3008252 | 04_Fourth Floor | 1839.96 | 25.4352 | 0.0385631
3008258 | 04_Fourth Floor | 1839.96 | 208.8 | 0.316568
3008262 | 04_Fourth Floor | 1844.1 | 27.9 | 0.0423001 | Group: Domestic Hot Water 106
3008294 | 04_Fourth Floor | 1728 | 112.9 | 0.171171 | Group: Domestic Hot Water 114
3008296 | 04_Fourth Floor | 1839.96 | 79.9033 | 0.121144
3008298 | 04_Fourth Floor | 1839.96 | 25.4352 | 0.0385631
3008304 | 04_Fourth Floor | 1839.96 | 208.8 | 0.316568
3008308 | 04_Fourth Floor | 1844.1 | 27.9 | 0.0423001 | Group: Domestic Hot Water 114
3008340 | 04_Fourth Floor | 1728 | 112.9 | 0.171171 | Group: Domestic Hot Water 122
3008342 | 04_Fourth Floor | 1839.96 | 79.9033 | 0.121144
3008344 | 04_Fourth Floor | 1839.96 | 25.4352 | 0.0385631
3008350 | 04_Fourth Floor | 1839.96 | 208.8 | 0.316568
3008354 | 04_Fourth Floor | 1844.1 | 27.9 | 0.0423001 | Group: Domestic Hot Water 122
3008387 | 04_Fourth Floor | 1728 | 112.9 | 0.171171 | Group: Domestic Hot Water 130
3008389 | 04_Fourth Floor | 1839.96 | 79.9033 | 0.121144
3008391 | 04_Fourth Floor | 1839.96 | 25.4352 | 0.0385631
3008397 | 04_Fourth Floor | 1839.96 | 208.8 | 0.316568
3008401 | 04_Fourth Floor | 1844.1 | 27.9 | 0.0423001 | Group: Domestic Hot Water 130
3008433 | 04_Fourth Floor | 1728 | 112.9 | 0.171171 | Group: Domestic Hot Water 138
3008435 | 04_Fourth Floor | 1839.96 | 79.9033 | 0.121144
3008437 | 04_Fourth Floor | 1839.96 | 25.4352 | 0.0385631
3008443 | 04_Fourth Floor | 1839.96 | 208.8 | 0.316568
3008447 | 04_Fourth Floor | 1844.1 | 27.9 | 0.0423001 | Group: Domestic Hot Water 138
3008483 | 04_Fourth Floor | 1728 | 112.9 | 0.171171 | Group: Domestic Hot Water 143
3008485 | 04_Fourth Floor | 1839.96 | 79.9033 | 0.121144
3008487 | 04_Fourth Floor | 1839.96 | 25.4352 | 0.0385631
3008493 | 04_Fourth Floor | 1839.96 | 208.8 | 0.316568
3008497 | 04_Fourth Floor | 1844.1 | 27.9 | 0.0423001 | Group: Domestic Hot Water 143
3008529 | 04_Fourth Floor | 1728 | 112.9 | 0.171171 | Group: Domestic Hot Water 147
3008531 | 04_Fourth Floor | 1839.96 | 79.9033 | 0.121144
3008533 | 04_Fourth Floor | 1839.96 | 25.4352 | 0.0385631
3008539 | 04_Fourth Floor | 1839.96 | 208.8 | 0.316568
3008543 | 04_Fourth Floor | 1844.1 | 27.9 | 0.0423001 | Group: Domestic Hot Water 147
3008575 | 04_Fourth Floor | 1728 | 112.9 | 0.171171 | Group: Domestic Hot Water 151
3008577 | 04_Fourth Floor | 1839.96 | 79.9033 | 0.121144
3008579 | 04_Fourth Floor | 1839.96 | 25.4352 | 0.0385631
3008585 | 04_Fourth Floor | 1839.96 | 208.8 | 0.316568
3008589 | 04_Fourth Floor | 1844.1 | 27.9 | 0.0423001 | Group: Domestic Hot Water 151
3008621 | 04_Fourth Floor | 1728 | 112.9 | 0.171171 | Group: Domestic Hot Water 155
3008623 | 04_Fourth Floor | 1839.96 | 79.9033 | 0.121144
3008625 | 04_Fourth Floor | 1839.96 | 25.4352 | 0.0385631
3008631 | 04_Fourth Floor | 1839.96 | 208.8 | 0.316568
3008635 | 04_Fourth Floor | 1844.1 | 27.9 | 0.0423001 | Group: Domestic Hot Water 155
3008667 | 04_Fourth Floor | 1728 | 112.9 | 0.171171 | Group: Domestic Hot Water 159
3008669 | 04_Fourth Floor | 1839.96 | 79.9033 | 0.121144
3008671 | 04_Fourth Floor | 1839.96 | 25.4352 | 0.0385631
3008677 | 04_Fourth Floor | 1839.96 | 208.8 | 0.316568
3008681 | 04_Fourth Floor | 1844.1 | 27.9 | 0.0423001 | Group: Domestic Hot Water 159
3008714 | 04_Fourth Floor | 1728 | 112.9 | 0.171171 | Group: Domestic Hot Water 163
3008716 | 04_Fourth Floor | 1839.96 | 79.9033 | 0.121144
3008718 | 04_Fourth Floor | 1839.96 | 25.4352 | 0.0385631
3008724 | 04_Fourth Floor | 1839.96 | 208.8 | 0.316568
3008728 | 04_Fourth Floor | 1844.1 | 27.9 | 0.0423001 | Group: Domestic Hot Water 163
3008760 | 04_Fourth Floor | 1728 | 112.9 | 0.171171 | Group: Domestic Hot Water 167
3008762 | 04_Fourth Floor | 1839.96 | 79.9033 | 0.121144
3008764 | 04_Fourth Floor | 1839.96 | 25.4352 | 0.0385631
3008770 | 04_Fourth Floor | 1839.96 | 208.8 | 0.316568
3008774 | 04_Fourth Floor | 1844.1 | 27.9 | 0.0423001 | Group: Domestic Hot Water 167
3008810 | 04_Fourth Floor | 1728 | 112.9 | 0.171171 | Group: Domestic Hot Water 171
3008812 | 04_Fourth Floor | 1839.96 | 79.9033 | 0.121144
3008814 | 04_Fourth Floor | 1839.96 | 25.4352 | 0.0385631
3008820 | 04_Fourth Floor | 1839.96 | 208.8 | 0.316568
3008824 | 04_Fourth Floor | 1844.1 | 27.9 | 0.0423001 | Group: Domestic Hot Water 171
3008856 | 04_Fourth Floor | 1728 | 112.9 | 0.171171 | Group: Domestic Hot Water 175
3008858 | 04_Fourth Floor | 1839.96 | 79.9033 | 0.121144
3008860 | 04_Fourth Floor | 1839.96 | 25.4352 | 0.0385631
3008866 | 04_Fourth Floor | 1839.96 | 208.8 | 0.316568
3008870 | 04_Fourth Floor | 1844.1 | 27.9 | 0.0423001 | Group: Domestic Hot Water 175
3008902 | 04_Fourth Floor | 1728 | 112.9 | 0.171171 | Group: Domestic Hot Water 177
3008904 | 04_Fourth Floor | 1839.96 | 79.9033 | 0.121144
3008906 | 04_Fourth Floor | 1839.96 | 25.4352 | 0.0385631
3008912 | 04_Fourth Floor | 1839.96 | 208.8 | 0.316568
3008916 | 04_Fourth Floor | 1844.1 | 27.9 | 0.0423001 | Group: Domestic Hot Water 177
3008948 | 04_Fourth Floor | 1728 | 112.9 | 0.171171 | Group: Domestic Hot Water 179
3008950 | 04_Fourth Floor | 1839.96 | 79.9033 | 0.121144
3008952 | 04_Fourth Floor | 1839.96 | 25.4352 | 0.0385631
3008958 | 04_Fourth Floor | 1839.96 | 208.8 | 0.316568
3008962 | 04_Fourth Floor | 1844.1 | 27.9 | 0.0423001 | Group: Domestic Hot Water 179
3008994 | 04_Fourth Floor | 1728 | 112.9 | 0.171171 | Group: Domestic Hot Water 181
3008996 | 04_Fourth Floor | 1839.96 | 79.9033 | 0.121144
3008998 | 04_Fourth Floor | 1839.96 | 25.4352 | 0.0385631
3009004 | 04_Fourth Floor | 1839.96 | 208.8 | 0.316568
3009008 | 04_Fourth Floor | 1844.1 | 27.9 | 0.0423001 | Group: Domestic Hot Water 181
3009041 | 04_Fourth Floor | 1728 | 112.9 | 0.171171 | Group: Domestic Hot Water 183
3009043 | 04_Fourth Floor | 1839.96 | 79.9033 | 0.121144
3009045 | 04_Fourth Floor | 1839.96 | 25.4352 | 0.0385631
3009051 | 04_Fourth Floor | 1839.96 | 208.8 | 0.316568
3009055 | 04_Fourth Floor | 1844.1 | 27.9 | 0.0423001 | Group: Domestic Hot Water 183
3009087 | 04_Fourth Floor | 1728 | 112.9 | 0.171171 | Group: Domestic Hot Water 185
3009089 | 04_Fourth Floor | 1839.96 | 79.9033 | 0.121144
3009091 | 04_Fourth Floor | 1839.96 | 25.4352 | 0.0385631
3009097 | 04_Fourth Floor | 1839.96 | 208.8 | 0.316568
3009101 | 04_Fourth Floor | 1844.1 | 27.9 | 0.0423001 | Group: Domestic Hot Water 185
3009137 | 04_Fourth Floor | 1728 | 112.9 | 0.171171 | Group: Domestic Hot Water 187
3009139 | 04_Fourth Floor | 1839.96 | 79.9033 | 0.121144
3009141 | 04_Fourth Floor | 1839.96 | 25.4352 | 0.0385631
3009147 | 04_Fourth Floor | 1839.96 | 208.8 | 0.316568
3009151 | 04_Fourth Floor | 1844.1 | 27.9 | 0.0423001 | Group: Domestic Hot Water 187
3009183 | 04_Fourth Floor | 1728 | 112.9 | 0.171171 | Group: Domestic Hot Water 189
3009185 | 04_Fourth Floor | 1839.96 | 79.9033 | 0.121144
3009187 | 04_Fourth Floor | 1839.96 | 25.4352 | 0.0385631
3009193 | 04_Fourth Floor | 1839.96 | 208.8 | 0.316568
3009197 | 04_Fourth Floor | 1844.1 | 27.9 | 0.0423001 | Group: Domestic Hot Water 189
3009229 | 04_Fourth Floor | 1728 | 112.9 | 0.171171 | Group: Domestic Hot Water 191
3009231 | 04_Fourth Floor | 1839.96 | 79.9033 | 0.121144
3009233 | 04_Fourth Floor | 1839.96 | 25.4352 | 0.0385631
3009239 | 04_Fourth Floor | 1839.96 | 208.8 | 0.316568
3009243 | 04_Fourth Floor | 1844.1 | 27.9 | 0.0423001 | Group: Domestic Hot Water 191
3009275 | 04_Fourth Floor | 1728 | 112.9 | 0.171171 | Group: Domestic Hot Water 193
3009277 | 04_Fourth Floor | 1839.96 | 79.9033 | 0.121144
3009279 | 04_Fourth Floor | 1839.96 | 25.4352 | 0.0385631
3009285 | 04_Fourth Floor | 1839.96 | 208.8 | 0.316568
3009289 | 04_Fourth Floor | 1844.1 | 27.9 | 0.0423001 | Group: Domestic Hot Water 193
3009321 | 04_Fourth Floor | 1728 | 112.9 | 0.171171 | Group: Domestic Hot Water 195
3009323 | 04_Fourth Floor | 1839.96 | 79.9033 | 0.121144
3009325 | 04_Fourth Floor | 1839.96 | 25.4352 | 0.0385631
3009331 | 04_Fourth Floor | 1839.96 | 208.8 | 0.316568
3009335 | 04_Fourth Floor | 1844.1 | 27.9 | 0.0423001 | Group: Domestic Hot Water 195
3009368 | 04_Fourth Floor | 1728 | 112.9 | 0.171171 | Group: Domestic Hot Water 197
3009370 | 04_Fourth Floor | 1839.96 | 79.9033 | 0.121144
3009372 | 04_Fourth Floor | 1839.96 | 25.4352 | 0.0385631
3009378 | 04_Fourth Floor | 1839.96 | 208.8 | 0.316568
3009382 | 04_Fourth Floor | 1844.1 | 27.9 | 0.0423001 | Group: Domestic Hot Water 197
3009414 | 04_Fourth Floor | 1728 | 112.9 | 0.171171 | Group: Domestic Hot Water 199
3009416 | 04_Fourth Floor | 1839.96 | 79.9033 | 0.121144
3009418 | 04_Fourth Floor | 1839.96 | 25.4352 | 0.0385631
3009424 | 04_Fourth Floor | 1839.96 | 208.8 | 0.316568
3009428 | 04_Fourth Floor | 1844.1 | 27.9 | 0.0423001 | Group: Domestic Hot Water 199
3009464 | 04_Fourth Floor | 1728 | 112.9 | 0.171171 | Group: Domestic Hot Water 201
3009466 | 04_Fourth Floor | 1839.96 | 79.9033 | 0.121144
3009468 | 04_Fourth Floor | 1839.96 | 25.4352 | 0.0385631
3009474 | 04_Fourth Floor | 1839.96 | 208.8 | 0.316568
3009478 | 04_Fourth Floor | 1844.1 | 27.9 | 0.0423001 | Group: Domestic Hot Water 201
3009510 | 04_Fourth Floor | 1728 | 112.9 | 0.171171 | Group: Domestic Hot Water 203
3009512 | 04_Fourth Floor | 1839.96 | 79.9033 | 0.121144
3009514 | 04_Fourth Floor | 1839.96 | 25.4352 | 0.0385631
3009520 | 04_Fourth Floor | 1839.96 | 208.8 | 0.316568
3009524 | 04_Fourth Floor | 1844.1 | 27.9 | 0.0423001 | Group: Domestic Hot Water 203
3009556 | 04_Fourth Floor | 1728 | 112.9 | 0.171171 | Group: Domestic Hot Water 205
3009558 | 04_Fourth Floor | 1839.96 | 79.9033 | 0.121144
3009560 | 04_Fourth Floor | 1839.96 | 25.4352 | 0.0385631
3009566 | 04_Fourth Floor | 1839.96 | 208.8 | 0.316568
3009570 | 04_Fourth Floor | 1844.1 | 27.9 | 0.0423001 | Group: Domestic Hot Water 205
3009602 | 04_Fourth Floor | 1728 | 112.9 | 0.171171 | Group: Domestic Hot Water 207
3009604 | 04_Fourth Floor | 1839.96 | 79.9033 | 0.121144
3009606 | 04_Fourth Floor | 1839.96 | 25.4352 | 0.0385631
3009612 | 04_Fourth Floor | 1839.96 | 208.8 | 0.316568
3009616 | 04_Fourth Floor | 1844.1 | 27.9 | 0.0423001 | Group: Domestic Hot Water 207
3009648 | 04_Fourth Floor | 1728 | 112.9 | 0.171171 | Group: Domestic Hot Water 209
3009650 | 04_Fourth Floor | 1839.96 | 79.9033 | 0.121144
3009652 | 04_Fourth Floor | 1839.96 | 25.4352 | 0.0385631
3009658 | 04_Fourth Floor | 1839.96 | 208.8 | 0.316568
3009662 | 04_Fourth Floor | 1844.1 | 27.9 | 0.0423001 | Group: Domestic Hot Water 209
3010255 | 05_Fifth Floor | 2128 | 112.9 | 0.171171 | Group: Domestic Hot Water 39
3010257 | 05_Fifth Floor | 2239.96 | 79.9033 | 0.121144
3010259 | 05_Fifth Floor | 2239.96 | 25.4352 | 0.0385631
3010265 | 05_Fifth Floor | 2239.96 | 208.8 | 0.316568
3010269 | 05_Fifth Floor | 2244.1 | 27.9 | 0.0423001 | Group: Domestic Hot Water 39
3010301 | 05_Fifth Floor | 2128 | 112.9 | 0.171171 | Group: Domestic Hot Water 83
3010303 | 05_Fifth Floor | 2239.96 | 79.9033 | 0.121144
3010305 | 05_Fifth Floor | 2239.96 | 25.4352 | 0.0385631
3010311 | 05_Fifth Floor | 2239.96 | 208.8 | 0.316568
3010315 | 05_Fifth Floor | 2244.1 | 27.9 | 0.0423001 | Group: Domestic Hot Water 83
3010351 | 05_Fifth Floor | 2128 | 112.9 | 0.171171 | Group: Domestic Hot Water 110
3010353 | 05_Fifth Floor | 2239.96 | 79.9033 | 0.121144
3010355 | 05_Fifth Floor | 2239.96 | 25.4352 | 0.0385631
3010361 | 05_Fifth Floor | 2239.96 | 208.8 | 0.316568
3010365 | 05_Fifth Floor | 2244.1 | 27.9 | 0.0423001 | Group: Domestic Hot Water 110
3010397 | 05_Fifth Floor | 2128 | 112.9 | 0.171171 | Group: Domestic Hot Water 126
3010399 | 05_Fifth Floor | 2239.96 | 79.9033 | 0.121144
3010401 | 05_Fifth Floor | 2239.96 | 25.4352 | 0.0385631
3010407 | 05_Fifth Floor | 2239.96 | 208.8 | 0.316568
3010411 | 05_Fifth Floor | 2244.1 | 27.9 | 0.0423001 | Group: Domestic Hot Water 126
3010443 | 05_Fifth Floor | 2128 | 112.9 | 0.171171 | Group: Domestic Hot Water 141
3010445 | 05_Fifth Floor | 2239.96 | 79.9033 | 0.121144
3010447 | 05_Fifth Floor | 2239.96 | 25.4352 | 0.0385631
3010453 | 05_Fifth Floor | 2239.96 | 208.8 | 0.316568
3010457 | 05_Fifth Floor | 2244.1 | 27.9 | 0.0423001 | Group: Domestic Hot Water 141
3010489 | 05_Fifth Floor | 2128 | 112.9 | 0.171171 | Group: Domestic Hot Water 149
3010491 | 05_Fifth Floor | 2239.96 | 79.9033 | 0.121144
3010493 | 05_Fifth Floor | 2239.96 | 25.4352 | 0.0385631
3010499 | 05_Fifth Floor | 2239.96 | 208.8 | 0.316568
3010503 | 05_Fifth Floor | 2244.1 | 27.9 | 0.0423001 | Group: Domestic Hot Water 149
3010535 | 05_Fifth Floor | 2128 | 112.9 | 0.171171 | Group: Domestic Hot Water 157
3010537 | 05_Fifth Floor | 2239.96 | 79.9033 | 0.121144
3010539 | 05_Fifth Floor | 2239.96 | 25.4352 | 0.0385631
3010545 | 05_Fifth Floor | 2239.96 | 208.8 | 0.316568
3010549 | 05_Fifth Floor | 2244.1 | 27.9 | 0.0423001 | Group: Domestic Hot Water 157
3010582 | 05_Fifth Floor | 2128 | 112.9 | 0.171171 | Group: Domestic Hot Water 165
3010584 | 05_Fifth Floor | 2239.96 | 79.9033 | 0.121144
3010586 | 05_Fifth Floor | 2239.96 | 25.4352 | 0.0385631
3010592 | 05_Fifth Floor | 2239.96 | 208.8 | 0.316568
3010596 | 05_Fifth Floor | 2244.1 | 27.9 | 0.0423001 | Group: Domestic Hot Water 165
3010628 | 05_Fifth Floor | 2128 | 112.9 | 0.171171 | Group: Domestic Hot Water 173
3010630 | 05_Fifth Floor | 2239.96 | 79.9033 | 0.121144
3010632 | 05_Fifth Floor | 2239.96 | 25.4352 | 0.0385631
3010638 | 05_Fifth Floor | 2239.96 | 208.8 | 0.316568
3010642 | 05_Fifth Floor | 2244.1 | 27.9 | 0.0423001 | Group: Domestic Hot Water 173
3010678 | 05_Fifth Floor | 2128 | 112.9 | 0.171171 | Group: Domestic Hot Water 178
3010680 | 05_Fifth Floor | 2239.96 | 79.9033 | 0.121144
3010682 | 05_Fifth Floor | 2239.96 | 25.4352 | 0.0385631
3010688 | 05_Fifth Floor | 2239.96 | 208.8 | 0.316568
3010692 | 05_Fifth Floor | 2244.1 | 27.9 | 0.0423001 | Group: Domestic Hot Water 178
3010724 | 05_Fifth Floor | 2128 | 112.9 | 0.171171 | Group: Domestic Hot Water 182
3010726 | 05_Fifth Floor | 2239.96 | 79.9033 | 0.121144
3010728 | 05_Fifth Floor | 2239.96 | 25.4352 | 0.0385631
3010734 | 05_Fifth Floor | 2239.96 | 208.8 | 0.316568
3010738 | 05_Fifth Floor | 2244.1 | 27.9 | 0.0423001 | Group: Domestic Hot Water 182
3010770 | 05_Fifth Floor | 2128 | 112.9 | 0.171171 | Group: Domestic Hot Water 186
3010772 | 05_Fifth Floor | 2239.96 | 79.9033 | 0.121144
3010774 | 05_Fifth Floor | 2239.96 | 25.4352 | 0.0385631
3010780 | 05_Fifth Floor | 2239.96 | 208.8 | 0.316568
3010784 | 05_Fifth Floor | 2244.1 | 27.9 | 0.0423001 | Group: Domestic Hot Water 186
3010816 | 05_Fifth Floor | 2128 | 112.9 | 0.171171 | Group: Domestic Hot Water 190
3010818 | 05_Fifth Floor | 2239.96 | 79.9033 | 0.121144
3010820 | 05_Fifth Floor | 2239.96 | 25.4352 | 0.0385631
3010826 | 05_Fifth Floor | 2239.96 | 208.8 | 0.316568
3010830 | 05_Fifth Floor | 2244.1 | 27.9 | 0.0423001 | Group: Domestic Hot Water 190
3010862 | 05_Fifth Floor | 2128 | 112.9 | 0.171171 | Group: Domestic Hot Water 194
3010864 | 05_Fifth Floor | 2239.96 | 79.9033 | 0.121144
3010866 | 05_Fifth Floor | 2239.96 | 25.4352 | 0.0385631
3010872 | 05_Fifth Floor | 2239.96 | 208.8 | 0.316568
3010876 | 05_Fifth Floor | 2244.1 | 27.9 | 0.0423001 | Group: Domestic Hot Water 194
3010909 | 05_Fifth Floor | 2128 | 112.9 | 0.171171 | Group: Domestic Hot Water 198
3010911 | 05_Fifth Floor | 2239.96 | 79.9033 | 0.121144
3010913 | 05_Fifth Floor | 2239.96 | 25.4352 | 0.0385631
3010919 | 05_Fifth Floor | 2239.96 | 208.8 | 0.316568
3010923 | 05_Fifth Floor | 2244.1 | 27.9 | 0.0423001 | Group: Domestic Hot Water 198
3010955 | 05_Fifth Floor | 2128 | 112.9 | 0.171171 | Group: Domestic Hot Water 202
3010957 | 05_Fifth Floor | 2239.96 | 79.9033 | 0.121144
3010959 | 05_Fifth Floor | 2239.96 | 25.4352 | 0.0385631
3010965 | 05_Fifth Floor | 2239.96 | 208.8 | 0.316568
3010969 | 05_Fifth Floor | 2244.1 | 27.9 | 0.0423001 | Group: Domestic Hot Water 202
3011005 | 05_Fifth Floor | 2128 | 112.9 | 0.171171 | Group: Domestic Hot Water 206
3011007 | 05_Fifth Floor | 2239.96 | 79.9033 | 0.121144
3011009 | 05_Fifth Floor | 2239.96 | 25.4352 | 0.0385631
3011015 | 05_Fifth Floor | 2239.96 | 208.8 | 0.316568
3011019 | 05_Fifth Floor | 2244.1 | 27.9 | 0.0423001 | Group: Domestic Hot Water 206
3011051 | 05_Fifth Floor | 2128 | 112.9 | 0.171171 | Group: Domestic Hot Water 210
3011053 | 05_Fifth Floor | 2239.96 | 79.9033 | 0.121144
3011055 | 05_Fifth Floor | 2239.96 | 25.4352 | 0.0385631
3011061 | 05_Fifth Floor | 2239.96 | 208.8 | 0.316568
3011065 | 05_Fifth Floor | 2244.1 | 27.9 | 0.0423001 | Group: Domestic Hot Water 210
3011097 | 05_Fifth Floor | 2128 | 112.9 | 0.171171 | Group: Domestic Hot Water 212
3011099 | 05_Fifth Floor | 2239.96 | 79.9033 | 0.121144
3011101 | 05_Fifth Floor | 2239.96 | 25.4352 | 0.0385631
3011107 | 05_Fifth Floor | 2239.96 | 208.8 | 0.316568
3011111 | 05_Fifth Floor | 2244.1 | 27.9 | 0.0423001 | Group: Domestic Hot Water 212
3011143 | 05_Fifth Floor | 2128 | 112.9 | 0.171171 | Group: Domestic Hot Water 214
3011145 | 05_Fifth Floor | 2239.96 | 79.9033 | 0.121144
3011147 | 05_Fifth Floor | 2239.96 | 25.4352 | 0.0385631
3011153 | 05_Fifth Floor | 2239.96 | 208.8 | 0.316568
3011157 | 05_Fifth Floor | 2244.1 | 27.9 | 0.0423001 | Group: Domestic Hot Water 214
3011189 | 05_Fifth Floor | 2128 | 112.9 | 0.171171 | Group: Domestic Hot Water 216
3011191 | 05_Fifth Floor | 2239.96 | 79.9033 | 0.121144
3011193 | 05_Fifth Floor | 2239.96 | 25.4352 | 0.0385631
3011199 | 05_Fifth Floor | 2239.96 | 208.8 | 0.316568
3011203 | 05_Fifth Floor | 2244.1 | 27.9 | 0.0423001 | Group: Domestic Hot Water 216
3011236 | 05_Fifth Floor | 2128 | 112.9 | 0.171171 | Group: Domestic Hot Water 218
3011238 | 05_Fifth Floor | 2239.96 | 79.9033 | 0.121144
3011240 | 05_Fifth Floor | 2239.96 | 25.4352 | 0.0385631
3011246 | 05_Fifth Floor | 2239.96 | 208.8 | 0.316568
3011250 | 05_Fifth Floor | 2244.1 | 27.9 | 0.0423001 | Group: Domestic Hot Water 218
3011282 | 05_Fifth Floor | 2128 | 112.9 | 0.171171 | Group: Domestic Hot Water 220
3011284 | 05_Fifth Floor | 2239.96 | 79.9033 | 0.121144
3011286 | 05_Fifth Floor | 2239.96 | 25.4352 | 0.0385631
3011292 | 05_Fifth Floor | 2239.96 | 208.8 | 0.316568
3011296 | 05_Fifth Floor | 2244.1 | 27.9 | 0.0423001 | Group: Domestic Hot Water 220
3011332 | 05_Fifth Floor | 2128 | 112.9 | 0.171171 | Group: Domestic Hot Water 222
3011334 | 05_Fifth Floor | 2239.96 | 79.9033 | 0.121144
3011336 | 05_Fifth Floor | 2239.96 | 25.4352 | 0.0385631
3011342 | 05_Fifth Floor | 2239.96 | 208.8 | 0.316568
3011346 | 05_Fifth Floor | 2244.1 | 27.9 | 0.0423001 | Group: Domestic Hot Water 222
3011378 | 05_Fifth Floor | 2128 | 112.9 | 0.171171 | Group: Domestic Hot Water 224
3011380 | 05_Fifth Floor | 2239.96 | 79.9033 | 0.121144
3011382 | 05_Fifth Floor | 2239.96 | 25.4352 | 0.0385631
3011388 | 05_Fifth Floor | 2239.96 | 208.8 | 0.316568
3011392 | 05_Fifth Floor | 2244.1 | 27.9 | 0.0423001 | Group: Domestic Hot Water 224
3011424 | 05_Fifth Floor | 2128 | 112.9 | 0.171171 | Group: Domestic Hot Water 226
3011426 | 05_Fifth Floor | 2239.96 | 79.9033 | 0.121144
3011428 | 05_Fifth Floor | 2239.96 | 25.4352 | 0.0385631
3011434 | 05_Fifth Floor | 2239.96 | 208.8 | 0.316568
3011438 | 05_Fifth Floor | 2244.1 | 27.9 | 0.0423001 | Group: Domestic Hot Water 226
3011470 | 05_Fifth Floor | 2128 | 112.9 | 0.171171 | Group: Domestic Hot Water 228
3011472 | 05_Fifth Floor | 2239.96 | 79.9033 | 0.121144
3011474 | 05_Fifth Floor | 2239.96 | 25.4352 | 0.0385631
3011480 | 05_Fifth Floor | 2239.96 | 208.8 | 0.316568
3011484 | 05_Fifth Floor | 2244.1 | 27.9 | 0.0423001 | Group: Domestic Hot Water 228
3011516 | 05_Fifth Floor | 2128 | 112.9 | 0.171171 | Group: Domestic Hot Water 230
3011518 | 05_Fifth Floor | 2239.96 | 79.9033 | 0.121144
3011520 | 05_Fifth Floor | 2239.96 | 25.4352 | 0.0385631
3011526 | 05_Fifth Floor | 2239.96 | 208.8 | 0.316568
3011530 | 05_Fifth Floor | 2244.1 | 27.9 | 0.0423001 | Group: Domestic Hot Water 230
3011563 | 05_Fifth Floor | 2128 | 112.9 | 0.171171 | Group: Domestic Hot Water 232
3011565 | 05_Fifth Floor | 2239.96 | 79.9033 | 0.121144
3011567 | 05_Fifth Floor | 2239.96 | 25.4352 | 0.0385631
3011573 | 05_Fifth Floor | 2239.96 | 208.8 | 0.316568
3011577 | 05_Fifth Floor | 2244.1 | 27.9 | 0.0423001 | Group: Domestic Hot Water 232
3011609 | 05_Fifth Floor | 2128 | 112.9 | 0.171171 | Group: Domestic Hot Water 234
3011611 | 05_Fifth Floor | 2239.96 | 79.9033 | 0.121144
3011613 | 05_Fifth Floor | 2239.96 | 25.4352 | 0.0385631
3011619 | 05_Fifth Floor | 2239.96 | 208.8 | 0.316568
3011623 | 05_Fifth Floor | 2244.1 | 27.9 | 0.0423001 | Group: Domestic Hot Water 234
3011659 | 05_Fifth Floor | 2128 | 112.9 | 0.171171 | Group: Domestic Hot Water 236
3011661 | 05_Fifth Floor | 2239.96 | 79.9033 | 0.121144
3011663 | 05_Fifth Floor | 2239.96 | 25.4352 | 0.0385631
3011669 | 05_Fifth Floor | 2239.96 | 208.8 | 0.316568
3011673 | 05_Fifth Floor | 2244.1 | 27.9 | 0.0423001 | Group: Domestic Hot Water 236
3011705 | 05_Fifth Floor | 2128 | 112.9 | 0.171171 | Group: Domestic Hot Water 238
3011707 | 05_Fifth Floor | 2239.96 | 79.9033 | 0.121144
3011709 | 05_Fifth Floor | 2239.96 | 25.4352 | 0.0385631
3011715 | 05_Fifth Floor | 2239.96 | 208.8 | 0.316568
3011719 | 05_Fifth Floor | 2244.1 | 27.9 | 0.0423001 | Group: Domestic Hot Water 238
3011751 | 05_Fifth Floor | 2128 | 112.9 | 0.171171 | Group: Domestic Hot Water 240
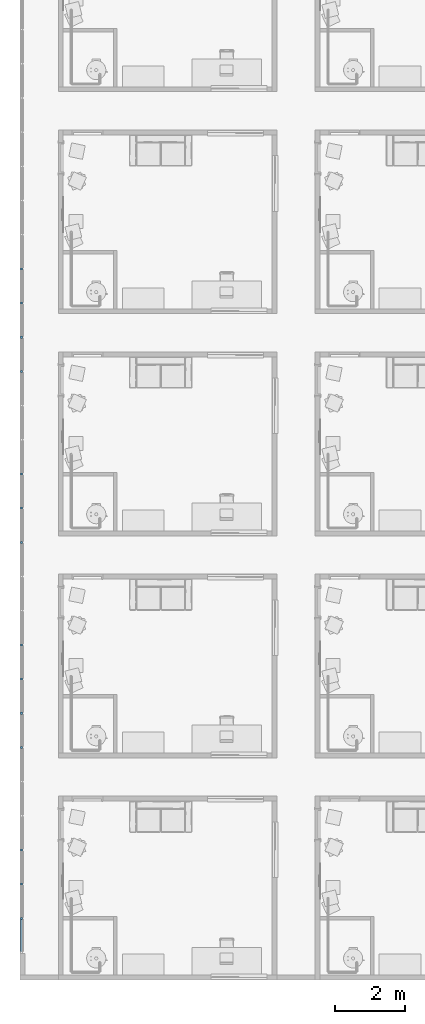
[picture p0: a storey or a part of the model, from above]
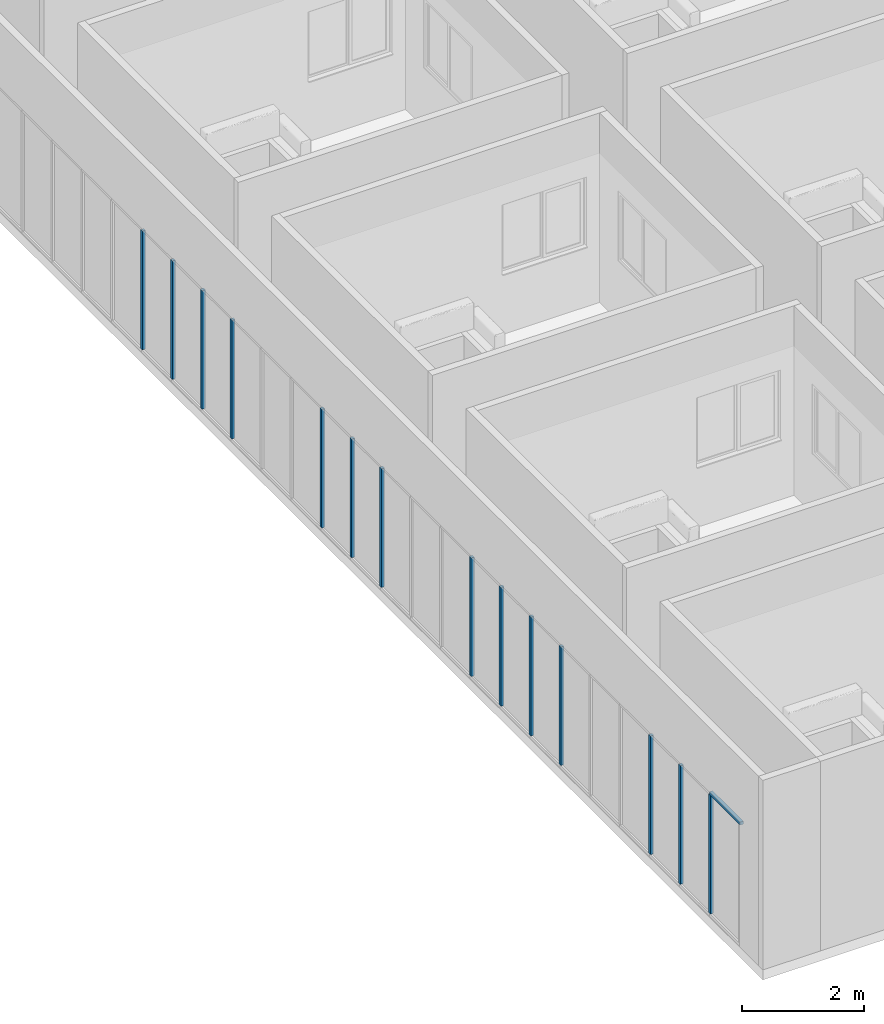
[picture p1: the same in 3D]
Properties of the parts of a building model (IFC4), part 11 of 14

# IfcPipeSegment: Pipe Types:Piping Aluminum (1400)
Name (Pipe Types:Piping Aluminum:...) | In | InvertElevation (cm) | Length (cm) | OuterSurfaceArea (m2)
3011753 | 05_Fifth Floor | 2239.96 | 79.9033 | 0.121144
3011755 | 05_Fifth Floor | 2239.96 | 25.4352 | 0.0385631
3011761 | 05_Fifth Floor | 2239.96 | 208.8 | 0.316568
3011765 | 05_Fifth Floor | 2244.1 | 27.9 | 0.0423001 | Group: Domestic Hot Water 240
3011797 | 05_Fifth Floor | 2128 | 112.9 | 0.171171 | Group: Domestic Hot Water 242
3011799 | 05_Fifth Floor | 2239.96 | 79.9033 | 0.121144
3011801 | 05_Fifth Floor | 2239.96 | 25.4352 | 0.0385631
3011807 | 05_Fifth Floor | 2239.96 | 208.8 | 0.316568
3011811 | 05_Fifth Floor | 2244.1 | 27.9 | 0.0423001 | Group: Domestic Hot Water 242
3011843 | 05_Fifth Floor | 2128 | 112.9 | 0.171171 | Group: Domestic Hot Water 244
3011845 | 05_Fifth Floor | 2239.96 | 79.9033 | 0.121144
3011847 | 05_Fifth Floor | 2239.96 | 25.4352 | 0.0385631
3011853 | 05_Fifth Floor | 2239.96 | 208.8 | 0.316568
3011857 | 05_Fifth Floor | 2244.1 | 27.9 | 0.0423001 | Group: Domestic Hot Water 244
3012452 | 06_Sixth Floor | 2528 | 112.9 | 0.171171 | Group: Domestic Hot Water 67
3012454 | 06_Sixth Floor | 2639.96 | 79.9033 | 0.121144
3012456 | 06_Sixth Floor | 2639.96 | 25.4352 | 0.0385631
3012462 | 06_Sixth Floor | 2639.96 | 208.8 | 0.316568
3012466 | 06_Sixth Floor | 2644.1 | 27.9 | 0.0423001 | Group: Domestic Hot Water 67
3012498 | 06_Sixth Floor | 2528 | 112.9 | 0.171171 | Group: Domestic Hot Water 118
3012500 | 06_Sixth Floor | 2639.96 | 79.9033 | 0.121144
3012502 | 06_Sixth Floor | 2639.96 | 25.4352 | 0.0385631
3012508 | 06_Sixth Floor | 2639.96 | 208.8 | 0.316568
3012512 | 06_Sixth Floor | 2644.1 | 27.9 | 0.0423001 | Group: Domestic Hot Water 118
3012548 | 06_Sixth Floor | 2528 | 112.9 | 0.171171 | Group: Domestic Hot Water 145
3012550 | 06_Sixth Floor | 2639.96 | 79.9033 | 0.121144
3012552 | 06_Sixth Floor | 2639.96 | 25.4352 | 0.0385631
3012558 | 06_Sixth Floor | 2639.96 | 208.8 | 0.316568
3012562 | 06_Sixth Floor | 2644.1 | 27.9 | 0.0423001 | Group: Domestic Hot Water 145
3012594 | 06_Sixth Floor | 2528 | 112.9 | 0.171171 | Group: Domestic Hot Water 161
3012596 | 06_Sixth Floor | 2639.96 | 79.9033 | 0.121144
3012598 | 06_Sixth Floor | 2639.96 | 25.4352 | 0.0385631
3012604 | 06_Sixth Floor | 2639.96 | 208.8 | 0.316568
3012608 | 06_Sixth Floor | 2644.1 | 27.9 | 0.0423001 | Group: Domestic Hot Water 161
3012640 | 06_Sixth Floor | 2528 | 112.9 | 0.171171 | Group: Domestic Hot Water 176
3012642 | 06_Sixth Floor | 2639.96 | 79.9033 | 0.121144
3012644 | 06_Sixth Floor | 2639.96 | 25.4352 | 0.0385631
3012650 | 06_Sixth Floor | 2639.96 | 208.8 | 0.316568
3012654 | 06_Sixth Floor | 2644.1 | 27.9 | 0.0423001 | Group: Domestic Hot Water 176
3012686 | 06_Sixth Floor | 2528 | 112.9 | 0.171171 | Group: Domestic Hot Water 184
3012688 | 06_Sixth Floor | 2639.96 | 79.9033 | 0.121144
3012690 | 06_Sixth Floor | 2639.96 | 25.4352 | 0.0385631
3012696 | 06_Sixth Floor | 2639.96 | 208.8 | 0.316568
3012700 | 06_Sixth Floor | 2644.1 | 27.9 | 0.0423001 | Group: Domestic Hot Water 184
3012732 | 06_Sixth Floor | 2528 | 112.9 | 0.171171 | Group: Domestic Hot Water 192
3012734 | 06_Sixth Floor | 2639.96 | 79.9033 | 0.121144
3012736 | 06_Sixth Floor | 2639.96 | 25.4352 | 0.0385631
3012742 | 06_Sixth Floor | 2639.96 | 208.8 | 0.316568
3012746 | 06_Sixth Floor | 2644.1 | 27.9 | 0.0423001 | Group: Domestic Hot Water 192
3012779 | 06_Sixth Floor | 2528 | 112.9 | 0.171171 | Group: Domestic Hot Water 200
3012781 | 06_Sixth Floor | 2639.96 | 79.9033 | 0.121144
3012783 | 06_Sixth Floor | 2639.96 | 25.4352 | 0.0385631
3012789 | 06_Sixth Floor | 2639.96 | 208.8 | 0.316568
3012793 | 06_Sixth Floor | 2644.1 | 27.9 | 0.0423001 | Group: Domestic Hot Water 200
3012825 | 06_Sixth Floor | 2528 | 112.9 | 0.171171 | Group: Domestic Hot Water 208
3012827 | 06_Sixth Floor | 2639.96 | 79.9033 | 0.121144
3012829 | 06_Sixth Floor | 2639.96 | 25.4352 | 0.0385631
3012835 | 06_Sixth Floor | 2639.96 | 208.8 | 0.316568
3012839 | 06_Sixth Floor | 2644.1 | 27.9 | 0.0423001 | Group: Domestic Hot Water 208
3012875 | 06_Sixth Floor | 2528 | 112.9 | 0.171171 | Group: Domestic Hot Water 213
3012877 | 06_Sixth Floor | 2639.96 | 79.9033 | 0.121144
3012879 | 06_Sixth Floor | 2639.96 | 25.4352 | 0.0385631
3012885 | 06_Sixth Floor | 2639.96 | 208.8 | 0.316568
3012889 | 06_Sixth Floor | 2644.1 | 27.9 | 0.0423001 | Group: Domestic Hot Water 213
3012921 | 06_Sixth Floor | 2528 | 112.9 | 0.171171 | Group: Domestic Hot Water 217
3012923 | 06_Sixth Floor | 2639.96 | 79.9033 | 0.121144
3012925 | 06_Sixth Floor | 2639.96 | 25.4352 | 0.0385631
3012931 | 06_Sixth Floor | 2639.96 | 208.8 | 0.316568
3012935 | 06_Sixth Floor | 2644.1 | 27.9 | 0.0423001 | Group: Domestic Hot Water 217
3012967 | 06_Sixth Floor | 2528 | 112.9 | 0.171171 | Group: Domestic Hot Water 221
3012969 | 06_Sixth Floor | 2639.96 | 79.9033 | 0.121144
3012971 | 06_Sixth Floor | 2639.96 | 25.4352 | 0.0385631
3012977 | 06_Sixth Floor | 2639.96 | 208.8 | 0.316568
3012981 | 06_Sixth Floor | 2644.1 | 27.9 | 0.0423001 | Group: Domestic Hot Water 221
3013013 | 06_Sixth Floor | 2528 | 112.9 | 0.171171 | Group: Domestic Hot Water 225
3013015 | 06_Sixth Floor | 2639.96 | 79.9033 | 0.121144
3013017 | 06_Sixth Floor | 2639.96 | 25.4352 | 0.0385631
3013023 | 06_Sixth Floor | 2639.96 | 208.8 | 0.316568
3013027 | 06_Sixth Floor | 2644.1 | 27.9 | 0.0423001 | Group: Domestic Hot Water 225
3013059 | 06_Sixth Floor | 2528 | 112.9 | 0.171171 | Group: Domestic Hot Water 229
3013061 | 06_Sixth Floor | 2639.96 | 79.9033 | 0.121144
3013063 | 06_Sixth Floor | 2639.96 | 25.4352 | 0.0385631
3013069 | 06_Sixth Floor | 2639.96 | 208.8 | 0.316568
3013073 | 06_Sixth Floor | 2644.1 | 27.9 | 0.0423001 | Group: Domestic Hot Water 229
3013106 | 06_Sixth Floor | 2528 | 112.9 | 0.171171 | Group: Domestic Hot Water 233
3013108 | 06_Sixth Floor | 2639.96 | 79.9033 | 0.121144
3013110 | 06_Sixth Floor | 2639.96 | 25.4352 | 0.0385631
3013116 | 06_Sixth Floor | 2639.96 | 208.8 | 0.316568
3013120 | 06_Sixth Floor | 2644.1 | 27.9 | 0.0423001 | Group: Domestic Hot Water 233
3013152 | 06_Sixth Floor | 2528 | 112.9 | 0.171171 | Group: Domestic Hot Water 237
3013154 | 06_Sixth Floor | 2639.96 | 79.9033 | 0.121144
3013156 | 06_Sixth Floor | 2639.96 | 25.4352 | 0.0385631
3013162 | 06_Sixth Floor | 2639.96 | 208.8 | 0.316568
3013166 | 06_Sixth Floor | 2644.1 | 27.9 | 0.0423001 | Group: Domestic Hot Water 237
3013202 | 06_Sixth Floor | 2528 | 112.9 | 0.171171 | Group: Domestic Hot Water 241
3013204 | 06_Sixth Floor | 2639.96 | 79.9033 | 0.121144
3013206 | 06_Sixth Floor | 2639.96 | 25.4352 | 0.0385631
3013212 | 06_Sixth Floor | 2639.96 | 208.8 | 0.316568
3013216 | 06_Sixth Floor | 2644.1 | 27.9 | 0.0423001 | Group: Domestic Hot Water 241
3013248 | 06_Sixth Floor | 2528 | 112.9 | 0.171171 | Group: Domestic Hot Water 245
3013250 | 06_Sixth Floor | 2639.96 | 79.9033 | 0.121144
3013252 | 06_Sixth Floor | 2639.96 | 25.4352 | 0.0385631
3013258 | 06_Sixth Floor | 2639.96 | 208.8 | 0.316568
3013262 | 06_Sixth Floor | 2644.1 | 27.9 | 0.0423001 | Group: Domestic Hot Water 245
3013294 | 06_Sixth Floor | 2528 | 112.9 | 0.171171 | Group: Domestic Hot Water 247
3013296 | 06_Sixth Floor | 2639.96 | 79.9033 | 0.121144
3013298 | 06_Sixth Floor | 2639.96 | 25.4352 | 0.0385631
3013304 | 06_Sixth Floor | 2639.96 | 208.8 | 0.316568
3013308 | 06_Sixth Floor | 2644.1 | 27.9 | 0.0423001 | Group: Domestic Hot Water 247
3013340 | 06_Sixth Floor | 2528 | 112.9 | 0.171171 | Group: Domestic Hot Water 249
3013342 | 06_Sixth Floor | 2639.96 | 79.9033 | 0.121144
3013344 | 06_Sixth Floor | 2639.96 | 25.4352 | 0.0385631
3013350 | 06_Sixth Floor | 2639.96 | 208.8 | 0.316568
3013354 | 06_Sixth Floor | 2644.1 | 27.9 | 0.0423001 | Group: Domestic Hot Water 249
3013386 | 06_Sixth Floor | 2528 | 112.9 | 0.171171 | Group: Domestic Hot Water 251
3013388 | 06_Sixth Floor | 2639.96 | 79.9033 | 0.121144
3013390 | 06_Sixth Floor | 2639.96 | 25.4352 | 0.0385631
3013396 | 06_Sixth Floor | 2639.96 | 208.8 | 0.316568
3013400 | 06_Sixth Floor | 2644.1 | 27.9 | 0.0423001 | Group: Domestic Hot Water 251
3013433 | 06_Sixth Floor | 2528 | 112.9 | 0.171171 | Group: Domestic Hot Water 253
3013435 | 06_Sixth Floor | 2639.96 | 79.9033 | 0.121144
3013437 | 06_Sixth Floor | 2639.96 | 25.4352 | 0.0385631
3013443 | 06_Sixth Floor | 2639.96 | 208.8 | 0.316568
3013447 | 06_Sixth Floor | 2644.1 | 27.9 | 0.0423001 | Group: Domestic Hot Water 253
3013479 | 06_Sixth Floor | 2528 | 112.9 | 0.171171 | Group: Domestic Hot Water 255
3013481 | 06_Sixth Floor | 2639.96 | 79.9033 | 0.121144
3013483 | 06_Sixth Floor | 2639.96 | 25.4352 | 0.0385631
3013489 | 06_Sixth Floor | 2639.96 | 208.8 | 0.316568
3013493 | 06_Sixth Floor | 2644.1 | 27.9 | 0.0423001 | Group: Domestic Hot Water 255
3013529 | 06_Sixth Floor | 2528 | 112.9 | 0.171171 | Group: Domestic Hot Water 257
3013531 | 06_Sixth Floor | 2639.96 | 79.9033 | 0.121144
3013533 | 06_Sixth Floor | 2639.96 | 25.4352 | 0.0385631
3013539 | 06_Sixth Floor | 2639.96 | 208.8 | 0.316568
3013543 | 06_Sixth Floor | 2644.1 | 27.9 | 0.0423001 | Group: Domestic Hot Water 257
3013575 | 06_Sixth Floor | 2528 | 112.9 | 0.171171 | Group: Domestic Hot Water 259
3013577 | 06_Sixth Floor | 2639.96 | 79.9033 | 0.121144
3013579 | 06_Sixth Floor | 2639.96 | 25.4352 | 0.0385631
3013585 | 06_Sixth Floor | 2639.96 | 208.8 | 0.316568
3013589 | 06_Sixth Floor | 2644.1 | 27.9 | 0.0423001 | Group: Domestic Hot Water 259
3013621 | 06_Sixth Floor | 2528 | 112.9 | 0.171171 | Group: Domestic Hot Water 261
3013623 | 06_Sixth Floor | 2639.96 | 79.9033 | 0.121144
3013625 | 06_Sixth Floor | 2639.96 | 25.4352 | 0.0385631
3013631 | 06_Sixth Floor | 2639.96 | 208.8 | 0.316568
3013635 | 06_Sixth Floor | 2644.1 | 27.9 | 0.0423001 | Group: Domestic Hot Water 261
3013667 | 06_Sixth Floor | 2528 | 112.9 | 0.171171 | Group: Domestic Hot Water 263
3013669 | 06_Sixth Floor | 2639.96 | 79.9033 | 0.121144
3013671 | 06_Sixth Floor | 2639.96 | 25.4352 | 0.0385631
3013677 | 06_Sixth Floor | 2639.96 | 208.8 | 0.316568
3013681 | 06_Sixth Floor | 2644.1 | 27.9 | 0.0423001 | Group: Domestic Hot Water 263
3013713 | 06_Sixth Floor | 2528 | 112.9 | 0.171171 | Group: Domestic Hot Water 265
3013715 | 06_Sixth Floor | 2639.96 | 79.9033 | 0.121144
3013717 | 06_Sixth Floor | 2639.96 | 25.4352 | 0.0385631
3013723 | 06_Sixth Floor | 2639.96 | 208.8 | 0.316568
3013727 | 06_Sixth Floor | 2644.1 | 27.9 | 0.0423001 | Group: Domestic Hot Water 265
3013760 | 06_Sixth Floor | 2528 | 112.9 | 0.171171 | Group: Domestic Hot Water 267
3013762 | 06_Sixth Floor | 2639.96 | 79.9033 | 0.121144
3013764 | 06_Sixth Floor | 2639.96 | 25.4352 | 0.0385631
3013770 | 06_Sixth Floor | 2639.96 | 208.8 | 0.316568
3013774 | 06_Sixth Floor | 2644.1 | 27.9 | 0.0423001 | Group: Domestic Hot Water 267
3013806 | 06_Sixth Floor | 2528 | 112.9 | 0.171171 | Group: Domestic Hot Water 269
3013808 | 06_Sixth Floor | 2639.96 | 79.9033 | 0.121144
3013810 | 06_Sixth Floor | 2639.96 | 25.4352 | 0.0385631
3013816 | 06_Sixth Floor | 2639.96 | 208.8 | 0.316568
3013820 | 06_Sixth Floor | 2644.1 | 27.9 | 0.0423001 | Group: Domestic Hot Water 269
3013856 | 06_Sixth Floor | 2528 | 112.9 | 0.171171 | Group: Domestic Hot Water 271
3013858 | 06_Sixth Floor | 2639.96 | 79.9033 | 0.121144
3013860 | 06_Sixth Floor | 2639.96 | 25.4352 | 0.0385631
3013866 | 06_Sixth Floor | 2639.96 | 208.8 | 0.316568
3013870 | 06_Sixth Floor | 2644.1 | 27.9 | 0.0423001 | Group: Domestic Hot Water 271
3013902 | 06_Sixth Floor | 2528 | 112.9 | 0.171171 | Group: Domestic Hot Water 273
3013904 | 06_Sixth Floor | 2639.96 | 79.9033 | 0.121144
3013906 | 06_Sixth Floor | 2639.96 | 25.4352 | 0.0385631
3013912 | 06_Sixth Floor | 2639.96 | 208.8 | 0.316568
3013916 | 06_Sixth Floor | 2644.1 | 27.9 | 0.0423001 | Group: Domestic Hot Water 273
3013948 | 06_Sixth Floor | 2528 | 112.9 | 0.171171 | Group: Domestic Hot Water 275
3013950 | 06_Sixth Floor | 2639.96 | 79.9033 | 0.121144
3013952 | 06_Sixth Floor | 2639.96 | 25.4352 | 0.0385631
3013958 | 06_Sixth Floor | 2639.96 | 208.8 | 0.316568
3013962 | 06_Sixth Floor | 2644.1 | 27.9 | 0.0423001 | Group: Domestic Hot Water 275
3013994 | 06_Sixth Floor | 2528 | 112.9 | 0.171171 | Group: Domestic Hot Water 277
3013996 | 06_Sixth Floor | 2639.96 | 79.9033 | 0.121144
3013998 | 06_Sixth Floor | 2639.96 | 25.4352 | 0.0385631
3014004 | 06_Sixth Floor | 2639.96 | 208.8 | 0.316568
3014008 | 06_Sixth Floor | 2644.1 | 27.9 | 0.0423001 | Group: Domestic Hot Water 277
3014040 | 06_Sixth Floor | 2528 | 112.9 | 0.171171 | Group: Domestic Hot Water 279
3014042 | 06_Sixth Floor | 2639.96 | 79.9033 | 0.121144
3014044 | 06_Sixth Floor | 2639.96 | 25.4352 | 0.0385631
3014050 | 06_Sixth Floor | 2639.96 | 208.8 | 0.316568
3014054 | 06_Sixth Floor | 2644.1 | 27.9 | 0.0423001 | Group: Domestic Hot Water 279
3014647 | 07_Seventh Floor | 2928 | 112.9 | 0.171171 | Group: Domestic Hot Water 99
3014649 | 07_Seventh Floor | 3039.96 | 79.9033 | 0.121144
3014651 | 07_Seventh Floor | 3039.96 | 25.4352 | 0.0385631
3014657 | 07_Seventh Floor | 3039.96 | 208.8 | 0.316568
3014661 | 07_Seventh Floor | 3044.1 | 27.9 | 0.0423001 | Group: Domestic Hot Water 99
3014693 | 07_Seventh Floor | 2928 | 112.9 | 0.171171 | Group: Domestic Hot Water 153
3014695 | 07_Seventh Floor | 3039.96 | 79.9033 | 0.121144
3014697 | 07_Seventh Floor | 3039.96 | 25.4352 | 0.0385631
3014703 | 07_Seventh Floor | 3039.96 | 208.8 | 0.316568
3014707 | 07_Seventh Floor | 3044.1 | 27.9 | 0.0423001 | Group: Domestic Hot Water 153
3014743 | 07_Seventh Floor | 2928 | 112.9 | 0.171171 | Group: Domestic Hot Water 180
3014745 | 07_Seventh Floor | 3039.96 | 79.9033 | 0.121144
3014747 | 07_Seventh Floor | 3039.96 | 25.4352 | 0.0385631
3014753 | 07_Seventh Floor | 3039.96 | 208.8 | 0.316568
3014757 | 07_Seventh Floor | 3044.1 | 27.9 | 0.0423001 | Group: Domestic Hot Water 180
3014789 | 07_Seventh Floor | 2928 | 112.9 | 0.171171 | Group: Domestic Hot Water 196
3014791 | 07_Seventh Floor | 3039.96 | 79.9033 | 0.121144
3014793 | 07_Seventh Floor | 3039.96 | 25.4352 | 0.0385631
3014799 | 07_Seventh Floor | 3039.96 | 208.8 | 0.316568
3014803 | 07_Seventh Floor | 3044.1 | 27.9 | 0.0423001 | Group: Domestic Hot Water 196
3014835 | 07_Seventh Floor | 2928 | 112.9 | 0.171171 | Group: Domestic Hot Water 211
3014837 | 07_Seventh Floor | 3039.96 | 79.9033 | 0.121144
3014839 | 07_Seventh Floor | 3039.96 | 25.4352 | 0.0385631
3014845 | 07_Seventh Floor | 3039.96 | 208.8 | 0.316568
3014849 | 07_Seventh Floor | 3044.1 | 27.9 | 0.0423001 | Group: Domestic Hot Water 211
3014881 | 07_Seventh Floor | 2928 | 112.9 | 0.171171 | Group: Domestic Hot Water 219
3014883 | 07_Seventh Floor | 3039.96 | 79.9033 | 0.121144
3014885 | 07_Seventh Floor | 3039.96 | 25.4352 | 0.0385631
3014891 | 07_Seventh Floor | 3039.96 | 208.8 | 0.316568
3014895 | 07_Seventh Floor | 3044.1 | 27.9 | 0.0423001 | Group: Domestic Hot Water 219
3014927 | 07_Seventh Floor | 2928 | 112.9 | 0.171171 | Group: Domestic Hot Water 227
3014929 | 07_Seventh Floor | 3039.96 | 79.9033 | 0.121144
3014931 | 07_Seventh Floor | 3039.96 | 25.4352 | 0.0385631
3014937 | 07_Seventh Floor | 3039.96 | 208.8 | 0.316568
3014941 | 07_Seventh Floor | 3044.1 | 27.9 | 0.0423001 | Group: Domestic Hot Water 227
3014974 | 07_Seventh Floor | 2928 | 112.9 | 0.171171 | Group: Domestic Hot Water 235
3014976 | 07_Seventh Floor | 3039.96 | 79.9033 | 0.121144
3014978 | 07_Seventh Floor | 3039.96 | 25.4352 | 0.0385631
3014984 | 07_Seventh Floor | 3039.96 | 208.8 | 0.316568
3014988 | 07_Seventh Floor | 3044.1 | 27.9 | 0.0423001 | Group: Domestic Hot Water 235
3015020 | 07_Seventh Floor | 2928 | 112.9 | 0.171171 | Group: Domestic Hot Water 243
3015022 | 07_Seventh Floor | 3039.96 | 79.9033 | 0.121144
3015024 | 07_Seventh Floor | 3039.96 | 25.4352 | 0.0385631
3015030 | 07_Seventh Floor | 3039.96 | 208.8 | 0.316568
3015034 | 07_Seventh Floor | 3044.1 | 27.9 | 0.0423001 | Group: Domestic Hot Water 243
3015070 | 07_Seventh Floor | 2928 | 112.9 | 0.171171 | Group: Domestic Hot Water 248
3015072 | 07_Seventh Floor | 3039.96 | 79.9033 | 0.121144
3015074 | 07_Seventh Floor | 3039.96 | 25.4352 | 0.0385631
3015080 | 07_Seventh Floor | 3039.96 | 208.8 | 0.316568
3015084 | 07_Seventh Floor | 3044.1 | 27.9 | 0.0423001 | Group: Domestic Hot Water 248
3015116 | 07_Seventh Floor | 2928 | 112.9 | 0.171171 | Group: Domestic Hot Water 252
3015118 | 07_Seventh Floor | 3039.96 | 79.9033 | 0.121144
3015120 | 07_Seventh Floor | 3039.96 | 25.4352 | 0.0385631
3015126 | 07_Seventh Floor | 3039.96 | 208.8 | 0.316568
3015130 | 07_Seventh Floor | 3044.1 | 27.9 | 0.0423001 | Group: Domestic Hot Water 252
3015162 | 07_Seventh Floor | 2928 | 112.9 | 0.171171 | Group: Domestic Hot Water 256
3015164 | 07_Seventh Floor | 3039.96 | 79.9033 | 0.121144
3015166 | 07_Seventh Floor | 3039.96 | 25.4352 | 0.0385631
3015172 | 07_Seventh Floor | 3039.96 | 208.8 | 0.316568
3015176 | 07_Seventh Floor | 3044.1 | 27.9 | 0.0423001 | Group: Domestic Hot Water 256
3015208 | 07_Seventh Floor | 2928 | 112.9 | 0.171171 | Group: Domestic Hot Water 260
3015210 | 07_Seventh Floor | 3039.96 | 79.9033 | 0.121144
3015212 | 07_Seventh Floor | 3039.96 | 25.4352 | 0.0385631
3015218 | 07_Seventh Floor | 3039.96 | 208.8 | 0.316568
3015222 | 07_Seventh Floor | 3044.1 | 27.9 | 0.0423001 | Group: Domestic Hot Water 260
3015254 | 07_Seventh Floor | 2928 | 112.9 | 0.171171 | Group: Domestic Hot Water 264
3015256 | 07_Seventh Floor | 3039.96 | 79.9033 | 0.121144
3015258 | 07_Seventh Floor | 3039.96 | 25.4352 | 0.0385631
3015264 | 07_Seventh Floor | 3039.96 | 208.8 | 0.316568
3015268 | 07_Seventh Floor | 3044.1 | 27.9 | 0.0423001 | Group: Domestic Hot Water 264
3015301 | 07_Seventh Floor | 2928 | 112.9 | 0.171171 | Group: Domestic Hot Water 268
3015303 | 07_Seventh Floor | 3039.96 | 79.9033 | 0.121144
3015305 | 07_Seventh Floor | 3039.96 | 25.4352 | 0.0385631
3015311 | 07_Seventh Floor | 3039.96 | 208.8 | 0.316568
3015315 | 07_Seventh Floor | 3044.1 | 27.9 | 0.0423001 | Group: Domestic Hot Water 268
3015347 | 07_Seventh Floor | 2928 | 112.9 | 0.171171 | Group: Domestic Hot Water 272
3015349 | 07_Seventh Floor | 3039.96 | 79.9033 | 0.121144
3015351 | 07_Seventh Floor | 3039.96 | 25.4352 | 0.0385631
3015357 | 07_Seventh Floor | 3039.96 | 208.8 | 0.316568
3015361 | 07_Seventh Floor | 3044.1 | 27.9 | 0.0423001 | Group: Domestic Hot Water 272
3015397 | 07_Seventh Floor | 2928 | 112.9 | 0.171171 | Group: Domestic Hot Water 276
3015399 | 07_Seventh Floor | 3039.96 | 79.9033 | 0.121144
3015401 | 07_Seventh Floor | 3039.96 | 25.4352 | 0.0385631
3015407 | 07_Seventh Floor | 3039.96 | 208.8 | 0.316568
3015411 | 07_Seventh Floor | 3044.1 | 27.9 | 0.0423001 | Group: Domestic Hot Water 276
3015443 | 07_Seventh Floor | 2928 | 112.9 | 0.171171 | Group: Domestic Hot Water 280
3015445 | 07_Seventh Floor | 3039.96 | 79.9033 | 0.121144
3015447 | 07_Seventh Floor | 3039.96 | 25.4352 | 0.0385631
3015453 | 07_Seventh Floor | 3039.96 | 208.8 | 0.316568
3015457 | 07_Seventh Floor | 3044.1 | 27.9 | 0.0423001 | Group: Domestic Hot Water 280
3015489 | 07_Seventh Floor | 2928 | 112.9 | 0.171171 | Group: Domestic Hot Water 282
3015491 | 07_Seventh Floor | 3039.96 | 79.9033 | 0.121144
3015493 | 07_Seventh Floor | 3039.96 | 25.4352 | 0.0385631
3015499 | 07_Seventh Floor | 3039.96 | 208.8 | 0.316568
3015503 | 07_Seventh Floor | 3044.1 | 27.9 | 0.0423001 | Group: Domestic Hot Water 282
3015535 | 07_Seventh Floor | 2928 | 112.9 | 0.171171 | Group: Domestic Hot Water 284
3015537 | 07_Seventh Floor | 3039.96 | 79.9033 | 0.121144
3015539 | 07_Seventh Floor | 3039.96 | 25.4352 | 0.0385631
3015545 | 07_Seventh Floor | 3039.96 | 208.8 | 0.316568
3015549 | 07_Seventh Floor | 3044.1 | 27.9 | 0.0423001 | Group: Domestic Hot Water 284
3015581 | 07_Seventh Floor | 2928 | 112.9 | 0.171171 | Group: Domestic Hot Water 286
3015583 | 07_Seventh Floor | 3039.96 | 79.9033 | 0.121144
3015585 | 07_Seventh Floor | 3039.96 | 25.4352 | 0.0385631
3015591 | 07_Seventh Floor | 3039.96 | 208.8 | 0.316568
3015595 | 07_Seventh Floor | 3044.1 | 27.9 | 0.0423001 | Group: Domestic Hot Water 286
3015628 | 07_Seventh Floor | 2928 | 112.9 | 0.171171 | Group: Domestic Hot Water 288
3015630 | 07_Seventh Floor | 3039.96 | 79.9033 | 0.121144
3015632 | 07_Seventh Floor | 3039.96 | 25.4352 | 0.0385631
3015638 | 07_Seventh Floor | 3039.96 | 208.8 | 0.316568
3015642 | 07_Seventh Floor | 3044.1 | 27.9 | 0.0423001 | Group: Domestic Hot Water 288
3015674 | 07_Seventh Floor | 2928 | 112.9 | 0.171171 | Group: Domestic Hot Water 290
3015676 | 07_Seventh Floor | 3039.96 | 79.9033 | 0.121144
3015678 | 07_Seventh Floor | 3039.96 | 25.4352 | 0.0385631
3015684 | 07_Seventh Floor | 3039.96 | 208.8 | 0.316568
3015688 | 07_Seventh Floor | 3044.1 | 27.9 | 0.0423001 | Group: Domestic Hot Water 290
3015724 | 07_Seventh Floor | 2928 | 112.9 | 0.171171 | Group: Domestic Hot Water 292
3015726 | 07_Seventh Floor | 3039.96 | 79.9033 | 0.121144
3015728 | 07_Seventh Floor | 3039.96 | 25.4352 | 0.0385631
3015734 | 07_Seventh Floor | 3039.96 | 208.8 | 0.316568
3015738 | 07_Seventh Floor | 3044.1 | 27.9 | 0.0423001 | Group: Domestic Hot Water 292
3015770 | 07_Seventh Floor | 2928 | 112.9 | 0.171171 | Group: Domestic Hot Water 294
3015772 | 07_Seventh Floor | 3039.96 | 79.9033 | 0.121144
3015774 | 07_Seventh Floor | 3039.96 | 25.4352 | 0.0385631
3015780 | 07_Seventh Floor | 3039.96 | 208.8 | 0.316568
3015784 | 07_Seventh Floor | 3044.1 | 27.9 | 0.0423001 | Group: Domestic Hot Water 294
3015816 | 07_Seventh Floor | 2928 | 112.9 | 0.171171 | Group: Domestic Hot Water 296
3015818 | 07_Seventh Floor | 3039.96 | 79.9033 | 0.121144
3015820 | 07_Seventh Floor | 3039.96 | 25.4352 | 0.0385631
3015826 | 07_Seventh Floor | 3039.96 | 208.8 | 0.316568
3015830 | 07_Seventh Floor | 3044.1 | 27.9 | 0.0423001 | Group: Domestic Hot Water 296
3015862 | 07_Seventh Floor | 2928 | 112.9 | 0.171171 | Group: Domestic Hot Water 298
3015864 | 07_Seventh Floor | 3039.96 | 79.9033 | 0.121144
3015866 | 07_Seventh Floor | 3039.96 | 25.4352 | 0.0385631
3015872 | 07_Seventh Floor | 3039.96 | 208.8 | 0.316568
3015876 | 07_Seventh Floor | 3044.1 | 27.9 | 0.0423001 | Group: Domestic Hot Water 298
3015908 | 07_Seventh Floor | 2928 | 112.9 | 0.171171 | Group: Domestic Hot Water 300
3015910 | 07_Seventh Floor | 3039.96 | 79.9033 | 0.121144
3015912 | 07_Seventh Floor | 3039.96 | 25.4352 | 0.0385631
3015918 | 07_Seventh Floor | 3039.96 | 208.8 | 0.316568
3015922 | 07_Seventh Floor | 3044.1 | 27.9 | 0.0423001 | Group: Domestic Hot Water 300
3015955 | 07_Seventh Floor | 2928 | 112.9 | 0.171171 | Group: Domestic Hot Water 302
3015957 | 07_Seventh Floor | 3039.96 | 79.9033 | 0.121144
3015959 | 07_Seventh Floor | 3039.96 | 25.4352 | 0.0385631
3015965 | 07_Seventh Floor | 3039.96 | 208.8 | 0.316568
3015969 | 07_Seventh Floor | 3044.1 | 27.9 | 0.0423001 | Group: Domestic Hot Water 302
3016001 | 07_Seventh Floor | 2928 | 112.9 | 0.171171 | Group: Domestic Hot Water 304
3016003 | 07_Seventh Floor | 3039.96 | 79.9033 | 0.121144
3016005 | 07_Seventh Floor | 3039.96 | 25.4352 | 0.0385631
3016011 | 07_Seventh Floor | 3039.96 | 208.8 | 0.316568
3016015 | 07_Seventh Floor | 3044.1 | 27.9 | 0.0423001 | Group: Domestic Hot Water 304
3016051 | 07_Seventh Floor | 2928 | 112.9 | 0.171171 | Group: Domestic Hot Water 306
3016053 | 07_Seventh Floor | 3039.96 | 79.9033 | 0.121144
3016055 | 07_Seventh Floor | 3039.96 | 25.4352 | 0.0385631
3016061 | 07_Seventh Floor | 3039.96 | 208.8 | 0.316568
3016065 | 07_Seventh Floor | 3044.1 | 27.9 | 0.0423001 | Group: Domestic Hot Water 306
3016097 | 07_Seventh Floor | 2928 | 112.9 | 0.171171 | Group: Domestic Hot Water 308
3016099 | 07_Seventh Floor | 3039.96 | 79.9033 | 0.121144
3016101 | 07_Seventh Floor | 3039.96 | 25.4352 | 0.0385631
3016107 | 07_Seventh Floor | 3039.96 | 208.8 | 0.316568
3016111 | 07_Seventh Floor | 3044.1 | 27.9 | 0.0423001 | Group: Domestic Hot Water 308
3016143 | 07_Seventh Floor | 2928 | 112.9 | 0.171171 | Group: Domestic Hot Water 310
3016145 | 07_Seventh Floor | 3039.96 | 79.9033 | 0.121144
3016147 | 07_Seventh Floor | 3039.96 | 25.4352 | 0.0385631
3016153 | 07_Seventh Floor | 3039.96 | 208.8 | 0.316568
3016157 | 07_Seventh Floor | 3044.1 | 27.9 | 0.0423001 | Group: Domestic Hot Water 310
3016189 | 07_Seventh Floor | 2928 | 112.9 | 0.171171 | Group: Domestic Hot Water 312
3016191 | 07_Seventh Floor | 3039.96 | 79.9033 | 0.121144
3016193 | 07_Seventh Floor | 3039.96 | 25.4352 | 0.0385631
3016199 | 07_Seventh Floor | 3039.96 | 208.8 | 0.316568
3016203 | 07_Seventh Floor | 3044.1 | 27.9 | 0.0423001 | Group: Domestic Hot Water 312
3016235 | 07_Seventh Floor | 2928 | 112.9 | 0.171171 | Group: Domestic Hot Water 314
3016237 | 07_Seventh Floor | 3039.96 | 79.9033 | 0.121144
3016239 | 07_Seventh Floor | 3039.96 | 25.4352 | 0.0385631
3016245 | 07_Seventh Floor | 3039.96 | 208.8 | 0.316568
3016249 | 07_Seventh Floor | 3044.1 | 27.9 | 0.0423001 | Group: Domestic Hot Water 314

# IfcPlate: System Panel:Glazed (656)
Type - PredefinedType: CURTAIN_PANEL; Material: ARC_FME.o1_glass_00_gen_BERSnl
Pset_EnvironmentalImpactIndicators - Reference: Glazed
Pset_PlateCommon - IsExternal: yes; Reference: Glazed
Name (System Panel:Glazed:...) | In | Width (cm) | GrossArea (m2) = NetArea (m2) | NetVolume (m3)
3000427 | 00_Ground Floor | 93.8431 | 2.23347 | 0.111673
3000430 | 00_Ground Floor | 93.8431 | 2.23347 | 0.111673
3000432 | 00_Ground Floor | 93.8431 | 2.23347 | 0.111673
3000434 | 00_Ground Floor | 93.8431 | 2.23347 | 0.111673
3000436 | 00_Ground Floor | 93.8431 | 2.23347 | 0.111673
3000438 | 00_Ground Floor | 93.8431 | 2.23347 | 0.111673
3000440 | 00_Ground Floor | 93.8431 | 2.23347 | 0.111673
3000442 | 00_Ground Floor | 93.8431 | 2.23347 | 0.111673
3000444 | 00_Ground Floor | 93.8431 | 2.23347 | 0.111673
3000446 | 00_Ground Floor | 93.8431 | 2.23347 | 0.111673
3000448 | 00_Ground Floor | 93.8431 | 2.23347 | 0.111673
3000450 | 00_Ground Floor | 93.8431 | 2.23347 | 0.111673
3000452 | 00_Ground Floor | 93.8431 | 2.23347 | 0.111673
3000454 | 00_Ground Floor | 93.8431 | 2.23347 | 0.111673
3000456 | 00_Ground Floor | 93.8431 | 2.23347 | 0.111673
3000458 | 00_Ground Floor | 93.8431 | 2.23347 | 0.111673
3000460 | 00_Ground Floor | 93.8431 | 2.23347 | 0.111673
3000462 | 00_Ground Floor | 93.8431 | 2.23347 | 0.111673
3000464 | 00_Ground Floor | 93.8431 | 2.23347 | 0.111673
3000466 | 00_Ground Floor | 93.8431 | 2.23347 | 0.111673
3000468 | 00_Ground Floor | 93.8431 | 2.23347 | 0.111673
3000470 | 00_Ground Floor | 93.8431 | 2.23347 | 0.111673
3000472 | 00_Ground Floor | 93.8431 | 2.23347 | 0.111673
3000474 | 00_Ground Floor | 93.8431 | 2.23347 | 0.111673
3000476 | 00_Ground Floor | 93.8431 | 2.23347 | 0.111673
3000478 | 00_Ground Floor | 93.8431 | 2.23347 | 0.111673
3000480 | 00_Ground Floor | 93.8431 | 2.23347 | 0.111673
3000482 | 00_Ground Floor | 93.8431 | 2.23347 | 0.111673
3000484 | 00_Ground Floor | 93.8431 | 2.23347 | 0.111673
3000486 | 00_Ground Floor | 93.8431 | 2.23347 | 0.111673
3000488 | 00_Ground Floor | 93.8431 | 2.23347 | 0.111673
3000490 | 00_Ground Floor | 93.8431 | 2.23347 | 0.111673
3000492 | 00_Ground Floor | 93.8431 | 2.23347 | 0.111673
3000494 | 00_Ground Floor | 93.8431 | 2.23347 | 0.111673
3000496 | 00_Ground Floor | 93.8431 | 2.23347 | 0.111673
3000498 | 00_Ground Floor | 93.8431 | 2.23347 | 0.111673
3000500 | 00_Ground Floor | 93.8431 | 2.23347 | 0.111673
3000502 | 00_Ground Floor | 93.8431 | 2.23347 | 0.111673
3000504 | 00_Ground Floor | 93.8431 | 2.23347 | 0.111673
3000506 | 00_Ground Floor | 93.8431 | 2.23347 | 0.111673
3000508 | 00_Ground Floor | 93.8431 | 2.23347 | 0.111673
3000510 | 00_Ground Floor | 93.8431 | 2.23347 | 0.111673
3000512 | 00_Ground Floor | 93.8431 | 2.23347 | 0.111673
3000514 | 00_Ground Floor | 93.8431 | 2.23347 | 0.111673
3000516 | 00_Ground Floor | 93.8431 | 2.23347 | 0.111673
3000518 | 00_Ground Floor | 93.8431 | 2.23347 | 0.111673
3000520 | 00_Ground Floor | 93.8431 | 2.23347 | 0.111673
3000522 | 00_Ground Floor | 93.8431 | 2.23347 | 0.111673
3000524 | 00_Ground Floor | 93.8431 | 2.23347 | 0.111673
3000526 | 00_Ground Floor | 93.8431 | 2.23347 | 0.111673
3000528 | 00_Ground Floor | 93.8431 | 2.23347 | 0.111673
3001062 | 00_Ground Floor | 92.1935 | 2.19421 | 0.10971
3001065 | 00_Ground Floor | 92.1935 | 2.19421 | 0.10971
3001067 | 00_Ground Floor | 92.1935 | 2.19421 | 0.10971
3001069 | 00_Ground Floor | 92.1935 | 2.19421 | 0.10971
3001071 | 00_Ground Floor | 92.1935 | 2.19421 | 0.10971
3001073 | 00_Ground Floor | 92.1935 | 2.19421 | 0.10971
3001075 | 00_Ground Floor | 92.1935 | 2.19421 | 0.10971
3001077 | 00_Ground Floor | 92.1935 | 2.19421 | 0.10971
3001079 | 00_Ground Floor | 92.1935 | 2.19421 | 0.10971
3001081 | 00_Ground Floor | 92.1935 | 2.19421 | 0.10971
3001083 | 00_Ground Floor | 92.1935 | 2.19421 | 0.10971
3001085 | 00_Ground Floor | 92.1935 | 2.19421 | 0.10971
3001087 | 00_Ground Floor | 92.1935 | 2.19421 | 0.10971
3001089 | 00_Ground Floor | 92.1935 | 2.19421 | 0.10971
3001091 | 00_Ground Floor | 92.1935 | 2.19421 | 0.10971
3001093 | 00_Ground Floor | 92.1935 | 2.19421 | 0.10971
3001095 | 00_Ground Floor | 92.1935 | 2.19421 | 0.10971
3001097 | 00_Ground Floor | 92.1935 | 2.19421 | 0.10971
3001099 | 00_Ground Floor | 92.1935 | 2.19421 | 0.10971
3001101 | 00_Ground Floor | 92.1935 | 2.19421 | 0.10971
3001103 | 00_Ground Floor | 92.1935 | 2.19421 | 0.10971
3001105 | 00_Ground Floor | 92.1935 | 2.19421 | 0.10971
3001107 | 00_Ground Floor | 92.1935 | 2.19421 | 0.10971
3001109 | 00_Ground Floor | 92.1935 | 2.19421 | 0.10971
3001111 | 00_Ground Floor | 92.1935 | 2.19421 | 0.10971
3001113 | 00_Ground Floor | 92.1935 | 2.19421 | 0.10971
3001115 | 00_Ground Floor | 92.1935 | 2.19421 | 0.10971
3001117 | 00_Ground Floor | 92.1935 | 2.19421 | 0.10971
3001119 | 00_Ground Floor | 92.1935 | 2.19421 | 0.10971
3001121 | 00_Ground Floor | 92.1935 | 2.19421 | 0.10971
3001123 | 00_Ground Floor | 92.1935 | 2.19421 | 0.10971
3003141 | 01_First Floor | 93.8431 | 2.23347 | 0.111673
3003143 | 01_First Floor | 93.8431 | 2.23347 | 0.111673
3003145 | 01_First Floor | 93.8431 | 2.23347 | 0.111673
3003147 | 01_First Floor | 93.8431 | 2.23347 | 0.111673
3003149 | 01_First Floor | 93.8431 | 2.23347 | 0.111673
3003151 | 01_First Floor | 93.8431 | 2.23347 | 0.111673
3003153 | 01_First Floor | 93.8431 | 2.23347 | 0.111673
3003155 | 01_First Floor | 93.8431 | 2.23347 | 0.111673
3003157 | 01_First Floor | 93.8431 | 2.23347 | 0.111673
3003159 | 01_First Floor | 93.8431 | 2.23347 | 0.111673
3003161 | 01_First Floor | 93.8431 | 2.23347 | 0.111673
3003163 | 01_First Floor | 93.8431 | 2.23347 | 0.111673
3003165 | 01_First Floor | 93.8431 | 2.23347 | 0.111673
3003167 | 01_First Floor | 93.8431 | 2.23347 | 0.111673
3003169 | 01_First Floor | 93.8431 | 2.23347 | 0.111673
3003171 | 01_First Floor | 93.8431 | 2.23347 | 0.111673
3003173 | 01_First Floor | 93.8431 | 2.23347 | 0.111673
3003175 | 01_First Floor | 93.8431 | 2.23347 | 0.111673
3003177 | 01_First Floor | 93.8431 | 2.23347 | 0.111673
3003179 | 01_First Floor | 93.8431 | 2.23347 | 0.111673
3003181 | 01_First Floor | 93.8431 | 2.23347 | 0.111673
3003183 | 01_First Floor | 93.8431 | 2.23347 | 0.111673
3003185 | 01_First Floor | 93.8431 | 2.23347 | 0.111673
3003187 | 01_First Floor | 93.8431 | 2.23347 | 0.111673
3003189 | 01_First Floor | 93.8431 | 2.23347 | 0.111673
3003191 | 01_First Floor | 93.8431 | 2.23347 | 0.111673
3003193 | 01_First Floor | 93.8431 | 2.23347 | 0.111673
3003195 | 01_First Floor | 93.8431 | 2.23347 | 0.111673
3003197 | 01_First Floor | 93.8431 | 2.23347 | 0.111673
3003199 | 01_First Floor | 93.8431 | 2.23347 | 0.111673
3003201 | 01_First Floor | 93.8431 | 2.23347 | 0.111673
3003203 | 01_First Floor | 93.8431 | 2.23347 | 0.111673
3003205 | 01_First Floor | 93.8431 | 2.23347 | 0.111673
3003207 | 01_First Floor | 93.8431 | 2.23347 | 0.111673
3003209 | 01_First Floor | 93.8431 | 2.23347 | 0.111673
3003211 | 01_First Floor | 93.8431 | 2.23347 | 0.111673
3003213 | 01_First Floor | 93.8431 | 2.23347 | 0.111673
3003215 | 01_First Floor | 93.8431 | 2.23347 | 0.111673
3003217 | 01_First Floor | 93.8431 | 2.23347 | 0.111673
3003219 | 01_First Floor | 93.8431 | 2.23347 | 0.111673
3003221 | 01_First Floor | 93.8431 | 2.23347 | 0.111673
3003223 | 01_First Floor | 93.8431 | 2.23347 | 0.111673
3003225 | 01_First Floor | 93.8431 | 2.23347 | 0.111673
3003227 | 01_First Floor | 93.8431 | 2.23347 | 0.111673
3003229 | 01_First Floor | 93.8431 | 2.23347 | 0.111673
3003231 | 01_First Floor | 93.8431 | 2.23347 | 0.111673
3003233 | 01_First Floor | 93.8431 | 2.23347 | 0.111673
3003235 | 01_First Floor | 93.8431 | 2.23347 | 0.111673
3003237 | 01_First Floor | 93.8431 | 2.23347 | 0.111673
3003239 | 01_First Floor | 93.8431 | 2.23347 | 0.111673
3003241 | 01_First Floor | 93.8431 | 2.23347 | 0.111673
3003397 | 01_First Floor | 92.1935 | 2.19421 | 0.10971
3003399 | 01_First Floor | 92.1935 | 2.19421 | 0.10971
3003401 | 01_First Floor | 92.1935 | 2.19421 | 0.10971
3003403 | 01_First Floor | 92.1935 | 2.19421 | 0.10971
3003405 | 01_First Floor | 92.1935 | 2.19421 | 0.10971
3003407 | 01_First Floor | 92.1935 | 2.19421 | 0.10971
3003409 | 01_First Floor | 92.1935 | 2.19421 | 0.10971
3003411 | 01_First Floor | 92.1935 | 2.19421 | 0.10971
3003413 | 01_First Floor | 92.1935 | 2.19421 | 0.10971
3003415 | 01_First Floor | 92.1935 | 2.19421 | 0.10971
3003417 | 01_First Floor | 92.1935 | 2.19421 | 0.10971
3003419 | 01_First Floor | 92.1935 | 2.19421 | 0.10971
3003421 | 01_First Floor | 92.1935 | 2.19421 | 0.10971
3003423 | 01_First Floor | 92.1935 | 2.19421 | 0.10971
3003425 | 01_First Floor | 92.1935 | 2.19421 | 0.10971
3003427 | 01_First Floor | 92.1935 | 2.19421 | 0.10971
3003429 | 01_First Floor | 92.1935 | 2.19421 | 0.10971
3003431 | 01_First Floor | 92.1935 | 2.19421 | 0.10971
3003433 | 01_First Floor | 92.1935 | 2.19421 | 0.10971
3003435 | 01_First Floor | 92.1935 | 2.19421 | 0.10971
3003437 | 01_First Floor | 92.1935 | 2.19421 | 0.10971
3003439 | 01_First Floor | 92.1935 | 2.19421 | 0.10971
3003441 | 01_First Floor | 92.1935 | 2.19421 | 0.10971
3003443 | 01_First Floor | 92.1935 | 2.19421 | 0.10971
3003445 | 01_First Floor | 92.1935 | 2.19421 | 0.10971
3003447 | 01_First Floor | 92.1935 | 2.19421 | 0.10971
3003449 | 01_First Floor | 92.1935 | 2.19421 | 0.10971
3003451 | 01_First Floor | 92.1935 | 2.19421 | 0.10971
3003453 | 01_First Floor | 92.1935 | 2.19421 | 0.10971
3003455 | 01_First Floor | 92.1935 | 2.19421 | 0.10971
3003457 | 01_First Floor | 92.1935 | 2.19421 | 0.10971
3005334 | 02_Second Floor | 93.8431 | 2.23347 | 0.111673
3005336 | 02_Second Floor | 93.8431 | 2.23347 | 0.111673
3005338 | 02_Second Floor | 93.8431 | 2.23347 | 0.111673
3005340 | 02_Second Floor | 93.8431 | 2.23347 | 0.111673
3005342 | 02_Second Floor | 93.8431 | 2.23347 | 0.111673
3005344 | 02_Second Floor | 93.8431 | 2.23347 | 0.111673
3005346 | 02_Second Floor | 93.8431 | 2.23347 | 0.111673
3005348 | 02_Second Floor | 93.8431 | 2.23347 | 0.111673
3005350 | 02_Second Floor | 93.8431 | 2.23347 | 0.111673
3005352 | 02_Second Floor | 93.8431 | 2.23347 | 0.111673
3005354 | 02_Second Floor | 93.8431 | 2.23347 | 0.111673
3005356 | 02_Second Floor | 93.8431 | 2.23347 | 0.111673
3005358 | 02_Second Floor | 93.8431 | 2.23347 | 0.111673
3005360 | 02_Second Floor | 93.8431 | 2.23347 | 0.111673
3005362 | 02_Second Floor | 93.8431 | 2.23347 | 0.111673
3005364 | 02_Second Floor | 93.8431 | 2.23347 | 0.111673
3005366 | 02_Second Floor | 93.8431 | 2.23347 | 0.111673
3005368 | 02_Second Floor | 93.8431 | 2.23347 | 0.111673
3005370 | 02_Second Floor | 93.8431 | 2.23347 | 0.111673
3005372 | 02_Second Floor | 93.8431 | 2.23347 | 0.111673
3005374 | 02_Second Floor | 93.8431 | 2.23347 | 0.111673
3005376 | 02_Second Floor | 93.8431 | 2.23347 | 0.111673
3005378 | 02_Second Floor | 93.8431 | 2.23347 | 0.111673
3005380 | 02_Second Floor | 93.8431 | 2.23347 | 0.111673
3005382 | 02_Second Floor | 93.8431 | 2.23347 | 0.111673
3005384 | 02_Second Floor | 93.8431 | 2.23347 | 0.111673
3005386 | 02_Second Floor | 93.8431 | 2.23347 | 0.111673
3005388 | 02_Second Floor | 93.8431 | 2.23347 | 0.111673
3005390 | 02_Second Floor | 93.8431 | 2.23347 | 0.111673
3005392 | 02_Second Floor | 93.8431 | 2.23347 | 0.111673
3005394 | 02_Second Floor | 93.8431 | 2.23347 | 0.111673
3005396 | 02_Second Floor | 93.8431 | 2.23347 | 0.111673
3005398 | 02_Second Floor | 93.8431 | 2.23347 | 0.111673
3005400 | 02_Second Floor | 93.8431 | 2.23347 | 0.111673
3005402 | 02_Second Floor | 93.8431 | 2.23347 | 0.111673
3005404 | 02_Second Floor | 93.8431 | 2.23347 | 0.111673
3005406 | 02_Second Floor | 93.8431 | 2.23347 | 0.111673
3005408 | 02_Second Floor | 93.8431 | 2.23347 | 0.111673
3005410 | 02_Second Floor | 93.8431 | 2.23347 | 0.111673
3005412 | 02_Second Floor | 93.8431 | 2.23347 | 0.111673
3005414 | 02_Second Floor | 93.8431 | 2.23347 | 0.111673
3005416 | 02_Second Floor | 93.8431 | 2.23347 | 0.111673
3005418 | 02_Second Floor | 93.8431 | 2.23347 | 0.111673
3005420 | 02_Second Floor | 93.8431 | 2.23347 | 0.111673
3005422 | 02_Second Floor | 93.8431 | 2.23347 | 0.111673
3005424 | 02_Second Floor | 93.8431 | 2.23347 | 0.111673
3005426 | 02_Second Floor | 93.8431 | 2.23347 | 0.111673
3005428 | 02_Second Floor | 93.8431 | 2.23347 | 0.111673
3005430 | 02_Second Floor | 93.8431 | 2.23347 | 0.111673
3005432 | 02_Second Floor | 93.8431 | 2.23347 | 0.111673
3005434 | 02_Second Floor | 93.8431 | 2.23347 | 0.111673
3005590 | 02_Second Floor | 92.1935 | 2.19421 | 0.10971
3005592 | 02_Second Floor | 92.1935 | 2.19421 | 0.10971
3005594 | 02_Second Floor | 92.1935 | 2.19421 | 0.10971
3005596 | 02_Second Floor | 92.1935 | 2.19421 | 0.10971
3005598 | 02_Second Floor | 92.1935 | 2.19421 | 0.10971
3005600 | 02_Second Floor | 92.1935 | 2.19421 | 0.10971
3005602 | 02_Second Floor | 92.1935 | 2.19421 | 0.10971
3005604 | 02_Second Floor | 92.1935 | 2.19421 | 0.10971
3005606 | 02_Second Floor | 92.1935 | 2.19421 | 0.10971
3005608 | 02_Second Floor | 92.1935 | 2.19421 | 0.10971
3005610 | 02_Second Floor | 92.1935 | 2.19421 | 0.10971
3005612 | 02_Second Floor | 92.1935 | 2.19421 | 0.10971
3005614 | 02_Second Floor | 92.1935 | 2.19421 | 0.10971
3005616 | 02_Second Floor | 92.1935 | 2.19421 | 0.10971
3005618 | 02_Second Floor | 92.1935 | 2.19421 | 0.10971
3005620 | 02_Second Floor | 92.1935 | 2.19421 | 0.10971
3005622 | 02_Second Floor | 92.1935 | 2.19421 | 0.10971
3005624 | 02_Second Floor | 92.1935 | 2.19421 | 0.10971
3005626 | 02_Second Floor | 92.1935 | 2.19421 | 0.10971
3005628 | 02_Second Floor | 92.1935 | 2.19421 | 0.10971
3005630 | 02_Second Floor | 92.1935 | 2.19421 | 0.10971
3005632 | 02_Second Floor | 92.1935 | 2.19421 | 0.10971
3005634 | 02_Second Floor | 92.1935 | 2.19421 | 0.10971
3005636 | 02_Second Floor | 92.1935 | 2.19421 | 0.10971
3005638 | 02_Second Floor | 92.1935 | 2.19421 | 0.10971
3005640 | 02_Second Floor | 92.1935 | 2.19421 | 0.10971
3005642 | 02_Second Floor | 92.1935 | 2.19421 | 0.10971
3005644 | 02_Second Floor | 92.1935 | 2.19421 | 0.10971
3005646 | 02_Second Floor | 92.1935 | 2.19421 | 0.10971
3005648 | 02_Second Floor | 92.1935 | 2.19421 | 0.10971
3005650 | 02_Second Floor | 92.1935 | 2.19421 | 0.10971
3007531 | 03_Third Floor | 93.8431 | 2.23347 | 0.111673
3007533 | 03_Third Floor | 93.8431 | 2.23347 | 0.111673
3007535 | 03_Third Floor | 93.8431 | 2.23347 | 0.111673
3007537 | 03_Third Floor | 93.8431 | 2.23347 | 0.111673
3007539 | 03_Third Floor | 93.8431 | 2.23347 | 0.111673
3007541 | 03_Third Floor | 93.8431 | 2.23347 | 0.111673
3007543 | 03_Third Floor | 93.8431 | 2.23347 | 0.111673
3007545 | 03_Third Floor | 93.8431 | 2.23347 | 0.111673
3007547 | 03_Third Floor | 93.8431 | 2.23347 | 0.111673
3007549 | 03_Third Floor | 93.8431 | 2.23347 | 0.111673
3007551 | 03_Third Floor | 93.8431 | 2.23347 | 0.111673
3007553 | 03_Third Floor | 93.8431 | 2.23347 | 0.111673
3007555 | 03_Third Floor | 93.8431 | 2.23347 | 0.111673
3007557 | 03_Third Floor | 93.8431 | 2.23347 | 0.111673
3007559 | 03_Third Floor | 93.8431 | 2.23347 | 0.111673
3007561 | 03_Third Floor | 93.8431 | 2.23347 | 0.111673
3007563 | 03_Third Floor | 93.8431 | 2.23347 | 0.111673
3007565 | 03_Third Floor | 93.8431 | 2.23347 | 0.111673
3007567 | 03_Third Floor | 93.8431 | 2.23347 | 0.111673
3007569 | 03_Third Floor | 93.8431 | 2.23347 | 0.111673
3007571 | 03_Third Floor | 93.8431 | 2.23347 | 0.111673
3007573 | 03_Third Floor | 93.8431 | 2.23347 | 0.111673
3007575 | 03_Third Floor | 93.8431 | 2.23347 | 0.111673
3007577 | 03_Third Floor | 93.8431 | 2.23347 | 0.111673
3007579 | 03_Third Floor | 93.8431 | 2.23347 | 0.111673
3007581 | 03_Third Floor | 93.8431 | 2.23347 | 0.111673
3007583 | 03_Third Floor | 93.8431 | 2.23347 | 0.111673
3007585 | 03_Third Floor | 93.8431 | 2.23347 | 0.111673
3007587 | 03_Third Floor | 93.8431 | 2.23347 | 0.111673
3007589 | 03_Third Floor | 93.8431 | 2.23347 | 0.111673
3007591 | 03_Third Floor | 93.8431 | 2.23347 | 0.111673
3007593 | 03_Third Floor | 93.8431 | 2.23347 | 0.111673
3007595 | 03_Third Floor | 93.8431 | 2.23347 | 0.111673
3007597 | 03_Third Floor | 93.8431 | 2.23347 | 0.111673
3007599 | 03_Third Floor | 93.8431 | 2.23347 | 0.111673
3007601 | 03_Third Floor | 93.8431 | 2.23347 | 0.111673
3007603 | 03_Third Floor | 93.8431 | 2.23347 | 0.111673
3007605 | 03_Third Floor | 93.8431 | 2.23347 | 0.111673
3007607 | 03_Third Floor | 93.8431 | 2.23347 | 0.111673
3007609 | 03_Third Floor | 93.8431 | 2.23347 | 0.111673
3007611 | 03_Third Floor | 93.8431 | 2.23347 | 0.111673
3007613 | 03_Third Floor | 93.8431 | 2.23347 | 0.111673
3007615 | 03_Third Floor | 93.8431 | 2.23347 | 0.111673
3007617 | 03_Third Floor | 93.8431 | 2.23347 | 0.111673
3007619 | 03_Third Floor | 93.8431 | 2.23347 | 0.111673
3007621 | 03_Third Floor | 93.8431 | 2.23347 | 0.111673
3007623 | 03_Third Floor | 93.8431 | 2.23347 | 0.111673
3007625 | 03_Third Floor | 93.8431 | 2.23347 | 0.111673
3007627 | 03_Third Floor | 93.8431 | 2.23347 | 0.111673
3007629 | 03_Third Floor | 93.8431 | 2.23347 | 0.111673
3007631 | 03_Third Floor | 93.8431 | 2.23347 | 0.111673
3007787 | 03_Third Floor | 92.1935 | 2.19421 | 0.10971
3007789 | 03_Third Floor | 92.1935 | 2.19421 | 0.10971
3007791 | 03_Third Floor | 92.1935 | 2.19421 | 0.10971
3007793 | 03_Third Floor | 92.1935 | 2.19421 | 0.10971
3007795 | 03_Third Floor | 92.1935 | 2.19421 | 0.10971
3007797 | 03_Third Floor | 92.1935 | 2.19421 | 0.10971
3007799 | 03_Third Floor | 92.1935 | 2.19421 | 0.10971
3007801 | 03_Third Floor | 92.1935 | 2.19421 | 0.10971
3007803 | 03_Third Floor | 92.1935 | 2.19421 | 0.10971
3007805 | 03_Third Floor | 92.1935 | 2.19421 | 0.10971
3007807 | 03_Third Floor | 92.1935 | 2.19421 | 0.10971
3007809 | 03_Third Floor | 92.1935 | 2.19421 | 0.10971
3007811 | 03_Third Floor | 92.1935 | 2.19421 | 0.10971
3007813 | 03_Third Floor | 92.1935 | 2.19421 | 0.10971
3007815 | 03_Third Floor | 92.1935 | 2.19421 | 0.10971
3007817 | 03_Third Floor | 92.1935 | 2.19421 | 0.10971
3007819 | 03_Third Floor | 92.1935 | 2.19421 | 0.10971
3007821 | 03_Third Floor | 92.1935 | 2.19421 | 0.10971
3007823 | 03_Third Floor | 92.1935 | 2.19421 | 0.10971
3007825 | 03_Third Floor | 92.1935 | 2.19421 | 0.10971
3007827 | 03_Third Floor | 92.1935 | 2.19421 | 0.10971
3007829 | 03_Third Floor | 92.1935 | 2.19421 | 0.10971
3007831 | 03_Third Floor | 92.1935 | 2.19421 | 0.10971
3007833 | 03_Third Floor | 92.1935 | 2.19421 | 0.10971
3007835 | 03_Third Floor | 92.1935 | 2.19421 | 0.10971
3007837 | 03_Third Floor | 92.1935 | 2.19421 | 0.10971
3007839 | 03_Third Floor | 92.1935 | 2.19421 | 0.10971
3007841 | 03_Third Floor | 92.1935 | 2.19421 | 0.10971
3007843 | 03_Third Floor | 92.1935 | 2.19421 | 0.10971
3007845 | 03_Third Floor | 92.1935 | 2.19421 | 0.10971
3007847 | 03_Third Floor | 92.1935 | 2.19421 | 0.10971
3009726 | 04_Fourth Floor | 93.8431 | 2.23347 | 0.111673
3009728 | 04_Fourth Floor | 93.8431 | 2.23347 | 0.111673
3009730 | 04_Fourth Floor | 93.8431 | 2.23347 | 0.111673
3009732 | 04_Fourth Floor | 93.8431 | 2.23347 | 0.111673
3009734 | 04_Fourth Floor | 93.8431 | 2.23347 | 0.111673
3009736 | 04_Fourth Floor | 93.8431 | 2.23347 | 0.111673
3009738 | 04_Fourth Floor | 93.8431 | 2.23347 | 0.111673
3009740 | 04_Fourth Floor | 93.8431 | 2.23347 | 0.111673
3009742 | 04_Fourth Floor | 93.8431 | 2.23347 | 0.111673
3009744 | 04_Fourth Floor | 93.8431 | 2.23347 | 0.111673
3009746 | 04_Fourth Floor | 93.8431 | 2.23347 | 0.111673
3009748 | 04_Fourth Floor | 93.8431 | 2.23347 | 0.111673
3009750 | 04_Fourth Floor | 93.8431 | 2.23347 | 0.111673
3009752 | 04_Fourth Floor | 93.8431 | 2.23347 | 0.111673
3009754 | 04_Fourth Floor | 93.8431 | 2.23347 | 0.111673
3009756 | 04_Fourth Floor | 93.8431 | 2.23347 | 0.111673
3009758 | 04_Fourth Floor | 93.8431 | 2.23347 | 0.111673
3009760 | 04_Fourth Floor | 93.8431 | 2.23347 | 0.111673
3009762 | 04_Fourth Floor | 93.8431 | 2.23347 | 0.111673
3009764 | 04_Fourth Floor | 93.8431 | 2.23347 | 0.111673
3009766 | 04_Fourth Floor | 93.8431 | 2.23347 | 0.111673
3009768 | 04_Fourth Floor | 93.8431 | 2.23347 | 0.111673
3009770 | 04_Fourth Floor | 93.8431 | 2.23347 | 0.111673
3009772 | 04_Fourth Floor | 93.8431 | 2.23347 | 0.111673
3009774 | 04_Fourth Floor | 93.8431 | 2.23347 | 0.111673
3009776 | 04_Fourth Floor | 93.8431 | 2.23347 | 0.111673
3009778 | 04_Fourth Floor | 93.8431 | 2.23347 | 0.111673
3009780 | 04_Fourth Floor | 93.8431 | 2.23347 | 0.111673
3009782 | 04_Fourth Floor | 93.8431 | 2.23347 | 0.111673
3009784 | 04_Fourth Floor | 93.8431 | 2.23347 | 0.111673
3009786 | 04_Fourth Floor | 93.8431 | 2.23347 | 0.111673
3009788 | 04_Fourth Floor | 93.8431 | 2.23347 | 0.111673
3009790 | 04_Fourth Floor | 93.8431 | 2.23347 | 0.111673
3009792 | 04_Fourth Floor | 93.8431 | 2.23347 | 0.111673
3009794 | 04_Fourth Floor | 93.8431 | 2.23347 | 0.111673
3009796 | 04_Fourth Floor | 93.8431 | 2.23347 | 0.111673
3009798 | 04_Fourth Floor | 93.8431 | 2.23347 | 0.111673
3009800 | 04_Fourth Floor | 93.8431 | 2.23347 | 0.111673
3009802 | 04_Fourth Floor | 93.8431 | 2.23347 | 0.111673
3009804 | 04_Fourth Floor | 93.8431 | 2.23347 | 0.111673
3009806 | 04_Fourth Floor | 93.8431 | 2.23347 | 0.111673
3009808 | 04_Fourth Floor | 93.8431 | 2.23347 | 0.111673
3009810 | 04_Fourth Floor | 93.8431 | 2.23347 | 0.111673
3009812 | 04_Fourth Floor | 93.8431 | 2.23347 | 0.111673
3009814 | 04_Fourth Floor | 93.8431 | 2.23347 | 0.111673
3009816 | 04_Fourth Floor | 93.8431 | 2.23347 | 0.111673
3009818 | 04_Fourth Floor | 93.8431 | 2.23347 | 0.111673
3009820 | 04_Fourth Floor | 93.8431 | 2.23347 | 0.111673
3009822 | 04_Fourth Floor | 93.8431 | 2.23347 | 0.111673
3009824 | 04_Fourth Floor | 93.8431 | 2.23347 | 0.111673
3009826 | 04_Fourth Floor | 93.8431 | 2.23347 | 0.111673
3009982 | 04_Fourth Floor | 92.1935 | 2.19421 | 0.10971
3009984 | 04_Fourth Floor | 92.1935 | 2.19421 | 0.10971
3009986 | 04_Fourth Floor | 92.1935 | 2.19421 | 0.10971
3009988 | 04_Fourth Floor | 92.1935 | 2.19421 | 0.10971
3009990 | 04_Fourth Floor | 92.1935 | 2.19421 | 0.10971
3009992 | 04_Fourth Floor | 92.1935 | 2.19421 | 0.10971
3009994 | 04_Fourth Floor | 92.1935 | 2.19421 | 0.10971
3009996 | 04_Fourth Floor | 92.1935 | 2.19421 | 0.10971
3009998 | 04_Fourth Floor | 92.1935 | 2.19421 | 0.10971
3010000 | 04_Fourth Floor | 92.1935 | 2.19421 | 0.10971
3010002 | 04_Fourth Floor | 92.1935 | 2.19421 | 0.10971
3010004 | 04_Fourth Floor | 92.1935 | 2.19421 | 0.10971
3010006 | 04_Fourth Floor | 92.1935 | 2.19421 | 0.10971
3010008 | 04_Fourth Floor | 92.1935 | 2.19421 | 0.10971
3010010 | 04_Fourth Floor | 92.1935 | 2.19421 | 0.10971
3010012 | 04_Fourth Floor | 92.1935 | 2.19421 | 0.10971
3010014 | 04_Fourth Floor | 92.1935 | 2.19421 | 0.10971
3010016 | 04_Fourth Floor | 92.1935 | 2.19421 | 0.10971
3010018 | 04_Fourth Floor | 92.1935 | 2.19421 | 0.10971
3010020 | 04_Fourth Floor | 92.1935 | 2.19421 | 0.10971
3010022 | 04_Fourth Floor | 92.1935 | 2.19421 | 0.10971
3010024 | 04_Fourth Floor | 92.1935 | 2.19421 | 0.10971
3010026 | 04_Fourth Floor | 92.1935 | 2.19421 | 0.10971
3010028 | 04_Fourth Floor | 92.1935 | 2.19421 | 0.10971
3010030 | 04_Fourth Floor | 92.1935 | 2.19421 | 0.10971
3010032 | 04_Fourth Floor | 92.1935 | 2.19421 | 0.10971
3010034 | 04_Fourth Floor | 92.1935 | 2.19421 | 0.10971
3010036 | 04_Fourth Floor | 92.1935 | 2.19421 | 0.10971
3010038 | 04_Fourth Floor | 92.1935 | 2.19421 | 0.10971
3010040 | 04_Fourth Floor | 92.1935 | 2.19421 | 0.10971
3010042 | 04_Fourth Floor | 92.1935 | 2.19421 | 0.10971
3011921 | 05_Fifth Floor | 93.8431 | 2.23347 | 0.111673
3011923 | 05_Fifth Floor | 93.8431 | 2.23347 | 0.111673
3011925 | 05_Fifth Floor | 93.8431 | 2.23347 | 0.111673
3011927 | 05_Fifth Floor | 93.8431 | 2.23347 | 0.111673
3011929 | 05_Fifth Floor | 93.8431 | 2.23347 | 0.111673
3011931 | 05_Fifth Floor | 93.8431 | 2.23347 | 0.111673
3011933 | 05_Fifth Floor | 93.8431 | 2.23347 | 0.111673
3011935 | 05_Fifth Floor | 93.8431 | 2.23347 | 0.111673
3011937 | 05_Fifth Floor | 93.8431 | 2.23347 | 0.111673
3011939 | 05_Fifth Floor | 93.8431 | 2.23347 | 0.111673
3011941 | 05_Fifth Floor | 93.8431 | 2.23347 | 0.111673
3011943 | 05_Fifth Floor | 93.8431 | 2.23347 | 0.111673
3011945 | 05_Fifth Floor | 93.8431 | 2.23347 | 0.111673
3011947 | 05_Fifth Floor | 93.8431 | 2.23347 | 0.111673
3011949 | 05_Fifth Floor | 93.8431 | 2.23347 | 0.111673
3011951 | 05_Fifth Floor | 93.8431 | 2.23347 | 0.111673
3011953 | 05_Fifth Floor | 93.8431 | 2.23347 | 0.111673
3011955 | 05_Fifth Floor | 93.8431 | 2.23347 | 0.111673
3011957 | 05_Fifth Floor | 93.8431 | 2.23347 | 0.111673
3011959 | 05_Fifth Floor | 93.8431 | 2.23347 | 0.111673
3011961 | 05_Fifth Floor | 93.8431 | 2.23347 | 0.111673
3011963 | 05_Fifth Floor | 93.8431 | 2.23347 | 0.111673
3011965 | 05_Fifth Floor | 93.8431 | 2.23347 | 0.111673
3011967 | 05_Fifth Floor | 93.8431 | 2.23347 | 0.111673
3011969 | 05_Fifth Floor | 93.8431 | 2.23347 | 0.111673
3011971 | 05_Fifth Floor | 93.8431 | 2.23347 | 0.111673
3011973 | 05_Fifth Floor | 93.8431 | 2.23347 | 0.111673
3011975 | 05_Fifth Floor | 93.8431 | 2.23347 | 0.111673
3011977 | 05_Fifth Floor | 93.8431 | 2.23347 | 0.111673
3011979 | 05_Fifth Floor | 93.8431 | 2.23347 | 0.111673
3011981 | 05_Fifth Floor | 93.8431 | 2.23347 | 0.111673
3011983 | 05_Fifth Floor | 93.8431 | 2.23347 | 0.111673
3011985 | 05_Fifth Floor | 93.8431 | 2.23347 | 0.111673
3011987 | 05_Fifth Floor | 93.8431 | 2.23347 | 0.111673
3011989 | 05_Fifth Floor | 93.8431 | 2.23347 | 0.111673
3011991 | 05_Fifth Floor | 93.8431 | 2.23347 | 0.111673
3011993 | 05_Fifth Floor | 93.8431 | 2.23347 | 0.111673
3011995 | 05_Fifth Floor | 93.8431 | 2.23347 | 0.111673
3011997 | 05_Fifth Floor | 93.8431 | 2.23347 | 0.111673
3011999 | 05_Fifth Floor | 93.8431 | 2.23347 | 0.111673
3012001 | 05_Fifth Floor | 93.8431 | 2.23347 | 0.111673
3012003 | 05_Fifth Floor | 93.8431 | 2.23347 | 0.111673
3012005 | 05_Fifth Floor | 93.8431 | 2.23347 | 0.111673
3012007 | 05_Fifth Floor | 93.8431 | 2.23347 | 0.111673
3012009 | 05_Fifth Floor | 93.8431 | 2.23347 | 0.111673
3012011 | 05_Fifth Floor | 93.8431 | 2.23347 | 0.111673
3012013 | 05_Fifth Floor | 93.8431 | 2.23347 | 0.111673
3012015 | 05_Fifth Floor | 93.8431 | 2.23347 | 0.111673
3012017 | 05_Fifth Floor | 93.8431 | 2.23347 | 0.111673
3012019 | 05_Fifth Floor | 93.8431 | 2.23347 | 0.111673
3012021 | 05_Fifth Floor | 93.8431 | 2.23347 | 0.111673
3012177 | 05_Fifth Floor | 92.1935 | 2.19421 | 0.10971
3012179 | 05_Fifth Floor | 92.1935 | 2.19421 | 0.10971
3012181 | 05_Fifth Floor | 92.1935 | 2.19421 | 0.10971
3012183 | 05_Fifth Floor | 92.1935 | 2.19421 | 0.10971
3012185 | 05_Fifth Floor | 92.1935 | 2.19421 | 0.10971
3012187 | 05_Fifth Floor | 92.1935 | 2.19421 | 0.10971
3012189 | 05_Fifth Floor | 92.1935 | 2.19421 | 0.10971
3012191 | 05_Fifth Floor | 92.1935 | 2.19421 | 0.10971
3012193 | 05_Fifth Floor | 92.1935 | 2.19421 | 0.10971
3012195 | 05_Fifth Floor | 92.1935 | 2.19421 | 0.10971
3012197 | 05_Fifth Floor | 92.1935 | 2.19421 | 0.10971
3012199 | 05_Fifth Floor | 92.1935 | 2.19421 | 0.10971
3012201 | 05_Fifth Floor | 92.1935 | 2.19421 | 0.10971
3012203 | 05_Fifth Floor | 92.1935 | 2.19421 | 0.10971
3012205 | 05_Fifth Floor | 92.1935 | 2.19421 | 0.10971
3012207 | 05_Fifth Floor | 92.1935 | 2.19421 | 0.10971
3012209 | 05_Fifth Floor | 92.1935 | 2.19421 | 0.10971
3012211 | 05_Fifth Floor | 92.1935 | 2.19421 | 0.10971
3012213 | 05_Fifth Floor | 92.1935 | 2.19421 | 0.10971
3012215 | 05_Fifth Floor | 92.1935 | 2.19421 | 0.10971
3012217 | 05_Fifth Floor | 92.1935 | 2.19421 | 0.10971
3012219 | 05_Fifth Floor | 92.1935 | 2.19421 | 0.10971
3012221 | 05_Fifth Floor | 92.1935 | 2.19421 | 0.10971
3012223 | 05_Fifth Floor | 92.1935 | 2.19421 | 0.10971
3012225 | 05_Fifth Floor | 92.1935 | 2.19421 | 0.10971
3012227 | 05_Fifth Floor | 92.1935 | 2.19421 | 0.10971
3012229 | 05_Fifth Floor | 92.1935 | 2.19421 | 0.10971
3012231 | 05_Fifth Floor | 92.1935 | 2.19421 | 0.10971
3012233 | 05_Fifth Floor | 92.1935 | 2.19421 | 0.10971
3012235 | 05_Fifth Floor | 92.1935 | 2.19421 | 0.10971
3012237 | 05_Fifth Floor | 92.1935 | 2.19421 | 0.10971
3014118 | 06_Sixth Floor | 93.8431 | 2.23347 | 0.111673
3014120 | 06_Sixth Floor | 93.8431 | 2.23347 | 0.111673
3014122 | 06_Sixth Floor | 93.8431 | 2.23347 | 0.111673
3014124 | 06_Sixth Floor | 93.8431 | 2.23347 | 0.111673
3014126 | 06_Sixth Floor | 93.8431 | 2.23347 | 0.111673
3014128 | 06_Sixth Floor | 93.8431 | 2.23347 | 0.111673
3014130 | 06_Sixth Floor | 93.8431 | 2.23347 | 0.111673
3014132 | 06_Sixth Floor | 93.8431 | 2.23347 | 0.111673
3014134 | 06_Sixth Floor | 93.8431 | 2.23347 | 0.111673
3014136 | 06_Sixth Floor | 93.8431 | 2.23347 | 0.111673
3014138 | 06_Sixth Floor | 93.8431 | 2.23347 | 0.111673
3014140 | 06_Sixth Floor | 93.8431 | 2.23347 | 0.111673
3014142 | 06_Sixth Floor | 93.8431 | 2.23347 | 0.111673
3014144 | 06_Sixth Floor | 93.8431 | 2.23347 | 0.111673
3014146 | 06_Sixth Floor | 93.8431 | 2.23347 | 0.111673
3014148 | 06_Sixth Floor | 93.8431 | 2.23347 | 0.111673
3014150 | 06_Sixth Floor | 93.8431 | 2.23347 | 0.111673
3014152 | 06_Sixth Floor | 93.8431 | 2.23347 | 0.111673
3014154 | 06_Sixth Floor | 93.8431 | 2.23347 | 0.111673
3014156 | 06_Sixth Floor | 93.8431 | 2.23347 | 0.111673
3014158 | 06_Sixth Floor | 93.8431 | 2.23347 | 0.111673
3014160 | 06_Sixth Floor | 93.8431 | 2.23347 | 0.111673
3014162 | 06_Sixth Floor | 93.8431 | 2.23347 | 0.111673
3014164 | 06_Sixth Floor | 93.8431 | 2.23347 | 0.111673
3014166 | 06_Sixth Floor | 93.8431 | 2.23347 | 0.111673
3014168 | 06_Sixth Floor | 93.8431 | 2.23347 | 0.111673
3014170 | 06_Sixth Floor | 93.8431 | 2.23347 | 0.111673
3014172 | 06_Sixth Floor | 93.8431 | 2.23347 | 0.111673
3014174 | 06_Sixth Floor | 93.8431 | 2.23347 | 0.111673
3014176 | 06_Sixth Floor | 93.8431 | 2.23347 | 0.111673
3014178 | 06_Sixth Floor | 93.8431 | 2.23347 | 0.111673
3014180 | 06_Sixth Floor | 93.8431 | 2.23347 | 0.111673
3014182 | 06_Sixth Floor | 93.8431 | 2.23347 | 0.111673
3014184 | 06_Sixth Floor | 93.8431 | 2.23347 | 0.111673
3014186 | 06_Sixth Floor | 93.8431 | 2.23347 | 0.111673
3014188 | 06_Sixth Floor | 93.8431 | 2.23347 | 0.111673
3014190 | 06_Sixth Floor | 93.8431 | 2.23347 | 0.111673
3014192 | 06_Sixth Floor | 93.8431 | 2.23347 | 0.111673
3014194 | 06_Sixth Floor | 93.8431 | 2.23347 | 0.111673
3014196 | 06_Sixth Floor | 93.8431 | 2.23347 | 0.111673
3014198 | 06_Sixth Floor | 93.8431 | 2.23347 | 0.111673
3014200 | 06_Sixth Floor | 93.8431 | 2.23347 | 0.111673
3014202 | 06_Sixth Floor | 93.8431 | 2.23347 | 0.111673
3014204 | 06_Sixth Floor | 93.8431 | 2.23347 | 0.111673
3014206 | 06_Sixth Floor | 93.8431 | 2.23347 | 0.111673
3014208 | 06_Sixth Floor | 93.8431 | 2.23347 | 0.111673
3014210 | 06_Sixth Floor | 93.8431 | 2.23347 | 0.111673
3014212 | 06_Sixth Floor | 93.8431 | 2.23347 | 0.111673
3014214 | 06_Sixth Floor | 93.8431 | 2.23347 | 0.111673
3014216 | 06_Sixth Floor | 93.8431 | 2.23347 | 0.111673
3014218 | 06_Sixth Floor | 93.8431 | 2.23347 | 0.111673
3014374 | 06_Sixth Floor | 92.1935 | 2.19421 | 0.10971
3014376 | 06_Sixth Floor | 92.1935 | 2.19421 | 0.10971
3014378 | 06_Sixth Floor | 92.1935 | 2.19421 | 0.10971
3014380 | 06_Sixth Floor | 92.1935 | 2.19421 | 0.10971
3014382 | 06_Sixth Floor | 92.1935 | 2.19421 | 0.10971
3014384 | 06_Sixth Floor | 92.1935 | 2.19421 | 0.10971
3014386 | 06_Sixth Floor | 92.1935 | 2.19421 | 0.10971
3014388 | 06_Sixth Floor | 92.1935 | 2.19421 | 0.10971
3014390 | 06_Sixth Floor | 92.1935 | 2.19421 | 0.10971
3014392 | 06_Sixth Floor | 92.1935 | 2.19421 | 0.10971
3014394 | 06_Sixth Floor | 92.1935 | 2.19421 | 0.10971
3014396 | 06_Sixth Floor | 92.1935 | 2.19421 | 0.10971
3014398 | 06_Sixth Floor | 92.1935 | 2.19421 | 0.10971
3014400 | 06_Sixth Floor | 92.1935 | 2.19421 | 0.10971
3014402 | 06_Sixth Floor | 92.1935 | 2.19421 | 0.10971
3014404 | 06_Sixth Floor | 92.1935 | 2.19421 | 0.10971
3014406 | 06_Sixth Floor | 92.1935 | 2.19421 | 0.10971
3014408 | 06_Sixth Floor | 92.1935 | 2.19421 | 0.10971
3014410 | 06_Sixth Floor | 92.1935 | 2.19421 | 0.10971
3014412 | 06_Sixth Floor | 92.1935 | 2.19421 | 0.10971
3014414 | 06_Sixth Floor | 92.1935 | 2.19421 | 0.10971
3014416 | 06_Sixth Floor | 92.1935 | 2.19421 | 0.10971
3014418 | 06_Sixth Floor | 92.1935 | 2.19421 | 0.10971
3014420 | 06_Sixth Floor | 92.1935 | 2.19421 | 0.10971
3014422 | 06_Sixth Floor | 92.1935 | 2.19421 | 0.10971
3014424 | 06_Sixth Floor | 92.1935 | 2.19421 | 0.10971
3014426 | 06_Sixth Floor | 92.1935 | 2.19421 | 0.10971
3014428 | 06_Sixth Floor | 92.1935 | 2.19421 | 0.10971
3014430 | 06_Sixth Floor | 92.1935 | 2.19421 | 0.10971
3014432 | 06_Sixth Floor | 92.1935 | 2.19421 | 0.10971
3014434 | 06_Sixth Floor | 92.1935 | 2.19421 | 0.10971
3016313 | 07_Seventh Floor | 93.8431 | 2.23347 | 0.111673
3016315 | 07_Seventh Floor | 93.8431 | 2.23347 | 0.111673
3016317 | 07_Seventh Floor | 93.8431 | 2.23347 | 0.111673
3016319 | 07_Seventh Floor | 93.8431 | 2.23347 | 0.111673
3016321 | 07_Seventh Floor | 93.8431 | 2.23347 | 0.111673
3016323 | 07_Seventh Floor | 93.8431 | 2.23347 | 0.111673
3016325 | 07_Seventh Floor | 93.8431 | 2.23347 | 0.111673
3016327 | 07_Seventh Floor | 93.8431 | 2.23347 | 0.111673
3016329 | 07_Seventh Floor | 93.8431 | 2.23347 | 0.111673
3016331 | 07_Seventh Floor | 93.8431 | 2.23347 | 0.111673
3016333 | 07_Seventh Floor | 93.8431 | 2.23347 | 0.111673
3016335 | 07_Seventh Floor | 93.8431 | 2.23347 | 0.111673
3016337 | 07_Seventh Floor | 93.8431 | 2.23347 | 0.111673
3016339 | 07_Seventh Floor | 93.8431 | 2.23347 | 0.111673
3016341 | 07_Seventh Floor | 93.8431 | 2.23347 | 0.111673
3016343 | 07_Seventh Floor | 93.8431 | 2.23347 | 0.111673
3016345 | 07_Seventh Floor | 93.8431 | 2.23347 | 0.111673
3016347 | 07_Seventh Floor | 93.8431 | 2.23347 | 0.111673
3016349 | 07_Seventh Floor | 93.8431 | 2.23347 | 0.111673
3016351 | 07_Seventh Floor | 93.8431 | 2.23347 | 0.111673
3016353 | 07_Seventh Floor | 93.8431 | 2.23347 | 0.111673
3016355 | 07_Seventh Floor | 93.8431 | 2.23347 | 0.111673
3016357 | 07_Seventh Floor | 93.8431 | 2.23347 | 0.111673
3016359 | 07_Seventh Floor | 93.8431 | 2.23347 | 0.111673
3016361 | 07_Seventh Floor | 93.8431 | 2.23347 | 0.111673
3016363 | 07_Seventh Floor | 93.8431 | 2.23347 | 0.111673
3016365 | 07_Seventh Floor | 93.8431 | 2.23347 | 0.111673
3016367 | 07_Seventh Floor | 93.8431 | 2.23347 | 0.111673
3016369 | 07_Seventh Floor | 93.8431 | 2.23347 | 0.111673
3016371 | 07_Seventh Floor | 93.8431 | 2.23347 | 0.111673
3016373 | 07_Seventh Floor | 93.8431 | 2.23347 | 0.111673
3016375 | 07_Seventh Floor | 93.8431 | 2.23347 | 0.111673
3016377 | 07_Seventh Floor | 93.8431 | 2.23347 | 0.111673
3016379 | 07_Seventh Floor | 93.8431 | 2.23347 | 0.111673
3016381 | 07_Seventh Floor | 93.8431 | 2.23347 | 0.111673
3016383 | 07_Seventh Floor | 93.8431 | 2.23347 | 0.111673
3016385 | 07_Seventh Floor | 93.8431 | 2.23347 | 0.111673
3016387 | 07_Seventh Floor | 93.8431 | 2.23347 | 0.111673
3016389 | 07_Seventh Floor | 93.8431 | 2.23347 | 0.111673
3016391 | 07_Seventh Floor | 93.8431 | 2.23347 | 0.111673
3016393 | 07_Seventh Floor | 93.8431 | 2.23347 | 0.111673
3016395 | 07_Seventh Floor | 93.8431 | 2.23347 | 0.111673
3016397 | 07_Seventh Floor | 93.8431 | 2.23347 | 0.111673
3016399 | 07_Seventh Floor | 93.8431 | 2.23347 | 0.111673
3016401 | 07_Seventh Floor | 93.8431 | 2.23347 | 0.111673
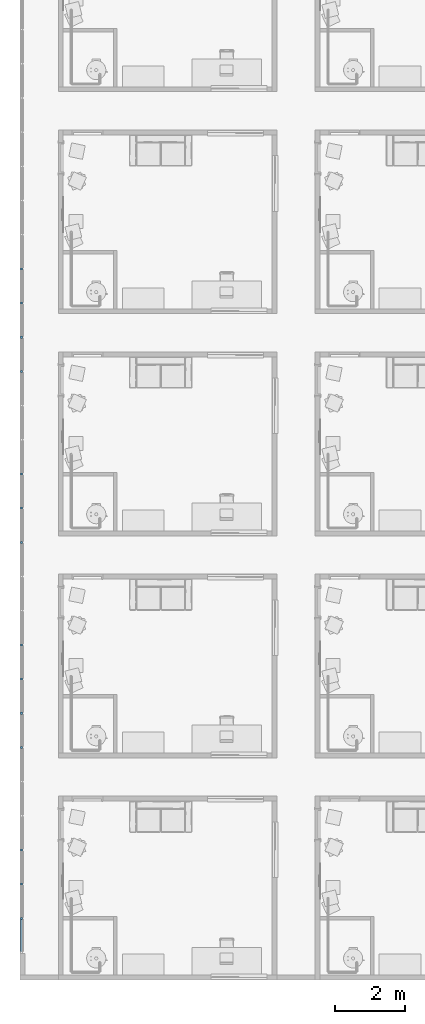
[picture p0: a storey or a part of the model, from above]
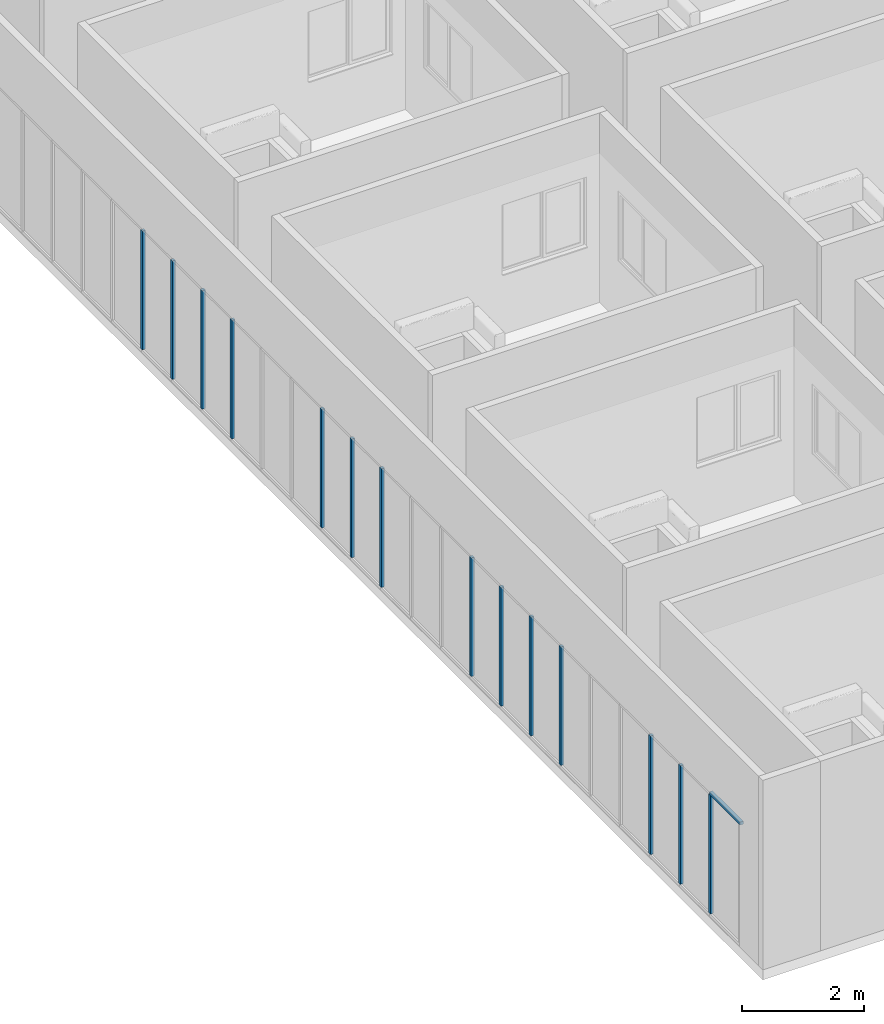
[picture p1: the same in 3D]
Properties of the parts of a building model (IFC4), part 12 of 14

# IfcPlate: System Panel:Glazed (656)
Name (System Panel:Glazed:...) | In | Width (cm) | GrossArea (m2) = NetArea (m2) | NetVolume (m3)
3016403 | 07_Seventh Floor | 93.8431 | 2.23347 | 0.111673
3016405 | 07_Seventh Floor | 93.8431 | 2.23347 | 0.111673
3016407 | 07_Seventh Floor | 93.8431 | 2.23347 | 0.111673
3016409 | 07_Seventh Floor | 93.8431 | 2.23347 | 0.111673
3016411 | 07_Seventh Floor | 93.8431 | 2.23347 | 0.111673
3016413 | 07_Seventh Floor | 93.8431 | 2.23347 | 0.111673
3016569 | 07_Seventh Floor | 92.1935 | 2.19421 | 0.10971
3016571 | 07_Seventh Floor | 92.1935 | 2.19421 | 0.10971
3016573 | 07_Seventh Floor | 92.1935 | 2.19421 | 0.10971
3016575 | 07_Seventh Floor | 92.1935 | 2.19421 | 0.10971
3016577 | 07_Seventh Floor | 92.1935 | 2.19421 | 0.10971
3016579 | 07_Seventh Floor | 92.1935 | 2.19421 | 0.10971
3016581 | 07_Seventh Floor | 92.1935 | 2.19421 | 0.10971
3016583 | 07_Seventh Floor | 92.1935 | 2.19421 | 0.10971
3016585 | 07_Seventh Floor | 92.1935 | 2.19421 | 0.10971
3016587 | 07_Seventh Floor | 92.1935 | 2.19421 | 0.10971
3016589 | 07_Seventh Floor | 92.1935 | 2.19421 | 0.10971
3016591 | 07_Seventh Floor | 92.1935 | 2.19421 | 0.10971
3016593 | 07_Seventh Floor | 92.1935 | 2.19421 | 0.10971
3016595 | 07_Seventh Floor | 92.1935 | 2.19421 | 0.10971
3016597 | 07_Seventh Floor | 92.1935 | 2.19421 | 0.10971
3016599 | 07_Seventh Floor | 92.1935 | 2.19421 | 0.10971
3016601 | 07_Seventh Floor | 92.1935 | 2.19421 | 0.10971
3016603 | 07_Seventh Floor | 92.1935 | 2.19421 | 0.10971
3016605 | 07_Seventh Floor | 92.1935 | 2.19421 | 0.10971
3016607 | 07_Seventh Floor | 92.1935 | 2.19421 | 0.10971
3016609 | 07_Seventh Floor | 92.1935 | 2.19421 | 0.10971
3016611 | 07_Seventh Floor | 92.1935 | 2.19421 | 0.10971
3016613 | 07_Seventh Floor | 92.1935 | 2.19421 | 0.10971
3016615 | 07_Seventh Floor | 92.1935 | 2.19421 | 0.10971
3016617 | 07_Seventh Floor | 92.1935 | 2.19421 | 0.10971
3016619 | 07_Seventh Floor | 92.1935 | 2.19421 | 0.10971
3016621 | 07_Seventh Floor | 92.1935 | 2.19421 | 0.10971
3016623 | 07_Seventh Floor | 92.1935 | 2.19421 | 0.10971
3016625 | 07_Seventh Floor | 92.1935 | 2.19421 | 0.10971
3016627 | 07_Seventh Floor | 92.1935 | 2.19421 | 0.10971
3016629 | 07_Seventh Floor | 92.1935 | 2.19421 | 0.10971

# IfcSlab: Floor:ARC_13_FL_SB_ConcreteCIP-20cm_gen_BERSnl (9)
Type - PredefinedType: FLOOR; Material: ARC_FME.f2_Ef2-Cast-In-Place Concrete_C30/37_gen_BERSnl
Type - Pset_ReinforcementBarPitchOfSlab - Description: betonvloer
Type - Pset_SlabCommon - ThermalTransmittance: 1.045 kg/K/s3
Classification: 13.22 vloeren op grondslag; constructief, vloeren als gebouwonderdeel (Uniformat)
Pset_EnvironmentalImpactIndicators - Reference: ARC_13_FL_SB_ConcreteCIP-20cm_gen_BERSnl; sets with these values: 2
Pset_SlabCommon - Reference: ARC_13_FL_SB_ConcreteCIP-20cm_gen_BERSnl; PitchAngle: 0 deg; IsExternal: yes; LoadBearing: yes
Qto_SlabBaseQuantities - Width: 5166 cm; Length: 3190 cm; Depth: 20 cm; Perimeter: 548.294 cm; GrossArea: 1647.95 m2; NetArea: 1647.95 m2; GrossVolume: 329.591 m3; NetVolume: 329.591 m3
Name (Floor:ARC_13_FL_SB_ConcreteCIP-20cm_gen_BERSnl:...) | In
2999138 | 00_Ground Floor
3003095 | 01_First Floor
3005292 | 02_Second Floor
3007489 | 03_Third Floor
3009684 | 04_Fourth Floor
3011879 | 05_Fifth Floor
3014076 | 06_Sixth Floor
3016271 | 07_Seventh Floor
3016887 | 08_Roof

# IfcWall: Basic Wall:ARC_22.10_WA_LB_GPS10_gen_BERSnl (560)
Type - PredefinedType: STANDARD
Type - Pset_ReinforcementBarPitchOfWall - Description: gyproc
Classification: 22.10 binnenwanden; niet constructief, algemeen (verzamelniveau) (Uniformat); Material: ARC_FME.r2_Plaster_white_gen_BERSnl
Qto_WallBaseQuantities - Height: 300 cm; Width: 10 cm
Pset_EnvironmentalImpactIndicators - Reference: ARC_22.10_WA_LB_GPS10_gen_BERSnl; sets with these values: 2
Pset_WallCommon - IsExternal: no; LoadBearing: no; ExtendToStructure: no; Reference: ARC_22.10_WA_LB_GPS10_gen_BERSnl
Name (Basic Wall:ARC_22.10_WA_LB_GPS10_gen_BERSnl:...) | In | Length (cm) | GrossFootprintArea (m2) | GrossVolume (m3) = NetVolume (m3) | GrossSideArea (m2) = NetSideArea (m2)
2975680 | 00_Ground Floor | 168 | 0.168 | 0.504 | 5.04
2975748 | 00_Ground Floor | 145 | 0.145 | 0.435 | 4.35
2995757 | 00_Ground Floor | 168 | 0.168 | 0.504 | 5.04
2995758 | 00_Ground Floor | 145 | 0.145 | 0.435 | 4.35
2995866 | 00_Ground Floor | 168 | 0.168 | 0.504 | 5.04
2995867 | 00_Ground Floor | 145 | 0.145 | 0.435 | 4.35
2995925 | 00_Ground Floor | 168 | 0.168 | 0.504 | 5.04
2995926 | 00_Ground Floor | 145 | 0.145 | 0.435 | 4.35
2995984 | 00_Ground Floor | 168 | 0.168 | 0.504 | 5.04
2995985 | 00_Ground Floor | 145 | 0.145 | 0.435 | 4.35
2996043 | 00_Ground Floor | 168 | 0.168 | 0.504 | 5.04
2996044 | 00_Ground Floor | 145 | 0.145 | 0.435 | 4.35
2996102 | 00_Ground Floor | 168 | 0.168 | 0.504 | 5.04
2996103 | 00_Ground Floor | 145 | 0.145 | 0.435 | 4.35
2996169 | 00_Ground Floor | 168 | 0.168 | 0.504 | 5.04
2996170 | 00_Ground Floor | 145 | 0.145 | 0.435 | 4.35
2996224 | 00_Ground Floor | 168 | 0.168 | 0.504 | 5.04
2996225 | 00_Ground Floor | 145 | 0.145 | 0.435 | 4.35
2996283 | 00_Ground Floor | 168 | 0.168 | 0.504 | 5.04
2996284 | 00_Ground Floor | 145 | 0.145 | 0.435 | 4.35
2996338 | 00_Ground Floor | 168 | 0.168 | 0.504 | 5.04
2996339 | 00_Ground Floor | 145 | 0.145 | 0.435 | 4.35
2996393 | 00_Ground Floor | 168 | 0.168 | 0.504 | 5.04
2996394 | 00_Ground Floor | 145 | 0.145 | 0.435 | 4.35
2996448 | 00_Ground Floor | 168 | 0.168 | 0.504 | 5.04
2996449 | 00_Ground Floor | 145 | 0.145 | 0.435 | 4.35
2996503 | 00_Ground Floor | 168 | 0.168 | 0.504 | 5.04
2996504 | 00_Ground Floor | 145 | 0.145 | 0.435 | 4.35
2996613 | 00_Ground Floor | 168 | 0.168 | 0.504 | 5.04
2996614 | 00_Ground Floor | 145 | 0.145 | 0.435 | 4.35
2996668 | 00_Ground Floor | 168 | 0.168 | 0.504 | 5.04
2996669 | 00_Ground Floor | 145 | 0.145 | 0.435 | 4.35
2996727 | 00_Ground Floor | 168 | 0.168 | 0.504 | 5.04
2996728 | 00_Ground Floor | 145 | 0.145 | 0.435 | 4.35
2996782 | 00_Ground Floor | 168 | 0.168 | 0.504 | 5.04
2996783 | 00_Ground Floor | 145 | 0.145 | 0.435 | 4.35
2996837 | 00_Ground Floor | 168 | 0.168 | 0.504 | 5.04
2996838 | 00_Ground Floor | 145 | 0.145 | 0.435 | 4.35
2996892 | 00_Ground Floor | 168 | 0.168 | 0.504 | 5.04
2996893 | 00_Ground Floor | 145 | 0.145 | 0.435 | 4.35
2996947 | 00_Ground Floor | 168 | 0.168 | 0.504 | 5.04
2996948 | 00_Ground Floor | 145 | 0.145 | 0.435 | 4.35
2997019 | 00_Ground Floor | 168 | 0.168 | 0.504 | 5.04
2997020 | 00_Ground Floor | 145 | 0.145 | 0.435 | 4.35
2997074 | 00_Ground Floor | 168 | 0.168 | 0.504 | 5.04
2997075 | 00_Ground Floor | 145 | 0.145 | 0.435 | 4.35
2997133 | 00_Ground Floor | 168 | 0.168 | 0.504 | 5.04
2997134 | 00_Ground Floor | 145 | 0.145 | 0.435 | 4.35
2997188 | 00_Ground Floor | 168 | 0.168 | 0.504 | 5.04
2997189 | 00_Ground Floor | 145 | 0.145 | 0.435 | 4.35
2997243 | 00_Ground Floor | 168 | 0.168 | 0.504 | 5.04
2997244 | 00_Ground Floor | 145 | 0.145 | 0.435 | 4.35
2997298 | 00_Ground Floor | 168 | 0.168 | 0.504 | 5.04
2997299 | 00_Ground Floor | 145 | 0.145 | 0.435 | 4.35
2997353 | 00_Ground Floor | 168 | 0.168 | 0.504 | 5.04
2997354 | 00_Ground Floor | 145 | 0.145 | 0.435 | 4.35
2997425 | 00_Ground Floor | 168 | 0.168 | 0.504 | 5.04
2997426 | 00_Ground Floor | 145 | 0.145 | 0.435 | 4.35
2997480 | 00_Ground Floor | 168 | 0.168 | 0.504 | 5.04
2997481 | 00_Ground Floor | 145 | 0.145 | 0.435 | 4.35
2997539 | 00_Ground Floor | 168 | 0.168 | 0.504 | 5.04
2997540 | 00_Ground Floor | 145 | 0.145 | 0.435 | 4.35
2997594 | 00_Ground Floor | 168 | 0.168 | 0.504 | 5.04
2997595 | 00_Ground Floor | 145 | 0.145 | 0.435 | 4.35
2997649 | 00_Ground Floor | 168 | 0.168 | 0.504 | 5.04
2997650 | 00_Ground Floor | 145 | 0.145 | 0.435 | 4.35
2997704 | 00_Ground Floor | 168 | 0.168 | 0.504 | 5.04
2997705 | 00_Ground Floor | 145 | 0.145 | 0.435 | 4.35
2997759 | 00_Ground Floor | 168 | 0.168 | 0.504 | 5.04
2997760 | 00_Ground Floor | 145 | 0.145 | 0.435 | 4.35
3001458 | 01_First Floor | 168 | 0.168 | 0.504 | 5.04
3001459 | 01_First Floor | 145 | 0.145 | 0.435 | 4.35
3001505 | 01_First Floor | 168 | 0.168 | 0.504 | 5.04
3001506 | 01_First Floor | 145 | 0.145 | 0.435 | 4.35
3001556 | 01_First Floor | 168 | 0.168 | 0.504 | 5.04
3001557 | 01_First Floor | 145 | 0.145 | 0.435 | 4.35
3001603 | 01_First Floor | 168 | 0.168 | 0.504 | 5.04
3001604 | 01_First Floor | 145 | 0.145 | 0.435 | 4.35
3001650 | 01_First Floor | 168 | 0.168 | 0.504 | 5.04
3001651 | 01_First Floor | 145 | 0.145 | 0.435 | 4.35
3001697 | 01_First Floor | 168 | 0.168 | 0.504 | 5.04
3001698 | 01_First Floor | 145 | 0.145 | 0.435 | 4.35
3001744 | 01_First Floor | 168 | 0.168 | 0.504 | 5.04
3001745 | 01_First Floor | 145 | 0.145 | 0.435 | 4.35
3001791 | 01_First Floor | 168 | 0.168 | 0.504 | 5.04
3001792 | 01_First Floor | 145 | 0.145 | 0.435 | 4.35
3001837 | 01_First Floor | 168 | 0.168 | 0.504 | 5.04
3001838 | 01_First Floor | 145 | 0.145 | 0.435 | 4.35
3001887 | 01_First Floor | 168 | 0.168 | 0.504 | 5.04
3001888 | 01_First Floor | 145 | 0.145 | 0.435 | 4.35
3001933 | 01_First Floor | 168 | 0.168 | 0.504 | 5.04
3001934 | 01_First Floor | 145 | 0.145 | 0.435 | 4.35
3001979 | 01_First Floor | 168 | 0.168 | 0.504 | 5.04
3001980 | 01_First Floor | 145 | 0.145 | 0.435 | 4.35
3002025 | 01_First Floor | 168 | 0.168 | 0.504 | 5.04
3002026 | 01_First Floor | 145 | 0.145 | 0.435 | 4.35
3002071 | 01_First Floor | 168 | 0.168 | 0.504 | 5.04
3002072 | 01_First Floor | 145 | 0.145 | 0.435 | 4.35
3002118 | 01_First Floor | 168 | 0.168 | 0.504 | 5.04
3002119 | 01_First Floor | 145 | 0.145 | 0.435 | 4.35
3002164 | 01_First Floor | 168 | 0.168 | 0.504 | 5.04
3002165 | 01_First Floor | 145 | 0.145 | 0.435 | 4.35
3002214 | 01_First Floor | 168 | 0.168 | 0.504 | 5.04
3002215 | 01_First Floor | 145 | 0.145 | 0.435 | 4.35
3002260 | 01_First Floor | 168 | 0.168 | 0.504 | 5.04
3002261 | 01_First Floor | 145 | 0.145 | 0.435 | 4.35
3002306 | 01_First Floor | 168 | 0.168 | 0.504 | 5.04
3002307 | 01_First Floor | 145 | 0.145 | 0.435 | 4.35
3002352 | 01_First Floor | 168 | 0.168 | 0.504 | 5.04
3002353 | 01_First Floor | 145 | 0.145 | 0.435 | 4.35
3002398 | 01_First Floor | 168 | 0.168 | 0.504 | 5.04
3002399 | 01_First Floor | 145 | 0.145 | 0.435 | 4.35
3002445 | 01_First Floor | 168 | 0.168 | 0.504 | 5.04
3002446 | 01_First Floor | 145 | 0.145 | 0.435 | 4.35
3002491 | 01_First Floor | 168 | 0.168 | 0.504 | 5.04
3002492 | 01_First Floor | 145 | 0.145 | 0.435 | 4.35
3002541 | 01_First Floor | 168 | 0.168 | 0.504 | 5.04
3002542 | 01_First Floor | 145 | 0.145 | 0.435 | 4.35
3002587 | 01_First Floor | 168 | 0.168 | 0.504 | 5.04
3002588 | 01_First Floor | 145 | 0.145 | 0.435 | 4.35
3002633 | 01_First Floor | 168 | 0.168 | 0.504 | 5.04
3002634 | 01_First Floor | 145 | 0.145 | 0.435 | 4.35
3002679 | 01_First Floor | 168 | 0.168 | 0.504 | 5.04
3002680 | 01_First Floor | 145 | 0.145 | 0.435 | 4.35
3002725 | 01_First Floor | 168 | 0.168 | 0.504 | 5.04
3002726 | 01_First Floor | 145 | 0.145 | 0.435 | 4.35
3002772 | 01_First Floor | 168 | 0.168 | 0.504 | 5.04
3002773 | 01_First Floor | 145 | 0.145 | 0.435 | 4.35
3002818 | 01_First Floor | 168 | 0.168 | 0.504 | 5.04
3002819 | 01_First Floor | 145 | 0.145 | 0.435 | 4.35
3002868 | 01_First Floor | 168 | 0.168 | 0.504 | 5.04
3002869 | 01_First Floor | 145 | 0.145 | 0.435 | 4.35
3002914 | 01_First Floor | 168 | 0.168 | 0.504 | 5.04
3002915 | 01_First Floor | 145 | 0.145 | 0.435 | 4.35
3002960 | 01_First Floor | 168 | 0.168 | 0.504 | 5.04
3002961 | 01_First Floor | 145 | 0.145 | 0.435 | 4.35
3003006 | 01_First Floor | 168 | 0.168 | 0.504 | 5.04
3003007 | 01_First Floor | 145 | 0.145 | 0.435 | 4.35
3003052 | 01_First Floor | 168 | 0.168 | 0.504 | 5.04
3003053 | 01_First Floor | 145 | 0.145 | 0.435 | 4.35
3003661 | 02_Second Floor | 168 | 0.168 | 0.504 | 5.04
3003662 | 02_Second Floor | 145 | 0.145 | 0.435 | 4.35
3003707 | 02_Second Floor | 168 | 0.168 | 0.504 | 5.04
3003708 | 02_Second Floor | 145 | 0.145 | 0.435 | 4.35
3003757 | 02_Second Floor | 168 | 0.168 | 0.504 | 5.04
3003758 | 02_Second Floor | 145 | 0.145 | 0.435 | 4.35
3003803 | 02_Second Floor | 168 | 0.168 | 0.504 | 5.04
3003804 | 02_Second Floor | 145 | 0.145 | 0.435 | 4.35
3003849 | 02_Second Floor | 168 | 0.168 | 0.504 | 5.04
3003850 | 02_Second Floor | 145 | 0.145 | 0.435 | 4.35
3003895 | 02_Second Floor | 168 | 0.168 | 0.504 | 5.04
3003896 | 02_Second Floor | 145 | 0.145 | 0.435 | 4.35
3003941 | 02_Second Floor | 168 | 0.168 | 0.504 | 5.04
3003942 | 02_Second Floor | 145 | 0.145 | 0.435 | 4.35
3003988 | 02_Second Floor | 168 | 0.168 | 0.504 | 5.04
3003989 | 02_Second Floor | 145 | 0.145 | 0.435 | 4.35
3004034 | 02_Second Floor | 168 | 0.168 | 0.504 | 5.04
3004035 | 02_Second Floor | 145 | 0.145 | 0.435 | 4.35
3004084 | 02_Second Floor | 168 | 0.168 | 0.504 | 5.04
3004085 | 02_Second Floor | 145 | 0.145 | 0.435 | 4.35
3004130 | 02_Second Floor | 168 | 0.168 | 0.504 | 5.04
3004131 | 02_Second Floor | 145 | 0.145 | 0.435 | 4.35
3004176 | 02_Second Floor | 168 | 0.168 | 0.504 | 5.04
3004177 | 02_Second Floor | 145 | 0.145 | 0.435 | 4.35
3004222 | 02_Second Floor | 168 | 0.168 | 0.504 | 5.04
3004223 | 02_Second Floor | 145 | 0.145 | 0.435 | 4.35
3004268 | 02_Second Floor | 168 | 0.168 | 0.504 | 5.04
3004269 | 02_Second Floor | 145 | 0.145 | 0.435 | 4.35
3004315 | 02_Second Floor | 168 | 0.168 | 0.504 | 5.04
3004316 | 02_Second Floor | 145 | 0.145 | 0.435 | 4.35
3004361 | 02_Second Floor | 168 | 0.168 | 0.504 | 5.04
3004362 | 02_Second Floor | 145 | 0.145 | 0.435 | 4.35
3004411 | 02_Second Floor | 168 | 0.168 | 0.504 | 5.04
3004412 | 02_Second Floor | 145 | 0.145 | 0.435 | 4.35
3004457 | 02_Second Floor | 168 | 0.168 | 0.504 | 5.04
3004458 | 02_Second Floor | 145 | 0.145 | 0.435 | 4.35
3004503 | 02_Second Floor | 168 | 0.168 | 0.504 | 5.04
3004504 | 02_Second Floor | 145 | 0.145 | 0.435 | 4.35
3004549 | 02_Second Floor | 168 | 0.168 | 0.504 | 5.04
3004550 | 02_Second Floor | 145 | 0.145 | 0.435 | 4.35
3004595 | 02_Second Floor | 168 | 0.168 | 0.504 | 5.04
3004596 | 02_Second Floor | 145 | 0.145 | 0.435 | 4.35
3004642 | 02_Second Floor | 168 | 0.168 | 0.504 | 5.04
3004643 | 02_Second Floor | 145 | 0.145 | 0.435 | 4.35
3004688 | 02_Second Floor | 168 | 0.168 | 0.504 | 5.04
3004689 | 02_Second Floor | 145 | 0.145 | 0.435 | 4.35
3004738 | 02_Second Floor | 168 | 0.168 | 0.504 | 5.04
3004739 | 02_Second Floor | 145 | 0.145 | 0.435 | 4.35
3004784 | 02_Second Floor | 168 | 0.168 | 0.504 | 5.04
3004785 | 02_Second Floor | 145 | 0.145 | 0.435 | 4.35
3004830 | 02_Second Floor | 168 | 0.168 | 0.504 | 5.04
3004831 | 02_Second Floor | 145 | 0.145 | 0.435 | 4.35
3004876 | 02_Second Floor | 168 | 0.168 | 0.504 | 5.04
3004877 | 02_Second Floor | 145 | 0.145 | 0.435 | 4.35
3004922 | 02_Second Floor | 168 | 0.168 | 0.504 | 5.04
3004923 | 02_Second Floor | 145 | 0.145 | 0.435 | 4.35
3004969 | 02_Second Floor | 168 | 0.168 | 0.504 | 5.04
3004970 | 02_Second Floor | 145 | 0.145 | 0.435 | 4.35
3005015 | 02_Second Floor | 168 | 0.168 | 0.504 | 5.04
3005016 | 02_Second Floor | 145 | 0.145 | 0.435 | 4.35
3005065 | 02_Second Floor | 168 | 0.168 | 0.504 | 5.04
3005066 | 02_Second Floor | 145 | 0.145 | 0.435 | 4.35
3005111 | 02_Second Floor | 168 | 0.168 | 0.504 | 5.04
3005112 | 02_Second Floor | 145 | 0.145 | 0.435 | 4.35
3005157 | 02_Second Floor | 168 | 0.168 | 0.504 | 5.04
3005158 | 02_Second Floor | 145 | 0.145 | 0.435 | 4.35
3005203 | 02_Second Floor | 168 | 0.168 | 0.504 | 5.04
3005204 | 02_Second Floor | 145 | 0.145 | 0.435 | 4.35
3005249 | 02_Second Floor | 168 | 0.168 | 0.504 | 5.04
3005250 | 02_Second Floor | 145 | 0.145 | 0.435 | 4.35
3005858 | 03_Third Floor | 168 | 0.168 | 0.504 | 5.04
3005859 | 03_Third Floor | 145 | 0.145 | 0.435 | 4.35
3005904 | 03_Third Floor | 168 | 0.168 | 0.504 | 5.04
3005905 | 03_Third Floor | 145 | 0.145 | 0.435 | 4.35
3005954 | 03_Third Floor | 168 | 0.168 | 0.504 | 5.04
3005955 | 03_Third Floor | 145 | 0.145 | 0.435 | 4.35
3006000 | 03_Third Floor | 168 | 0.168 | 0.504 | 5.04
3006001 | 03_Third Floor | 145 | 0.145 | 0.435 | 4.35
3006046 | 03_Third Floor | 168 | 0.168 | 0.504 | 5.04
3006047 | 03_Third Floor | 145 | 0.145 | 0.435 | 4.35
3006092 | 03_Third Floor | 168 | 0.168 | 0.504 | 5.04
3006093 | 03_Third Floor | 145 | 0.145 | 0.435 | 4.35
3006138 | 03_Third Floor | 168 | 0.168 | 0.504 | 5.04
3006139 | 03_Third Floor | 145 | 0.145 | 0.435 | 4.35
3006185 | 03_Third Floor | 168 | 0.168 | 0.504 | 5.04
3006186 | 03_Third Floor | 145 | 0.145 | 0.435 | 4.35
3006231 | 03_Third Floor | 168 | 0.168 | 0.504 | 5.04
3006232 | 03_Third Floor | 145 | 0.145 | 0.435 | 4.35
3006281 | 03_Third Floor | 168 | 0.168 | 0.504 | 5.04
3006282 | 03_Third Floor | 145 | 0.145 | 0.435 | 4.35
3006327 | 03_Third Floor | 168 | 0.168 | 0.504 | 5.04
3006328 | 03_Third Floor | 145 | 0.145 | 0.435 | 4.35
3006373 | 03_Third Floor | 168 | 0.168 | 0.504 | 5.04
3006374 | 03_Third Floor | 145 | 0.145 | 0.435 | 4.35
3006419 | 03_Third Floor | 168 | 0.168 | 0.504 | 5.04
3006420 | 03_Third Floor | 145 | 0.145 | 0.435 | 4.35
3006465 | 03_Third Floor | 168 | 0.168 | 0.504 | 5.04
3006466 | 03_Third Floor | 145 | 0.145 | 0.435 | 4.35
3006512 | 03_Third Floor | 168 | 0.168 | 0.504 | 5.04
3006513 | 03_Third Floor | 145 | 0.145 | 0.435 | 4.35
3006558 | 03_Third Floor | 168 | 0.168 | 0.504 | 5.04
3006559 | 03_Third Floor | 145 | 0.145 | 0.435 | 4.35
3006608 | 03_Third Floor | 168 | 0.168 | 0.504 | 5.04
3006609 | 03_Third Floor | 145 | 0.145 | 0.435 | 4.35
3006654 | 03_Third Floor | 168 | 0.168 | 0.504 | 5.04
3006655 | 03_Third Floor | 145 | 0.145 | 0.435 | 4.35
3006700 | 03_Third Floor | 168 | 0.168 | 0.504 | 5.04
3006701 | 03_Third Floor | 145 | 0.145 | 0.435 | 4.35
3006746 | 03_Third Floor | 168 | 0.168 | 0.504 | 5.04
3006747 | 03_Third Floor | 145 | 0.145 | 0.435 | 4.35
3006792 | 03_Third Floor | 168 | 0.168 | 0.504 | 5.04
3006793 | 03_Third Floor | 145 | 0.145 | 0.435 | 4.35
3006839 | 03_Third Floor | 168 | 0.168 | 0.504 | 5.04
3006840 | 03_Third Floor | 145 | 0.145 | 0.435 | 4.35
3006885 | 03_Third Floor | 168 | 0.168 | 0.504 | 5.04
3006886 | 03_Third Floor | 145 | 0.145 | 0.435 | 4.35
3006935 | 03_Third Floor | 168 | 0.168 | 0.504 | 5.04
3006936 | 03_Third Floor | 145 | 0.145 | 0.435 | 4.35
3006981 | 03_Third Floor | 168 | 0.168 | 0.504 | 5.04
3006982 | 03_Third Floor | 145 | 0.145 | 0.435 | 4.35
3007027 | 03_Third Floor | 168 | 0.168 | 0.504 | 5.04
3007028 | 03_Third Floor | 145 | 0.145 | 0.435 | 4.35
3007073 | 03_Third Floor | 168 | 0.168 | 0.504 | 5.04
3007074 | 03_Third Floor | 145 | 0.145 | 0.435 | 4.35
3007119 | 03_Third Floor | 168 | 0.168 | 0.504 | 5.04
3007120 | 03_Third Floor | 145 | 0.145 | 0.435 | 4.35
3007166 | 03_Third Floor | 168 | 0.168 | 0.504 | 5.04
3007167 | 03_Third Floor | 145 | 0.145 | 0.435 | 4.35
3007212 | 03_Third Floor | 168 | 0.168 | 0.504 | 5.04
3007213 | 03_Third Floor | 145 | 0.145 | 0.435 | 4.35
3007262 | 03_Third Floor | 168 | 0.168 | 0.504 | 5.04
3007263 | 03_Third Floor | 145 | 0.145 | 0.435 | 4.35
3007308 | 03_Third Floor | 168 | 0.168 | 0.504 | 5.04
3007309 | 03_Third Floor | 145 | 0.145 | 0.435 | 4.35
3007354 | 03_Third Floor | 168 | 0.168 | 0.504 | 5.04
3007355 | 03_Third Floor | 145 | 0.145 | 0.435 | 4.35
3007400 | 03_Third Floor | 168 | 0.168 | 0.504 | 5.04
3007401 | 03_Third Floor | 145 | 0.145 | 0.435 | 4.35
3007446 | 03_Third Floor | 168 | 0.168 | 0.504 | 5.04
3007447 | 03_Third Floor | 145 | 0.145 | 0.435 | 4.35
3008053 | 04_Fourth Floor | 168 | 0.168 | 0.504 | 5.04
3008054 | 04_Fourth Floor | 145 | 0.145 | 0.435 | 4.35
3008099 | 04_Fourth Floor | 168 | 0.168 | 0.504 | 5.04
3008100 | 04_Fourth Floor | 145 | 0.145 | 0.435 | 4.35
3008149 | 04_Fourth Floor | 168 | 0.168 | 0.504 | 5.04
3008150 | 04_Fourth Floor | 145 | 0.145 | 0.435 | 4.35
3008195 | 04_Fourth Floor | 168 | 0.168 | 0.504 | 5.04
3008196 | 04_Fourth Floor | 145 | 0.145 | 0.435 | 4.35
3008241 | 04_Fourth Floor | 168 | 0.168 | 0.504 | 5.04
3008242 | 04_Fourth Floor | 145 | 0.145 | 0.435 | 4.35
3008287 | 04_Fourth Floor | 168 | 0.168 | 0.504 | 5.04
3008288 | 04_Fourth Floor | 145 | 0.145 | 0.435 | 4.35
3008333 | 04_Fourth Floor | 168 | 0.168 | 0.504 | 5.04
3008334 | 04_Fourth Floor | 145 | 0.145 | 0.435 | 4.35
3008380 | 04_Fourth Floor | 168 | 0.168 | 0.504 | 5.04
3008381 | 04_Fourth Floor | 145 | 0.145 | 0.435 | 4.35
3008426 | 04_Fourth Floor | 168 | 0.168 | 0.504 | 5.04
3008427 | 04_Fourth Floor | 145 | 0.145 | 0.435 | 4.35
3008476 | 04_Fourth Floor | 168 | 0.168 | 0.504 | 5.04
3008477 | 04_Fourth Floor | 145 | 0.145 | 0.435 | 4.35
3008522 | 04_Fourth Floor | 168 | 0.168 | 0.504 | 5.04
3008523 | 04_Fourth Floor | 145 | 0.145 | 0.435 | 4.35
3008568 | 04_Fourth Floor | 168 | 0.168 | 0.504 | 5.04
3008569 | 04_Fourth Floor | 145 | 0.145 | 0.435 | 4.35
3008614 | 04_Fourth Floor | 168 | 0.168 | 0.504 | 5.04
3008615 | 04_Fourth Floor | 145 | 0.145 | 0.435 | 4.35
3008660 | 04_Fourth Floor | 168 | 0.168 | 0.504 | 5.04
3008661 | 04_Fourth Floor | 145 | 0.145 | 0.435 | 4.35
3008707 | 04_Fourth Floor | 168 | 0.168 | 0.504 | 5.04
3008708 | 04_Fourth Floor | 145 | 0.145 | 0.435 | 4.35
3008753 | 04_Fourth Floor | 168 | 0.168 | 0.504 | 5.04
3008754 | 04_Fourth Floor | 145 | 0.145 | 0.435 | 4.35
3008803 | 04_Fourth Floor | 168 | 0.168 | 0.504 | 5.04
3008804 | 04_Fourth Floor | 145 | 0.145 | 0.435 | 4.35
3008849 | 04_Fourth Floor | 168 | 0.168 | 0.504 | 5.04
3008850 | 04_Fourth Floor | 145 | 0.145 | 0.435 | 4.35
3008895 | 04_Fourth Floor | 168 | 0.168 | 0.504 | 5.04
3008896 | 04_Fourth Floor | 145 | 0.145 | 0.435 | 4.35
3008941 | 04_Fourth Floor | 168 | 0.168 | 0.504 | 5.04
3008942 | 04_Fourth Floor | 145 | 0.145 | 0.435 | 4.35
3008987 | 04_Fourth Floor | 168 | 0.168 | 0.504 | 5.04
3008988 | 04_Fourth Floor | 145 | 0.145 | 0.435 | 4.35
3009034 | 04_Fourth Floor | 168 | 0.168 | 0.504 | 5.04
3009035 | 04_Fourth Floor | 145 | 0.145 | 0.435 | 4.35
3009080 | 04_Fourth Floor | 168 | 0.168 | 0.504 | 5.04
3009081 | 04_Fourth Floor | 145 | 0.145 | 0.435 | 4.35
3009130 | 04_Fourth Floor | 168 | 0.168 | 0.504 | 5.04
3009131 | 04_Fourth Floor | 145 | 0.145 | 0.435 | 4.35
3009176 | 04_Fourth Floor | 168 | 0.168 | 0.504 | 5.04
3009177 | 04_Fourth Floor | 145 | 0.145 | 0.435 | 4.35
3009222 | 04_Fourth Floor | 168 | 0.168 | 0.504 | 5.04
3009223 | 04_Fourth Floor | 145 | 0.145 | 0.435 | 4.35
3009268 | 04_Fourth Floor | 168 | 0.168 | 0.504 | 5.04
3009269 | 04_Fourth Floor | 145 | 0.145 | 0.435 | 4.35
3009314 | 04_Fourth Floor | 168 | 0.168 | 0.504 | 5.04
3009315 | 04_Fourth Floor | 145 | 0.145 | 0.435 | 4.35
3009361 | 04_Fourth Floor | 168 | 0.168 | 0.504 | 5.04
3009362 | 04_Fourth Floor | 145 | 0.145 | 0.435 | 4.35
3009407 | 04_Fourth Floor | 168 | 0.168 | 0.504 | 5.04
3009408 | 04_Fourth Floor | 145 | 0.145 | 0.435 | 4.35
3009457 | 04_Fourth Floor | 168 | 0.168 | 0.504 | 5.04
3009458 | 04_Fourth Floor | 145 | 0.145 | 0.435 | 4.35
3009503 | 04_Fourth Floor | 168 | 0.168 | 0.504 | 5.04
3009504 | 04_Fourth Floor | 145 | 0.145 | 0.435 | 4.35
3009549 | 04_Fourth Floor | 168 | 0.168 | 0.504 | 5.04
3009550 | 04_Fourth Floor | 145 | 0.145 | 0.435 | 4.35
3009595 | 04_Fourth Floor | 168 | 0.168 | 0.504 | 5.04
3009596 | 04_Fourth Floor | 145 | 0.145 | 0.435 | 4.35
3009641 | 04_Fourth Floor | 168 | 0.168 | 0.504 | 5.04
3009642 | 04_Fourth Floor | 145 | 0.145 | 0.435 | 4.35
3010248 | 05_Fifth Floor | 168 | 0.168 | 0.504 | 5.04
3010249 | 05_Fifth Floor | 145 | 0.145 | 0.435 | 4.35
3010294 | 05_Fifth Floor | 168 | 0.168 | 0.504 | 5.04
3010295 | 05_Fifth Floor | 145 | 0.145 | 0.435 | 4.35
3010344 | 05_Fifth Floor | 168 | 0.168 | 0.504 | 5.04
3010345 | 05_Fifth Floor | 145 | 0.145 | 0.435 | 4.35
3010390 | 05_Fifth Floor | 168 | 0.168 | 0.504 | 5.04
3010391 | 05_Fifth Floor | 145 | 0.145 | 0.435 | 4.35
3010436 | 05_Fifth Floor | 168 | 0.168 | 0.504 | 5.04
3010437 | 05_Fifth Floor | 145 | 0.145 | 0.435 | 4.35
3010482 | 05_Fifth Floor | 168 | 0.168 | 0.504 | 5.04
3010483 | 05_Fifth Floor | 145 | 0.145 | 0.435 | 4.35
3010528 | 05_Fifth Floor | 168 | 0.168 | 0.504 | 5.04
3010529 | 05_Fifth Floor | 145 | 0.145 | 0.435 | 4.35
3010575 | 05_Fifth Floor | 168 | 0.168 | 0.504 | 5.04
3010576 | 05_Fifth Floor | 145 | 0.145 | 0.435 | 4.35
3010621 | 05_Fifth Floor | 168 | 0.168 | 0.504 | 5.04
3010622 | 05_Fifth Floor | 145 | 0.145 | 0.435 | 4.35
3010671 | 05_Fifth Floor | 168 | 0.168 | 0.504 | 5.04
3010672 | 05_Fifth Floor | 145 | 0.145 | 0.435 | 4.35
3010717 | 05_Fifth Floor | 168 | 0.168 | 0.504 | 5.04
3010718 | 05_Fifth Floor | 145 | 0.145 | 0.435 | 4.35
3010763 | 05_Fifth Floor | 168 | 0.168 | 0.504 | 5.04
3010764 | 05_Fifth Floor | 145 | 0.145 | 0.435 | 4.35
3010809 | 05_Fifth Floor | 168 | 0.168 | 0.504 | 5.04
3010810 | 05_Fifth Floor | 145 | 0.145 | 0.435 | 4.35
3010855 | 05_Fifth Floor | 168 | 0.168 | 0.504 | 5.04
3010856 | 05_Fifth Floor | 145 | 0.145 | 0.435 | 4.35
3010902 | 05_Fifth Floor | 168 | 0.168 | 0.504 | 5.04
3010903 | 05_Fifth Floor | 145 | 0.145 | 0.435 | 4.35
3010948 | 05_Fifth Floor | 168 | 0.168 | 0.504 | 5.04
3010949 | 05_Fifth Floor | 145 | 0.145 | 0.435 | 4.35
3010998 | 05_Fifth Floor | 168 | 0.168 | 0.504 | 5.04
3010999 | 05_Fifth Floor | 145 | 0.145 | 0.435 | 4.35
3011044 | 05_Fifth Floor | 168 | 0.168 | 0.504 | 5.04
3011045 | 05_Fifth Floor | 145 | 0.145 | 0.435 | 4.35
3011090 | 05_Fifth Floor | 168 | 0.168 | 0.504 | 5.04
3011091 | 05_Fifth Floor | 145 | 0.145 | 0.435 | 4.35
3011136 | 05_Fifth Floor | 168 | 0.168 | 0.504 | 5.04
3011137 | 05_Fifth Floor | 145 | 0.145 | 0.435 | 4.35
3011182 | 05_Fifth Floor | 168 | 0.168 | 0.504 | 5.04
3011183 | 05_Fifth Floor | 145 | 0.145 | 0.435 | 4.35
3011229 | 05_Fifth Floor | 168 | 0.168 | 0.504 | 5.04
3011230 | 05_Fifth Floor | 145 | 0.145 | 0.435 | 4.35
3011275 | 05_Fifth Floor | 168 | 0.168 | 0.504 | 5.04
3011276 | 05_Fifth Floor | 145 | 0.145 | 0.435 | 4.35
3011325 | 05_Fifth Floor | 168 | 0.168 | 0.504 | 5.04
3011326 | 05_Fifth Floor | 145 | 0.145 | 0.435 | 4.35
3011371 | 05_Fifth Floor | 168 | 0.168 | 0.504 | 5.04
3011372 | 05_Fifth Floor | 145 | 0.145 | 0.435 | 4.35
3011417 | 05_Fifth Floor | 168 | 0.168 | 0.504 | 5.04
3011418 | 05_Fifth Floor | 145 | 0.145 | 0.435 | 4.35
3011463 | 05_Fifth Floor | 168 | 0.168 | 0.504 | 5.04
3011464 | 05_Fifth Floor | 145 | 0.145 | 0.435 | 4.35
3011509 | 05_Fifth Floor | 168 | 0.168 | 0.504 | 5.04
3011510 | 05_Fifth Floor | 145 | 0.145 | 0.435 | 4.35
3011556 | 05_Fifth Floor | 168 | 0.168 | 0.504 | 5.04
3011557 | 05_Fifth Floor | 145 | 0.145 | 0.435 | 4.35
3011602 | 05_Fifth Floor | 168 | 0.168 | 0.504 | 5.04
3011603 | 05_Fifth Floor | 145 | 0.145 | 0.435 | 4.35
3011652 | 05_Fifth Floor | 168 | 0.168 | 0.504 | 5.04
3011653 | 05_Fifth Floor | 145 | 0.145 | 0.435 | 4.35
3011698 | 05_Fifth Floor | 168 | 0.168 | 0.504 | 5.04
3011699 | 05_Fifth Floor | 145 | 0.145 | 0.435 | 4.35
3011744 | 05_Fifth Floor | 168 | 0.168 | 0.504 | 5.04
3011745 | 05_Fifth Floor | 145 | 0.145 | 0.435 | 4.35
3011790 | 05_Fifth Floor | 168 | 0.168 | 0.504 | 5.04
3011791 | 05_Fifth Floor | 145 | 0.145 | 0.435 | 4.35
3011836 | 05_Fifth Floor | 168 | 0.168 | 0.504 | 5.04
3011837 | 05_Fifth Floor | 145 | 0.145 | 0.435 | 4.35
3012445 | 06_Sixth Floor | 168 | 0.168 | 0.504 | 5.04
3012446 | 06_Sixth Floor | 145 | 0.145 | 0.435 | 4.35
3012491 | 06_Sixth Floor | 168 | 0.168 | 0.504 | 5.04
3012492 | 06_Sixth Floor | 145 | 0.145 | 0.435 | 4.35
3012541 | 06_Sixth Floor | 168 | 0.168 | 0.504 | 5.04
3012542 | 06_Sixth Floor | 145 | 0.145 | 0.435 | 4.35
3012587 | 06_Sixth Floor | 168 | 0.168 | 0.504 | 5.04
3012588 | 06_Sixth Floor | 145 | 0.145 | 0.435 | 4.35
3012633 | 06_Sixth Floor | 168 | 0.168 | 0.504 | 5.04
3012634 | 06_Sixth Floor | 145 | 0.145 | 0.435 | 4.35
3012679 | 06_Sixth Floor | 168 | 0.168 | 0.504 | 5.04
3012680 | 06_Sixth Floor | 145 | 0.145 | 0.435 | 4.35
3012725 | 06_Sixth Floor | 168 | 0.168 | 0.504 | 5.04
3012726 | 06_Sixth Floor | 145 | 0.145 | 0.435 | 4.35
3012772 | 06_Sixth Floor | 168 | 0.168 | 0.504 | 5.04
3012773 | 06_Sixth Floor | 145 | 0.145 | 0.435 | 4.35
3012818 | 06_Sixth Floor | 168 | 0.168 | 0.504 | 5.04
3012819 | 06_Sixth Floor | 145 | 0.145 | 0.435 | 4.35
3012868 | 06_Sixth Floor | 168 | 0.168 | 0.504 | 5.04
3012869 | 06_Sixth Floor | 145 | 0.145 | 0.435 | 4.35
3012914 | 06_Sixth Floor | 168 | 0.168 | 0.504 | 5.04
3012915 | 06_Sixth Floor | 145 | 0.145 | 0.435 | 4.35
3012960 | 06_Sixth Floor | 168 | 0.168 | 0.504 | 5.04
3012961 | 06_Sixth Floor | 145 | 0.145 | 0.435 | 4.35
3013006 | 06_Sixth Floor | 168 | 0.168 | 0.504 | 5.04
3013007 | 06_Sixth Floor | 145 | 0.145 | 0.435 | 4.35
3013052 | 06_Sixth Floor | 168 | 0.168 | 0.504 | 5.04
3013053 | 06_Sixth Floor | 145 | 0.145 | 0.435 | 4.35
3013099 | 06_Sixth Floor | 168 | 0.168 | 0.504 | 5.04
3013100 | 06_Sixth Floor | 145 | 0.145 | 0.435 | 4.35
3013145 | 06_Sixth Floor | 168 | 0.168 | 0.504 | 5.04
3013146 | 06_Sixth Floor | 145 | 0.145 | 0.435 | 4.35
3013195 | 06_Sixth Floor | 168 | 0.168 | 0.504 | 5.04
3013196 | 06_Sixth Floor | 145 | 0.145 | 0.435 | 4.35
3013241 | 06_Sixth Floor | 168 | 0.168 | 0.504 | 5.04
3013242 | 06_Sixth Floor | 145 | 0.145 | 0.435 | 4.35
3013287 | 06_Sixth Floor | 168 | 0.168 | 0.504 | 5.04
3013288 | 06_Sixth Floor | 145 | 0.145 | 0.435 | 4.35
3013333 | 06_Sixth Floor | 168 | 0.168 | 0.504 | 5.04
3013334 | 06_Sixth Floor | 145 | 0.145 | 0.435 | 4.35
3013379 | 06_Sixth Floor | 168 | 0.168 | 0.504 | 5.04
3013380 | 06_Sixth Floor | 145 | 0.145 | 0.435 | 4.35
3013426 | 06_Sixth Floor | 168 | 0.168 | 0.504 | 5.04
3013427 | 06_Sixth Floor | 145 | 0.145 | 0.435 | 4.35
3013472 | 06_Sixth Floor | 168 | 0.168 | 0.504 | 5.04
3013473 | 06_Sixth Floor | 145 | 0.145 | 0.435 | 4.35
3013522 | 06_Sixth Floor | 168 | 0.168 | 0.504 | 5.04
3013523 | 06_Sixth Floor | 145 | 0.145 | 0.435 | 4.35
3013568 | 06_Sixth Floor | 168 | 0.168 | 0.504 | 5.04
3013569 | 06_Sixth Floor | 145 | 0.145 | 0.435 | 4.35
3013614 | 06_Sixth Floor | 168 | 0.168 | 0.504 | 5.04
3013615 | 06_Sixth Floor | 145 | 0.145 | 0.435 | 4.35
3013660 | 06_Sixth Floor | 168 | 0.168 | 0.504 | 5.04
3013661 | 06_Sixth Floor | 145 | 0.145 | 0.435 | 4.35
3013706 | 06_Sixth Floor | 168 | 0.168 | 0.504 | 5.04
3013707 | 06_Sixth Floor | 145 | 0.145 | 0.435 | 4.35
3013753 | 06_Sixth Floor | 168 | 0.168 | 0.504 | 5.04
3013754 | 06_Sixth Floor | 145 | 0.145 | 0.435 | 4.35
3013799 | 06_Sixth Floor | 168 | 0.168 | 0.504 | 5.04
3013800 | 06_Sixth Floor | 145 | 0.145 | 0.435 | 4.35
3013849 | 06_Sixth Floor | 168 | 0.168 | 0.504 | 5.04
3013850 | 06_Sixth Floor | 145 | 0.145 | 0.435 | 4.35
3013895 | 06_Sixth Floor | 168 | 0.168 | 0.504 | 5.04
3013896 | 06_Sixth Floor | 145 | 0.145 | 0.435 | 4.35
3013941 | 06_Sixth Floor | 168 | 0.168 | 0.504 | 5.04
3013942 | 06_Sixth Floor | 145 | 0.145 | 0.435 | 4.35
3013987 | 06_Sixth Floor | 168 | 0.168 | 0.504 | 5.04
3013988 | 06_Sixth Floor | 145 | 0.145 | 0.435 | 4.35
3014033 | 06_Sixth Floor | 168 | 0.168 | 0.504 | 5.04
3014034 | 06_Sixth Floor | 145 | 0.145 | 0.435 | 4.35
3014640 | 07_Seventh Floor | 168 | 0.168 | 0.504 | 5.04
3014641 | 07_Seventh Floor | 145 | 0.145 | 0.435 | 4.35
3014686 | 07_Seventh Floor | 168 | 0.168 | 0.504 | 5.04
3014687 | 07_Seventh Floor | 145 | 0.145 | 0.435 | 4.35
3014736 | 07_Seventh Floor | 168 | 0.168 | 0.504 | 5.04
3014737 | 07_Seventh Floor | 145 | 0.145 | 0.435 | 4.35
3014782 | 07_Seventh Floor | 168 | 0.168 | 0.504 | 5.04
3014783 | 07_Seventh Floor | 145 | 0.145 | 0.435 | 4.35
3014828 | 07_Seventh Floor | 168 | 0.168 | 0.504 | 5.04
3014829 | 07_Seventh Floor | 145 | 0.145 | 0.435 | 4.35
3014874 | 07_Seventh Floor | 168 | 0.168 | 0.504 | 5.04
3014875 | 07_Seventh Floor | 145 | 0.145 | 0.435 | 4.35
3014920 | 07_Seventh Floor | 168 | 0.168 | 0.504 | 5.04
3014921 | 07_Seventh Floor | 145 | 0.145 | 0.435 | 4.35
3014967 | 07_Seventh Floor | 168 | 0.168 | 0.504 | 5.04
3014968 | 07_Seventh Floor | 145 | 0.145 | 0.435 | 4.35
3015013 | 07_Seventh Floor | 168 | 0.168 | 0.504 | 5.04
3015014 | 07_Seventh Floor | 145 | 0.145 | 0.435 | 4.35
3015063 | 07_Seventh Floor | 168 | 0.168 | 0.504 | 5.04
3015064 | 07_Seventh Floor | 145 | 0.145 | 0.435 | 4.35
3015109 | 07_Seventh Floor | 168 | 0.168 | 0.504 | 5.04
3015110 | 07_Seventh Floor | 145 | 0.145 | 0.435 | 4.35
3015155 | 07_Seventh Floor | 168 | 0.168 | 0.504 | 5.04
3015156 | 07_Seventh Floor | 145 | 0.145 | 0.435 | 4.35
3015201 | 07_Seventh Floor | 168 | 0.168 | 0.504 | 5.04
3015202 | 07_Seventh Floor | 145 | 0.145 | 0.435 | 4.35
3015247 | 07_Seventh Floor | 168 | 0.168 | 0.504 | 5.04
3015248 | 07_Seventh Floor | 145 | 0.145 | 0.435 | 4.35
3015294 | 07_Seventh Floor | 168 | 0.168 | 0.504 | 5.04
3015295 | 07_Seventh Floor | 145 | 0.145 | 0.435 | 4.35
3015340 | 07_Seventh Floor | 168 | 0.168 | 0.504 | 5.04
3015341 | 07_Seventh Floor | 145 | 0.145 | 0.435 | 4.35
3015390 | 07_Seventh Floor | 168 | 0.168 | 0.504 | 5.04
3015391 | 07_Seventh Floor | 145 | 0.145 | 0.435 | 4.35
3015436 | 07_Seventh Floor | 168 | 0.168 | 0.504 | 5.04
3015437 | 07_Seventh Floor | 145 | 0.145 | 0.435 | 4.35
3015482 | 07_Seventh Floor | 168 | 0.168 | 0.504 | 5.04
3015483 | 07_Seventh Floor | 145 | 0.145 | 0.435 | 4.35
3015528 | 07_Seventh Floor | 168 | 0.168 | 0.504 | 5.04
3015529 | 07_Seventh Floor | 145 | 0.145 | 0.435 | 4.35
3015574 | 07_Seventh Floor | 168 | 0.168 | 0.504 | 5.04
3015575 | 07_Seventh Floor | 145 | 0.145 | 0.435 | 4.35
3015621 | 07_Seventh Floor | 168 | 0.168 | 0.504 | 5.04
3015622 | 07_Seventh Floor | 145 | 0.145 | 0.435 | 4.35
3015667 | 07_Seventh Floor | 168 | 0.168 | 0.504 | 5.04
3015668 | 07_Seventh Floor | 145 | 0.145 | 0.435 | 4.35
3015717 | 07_Seventh Floor | 168 | 0.168 | 0.504 | 5.04
3015718 | 07_Seventh Floor | 145 | 0.145 | 0.435 | 4.35
3015763 | 07_Seventh Floor | 168 | 0.168 | 0.504 | 5.04
3015764 | 07_Seventh Floor | 145 | 0.145 | 0.435 | 4.35
3015809 | 07_Seventh Floor | 168 | 0.168 | 0.504 | 5.04
3015810 | 07_Seventh Floor | 145 | 0.145 | 0.435 | 4.35
3015855 | 07_Seventh Floor | 168 | 0.168 | 0.504 | 5.04
3015856 | 07_Seventh Floor | 145 | 0.145 | 0.435 | 4.35
3015901 | 07_Seventh Floor | 168 | 0.168 | 0.504 | 5.04
3015902 | 07_Seventh Floor | 145 | 0.145 | 0.435 | 4.35
3015948 | 07_Seventh Floor | 168 | 0.168 | 0.504 | 5.04
3015949 | 07_Seventh Floor | 145 | 0.145 | 0.435 | 4.35
3015994 | 07_Seventh Floor | 168 | 0.168 | 0.504 | 5.04
3015995 | 07_Seventh Floor | 145 | 0.145 | 0.435 | 4.35
3016044 | 07_Seventh Floor | 168 | 0.168 | 0.504 | 5.04
3016045 | 07_Seventh Floor | 145 | 0.145 | 0.435 | 4.35
3016090 | 07_Seventh Floor | 168 | 0.168 | 0.504 | 5.04
3016091 | 07_Seventh Floor | 145 | 0.145 | 0.435 | 4.35
3016136 | 07_Seventh Floor | 168 | 0.168 | 0.504 | 5.04
3016137 | 07_Seventh Floor | 145 | 0.145 | 0.435 | 4.35
3016182 | 07_Seventh Floor | 168 | 0.168 | 0.504 | 5.04
3016183 | 07_Seventh Floor | 145 | 0.145 | 0.435 | 4.35
3016228 | 07_Seventh Floor | 168 | 0.168 | 0.504 | 5.04
3016229 | 07_Seventh Floor | 145 | 0.145 | 0.435 | 4.35

# IfcWall: Basic Wall:ARC_22.10_WA_LB_SB14_gen_BERSnl (1232)
Type - PredefinedType: STANDARD
Type - Pset_ReinforcementBarPitchOfWall - Description: metselwerken
Type - Pset_WallCommon - ThermalTransmittance: 3.92857 kg/K/s3
Classification: 22.10 binnenwanden; niet constructief, algemeen (verzamelniveau) (Uniformat); Material: ARC_FME.g2_Fg2 Masonry_00_gen_BERSnl
Qto_WallBaseQuantities - Height: 380 cm; Width: 14 cm
Pset_EnvironmentalImpactIndicators - Reference: ARC_22.10_WA_LB_SB14_gen_BERSnl; sets with these values: 2
Pset_WallCommon - IsExternal: no; Reference: ARC_22.10_WA_LB_SB14_gen_BERSnl; LoadBearing: no; ExtendToStructure: no
Name (Basic Wall:ARC_22.10_WA_LB_SB14_gen_BERSnl:...) | In | Length (cm) | GrossFootprintArea (m2) | GrossVolume (m3) | GrossSideArea (m2) | NetSideArea (m2) | NetVolume (m3) | bSI_C_TX_SuperSecretCode
2938170 | 00_Ground Floor | 628 | 0.8792 | 3.34096 | 23.864 | 21.624 | 3.02736 | 1
2938171 | 00_Ground Floor | 514 | 0.7196 | 2.46358 | 17.597 | 17.597 | 2.46358 | 2
2938172 | 00_Ground Floor | 614 | 0.8596 | 2.99558 | 21.397 | 19.157 | 2.68198 | 3
2938173 | 00_Ground Floor | 500 | 0.7 | 2.66 | 19 | 16.76 | 2.3464 | 4
2995736 | 00_Ground Floor | 600 | 0.84 | 3.192 | 22.8 | 20.56 | 2.8784 | 5
2995737 | 00_Ground Floor | 528 | 0.7392 | 2.53806 | 18.129 | 18.129 | 2.53806 | 6
2995738 | 00_Ground Floor | 614 | 0.8596 | 2.99558 | 21.397 | 19.157 | 2.68198 | 7
2995739 | 00_Ground Floor | 514 | 0.7196 | 2.73448 | 19.532 | 17.292 | 2.42088 | 8
2995845 | 00_Ground Floor | 614 | 0.8596 | 3.26648 | 23.332 | 21.092 | 2.95288 | 9
2995846 | 00_Ground Floor | 514 | 0.7196 | 2.46358 | 17.597 | 17.597 | 2.46358 | 10
2995847 | 00_Ground Floor | 614 | 0.8596 | 2.99558 | 21.397 | 19.157 | 2.68198 | 11
2995848 | 00_Ground Floor | 514 | 0.7196 | 2.73448 | 19.532 | 17.292 | 2.42088 | 12
2995904 | 00_Ground Floor | 614 | 0.8596 | 3.26648 | 23.332 | 21.092 | 2.95288 | 13
2995905 | 00_Ground Floor | 514 | 0.7196 | 2.46358 | 17.597 | 17.597 | 2.46358 | 14
2995906 | 00_Ground Floor | 614 | 0.8596 | 2.99558 | 21.397 | 19.157 | 2.68198 | 15
2995907 | 00_Ground Floor | 514 | 0.7196 | 2.73448 | 19.532 | 17.292 | 2.42088 | 16
2995963 | 00_Ground Floor | 614 | 0.8596 | 3.26648 | 23.332 | 21.092 | 2.95288 | 17
2995964 | 00_Ground Floor | 514 | 0.7196 | 2.46358 | 17.597 | 17.597 | 2.46358 | 18
2995965 | 00_Ground Floor | 614 | 0.8596 | 2.99558 | 21.397 | 19.157 | 2.68198 | 19
2995966 | 00_Ground Floor | 514 | 0.7196 | 2.73448 | 19.532 | 17.292 | 2.42088 | 20
2996022 | 00_Ground Floor | 614 | 0.8596 | 3.26648 | 23.332 | 21.092 | 2.95288 | 21
2996023 | 00_Ground Floor | 514 | 0.7196 | 2.46358 | 17.597 | 17.597 | 2.46358 | 22
2996024 | 00_Ground Floor | 614 | 0.8596 | 2.99558 | 21.397 | 19.157 | 2.68198 | 23
2996025 | 00_Ground Floor | 514 | 0.7196 | 2.73448 | 19.532 | 17.292 | 2.42088 | 24
2996081 | 00_Ground Floor | 614 | 0.8596 | 3.26648 | 23.332 | 21.092 | 2.95288 | 25
2996082 | 00_Ground Floor | 514 | 0.7196 | 2.46358 | 17.597 | 17.597 | 2.46358 | 26
2996083 | 00_Ground Floor | 614 | 0.8596 | 2.99558 | 21.397 | 19.157 | 2.68198 | 27
2996084 | 00_Ground Floor | 514 | 0.7196 | 2.73448 | 19.532 | 17.292 | 2.42088 | 28
2996148 | 00_Ground Floor | 614 | 0.8596 | 3.26648 | 23.332 | 21.092 | 2.95288 | 29
2996149 | 00_Ground Floor | 514 | 0.7196 | 2.46358 | 17.597 | 17.597 | 2.46358 | 30
2996150 | 00_Ground Floor | 614 | 0.8596 | 2.99558 | 21.397 | 19.157 | 2.68198 | 31
2996151 | 00_Ground Floor | 514 | 0.7196 | 2.73448 | 19.532 | 17.292 | 2.42088 | 32
2996203 | 00_Ground Floor | 614 | 0.8596 | 3.26648 | 23.332 | 21.092 | 2.95288 | 33
2996204 | 00_Ground Floor | 514 | 0.7196 | 2.46358 | 17.597 | 17.597 | 2.46358 | 34
2996205 | 00_Ground Floor | 614 | 0.8596 | 2.99558 | 21.397 | 19.157 | 2.68198 | 35
2996206 | 00_Ground Floor | 514 | 0.7196 | 2.73448 | 19.532 | 17.292 | 2.42088 | 36
2996262 | 00_Ground Floor | 614 | 0.8596 | 3.26648 | 23.332 | 21.092 | 2.95288 | 37
2996263 | 00_Ground Floor | 514 | 0.7196 | 2.46358 | 17.597 | 17.597 | 2.46358 | 38
2996264 | 00_Ground Floor | 614 | 0.8596 | 2.99558 | 21.397 | 19.157 | 2.68198 | 39
2996265 | 00_Ground Floor | 514 | 0.7196 | 2.73448 | 19.532 | 17.292 | 2.42088 | 40
2996317 | 00_Ground Floor | 614 | 0.8596 | 3.26648 | 23.332 | 21.092 | 2.95288 | 41
2996318 | 00_Ground Floor | 514 | 0.7196 | 2.46358 | 17.597 | 17.597 | 2.46358 | 42
2996319 | 00_Ground Floor | 614 | 0.8596 | 2.99558 | 21.397 | 19.157 | 2.68198 | 43
2996320 | 00_Ground Floor | 514 | 0.7196 | 2.73448 | 19.532 | 17.292 | 2.42088 | 44
2996372 | 00_Ground Floor | 614 | 0.8596 | 3.26648 | 23.332 | 21.092 | 2.95288 | 45
2996373 | 00_Ground Floor | 514 | 0.7196 | 2.46358 | 17.597 | 17.597 | 2.46358 | 46
2996374 | 00_Ground Floor | 614 | 0.8596 | 2.99558 | 21.397 | 19.157 | 2.68198 | 47
2996375 | 00_Ground Floor | 514 | 0.7196 | 2.73448 | 19.532 | 17.292 | 2.42088 | 48
2996427 | 00_Ground Floor | 614 | 0.8596 | 3.26648 | 23.332 | 21.092 | 2.95288 | 49
2996428 | 00_Ground Floor | 514 | 0.7196 | 2.46358 | 17.597 | 17.597 | 2.46358 | 50
2996429 | 00_Ground Floor | 614 | 0.8596 | 2.99558 | 21.397 | 19.157 | 2.68198 | 51
2996430 | 00_Ground Floor | 514 | 0.7196 | 2.73448 | 19.532 | 17.292 | 2.42088 | 52
2996482 | 00_Ground Floor | 614 | 0.8596 | 3.26648 | 23.332 | 21.092 | 2.95288 | 53
2996483 | 00_Ground Floor | 514 | 0.7196 | 2.46358 | 17.597 | 17.597 | 2.46358 | 54
2996484 | 00_Ground Floor | 614 | 0.8596 | 2.99558 | 21.397 | 19.157 | 2.68198 | 55
2996485 | 00_Ground Floor | 514 | 0.7196 | 2.73448 | 19.532 | 17.292 | 2.42088 | 56
2996592 | 00_Ground Floor | 614 | 0.8596 | 3.26648 | 23.332 | 21.092 | 2.95288 | 57
2996593 | 00_Ground Floor | 514 | 0.7196 | 2.46358 | 17.597 | 17.597 | 2.46358 | 58
2996594 | 00_Ground Floor | 614 | 0.8596 | 2.99558 | 21.397 | 19.157 | 2.68198 | 59
2996595 | 00_Ground Floor | 514 | 0.7196 | 2.73448 | 19.532 | 17.292 | 2.42088 | 60
2996647 | 00_Ground Floor | 614 | 0.8596 | 3.26648 | 23.332 | 21.092 | 2.95288 | 61
2996648 | 00_Ground Floor | 514 | 0.7196 | 2.46358 | 17.597 | 17.597 | 2.46358 | 62
2996649 | 00_Ground Floor | 614 | 0.8596 | 2.99558 | 21.397 | 19.157 | 2.68198 | 63
2996650 | 00_Ground Floor | 514 | 0.7196 | 2.73448 | 19.532 | 17.292 | 2.42088 | 64
2996706 | 00_Ground Floor | 614 | 0.8596 | 3.26648 | 23.332 | 21.092 | 2.95288 | 65
2996707 | 00_Ground Floor | 514 | 0.7196 | 2.46358 | 17.597 | 17.597 | 2.46358 | 66
2996708 | 00_Ground Floor | 614 | 0.8596 | 2.99558 | 21.397 | 19.157 | 2.68198 | 67
2996709 | 00_Ground Floor | 514 | 0.7196 | 2.73448 | 19.532 | 17.292 | 2.42088 | 68
2996761 | 00_Ground Floor | 614 | 0.8596 | 3.26648 | 23.332 | 21.092 | 2.95288 | 69
2996762 | 00_Ground Floor | 514 | 0.7196 | 2.46358 | 17.597 | 17.597 | 2.46358 | 70
2996763 | 00_Ground Floor | 614 | 0.8596 | 2.99558 | 21.397 | 19.157 | 2.68198 | 71
2996764 | 00_Ground Floor | 514 | 0.7196 | 2.73448 | 19.532 | 17.292 | 2.42088 | 72
2996816 | 00_Ground Floor | 614 | 0.8596 | 3.26648 | 23.332 | 21.092 | 2.95288 | 73
2996817 | 00_Ground Floor | 514 | 0.7196 | 2.46358 | 17.597 | 17.597 | 2.46358 | 74
2996818 | 00_Ground Floor | 614 | 0.8596 | 2.99558 | 21.397 | 19.157 | 2.68198 | 75
2996819 | 00_Ground Floor | 514 | 0.7196 | 2.73448 | 19.532 | 17.292 | 2.42088 | 76
2996871 | 00_Ground Floor | 614 | 0.8596 | 3.26648 | 23.332 | 21.092 | 2.95288 | 77
2996872 | 00_Ground Floor | 514 | 0.7196 | 2.46358 | 17.597 | 17.597 | 2.46358 | 78
2996873 | 00_Ground Floor | 614 | 0.8596 | 2.99558 | 21.397 | 19.157 | 2.68198 | 79
2996874 | 00_Ground Floor | 514 | 0.7196 | 2.73448 | 19.532 | 17.292 | 2.42088 | 80
2996926 | 00_Ground Floor | 614 | 0.8596 | 3.26648 | 23.332 | 21.092 | 2.95288 | 81
2996927 | 00_Ground Floor | 514 | 0.7196 | 2.46358 | 17.597 | 17.597 | 2.46358 | 82
2996928 | 00_Ground Floor | 614 | 0.8596 | 2.99558 | 21.397 | 19.157 | 2.68198 | 83
2996929 | 00_Ground Floor | 514 | 0.7196 | 2.73448 | 19.532 | 17.292 | 2.42088 | 84
2996998 | 00_Ground Floor | 614 | 0.8596 | 3.26648 | 23.332 | 21.092 | 2.95288 | 85
2996999 | 00_Ground Floor | 514 | 0.7196 | 2.46358 | 17.597 | 17.597 | 2.46358 | 86
2997000 | 00_Ground Floor | 614 | 0.8596 | 2.99558 | 21.397 | 19.157 | 2.68198 | 87
2997001 | 00_Ground Floor | 514 | 0.7196 | 2.73448 | 19.532 | 17.292 | 2.42088 | 88
2997053 | 00_Ground Floor | 614 | 0.8596 | 3.26648 | 23.332 | 21.092 | 2.95288 | 89
2997054 | 00_Ground Floor | 514 | 0.7196 | 2.46358 | 17.597 | 17.597 | 2.46358 | 90
2997055 | 00_Ground Floor | 614 | 0.8596 | 2.99558 | 21.397 | 19.157 | 2.68198 | 91
2997056 | 00_Ground Floor | 514 | 0.7196 | 2.73448 | 19.532 | 17.292 | 2.42088 | 92
2997112 | 00_Ground Floor | 614 | 0.8596 | 3.26648 | 23.332 | 21.092 | 2.95288 | 93
2997113 | 00_Ground Floor | 514 | 0.7196 | 2.46358 | 17.597 | 17.597 | 2.46358 | 94
2997114 | 00_Ground Floor | 614 | 0.8596 | 2.99558 | 21.397 | 19.157 | 2.68198 | 95
2997115 | 00_Ground Floor | 514 | 0.7196 | 2.73448 | 19.532 | 17.292 | 2.42088 | 96
2997167 | 00_Ground Floor | 614 | 0.8596 | 3.26648 | 23.332 | 21.092 | 2.95288 | 97
2997168 | 00_Ground Floor | 514 | 0.7196 | 2.46358 | 17.597 | 17.597 | 2.46358 | 98
2997169 | 00_Ground Floor | 614 | 0.8596 | 2.99558 | 21.397 | 19.157 | 2.68198 | 99
2997170 | 00_Ground Floor | 514 | 0.7196 | 2.73448 | 19.532 | 17.292 | 2.42088 | 100
2997222 | 00_Ground Floor | 614 | 0.8596 | 3.26648 | 23.332 | 21.092 | 2.95288 | 101
2997223 | 00_Ground Floor | 514 | 0.7196 | 2.46358 | 17.597 | 17.597 | 2.46358 | 102
2997224 | 00_Ground Floor | 614 | 0.8596 | 2.99558 | 21.397 | 19.157 | 2.68198 | 103
2997225 | 00_Ground Floor | 514 | 0.7196 | 2.73448 | 19.532 | 17.292 | 2.42088 | 104
2997277 | 00_Ground Floor | 614 | 0.8596 | 3.26648 | 23.332 | 21.092 | 2.95288 | 105
2997278 | 00_Ground Floor | 514 | 0.7196 | 2.46358 | 17.597 | 17.597 | 2.46358 | 106
2997279 | 00_Ground Floor | 614 | 0.8596 | 2.99558 | 21.397 | 19.157 | 2.68198 | 107
2997280 | 00_Ground Floor | 514 | 0.7196 | 2.73448 | 19.532 | 17.292 | 2.42088 | 108
2997332 | 00_Ground Floor | 614 | 0.8596 | 3.26648 | 23.332 | 21.092 | 2.95288 | 109
2997333 | 00_Ground Floor | 514 | 0.7196 | 2.46358 | 17.597 | 17.597 | 2.46358 | 110
2997334 | 00_Ground Floor | 614 | 0.8596 | 2.99558 | 21.397 | 19.157 | 2.68198 | 111
2997335 | 00_Ground Floor | 514 | 0.7196 | 2.73448 | 19.532 | 17.292 | 2.42088 | 112
2997404 | 00_Ground Floor | 614 | 0.8596 | 3.26648 | 23.332 | 21.092 | 2.95288 | 113
2997405 | 00_Ground Floor | 514 | 0.7196 | 2.46358 | 17.597 | 17.597 | 2.46358 | 114
2997406 | 00_Ground Floor | 614 | 0.8596 | 2.99558 | 21.397 | 19.157 | 2.68198 | 115
2997407 | 00_Ground Floor | 514 | 0.7196 | 2.73448 | 19.532 | 17.292 | 2.42088 | 116
2997459 | 00_Ground Floor | 614 | 0.8596 | 3.26648 | 23.332 | 21.092 | 2.95288 | 117
2997460 | 00_Ground Floor | 514 | 0.7196 | 2.46358 | 17.597 | 17.597 | 2.46358 | 118
2997461 | 00_Ground Floor | 614 | 0.8596 | 2.99558 | 21.397 | 19.157 | 2.68198 | 119
2997462 | 00_Ground Floor | 514 | 0.7196 | 2.73448 | 19.532 | 17.292 | 2.42088 | 120
2997518 | 00_Ground Floor | 614 | 0.8596 | 3.26648 | 23.332 | 21.092 | 2.95288 | 121
2997519 | 00_Ground Floor | 514 | 0.7196 | 2.46358 | 17.597 | 17.597 | 2.46358 | 122
2997520 | 00_Ground Floor | 614 | 0.8596 | 2.99558 | 21.397 | 19.157 | 2.68198 | 123
2997521 | 00_Ground Floor | 514 | 0.7196 | 2.73448 | 19.532 | 17.292 | 2.42088 | 124
2997573 | 00_Ground Floor | 614 | 0.8596 | 3.26648 | 23.332 | 21.092 | 2.95288 | 125
2997574 | 00_Ground Floor | 514 | 0.7196 | 2.46358 | 17.597 | 17.597 | 2.46358 | 126
2997575 | 00_Ground Floor | 614 | 0.8596 | 2.99558 | 21.397 | 19.157 | 2.68198 | 127
2997576 | 00_Ground Floor | 514 | 0.7196 | 2.73448 | 19.532 | 17.292 | 2.42088 | 128
2997628 | 00_Ground Floor | 614 | 0.8596 | 3.26648 | 23.332 | 21.092 | 2.95288 | 129
2997629 | 00_Ground Floor | 514 | 0.7196 | 2.46358 | 17.597 | 17.597 | 2.46358 | 130
2997630 | 00_Ground Floor | 614 | 0.8596 | 2.99558 | 21.397 | 19.157 | 2.68198 | 131
2997631 | 00_Ground Floor | 514 | 0.7196 | 2.73448 | 19.532 | 17.292 | 2.42088 | 132
2997683 | 00_Ground Floor | 614 | 0.8596 | 3.26648 | 23.332 | 21.092 | 2.95288 | 133
2997684 | 00_Ground Floor | 514 | 0.7196 | 2.46358 | 17.597 | 17.597 | 2.46358 | 134
2997685 | 00_Ground Floor | 614 | 0.8596 | 2.99558 | 21.397 | 19.157 | 2.68198 | 135
2997686 | 00_Ground Floor | 514 | 0.7196 | 2.73448 | 19.532 | 17.292 | 2.42088 | 136
2997738 | 00_Ground Floor | 614 | 0.8596 | 3.26648 | 23.332 | 21.092 | 2.95288 | 137
2997739 | 00_Ground Floor | 514 | 0.7196 | 2.46358 | 17.597 | 17.597 | 2.46358 | 138
2997740 | 00_Ground Floor | 614 | 0.8596 | 2.99558 | 21.397 | 19.157 | 2.68198 | 139
2997741 | 00_Ground Floor | 514 | 0.7196 | 2.73448 | 19.532 | 17.292 | 2.42088 | 140
2997931 | 00_Ground Floor | 110 | 0.154 | 0.5852 | 4.18 | 4.18 | 0.5852 | 141
2998147 | 00_Ground Floor | 110 | 0.154 | 0.5852 | 4.18 | 4.18 | 0.5852 | 142
2998157 | 00_Ground Floor | 110 | 0.154 | 0.5852 | 4.18 | 4.18 | 0.5852 | 143
2998165 | 00_Ground Floor | 110 | 0.154 | 0.5852 | 4.18 | 4.18 | 0.5852 | 144
2998175 | 00_Ground Floor | 110 | 0.154 | 0.5852 | 4.18 | 4.18 | 0.5852 | 145
2998183 | 00_Ground Floor | 110 | 0.154 | 0.5852 | 4.18 | 4.18 | 0.5852 | 146
2998261 | 00_Ground Floor | 110 | 0.154 | 0.5852 | 4.18 | 4.18 | 0.5852 | 147
2998366 | 00_Ground Floor | 3176 | 4.4464 | 6.22132 | 44.438 | 44.438 | 6.22132 | 148
2998456 | 00_Ground Floor | 5152 | 7.2128 | 9.56564 | 68.326 | 68.326 | 9.56564 | 149
2998596 | 00_Ground Floor | 96 | 0.1344 | 0.51072 | 3.648 | 3.648 | 0.51072 | 150
2998714 | 00_Ground Floor | 110 | 0.154 | 0.5852 | 4.18 | 4.18 | 0.5852 | 151
2998828 | 00_Ground Floor | 110 | 0.154 | 0.5852 | 4.18 | 4.18 | 0.5852 | 152
2998958 | 00_Ground Floor | 110 | 0.154 | 0.5852 | 4.18 | 4.18 | 0.5852 | 153
2999028 | 00_Ground Floor | 110 | 0.154 | 0.5852 | 4.18 | 4.18 | 0.5852 | 154
3001437 | 01_First Floor | 628 | 0.8792 | 3.34096 | 23.864 | 21.624 | 3.02736 | 155
3001438 | 01_First Floor | 514 | 0.7196 | 2.46358 | 17.597 | 17.597 | 2.46358 | 156
3001439 | 01_First Floor | 614 | 0.8596 | 2.99558 | 21.397 | 19.157 | 2.68198 | 157
3001440 | 01_First Floor | 500 | 0.7 | 2.66 | 19 | 16.76 | 2.3464 | 158
3001484 | 01_First Floor | 600 | 0.84 | 3.192 | 22.8 | 20.56 | 2.8784 | 159
3001485 | 01_First Floor | 528 | 0.7392 | 2.53806 | 18.129 | 18.129 | 2.53806 | 160
3001486 | 01_First Floor | 614 | 0.8596 | 2.99558 | 21.397 | 19.157 | 2.68198 | 161
3001487 | 01_First Floor | 514 | 0.7196 | 2.73448 | 19.532 | 17.292 | 2.42088 | 162
3001535 | 01_First Floor | 614 | 0.8596 | 3.26648 | 23.332 | 21.092 | 2.95288 | 163
3001536 | 01_First Floor | 514 | 0.7196 | 2.46358 | 17.597 | 17.597 | 2.46358 | 164
3001537 | 01_First Floor | 614 | 0.8596 | 2.99558 | 21.397 | 19.157 | 2.68198 | 165
3001538 | 01_First Floor | 514 | 0.7196 | 2.73448 | 19.532 | 17.292 | 2.42088 | 166
3001582 | 01_First Floor | 614 | 0.8596 | 3.26648 | 23.332 | 21.092 | 2.95288 | 167
3001583 | 01_First Floor | 514 | 0.7196 | 2.46358 | 17.597 | 17.597 | 2.46358 | 168
3001584 | 01_First Floor | 614 | 0.8596 | 2.99558 | 21.397 | 19.157 | 2.68198 | 169
3001585 | 01_First Floor | 514 | 0.7196 | 2.73448 | 19.532 | 17.292 | 2.42088 | 170
3001629 | 01_First Floor | 614 | 0.8596 | 3.26648 | 23.332 | 21.092 | 2.95288 | 171
3001630 | 01_First Floor | 514 | 0.7196 | 2.46358 | 17.597 | 17.597 | 2.46358 | 172
3001631 | 01_First Floor | 614 | 0.8596 | 2.99558 | 21.397 | 19.157 | 2.68198 | 173
3001632 | 01_First Floor | 514 | 0.7196 | 2.73448 | 19.532 | 17.292 | 2.42088 | 174
3001676 | 01_First Floor | 614 | 0.8596 | 3.26648 | 23.332 | 21.092 | 2.95288 | 175
3001677 | 01_First Floor | 514 | 0.7196 | 2.46358 | 17.597 | 17.597 | 2.46358 | 176
3001678 | 01_First Floor | 614 | 0.8596 | 2.99558 | 21.397 | 19.157 | 2.68198 | 177
3001679 | 01_First Floor | 514 | 0.7196 | 2.73448 | 19.532 | 17.292 | 2.42088 | 178
3001723 | 01_First Floor | 614 | 0.8596 | 3.26648 | 23.332 | 21.092 | 2.95288 | 179
3001724 | 01_First Floor | 514 | 0.7196 | 2.46358 | 17.597 | 17.597 | 2.46358 | 180
3001725 | 01_First Floor | 614 | 0.8596 | 2.99558 | 21.397 | 19.157 | 2.68198 | 181
3001726 | 01_First Floor | 514 | 0.7196 | 2.73448 | 19.532 | 17.292 | 2.42088 | 182
3001771 | 01_First Floor | 614 | 0.8596 | 3.26648 | 23.332 | 21.092 | 2.95288 | 183
3001772 | 01_First Floor | 514 | 0.7196 | 2.46358 | 17.597 | 17.597 | 2.46358 | 184
3001773 | 01_First Floor | 614 | 0.8596 | 2.99558 | 21.397 | 19.157 | 2.68198 | 185
3001774 | 01_First Floor | 514 | 0.7196 | 2.73448 | 19.532 | 17.292 | 2.42088 | 186
3001817 | 01_First Floor | 614 | 0.8596 | 3.26648 | 23.332 | 21.092 | 2.95288 | 187
3001818 | 01_First Floor | 514 | 0.7196 | 2.46358 | 17.597 | 17.597 | 2.46358 | 188
3001819 | 01_First Floor | 614 | 0.8596 | 2.99558 | 21.397 | 19.157 | 2.68198 | 189
3001820 | 01_First Floor | 514 | 0.7196 | 2.73448 | 19.532 | 17.292 | 2.42088 | 190
3001867 | 01_First Floor | 614 | 0.8596 | 3.26648 | 23.332 | 21.092 | 2.95288 | 191
3001868 | 01_First Floor | 514 | 0.7196 | 2.46358 | 17.597 | 17.597 | 2.46358 | 192
3001869 | 01_First Floor | 614 | 0.8596 | 2.99558 | 21.397 | 19.157 | 2.68198 | 193
3001870 | 01_First Floor | 514 | 0.7196 | 2.73448 | 19.532 | 17.292 | 2.42088 | 194
3001913 | 01_First Floor | 614 | 0.8596 | 3.26648 | 23.332 | 21.092 | 2.95288 | 195
3001914 | 01_First Floor | 514 | 0.7196 | 2.46358 | 17.597 | 17.597 | 2.46358 | 196
3001915 | 01_First Floor | 614 | 0.8596 | 2.99558 | 21.397 | 19.157 | 2.68198 | 197
3001916 | 01_First Floor | 514 | 0.7196 | 2.73448 | 19.532 | 17.292 | 2.42088 | 198
3001959 | 01_First Floor | 614 | 0.8596 | 3.26648 | 23.332 | 21.092 | 2.95288 | 199
3001960 | 01_First Floor | 514 | 0.7196 | 2.46358 | 17.597 | 17.597 | 2.46358 | 200
3001961 | 01_First Floor | 614 | 0.8596 | 2.99558 | 21.397 | 19.157 | 2.68198 | 201
3001962 | 01_First Floor | 514 | 0.7196 | 2.73448 | 19.532 | 17.292 | 2.42088 | 202
3002005 | 01_First Floor | 614 | 0.8596 | 3.26648 | 23.332 | 21.092 | 2.95288 | 203
3002006 | 01_First Floor | 514 | 0.7196 | 2.46358 | 17.597 | 17.597 | 2.46358 | 204
3002007 | 01_First Floor | 614 | 0.8596 | 2.99558 | 21.397 | 19.157 | 2.68198 | 205
3002008 | 01_First Floor | 514 | 0.7196 | 2.73448 | 19.532 | 17.292 | 2.42088 | 206
3002051 | 01_First Floor | 614 | 0.8596 | 3.26648 | 23.332 | 21.092 | 2.95288 | 207
3002052 | 01_First Floor | 514 | 0.7196 | 2.46358 | 17.597 | 17.597 | 2.46358 | 208
3002053 | 01_First Floor | 614 | 0.8596 | 2.99558 | 21.397 | 19.157 | 2.68198 | 209
3002054 | 01_First Floor | 514 | 0.7196 | 2.73448 | 19.532 | 17.292 | 2.42088 | 210
3002098 | 01_First Floor | 614 | 0.8596 | 3.26648 | 23.332 | 21.092 | 2.95288 | 211
3002099 | 01_First Floor | 514 | 0.7196 | 2.46358 | 17.597 | 17.597 | 2.46358 | 212
3002100 | 01_First Floor | 614 | 0.8596 | 2.99558 | 21.397 | 19.157 | 2.68198 | 213
3002101 | 01_First Floor | 514 | 0.7196 | 2.73448 | 19.532 | 17.292 | 2.42088 | 214
3002144 | 01_First Floor | 614 | 0.8596 | 3.26648 | 23.332 | 21.092 | 2.95288 | 215
3002145 | 01_First Floor | 514 | 0.7196 | 2.46358 | 17.597 | 17.597 | 2.46358 | 216
3002146 | 01_First Floor | 614 | 0.8596 | 2.99558 | 21.397 | 19.157 | 2.68198 | 217
3002147 | 01_First Floor | 514 | 0.7196 | 2.73448 | 19.532 | 17.292 | 2.42088 | 218
3002194 | 01_First Floor | 614 | 0.8596 | 3.26648 | 23.332 | 21.092 | 2.95288 | 219
3002195 | 01_First Floor | 514 | 0.7196 | 2.46358 | 17.597 | 17.597 | 2.46358 | 220
3002196 | 01_First Floor | 614 | 0.8596 | 2.99558 | 21.397 | 19.157 | 2.68198 | 221
3002197 | 01_First Floor | 514 | 0.7196 | 2.73448 | 19.532 | 17.292 | 2.42088 | 222
3002240 | 01_First Floor | 614 | 0.8596 | 3.26648 | 23.332 | 21.092 | 2.95288 | 223
3002241 | 01_First Floor | 514 | 0.7196 | 2.46358 | 17.597 | 17.597 | 2.46358 | 224
3002242 | 01_First Floor | 614 | 0.8596 | 2.99558 | 21.397 | 19.157 | 2.68198 | 225
3002243 | 01_First Floor | 514 | 0.7196 | 2.73448 | 19.532 | 17.292 | 2.42088 | 226
3002286 | 01_First Floor | 614 | 0.8596 | 3.26648 | 23.332 | 21.092 | 2.95288 | 227
3002287 | 01_First Floor | 514 | 0.7196 | 2.46358 | 17.597 | 17.597 | 2.46358 | 228
3002288 | 01_First Floor | 614 | 0.8596 | 2.99558 | 21.397 | 19.157 | 2.68198 | 229
3002289 | 01_First Floor | 514 | 0.7196 | 2.73448 | 19.532 | 17.292 | 2.42088 | 230
3002332 | 01_First Floor | 614 | 0.8596 | 3.26648 | 23.332 | 21.092 | 2.95288 | 231
3002333 | 01_First Floor | 514 | 0.7196 | 2.46358 | 17.597 | 17.597 | 2.46358 | 232
3002334 | 01_First Floor | 614 | 0.8596 | 2.99558 | 21.397 | 19.157 | 2.68198 | 233
3002335 | 01_First Floor | 514 | 0.7196 | 2.73448 | 19.532 | 17.292 | 2.42088 | 234
3002378 | 01_First Floor | 614 | 0.8596 | 3.26648 | 23.332 | 21.092 | 2.95288 | 235
3002379 | 01_First Floor | 514 | 0.7196 | 2.46358 | 17.597 | 17.597 | 2.46358 | 236
3002380 | 01_First Floor | 614 | 0.8596 | 2.99558 | 21.397 | 19.157 | 2.68198 | 237
3002381 | 01_First Floor | 514 | 0.7196 | 2.73448 | 19.532 | 17.292 | 2.42088 | 238
3002425 | 01_First Floor | 614 | 0.8596 | 3.26648 | 23.332 | 21.092 | 2.95288 | 239
3002426 | 01_First Floor | 514 | 0.7196 | 2.46358 | 17.597 | 17.597 | 2.46358 | 240
3002427 | 01_First Floor | 614 | 0.8596 | 2.99558 | 21.397 | 19.157 | 2.68198 | 241
3002428 | 01_First Floor | 514 | 0.7196 | 2.73448 | 19.532 | 17.292 | 2.42088 | 242
3002471 | 01_First Floor | 614 | 0.8596 | 3.26648 | 23.332 | 21.092 | 2.95288 | 243
3002472 | 01_First Floor | 514 | 0.7196 | 2.46358 | 17.597 | 17.597 | 2.46358 | 244
3002473 | 01_First Floor | 614 | 0.8596 | 2.99558 | 21.397 | 19.157 | 2.68198 | 245
3002474 | 01_First Floor | 514 | 0.7196 | 2.73448 | 19.532 | 17.292 | 2.42088 | 246
3002521 | 01_First Floor | 614 | 0.8596 | 3.26648 | 23.332 | 21.092 | 2.95288 | 247
3002522 | 01_First Floor | 514 | 0.7196 | 2.46358 | 17.597 | 17.597 | 2.46358 | 248
3002523 | 01_First Floor | 614 | 0.8596 | 2.99558 | 21.397 | 19.157 | 2.68198 | 249
3002524 | 01_First Floor | 514 | 0.7196 | 2.73448 | 19.532 | 17.292 | 2.42088 | 250
3002567 | 01_First Floor | 614 | 0.8596 | 3.26648 | 23.332 | 21.092 | 2.95288 | 251
3002568 | 01_First Floor | 514 | 0.7196 | 2.46358 | 17.597 | 17.597 | 2.46358 | 252
3002569 | 01_First Floor | 614 | 0.8596 | 2.99558 | 21.397 | 19.157 | 2.68198 | 253
3002570 | 01_First Floor | 514 | 0.7196 | 2.73448 | 19.532 | 17.292 | 2.42088 | 254
3002613 | 01_First Floor | 614 | 0.8596 | 3.26648 | 23.332 | 21.092 | 2.95288 | 255
3002614 | 01_First Floor | 514 | 0.7196 | 2.46358 | 17.597 | 17.597 | 2.46358 | 256
3002615 | 01_First Floor | 614 | 0.8596 | 2.99558 | 21.397 | 19.157 | 2.68198 | 257
3002616 | 01_First Floor | 514 | 0.7196 | 2.73448 | 19.532 | 17.292 | 2.42088 | 258
3002659 | 01_First Floor | 614 | 0.8596 | 3.26648 | 23.332 | 21.092 | 2.95288 | 259
3002660 | 01_First Floor | 514 | 0.7196 | 2.46358 | 17.597 | 17.597 | 2.46358 | 260
3002661 | 01_First Floor | 614 | 0.8596 | 2.99558 | 21.397 | 19.157 | 2.68198 | 261
3002662 | 01_First Floor | 514 | 0.7196 | 2.73448 | 19.532 | 17.292 | 2.42088 | 262
3002705 | 01_First Floor | 614 | 0.8596 | 3.26648 | 23.332 | 21.092 | 2.95288 | 263
3002706 | 01_First Floor | 514 | 0.7196 | 2.46358 | 17.597 | 17.597 | 2.46358 | 264
3002707 | 01_First Floor | 614 | 0.8596 | 2.99558 | 21.397 | 19.157 | 2.68198 | 265
3002708 | 01_First Floor | 514 | 0.7196 | 2.73448 | 19.532 | 17.292 | 2.42088 | 266
3002752 | 01_First Floor | 614 | 0.8596 | 3.26648 | 23.332 | 21.092 | 2.95288 | 267
3002753 | 01_First Floor | 514 | 0.7196 | 2.46358 | 17.597 | 17.597 | 2.46358 | 268
3002754 | 01_First Floor | 614 | 0.8596 | 2.99558 | 21.397 | 19.157 | 2.68198 | 269
3002755 | 01_First Floor | 514 | 0.7196 | 2.73448 | 19.532 | 17.292 | 2.42088 | 270
3002798 | 01_First Floor | 614 | 0.8596 | 3.26648 | 23.332 | 21.092 | 2.95288 | 271
3002799 | 01_First Floor | 514 | 0.7196 | 2.46358 | 17.597 | 17.597 | 2.46358 | 272
3002800 | 01_First Floor | 614 | 0.8596 | 2.99558 | 21.397 | 19.157 | 2.68198 | 273
3002801 | 01_First Floor | 514 | 0.7196 | 2.73448 | 19.532 | 17.292 | 2.42088 | 274
3002848 | 01_First Floor | 614 | 0.8596 | 3.26648 | 23.332 | 21.092 | 2.95288 | 275
3002849 | 01_First Floor | 514 | 0.7196 | 2.46358 | 17.597 | 17.597 | 2.46358 | 276
3002850 | 01_First Floor | 614 | 0.8596 | 2.99558 | 21.397 | 19.157 | 2.68198 | 277
3002851 | 01_First Floor | 514 | 0.7196 | 2.73448 | 19.532 | 17.292 | 2.42088 | 278
3002894 | 01_First Floor | 614 | 0.8596 | 3.26648 | 23.332 | 21.092 | 2.95288 | 279
3002895 | 01_First Floor | 514 | 0.7196 | 2.46358 | 17.597 | 17.597 | 2.46358 | 280
3002896 | 01_First Floor | 614 | 0.8596 | 2.99558 | 21.397 | 19.157 | 2.68198 | 281
3002897 | 01_First Floor | 514 | 0.7196 | 2.73448 | 19.532 | 17.292 | 2.42088 | 282
3002940 | 01_First Floor | 614 | 0.8596 | 3.26648 | 23.332 | 21.092 | 2.95288 | 283
3002941 | 01_First Floor | 514 | 0.7196 | 2.46358 | 17.597 | 17.597 | 2.46358 | 284
3002942 | 01_First Floor | 614 | 0.8596 | 2.99558 | 21.397 | 19.157 | 2.68198 | 285
3002943 | 01_First Floor | 514 | 0.7196 | 2.73448 | 19.532 | 17.292 | 2.42088 | 286
3002986 | 01_First Floor | 614 | 0.8596 | 3.26648 | 23.332 | 21.092 | 2.95288 | 287
3002987 | 01_First Floor | 514 | 0.7196 | 2.46358 | 17.597 | 17.597 | 2.46358 | 288
3002988 | 01_First Floor | 614 | 0.8596 | 2.99558 | 21.397 | 19.157 | 2.68198 | 289
3002989 | 01_First Floor | 514 | 0.7196 | 2.73448 | 19.532 | 17.292 | 2.42088 | 290
3003032 | 01_First Floor | 614 | 0.8596 | 3.26648 | 23.332 | 21.092 | 2.95288 | 291
3003033 | 01_First Floor | 514 | 0.7196 | 2.46358 | 17.597 | 17.597 | 2.46358 | 292
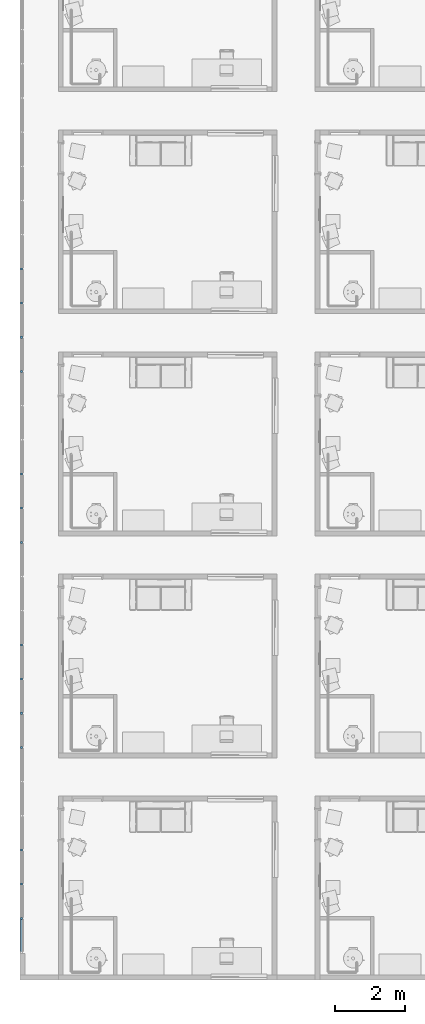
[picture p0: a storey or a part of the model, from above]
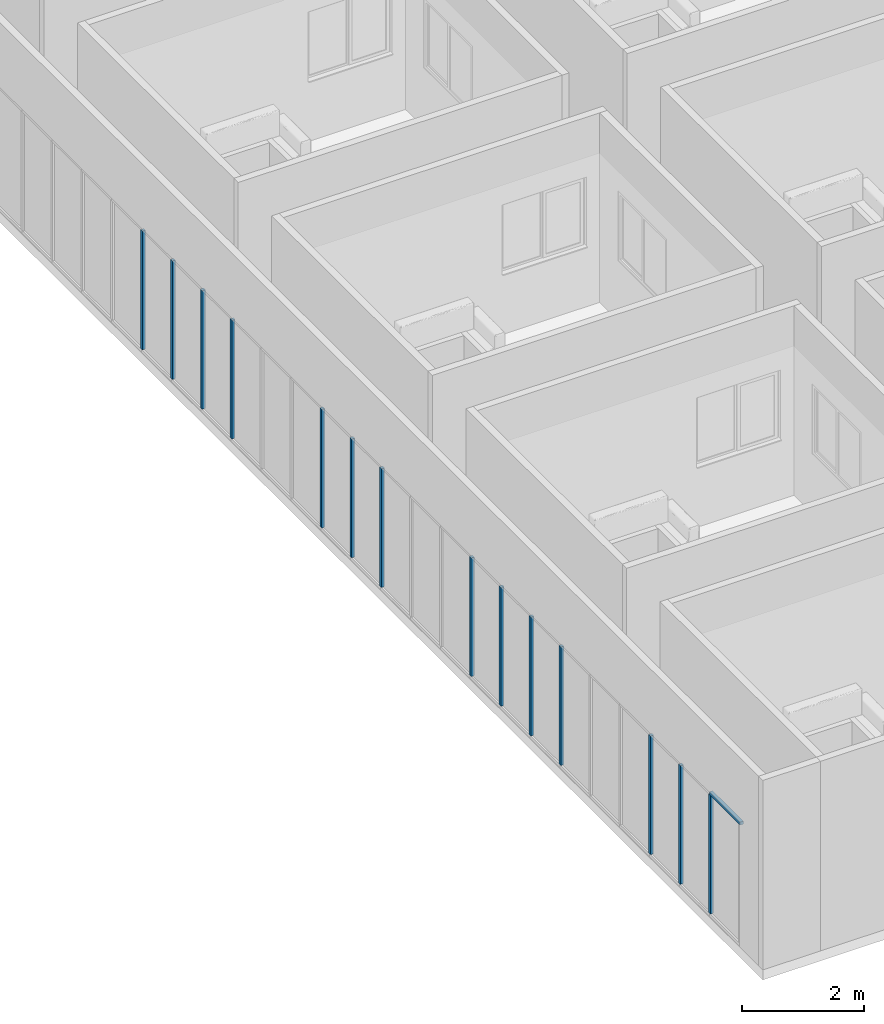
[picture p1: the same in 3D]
Properties of the parts of a building model (IFC4), part 13 of 14

# IfcWall: Basic Wall:ARC_22.10_WA_LB_SB14_gen_BERSnl (1232)
Name (Basic Wall:ARC_22.10_WA_LB_SB14_gen_BERSnl:...) | In | Length (cm) | GrossFootprintArea (m2) | GrossVolume (m3) | GrossSideArea (m2) | NetSideArea (m2) | NetVolume (m3) | bSI_C_TX_SuperSecretCode
3003034 | 01_First Floor | 614 | 0.8596 | 2.99558 | 21.397 | 19.157 | 2.68198 | 293
3003035 | 01_First Floor | 514 | 0.7196 | 2.73448 | 19.532 | 17.292 | 2.42088 | 294
3003079 | 01_First Floor | 110 | 0.154 | 0.5852 | 4.18 | 4.18 | 0.5852 | 295
3003080 | 01_First Floor | 110 | 0.154 | 0.5852 | 4.18 | 4.18 | 0.5852 | 296
3003081 | 01_First Floor | 110 | 0.154 | 0.5852 | 4.18 | 4.18 | 0.5852 | 297
3003082 | 01_First Floor | 110 | 0.154 | 0.5852 | 4.18 | 4.18 | 0.5852 | 298
3003083 | 01_First Floor | 110 | 0.154 | 0.5852 | 4.18 | 4.18 | 0.5852 | 299
3003084 | 01_First Floor | 110 | 0.154 | 0.5852 | 4.18 | 4.18 | 0.5852 | 300
3003085 | 01_First Floor | 110 | 0.154 | 0.5852 | 4.18 | 4.18 | 0.5852 | 301
3003086 | 01_First Floor | 3176 | 4.4464 | 6.22132 | 44.438 | 44.438 | 6.22132 | 302
3003087 | 01_First Floor | 5152 | 7.2128 | 9.56564 | 68.326 | 68.326 | 9.56564 | 303
3003088 | 01_First Floor | 96 | 0.1344 | 0.51072 | 3.648 | 3.648 | 0.51072 | 304
3003089 | 01_First Floor | 110 | 0.154 | 0.5852 | 4.18 | 4.18 | 0.5852 | 305
3003090 | 01_First Floor | 110 | 0.154 | 0.5852 | 4.18 | 4.18 | 0.5852 | 306
3003091 | 01_First Floor | 110 | 0.154 | 0.5852 | 4.18 | 4.18 | 0.5852 | 307
3003092 | 01_First Floor | 110 | 0.154 | 0.5852 | 4.18 | 4.18 | 0.5852 | 308
3003641 | 02_Second Floor | 628 | 0.8792 | 3.34096 | 23.864 | 21.624 | 3.02736 | 309
3003642 | 02_Second Floor | 514 | 0.7196 | 2.46358 | 17.597 | 17.597 | 2.46358 | 310
3003643 | 02_Second Floor | 614 | 0.8596 | 2.99558 | 21.397 | 19.157 | 2.68198 | 311
3003644 | 02_Second Floor | 500 | 0.7 | 2.66 | 19 | 16.76 | 2.3464 | 312
3003687 | 02_Second Floor | 600 | 0.84 | 3.192 | 22.8 | 20.56 | 2.8784 | 313
3003688 | 02_Second Floor | 528 | 0.7392 | 2.53806 | 18.129 | 18.129 | 2.53806 | 314
3003689 | 02_Second Floor | 614 | 0.8596 | 2.99558 | 21.397 | 19.157 | 2.68198 | 315
3003690 | 02_Second Floor | 514 | 0.7196 | 2.73448 | 19.532 | 17.292 | 2.42088 | 316
3003737 | 02_Second Floor | 614 | 0.8596 | 3.26648 | 23.332 | 21.092 | 2.95288 | 317
3003738 | 02_Second Floor | 514 | 0.7196 | 2.46358 | 17.597 | 17.597 | 2.46358 | 318
3003739 | 02_Second Floor | 614 | 0.8596 | 2.99558 | 21.397 | 19.157 | 2.68198 | 319
3003740 | 02_Second Floor | 514 | 0.7196 | 2.73448 | 19.532 | 17.292 | 2.42088 | 320
3003783 | 02_Second Floor | 614 | 0.8596 | 3.26648 | 23.332 | 21.092 | 2.95288 | 321
3003784 | 02_Second Floor | 514 | 0.7196 | 2.46358 | 17.597 | 17.597 | 2.46358 | 322
3003785 | 02_Second Floor | 614 | 0.8596 | 2.99558 | 21.397 | 19.157 | 2.68198 | 323
3003786 | 02_Second Floor | 514 | 0.7196 | 2.73448 | 19.532 | 17.292 | 2.42088 | 324
3003829 | 02_Second Floor | 614 | 0.8596 | 3.26648 | 23.332 | 21.092 | 2.95288 | 325
3003830 | 02_Second Floor | 514 | 0.7196 | 2.46358 | 17.597 | 17.597 | 2.46358 | 326
3003831 | 02_Second Floor | 614 | 0.8596 | 2.99558 | 21.397 | 19.157 | 2.68198 | 327
3003832 | 02_Second Floor | 514 | 0.7196 | 2.73448 | 19.532 | 17.292 | 2.42088 | 328
3003875 | 02_Second Floor | 614 | 0.8596 | 3.26648 | 23.332 | 21.092 | 2.95288 | 329
3003876 | 02_Second Floor | 514 | 0.7196 | 2.46358 | 17.597 | 17.597 | 2.46358 | 330
3003877 | 02_Second Floor | 614 | 0.8596 | 2.99558 | 21.397 | 19.157 | 2.68198 | 331
3003878 | 02_Second Floor | 514 | 0.7196 | 2.73448 | 19.532 | 17.292 | 2.42088 | 332
3003921 | 02_Second Floor | 614 | 0.8596 | 3.26648 | 23.332 | 21.092 | 2.95288 | 333
3003922 | 02_Second Floor | 514 | 0.7196 | 2.46358 | 17.597 | 17.597 | 2.46358 | 334
3003923 | 02_Second Floor | 614 | 0.8596 | 2.99558 | 21.397 | 19.157 | 2.68198 | 335
3003924 | 02_Second Floor | 514 | 0.7196 | 2.73448 | 19.532 | 17.292 | 2.42088 | 336
3003968 | 02_Second Floor | 614 | 0.8596 | 3.26648 | 23.332 | 21.092 | 2.95288 | 337
3003969 | 02_Second Floor | 514 | 0.7196 | 2.46358 | 17.597 | 17.597 | 2.46358 | 338
3003970 | 02_Second Floor | 614 | 0.8596 | 2.99558 | 21.397 | 19.157 | 2.68198 | 339
3003971 | 02_Second Floor | 514 | 0.7196 | 2.73448 | 19.532 | 17.292 | 2.42088 | 340
3004014 | 02_Second Floor | 614 | 0.8596 | 3.26648 | 23.332 | 21.092 | 2.95288 | 341
3004015 | 02_Second Floor | 514 | 0.7196 | 2.46358 | 17.597 | 17.597 | 2.46358 | 342
3004016 | 02_Second Floor | 614 | 0.8596 | 2.99558 | 21.397 | 19.157 | 2.68198 | 343
3004017 | 02_Second Floor | 514 | 0.7196 | 2.73448 | 19.532 | 17.292 | 2.42088 | 344
3004064 | 02_Second Floor | 614 | 0.8596 | 3.26648 | 23.332 | 21.092 | 2.95288 | 345
3004065 | 02_Second Floor | 514 | 0.7196 | 2.46358 | 17.597 | 17.597 | 2.46358 | 346
3004066 | 02_Second Floor | 614 | 0.8596 | 2.99558 | 21.397 | 19.157 | 2.68198 | 347
3004067 | 02_Second Floor | 514 | 0.7196 | 2.73448 | 19.532 | 17.292 | 2.42088 | 348
3004110 | 02_Second Floor | 614 | 0.8596 | 3.26648 | 23.332 | 21.092 | 2.95288 | 349
3004111 | 02_Second Floor | 514 | 0.7196 | 2.46358 | 17.597 | 17.597 | 2.46358 | 350
3004112 | 02_Second Floor | 614 | 0.8596 | 2.99558 | 21.397 | 19.157 | 2.68198 | 351
3004113 | 02_Second Floor | 514 | 0.7196 | 2.73448 | 19.532 | 17.292 | 2.42088 | 352
3004156 | 02_Second Floor | 614 | 0.8596 | 3.26648 | 23.332 | 21.092 | 2.95288 | 353
3004157 | 02_Second Floor | 514 | 0.7196 | 2.46358 | 17.597 | 17.597 | 2.46358 | 354
3004158 | 02_Second Floor | 614 | 0.8596 | 2.99558 | 21.397 | 19.157 | 2.68198 | 355
3004159 | 02_Second Floor | 514 | 0.7196 | 2.73448 | 19.532 | 17.292 | 2.42088 | 356
3004202 | 02_Second Floor | 614 | 0.8596 | 3.26648 | 23.332 | 21.092 | 2.95288 | 357
3004203 | 02_Second Floor | 514 | 0.7196 | 2.46358 | 17.597 | 17.597 | 2.46358 | 358
3004204 | 02_Second Floor | 614 | 0.8596 | 2.99558 | 21.397 | 19.157 | 2.68198 | 359
3004205 | 02_Second Floor | 514 | 0.7196 | 2.73448 | 19.532 | 17.292 | 2.42088 | 360
3004248 | 02_Second Floor | 614 | 0.8596 | 3.26648 | 23.332 | 21.092 | 2.95288 | 361
3004249 | 02_Second Floor | 514 | 0.7196 | 2.46358 | 17.597 | 17.597 | 2.46358 | 362
3004250 | 02_Second Floor | 614 | 0.8596 | 2.99558 | 21.397 | 19.157 | 2.68198 | 363
3004251 | 02_Second Floor | 514 | 0.7196 | 2.73448 | 19.532 | 17.292 | 2.42088 | 364
3004295 | 02_Second Floor | 614 | 0.8596 | 3.26648 | 23.332 | 21.092 | 2.95288 | 365
3004296 | 02_Second Floor | 514 | 0.7196 | 2.46358 | 17.597 | 17.597 | 2.46358 | 366
3004297 | 02_Second Floor | 614 | 0.8596 | 2.99558 | 21.397 | 19.157 | 2.68198 | 367
3004298 | 02_Second Floor | 514 | 0.7196 | 2.73448 | 19.532 | 17.292 | 2.42088 | 368
3004341 | 02_Second Floor | 614 | 0.8596 | 3.26648 | 23.332 | 21.092 | 2.95288 | 369
3004342 | 02_Second Floor | 514 | 0.7196 | 2.46358 | 17.597 | 17.597 | 2.46358 | 370
3004343 | 02_Second Floor | 614 | 0.8596 | 2.99558 | 21.397 | 19.157 | 2.68198 | 371
3004344 | 02_Second Floor | 514 | 0.7196 | 2.73448 | 19.532 | 17.292 | 2.42088 | 372
3004391 | 02_Second Floor | 614 | 0.8596 | 3.26648 | 23.332 | 21.092 | 2.95288 | 373
3004392 | 02_Second Floor | 514 | 0.7196 | 2.46358 | 17.597 | 17.597 | 2.46358 | 374
3004393 | 02_Second Floor | 614 | 0.8596 | 2.99558 | 21.397 | 19.157 | 2.68198 | 375
3004394 | 02_Second Floor | 514 | 0.7196 | 2.73448 | 19.532 | 17.292 | 2.42088 | 376
3004437 | 02_Second Floor | 614 | 0.8596 | 3.26648 | 23.332 | 21.092 | 2.95288 | 377
3004438 | 02_Second Floor | 514 | 0.7196 | 2.46358 | 17.597 | 17.597 | 2.46358 | 378
3004439 | 02_Second Floor | 614 | 0.8596 | 2.99558 | 21.397 | 19.157 | 2.68198 | 379
3004440 | 02_Second Floor | 514 | 0.7196 | 2.73448 | 19.532 | 17.292 | 2.42088 | 380
3004483 | 02_Second Floor | 614 | 0.8596 | 3.26648 | 23.332 | 21.092 | 2.95288 | 381
3004484 | 02_Second Floor | 514 | 0.7196 | 2.46358 | 17.597 | 17.597 | 2.46358 | 382
3004485 | 02_Second Floor | 614 | 0.8596 | 2.99558 | 21.397 | 19.157 | 2.68198 | 383
3004486 | 02_Second Floor | 514 | 0.7196 | 2.73448 | 19.532 | 17.292 | 2.42088 | 384
3004529 | 02_Second Floor | 614 | 0.8596 | 3.26648 | 23.332 | 21.092 | 2.95288 | 385
3004530 | 02_Second Floor | 514 | 0.7196 | 2.46358 | 17.597 | 17.597 | 2.46358 | 386
3004531 | 02_Second Floor | 614 | 0.8596 | 2.99558 | 21.397 | 19.157 | 2.68198 | 387
3004532 | 02_Second Floor | 514 | 0.7196 | 2.73448 | 19.532 | 17.292 | 2.42088 | 388
3004575 | 02_Second Floor | 614 | 0.8596 | 3.26648 | 23.332 | 21.092 | 2.95288 | 389
3004576 | 02_Second Floor | 514 | 0.7196 | 2.46358 | 17.597 | 17.597 | 2.46358 | 390
3004577 | 02_Second Floor | 614 | 0.8596 | 2.99558 | 21.397 | 19.157 | 2.68198 | 391
3004578 | 02_Second Floor | 514 | 0.7196 | 2.73448 | 19.532 | 17.292 | 2.42088 | 392
3004622 | 02_Second Floor | 614 | 0.8596 | 3.26648 | 23.332 | 21.092 | 2.95288 | 393
3004623 | 02_Second Floor | 514 | 0.7196 | 2.46358 | 17.597 | 17.597 | 2.46358 | 394
3004624 | 02_Second Floor | 614 | 0.8596 | 2.99558 | 21.397 | 19.157 | 2.68198 | 395
3004625 | 02_Second Floor | 514 | 0.7196 | 2.73448 | 19.532 | 17.292 | 2.42088 | 396
3004668 | 02_Second Floor | 614 | 0.8596 | 3.26648 | 23.332 | 21.092 | 2.95288 | 397
3004669 | 02_Second Floor | 514 | 0.7196 | 2.46358 | 17.597 | 17.597 | 2.46358 | 398
3004670 | 02_Second Floor | 614 | 0.8596 | 2.99558 | 21.397 | 19.157 | 2.68198 | 399
3004671 | 02_Second Floor | 514 | 0.7196 | 2.73448 | 19.532 | 17.292 | 2.42088 | 400
3004718 | 02_Second Floor | 614 | 0.8596 | 3.26648 | 23.332 | 21.092 | 2.95288 | 401
3004719 | 02_Second Floor | 514 | 0.7196 | 2.46358 | 17.597 | 17.597 | 2.46358 | 402
3004720 | 02_Second Floor | 614 | 0.8596 | 2.99558 | 21.397 | 19.157 | 2.68198 | 403
3004721 | 02_Second Floor | 514 | 0.7196 | 2.73448 | 19.532 | 17.292 | 2.42088 | 404
3004764 | 02_Second Floor | 614 | 0.8596 | 3.26648 | 23.332 | 21.092 | 2.95288 | 405
3004765 | 02_Second Floor | 514 | 0.7196 | 2.46358 | 17.597 | 17.597 | 2.46358 | 406
3004766 | 02_Second Floor | 614 | 0.8596 | 2.99558 | 21.397 | 19.157 | 2.68198 | 407
3004767 | 02_Second Floor | 514 | 0.7196 | 2.73448 | 19.532 | 17.292 | 2.42088 | 408
3004810 | 02_Second Floor | 614 | 0.8596 | 3.26648 | 23.332 | 21.092 | 2.95288 | 409
3004811 | 02_Second Floor | 514 | 0.7196 | 2.46358 | 17.597 | 17.597 | 2.46358 | 410
3004812 | 02_Second Floor | 614 | 0.8596 | 2.99558 | 21.397 | 19.157 | 2.68198 | 411
3004813 | 02_Second Floor | 514 | 0.7196 | 2.73448 | 19.532 | 17.292 | 2.42088 | 412
3004856 | 02_Second Floor | 614 | 0.8596 | 3.26648 | 23.332 | 21.092 | 2.95288 | 413
3004857 | 02_Second Floor | 514 | 0.7196 | 2.46358 | 17.597 | 17.597 | 2.46358 | 414
3004858 | 02_Second Floor | 614 | 0.8596 | 2.99558 | 21.397 | 19.157 | 2.68198 | 415
3004859 | 02_Second Floor | 514 | 0.7196 | 2.73448 | 19.532 | 17.292 | 2.42088 | 416
3004902 | 02_Second Floor | 614 | 0.8596 | 3.26648 | 23.332 | 21.092 | 2.95288 | 417
3004903 | 02_Second Floor | 514 | 0.7196 | 2.46358 | 17.597 | 17.597 | 2.46358 | 418
3004904 | 02_Second Floor | 614 | 0.8596 | 2.99558 | 21.397 | 19.157 | 2.68198 | 419
3004905 | 02_Second Floor | 514 | 0.7196 | 2.73448 | 19.532 | 17.292 | 2.42088 | 420
3004949 | 02_Second Floor | 614 | 0.8596 | 3.26648 | 23.332 | 21.092 | 2.95288 | 421
3004950 | 02_Second Floor | 514 | 0.7196 | 2.46358 | 17.597 | 17.597 | 2.46358 | 422
3004951 | 02_Second Floor | 614 | 0.8596 | 2.99558 | 21.397 | 19.157 | 2.68198 | 423
3004952 | 02_Second Floor | 514 | 0.7196 | 2.73448 | 19.532 | 17.292 | 2.42088 | 424
3004995 | 02_Second Floor | 614 | 0.8596 | 3.26648 | 23.332 | 21.092 | 2.95288 | 425
3004996 | 02_Second Floor | 514 | 0.7196 | 2.46358 | 17.597 | 17.597 | 2.46358 | 426
3004997 | 02_Second Floor | 614 | 0.8596 | 2.99558 | 21.397 | 19.157 | 2.68198 | 427
3004998 | 02_Second Floor | 514 | 0.7196 | 2.73448 | 19.532 | 17.292 | 2.42088 | 428
3005045 | 02_Second Floor | 614 | 0.8596 | 3.26648 | 23.332 | 21.092 | 2.95288 | 429
3005046 | 02_Second Floor | 514 | 0.7196 | 2.46358 | 17.597 | 17.597 | 2.46358 | 430
3005047 | 02_Second Floor | 614 | 0.8596 | 2.99558 | 21.397 | 19.157 | 2.68198 | 431
3005048 | 02_Second Floor | 514 | 0.7196 | 2.73448 | 19.532 | 17.292 | 2.42088 | 432
3005091 | 02_Second Floor | 614 | 0.8596 | 3.26648 | 23.332 | 21.092 | 2.95288 | 433
3005092 | 02_Second Floor | 514 | 0.7196 | 2.46358 | 17.597 | 17.597 | 2.46358 | 434
3005093 | 02_Second Floor | 614 | 0.8596 | 2.99558 | 21.397 | 19.157 | 2.68198 | 435
3005094 | 02_Second Floor | 514 | 0.7196 | 2.73448 | 19.532 | 17.292 | 2.42088 | 436
3005137 | 02_Second Floor | 614 | 0.8596 | 3.26648 | 23.332 | 21.092 | 2.95288 | 437
3005138 | 02_Second Floor | 514 | 0.7196 | 2.46358 | 17.597 | 17.597 | 2.46358 | 438
3005139 | 02_Second Floor | 614 | 0.8596 | 2.99558 | 21.397 | 19.157 | 2.68198 | 439
3005140 | 02_Second Floor | 514 | 0.7196 | 2.73448 | 19.532 | 17.292 | 2.42088 | 440
3005183 | 02_Second Floor | 614 | 0.8596 | 3.26648 | 23.332 | 21.092 | 2.95288 | 441
3005184 | 02_Second Floor | 514 | 0.7196 | 2.46358 | 17.597 | 17.597 | 2.46358 | 442
3005185 | 02_Second Floor | 614 | 0.8596 | 2.99558 | 21.397 | 19.157 | 2.68198 | 443
3005186 | 02_Second Floor | 514 | 0.7196 | 2.73448 | 19.532 | 17.292 | 2.42088 | 444
3005229 | 02_Second Floor | 614 | 0.8596 | 3.26648 | 23.332 | 21.092 | 2.95288 | 445
3005230 | 02_Second Floor | 514 | 0.7196 | 2.46358 | 17.597 | 17.597 | 2.46358 | 446
3005231 | 02_Second Floor | 614 | 0.8596 | 2.99558 | 21.397 | 19.157 | 2.68198 | 447
3005232 | 02_Second Floor | 514 | 0.7196 | 2.73448 | 19.532 | 17.292 | 2.42088 | 448
3005276 | 02_Second Floor | 110 | 0.154 | 0.5852 | 4.18 | 4.18 | 0.5852 | 449
3005277 | 02_Second Floor | 110 | 0.154 | 0.5852 | 4.18 | 4.18 | 0.5852 | 450
3005278 | 02_Second Floor | 110 | 0.154 | 0.5852 | 4.18 | 4.18 | 0.5852 | 451
3005279 | 02_Second Floor | 110 | 0.154 | 0.5852 | 4.18 | 4.18 | 0.5852 | 452
3005280 | 02_Second Floor | 110 | 0.154 | 0.5852 | 4.18 | 4.18 | 0.5852 | 453
3005281 | 02_Second Floor | 110 | 0.154 | 0.5852 | 4.18 | 4.18 | 0.5852 | 454
3005282 | 02_Second Floor | 110 | 0.154 | 0.5852 | 4.18 | 4.18 | 0.5852 | 455
3005283 | 02_Second Floor | 3176 | 4.4464 | 6.22132 | 44.438 | 44.438 | 6.22132 | 456
3005284 | 02_Second Floor | 5152 | 7.2128 | 9.56564 | 68.326 | 68.326 | 9.56564 | 457
3005285 | 02_Second Floor | 96 | 0.1344 | 0.51072 | 3.648 | 3.648 | 0.51072 | 458
3005286 | 02_Second Floor | 110 | 0.154 | 0.5852 | 4.18 | 4.18 | 0.5852 | 459
3005287 | 02_Second Floor | 110 | 0.154 | 0.5852 | 4.18 | 4.18 | 0.5852 | 460
3005288 | 02_Second Floor | 110 | 0.154 | 0.5852 | 4.18 | 4.18 | 0.5852 | 461
3005289 | 02_Second Floor | 110 | 0.154 | 0.5852 | 4.18 | 4.18 | 0.5852 | 462
3005838 | 03_Third Floor | 628 | 0.8792 | 3.34096 | 23.864 | 21.624 | 3.02736 | 463
3005839 | 03_Third Floor | 514 | 0.7196 | 2.46358 | 17.597 | 17.597 | 2.46358 | 464
3005840 | 03_Third Floor | 614 | 0.8596 | 2.99558 | 21.397 | 19.157 | 2.68198 | 465
3005841 | 03_Third Floor | 500 | 0.7 | 2.66 | 19 | 16.76 | 2.3464 | 466
3005884 | 03_Third Floor | 600 | 0.84 | 3.192 | 22.8 | 20.56 | 2.8784 | 467
3005885 | 03_Third Floor | 528 | 0.7392 | 2.53806 | 18.129 | 18.129 | 2.53806 | 468
3005886 | 03_Third Floor | 614 | 0.8596 | 2.99558 | 21.397 | 19.157 | 2.68198 | 469
3005887 | 03_Third Floor | 514 | 0.7196 | 2.73448 | 19.532 | 17.292 | 2.42088 | 470
3005934 | 03_Third Floor | 614 | 0.8596 | 3.26648 | 23.332 | 21.092 | 2.95288 | 471
3005935 | 03_Third Floor | 514 | 0.7196 | 2.46358 | 17.597 | 17.597 | 2.46358 | 472
3005936 | 03_Third Floor | 614 | 0.8596 | 2.99558 | 21.397 | 19.157 | 2.68198 | 473
3005937 | 03_Third Floor | 514 | 0.7196 | 2.73448 | 19.532 | 17.292 | 2.42088 | 474
3005980 | 03_Third Floor | 614 | 0.8596 | 3.26648 | 23.332 | 21.092 | 2.95288 | 475
3005981 | 03_Third Floor | 514 | 0.7196 | 2.46358 | 17.597 | 17.597 | 2.46358 | 476
3005982 | 03_Third Floor | 614 | 0.8596 | 2.99558 | 21.397 | 19.157 | 2.68198 | 477
3005983 | 03_Third Floor | 514 | 0.7196 | 2.73448 | 19.532 | 17.292 | 2.42088 | 478
3006026 | 03_Third Floor | 614 | 0.8596 | 3.26648 | 23.332 | 21.092 | 2.95288 | 479
3006027 | 03_Third Floor | 514 | 0.7196 | 2.46358 | 17.597 | 17.597 | 2.46358 | 480
3006028 | 03_Third Floor | 614 | 0.8596 | 2.99558 | 21.397 | 19.157 | 2.68198 | 481
3006029 | 03_Third Floor | 514 | 0.7196 | 2.73448 | 19.532 | 17.292 | 2.42088 | 482
3006072 | 03_Third Floor | 614 | 0.8596 | 3.26648 | 23.332 | 21.092 | 2.95288 | 483
3006073 | 03_Third Floor | 514 | 0.7196 | 2.46358 | 17.597 | 17.597 | 2.46358 | 484
3006074 | 03_Third Floor | 614 | 0.8596 | 2.99558 | 21.397 | 19.157 | 2.68198 | 485
3006075 | 03_Third Floor | 514 | 0.7196 | 2.73448 | 19.532 | 17.292 | 2.42088 | 486
3006118 | 03_Third Floor | 614 | 0.8596 | 3.26648 | 23.332 | 21.092 | 2.95288 | 487
3006119 | 03_Third Floor | 514 | 0.7196 | 2.46358 | 17.597 | 17.597 | 2.46358 | 488
3006120 | 03_Third Floor | 614 | 0.8596 | 2.99558 | 21.397 | 19.157 | 2.68198 | 489
3006121 | 03_Third Floor | 514 | 0.7196 | 2.73448 | 19.532 | 17.292 | 2.42088 | 490
3006165 | 03_Third Floor | 614 | 0.8596 | 3.26648 | 23.332 | 21.092 | 2.95288 | 491
3006166 | 03_Third Floor | 514 | 0.7196 | 2.46358 | 17.597 | 17.597 | 2.46358 | 492
3006167 | 03_Third Floor | 614 | 0.8596 | 2.99558 | 21.397 | 19.157 | 2.68198 | 493
3006168 | 03_Third Floor | 514 | 0.7196 | 2.73448 | 19.532 | 17.292 | 2.42088 | 494
3006211 | 03_Third Floor | 614 | 0.8596 | 3.26648 | 23.332 | 21.092 | 2.95288 | 495
3006212 | 03_Third Floor | 514 | 0.7196 | 2.46358 | 17.597 | 17.597 | 2.46358 | 496
3006213 | 03_Third Floor | 614 | 0.8596 | 2.99558 | 21.397 | 19.157 | 2.68198 | 497
3006214 | 03_Third Floor | 514 | 0.7196 | 2.73448 | 19.532 | 17.292 | 2.42088 | 498
3006261 | 03_Third Floor | 614 | 0.8596 | 3.26648 | 23.332 | 21.092 | 2.95288 | 499
3006262 | 03_Third Floor | 514 | 0.7196 | 2.46358 | 17.597 | 17.597 | 2.46358 | 500
3006263 | 03_Third Floor | 614 | 0.8596 | 2.99558 | 21.397 | 19.157 | 2.68198 | 501
3006264 | 03_Third Floor | 514 | 0.7196 | 2.73448 | 19.532 | 17.292 | 2.42088 | 502
3006307 | 03_Third Floor | 614 | 0.8596 | 3.26648 | 23.332 | 21.092 | 2.95288 | 503
3006308 | 03_Third Floor | 514 | 0.7196 | 2.46358 | 17.597 | 17.597 | 2.46358 | 504
3006309 | 03_Third Floor | 614 | 0.8596 | 2.99558 | 21.397 | 19.157 | 2.68198 | 505
3006310 | 03_Third Floor | 514 | 0.7196 | 2.73448 | 19.532 | 17.292 | 2.42088 | 506
3006353 | 03_Third Floor | 614 | 0.8596 | 3.26648 | 23.332 | 21.092 | 2.95288 | 507
3006354 | 03_Third Floor | 514 | 0.7196 | 2.46358 | 17.597 | 17.597 | 2.46358 | 508
3006355 | 03_Third Floor | 614 | 0.8596 | 2.99558 | 21.397 | 19.157 | 2.68198 | 509
3006356 | 03_Third Floor | 514 | 0.7196 | 2.73448 | 19.532 | 17.292 | 2.42088 | 510
3006399 | 03_Third Floor | 614 | 0.8596 | 3.26648 | 23.332 | 21.092 | 2.95288 | 511
3006400 | 03_Third Floor | 514 | 0.7196 | 2.46358 | 17.597 | 17.597 | 2.46358 | 512
3006401 | 03_Third Floor | 614 | 0.8596 | 2.99558 | 21.397 | 19.157 | 2.68198 | 513
3006402 | 03_Third Floor | 514 | 0.7196 | 2.73448 | 19.532 | 17.292 | 2.42088 | 514
3006445 | 03_Third Floor | 614 | 0.8596 | 3.26648 | 23.332 | 21.092 | 2.95288 | 515
3006446 | 03_Third Floor | 514 | 0.7196 | 2.46358 | 17.597 | 17.597 | 2.46358 | 516
3006447 | 03_Third Floor | 614 | 0.8596 | 2.99558 | 21.397 | 19.157 | 2.68198 | 517
3006448 | 03_Third Floor | 514 | 0.7196 | 2.73448 | 19.532 | 17.292 | 2.42088 | 518
3006492 | 03_Third Floor | 614 | 0.8596 | 3.26648 | 23.332 | 21.092 | 2.95288 | 519
3006493 | 03_Third Floor | 514 | 0.7196 | 2.46358 | 17.597 | 17.597 | 2.46358 | 520
3006494 | 03_Third Floor | 614 | 0.8596 | 2.99558 | 21.397 | 19.157 | 2.68198 | 521
3006495 | 03_Third Floor | 514 | 0.7196 | 2.73448 | 19.532 | 17.292 | 2.42088 | 522
3006538 | 03_Third Floor | 614 | 0.8596 | 3.26648 | 23.332 | 21.092 | 2.95288 | 523
3006539 | 03_Third Floor | 514 | 0.7196 | 2.46358 | 17.597 | 17.597 | 2.46358 | 524
3006540 | 03_Third Floor | 614 | 0.8596 | 2.99558 | 21.397 | 19.157 | 2.68198 | 525
3006541 | 03_Third Floor | 514 | 0.7196 | 2.73448 | 19.532 | 17.292 | 2.42088 | 526
3006588 | 03_Third Floor | 614 | 0.8596 | 3.26648 | 23.332 | 21.092 | 2.95288 | 527
3006589 | 03_Third Floor | 514 | 0.7196 | 2.46358 | 17.597 | 17.597 | 2.46358 | 528
3006590 | 03_Third Floor | 614 | 0.8596 | 2.99558 | 21.397 | 19.157 | 2.68198 | 529
3006591 | 03_Third Floor | 514 | 0.7196 | 2.73448 | 19.532 | 17.292 | 2.42088 | 530
3006634 | 03_Third Floor | 614 | 0.8596 | 3.26648 | 23.332 | 21.092 | 2.95288 | 531
3006635 | 03_Third Floor | 514 | 0.7196 | 2.46358 | 17.597 | 17.597 | 2.46358 | 532
3006636 | 03_Third Floor | 614 | 0.8596 | 2.99558 | 21.397 | 19.157 | 2.68198 | 533
3006637 | 03_Third Floor | 514 | 0.7196 | 2.73448 | 19.532 | 17.292 | 2.42088 | 534
3006680 | 03_Third Floor | 614 | 0.8596 | 3.26648 | 23.332 | 21.092 | 2.95288 | 535
3006681 | 03_Third Floor | 514 | 0.7196 | 2.46358 | 17.597 | 17.597 | 2.46358 | 536
3006682 | 03_Third Floor | 614 | 0.8596 | 2.99558 | 21.397 | 19.157 | 2.68198 | 537
3006683 | 03_Third Floor | 514 | 0.7196 | 2.73448 | 19.532 | 17.292 | 2.42088 | 538
3006726 | 03_Third Floor | 614 | 0.8596 | 3.26648 | 23.332 | 21.092 | 2.95288 | 539
3006727 | 03_Third Floor | 514 | 0.7196 | 2.46358 | 17.597 | 17.597 | 2.46358 | 540
3006728 | 03_Third Floor | 614 | 0.8596 | 2.99558 | 21.397 | 19.157 | 2.68198 | 541
3006729 | 03_Third Floor | 514 | 0.7196 | 2.73448 | 19.532 | 17.292 | 2.42088 | 542
3006772 | 03_Third Floor | 614 | 0.8596 | 3.26648 | 23.332 | 21.092 | 2.95288 | 543
3006773 | 03_Third Floor | 514 | 0.7196 | 2.46358 | 17.597 | 17.597 | 2.46358 | 544
3006774 | 03_Third Floor | 614 | 0.8596 | 2.99558 | 21.397 | 19.157 | 2.68198 | 545
3006775 | 03_Third Floor | 514 | 0.7196 | 2.73448 | 19.532 | 17.292 | 2.42088 | 546
3006819 | 03_Third Floor | 614 | 0.8596 | 3.26648 | 23.332 | 21.092 | 2.95288 | 547
3006820 | 03_Third Floor | 514 | 0.7196 | 2.46358 | 17.597 | 17.597 | 2.46358 | 548
3006821 | 03_Third Floor | 614 | 0.8596 | 2.99558 | 21.397 | 19.157 | 2.68198 | 549
3006822 | 03_Third Floor | 514 | 0.7196 | 2.73448 | 19.532 | 17.292 | 2.42088 | 550
3006865 | 03_Third Floor | 614 | 0.8596 | 3.26648 | 23.332 | 21.092 | 2.95288 | 551
3006866 | 03_Third Floor | 514 | 0.7196 | 2.46358 | 17.597 | 17.597 | 2.46358 | 552
3006867 | 03_Third Floor | 614 | 0.8596 | 2.99558 | 21.397 | 19.157 | 2.68198 | 553
3006868 | 03_Third Floor | 514 | 0.7196 | 2.73448 | 19.532 | 17.292 | 2.42088 | 554
3006915 | 03_Third Floor | 614 | 0.8596 | 3.26648 | 23.332 | 21.092 | 2.95288 | 555
3006916 | 03_Third Floor | 514 | 0.7196 | 2.46358 | 17.597 | 17.597 | 2.46358 | 556
3006917 | 03_Third Floor | 614 | 0.8596 | 2.99558 | 21.397 | 19.157 | 2.68198 | 557
3006918 | 03_Third Floor | 514 | 0.7196 | 2.73448 | 19.532 | 17.292 | 2.42088 | 558
3006961 | 03_Third Floor | 614 | 0.8596 | 3.26648 | 23.332 | 21.092 | 2.95288 | 559
3006962 | 03_Third Floor | 514 | 0.7196 | 2.46358 | 17.597 | 17.597 | 2.46358 | 560
3006963 | 03_Third Floor | 614 | 0.8596 | 2.99558 | 21.397 | 19.157 | 2.68198 | 561
3006964 | 03_Third Floor | 514 | 0.7196 | 2.73448 | 19.532 | 17.292 | 2.42088 | 562
3007007 | 03_Third Floor | 614 | 0.8596 | 3.26648 | 23.332 | 21.092 | 2.95288 | 563
3007008 | 03_Third Floor | 514 | 0.7196 | 2.46358 | 17.597 | 17.597 | 2.46358 | 564
3007009 | 03_Third Floor | 614 | 0.8596 | 2.99558 | 21.397 | 19.157 | 2.68198 | 565
3007010 | 03_Third Floor | 514 | 0.7196 | 2.73448 | 19.532 | 17.292 | 2.42088 | 566
3007053 | 03_Third Floor | 614 | 0.8596 | 3.26648 | 23.332 | 21.092 | 2.95288 | 567
3007054 | 03_Third Floor | 514 | 0.7196 | 2.46358 | 17.597 | 17.597 | 2.46358 | 568
3007055 | 03_Third Floor | 614 | 0.8596 | 2.99558 | 21.397 | 19.157 | 2.68198 | 569
3007056 | 03_Third Floor | 514 | 0.7196 | 2.73448 | 19.532 | 17.292 | 2.42088 | 570
3007099 | 03_Third Floor | 614 | 0.8596 | 3.26648 | 23.332 | 21.092 | 2.95288 | 571
3007100 | 03_Third Floor | 514 | 0.7196 | 2.46358 | 17.597 | 17.597 | 2.46358 | 572
3007101 | 03_Third Floor | 614 | 0.8596 | 2.99558 | 21.397 | 19.157 | 2.68198 | 573
3007102 | 03_Third Floor | 514 | 0.7196 | 2.73448 | 19.532 | 17.292 | 2.42088 | 574
3007146 | 03_Third Floor | 614 | 0.8596 | 3.26648 | 23.332 | 21.092 | 2.95288 | 575
3007147 | 03_Third Floor | 514 | 0.7196 | 2.46358 | 17.597 | 17.597 | 2.46358 | 576
3007148 | 03_Third Floor | 614 | 0.8596 | 2.99558 | 21.397 | 19.157 | 2.68198 | 577
3007149 | 03_Third Floor | 514 | 0.7196 | 2.73448 | 19.532 | 17.292 | 2.42088 | 578
3007192 | 03_Third Floor | 614 | 0.8596 | 3.26648 | 23.332 | 21.092 | 2.95288 | 579
3007193 | 03_Third Floor | 514 | 0.7196 | 2.46358 | 17.597 | 17.597 | 2.46358 | 580
3007194 | 03_Third Floor | 614 | 0.8596 | 2.99558 | 21.397 | 19.157 | 2.68198 | 581
3007195 | 03_Third Floor | 514 | 0.7196 | 2.73448 | 19.532 | 17.292 | 2.42088 | 582
3007242 | 03_Third Floor | 614 | 0.8596 | 3.26648 | 23.332 | 21.092 | 2.95288 | 583
3007243 | 03_Third Floor | 514 | 0.7196 | 2.46358 | 17.597 | 17.597 | 2.46358 | 584
3007244 | 03_Third Floor | 614 | 0.8596 | 2.99558 | 21.397 | 19.157 | 2.68198 | 585
3007245 | 03_Third Floor | 514 | 0.7196 | 2.73448 | 19.532 | 17.292 | 2.42088 | 586
3007288 | 03_Third Floor | 614 | 0.8596 | 3.26648 | 23.332 | 21.092 | 2.95288 | 587
3007289 | 03_Third Floor | 514 | 0.7196 | 2.46358 | 17.597 | 17.597 | 2.46358 | 588
3007290 | 03_Third Floor | 614 | 0.8596 | 2.99558 | 21.397 | 19.157 | 2.68198 | 589
3007291 | 03_Third Floor | 514 | 0.7196 | 2.73448 | 19.532 | 17.292 | 2.42088 | 590
3007334 | 03_Third Floor | 614 | 0.8596 | 3.26648 | 23.332 | 21.092 | 2.95288 | 591
3007335 | 03_Third Floor | 514 | 0.7196 | 2.46358 | 17.597 | 17.597 | 2.46358 | 592
3007336 | 03_Third Floor | 614 | 0.8596 | 2.99558 | 21.397 | 19.157 | 2.68198 | 593
3007337 | 03_Third Floor | 514 | 0.7196 | 2.73448 | 19.532 | 17.292 | 2.42088 | 594
3007380 | 03_Third Floor | 614 | 0.8596 | 3.26648 | 23.332 | 21.092 | 2.95288 | 595
3007381 | 03_Third Floor | 514 | 0.7196 | 2.46358 | 17.597 | 17.597 | 2.46358 | 596
3007382 | 03_Third Floor | 614 | 0.8596 | 2.99558 | 21.397 | 19.157 | 2.68198 | 597
3007383 | 03_Third Floor | 514 | 0.7196 | 2.73448 | 19.532 | 17.292 | 2.42088 | 598
3007426 | 03_Third Floor | 614 | 0.8596 | 3.26648 | 23.332 | 21.092 | 2.95288 | 599
3007427 | 03_Third Floor | 514 | 0.7196 | 2.46358 | 17.597 | 17.597 | 2.46358 | 600
3007428 | 03_Third Floor | 614 | 0.8596 | 2.99558 | 21.397 | 19.157 | 2.68198 | 601
3007429 | 03_Third Floor | 514 | 0.7196 | 2.73448 | 19.532 | 17.292 | 2.42088 | 602
3007473 | 03_Third Floor | 110 | 0.154 | 0.5852 | 4.18 | 4.18 | 0.5852 | 603
3007474 | 03_Third Floor | 110 | 0.154 | 0.5852 | 4.18 | 4.18 | 0.5852 | 604
3007475 | 03_Third Floor | 110 | 0.154 | 0.5852 | 4.18 | 4.18 | 0.5852 | 605
3007476 | 03_Third Floor | 110 | 0.154 | 0.5852 | 4.18 | 4.18 | 0.5852 | 606
3007477 | 03_Third Floor | 110 | 0.154 | 0.5852 | 4.18 | 4.18 | 0.5852 | 607
3007478 | 03_Third Floor | 110 | 0.154 | 0.5852 | 4.18 | 4.18 | 0.5852 | 608
3007479 | 03_Third Floor | 110 | 0.154 | 0.5852 | 4.18 | 4.18 | 0.5852 | 609
3007480 | 03_Third Floor | 3176 | 4.4464 | 6.22132 | 44.438 | 44.438 | 6.22132 | 610
3007481 | 03_Third Floor | 5152 | 7.2128 | 9.56564 | 68.326 | 68.326 | 9.56564 | 611
3007482 | 03_Third Floor | 96 | 0.1344 | 0.51072 | 3.648 | 3.648 | 0.51072 | 612
3007483 | 03_Third Floor | 110 | 0.154 | 0.5852 | 4.18 | 4.18 | 0.5852 | 613
3007484 | 03_Third Floor | 110 | 0.154 | 0.5852 | 4.18 | 4.18 | 0.5852 | 614
3007485 | 03_Third Floor | 110 | 0.154 | 0.5852 | 4.18 | 4.18 | 0.5852 | 615
3007486 | 03_Third Floor | 110 | 0.154 | 0.5852 | 4.18 | 4.18 | 0.5852 | 616
3008033 | 04_Fourth Floor | 628 | 0.8792 | 3.34096 | 23.864 | 21.624 | 3.02736 | 617
3008034 | 04_Fourth Floor | 514 | 0.7196 | 2.46358 | 17.597 | 17.597 | 2.46358 | 618
3008035 | 04_Fourth Floor | 614 | 0.8596 | 2.99558 | 21.397 | 19.157 | 2.68198 | 619
3008036 | 04_Fourth Floor | 500 | 0.7 | 2.66 | 19 | 16.76 | 2.3464 | 620
3008079 | 04_Fourth Floor | 600 | 0.84 | 3.192 | 22.8 | 20.56 | 2.8784 | 621
3008080 | 04_Fourth Floor | 528 | 0.7392 | 2.53806 | 18.129 | 18.129 | 2.53806 | 622
3008081 | 04_Fourth Floor | 614 | 0.8596 | 2.99558 | 21.397 | 19.157 | 2.68198 | 623
3008082 | 04_Fourth Floor | 514 | 0.7196 | 2.73448 | 19.532 | 17.292 | 2.42088 | 624
3008129 | 04_Fourth Floor | 614 | 0.8596 | 3.26648 | 23.332 | 21.092 | 2.95288 | 625
3008130 | 04_Fourth Floor | 514 | 0.7196 | 2.46358 | 17.597 | 17.597 | 2.46358 | 626
3008131 | 04_Fourth Floor | 614 | 0.8596 | 2.99558 | 21.397 | 19.157 | 2.68198 | 627
3008132 | 04_Fourth Floor | 514 | 0.7196 | 2.73448 | 19.532 | 17.292 | 2.42088 | 628
3008175 | 04_Fourth Floor | 614 | 0.8596 | 3.26648 | 23.332 | 21.092 | 2.95288 | 629
3008176 | 04_Fourth Floor | 514 | 0.7196 | 2.46358 | 17.597 | 17.597 | 2.46358 | 630
3008177 | 04_Fourth Floor | 614 | 0.8596 | 2.99558 | 21.397 | 19.157 | 2.68198 | 631
3008178 | 04_Fourth Floor | 514 | 0.7196 | 2.73448 | 19.532 | 17.292 | 2.42088 | 632
3008221 | 04_Fourth Floor | 614 | 0.8596 | 3.26648 | 23.332 | 21.092 | 2.95288 | 633
3008222 | 04_Fourth Floor | 514 | 0.7196 | 2.46358 | 17.597 | 17.597 | 2.46358 | 634
3008223 | 04_Fourth Floor | 614 | 0.8596 | 2.99558 | 21.397 | 19.157 | 2.68198 | 635
3008224 | 04_Fourth Floor | 514 | 0.7196 | 2.73448 | 19.532 | 17.292 | 2.42088 | 636
3008267 | 04_Fourth Floor | 614 | 0.8596 | 3.26648 | 23.332 | 21.092 | 2.95288 | 637
3008268 | 04_Fourth Floor | 514 | 0.7196 | 2.46358 | 17.597 | 17.597 | 2.46358 | 638
3008269 | 04_Fourth Floor | 614 | 0.8596 | 2.99558 | 21.397 | 19.157 | 2.68198 | 639
3008270 | 04_Fourth Floor | 514 | 0.7196 | 2.73448 | 19.532 | 17.292 | 2.42088 | 640
3008313 | 04_Fourth Floor | 614 | 0.8596 | 3.26648 | 23.332 | 21.092 | 2.95288 | 641
3008314 | 04_Fourth Floor | 514 | 0.7196 | 2.46358 | 17.597 | 17.597 | 2.46358 | 642
3008315 | 04_Fourth Floor | 614 | 0.8596 | 2.99558 | 21.397 | 19.157 | 2.68198 | 643
3008316 | 04_Fourth Floor | 514 | 0.7196 | 2.73448 | 19.532 | 17.292 | 2.42088 | 644
3008360 | 04_Fourth Floor | 614 | 0.8596 | 3.26648 | 23.332 | 21.092 | 2.95288 | 645
3008361 | 04_Fourth Floor | 514 | 0.7196 | 2.46358 | 17.597 | 17.597 | 2.46358 | 646
3008362 | 04_Fourth Floor | 614 | 0.8596 | 2.99558 | 21.397 | 19.157 | 2.68198 | 647
3008363 | 04_Fourth Floor | 514 | 0.7196 | 2.73448 | 19.532 | 17.292 | 2.42088 | 648
3008406 | 04_Fourth Floor | 614 | 0.8596 | 3.26648 | 23.332 | 21.092 | 2.95288 | 649
3008407 | 04_Fourth Floor | 514 | 0.7196 | 2.46358 | 17.597 | 17.597 | 2.46358 | 650
3008408 | 04_Fourth Floor | 614 | 0.8596 | 2.99558 | 21.397 | 19.157 | 2.68198 | 651
3008409 | 04_Fourth Floor | 514 | 0.7196 | 2.73448 | 19.532 | 17.292 | 2.42088 | 652
3008456 | 04_Fourth Floor | 614 | 0.8596 | 3.26648 | 23.332 | 21.092 | 2.95288 | 653
3008457 | 04_Fourth Floor | 514 | 0.7196 | 2.46358 | 17.597 | 17.597 | 2.46358 | 654
3008458 | 04_Fourth Floor | 614 | 0.8596 | 2.99558 | 21.397 | 19.157 | 2.68198 | 655
3008459 | 04_Fourth Floor | 514 | 0.7196 | 2.73448 | 19.532 | 17.292 | 2.42088 | 656
3008502 | 04_Fourth Floor | 614 | 0.8596 | 3.26648 | 23.332 | 21.092 | 2.95288 | 657
3008503 | 04_Fourth Floor | 514 | 0.7196 | 2.46358 | 17.597 | 17.597 | 2.46358 | 658
3008504 | 04_Fourth Floor | 614 | 0.8596 | 2.99558 | 21.397 | 19.157 | 2.68198 | 659
3008505 | 04_Fourth Floor | 514 | 0.7196 | 2.73448 | 19.532 | 17.292 | 2.42088 | 660
3008548 | 04_Fourth Floor | 614 | 0.8596 | 3.26648 | 23.332 | 21.092 | 2.95288 | 661
3008549 | 04_Fourth Floor | 514 | 0.7196 | 2.46358 | 17.597 | 17.597 | 2.46358 | 662
3008550 | 04_Fourth Floor | 614 | 0.8596 | 2.99558 | 21.397 | 19.157 | 2.68198 | 663
3008551 | 04_Fourth Floor | 514 | 0.7196 | 2.73448 | 19.532 | 17.292 | 2.42088 | 664
3008594 | 04_Fourth Floor | 614 | 0.8596 | 3.26648 | 23.332 | 21.092 | 2.95288 | 665
3008595 | 04_Fourth Floor | 514 | 0.7196 | 2.46358 | 17.597 | 17.597 | 2.46358 | 666
3008596 | 04_Fourth Floor | 614 | 0.8596 | 2.99558 | 21.397 | 19.157 | 2.68198 | 667
3008597 | 04_Fourth Floor | 514 | 0.7196 | 2.73448 | 19.532 | 17.292 | 2.42088 | 668
3008640 | 04_Fourth Floor | 614 | 0.8596 | 3.26648 | 23.332 | 21.092 | 2.95288 | 669
3008641 | 04_Fourth Floor | 514 | 0.7196 | 2.46358 | 17.597 | 17.597 | 2.46358 | 670
3008642 | 04_Fourth Floor | 614 | 0.8596 | 2.99558 | 21.397 | 19.157 | 2.68198 | 671
3008643 | 04_Fourth Floor | 514 | 0.7196 | 2.73448 | 19.532 | 17.292 | 2.42088 | 672
3008687 | 04_Fourth Floor | 614 | 0.8596 | 3.26648 | 23.332 | 21.092 | 2.95288 | 673
3008688 | 04_Fourth Floor | 514 | 0.7196 | 2.46358 | 17.597 | 17.597 | 2.46358 | 674
3008689 | 04_Fourth Floor | 614 | 0.8596 | 2.99558 | 21.397 | 19.157 | 2.68198 | 675
3008690 | 04_Fourth Floor | 514 | 0.7196 | 2.73448 | 19.532 | 17.292 | 2.42088 | 676
3008733 | 04_Fourth Floor | 614 | 0.8596 | 3.26648 | 23.332 | 21.092 | 2.95288 | 677
3008734 | 04_Fourth Floor | 514 | 0.7196 | 2.46358 | 17.597 | 17.597 | 2.46358 | 678
3008735 | 04_Fourth Floor | 614 | 0.8596 | 2.99558 | 21.397 | 19.157 | 2.68198 | 679
3008736 | 04_Fourth Floor | 514 | 0.7196 | 2.73448 | 19.532 | 17.292 | 2.42088 | 680
3008783 | 04_Fourth Floor | 614 | 0.8596 | 3.26648 | 23.332 | 21.092 | 2.95288 | 681
3008784 | 04_Fourth Floor | 514 | 0.7196 | 2.46358 | 17.597 | 17.597 | 2.46358 | 682
3008785 | 04_Fourth Floor | 614 | 0.8596 | 2.99558 | 21.397 | 19.157 | 2.68198 | 683
3008786 | 04_Fourth Floor | 514 | 0.7196 | 2.73448 | 19.532 | 17.292 | 2.42088 | 684
3008829 | 04_Fourth Floor | 614 | 0.8596 | 3.26648 | 23.332 | 21.092 | 2.95288 | 685
3008830 | 04_Fourth Floor | 514 | 0.7196 | 2.46358 | 17.597 | 17.597 | 2.46358 | 686
3008831 | 04_Fourth Floor | 614 | 0.8596 | 2.99558 | 21.397 | 19.157 | 2.68198 | 687
3008832 | 04_Fourth Floor | 514 | 0.7196 | 2.73448 | 19.532 | 17.292 | 2.42088 | 688
3008875 | 04_Fourth Floor | 614 | 0.8596 | 3.26648 | 23.332 | 21.092 | 2.95288 | 689
3008876 | 04_Fourth Floor | 514 | 0.7196 | 2.46358 | 17.597 | 17.597 | 2.46358 | 690
3008877 | 04_Fourth Floor | 614 | 0.8596 | 2.99558 | 21.397 | 19.157 | 2.68198 | 691
3008878 | 04_Fourth Floor | 514 | 0.7196 | 2.73448 | 19.532 | 17.292 | 2.42088 | 692
3008921 | 04_Fourth Floor | 614 | 0.8596 | 3.26648 | 23.332 | 21.092 | 2.95288 | 693
3008922 | 04_Fourth Floor | 514 | 0.7196 | 2.46358 | 17.597 | 17.597 | 2.46358 | 694
3008923 | 04_Fourth Floor | 614 | 0.8596 | 2.99558 | 21.397 | 19.157 | 2.68198 | 695
3008924 | 04_Fourth Floor | 514 | 0.7196 | 2.73448 | 19.532 | 17.292 | 2.42088 | 696
3008967 | 04_Fourth Floor | 614 | 0.8596 | 3.26648 | 23.332 | 21.092 | 2.95288 | 697
3008968 | 04_Fourth Floor | 514 | 0.7196 | 2.46358 | 17.597 | 17.597 | 2.46358 | 698
3008969 | 04_Fourth Floor | 614 | 0.8596 | 2.99558 | 21.397 | 19.157 | 2.68198 | 699
3008970 | 04_Fourth Floor | 514 | 0.7196 | 2.73448 | 19.532 | 17.292 | 2.42088 | 700
3009014 | 04_Fourth Floor | 614 | 0.8596 | 3.26648 | 23.332 | 21.092 | 2.95288 | 701
3009015 | 04_Fourth Floor | 514 | 0.7196 | 2.46358 | 17.597 | 17.597 | 2.46358 | 702
3009016 | 04_Fourth Floor | 614 | 0.8596 | 2.99558 | 21.397 | 19.157 | 2.68198 | 703
3009017 | 04_Fourth Floor | 514 | 0.7196 | 2.73448 | 19.532 | 17.292 | 2.42088 | 704
3009060 | 04_Fourth Floor | 614 | 0.8596 | 3.26648 | 23.332 | 21.092 | 2.95288 | 705
3009061 | 04_Fourth Floor | 514 | 0.7196 | 2.46358 | 17.597 | 17.597 | 2.46358 | 706
3009062 | 04_Fourth Floor | 614 | 0.8596 | 2.99558 | 21.397 | 19.157 | 2.68198 | 707
3009063 | 04_Fourth Floor | 514 | 0.7196 | 2.73448 | 19.532 | 17.292 | 2.42088 | 708
3009110 | 04_Fourth Floor | 614 | 0.8596 | 3.26648 | 23.332 | 21.092 | 2.95288 | 709
3009111 | 04_Fourth Floor | 514 | 0.7196 | 2.46358 | 17.597 | 17.597 | 2.46358 | 710
3009112 | 04_Fourth Floor | 614 | 0.8596 | 2.99558 | 21.397 | 19.157 | 2.68198 | 711
3009113 | 04_Fourth Floor | 514 | 0.7196 | 2.73448 | 19.532 | 17.292 | 2.42088 | 712
3009156 | 04_Fourth Floor | 614 | 0.8596 | 3.26648 | 23.332 | 21.092 | 2.95288 | 713
3009157 | 04_Fourth Floor | 514 | 0.7196 | 2.46358 | 17.597 | 17.597 | 2.46358 | 714
3009158 | 04_Fourth Floor | 614 | 0.8596 | 2.99558 | 21.397 | 19.157 | 2.68198 | 715
3009159 | 04_Fourth Floor | 514 | 0.7196 | 2.73448 | 19.532 | 17.292 | 2.42088 | 716
3009202 | 04_Fourth Floor | 614 | 0.8596 | 3.26648 | 23.332 | 21.092 | 2.95288 | 717
3009203 | 04_Fourth Floor | 514 | 0.7196 | 2.46358 | 17.597 | 17.597 | 2.46358 | 718
3009204 | 04_Fourth Floor | 614 | 0.8596 | 2.99558 | 21.397 | 19.157 | 2.68198 | 719
3009205 | 04_Fourth Floor | 514 | 0.7196 | 2.73448 | 19.532 | 17.292 | 2.42088 | 720
3009248 | 04_Fourth Floor | 614 | 0.8596 | 3.26648 | 23.332 | 21.092 | 2.95288 | 721
3009249 | 04_Fourth Floor | 514 | 0.7196 | 2.46358 | 17.597 | 17.597 | 2.46358 | 722
3009250 | 04_Fourth Floor | 614 | 0.8596 | 2.99558 | 21.397 | 19.157 | 2.68198 | 723
3009251 | 04_Fourth Floor | 514 | 0.7196 | 2.73448 | 19.532 | 17.292 | 2.42088 | 724
3009294 | 04_Fourth Floor | 614 | 0.8596 | 3.26648 | 23.332 | 21.092 | 2.95288 | 725
3009295 | 04_Fourth Floor | 514 | 0.7196 | 2.46358 | 17.597 | 17.597 | 2.46358 | 726
3009296 | 04_Fourth Floor | 614 | 0.8596 | 2.99558 | 21.397 | 19.157 | 2.68198 | 727
3009297 | 04_Fourth Floor | 514 | 0.7196 | 2.73448 | 19.532 | 17.292 | 2.42088 | 728
3009341 | 04_Fourth Floor | 614 | 0.8596 | 3.26648 | 23.332 | 21.092 | 2.95288 | 729
3009342 | 04_Fourth Floor | 514 | 0.7196 | 2.46358 | 17.597 | 17.597 | 2.46358 | 730
3009343 | 04_Fourth Floor | 614 | 0.8596 | 2.99558 | 21.397 | 19.157 | 2.68198 | 731
3009344 | 04_Fourth Floor | 514 | 0.7196 | 2.73448 | 19.532 | 17.292 | 2.42088 | 732
3009387 | 04_Fourth Floor | 614 | 0.8596 | 3.26648 | 23.332 | 21.092 | 2.95288 | 733
3009388 | 04_Fourth Floor | 514 | 0.7196 | 2.46358 | 17.597 | 17.597 | 2.46358 | 734
3009389 | 04_Fourth Floor | 614 | 0.8596 | 2.99558 | 21.397 | 19.157 | 2.68198 | 735
3009390 | 04_Fourth Floor | 514 | 0.7196 | 2.73448 | 19.532 | 17.292 | 2.42088 | 736
3009437 | 04_Fourth Floor | 614 | 0.8596 | 3.26648 | 23.332 | 21.092 | 2.95288 | 737
3009438 | 04_Fourth Floor | 514 | 0.7196 | 2.46358 | 17.597 | 17.597 | 2.46358 | 738
3009439 | 04_Fourth Floor | 614 | 0.8596 | 2.99558 | 21.397 | 19.157 | 2.68198 | 739
3009440 | 04_Fourth Floor | 514 | 0.7196 | 2.73448 | 19.532 | 17.292 | 2.42088 | 740
3009483 | 04_Fourth Floor | 614 | 0.8596 | 3.26648 | 23.332 | 21.092 | 2.95288 | 741
3009484 | 04_Fourth Floor | 514 | 0.7196 | 2.46358 | 17.597 | 17.597 | 2.46358 | 742
3009485 | 04_Fourth Floor | 614 | 0.8596 | 2.99558 | 21.397 | 19.157 | 2.68198 | 743
3009486 | 04_Fourth Floor | 514 | 0.7196 | 2.73448 | 19.532 | 17.292 | 2.42088 | 744
3009529 | 04_Fourth Floor | 614 | 0.8596 | 3.26648 | 23.332 | 21.092 | 2.95288 | 745
3009530 | 04_Fourth Floor | 514 | 0.7196 | 2.46358 | 17.597 | 17.597 | 2.46358 | 746
3009531 | 04_Fourth Floor | 614 | 0.8596 | 2.99558 | 21.397 | 19.157 | 2.68198 | 747
3009532 | 04_Fourth Floor | 514 | 0.7196 | 2.73448 | 19.532 | 17.292 | 2.42088 | 748
3009575 | 04_Fourth Floor | 614 | 0.8596 | 3.26648 | 23.332 | 21.092 | 2.95288 | 749
3009576 | 04_Fourth Floor | 514 | 0.7196 | 2.46358 | 17.597 | 17.597 | 2.46358 | 750
3009577 | 04_Fourth Floor | 614 | 0.8596 | 2.99558 | 21.397 | 19.157 | 2.68198 | 751
3009578 | 04_Fourth Floor | 514 | 0.7196 | 2.73448 | 19.532 | 17.292 | 2.42088 | 752
3009621 | 04_Fourth Floor | 614 | 0.8596 | 3.26648 | 23.332 | 21.092 | 2.95288 | 753
3009622 | 04_Fourth Floor | 514 | 0.7196 | 2.46358 | 17.597 | 17.597 | 2.46358 | 754
3009623 | 04_Fourth Floor | 614 | 0.8596 | 2.99558 | 21.397 | 19.157 | 2.68198 | 755
3009624 | 04_Fourth Floor | 514 | 0.7196 | 2.73448 | 19.532 | 17.292 | 2.42088 | 756
3009668 | 04_Fourth Floor | 110 | 0.154 | 0.5852 | 4.18 | 4.18 | 0.5852 | 757
3009669 | 04_Fourth Floor | 110 | 0.154 | 0.5852 | 4.18 | 4.18 | 0.5852 | 758
3009670 | 04_Fourth Floor | 110 | 0.154 | 0.5852 | 4.18 | 4.18 | 0.5852 | 759
3009671 | 04_Fourth Floor | 110 | 0.154 | 0.5852 | 4.18 | 4.18 | 0.5852 | 760
3009672 | 04_Fourth Floor | 110 | 0.154 | 0.5852 | 4.18 | 4.18 | 0.5852 | 761
3009673 | 04_Fourth Floor | 110 | 0.154 | 0.5852 | 4.18 | 4.18 | 0.5852 | 762
3009674 | 04_Fourth Floor | 110 | 0.154 | 0.5852 | 4.18 | 4.18 | 0.5852 | 763
3009675 | 04_Fourth Floor | 3176 | 4.4464 | 6.22132 | 44.438 | 44.438 | 6.22132 | 764
3009676 | 04_Fourth Floor | 5152 | 7.2128 | 9.56564 | 68.326 | 68.326 | 9.56564 | 765
3009677 | 04_Fourth Floor | 96 | 0.1344 | 0.51072 | 3.648 | 3.648 | 0.51072 | 766
3009678 | 04_Fourth Floor | 110 | 0.154 | 0.5852 | 4.18 | 4.18 | 0.5852 | 767
3009679 | 04_Fourth Floor | 110 | 0.154 | 0.5852 | 4.18 | 4.18 | 0.5852 | 768
3009680 | 04_Fourth Floor | 110 | 0.154 | 0.5852 | 4.18 | 4.18 | 0.5852 | 769
3009681 | 04_Fourth Floor | 110 | 0.154 | 0.5852 | 4.18 | 4.18 | 0.5852 | 770
3010228 | 05_Fifth Floor | 628 | 0.8792 | 3.34096 | 23.864 | 21.624 | 3.02736 | 771
3010229 | 05_Fifth Floor | 514 | 0.7196 | 2.46358 | 17.597 | 17.597 | 2.46358 | 772
3010230 | 05_Fifth Floor | 614 | 0.8596 | 2.99558 | 21.397 | 19.157 | 2.68198 | 773
3010231 | 05_Fifth Floor | 500 | 0.7 | 2.66 | 19 | 16.76 | 2.3464 | 774
3010274 | 05_Fifth Floor | 600 | 0.84 | 3.192 | 22.8 | 20.56 | 2.8784 | 775
3010275 | 05_Fifth Floor | 528 | 0.7392 | 2.53806 | 18.129 | 18.129 | 2.53806 | 776
3010276 | 05_Fifth Floor | 614 | 0.8596 | 2.99558 | 21.397 | 19.157 | 2.68198 | 777
3010277 | 05_Fifth Floor | 514 | 0.7196 | 2.73448 | 19.532 | 17.292 | 2.42088 | 778
3010324 | 05_Fifth Floor | 614 | 0.8596 | 3.26648 | 23.332 | 21.092 | 2.95288 | 779
3010325 | 05_Fifth Floor | 514 | 0.7196 | 2.46358 | 17.597 | 17.597 | 2.46358 | 780
3010326 | 05_Fifth Floor | 614 | 0.8596 | 2.99558 | 21.397 | 19.157 | 2.68198 | 781
3010327 | 05_Fifth Floor | 514 | 0.7196 | 2.73448 | 19.532 | 17.292 | 2.42088 | 782
3010370 | 05_Fifth Floor | 614 | 0.8596 | 3.26648 | 23.332 | 21.092 | 2.95288 | 783
3010371 | 05_Fifth Floor | 514 | 0.7196 | 2.46358 | 17.597 | 17.597 | 2.46358 | 784
3010372 | 05_Fifth Floor | 614 | 0.8596 | 2.99558 | 21.397 | 19.157 | 2.68198 | 785
3010373 | 05_Fifth Floor | 514 | 0.7196 | 2.73448 | 19.532 | 17.292 | 2.42088 | 786
3010416 | 05_Fifth Floor | 614 | 0.8596 | 3.26648 | 23.332 | 21.092 | 2.95288 | 787
3010417 | 05_Fifth Floor | 514 | 0.7196 | 2.46358 | 17.597 | 17.597 | 2.46358 | 788
3010418 | 05_Fifth Floor | 614 | 0.8596 | 2.99558 | 21.397 | 19.157 | 2.68198 | 789
3010419 | 05_Fifth Floor | 514 | 0.7196 | 2.73448 | 19.532 | 17.292 | 2.42088 | 790
3010462 | 05_Fifth Floor | 614 | 0.8596 | 3.26648 | 23.332 | 21.092 | 2.95288 | 791
3010463 | 05_Fifth Floor | 514 | 0.7196 | 2.46358 | 17.597 | 17.597 | 2.46358 | 792
3010464 | 05_Fifth Floor | 614 | 0.8596 | 2.99558 | 21.397 | 19.157 | 2.68198 | 793
3010465 | 05_Fifth Floor | 514 | 0.7196 | 2.73448 | 19.532 | 17.292 | 2.42088 | 794
3010508 | 05_Fifth Floor | 614 | 0.8596 | 3.26648 | 23.332 | 21.092 | 2.95288 | 795
3010509 | 05_Fifth Floor | 514 | 0.7196 | 2.46358 | 17.597 | 17.597 | 2.46358 | 796
3010510 | 05_Fifth Floor | 614 | 0.8596 | 2.99558 | 21.397 | 19.157 | 2.68198 | 797
3010511 | 05_Fifth Floor | 514 | 0.7196 | 2.73448 | 19.532 | 17.292 | 2.42088 | 798
3010555 | 05_Fifth Floor | 614 | 0.8596 | 3.26648 | 23.332 | 21.092 | 2.95288 | 799
3010556 | 05_Fifth Floor | 514 | 0.7196 | 2.46358 | 17.597 | 17.597 | 2.46358 | 800
3010557 | 05_Fifth Floor | 614 | 0.8596 | 2.99558 | 21.397 | 19.157 | 2.68198 | 801
3010558 | 05_Fifth Floor | 514 | 0.7196 | 2.73448 | 19.532 | 17.292 | 2.42088 | 802
3010601 | 05_Fifth Floor | 614 | 0.8596 | 3.26648 | 23.332 | 21.092 | 2.95288 | 803
3010602 | 05_Fifth Floor | 514 | 0.7196 | 2.46358 | 17.597 | 17.597 | 2.46358 | 804
3010603 | 05_Fifth Floor | 614 | 0.8596 | 2.99558 | 21.397 | 19.157 | 2.68198 | 805
3010604 | 05_Fifth Floor | 514 | 0.7196 | 2.73448 | 19.532 | 17.292 | 2.42088 | 806
3010651 | 05_Fifth Floor | 614 | 0.8596 | 3.26648 | 23.332 | 21.092 | 2.95288 | 807
3010652 | 05_Fifth Floor | 514 | 0.7196 | 2.46358 | 17.597 | 17.597 | 2.46358 | 808
3010653 | 05_Fifth Floor | 614 | 0.8596 | 2.99558 | 21.397 | 19.157 | 2.68198 | 809
3010654 | 05_Fifth Floor | 514 | 0.7196 | 2.73448 | 19.532 | 17.292 | 2.42088 | 810
3010697 | 05_Fifth Floor | 614 | 0.8596 | 3.26648 | 23.332 | 21.092 | 2.95288 | 811
3010698 | 05_Fifth Floor | 514 | 0.7196 | 2.46358 | 17.597 | 17.597 | 2.46358 | 812
3010699 | 05_Fifth Floor | 614 | 0.8596 | 2.99558 | 21.397 | 19.157 | 2.68198 | 813
3010700 | 05_Fifth Floor | 514 | 0.7196 | 2.73448 | 19.532 | 17.292 | 2.42088 | 814
3010743 | 05_Fifth Floor | 614 | 0.8596 | 3.26648 | 23.332 | 21.092 | 2.95288 | 815
3010744 | 05_Fifth Floor | 514 | 0.7196 | 2.46358 | 17.597 | 17.597 | 2.46358 | 816
3010745 | 05_Fifth Floor | 614 | 0.8596 | 2.99558 | 21.397 | 19.157 | 2.68198 | 817
3010746 | 05_Fifth Floor | 514 | 0.7196 | 2.73448 | 19.532 | 17.292 | 2.42088 | 818
3010789 | 05_Fifth Floor | 614 | 0.8596 | 3.26648 | 23.332 | 21.092 | 2.95288 | 819
3010790 | 05_Fifth Floor | 514 | 0.7196 | 2.46358 | 17.597 | 17.597 | 2.46358 | 820
3010791 | 05_Fifth Floor | 614 | 0.8596 | 2.99558 | 21.397 | 19.157 | 2.68198 | 821
3010792 | 05_Fifth Floor | 514 | 0.7196 | 2.73448 | 19.532 | 17.292 | 2.42088 | 822
3010835 | 05_Fifth Floor | 614 | 0.8596 | 3.26648 | 23.332 | 21.092 | 2.95288 | 823
3010836 | 05_Fifth Floor | 514 | 0.7196 | 2.46358 | 17.597 | 17.597 | 2.46358 | 824
3010837 | 05_Fifth Floor | 614 | 0.8596 | 2.99558 | 21.397 | 19.157 | 2.68198 | 825
3010838 | 05_Fifth Floor | 514 | 0.7196 | 2.73448 | 19.532 | 17.292 | 2.42088 | 826
3010882 | 05_Fifth Floor | 614 | 0.8596 | 3.26648 | 23.332 | 21.092 | 2.95288 | 827
3010883 | 05_Fifth Floor | 514 | 0.7196 | 2.46358 | 17.597 | 17.597 | 2.46358 | 828
3010884 | 05_Fifth Floor | 614 | 0.8596 | 2.99558 | 21.397 | 19.157 | 2.68198 | 829
3010885 | 05_Fifth Floor | 514 | 0.7196 | 2.73448 | 19.532 | 17.292 | 2.42088 | 830
3010928 | 05_Fifth Floor | 614 | 0.8596 | 3.26648 | 23.332 | 21.092 | 2.95288 | 831
3010929 | 05_Fifth Floor | 514 | 0.7196 | 2.46358 | 17.597 | 17.597 | 2.46358 | 832
3010930 | 05_Fifth Floor | 614 | 0.8596 | 2.99558 | 21.397 | 19.157 | 2.68198 | 833
3010931 | 05_Fifth Floor | 514 | 0.7196 | 2.73448 | 19.532 | 17.292 | 2.42088 | 834
3010978 | 05_Fifth Floor | 614 | 0.8596 | 3.26648 | 23.332 | 21.092 | 2.95288 | 835
3010979 | 05_Fifth Floor | 514 | 0.7196 | 2.46358 | 17.597 | 17.597 | 2.46358 | 836
3010980 | 05_Fifth Floor | 614 | 0.8596 | 2.99558 | 21.397 | 19.157 | 2.68198 | 837
3010981 | 05_Fifth Floor | 514 | 0.7196 | 2.73448 | 19.532 | 17.292 | 2.42088 | 838
3011024 | 05_Fifth Floor | 614 | 0.8596 | 3.26648 | 23.332 | 21.092 | 2.95288 | 839
3011025 | 05_Fifth Floor | 514 | 0.7196 | 2.46358 | 17.597 | 17.597 | 2.46358 | 840
3011026 | 05_Fifth Floor | 614 | 0.8596 | 2.99558 | 21.397 | 19.157 | 2.68198 | 841
3011027 | 05_Fifth Floor | 514 | 0.7196 | 2.73448 | 19.532 | 17.292 | 2.42088 | 842
3011070 | 05_Fifth Floor | 614 | 0.8596 | 3.26648 | 23.332 | 21.092 | 2.95288 | 843
3011071 | 05_Fifth Floor | 514 | 0.7196 | 2.46358 | 17.597 | 17.597 | 2.46358 | 844
3011072 | 05_Fifth Floor | 614 | 0.8596 | 2.99558 | 21.397 | 19.157 | 2.68198 | 845
3011073 | 05_Fifth Floor | 514 | 0.7196 | 2.73448 | 19.532 | 17.292 | 2.42088 | 846
3011116 | 05_Fifth Floor | 614 | 0.8596 | 3.26648 | 23.332 | 21.092 | 2.95288 | 847
3011117 | 05_Fifth Floor | 514 | 0.7196 | 2.46358 | 17.597 | 17.597 | 2.46358 | 848
3011118 | 05_Fifth Floor | 614 | 0.8596 | 2.99558 | 21.397 | 19.157 | 2.68198 | 849
3011119 | 05_Fifth Floor | 514 | 0.7196 | 2.73448 | 19.532 | 17.292 | 2.42088 | 850
3011162 | 05_Fifth Floor | 614 | 0.8596 | 3.26648 | 23.332 | 21.092 | 2.95288 | 851
3011163 | 05_Fifth Floor | 514 | 0.7196 | 2.46358 | 17.597 | 17.597 | 2.46358 | 852
3011164 | 05_Fifth Floor | 614 | 0.8596 | 2.99558 | 21.397 | 19.157 | 2.68198 | 853
3011165 | 05_Fifth Floor | 514 | 0.7196 | 2.73448 | 19.532 | 17.292 | 2.42088 | 854
3011209 | 05_Fifth Floor | 614 | 0.8596 | 3.26648 | 23.332 | 21.092 | 2.95288 | 855
3011210 | 05_Fifth Floor | 514 | 0.7196 | 2.46358 | 17.597 | 17.597 | 2.46358 | 856
3011211 | 05_Fifth Floor | 614 | 0.8596 | 2.99558 | 21.397 | 19.157 | 2.68198 | 857
3011212 | 05_Fifth Floor | 514 | 0.7196 | 2.73448 | 19.532 | 17.292 | 2.42088 | 858
3011255 | 05_Fifth Floor | 614 | 0.8596 | 3.26648 | 23.332 | 21.092 | 2.95288 | 859
3011256 | 05_Fifth Floor | 514 | 0.7196 | 2.46358 | 17.597 | 17.597 | 2.46358 | 860
3011257 | 05_Fifth Floor | 614 | 0.8596 | 2.99558 | 21.397 | 19.157 | 2.68198 | 861
3011258 | 05_Fifth Floor | 514 | 0.7196 | 2.73448 | 19.532 | 17.292 | 2.42088 | 862
3011305 | 05_Fifth Floor | 614 | 0.8596 | 3.26648 | 23.332 | 21.092 | 2.95288 | 863
3011306 | 05_Fifth Floor | 514 | 0.7196 | 2.46358 | 17.597 | 17.597 | 2.46358 | 864
3011307 | 05_Fifth Floor | 614 | 0.8596 | 2.99558 | 21.397 | 19.157 | 2.68198 | 865
3011308 | 05_Fifth Floor | 514 | 0.7196 | 2.73448 | 19.532 | 17.292 | 2.42088 | 866
3011351 | 05_Fifth Floor | 614 | 0.8596 | 3.26648 | 23.332 | 21.092 | 2.95288 | 867
3011352 | 05_Fifth Floor | 514 | 0.7196 | 2.46358 | 17.597 | 17.597 | 2.46358 | 868
3011353 | 05_Fifth Floor | 614 | 0.8596 | 2.99558 | 21.397 | 19.157 | 2.68198 | 869
3011354 | 05_Fifth Floor | 514 | 0.7196 | 2.73448 | 19.532 | 17.292 | 2.42088 | 870
3011397 | 05_Fifth Floor | 614 | 0.8596 | 3.26648 | 23.332 | 21.092 | 2.95288 | 871
3011398 | 05_Fifth Floor | 514 | 0.7196 | 2.46358 | 17.597 | 17.597 | 2.46358 | 872
3011399 | 05_Fifth Floor | 614 | 0.8596 | 2.99558 | 21.397 | 19.157 | 2.68198 | 873
3011400 | 05_Fifth Floor | 514 | 0.7196 | 2.73448 | 19.532 | 17.292 | 2.42088 | 874
3011443 | 05_Fifth Floor | 614 | 0.8596 | 3.26648 | 23.332 | 21.092 | 2.95288 | 875
3011444 | 05_Fifth Floor | 514 | 0.7196 | 2.46358 | 17.597 | 17.597 | 2.46358 | 876
3011445 | 05_Fifth Floor | 614 | 0.8596 | 2.99558 | 21.397 | 19.157 | 2.68198 | 877
3011446 | 05_Fifth Floor | 514 | 0.7196 | 2.73448 | 19.532 | 17.292 | 2.42088 | 878
3011489 | 05_Fifth Floor | 614 | 0.8596 | 3.26648 | 23.332 | 21.092 | 2.95288 | 879
3011490 | 05_Fifth Floor | 514 | 0.7196 | 2.46358 | 17.597 | 17.597 | 2.46358 | 880
3011491 | 05_Fifth Floor | 614 | 0.8596 | 2.99558 | 21.397 | 19.157 | 2.68198 | 881
3011492 | 05_Fifth Floor | 514 | 0.7196 | 2.73448 | 19.532 | 17.292 | 2.42088 | 882
3011536 | 05_Fifth Floor | 614 | 0.8596 | 3.26648 | 23.332 | 21.092 | 2.95288 | 883
3011537 | 05_Fifth Floor | 514 | 0.7196 | 2.46358 | 17.597 | 17.597 | 2.46358 | 884
3011538 | 05_Fifth Floor | 614 | 0.8596 | 2.99558 | 21.397 | 19.157 | 2.68198 | 885
3011539 | 05_Fifth Floor | 514 | 0.7196 | 2.73448 | 19.532 | 17.292 | 2.42088 | 886
3011582 | 05_Fifth Floor | 614 | 0.8596 | 3.26648 | 23.332 | 21.092 | 2.95288 | 887
3011583 | 05_Fifth Floor | 514 | 0.7196 | 2.46358 | 17.597 | 17.597 | 2.46358 | 888
3011584 | 05_Fifth Floor | 614 | 0.8596 | 2.99558 | 21.397 | 19.157 | 2.68198 | 889
3011585 | 05_Fifth Floor | 514 | 0.7196 | 2.73448 | 19.532 | 17.292 | 2.42088 | 890
3011632 | 05_Fifth Floor | 614 | 0.8596 | 3.26648 | 23.332 | 21.092 | 2.95288 | 891
3011633 | 05_Fifth Floor | 514 | 0.7196 | 2.46358 | 17.597 | 17.597 | 2.46358 | 892
3011634 | 05_Fifth Floor | 614 | 0.8596 | 2.99558 | 21.397 | 19.157 | 2.68198 | 893
3011635 | 05_Fifth Floor | 514 | 0.7196 | 2.73448 | 19.532 | 17.292 | 2.42088 | 894
3011678 | 05_Fifth Floor | 614 | 0.8596 | 3.26648 | 23.332 | 21.092 | 2.95288 | 895
3011679 | 05_Fifth Floor | 514 | 0.7196 | 2.46358 | 17.597 | 17.597 | 2.46358 | 896
3011680 | 05_Fifth Floor | 614 | 0.8596 | 2.99558 | 21.397 | 19.157 | 2.68198 | 897
3011681 | 05_Fifth Floor | 514 | 0.7196 | 2.73448 | 19.532 | 17.292 | 2.42088 | 898
3011724 | 05_Fifth Floor | 614 | 0.8596 | 3.26648 | 23.332 | 21.092 | 2.95288 | 899
3011725 | 05_Fifth Floor | 514 | 0.7196 | 2.46358 | 17.597 | 17.597 | 2.46358 | 900
3011726 | 05_Fifth Floor | 614 | 0.8596 | 2.99558 | 21.397 | 19.157 | 2.68198 | 901
3011727 | 05_Fifth Floor | 514 | 0.7196 | 2.73448 | 19.532 | 17.292 | 2.42088 | 902
3011770 | 05_Fifth Floor | 614 | 0.8596 | 3.26648 | 23.332 | 21.092 | 2.95288 | 903
3011771 | 05_Fifth Floor | 514 | 0.7196 | 2.46358 | 17.597 | 17.597 | 2.46358 | 904
3011772 | 05_Fifth Floor | 614 | 0.8596 | 2.99558 | 21.397 | 19.157 | 2.68198 | 905
3011773 | 05_Fifth Floor | 514 | 0.7196 | 2.73448 | 19.532 | 17.292 | 2.42088 | 906
3011816 | 05_Fifth Floor | 614 | 0.8596 | 3.26648 | 23.332 | 21.092 | 2.95288 | 907
3011817 | 05_Fifth Floor | 514 | 0.7196 | 2.46358 | 17.597 | 17.597 | 2.46358 | 908
3011818 | 05_Fifth Floor | 614 | 0.8596 | 2.99558 | 21.397 | 19.157 | 2.68198 | 909
3011819 | 05_Fifth Floor | 514 | 0.7196 | 2.73448 | 19.532 | 17.292 | 2.42088 | 910
3011863 | 05_Fifth Floor | 110 | 0.154 | 0.5852 | 4.18 | 4.18 | 0.5852 | 911
3011864 | 05_Fifth Floor | 110 | 0.154 | 0.5852 | 4.18 | 4.18 | 0.5852 | 912
3011865 | 05_Fifth Floor | 110 | 0.154 | 0.5852 | 4.18 | 4.18 | 0.5852 | 913
3011866 | 05_Fifth Floor | 110 | 0.154 | 0.5852 | 4.18 | 4.18 | 0.5852 | 914
3011867 | 05_Fifth Floor | 110 | 0.154 | 0.5852 | 4.18 | 4.18 | 0.5852 | 915
3011868 | 05_Fifth Floor | 110 | 0.154 | 0.5852 | 4.18 | 4.18 | 0.5852 | 916
3011869 | 05_Fifth Floor | 110 | 0.154 | 0.5852 | 4.18 | 4.18 | 0.5852 | 917
3011870 | 05_Fifth Floor | 3176 | 4.4464 | 6.22132 | 44.438 | 44.438 | 6.22132 | 918
3011871 | 05_Fifth Floor | 5152 | 7.2128 | 9.56564 | 68.326 | 68.326 | 9.56564 | 919
3011872 | 05_Fifth Floor | 96 | 0.1344 | 0.51072 | 3.648 | 3.648 | 0.51072 | 920
3011873 | 05_Fifth Floor | 110 | 0.154 | 0.5852 | 4.18 | 4.18 | 0.5852 | 921
3011874 | 05_Fifth Floor | 110 | 0.154 | 0.5852 | 4.18 | 4.18 | 0.5852 | 922
3011875 | 05_Fifth Floor | 110 | 0.154 | 0.5852 | 4.18 | 4.18 | 0.5852 | 923
3011876 | 05_Fifth Floor | 110 | 0.154 | 0.5852 | 4.18 | 4.18 | 0.5852 | 924
3012425 | 06_Sixth Floor | 628 | 0.8792 | 3.34096 | 23.864 | 21.624 | 3.02736 | 925
3012426 | 06_Sixth Floor | 514 | 0.7196 | 2.46358 | 17.597 | 17.597 | 2.46358 | 926
3012427 | 06_Sixth Floor | 614 | 0.8596 | 2.99558 | 21.397 | 19.157 | 2.68198 | 927
3012428 | 06_Sixth Floor | 500 | 0.7 | 2.66 | 19 | 16.76 | 2.3464 | 928
3012471 | 06_Sixth Floor | 600 | 0.84 | 3.192 | 22.8 | 20.56 | 2.8784 | 929
3012472 | 06_Sixth Floor | 528 | 0.7392 | 2.53806 | 18.129 | 18.129 | 2.53806 | 930
3012473 | 06_Sixth Floor | 614 | 0.8596 | 2.99558 | 21.397 | 19.157 | 2.68198 | 931
3012474 | 06_Sixth Floor | 514 | 0.7196 | 2.73448 | 19.532 | 17.292 | 2.42088 | 932
3012521 | 06_Sixth Floor | 614 | 0.8596 | 3.26648 | 23.332 | 21.092 | 2.95288 | 933
3012522 | 06_Sixth Floor | 514 | 0.7196 | 2.46358 | 17.597 | 17.597 | 2.46358 | 934
3012523 | 06_Sixth Floor | 614 | 0.8596 | 2.99558 | 21.397 | 19.157 | 2.68198 | 935
3012524 | 06_Sixth Floor | 514 | 0.7196 | 2.73448 | 19.532 | 17.292 | 2.42088 | 936
3012567 | 06_Sixth Floor | 614 | 0.8596 | 3.26648 | 23.332 | 21.092 | 2.95288 | 937
3012568 | 06_Sixth Floor | 514 | 0.7196 | 2.46358 | 17.597 | 17.597 | 2.46358 | 938
3012569 | 06_Sixth Floor | 614 | 0.8596 | 2.99558 | 21.397 | 19.157 | 2.68198 | 939
3012570 | 06_Sixth Floor | 514 | 0.7196 | 2.73448 | 19.532 | 17.292 | 2.42088 | 940
3012613 | 06_Sixth Floor | 614 | 0.8596 | 3.26648 | 23.332 | 21.092 | 2.95288 | 941
3012614 | 06_Sixth Floor | 514 | 0.7196 | 2.46358 | 17.597 | 17.597 | 2.46358 | 942
3012615 | 06_Sixth Floor | 614 | 0.8596 | 2.99558 | 21.397 | 19.157 | 2.68198 | 943
3012616 | 06_Sixth Floor | 514 | 0.7196 | 2.73448 | 19.532 | 17.292 | 2.42088 | 944
3012659 | 06_Sixth Floor | 614 | 0.8596 | 3.26648 | 23.332 | 21.092 | 2.95288 | 945
3012660 | 06_Sixth Floor | 514 | 0.7196 | 2.46358 | 17.597 | 17.597 | 2.46358 | 946
3012661 | 06_Sixth Floor | 614 | 0.8596 | 2.99558 | 21.397 | 19.157 | 2.68198 | 947
3012662 | 06_Sixth Floor | 514 | 0.7196 | 2.73448 | 19.532 | 17.292 | 2.42088 | 948
3012705 | 06_Sixth Floor | 614 | 0.8596 | 3.26648 | 23.332 | 21.092 | 2.95288 | 949
3012706 | 06_Sixth Floor | 514 | 0.7196 | 2.46358 | 17.597 | 17.597 | 2.46358 | 950
3012707 | 06_Sixth Floor | 614 | 0.8596 | 2.99558 | 21.397 | 19.157 | 2.68198 | 951
3012708 | 06_Sixth Floor | 514 | 0.7196 | 2.73448 | 19.532 | 17.292 | 2.42088 | 952
3012752 | 06_Sixth Floor | 614 | 0.8596 | 3.26648 | 23.332 | 21.092 | 2.95288 | 953
3012753 | 06_Sixth Floor | 514 | 0.7196 | 2.46358 | 17.597 | 17.597 | 2.46358 | 954
3012754 | 06_Sixth Floor | 614 | 0.8596 | 2.99558 | 21.397 | 19.157 | 2.68198 | 955
3012755 | 06_Sixth Floor | 514 | 0.7196 | 2.73448 | 19.532 | 17.292 | 2.42088 | 956
3012798 | 06_Sixth Floor | 614 | 0.8596 | 3.26648 | 23.332 | 21.092 | 2.95288 | 957
3012799 | 06_Sixth Floor | 514 | 0.7196 | 2.46358 | 17.597 | 17.597 | 2.46358 | 958
3012800 | 06_Sixth Floor | 614 | 0.8596 | 2.99558 | 21.397 | 19.157 | 2.68198 | 959
3012801 | 06_Sixth Floor | 514 | 0.7196 | 2.73448 | 19.532 | 17.292 | 2.42088 | 960
3012848 | 06_Sixth Floor | 614 | 0.8596 | 3.26648 | 23.332 | 21.092 | 2.95288 | 961
3012849 | 06_Sixth Floor | 514 | 0.7196 | 2.46358 | 17.597 | 17.597 | 2.46358 | 962
3012850 | 06_Sixth Floor | 614 | 0.8596 | 2.99558 | 21.397 | 19.157 | 2.68198 | 963
3012851 | 06_Sixth Floor | 514 | 0.7196 | 2.73448 | 19.532 | 17.292 | 2.42088 | 964
3012894 | 06_Sixth Floor | 614 | 0.8596 | 3.26648 | 23.332 | 21.092 | 2.95288 | 965
3012895 | 06_Sixth Floor | 514 | 0.7196 | 2.46358 | 17.597 | 17.597 | 2.46358 | 966
3012896 | 06_Sixth Floor | 614 | 0.8596 | 2.99558 | 21.397 | 19.157 | 2.68198 | 967
3012897 | 06_Sixth Floor | 514 | 0.7196 | 2.73448 | 19.532 | 17.292 | 2.42088 | 968
3012940 | 06_Sixth Floor | 614 | 0.8596 | 3.26648 | 23.332 | 21.092 | 2.95288 | 969
3012941 | 06_Sixth Floor | 514 | 0.7196 | 2.46358 | 17.597 | 17.597 | 2.46358 | 970
3012942 | 06_Sixth Floor | 614 | 0.8596 | 2.99558 | 21.397 | 19.157 | 2.68198 | 971
3012943 | 06_Sixth Floor | 514 | 0.7196 | 2.73448 | 19.532 | 17.292 | 2.42088 | 972
3012986 | 06_Sixth Floor | 614 | 0.8596 | 3.26648 | 23.332 | 21.092 | 2.95288 | 973
3012987 | 06_Sixth Floor | 514 | 0.7196 | 2.46358 | 17.597 | 17.597 | 2.46358 | 974
3012988 | 06_Sixth Floor | 614 | 0.8596 | 2.99558 | 21.397 | 19.157 | 2.68198 | 975
3012989 | 06_Sixth Floor | 514 | 0.7196 | 2.73448 | 19.532 | 17.292 | 2.42088 | 976
3013032 | 06_Sixth Floor | 614 | 0.8596 | 3.26648 | 23.332 | 21.092 | 2.95288 | 977
3013033 | 06_Sixth Floor | 514 | 0.7196 | 2.46358 | 17.597 | 17.597 | 2.46358 | 978
3013034 | 06_Sixth Floor | 614 | 0.8596 | 2.99558 | 21.397 | 19.157 | 2.68198 | 979
3013035 | 06_Sixth Floor | 514 | 0.7196 | 2.73448 | 19.532 | 17.292 | 2.42088 | 980
3013079 | 06_Sixth Floor | 614 | 0.8596 | 3.26648 | 23.332 | 21.092 | 2.95288 | 981
3013080 | 06_Sixth Floor | 514 | 0.7196 | 2.46358 | 17.597 | 17.597 | 2.46358 | 982
3013081 | 06_Sixth Floor | 614 | 0.8596 | 2.99558 | 21.397 | 19.157 | 2.68198 | 983
3013082 | 06_Sixth Floor | 514 | 0.7196 | 2.73448 | 19.532 | 17.292 | 2.42088 | 984
3013125 | 06_Sixth Floor | 614 | 0.8596 | 3.26648 | 23.332 | 21.092 | 2.95288 | 985
3013126 | 06_Sixth Floor | 514 | 0.7196 | 2.46358 | 17.597 | 17.597 | 2.46358 | 986
3013127 | 06_Sixth Floor | 614 | 0.8596 | 2.99558 | 21.397 | 19.157 | 2.68198 | 987
3013128 | 06_Sixth Floor | 514 | 0.7196 | 2.73448 | 19.532 | 17.292 | 2.42088 | 988
3013175 | 06_Sixth Floor | 614 | 0.8596 | 3.26648 | 23.332 | 21.092 | 2.95288 | 989
3013176 | 06_Sixth Floor | 514 | 0.7196 | 2.46358 | 17.597 | 17.597 | 2.46358 | 990
3013177 | 06_Sixth Floor | 614 | 0.8596 | 2.99558 | 21.397 | 19.157 | 2.68198 | 991
3013178 | 06_Sixth Floor | 514 | 0.7196 | 2.73448 | 19.532 | 17.292 | 2.42088 | 992
3013221 | 06_Sixth Floor | 614 | 0.8596 | 3.26648 | 23.332 | 21.092 | 2.95288 | 993
3013222 | 06_Sixth Floor | 514 | 0.7196 | 2.46358 | 17.597 | 17.597 | 2.46358 | 994
3013223 | 06_Sixth Floor | 614 | 0.8596 | 2.99558 | 21.397 | 19.157 | 2.68198 | 995
3013224 | 06_Sixth Floor | 514 | 0.7196 | 2.73448 | 19.532 | 17.292 | 2.42088 | 996
3013267 | 06_Sixth Floor | 614 | 0.8596 | 3.26648 | 23.332 | 21.092 | 2.95288 | 997
3013268 | 06_Sixth Floor | 514 | 0.7196 | 2.46358 | 17.597 | 17.597 | 2.46358 | 998
3013269 | 06_Sixth Floor | 614 | 0.8596 | 2.99558 | 21.397 | 19.157 | 2.68198 | 999
3013270 | 06_Sixth Floor | 514 | 0.7196 | 2.73448 | 19.532 | 17.292 | 2.42088 | 1000
3013313 | 06_Sixth Floor | 614 | 0.8596 | 3.26648 | 23.332 | 21.092 | 2.95288 | 1001
3013314 | 06_Sixth Floor | 514 | 0.7196 | 2.46358 | 17.597 | 17.597 | 2.46358 | 1002
3013315 | 06_Sixth Floor | 614 | 0.8596 | 2.99558 | 21.397 | 19.157 | 2.68198 | 1003
3013316 | 06_Sixth Floor | 514 | 0.7196 | 2.73448 | 19.532 | 17.292 | 2.42088 | 1004
3013359 | 06_Sixth Floor | 614 | 0.8596 | 3.26648 | 23.332 | 21.092 | 2.95288 | 1005
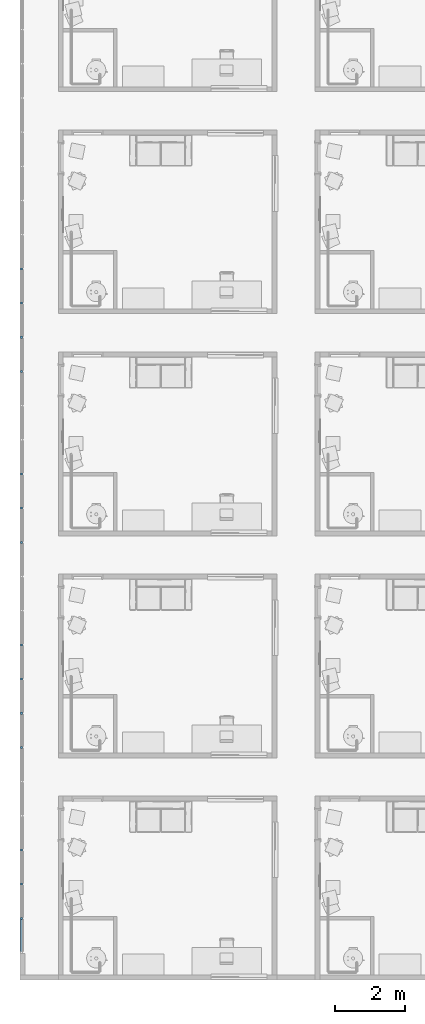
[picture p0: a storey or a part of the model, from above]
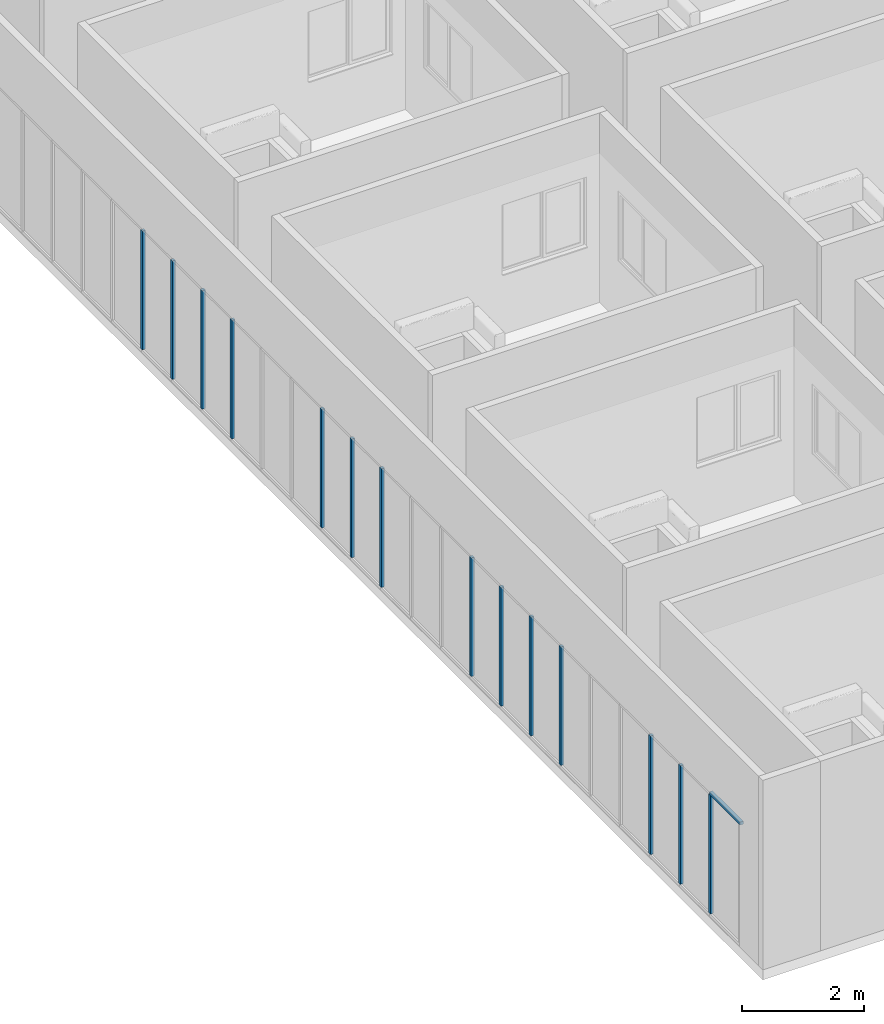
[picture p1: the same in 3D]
Properties of the parts of a building model (IFC4), part 14 of 14

# IfcWall: Basic Wall:ARC_22.10_WA_LB_SB14_gen_BERSnl (1232)
Name (Basic Wall:ARC_22.10_WA_LB_SB14_gen_BERSnl:...) | In | Length (cm) | GrossFootprintArea (m2) | GrossVolume (m3) | GrossSideArea (m2) | NetSideArea (m2) | NetVolume (m3) | bSI_C_TX_SuperSecretCode
3013360 | 06_Sixth Floor | 514 | 0.7196 | 2.46358 | 17.597 | 17.597 | 2.46358 | 1006
3013361 | 06_Sixth Floor | 614 | 0.8596 | 2.99558 | 21.397 | 19.157 | 2.68198 | 1007
3013362 | 06_Sixth Floor | 514 | 0.7196 | 2.73448 | 19.532 | 17.292 | 2.42088 | 1008
3013406 | 06_Sixth Floor | 614 | 0.8596 | 3.26648 | 23.332 | 21.092 | 2.95288 | 1009
3013407 | 06_Sixth Floor | 514 | 0.7196 | 2.46358 | 17.597 | 17.597 | 2.46358 | 1010
3013408 | 06_Sixth Floor | 614 | 0.8596 | 2.99558 | 21.397 | 19.157 | 2.68198 | 1011
3013409 | 06_Sixth Floor | 514 | 0.7196 | 2.73448 | 19.532 | 17.292 | 2.42088 | 1012
3013452 | 06_Sixth Floor | 614 | 0.8596 | 3.26648 | 23.332 | 21.092 | 2.95288 | 1013
3013453 | 06_Sixth Floor | 514 | 0.7196 | 2.46358 | 17.597 | 17.597 | 2.46358 | 1014
3013454 | 06_Sixth Floor | 614 | 0.8596 | 2.99558 | 21.397 | 19.157 | 2.68198 | 1015
3013455 | 06_Sixth Floor | 514 | 0.7196 | 2.73448 | 19.532 | 17.292 | 2.42088 | 1016
3013502 | 06_Sixth Floor | 614 | 0.8596 | 3.26648 | 23.332 | 21.092 | 2.95288 | 1017
3013503 | 06_Sixth Floor | 514 | 0.7196 | 2.46358 | 17.597 | 17.597 | 2.46358 | 1018
3013504 | 06_Sixth Floor | 614 | 0.8596 | 2.99558 | 21.397 | 19.157 | 2.68198 | 1019
3013505 | 06_Sixth Floor | 514 | 0.7196 | 2.73448 | 19.532 | 17.292 | 2.42088 | 1020
3013548 | 06_Sixth Floor | 614 | 0.8596 | 3.26648 | 23.332 | 21.092 | 2.95288 | 1021
3013549 | 06_Sixth Floor | 514 | 0.7196 | 2.46358 | 17.597 | 17.597 | 2.46358 | 1022
3013550 | 06_Sixth Floor | 614 | 0.8596 | 2.99558 | 21.397 | 19.157 | 2.68198 | 1023
3013551 | 06_Sixth Floor | 514 | 0.7196 | 2.73448 | 19.532 | 17.292 | 2.42088 | 1024
3013594 | 06_Sixth Floor | 614 | 0.8596 | 3.26648 | 23.332 | 21.092 | 2.95288 | 1025
3013595 | 06_Sixth Floor | 514 | 0.7196 | 2.46358 | 17.597 | 17.597 | 2.46358 | 1026
3013596 | 06_Sixth Floor | 614 | 0.8596 | 2.99558 | 21.397 | 19.157 | 2.68198 | 1027
3013597 | 06_Sixth Floor | 514 | 0.7196 | 2.73448 | 19.532 | 17.292 | 2.42088 | 1028
3013640 | 06_Sixth Floor | 614 | 0.8596 | 3.26648 | 23.332 | 21.092 | 2.95288 | 1029
3013641 | 06_Sixth Floor | 514 | 0.7196 | 2.46358 | 17.597 | 17.597 | 2.46358 | 1030
3013642 | 06_Sixth Floor | 614 | 0.8596 | 2.99558 | 21.397 | 19.157 | 2.68198 | 1031
3013643 | 06_Sixth Floor | 514 | 0.7196 | 2.73448 | 19.532 | 17.292 | 2.42088 | 1032
3013686 | 06_Sixth Floor | 614 | 0.8596 | 3.26648 | 23.332 | 21.092 | 2.95288 | 1033
3013687 | 06_Sixth Floor | 514 | 0.7196 | 2.46358 | 17.597 | 17.597 | 2.46358 | 1034
3013688 | 06_Sixth Floor | 614 | 0.8596 | 2.99558 | 21.397 | 19.157 | 2.68198 | 1035
3013689 | 06_Sixth Floor | 514 | 0.7196 | 2.73448 | 19.532 | 17.292 | 2.42088 | 1036
3013733 | 06_Sixth Floor | 614 | 0.8596 | 3.26648 | 23.332 | 21.092 | 2.95288 | 1037
3013734 | 06_Sixth Floor | 514 | 0.7196 | 2.46358 | 17.597 | 17.597 | 2.46358 | 1038
3013735 | 06_Sixth Floor | 614 | 0.8596 | 2.99558 | 21.397 | 19.157 | 2.68198 | 1039
3013736 | 06_Sixth Floor | 514 | 0.7196 | 2.73448 | 19.532 | 17.292 | 2.42088 | 1040
3013779 | 06_Sixth Floor | 614 | 0.8596 | 3.26648 | 23.332 | 21.092 | 2.95288 | 1041
3013780 | 06_Sixth Floor | 514 | 0.7196 | 2.46358 | 17.597 | 17.597 | 2.46358 | 1042
3013781 | 06_Sixth Floor | 614 | 0.8596 | 2.99558 | 21.397 | 19.157 | 2.68198 | 1043
3013782 | 06_Sixth Floor | 514 | 0.7196 | 2.73448 | 19.532 | 17.292 | 2.42088 | 1044
3013829 | 06_Sixth Floor | 614 | 0.8596 | 3.26648 | 23.332 | 21.092 | 2.95288 | 1045
3013830 | 06_Sixth Floor | 514 | 0.7196 | 2.46358 | 17.597 | 17.597 | 2.46358 | 1046
3013831 | 06_Sixth Floor | 614 | 0.8596 | 2.99558 | 21.397 | 19.157 | 2.68198 | 1047
3013832 | 06_Sixth Floor | 514 | 0.7196 | 2.73448 | 19.532 | 17.292 | 2.42088 | 1048
3013875 | 06_Sixth Floor | 614 | 0.8596 | 3.26648 | 23.332 | 21.092 | 2.95288 | 1049
3013876 | 06_Sixth Floor | 514 | 0.7196 | 2.46358 | 17.597 | 17.597 | 2.46358 | 1050
3013877 | 06_Sixth Floor | 614 | 0.8596 | 2.99558 | 21.397 | 19.157 | 2.68198 | 1051
3013878 | 06_Sixth Floor | 514 | 0.7196 | 2.73448 | 19.532 | 17.292 | 2.42088 | 1052
3013921 | 06_Sixth Floor | 614 | 0.8596 | 3.26648 | 23.332 | 21.092 | 2.95288 | 1053
3013922 | 06_Sixth Floor | 514 | 0.7196 | 2.46358 | 17.597 | 17.597 | 2.46358 | 1054
3013923 | 06_Sixth Floor | 614 | 0.8596 | 2.99558 | 21.397 | 19.157 | 2.68198 | 1055
3013924 | 06_Sixth Floor | 514 | 0.7196 | 2.73448 | 19.532 | 17.292 | 2.42088 | 1056
3013967 | 06_Sixth Floor | 614 | 0.8596 | 3.26648 | 23.332 | 21.092 | 2.95288 | 1057
3013968 | 06_Sixth Floor | 514 | 0.7196 | 2.46358 | 17.597 | 17.597 | 2.46358 | 1058
3013969 | 06_Sixth Floor | 614 | 0.8596 | 2.99558 | 21.397 | 19.157 | 2.68198 | 1059
3013970 | 06_Sixth Floor | 514 | 0.7196 | 2.73448 | 19.532 | 17.292 | 2.42088 | 1060
3014013 | 06_Sixth Floor | 614 | 0.8596 | 3.26648 | 23.332 | 21.092 | 2.95288 | 1061
3014014 | 06_Sixth Floor | 514 | 0.7196 | 2.46358 | 17.597 | 17.597 | 2.46358 | 1062
3014015 | 06_Sixth Floor | 614 | 0.8596 | 2.99558 | 21.397 | 19.157 | 2.68198 | 1063
3014016 | 06_Sixth Floor | 514 | 0.7196 | 2.73448 | 19.532 | 17.292 | 2.42088 | 1064
3014060 | 06_Sixth Floor | 110 | 0.154 | 0.5852 | 4.18 | 4.18 | 0.5852 | 1065
3014061 | 06_Sixth Floor | 110 | 0.154 | 0.5852 | 4.18 | 4.18 | 0.5852 | 1066
3014062 | 06_Sixth Floor | 110 | 0.154 | 0.5852 | 4.18 | 4.18 | 0.5852 | 1067
3014063 | 06_Sixth Floor | 110 | 0.154 | 0.5852 | 4.18 | 4.18 | 0.5852 | 1068
3014064 | 06_Sixth Floor | 110 | 0.154 | 0.5852 | 4.18 | 4.18 | 0.5852 | 1069
3014065 | 06_Sixth Floor | 110 | 0.154 | 0.5852 | 4.18 | 4.18 | 0.5852 | 1070
3014066 | 06_Sixth Floor | 110 | 0.154 | 0.5852 | 4.18 | 4.18 | 0.5852 | 1071
3014067 | 06_Sixth Floor | 3176 | 4.4464 | 6.22132 | 44.438 | 44.438 | 6.22132 | 1072
3014068 | 06_Sixth Floor | 5152 | 7.2128 | 9.56564 | 68.326 | 68.326 | 9.56564 | 1073
3014069 | 06_Sixth Floor | 96 | 0.1344 | 0.51072 | 3.648 | 3.648 | 0.51072 | 1074
3014070 | 06_Sixth Floor | 110 | 0.154 | 0.5852 | 4.18 | 4.18 | 0.5852 | 1075
3014071 | 06_Sixth Floor | 110 | 0.154 | 0.5852 | 4.18 | 4.18 | 0.5852 | 1076
3014072 | 06_Sixth Floor | 110 | 0.154 | 0.5852 | 4.18 | 4.18 | 0.5852 | 1077
3014073 | 06_Sixth Floor | 110 | 0.154 | 0.5852 | 4.18 | 4.18 | 0.5852 | 1078
3014620 | 07_Seventh Floor | 628 | 0.8792 | 3.34096 | 23.864 | 21.624 | 3.02736 | 1079
3014621 | 07_Seventh Floor | 514 | 0.7196 | 2.46358 | 17.597 | 17.597 | 2.46358 | 1080
3014622 | 07_Seventh Floor | 614 | 0.8596 | 2.99558 | 21.397 | 19.157 | 2.68198 | 1081
3014623 | 07_Seventh Floor | 500 | 0.7 | 2.66 | 19 | 16.76 | 2.3464 | 1082
3014666 | 07_Seventh Floor | 600 | 0.84 | 3.192 | 22.8 | 20.56 | 2.8784 | 1083
3014667 | 07_Seventh Floor | 528 | 0.7392 | 2.53806 | 18.129 | 18.129 | 2.53806 | 1084
3014668 | 07_Seventh Floor | 614 | 0.8596 | 2.99558 | 21.397 | 19.157 | 2.68198 | 1085
3014669 | 07_Seventh Floor | 514 | 0.7196 | 2.73448 | 19.532 | 17.292 | 2.42088 | 1086
3014716 | 07_Seventh Floor | 614 | 0.8596 | 3.26648 | 23.332 | 21.092 | 2.95288 | 1087
3014717 | 07_Seventh Floor | 514 | 0.7196 | 2.46358 | 17.597 | 17.597 | 2.46358 | 1088
3014718 | 07_Seventh Floor | 614 | 0.8596 | 2.99558 | 21.397 | 19.157 | 2.68198 | 1089
3014719 | 07_Seventh Floor | 514 | 0.7196 | 2.73448 | 19.532 | 17.292 | 2.42088 | 1090
3014762 | 07_Seventh Floor | 614 | 0.8596 | 3.26648 | 23.332 | 21.092 | 2.95288 | 1091
3014763 | 07_Seventh Floor | 514 | 0.7196 | 2.46358 | 17.597 | 17.597 | 2.46358 | 1092
3014764 | 07_Seventh Floor | 614 | 0.8596 | 2.99558 | 21.397 | 19.157 | 2.68198 | 1093
3014765 | 07_Seventh Floor | 514 | 0.7196 | 2.73448 | 19.532 | 17.292 | 2.42088 | 1094
3014808 | 07_Seventh Floor | 614 | 0.8596 | 3.26648 | 23.332 | 21.092 | 2.95288 | 1095
3014809 | 07_Seventh Floor | 514 | 0.7196 | 2.46358 | 17.597 | 17.597 | 2.46358 | 1096
3014810 | 07_Seventh Floor | 614 | 0.8596 | 2.99558 | 21.397 | 19.157 | 2.68198 | 1097
3014811 | 07_Seventh Floor | 514 | 0.7196 | 2.73448 | 19.532 | 17.292 | 2.42088 | 1098
3014854 | 07_Seventh Floor | 614 | 0.8596 | 3.26648 | 23.332 | 21.092 | 2.95288 | 1099
3014855 | 07_Seventh Floor | 514 | 0.7196 | 2.46358 | 17.597 | 17.597 | 2.46358 | 1100
3014856 | 07_Seventh Floor | 614 | 0.8596 | 2.99558 | 21.397 | 19.157 | 2.68198 | 1101
3014857 | 07_Seventh Floor | 514 | 0.7196 | 2.73448 | 19.532 | 17.292 | 2.42088 | 1102
3014900 | 07_Seventh Floor | 614 | 0.8596 | 3.26648 | 23.332 | 21.092 | 2.95288 | 1103
3014901 | 07_Seventh Floor | 514 | 0.7196 | 2.46358 | 17.597 | 17.597 | 2.46358 | 1104
3014902 | 07_Seventh Floor | 614 | 0.8596 | 2.99558 | 21.397 | 19.157 | 2.68198 | 1105
3014903 | 07_Seventh Floor | 514 | 0.7196 | 2.73448 | 19.532 | 17.292 | 2.42088 | 1106
3014947 | 07_Seventh Floor | 614 | 0.8596 | 3.26648 | 23.332 | 21.092 | 2.95288 | 1107
3014948 | 07_Seventh Floor | 514 | 0.7196 | 2.46358 | 17.597 | 17.597 | 2.46358 | 1108
3014949 | 07_Seventh Floor | 614 | 0.8596 | 2.99558 | 21.397 | 19.157 | 2.68198 | 1109
3014950 | 07_Seventh Floor | 514 | 0.7196 | 2.73448 | 19.532 | 17.292 | 2.42088 | 1110
3014993 | 07_Seventh Floor | 614 | 0.8596 | 3.26648 | 23.332 | 21.092 | 2.95288 | 1111
3014994 | 07_Seventh Floor | 514 | 0.7196 | 2.46358 | 17.597 | 17.597 | 2.46358 | 1112
3014995 | 07_Seventh Floor | 614 | 0.8596 | 2.99558 | 21.397 | 19.157 | 2.68198 | 1113
3014996 | 07_Seventh Floor | 514 | 0.7196 | 2.73448 | 19.532 | 17.292 | 2.42088 | 1114
3015043 | 07_Seventh Floor | 614 | 0.8596 | 3.26648 | 23.332 | 21.092 | 2.95288 | 1115
3015044 | 07_Seventh Floor | 514 | 0.7196 | 2.46358 | 17.597 | 17.597 | 2.46358 | 1116
3015045 | 07_Seventh Floor | 614 | 0.8596 | 2.99558 | 21.397 | 19.157 | 2.68198 | 1117
3015046 | 07_Seventh Floor | 514 | 0.7196 | 2.73448 | 19.532 | 17.292 | 2.42088 | 1118
3015089 | 07_Seventh Floor | 614 | 0.8596 | 3.26648 | 23.332 | 21.092 | 2.95288 | 1119
3015090 | 07_Seventh Floor | 514 | 0.7196 | 2.46358 | 17.597 | 17.597 | 2.46358 | 1120
3015091 | 07_Seventh Floor | 614 | 0.8596 | 2.99558 | 21.397 | 19.157 | 2.68198 | 1121
3015092 | 07_Seventh Floor | 514 | 0.7196 | 2.73448 | 19.532 | 17.292 | 2.42088 | 1122
3015135 | 07_Seventh Floor | 614 | 0.8596 | 3.26648 | 23.332 | 21.092 | 2.95288 | 1123
3015136 | 07_Seventh Floor | 514 | 0.7196 | 2.46358 | 17.597 | 17.597 | 2.46358 | 1124
3015137 | 07_Seventh Floor | 614 | 0.8596 | 2.99558 | 21.397 | 19.157 | 2.68198 | 1125
3015138 | 07_Seventh Floor | 514 | 0.7196 | 2.73448 | 19.532 | 17.292 | 2.42088 | 1126
3015181 | 07_Seventh Floor | 614 | 0.8596 | 3.26648 | 23.332 | 21.092 | 2.95288 | 1127
3015182 | 07_Seventh Floor | 514 | 0.7196 | 2.46358 | 17.597 | 17.597 | 2.46358 | 1128
3015183 | 07_Seventh Floor | 614 | 0.8596 | 2.99558 | 21.397 | 19.157 | 2.68198 | 1129
3015184 | 07_Seventh Floor | 514 | 0.7196 | 2.73448 | 19.532 | 17.292 | 2.42088 | 1130
3015227 | 07_Seventh Floor | 614 | 0.8596 | 3.26648 | 23.332 | 21.092 | 2.95288 | 1131
3015228 | 07_Seventh Floor | 514 | 0.7196 | 2.46358 | 17.597 | 17.597 | 2.46358 | 1132
3015229 | 07_Seventh Floor | 614 | 0.8596 | 2.99558 | 21.397 | 19.157 | 2.68198 | 1133
3015230 | 07_Seventh Floor | 514 | 0.7196 | 2.73448 | 19.532 | 17.292 | 2.42088 | 1134
3015274 | 07_Seventh Floor | 614 | 0.8596 | 3.26648 | 23.332 | 21.092 | 2.95288 | 1135
3015275 | 07_Seventh Floor | 514 | 0.7196 | 2.46358 | 17.597 | 17.597 | 2.46358 | 1136
3015276 | 07_Seventh Floor | 614 | 0.8596 | 2.99558 | 21.397 | 19.157 | 2.68198 | 1137
3015277 | 07_Seventh Floor | 514 | 0.7196 | 2.73448 | 19.532 | 17.292 | 2.42088 | 1138
3015320 | 07_Seventh Floor | 614 | 0.8596 | 3.26648 | 23.332 | 21.092 | 2.95288 | 1139
3015321 | 07_Seventh Floor | 514 | 0.7196 | 2.46358 | 17.597 | 17.597 | 2.46358 | 1140
3015322 | 07_Seventh Floor | 614 | 0.8596 | 2.99558 | 21.397 | 19.157 | 2.68198 | 1141
3015323 | 07_Seventh Floor | 514 | 0.7196 | 2.73448 | 19.532 | 17.292 | 2.42088 | 1142
3015370 | 07_Seventh Floor | 614 | 0.8596 | 3.26648 | 23.332 | 21.092 | 2.95288 | 1143
3015371 | 07_Seventh Floor | 514 | 0.7196 | 2.46358 | 17.597 | 17.597 | 2.46358 | 1144
3015372 | 07_Seventh Floor | 614 | 0.8596 | 2.99558 | 21.397 | 19.157 | 2.68198 | 1145
3015373 | 07_Seventh Floor | 514 | 0.7196 | 2.73448 | 19.532 | 17.292 | 2.42088 | 1146
3015416 | 07_Seventh Floor | 614 | 0.8596 | 3.26648 | 23.332 | 21.092 | 2.95288 | 1147
3015417 | 07_Seventh Floor | 514 | 0.7196 | 2.46358 | 17.597 | 17.597 | 2.46358 | 1148
3015418 | 07_Seventh Floor | 614 | 0.8596 | 2.99558 | 21.397 | 19.157 | 2.68198 | 1149
3015419 | 07_Seventh Floor | 514 | 0.7196 | 2.73448 | 19.532 | 17.292 | 2.42088 | 1150
3015462 | 07_Seventh Floor | 614 | 0.8596 | 3.26648 | 23.332 | 21.092 | 2.95288 | 1151
3015463 | 07_Seventh Floor | 514 | 0.7196 | 2.46358 | 17.597 | 17.597 | 2.46358 | 1152
3015464 | 07_Seventh Floor | 614 | 0.8596 | 2.99558 | 21.397 | 19.157 | 2.68198 | 1153
3015465 | 07_Seventh Floor | 514 | 0.7196 | 2.73448 | 19.532 | 17.292 | 2.42088 | 1154
3015508 | 07_Seventh Floor | 614 | 0.8596 | 3.26648 | 23.332 | 21.092 | 2.95288 | 1155
3015509 | 07_Seventh Floor | 514 | 0.7196 | 2.46358 | 17.597 | 17.597 | 2.46358 | 1156
3015510 | 07_Seventh Floor | 614 | 0.8596 | 2.99558 | 21.397 | 19.157 | 2.68198 | 1157
3015511 | 07_Seventh Floor | 514 | 0.7196 | 2.73448 | 19.532 | 17.292 | 2.42088 | 1158
3015554 | 07_Seventh Floor | 614 | 0.8596 | 3.26648 | 23.332 | 21.092 | 2.95288 | 1159
3015555 | 07_Seventh Floor | 514 | 0.7196 | 2.46358 | 17.597 | 17.597 | 2.46358 | 1160
3015556 | 07_Seventh Floor | 614 | 0.8596 | 2.99558 | 21.397 | 19.157 | 2.68198 | 1161
3015557 | 07_Seventh Floor | 514 | 0.7196 | 2.73448 | 19.532 | 17.292 | 2.42088 | 1162
3015601 | 07_Seventh Floor | 614 | 0.8596 | 3.26648 | 23.332 | 21.092 | 2.95288 | 1163
3015602 | 07_Seventh Floor | 514 | 0.7196 | 2.46358 | 17.597 | 17.597 | 2.46358 | 1164
3015603 | 07_Seventh Floor | 614 | 0.8596 | 2.99558 | 21.397 | 19.157 | 2.68198 | 1165
3015604 | 07_Seventh Floor | 514 | 0.7196 | 2.73448 | 19.532 | 17.292 | 2.42088 | 1166
3015647 | 07_Seventh Floor | 614 | 0.8596 | 3.26648 | 23.332 | 21.092 | 2.95288 | 1167
3015648 | 07_Seventh Floor | 514 | 0.7196 | 2.46358 | 17.597 | 17.597 | 2.46358 | 1168
3015649 | 07_Seventh Floor | 614 | 0.8596 | 2.99558 | 21.397 | 19.157 | 2.68198 | 1169
3015650 | 07_Seventh Floor | 514 | 0.7196 | 2.73448 | 19.532 | 17.292 | 2.42088 | 1170
3015697 | 07_Seventh Floor | 614 | 0.8596 | 3.26648 | 23.332 | 21.092 | 2.95288 | 1171
3015698 | 07_Seventh Floor | 514 | 0.7196 | 2.46358 | 17.597 | 17.597 | 2.46358 | 1172
3015699 | 07_Seventh Floor | 614 | 0.8596 | 2.99558 | 21.397 | 19.157 | 2.68198 | 1173
3015700 | 07_Seventh Floor | 514 | 0.7196 | 2.73448 | 19.532 | 17.292 | 2.42088 | 1174
3015743 | 07_Seventh Floor | 614 | 0.8596 | 3.26648 | 23.332 | 21.092 | 2.95288 | 1175
3015744 | 07_Seventh Floor | 514 | 0.7196 | 2.46358 | 17.597 | 17.597 | 2.46358 | 1176
3015745 | 07_Seventh Floor | 614 | 0.8596 | 2.99558 | 21.397 | 19.157 | 2.68198 | 1177
3015746 | 07_Seventh Floor | 514 | 0.7196 | 2.73448 | 19.532 | 17.292 | 2.42088 | 1178
3015789 | 07_Seventh Floor | 614 | 0.8596 | 3.26648 | 23.332 | 21.092 | 2.95288 | 1179
3015790 | 07_Seventh Floor | 514 | 0.7196 | 2.46358 | 17.597 | 17.597 | 2.46358 | 1180
3015791 | 07_Seventh Floor | 614 | 0.8596 | 2.99558 | 21.397 | 19.157 | 2.68198 | 1181
3015792 | 07_Seventh Floor | 514 | 0.7196 | 2.73448 | 19.532 | 17.292 | 2.42088 | 1182
3015835 | 07_Seventh Floor | 614 | 0.8596 | 3.26648 | 23.332 | 21.092 | 2.95288 | 1183
3015836 | 07_Seventh Floor | 514 | 0.7196 | 2.46358 | 17.597 | 17.597 | 2.46358 | 1184
3015837 | 07_Seventh Floor | 614 | 0.8596 | 2.99558 | 21.397 | 19.157 | 2.68198 | 1185
3015838 | 07_Seventh Floor | 514 | 0.7196 | 2.73448 | 19.532 | 17.292 | 2.42088 | 1186
3015881 | 07_Seventh Floor | 614 | 0.8596 | 3.26648 | 23.332 | 21.092 | 2.95288 | 1187
3015882 | 07_Seventh Floor | 514 | 0.7196 | 2.46358 | 17.597 | 17.597 | 2.46358 | 1188
3015883 | 07_Seventh Floor | 614 | 0.8596 | 2.99558 | 21.397 | 19.157 | 2.68198 | 1189
3015884 | 07_Seventh Floor | 514 | 0.7196 | 2.73448 | 19.532 | 17.292 | 2.42088 | 1190
3015928 | 07_Seventh Floor | 614 | 0.8596 | 3.26648 | 23.332 | 21.092 | 2.95288 | 1191
3015929 | 07_Seventh Floor | 514 | 0.7196 | 2.46358 | 17.597 | 17.597 | 2.46358 | 1192
3015930 | 07_Seventh Floor | 614 | 0.8596 | 2.99558 | 21.397 | 19.157 | 2.68198 | 1193
3015931 | 07_Seventh Floor | 514 | 0.7196 | 2.73448 | 19.532 | 17.292 | 2.42088 | 1194
3015974 | 07_Seventh Floor | 614 | 0.8596 | 3.26648 | 23.332 | 21.092 | 2.95288 | 1195
3015975 | 07_Seventh Floor | 514 | 0.7196 | 2.46358 | 17.597 | 17.597 | 2.46358 | 1196
3015976 | 07_Seventh Floor | 614 | 0.8596 | 2.99558 | 21.397 | 19.157 | 2.68198 | 1197
3015977 | 07_Seventh Floor | 514 | 0.7196 | 2.73448 | 19.532 | 17.292 | 2.42088 | 1198
3016024 | 07_Seventh Floor | 614 | 0.8596 | 3.26648 | 23.332 | 21.092 | 2.95288 | 1199
3016025 | 07_Seventh Floor | 514 | 0.7196 | 2.46358 | 17.597 | 17.597 | 2.46358 | 1200
3016026 | 07_Seventh Floor | 614 | 0.8596 | 2.99558 | 21.397 | 19.157 | 2.68198 | 1201
3016027 | 07_Seventh Floor | 514 | 0.7196 | 2.73448 | 19.532 | 17.292 | 2.42088 | 1202
3016070 | 07_Seventh Floor | 614 | 0.8596 | 3.26648 | 23.332 | 21.092 | 2.95288 | 1203
3016071 | 07_Seventh Floor | 514 | 0.7196 | 2.46358 | 17.597 | 17.597 | 2.46358 | 1204
3016072 | 07_Seventh Floor | 614 | 0.8596 | 2.99558 | 21.397 | 19.157 | 2.68198 | 1205
3016073 | 07_Seventh Floor | 514 | 0.7196 | 2.73448 | 19.532 | 17.292 | 2.42088 | 1206
3016116 | 07_Seventh Floor | 614 | 0.8596 | 3.26648 | 23.332 | 21.092 | 2.95288 | 1207
3016117 | 07_Seventh Floor | 514 | 0.7196 | 2.46358 | 17.597 | 17.597 | 2.46358 | 1208
3016118 | 07_Seventh Floor | 614 | 0.8596 | 2.99558 | 21.397 | 19.157 | 2.68198 | 1209
3016119 | 07_Seventh Floor | 514 | 0.7196 | 2.73448 | 19.532 | 17.292 | 2.42088 | 1210
3016162 | 07_Seventh Floor | 614 | 0.8596 | 3.26648 | 23.332 | 21.092 | 2.95288 | 1211
3016163 | 07_Seventh Floor | 514 | 0.7196 | 2.46358 | 17.597 | 17.597 | 2.46358 | 1212
3016164 | 07_Seventh Floor | 614 | 0.8596 | 2.99558 | 21.397 | 19.157 | 2.68198 | 1213
3016165 | 07_Seventh Floor | 514 | 0.7196 | 2.73448 | 19.532 | 17.292 | 2.42088 | 1214
3016208 | 07_Seventh Floor | 614 | 0.8596 | 3.26648 | 23.332 | 21.092 | 2.95288 | 1215
3016209 | 07_Seventh Floor | 514 | 0.7196 | 2.46358 | 17.597 | 17.597 | 2.46358 | 1216
3016210 | 07_Seventh Floor | 614 | 0.8596 | 2.99558 | 21.397 | 19.157 | 2.68198 | 1217
3016211 | 07_Seventh Floor | 514 | 0.7196 | 2.73448 | 19.532 | 17.292 | 2.42088 | 1218
3016255 | 07_Seventh Floor | 110 | 0.154 | 0.5852 | 4.18 | 4.18 | 0.5852 | 1219
3016256 | 07_Seventh Floor | 110 | 0.154 | 0.5852 | 4.18 | 4.18 | 0.5852 | 1220
3016257 | 07_Seventh Floor | 110 | 0.154 | 0.5852 | 4.18 | 4.18 | 0.5852 | 1221
3016258 | 07_Seventh Floor | 110 | 0.154 | 0.5852 | 4.18 | 4.18 | 0.5852 | 1222
3016259 | 07_Seventh Floor | 110 | 0.154 | 0.5852 | 4.18 | 4.18 | 0.5852 | 1223
3016260 | 07_Seventh Floor | 110 | 0.154 | 0.5852 | 4.18 | 4.18 | 0.5852 | 1224
3016261 | 07_Seventh Floor | 110 | 0.154 | 0.5852 | 4.18 | 4.18 | 0.5852 | 1225
3016262 | 07_Seventh Floor | 3176 | 4.4464 | 6.22132 | 44.438 | 44.438 | 6.22132 | 1226
3016263 | 07_Seventh Floor | 5152 | 7.2128 | 9.56564 | 68.326 | 68.326 | 9.56564 | 1227
3016264 | 07_Seventh Floor | 96 | 0.1344 | 0.51072 | 3.648 | 3.648 | 0.51072 | 1228
3016265 | 07_Seventh Floor | 110 | 0.154 | 0.5852 | 4.18 | 4.18 | 0.5852 | 1229
3016266 | 07_Seventh Floor | 110 | 0.154 | 0.5852 | 4.18 | 4.18 | 0.5852 | 1230
3016267 | 07_Seventh Floor | 110 | 0.154 | 0.5852 | 4.18 | 4.18 | 0.5852 | 1231
3016268 | 07_Seventh Floor | 110 | 0.154 | 0.5852 | 4.18 | 4.18 | 0.5852 | 1232

# IfcWindow: ARC_31_WI_WB_Dubbel Raam-Recht-Vast en Draaiend_gen_BERSnl:Links-Draaiend / Rechts-Draaiend (840)
Type - PredefinedType: WINDOW; Material: <Unnamed> (2), ARC_FME.o1_glass_00_gen_BERSnl
OverallHeight: 140 cm; OverallWidth: 160 cm; Classification: 31.25 buitenwandopeningen; gevuld met ramen, combinatieramen (Uniformat); Material: <Unnamed>, ARC_FME.o1_glass_00_gen_BERSnl
Pset_EnvironmentalImpactIndicators - Reference: Links-Draaiend / Rechts-Draaiend
Pset_WindowCommon - IsExternal: no; Reference: Links-Draaiend / Rechts-Draaiend
Qto_WindowBaseQuantities - Width: 150 cm; Height: 135 cm; Perimeter: 134.8 cm; Area: 2.025 m2
Name (ARC_31_WI_WB_Dubbel Raam-Recht-Vast en Draaiend_gen_BERSnl:Links-Draaiend / Rechts-Draaiend:...) | In | bSI_C_TX_SuperSecretCode
2950911 | 00_Ground Floor | 1
2956045 | 00_Ground Floor | 2
2995741 | 00_Ground Floor | 3
2995743 | 00_Ground Floor | 4
2995850 | 00_Ground Floor | 5
2995852 | 00_Ground Floor | 6
2995909 | 00_Ground Floor | 7
2995911 | 00_Ground Floor | 8
2995968 | 00_Ground Floor | 9
2995970 | 00_Ground Floor | 10
2996027 | 00_Ground Floor | 11
2996029 | 00_Ground Floor | 12
2996086 | 00_Ground Floor | 13
2996088 | 00_Ground Floor | 14
2996153 | 00_Ground Floor | 15
2996155 | 00_Ground Floor | 16
2996208 | 00_Ground Floor | 17
2996210 | 00_Ground Floor | 18
2996267 | 00_Ground Floor | 19
2996269 | 00_Ground Floor | 20
2996322 | 00_Ground Floor | 21
2996324 | 00_Ground Floor | 22
2996377 | 00_Ground Floor | 23
2996379 | 00_Ground Floor | 24
2996432 | 00_Ground Floor | 25
2996434 | 00_Ground Floor | 26
2996487 | 00_Ground Floor | 27
2996489 | 00_Ground Floor | 28
2996597 | 00_Ground Floor | 29
2996599 | 00_Ground Floor | 30
2996652 | 00_Ground Floor | 31
2996654 | 00_Ground Floor | 32
2996711 | 00_Ground Floor | 33
2996713 | 00_Ground Floor | 34
2996766 | 00_Ground Floor | 35
2996768 | 00_Ground Floor | 36
2996821 | 00_Ground Floor | 37
2996823 | 00_Ground Floor | 38
2996876 | 00_Ground Floor | 39
2996878 | 00_Ground Floor | 40
2996931 | 00_Ground Floor | 41
2996933 | 00_Ground Floor | 42
2997003 | 00_Ground Floor | 43
2997005 | 00_Ground Floor | 44
2997058 | 00_Ground Floor | 45
2997060 | 00_Ground Floor | 46
2997117 | 00_Ground Floor | 47
2997119 | 00_Ground Floor | 48
2997172 | 00_Ground Floor | 49
2997174 | 00_Ground Floor | 50
2997227 | 00_Ground Floor | 51
2997229 | 00_Ground Floor | 52
2997282 | 00_Ground Floor | 53
2997284 | 00_Ground Floor | 54
2997337 | 00_Ground Floor | 55
2997339 | 00_Ground Floor | 56
2997409 | 00_Ground Floor | 57
2997411 | 00_Ground Floor | 58
2997464 | 00_Ground Floor | 59
2997466 | 00_Ground Floor | 60
2997523 | 00_Ground Floor | 61
2997525 | 00_Ground Floor | 62
2997578 | 00_Ground Floor | 63
2997580 | 00_Ground Floor | 64
2997633 | 00_Ground Floor | 65
2997635 | 00_Ground Floor | 66
2997688 | 00_Ground Floor | 67
2997690 | 00_Ground Floor | 68
2997743 | 00_Ground Floor | 69
2997745 | 00_Ground Floor | 70
2999214 | 00_Ground Floor | 71
2999673 | 00_Ground Floor | 72
2999677 | 00_Ground Floor | 73
2999679 | 00_Ground Floor | 74
2999681 | 00_Ground Floor | 75
2999683 | 00_Ground Floor | 76
2999685 | 00_Ground Floor | 77
2999687 | 00_Ground Floor | 78
2999689 | 00_Ground Floor | 79
2999691 | 00_Ground Floor | 80
2999693 | 00_Ground Floor | 81
2999695 | 00_Ground Floor | 82
2999697 | 00_Ground Floor | 83
2999699 | 00_Ground Floor | 84
2999701 | 00_Ground Floor | 85
2999703 | 00_Ground Floor | 86
2999705 | 00_Ground Floor | 87
2999707 | 00_Ground Floor | 88
2999709 | 00_Ground Floor | 89
2999711 | 00_Ground Floor | 90
2999713 | 00_Ground Floor | 91
2999715 | 00_Ground Floor | 92
2999717 | 00_Ground Floor | 93
2999719 | 00_Ground Floor | 94
2999721 | 00_Ground Floor | 95
2999723 | 00_Ground Floor | 96
2999725 | 00_Ground Floor | 97
2999727 | 00_Ground Floor | 98
2999729 | 00_Ground Floor | 99
2999731 | 00_Ground Floor | 100
2999733 | 00_Ground Floor | 101
2999735 | 00_Ground Floor | 102
2999737 | 00_Ground Floor | 103
2999739 | 00_Ground Floor | 104
2999741 | 00_Ground Floor | 105
3001442 | 01_First Floor | 106
3001444 | 01_First Floor | 107
3001489 | 01_First Floor | 108
3001491 | 01_First Floor | 109
3001540 | 01_First Floor | 110
3001542 | 01_First Floor | 111
3001587 | 01_First Floor | 112
3001589 | 01_First Floor | 113
3001634 | 01_First Floor | 114
3001636 | 01_First Floor | 115
3001681 | 01_First Floor | 116
3001683 | 01_First Floor | 117
3001728 | 01_First Floor | 118
3001730 | 01_First Floor | 119
3001776 | 01_First Floor | 120
3001778 | 01_First Floor | 121
3001822 | 01_First Floor | 122
3001824 | 01_First Floor | 123
3001872 | 01_First Floor | 124
3001874 | 01_First Floor | 125
3001918 | 01_First Floor | 126
3001920 | 01_First Floor | 127
3001964 | 01_First Floor | 128
3001966 | 01_First Floor | 129
3002010 | 01_First Floor | 130
3002012 | 01_First Floor | 131
3002056 | 01_First Floor | 132
3002058 | 01_First Floor | 133
3002103 | 01_First Floor | 134
3002105 | 01_First Floor | 135
3002149 | 01_First Floor | 136
3002151 | 01_First Floor | 137
3002199 | 01_First Floor | 138
3002201 | 01_First Floor | 139
3002245 | 01_First Floor | 140
3002247 | 01_First Floor | 141
3002291 | 01_First Floor | 142
3002293 | 01_First Floor | 143
3002337 | 01_First Floor | 144
3002339 | 01_First Floor | 145
3002383 | 01_First Floor | 146
3002385 | 01_First Floor | 147
3002430 | 01_First Floor | 148
3002432 | 01_First Floor | 149
3002476 | 01_First Floor | 150
3002478 | 01_First Floor | 151
3002526 | 01_First Floor | 152
3002528 | 01_First Floor | 153
3002572 | 01_First Floor | 154
3002574 | 01_First Floor | 155
3002618 | 01_First Floor | 156
3002620 | 01_First Floor | 157
3002664 | 01_First Floor | 158
3002666 | 01_First Floor | 159
3002710 | 01_First Floor | 160
3002712 | 01_First Floor | 161
3002757 | 01_First Floor | 162
3002759 | 01_First Floor | 163
3002803 | 01_First Floor | 164
3002805 | 01_First Floor | 165
3002853 | 01_First Floor | 166
3002855 | 01_First Floor | 167
3002899 | 01_First Floor | 168
3002901 | 01_First Floor | 169
3002945 | 01_First Floor | 170
3002947 | 01_First Floor | 171
3002991 | 01_First Floor | 172
3002993 | 01_First Floor | 173
3003037 | 01_First Floor | 174
3003039 | 01_First Floor | 175
3003105 | 01_First Floor | 176
3003106 | 01_First Floor | 177
3003107 | 01_First Floor | 178
3003108 | 01_First Floor | 179
3003109 | 01_First Floor | 180
3003110 | 01_First Floor | 181
3003111 | 01_First Floor | 182
3003112 | 01_First Floor | 183
3003113 | 01_First Floor | 184
3003114 | 01_First Floor | 185
3003115 | 01_First Floor | 186
3003116 | 01_First Floor | 187
3003117 | 01_First Floor | 188
3003118 | 01_First Floor | 189
3003119 | 01_First Floor | 190
3003120 | 01_First Floor | 191
3003121 | 01_First Floor | 192
3003122 | 01_First Floor | 193
3003123 | 01_First Floor | 194
3003124 | 01_First Floor | 195
3003125 | 01_First Floor | 196
3003126 | 01_First Floor | 197
3003127 | 01_First Floor | 198
3003128 | 01_First Floor | 199
3003129 | 01_First Floor | 200
3003130 | 01_First Floor | 201
3003131 | 01_First Floor | 202
3003132 | 01_First Floor | 203
3003133 | 01_First Floor | 204
3003134 | 01_First Floor | 205
3003135 | 01_First Floor | 206
3003136 | 01_First Floor | 207
3003137 | 01_First Floor | 208
3003138 | 01_First Floor | 209
3003139 | 01_First Floor | 210
3003646 | 02_Second Floor | 211
3003648 | 02_Second Floor | 212
3003692 | 02_Second Floor | 213
3003694 | 02_Second Floor | 214
3003742 | 02_Second Floor | 215
3003744 | 02_Second Floor | 216
3003788 | 02_Second Floor | 217
3003790 | 02_Second Floor | 218
3003834 | 02_Second Floor | 219
3003836 | 02_Second Floor | 220
3003880 | 02_Second Floor | 221
3003882 | 02_Second Floor | 222
3003926 | 02_Second Floor | 223
3003928 | 02_Second Floor | 224
3003973 | 02_Second Floor | 225
3003975 | 02_Second Floor | 226
3004019 | 02_Second Floor | 227
3004021 | 02_Second Floor | 228
3004069 | 02_Second Floor | 229
3004071 | 02_Second Floor | 230
3004115 | 02_Second Floor | 231
3004117 | 02_Second Floor | 232
3004161 | 02_Second Floor | 233
3004163 | 02_Second Floor | 234
3004207 | 02_Second Floor | 235
3004209 | 02_Second Floor | 236
3004253 | 02_Second Floor | 237
3004255 | 02_Second Floor | 238
3004300 | 02_Second Floor | 239
3004302 | 02_Second Floor | 240
3004346 | 02_Second Floor | 241
3004348 | 02_Second Floor | 242
3004396 | 02_Second Floor | 243
3004398 | 02_Second Floor | 244
3004442 | 02_Second Floor | 245
3004444 | 02_Second Floor | 246
3004488 | 02_Second Floor | 247
3004490 | 02_Second Floor | 248
3004534 | 02_Second Floor | 249
3004536 | 02_Second Floor | 250
3004580 | 02_Second Floor | 251
3004582 | 02_Second Floor | 252
3004627 | 02_Second Floor | 253
3004629 | 02_Second Floor | 254
3004673 | 02_Second Floor | 255
3004675 | 02_Second Floor | 256
3004723 | 02_Second Floor | 257
3004725 | 02_Second Floor | 258
3004769 | 02_Second Floor | 259
3004771 | 02_Second Floor | 260
3004815 | 02_Second Floor | 261
3004817 | 02_Second Floor | 262
3004861 | 02_Second Floor | 263
3004863 | 02_Second Floor | 264
3004907 | 02_Second Floor | 265
3004909 | 02_Second Floor | 266
3004954 | 02_Second Floor | 267
3004956 | 02_Second Floor | 268
3005000 | 02_Second Floor | 269
3005002 | 02_Second Floor | 270
3005050 | 02_Second Floor | 271
3005052 | 02_Second Floor | 272
3005096 | 02_Second Floor | 273
3005098 | 02_Second Floor | 274
3005142 | 02_Second Floor | 275
3005144 | 02_Second Floor | 276
3005188 | 02_Second Floor | 277
3005190 | 02_Second Floor | 278
3005234 | 02_Second Floor | 279
3005236 | 02_Second Floor | 280
3005298 | 02_Second Floor | 281
3005299 | 02_Second Floor | 282
3005300 | 02_Second Floor | 283
3005301 | 02_Second Floor | 284
3005302 | 02_Second Floor | 285
3005303 | 02_Second Floor | 286
3005304 | 02_Second Floor | 287
3005305 | 02_Second Floor | 288
3005306 | 02_Second Floor | 289
3005307 | 02_Second Floor | 290
3005308 | 02_Second Floor | 291
3005309 | 02_Second Floor | 292
3005310 | 02_Second Floor | 293
3005311 | 02_Second Floor | 294
3005312 | 02_Second Floor | 295
3005313 | 02_Second Floor | 296
3005314 | 02_Second Floor | 297
3005315 | 02_Second Floor | 298
3005316 | 02_Second Floor | 299
3005317 | 02_Second Floor | 300
3005318 | 02_Second Floor | 301
3005319 | 02_Second Floor | 302
3005320 | 02_Second Floor | 303
3005321 | 02_Second Floor | 304
3005322 | 02_Second Floor | 305
3005323 | 02_Second Floor | 306
3005324 | 02_Second Floor | 307
3005325 | 02_Second Floor | 308
3005326 | 02_Second Floor | 309
3005327 | 02_Second Floor | 310
3005328 | 02_Second Floor | 311
3005329 | 02_Second Floor | 312
3005330 | 02_Second Floor | 313
3005331 | 02_Second Floor | 314
3005332 | 02_Second Floor | 315
3005843 | 03_Third Floor | 316
3005845 | 03_Third Floor | 317
3005889 | 03_Third Floor | 318
3005891 | 03_Third Floor | 319
3005939 | 03_Third Floor | 320
3005941 | 03_Third Floor | 321
3005985 | 03_Third Floor | 322
3005987 | 03_Third Floor | 323
3006031 | 03_Third Floor | 324
3006033 | 03_Third Floor | 325
3006077 | 03_Third Floor | 326
3006079 | 03_Third Floor | 327
3006123 | 03_Third Floor | 328
3006125 | 03_Third Floor | 329
3006170 | 03_Third Floor | 330
3006172 | 03_Third Floor | 331
3006216 | 03_Third Floor | 332
3006218 | 03_Third Floor | 333
3006266 | 03_Third Floor | 334
3006268 | 03_Third Floor | 335
3006312 | 03_Third Floor | 336
3006314 | 03_Third Floor | 337
3006358 | 03_Third Floor | 338
3006360 | 03_Third Floor | 339
3006404 | 03_Third Floor | 340
3006406 | 03_Third Floor | 341
3006450 | 03_Third Floor | 342
3006452 | 03_Third Floor | 343
3006497 | 03_Third Floor | 344
3006499 | 03_Third Floor | 345
3006543 | 03_Third Floor | 346
3006545 | 03_Third Floor | 347
3006593 | 03_Third Floor | 348
3006595 | 03_Third Floor | 349
3006639 | 03_Third Floor | 350
3006641 | 03_Third Floor | 351
3006685 | 03_Third Floor | 352
3006687 | 03_Third Floor | 353
3006731 | 03_Third Floor | 354
3006733 | 03_Third Floor | 355
3006777 | 03_Third Floor | 356
3006779 | 03_Third Floor | 357
3006824 | 03_Third Floor | 358
3006826 | 03_Third Floor | 359
3006870 | 03_Third Floor | 360
3006872 | 03_Third Floor | 361
3006920 | 03_Third Floor | 362
3006922 | 03_Third Floor | 363
3006966 | 03_Third Floor | 364
3006968 | 03_Third Floor | 365
3007012 | 03_Third Floor | 366
3007014 | 03_Third Floor | 367
3007058 | 03_Third Floor | 368
3007060 | 03_Third Floor | 369
3007104 | 03_Third Floor | 370
3007106 | 03_Third Floor | 371
3007151 | 03_Third Floor | 372
3007153 | 03_Third Floor | 373
3007197 | 03_Third Floor | 374
3007199 | 03_Third Floor | 375
3007247 | 03_Third Floor | 376
3007249 | 03_Third Floor | 377
3007293 | 03_Third Floor | 378
3007295 | 03_Third Floor | 379
3007339 | 03_Third Floor | 380
3007341 | 03_Third Floor | 381
3007385 | 03_Third Floor | 382
3007387 | 03_Third Floor | 383
3007431 | 03_Third Floor | 384
3007433 | 03_Third Floor | 385
3007495 | 03_Third Floor | 386
3007496 | 03_Third Floor | 387
3007497 | 03_Third Floor | 388
3007498 | 03_Third Floor | 389
3007499 | 03_Third Floor | 390
3007500 | 03_Third Floor | 391
3007501 | 03_Third Floor | 392
3007502 | 03_Third Floor | 393
3007503 | 03_Third Floor | 394
3007504 | 03_Third Floor | 395
3007505 | 03_Third Floor | 396
3007506 | 03_Third Floor | 397
3007507 | 03_Third Floor | 398
3007508 | 03_Third Floor | 399
3007509 | 03_Third Floor | 400
3007510 | 03_Third Floor | 401
3007511 | 03_Third Floor | 402
3007512 | 03_Third Floor | 403
3007513 | 03_Third Floor | 404
3007514 | 03_Third Floor | 405
3007515 | 03_Third Floor | 406
3007516 | 03_Third Floor | 407
3007517 | 03_Third Floor | 408
3007518 | 03_Third Floor | 409
3007519 | 03_Third Floor | 410
3007520 | 03_Third Floor | 411
3007521 | 03_Third Floor | 412
3007522 | 03_Third Floor | 413
3007523 | 03_Third Floor | 414
3007524 | 03_Third Floor | 415
3007525 | 03_Third Floor | 416
3007526 | 03_Third Floor | 417
3007527 | 03_Third Floor | 418
3007528 | 03_Third Floor | 419
3007529 | 03_Third Floor | 420
3008038 | 04_Fourth Floor | 421
3008040 | 04_Fourth Floor | 422
3008084 | 04_Fourth Floor | 423
3008086 | 04_Fourth Floor | 424
3008134 | 04_Fourth Floor | 425
3008136 | 04_Fourth Floor | 426
3008180 | 04_Fourth Floor | 427
3008182 | 04_Fourth Floor | 428
3008226 | 04_Fourth Floor | 429
3008228 | 04_Fourth Floor | 430
3008272 | 04_Fourth Floor | 431
3008274 | 04_Fourth Floor | 432
3008318 | 04_Fourth Floor | 433
3008320 | 04_Fourth Floor | 434
3008365 | 04_Fourth Floor | 435
3008367 | 04_Fourth Floor | 436
3008411 | 04_Fourth Floor | 437
3008413 | 04_Fourth Floor | 438
3008461 | 04_Fourth Floor | 439
3008463 | 04_Fourth Floor | 440
3008507 | 04_Fourth Floor | 441
3008509 | 04_Fourth Floor | 442
3008553 | 04_Fourth Floor | 443
3008555 | 04_Fourth Floor | 444
3008599 | 04_Fourth Floor | 445
3008601 | 04_Fourth Floor | 446
3008645 | 04_Fourth Floor | 447
3008647 | 04_Fourth Floor | 448
3008692 | 04_Fourth Floor | 449
3008694 | 04_Fourth Floor | 450
3008738 | 04_Fourth Floor | 451
3008740 | 04_Fourth Floor | 452
3008788 | 04_Fourth Floor | 453
3008790 | 04_Fourth Floor | 454
3008834 | 04_Fourth Floor | 455
3008836 | 04_Fourth Floor | 456
3008880 | 04_Fourth Floor | 457
3008882 | 04_Fourth Floor | 458
3008926 | 04_Fourth Floor | 459
3008928 | 04_Fourth Floor | 460
3008972 | 04_Fourth Floor | 461
3008974 | 04_Fourth Floor | 462
3009019 | 04_Fourth Floor | 463
3009021 | 04_Fourth Floor | 464
3009065 | 04_Fourth Floor | 465
3009067 | 04_Fourth Floor | 466
3009115 | 04_Fourth Floor | 467
3009117 | 04_Fourth Floor | 468
3009161 | 04_Fourth Floor | 469
3009163 | 04_Fourth Floor | 470
3009207 | 04_Fourth Floor | 471
3009209 | 04_Fourth Floor | 472
3009253 | 04_Fourth Floor | 473
3009255 | 04_Fourth Floor | 474
3009299 | 04_Fourth Floor | 475
3009301 | 04_Fourth Floor | 476
3009346 | 04_Fourth Floor | 477
3009348 | 04_Fourth Floor | 478
3009392 | 04_Fourth Floor | 479
3009394 | 04_Fourth Floor | 480
3009442 | 04_Fourth Floor | 481
3009444 | 04_Fourth Floor | 482
3009488 | 04_Fourth Floor | 483
3009490 | 04_Fourth Floor | 484
3009534 | 04_Fourth Floor | 485
3009536 | 04_Fourth Floor | 486
3009580 | 04_Fourth Floor | 487
3009582 | 04_Fourth Floor | 488
3009626 | 04_Fourth Floor | 489
3009628 | 04_Fourth Floor | 490
3009690 | 04_Fourth Floor | 491
3009691 | 04_Fourth Floor | 492
3009692 | 04_Fourth Floor | 493
3009693 | 04_Fourth Floor | 494
3009694 | 04_Fourth Floor | 495
3009695 | 04_Fourth Floor | 496
3009696 | 04_Fourth Floor | 497
3009697 | 04_Fourth Floor | 498
3009698 | 04_Fourth Floor | 499
3009699 | 04_Fourth Floor | 500
3009700 | 04_Fourth Floor | 501
3009701 | 04_Fourth Floor | 502
3009702 | 04_Fourth Floor | 503
3009703 | 04_Fourth Floor | 504
3009704 | 04_Fourth Floor | 505
3009705 | 04_Fourth Floor | 506
3009706 | 04_Fourth Floor | 507
3009707 | 04_Fourth Floor | 508
3009708 | 04_Fourth Floor | 509
3009709 | 04_Fourth Floor | 510
3009710 | 04_Fourth Floor | 511
3009711 | 04_Fourth Floor | 512
3009712 | 04_Fourth Floor | 513
3009713 | 04_Fourth Floor | 514
3009714 | 04_Fourth Floor | 515
3009715 | 04_Fourth Floor | 516
3009716 | 04_Fourth Floor | 517
3009717 | 04_Fourth Floor | 518
3009718 | 04_Fourth Floor | 519
3009719 | 04_Fourth Floor | 520
3009720 | 04_Fourth Floor | 521
3009721 | 04_Fourth Floor | 522
3009722 | 04_Fourth Floor | 523
3009723 | 04_Fourth Floor | 524
3009724 | 04_Fourth Floor | 525
3010233 | 05_Fifth Floor | 526
3010235 | 05_Fifth Floor | 527
3010279 | 05_Fifth Floor | 528
3010281 | 05_Fifth Floor | 529
3010329 | 05_Fifth Floor | 530
3010331 | 05_Fifth Floor | 531
3010375 | 05_Fifth Floor | 532
3010377 | 05_Fifth Floor | 533
3010421 | 05_Fifth Floor | 534
3010423 | 05_Fifth Floor | 535
3010467 | 05_Fifth Floor | 536
3010469 | 05_Fifth Floor | 537
3010513 | 05_Fifth Floor | 538
3010515 | 05_Fifth Floor | 539
3010560 | 05_Fifth Floor | 540
3010562 | 05_Fifth Floor | 541
3010606 | 05_Fifth Floor | 542
3010608 | 05_Fifth Floor | 543
3010656 | 05_Fifth Floor | 544
3010658 | 05_Fifth Floor | 545
3010702 | 05_Fifth Floor | 546
3010704 | 05_Fifth Floor | 547
3010748 | 05_Fifth Floor | 548
3010750 | 05_Fifth Floor | 549
3010794 | 05_Fifth Floor | 550
3010796 | 05_Fifth Floor | 551
3010840 | 05_Fifth Floor | 552
3010842 | 05_Fifth Floor | 553
3010887 | 05_Fifth Floor | 554
3010889 | 05_Fifth Floor | 555
3010933 | 05_Fifth Floor | 556
3010935 | 05_Fifth Floor | 557
3010983 | 05_Fifth Floor | 558
3010985 | 05_Fifth Floor | 559
3011029 | 05_Fifth Floor | 560
3011031 | 05_Fifth Floor | 561
3011075 | 05_Fifth Floor | 562
3011077 | 05_Fifth Floor | 563
3011121 | 05_Fifth Floor | 564
3011123 | 05_Fifth Floor | 565
3011167 | 05_Fifth Floor | 566
3011169 | 05_Fifth Floor | 567
3011214 | 05_Fifth Floor | 568
3011216 | 05_Fifth Floor | 569
3011260 | 05_Fifth Floor | 570
3011262 | 05_Fifth Floor | 571
3011310 | 05_Fifth Floor | 572
3011312 | 05_Fifth Floor | 573
3011356 | 05_Fifth Floor | 574
3011358 | 05_Fifth Floor | 575
3011402 | 05_Fifth Floor | 576
3011404 | 05_Fifth Floor | 577
3011448 | 05_Fifth Floor | 578
3011450 | 05_Fifth Floor | 579
3011494 | 05_Fifth Floor | 580
3011496 | 05_Fifth Floor | 581
3011541 | 05_Fifth Floor | 582
3011543 | 05_Fifth Floor | 583
3011587 | 05_Fifth Floor | 584
3011589 | 05_Fifth Floor | 585
3011637 | 05_Fifth Floor | 586
3011639 | 05_Fifth Floor | 587
3011683 | 05_Fifth Floor | 588
3011685 | 05_Fifth Floor | 589
3011729 | 05_Fifth Floor | 590
3011731 | 05_Fifth Floor | 591
3011775 | 05_Fifth Floor | 592
3011777 | 05_Fifth Floor | 593
3011821 | 05_Fifth Floor | 594
3011823 | 05_Fifth Floor | 595
3011885 | 05_Fifth Floor | 596
3011886 | 05_Fifth Floor | 597
3011887 | 05_Fifth Floor | 598
3011888 | 05_Fifth Floor | 599
3011889 | 05_Fifth Floor | 600
3011890 | 05_Fifth Floor | 601
3011891 | 05_Fifth Floor | 602
3011892 | 05_Fifth Floor | 603
3011893 | 05_Fifth Floor | 604
3011894 | 05_Fifth Floor | 605
3011895 | 05_Fifth Floor | 606
3011896 | 05_Fifth Floor | 607
3011897 | 05_Fifth Floor | 608
3011898 | 05_Fifth Floor | 609
3011899 | 05_Fifth Floor | 610
3011900 | 05_Fifth Floor | 611
3011901 | 05_Fifth Floor | 612
3011902 | 05_Fifth Floor | 613
3011903 | 05_Fifth Floor | 614
3011904 | 05_Fifth Floor | 615
3011905 | 05_Fifth Floor | 616
3011906 | 05_Fifth Floor | 617
3011907 | 05_Fifth Floor | 618
3011908 | 05_Fifth Floor | 619
3011909 | 05_Fifth Floor | 620
3011910 | 05_Fifth Floor | 621
3011911 | 05_Fifth Floor | 622
3011912 | 05_Fifth Floor | 623
3011913 | 05_Fifth Floor | 624
3011914 | 05_Fifth Floor | 625
3011915 | 05_Fifth Floor | 626
3011916 | 05_Fifth Floor | 627
3011917 | 05_Fifth Floor | 628
3011918 | 05_Fifth Floor | 629
3011919 | 05_Fifth Floor | 630
3012430 | 06_Sixth Floor | 631
3012432 | 06_Sixth Floor | 632
3012476 | 06_Sixth Floor | 633
3012478 | 06_Sixth Floor | 634
3012526 | 06_Sixth Floor | 635
3012528 | 06_Sixth Floor | 636
3012572 | 06_Sixth Floor | 637
3012574 | 06_Sixth Floor | 638
3012618 | 06_Sixth Floor | 639
3012620 | 06_Sixth Floor | 640
3012664 | 06_Sixth Floor | 641
3012666 | 06_Sixth Floor | 642
3012710 | 06_Sixth Floor | 643
3012712 | 06_Sixth Floor | 644
3012757 | 06_Sixth Floor | 645
3012759 | 06_Sixth Floor | 646
3012803 | 06_Sixth Floor | 647
3012805 | 06_Sixth Floor | 648
3012853 | 06_Sixth Floor | 649
3012855 | 06_Sixth Floor | 650
3012899 | 06_Sixth Floor | 651
3012901 | 06_Sixth Floor | 652
3012945 | 06_Sixth Floor | 653
3012947 | 06_Sixth Floor | 654
3012991 | 06_Sixth Floor | 655
3012993 | 06_Sixth Floor | 656
3013037 | 06_Sixth Floor | 657
3013039 | 06_Sixth Floor | 658
3013084 | 06_Sixth Floor | 659
3013086 | 06_Sixth Floor | 660
3013130 | 06_Sixth Floor | 661
3013132 | 06_Sixth Floor | 662
3013180 | 06_Sixth Floor | 663
3013182 | 06_Sixth Floor | 664
3013226 | 06_Sixth Floor | 665
3013228 | 06_Sixth Floor | 666
3013272 | 06_Sixth Floor | 667
3013274 | 06_Sixth Floor | 668
3013318 | 06_Sixth Floor | 669
3013320 | 06_Sixth Floor | 670
3013364 | 06_Sixth Floor | 671
3013366 | 06_Sixth Floor | 672
3013411 | 06_Sixth Floor | 673
3013413 | 06_Sixth Floor | 674
3013457 | 06_Sixth Floor | 675
3013459 | 06_Sixth Floor | 676
3013507 | 06_Sixth Floor | 677
3013509 | 06_Sixth Floor | 678
3013553 | 06_Sixth Floor | 679
3013555 | 06_Sixth Floor | 680
3013599 | 06_Sixth Floor | 681
3013601 | 06_Sixth Floor | 682
3013645 | 06_Sixth Floor | 683
3013647 | 06_Sixth Floor | 684
3013691 | 06_Sixth Floor | 685
3013693 | 06_Sixth Floor | 686
3013738 | 06_Sixth Floor | 687
3013740 | 06_Sixth Floor | 688
3013784 | 06_Sixth Floor | 689
3013786 | 06_Sixth Floor | 690
3013834 | 06_Sixth Floor | 691
3013836 | 06_Sixth Floor | 692
3013880 | 06_Sixth Floor | 693
3013882 | 06_Sixth Floor | 694
3013926 | 06_Sixth Floor | 695
3013928 | 06_Sixth Floor | 696
3013972 | 06_Sixth Floor | 697
3013974 | 06_Sixth Floor | 698
3014018 | 06_Sixth Floor | 699
3014020 | 06_Sixth Floor | 700
3014082 | 06_Sixth Floor | 701
3014083 | 06_Sixth Floor | 702
3014084 | 06_Sixth Floor | 703
3014085 | 06_Sixth Floor | 704
3014086 | 06_Sixth Floor | 705
3014087 | 06_Sixth Floor | 706
3014088 | 06_Sixth Floor | 707
3014089 | 06_Sixth Floor | 708
3014090 | 06_Sixth Floor | 709
3014091 | 06_Sixth Floor | 710
3014092 | 06_Sixth Floor | 711
3014093 | 06_Sixth Floor | 712
3014094 | 06_Sixth Floor | 713
3014095 | 06_Sixth Floor | 714
3014096 | 06_Sixth Floor | 715
3014097 | 06_Sixth Floor | 716
3014098 | 06_Sixth Floor | 717
3014099 | 06_Sixth Floor | 718
3014100 | 06_Sixth Floor | 719
3014101 | 06_Sixth Floor | 720
3014102 | 06_Sixth Floor | 721
3014103 | 06_Sixth Floor | 722
3014104 | 06_Sixth Floor | 723
3014105 | 06_Sixth Floor | 724
3014106 | 06_Sixth Floor | 725
3014107 | 06_Sixth Floor | 726
3014108 | 06_Sixth Floor | 727
3014109 | 06_Sixth Floor | 728
3014110 | 06_Sixth Floor | 729
3014111 | 06_Sixth Floor | 730
3014112 | 06_Sixth Floor | 731
3014113 | 06_Sixth Floor | 732
3014114 | 06_Sixth Floor | 733
3014115 | 06_Sixth Floor | 734
3014116 | 06_Sixth Floor | 735
3014625 | 07_Seventh Floor | 736
3014627 | 07_Seventh Floor | 737
3014671 | 07_Seventh Floor | 738
3014673 | 07_Seventh Floor | 739
3014721 | 07_Seventh Floor | 740
3014723 | 07_Seventh Floor | 741
3014767 | 07_Seventh Floor | 742
3014769 | 07_Seventh Floor | 743
3014813 | 07_Seventh Floor | 744
3014815 | 07_Seventh Floor | 745
3014859 | 07_Seventh Floor | 746
3014861 | 07_Seventh Floor | 747
3014905 | 07_Seventh Floor | 748
3014907 | 07_Seventh Floor | 749
3014952 | 07_Seventh Floor | 750
3014954 | 07_Seventh Floor | 751
3014998 | 07_Seventh Floor | 752
3015000 | 07_Seventh Floor | 753
3015048 | 07_Seventh Floor | 754
3015050 | 07_Seventh Floor | 755
3015094 | 07_Seventh Floor | 756
3015096 | 07_Seventh Floor | 757
3015140 | 07_Seventh Floor | 758
3015142 | 07_Seventh Floor | 759
3015186 | 07_Seventh Floor | 760
3015188 | 07_Seventh Floor | 761
3015232 | 07_Seventh Floor | 762
3015234 | 07_Seventh Floor | 763
3015279 | 07_Seventh Floor | 764
3015281 | 07_Seventh Floor | 765
3015325 | 07_Seventh Floor | 766
3015327 | 07_Seventh Floor | 767
3015375 | 07_Seventh Floor | 768
3015377 | 07_Seventh Floor | 769
3015421 | 07_Seventh Floor | 770
3015423 | 07_Seventh Floor | 771
3015467 | 07_Seventh Floor | 772
3015469 | 07_Seventh Floor | 773
3015513 | 07_Seventh Floor | 774
3015515 | 07_Seventh Floor | 775
3015559 | 07_Seventh Floor | 776
3015561 | 07_Seventh Floor | 777
3015606 | 07_Seventh Floor | 778
3015608 | 07_Seventh Floor | 779
3015652 | 07_Seventh Floor | 780
3015654 | 07_Seventh Floor | 781
3015702 | 07_Seventh Floor | 782
3015704 | 07_Seventh Floor | 783
3015748 | 07_Seventh Floor | 784
3015750 | 07_Seventh Floor | 785
3015794 | 07_Seventh Floor | 786
3015796 | 07_Seventh Floor | 787
3015840 | 07_Seventh Floor | 788
3015842 | 07_Seventh Floor | 789
3015886 | 07_Seventh Floor | 790
3015888 | 07_Seventh Floor | 791
3015933 | 07_Seventh Floor | 792
3015935 | 07_Seventh Floor | 793
3015979 | 07_Seventh Floor | 794
3015981 | 07_Seventh Floor | 795
3016029 | 07_Seventh Floor | 796
3016031 | 07_Seventh Floor | 797
3016075 | 07_Seventh Floor | 798
3016077 | 07_Seventh Floor | 799
3016121 | 07_Seventh Floor | 800
3016123 | 07_Seventh Floor | 801
3016167 | 07_Seventh Floor | 802
3016169 | 07_Seventh Floor | 803
3016213 | 07_Seventh Floor | 804
3016215 | 07_Seventh Floor | 805
3016277 | 07_Seventh Floor | 806
3016278 | 07_Seventh Floor | 807
3016279 | 07_Seventh Floor | 808
3016280 | 07_Seventh Floor | 809
3016281 | 07_Seventh Floor | 810
3016282 | 07_Seventh Floor | 811
3016283 | 07_Seventh Floor | 812
3016284 | 07_Seventh Floor | 813
3016285 | 07_Seventh Floor | 814
3016286 | 07_Seventh Floor | 815
3016287 | 07_Seventh Floor | 816
3016288 | 07_Seventh Floor | 817
3016289 | 07_Seventh Floor | 818
3016290 | 07_Seventh Floor | 819
3016291 | 07_Seventh Floor | 820
3016292 | 07_Seventh Floor | 821
3016293 | 07_Seventh Floor | 822
3016294 | 07_Seventh Floor | 823
3016295 | 07_Seventh Floor | 824
3016296 | 07_Seventh Floor | 825
3016297 | 07_Seventh Floor | 826
3016298 | 07_Seventh Floor | 827
3016299 | 07_Seventh Floor | 828
3016300 | 07_Seventh Floor | 829
3016301 | 07_Seventh Floor | 830
3016302 | 07_Seventh Floor | 831
3016303 | 07_Seventh Floor | 832
3016304 | 07_Seventh Floor | 833
3016305 | 07_Seventh Floor | 834
3016306 | 07_Seventh Floor | 835
3016307 | 07_Seventh Floor | 836
3016308 | 07_Seventh Floor | 837
3016309 | 07_Seventh Floor | 838
3016310 | 07_Seventh Floor | 839
3016311 | 07_Seventh Floor | 840

# Material: ARC_FME.g2_Fg2 Masonry_00_gen_BERSnl
Identity - Category: g - klei; Class: Masonry
Thermal - Name: metselwerk - snelbouw - gebakken aarde(3); Description: Medium weight brick; Keywords: :Medium:thermal:solid; Type: Solid; SubClass: Masonry; Source: Autodesk; Density: 1550 kg/m3; Emissivity: 0.95; Behavior: Isotropic; TransmitsLight: no; Permeability: 0 s/m; Reflectivity: 0; ElectricalResistivity: 2000000
Pset_MaterialCommon - Porosity: 0.001
Pset_MaterialThermal - SpecificHeatCapacity: 840 m2/K/s2; ThermalConductivity: 0.55
Other - Category: Materials
Identity Data - Cost: 0; Description: Masonry; Keynote: Fg2
Materials and Finishes - Color: 3104659; Glow: no; Name: ARC_FME.g2_Fg2 Masonry_00_gen_BERSnl; Shininess: 64; Smoothness: 50; Transparency: 0

# Material: ARC_FME.i3_wood_00_gen_BERSnl
Identity - Category: i - hout; Class: Wood
Other - Category: Materials
Identity Data - Cost: 0; Description: Wood; Keynote: i3
Materials and Finishes - Glow: no; Transparency: 0; Color: 7451604; Name: ARC_FME.i3_wood_00_gen_BERSnl; Shininess: 64; Smoothness: 50

# Material: ARC_FME.o1_glass_00_gen_BERSnl
Identity - Category: o - glas; Class: Glass
Other - Category: Materials
Identity Data - Cost: 0; Description: Glass; Keynote: o1
Materials and Finishes - Glow: no; Color: 14738126; Name: ARC_FME.o1_glass_00_gen_BERSnl; Shininess: 64; Smoothness: 50; Transparency: 85

# Material: TB_LVC_referentievlak_00_gen_BERSnl
Identity - Category: BE Default; Class: BE Default
Other - Category: Materials
Identity Data - Cost: 0
Materials and Finishes - Glow: no; Transparency: 0; Color: 255; Name: TB_LVC_referentievlak_00_gen_BERSnl; Shininess: 64; Smoothness: 50

# Material: ARC_FME.h2_staal_00_gen_BERSnl
Identity - Category: h - metaal; Class: Metal
Other - Category: Materials
Identity Data - Cost: 0; Description: staal, algemeen; Keynote: h2
Materials and Finishes - Glow: no; Transparency: 0; Color: 6052956; Name: ARC_FME.h2_staal_00_gen_BERSnl; Shininess: 64; Smoothness: 50

# Material: ARC_FME.r2_Plaster_white_gen_BERSnl
Identity - Category: r - klei, gips, magnesium en kunststof bindmiddelen; Class: Generic
Other - Category: Materials
Identity Data - Cost: 0; Description: Plaster; Keynote: r2
Materials and Finishes - Glow: no; Transparency: 0; Color: 16382457; Name: ARC_FME.r2_Plaster_white_gen_BERSnl; Shininess: 64; Smoothness: 50

# Material: ARC_FME.f2_Ef2-Cast-In-Place Concrete_C30/37_gen_BERSnl
Identity - Category: f - niet-gebakken kunststeen; Class: Concrete
Structural - Name: licht beton(4); Description: Lightweight f'c=4.0 ksi; Keywords: :structural:concrete; Type: Concrete; SubClass: Lightweight; Source: Autodesk; Behavior: Isotropic; TensileStrength: 2758050 Pa; ConcreteCompression: 27580501 Pa; ShearStrengthModification: 1.3; ThermallyTreated: yes
Thermal - Emissivity: 0.95; Permeability: 0 s/m; Reflectivity: 0; Name: licht beton(4); Description: Concrete, lightweight aggregate; Keywords: :thermal:solid; Type: Solid; SubClass: Concrete; Source: Autodesk; Density: 950 kg/m3; Behavior: Isotropic; TransmitsLight: no; ElectricalResistivity: 2000000
Pset_MaterialCommon - Porosity: 0.001; MassDensity: 1762.03 kg/m3
Pset_MaterialMechanical - YoungModulus: 16603000000 kg/m/s2; ShearModulus: 6916000000 kg/m/s2; PoissonRatio: 0.2; ThermalExpansionCoefficient: 0.00001 1/K
Pset_MaterialSteel - YieldStress: 2758050 Pa
Pset_MaterialThermal - SpecificHeatCapacity: 657 m2/K/s2; ThermalConductivity: 0.209
Other - Category: Materials
Identity Data - Cost: 0; Description: Cast-In-Place Concrete, C30/37; Keynote: Ef2
Materials and Finishes - Glow: no; Transparency: 0; Color: 11711154; Material Type: Concrete; Name: ARC_FME.f2_Ef2-Cast-In-Place Concrete_C30/37_gen_BERSnl; Shininess: 64; Smoothness: 50

# Material: ARC_FME.h4_aluminium_00_gen_BERSnl
Identity - Category: h - metaal; Class: Metal
Other - Category: Materials
Identity Data - Cost: 0; Description: aluminum; Keynote: h4
Materials and Finishes - Glow: no; Transparency: 0; Color: 6055034; Name: ARC_FME.h4_aluminium_00_gen_BERSnl; Shininess: 64; Smoothness: 50

# Material: Cat
Identity - Category: Unassigned; Class: OBJ
Other - Category: Materials
Materials and Finishes - Glow: no; Transparency: 0; Color: 16777215; Name: Cat; Shininess: 128; Smoothness: 100
